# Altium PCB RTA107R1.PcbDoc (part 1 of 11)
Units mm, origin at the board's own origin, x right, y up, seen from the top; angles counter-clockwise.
Board outline 96.01 x 65.66 mm, 22 copper layers (Top Layer, GND1, INT1, PWR1-(VCCIO_MRAM), INT2, PWR2-(VCCINT), INT3, PWR3_(12V_MGTAVCC), INT4, GND2-(DGND_SGND), PWR4_(MGTAVTT_VCCBRAM,VCCAUX), PWR5-(VCC_12V), GND3-(DGND_GND), INT5, GND4, INT6, PWR6_(VCCO), INT7, GND5, INT8, GND6, Bottom Layer), stack 2.833 mm thick; 614 components, 659 nets, 4037 pads, 3511 vias.

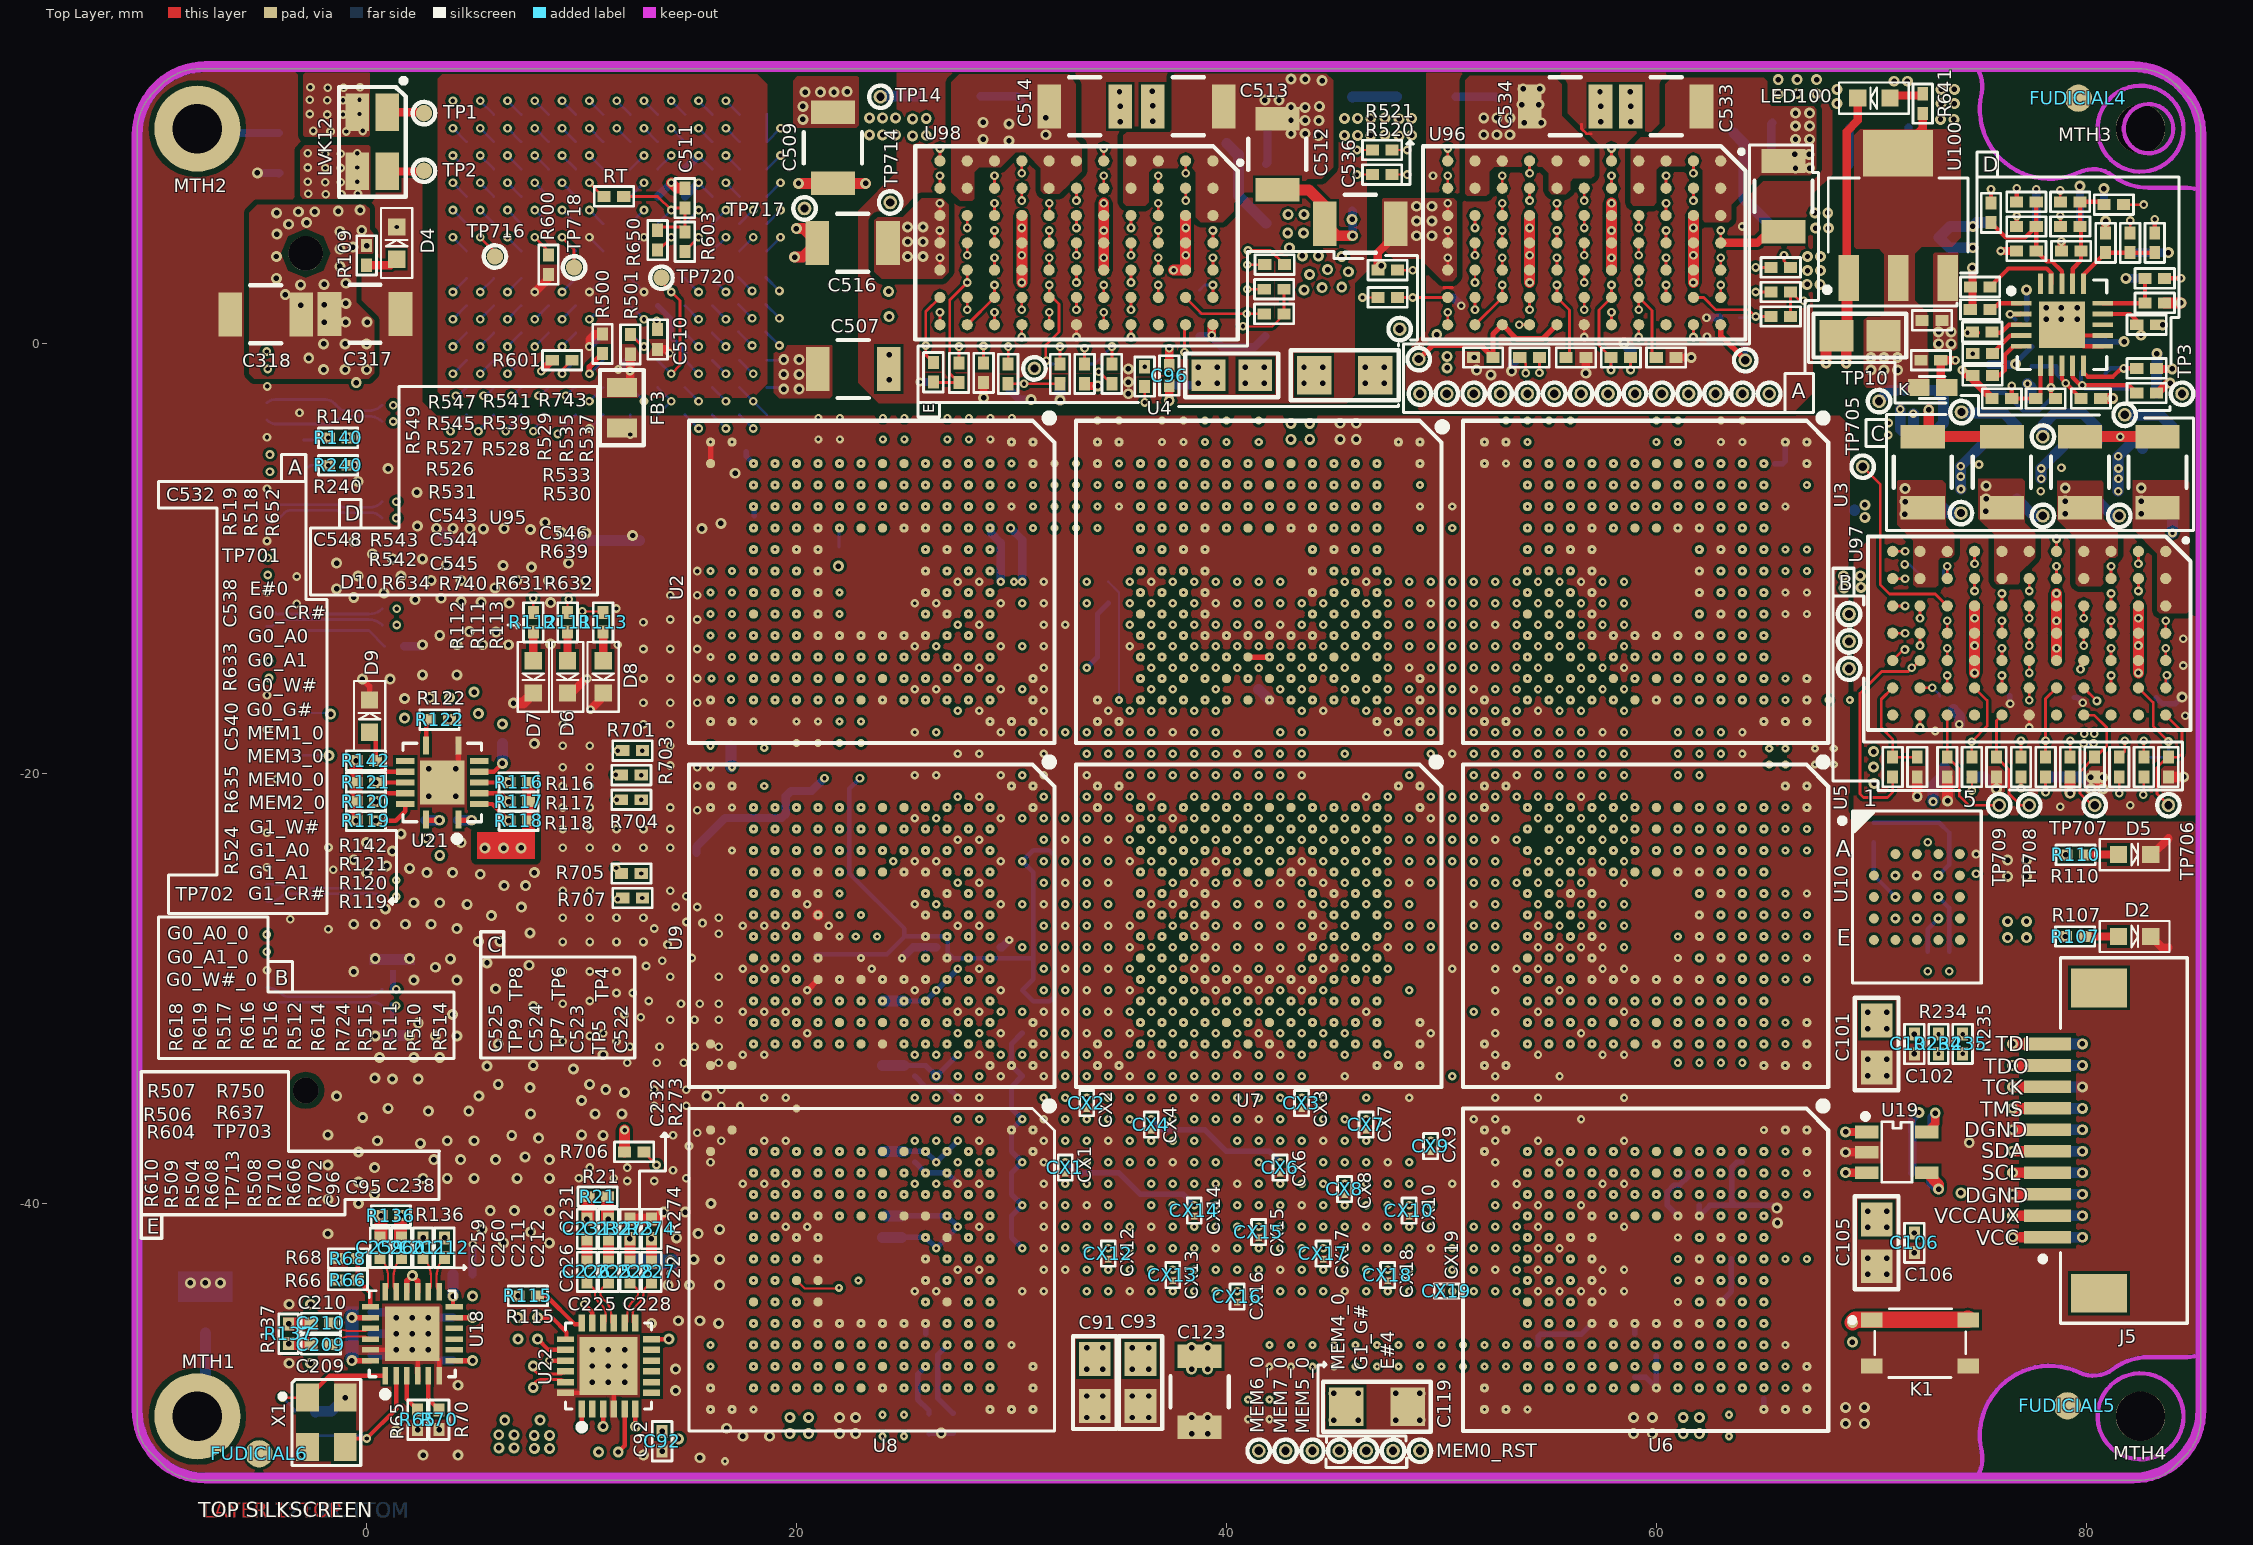
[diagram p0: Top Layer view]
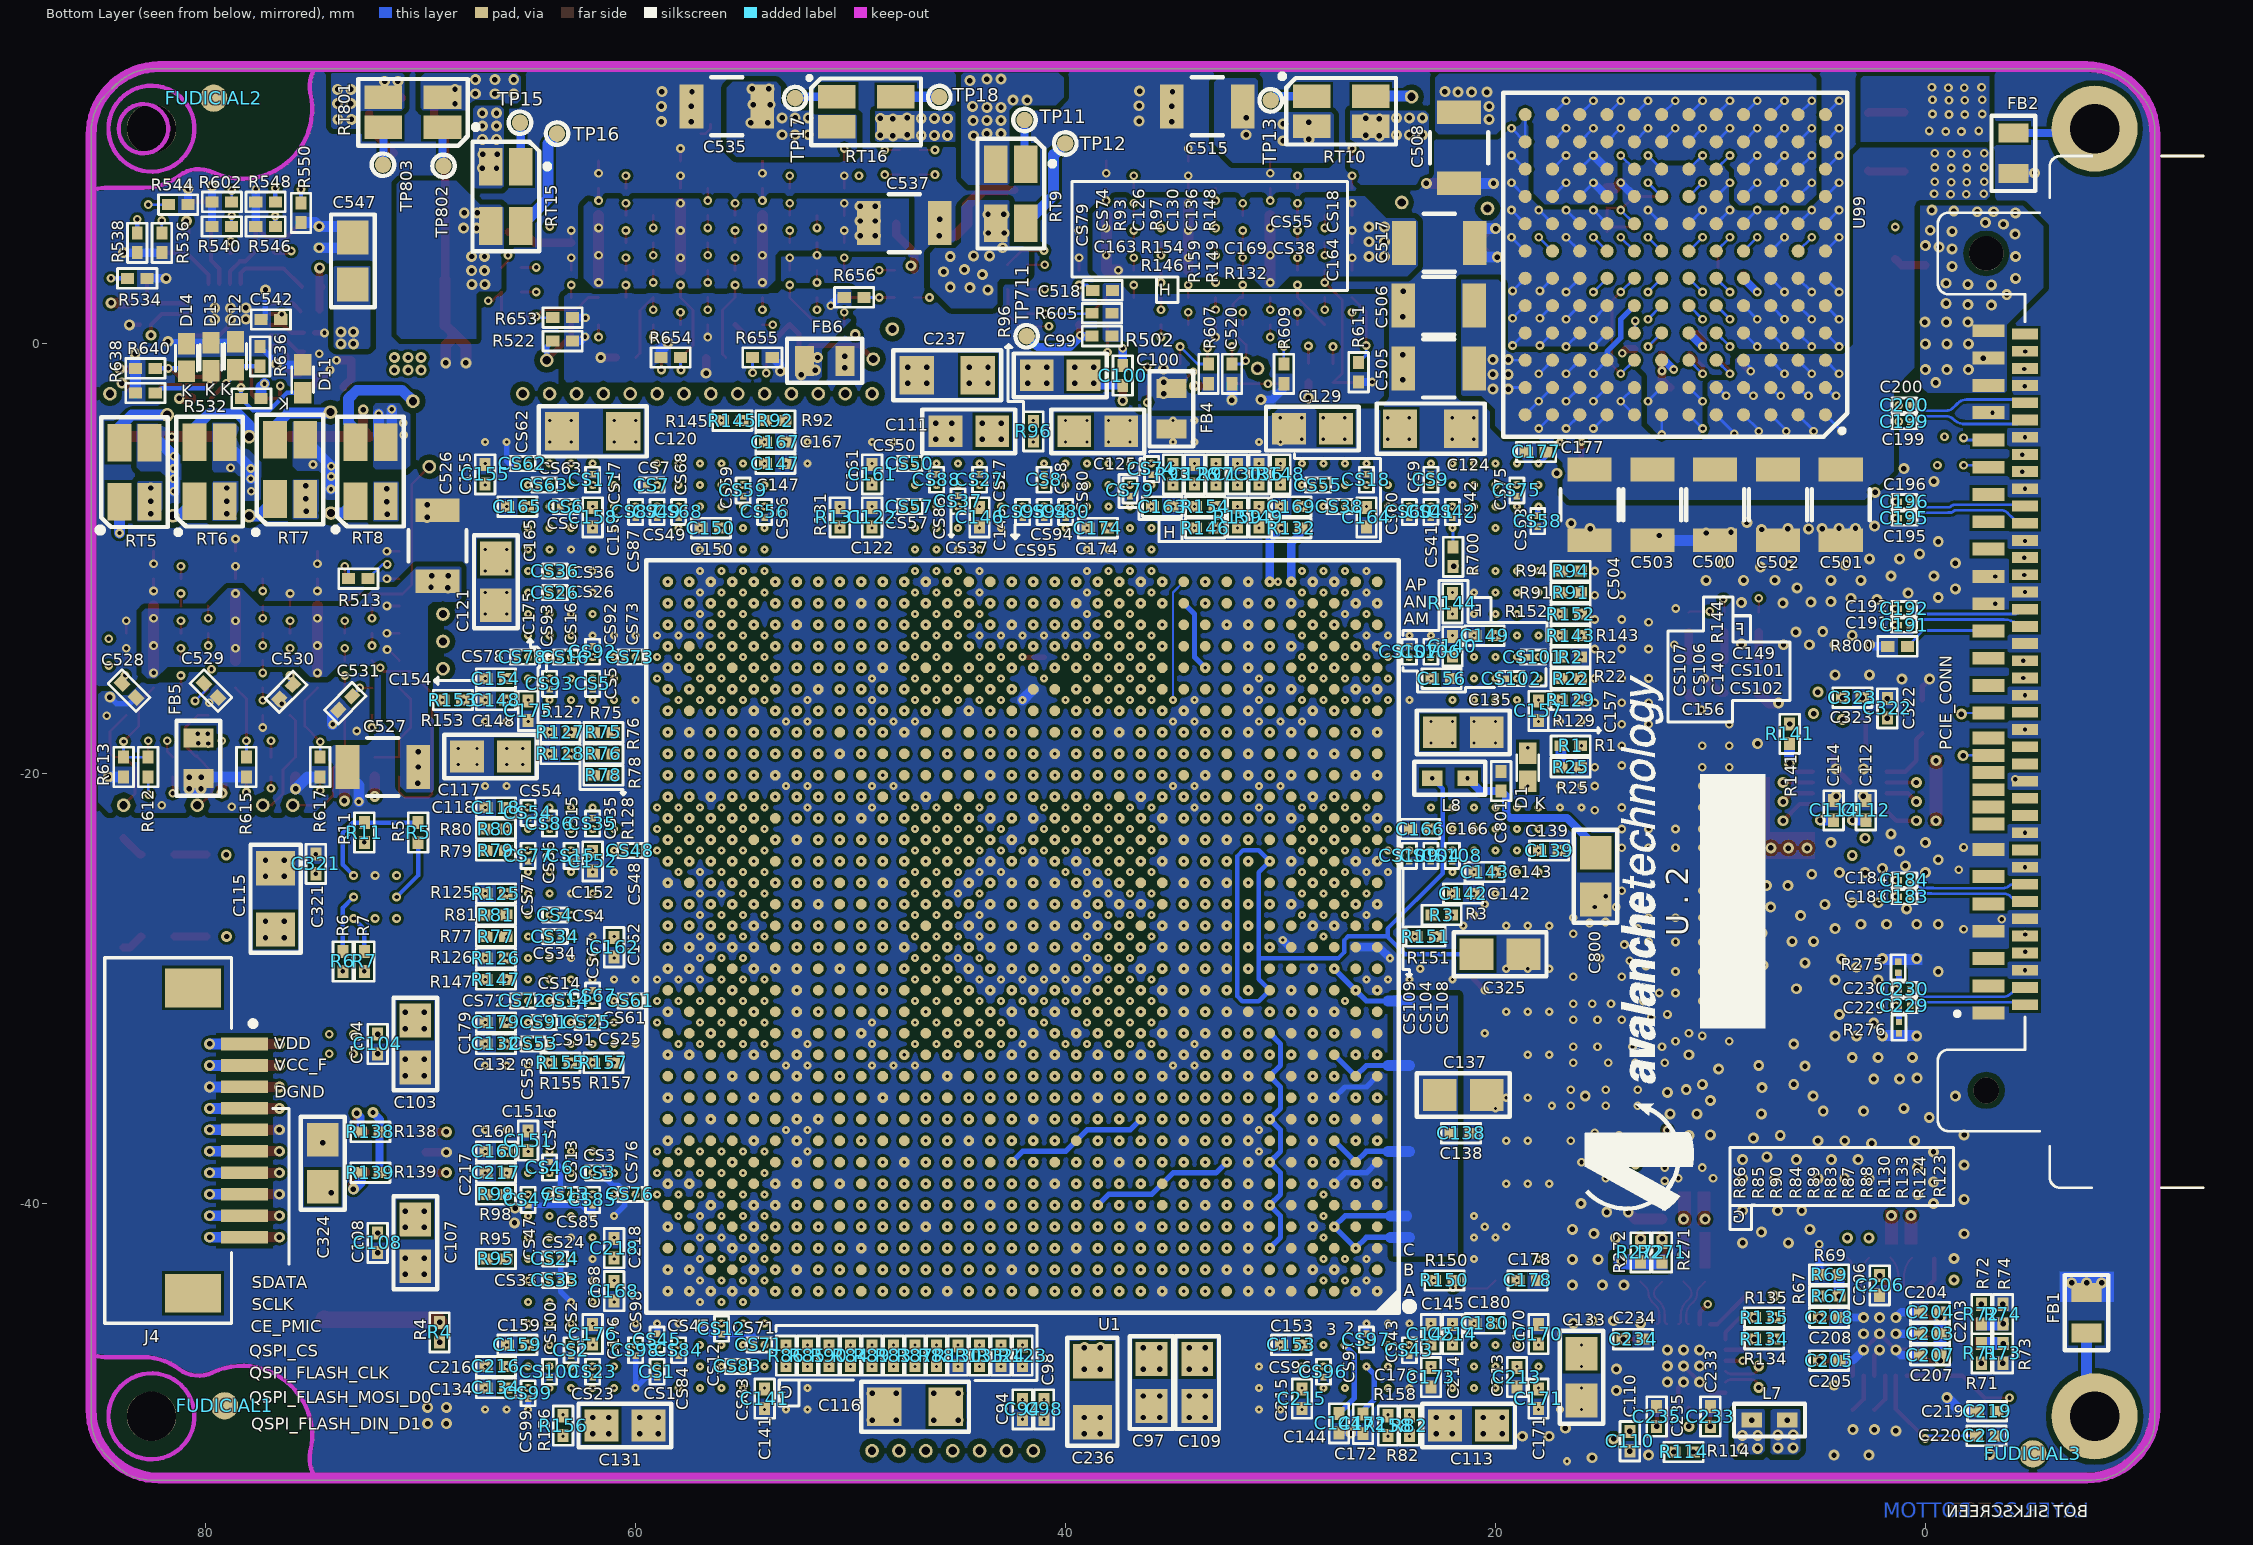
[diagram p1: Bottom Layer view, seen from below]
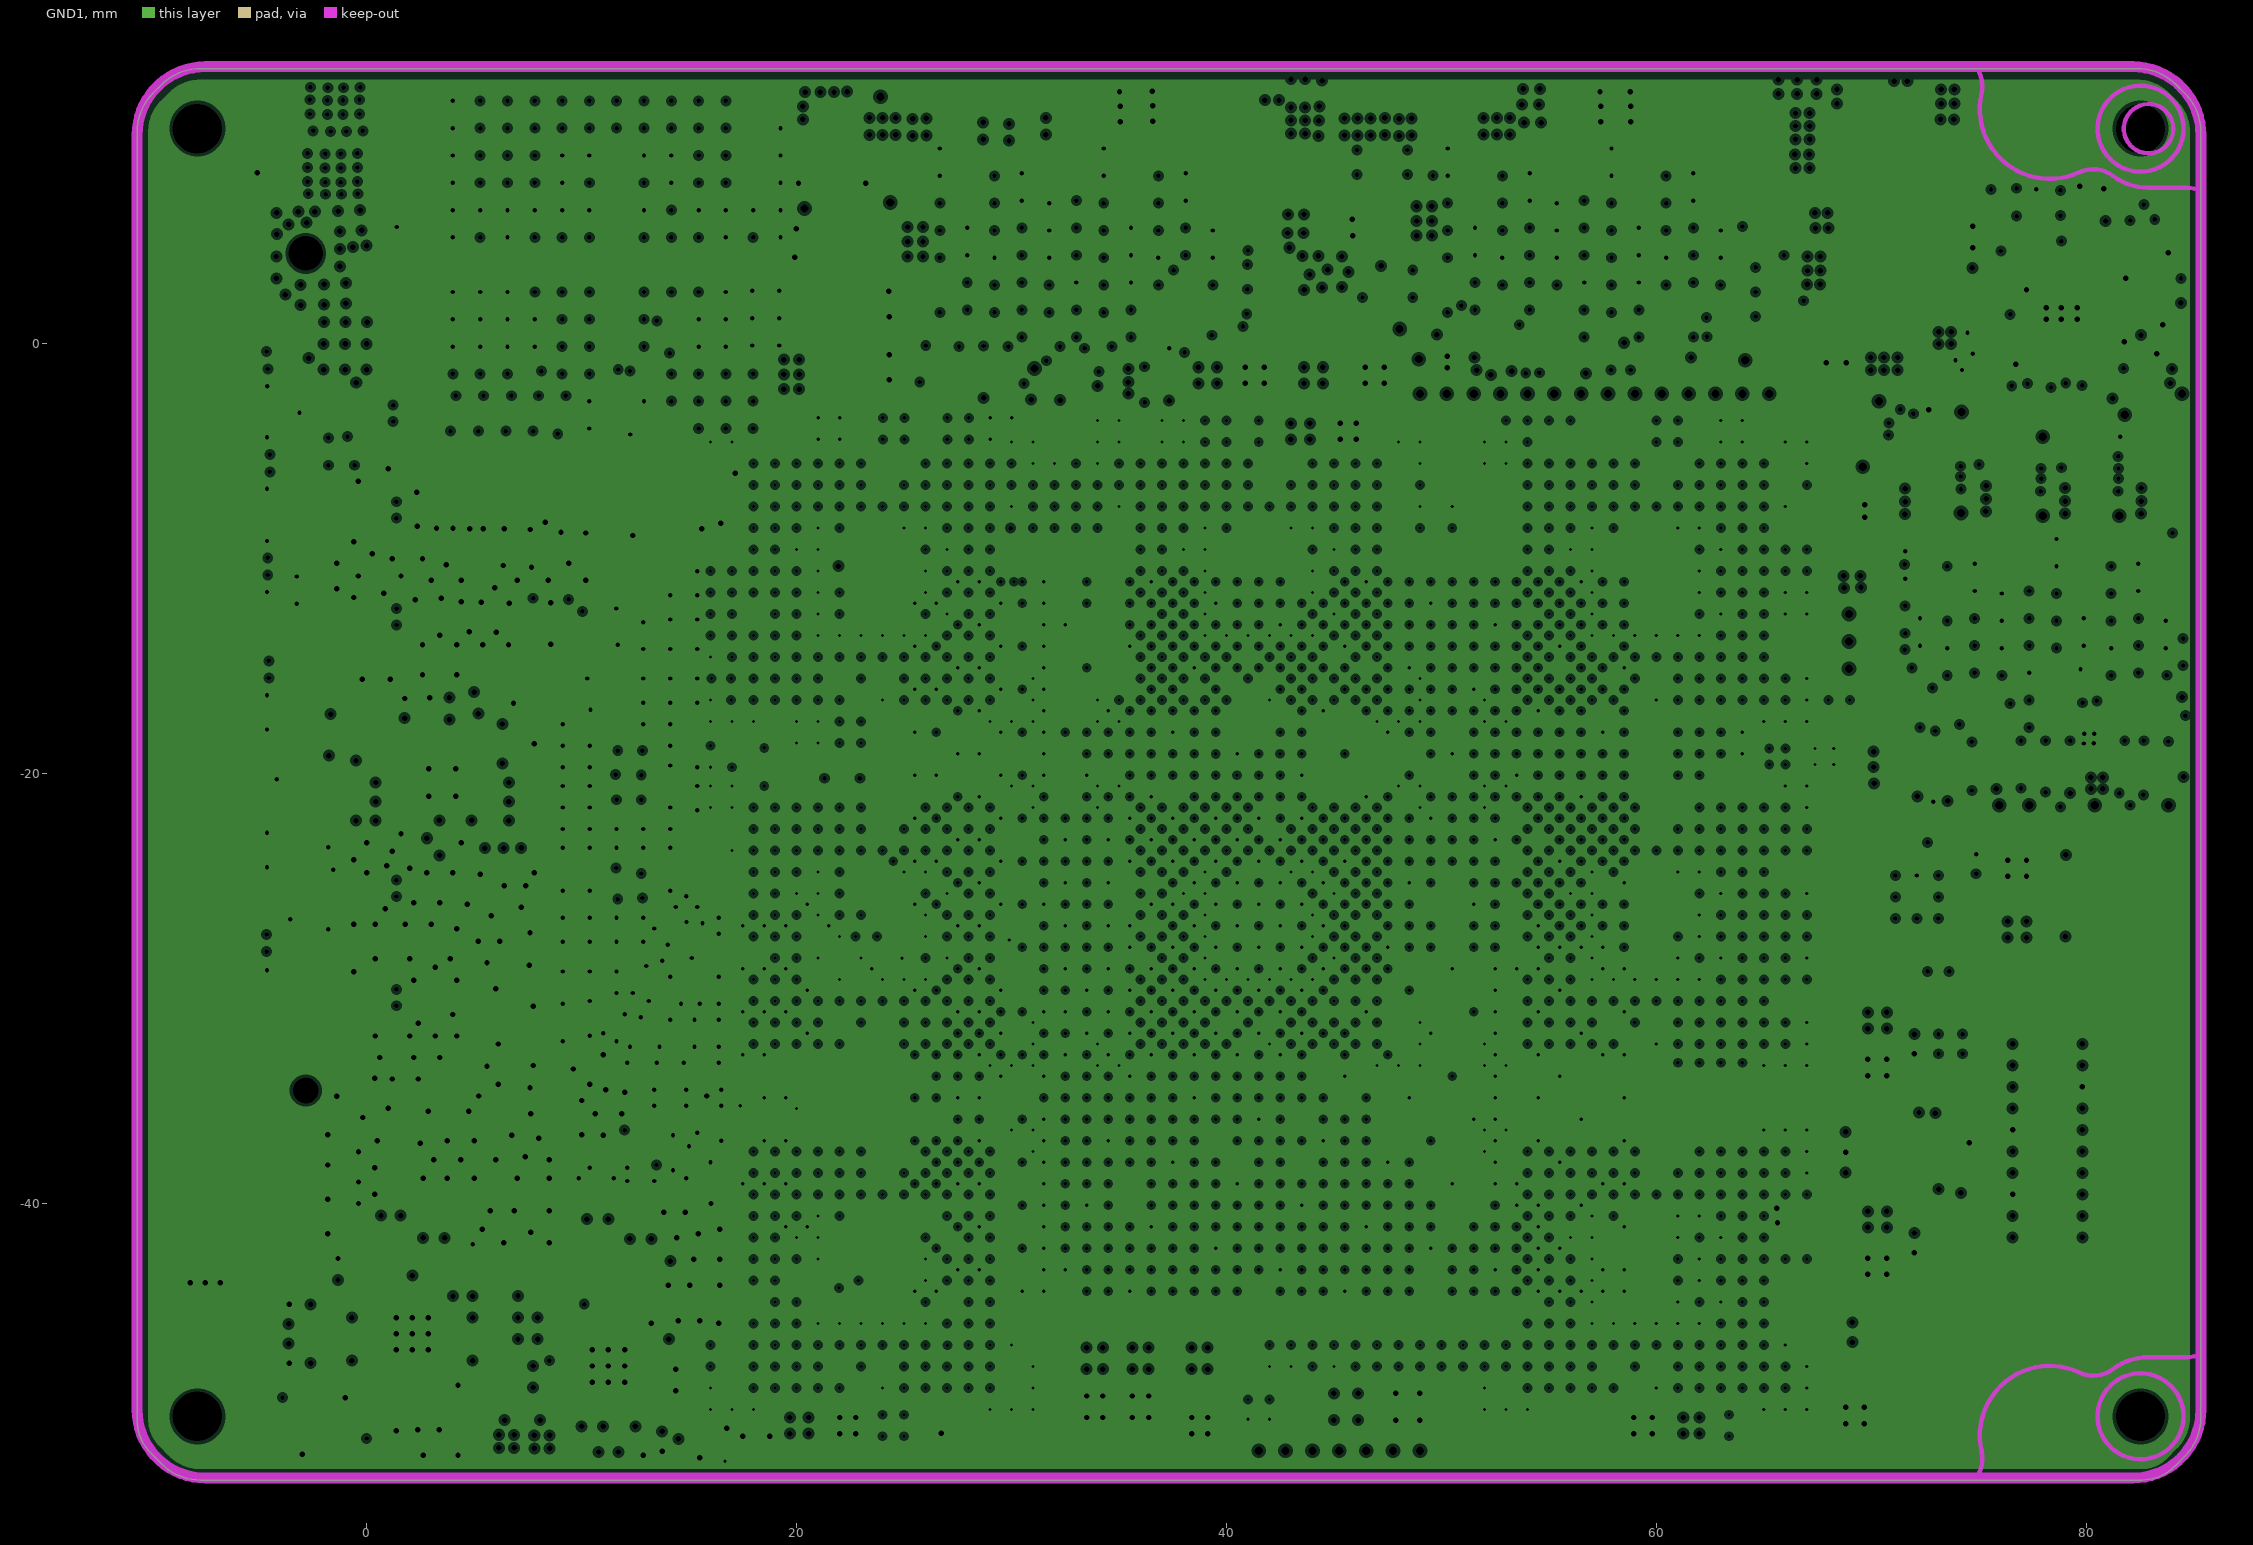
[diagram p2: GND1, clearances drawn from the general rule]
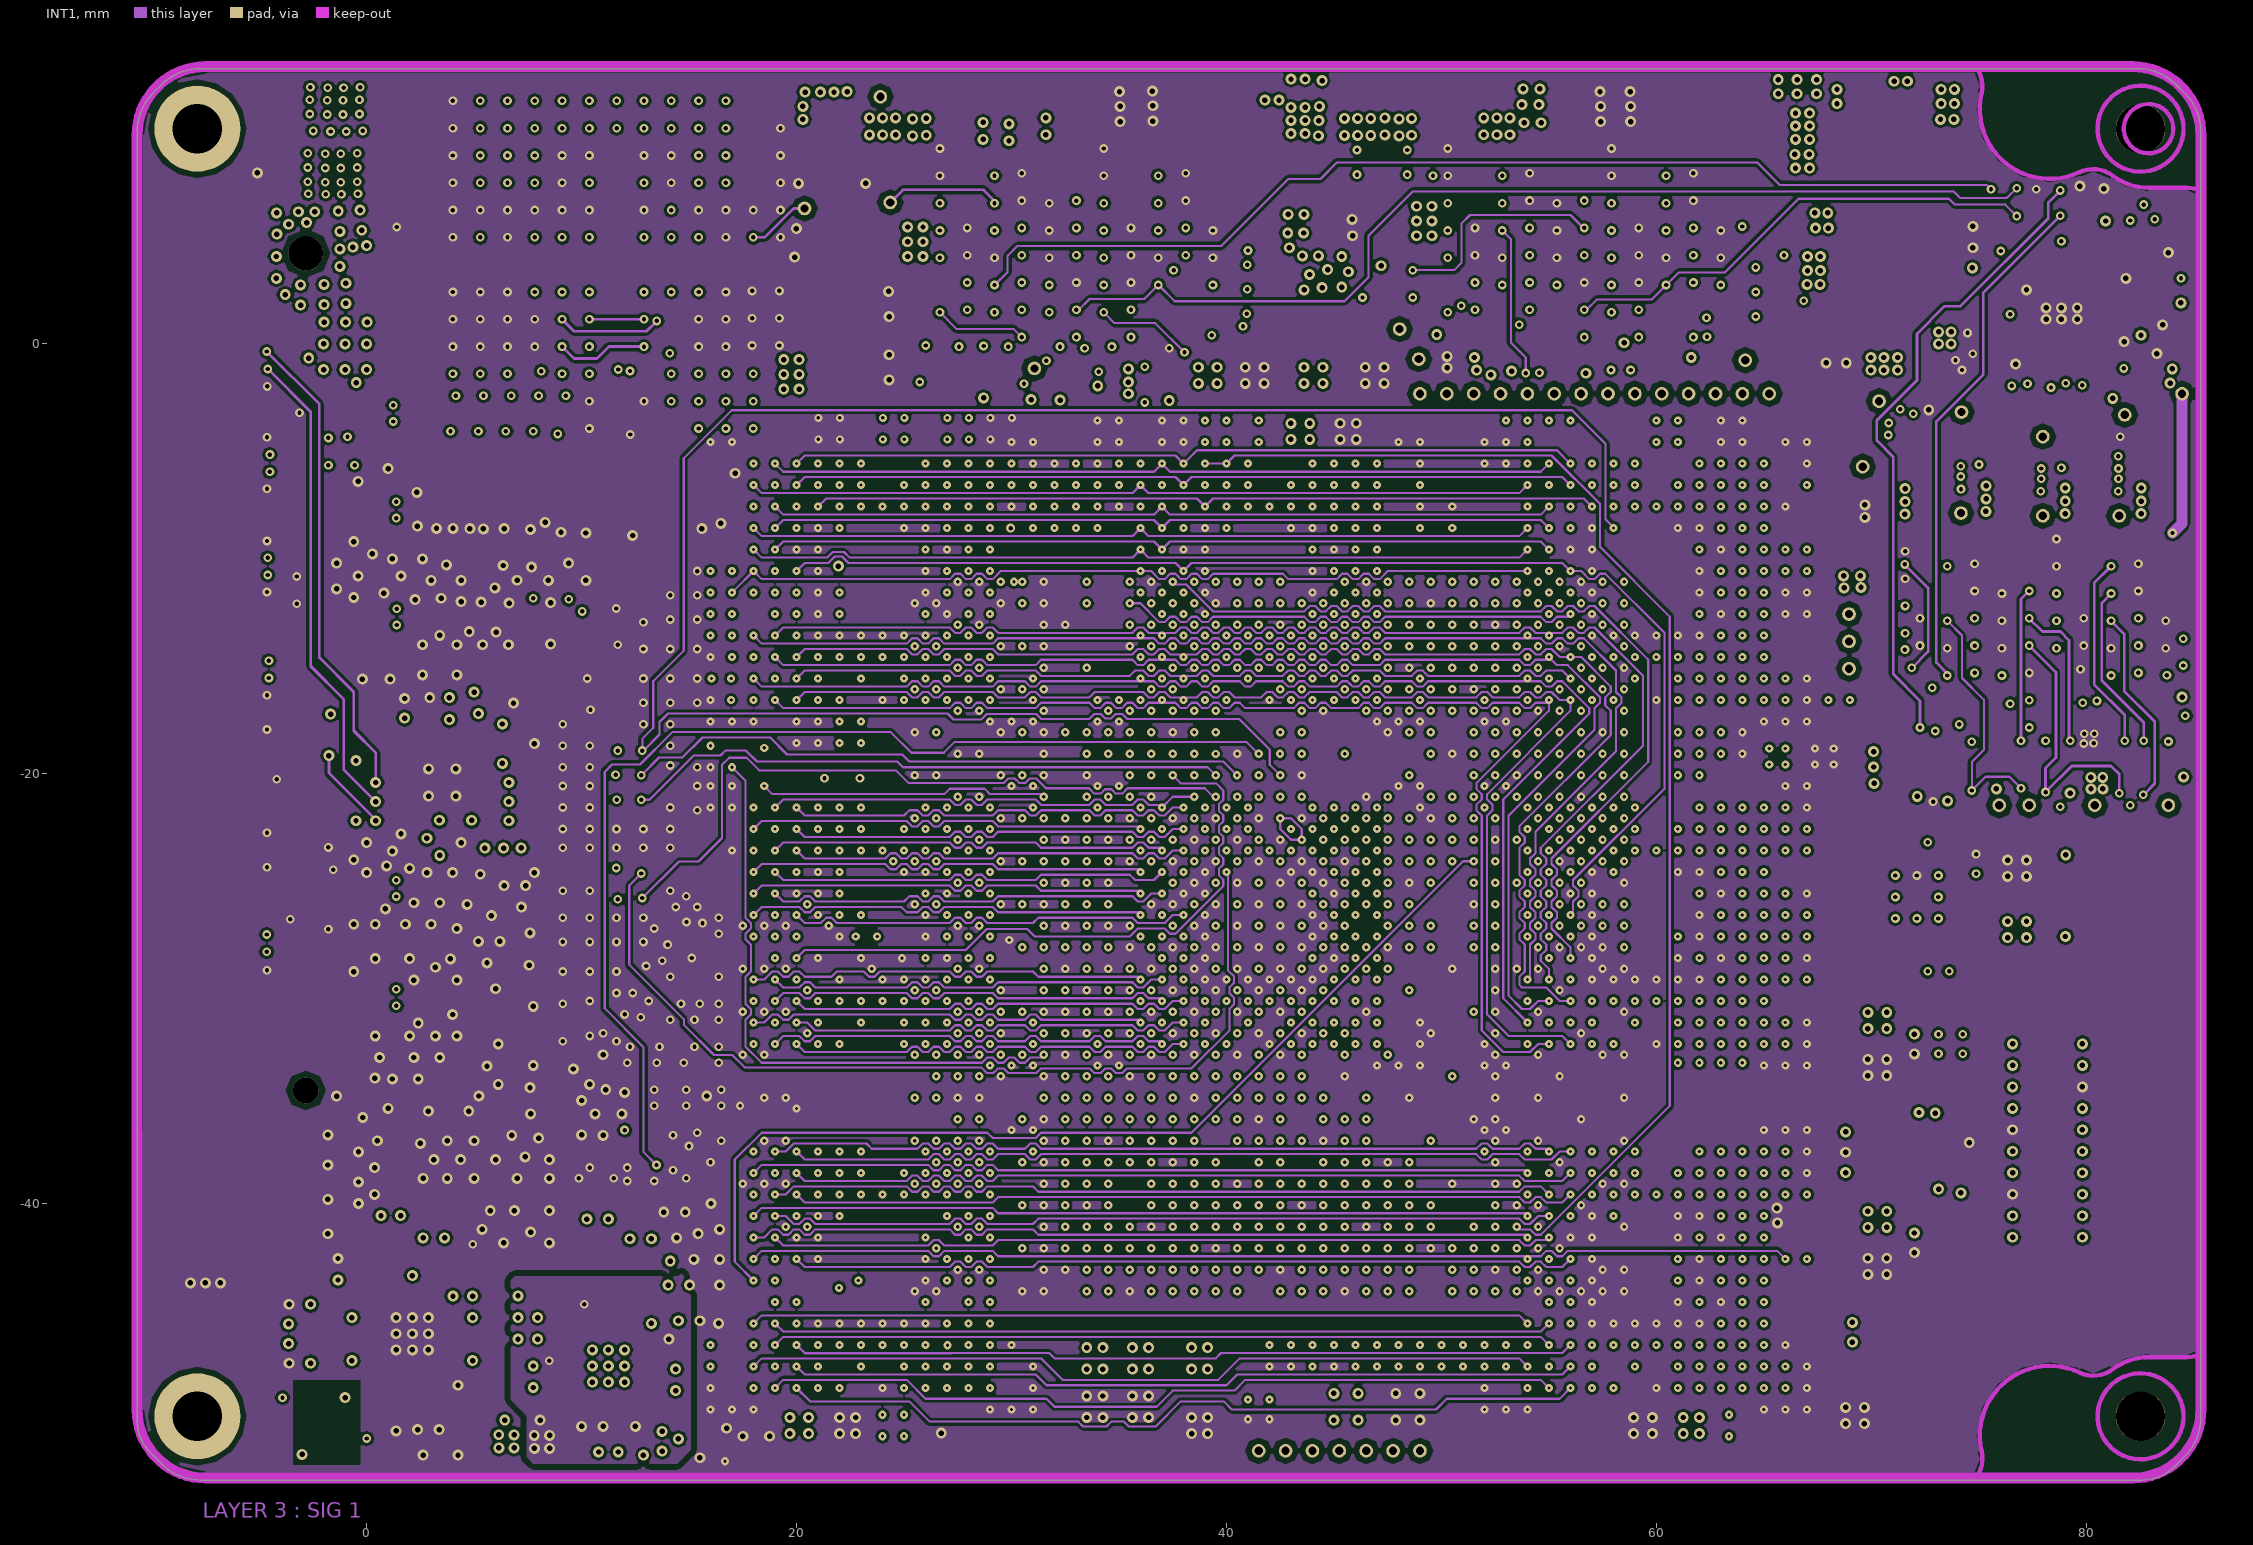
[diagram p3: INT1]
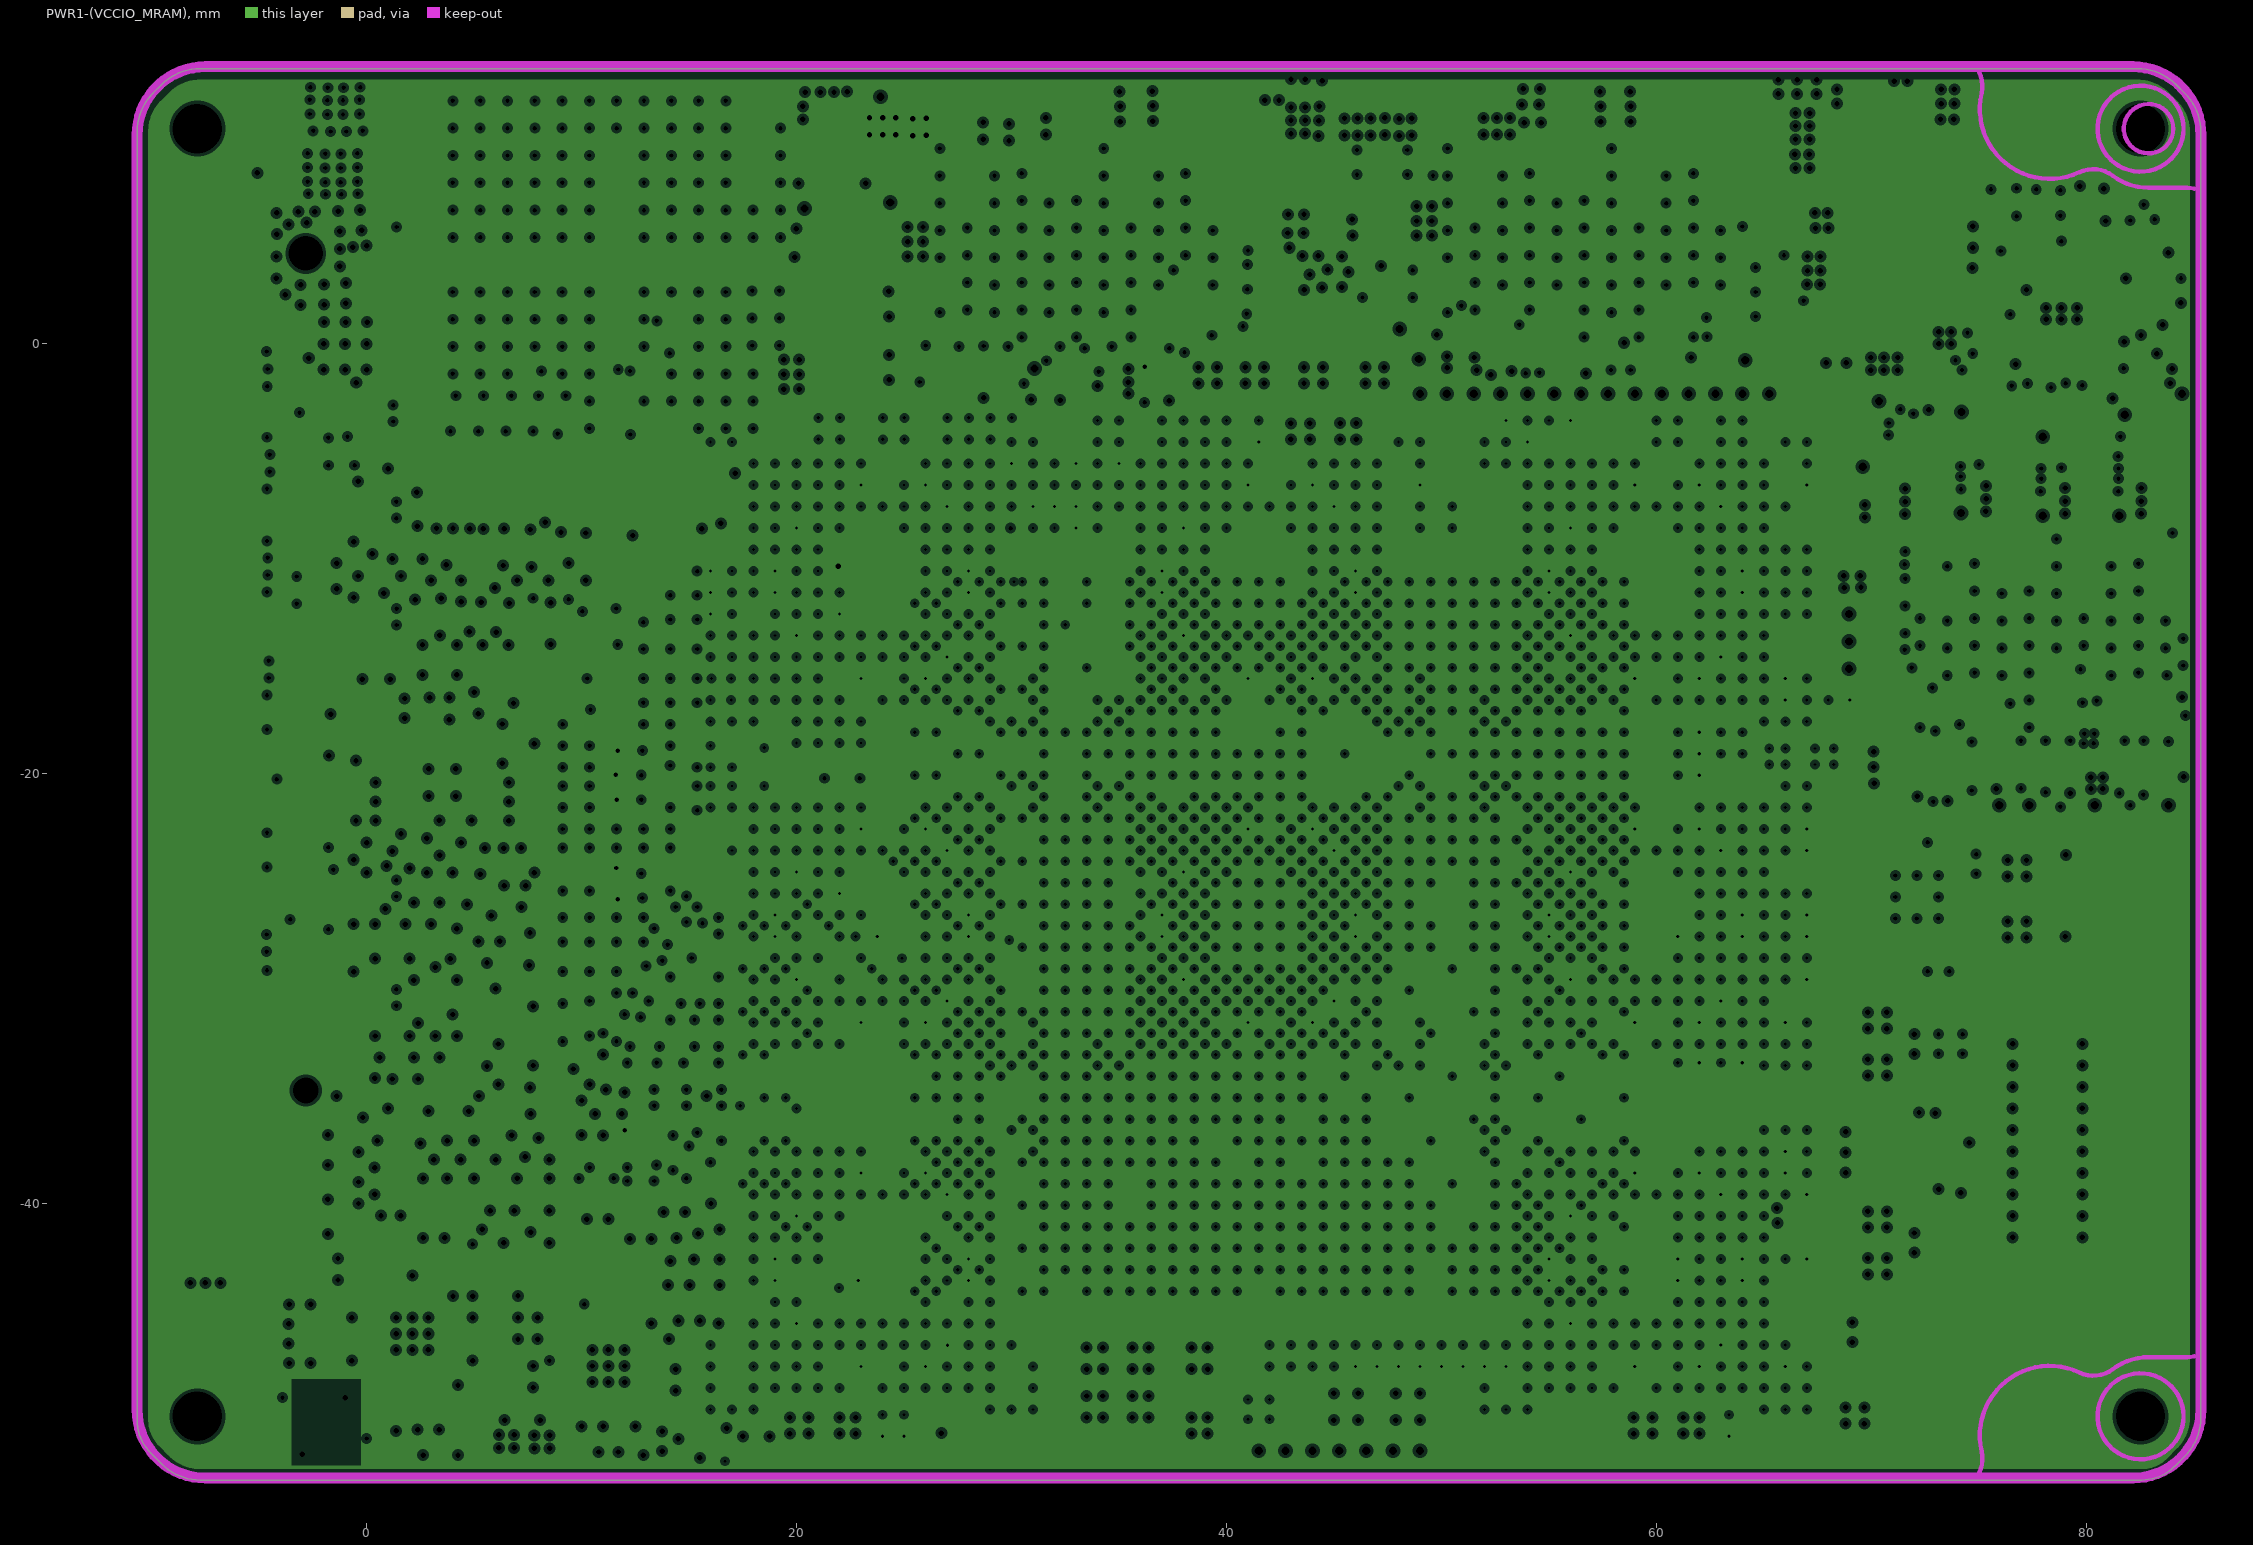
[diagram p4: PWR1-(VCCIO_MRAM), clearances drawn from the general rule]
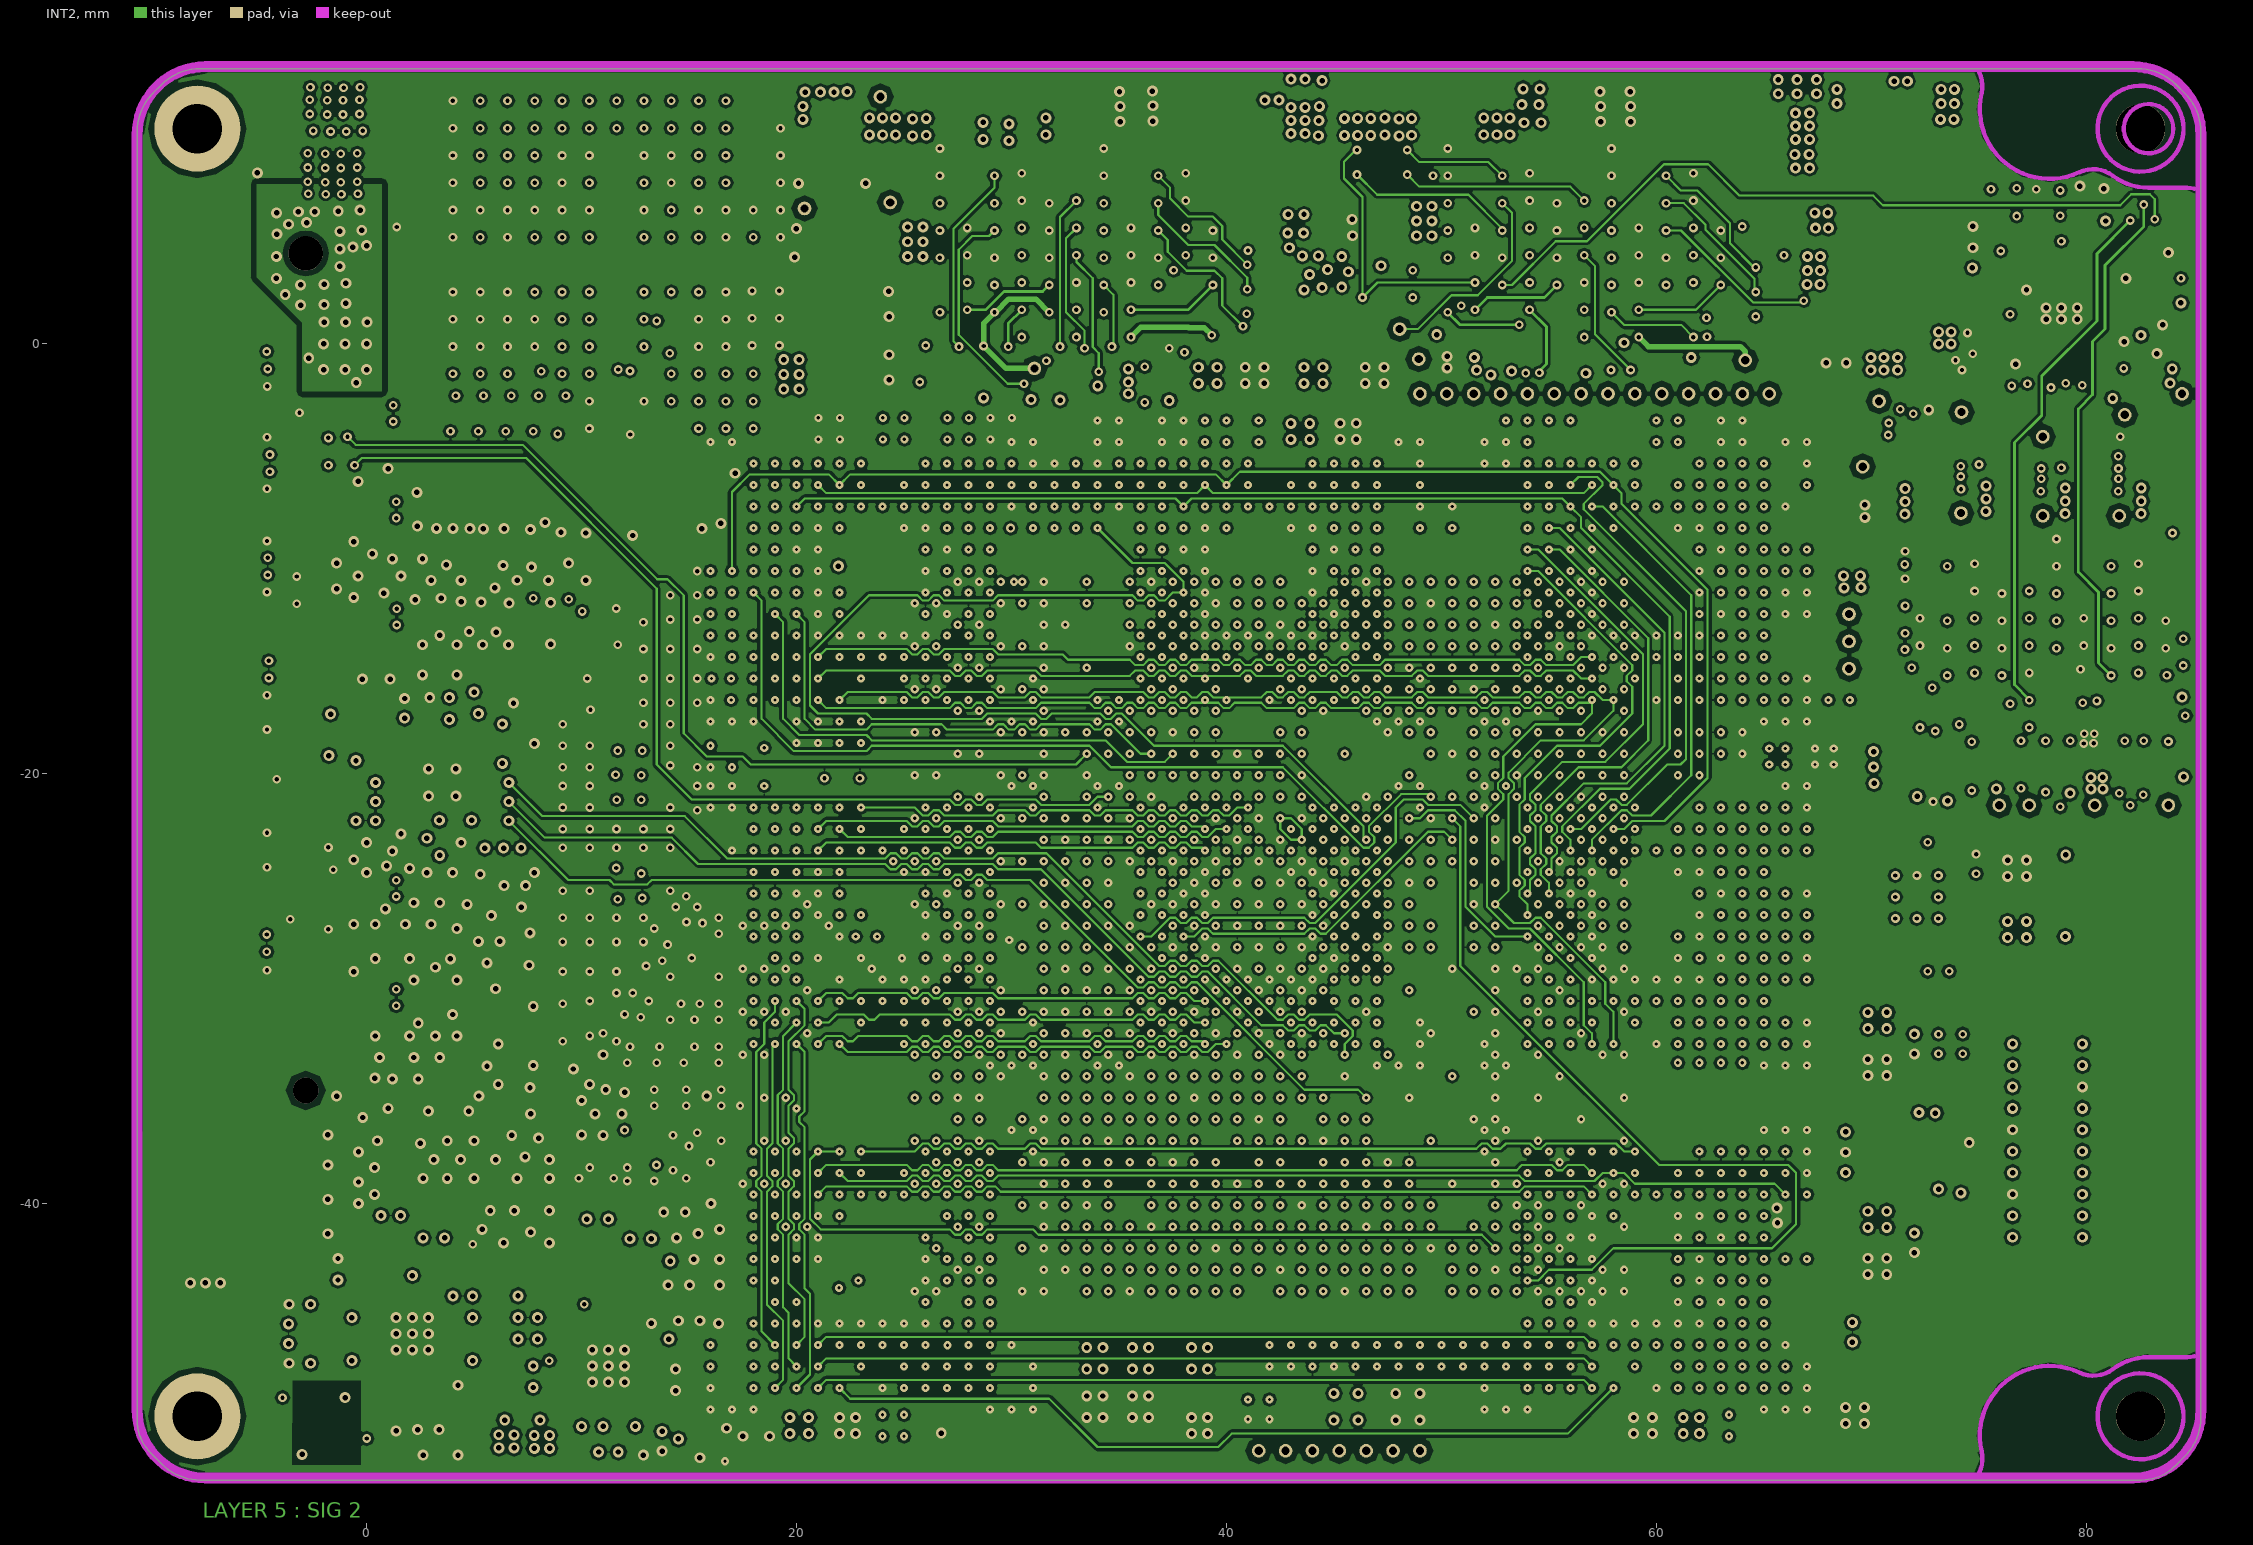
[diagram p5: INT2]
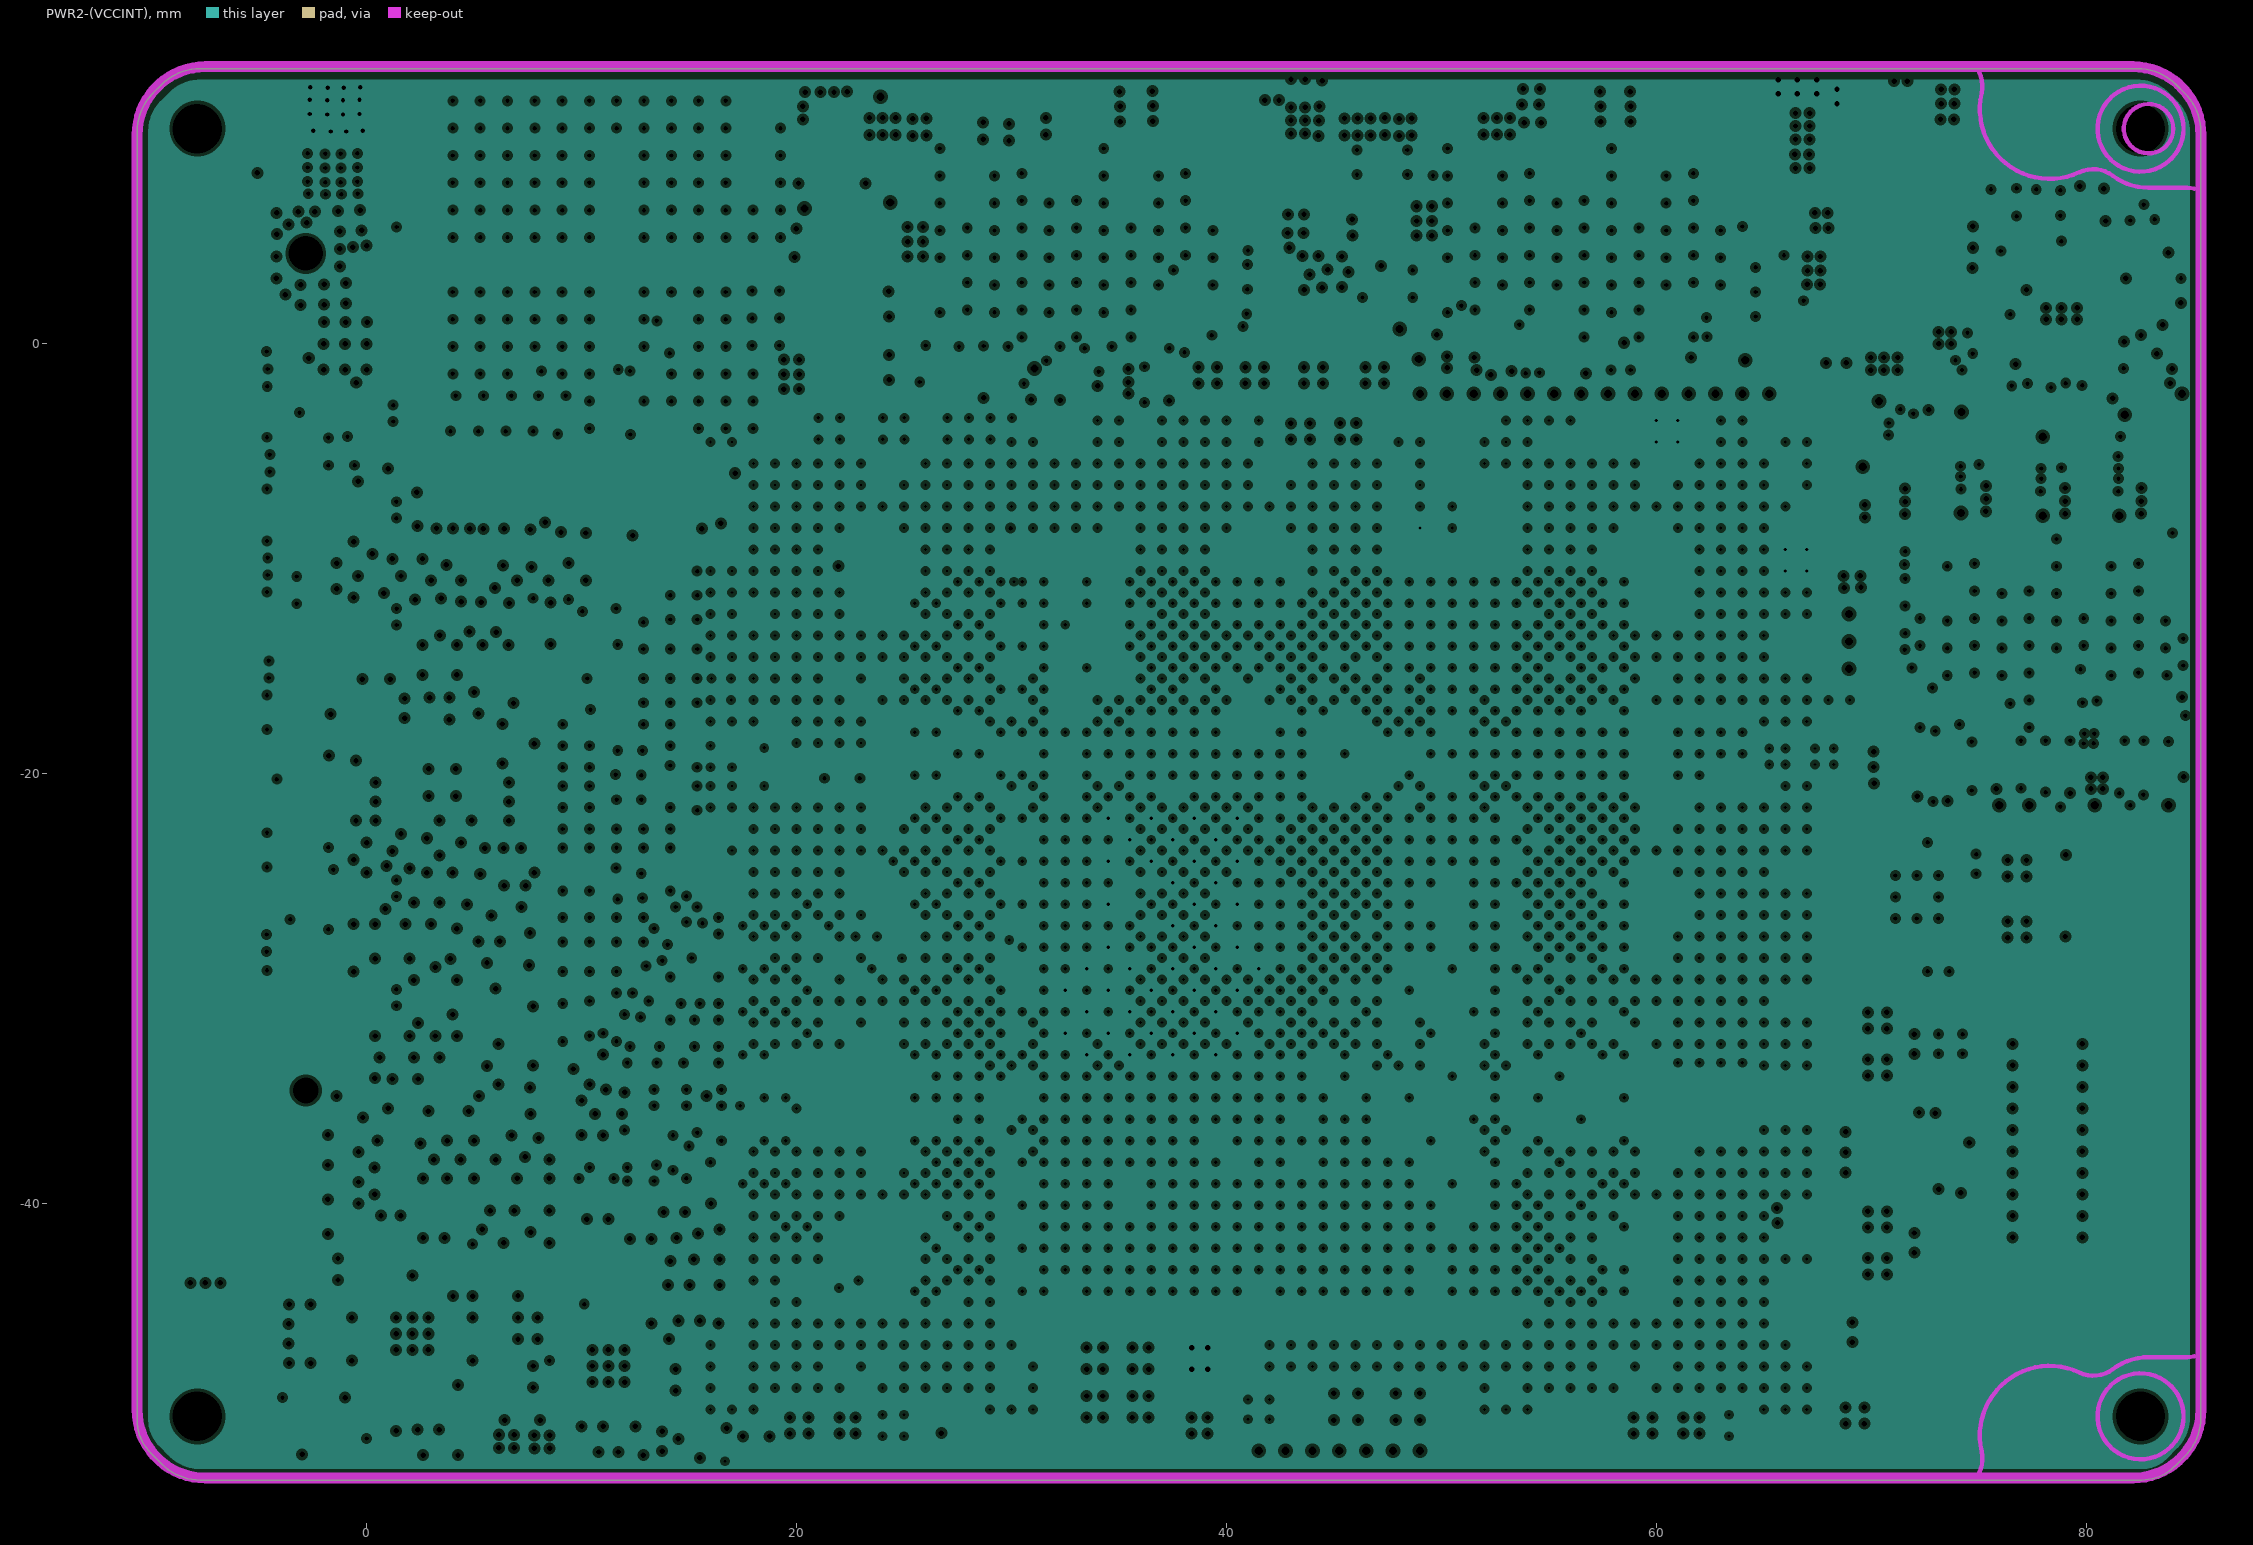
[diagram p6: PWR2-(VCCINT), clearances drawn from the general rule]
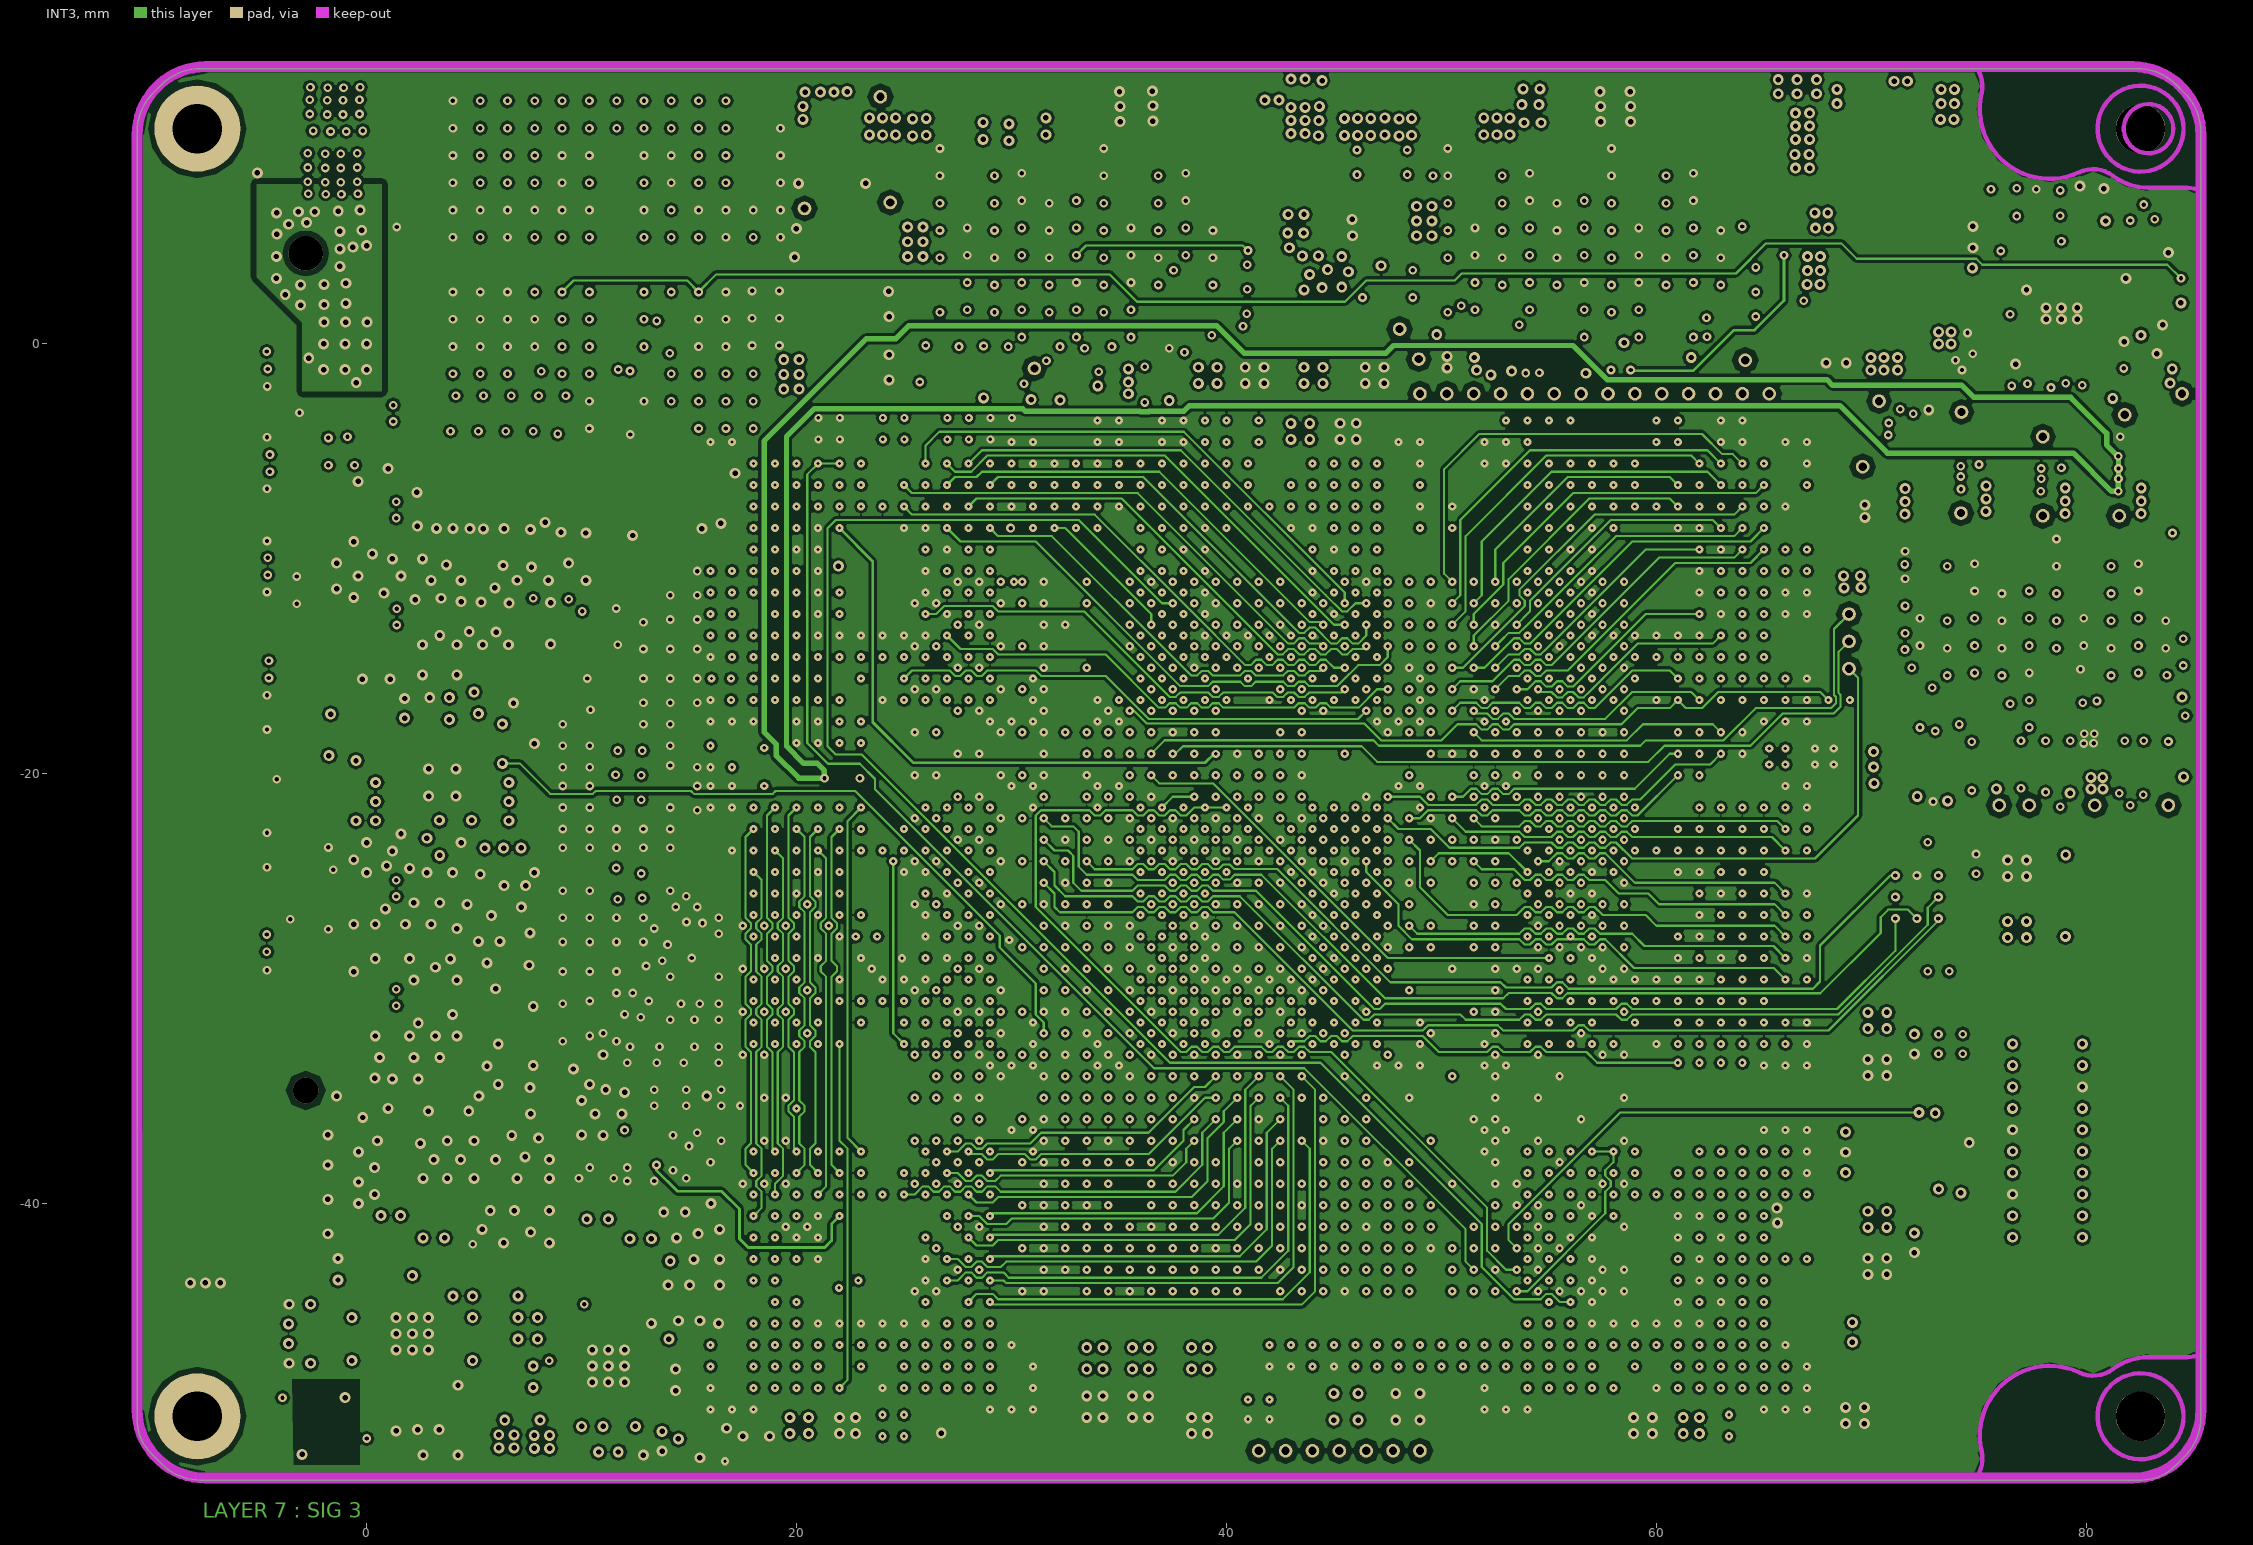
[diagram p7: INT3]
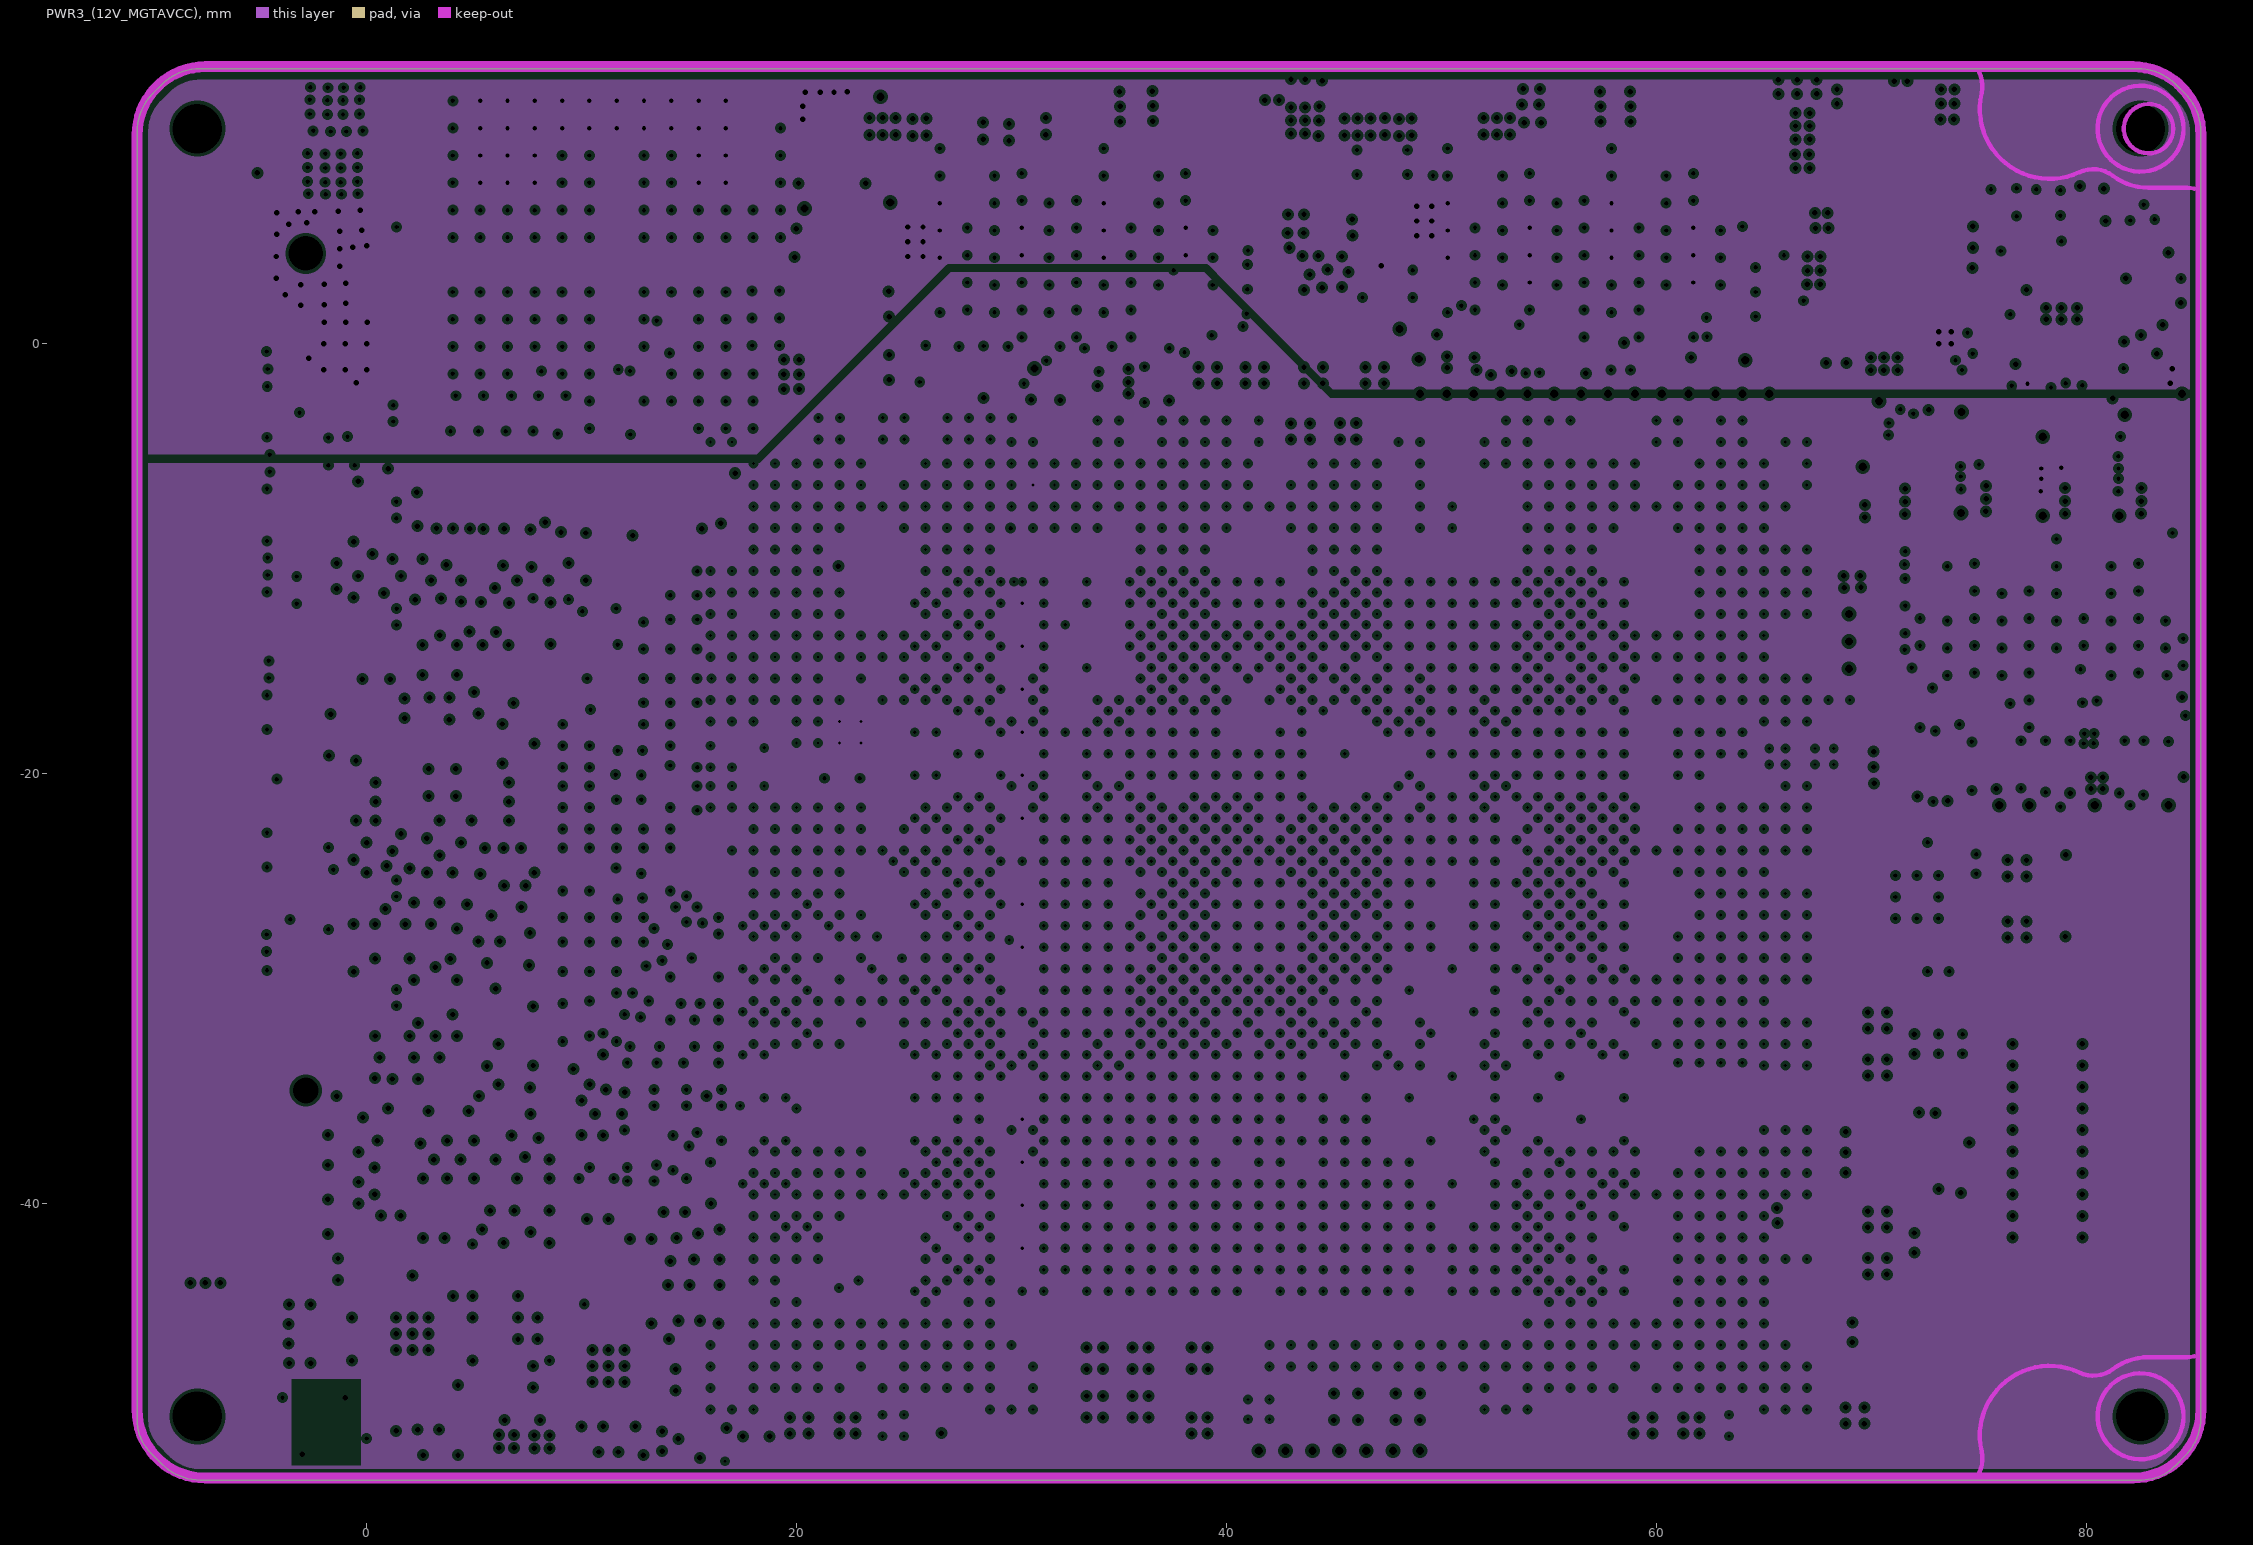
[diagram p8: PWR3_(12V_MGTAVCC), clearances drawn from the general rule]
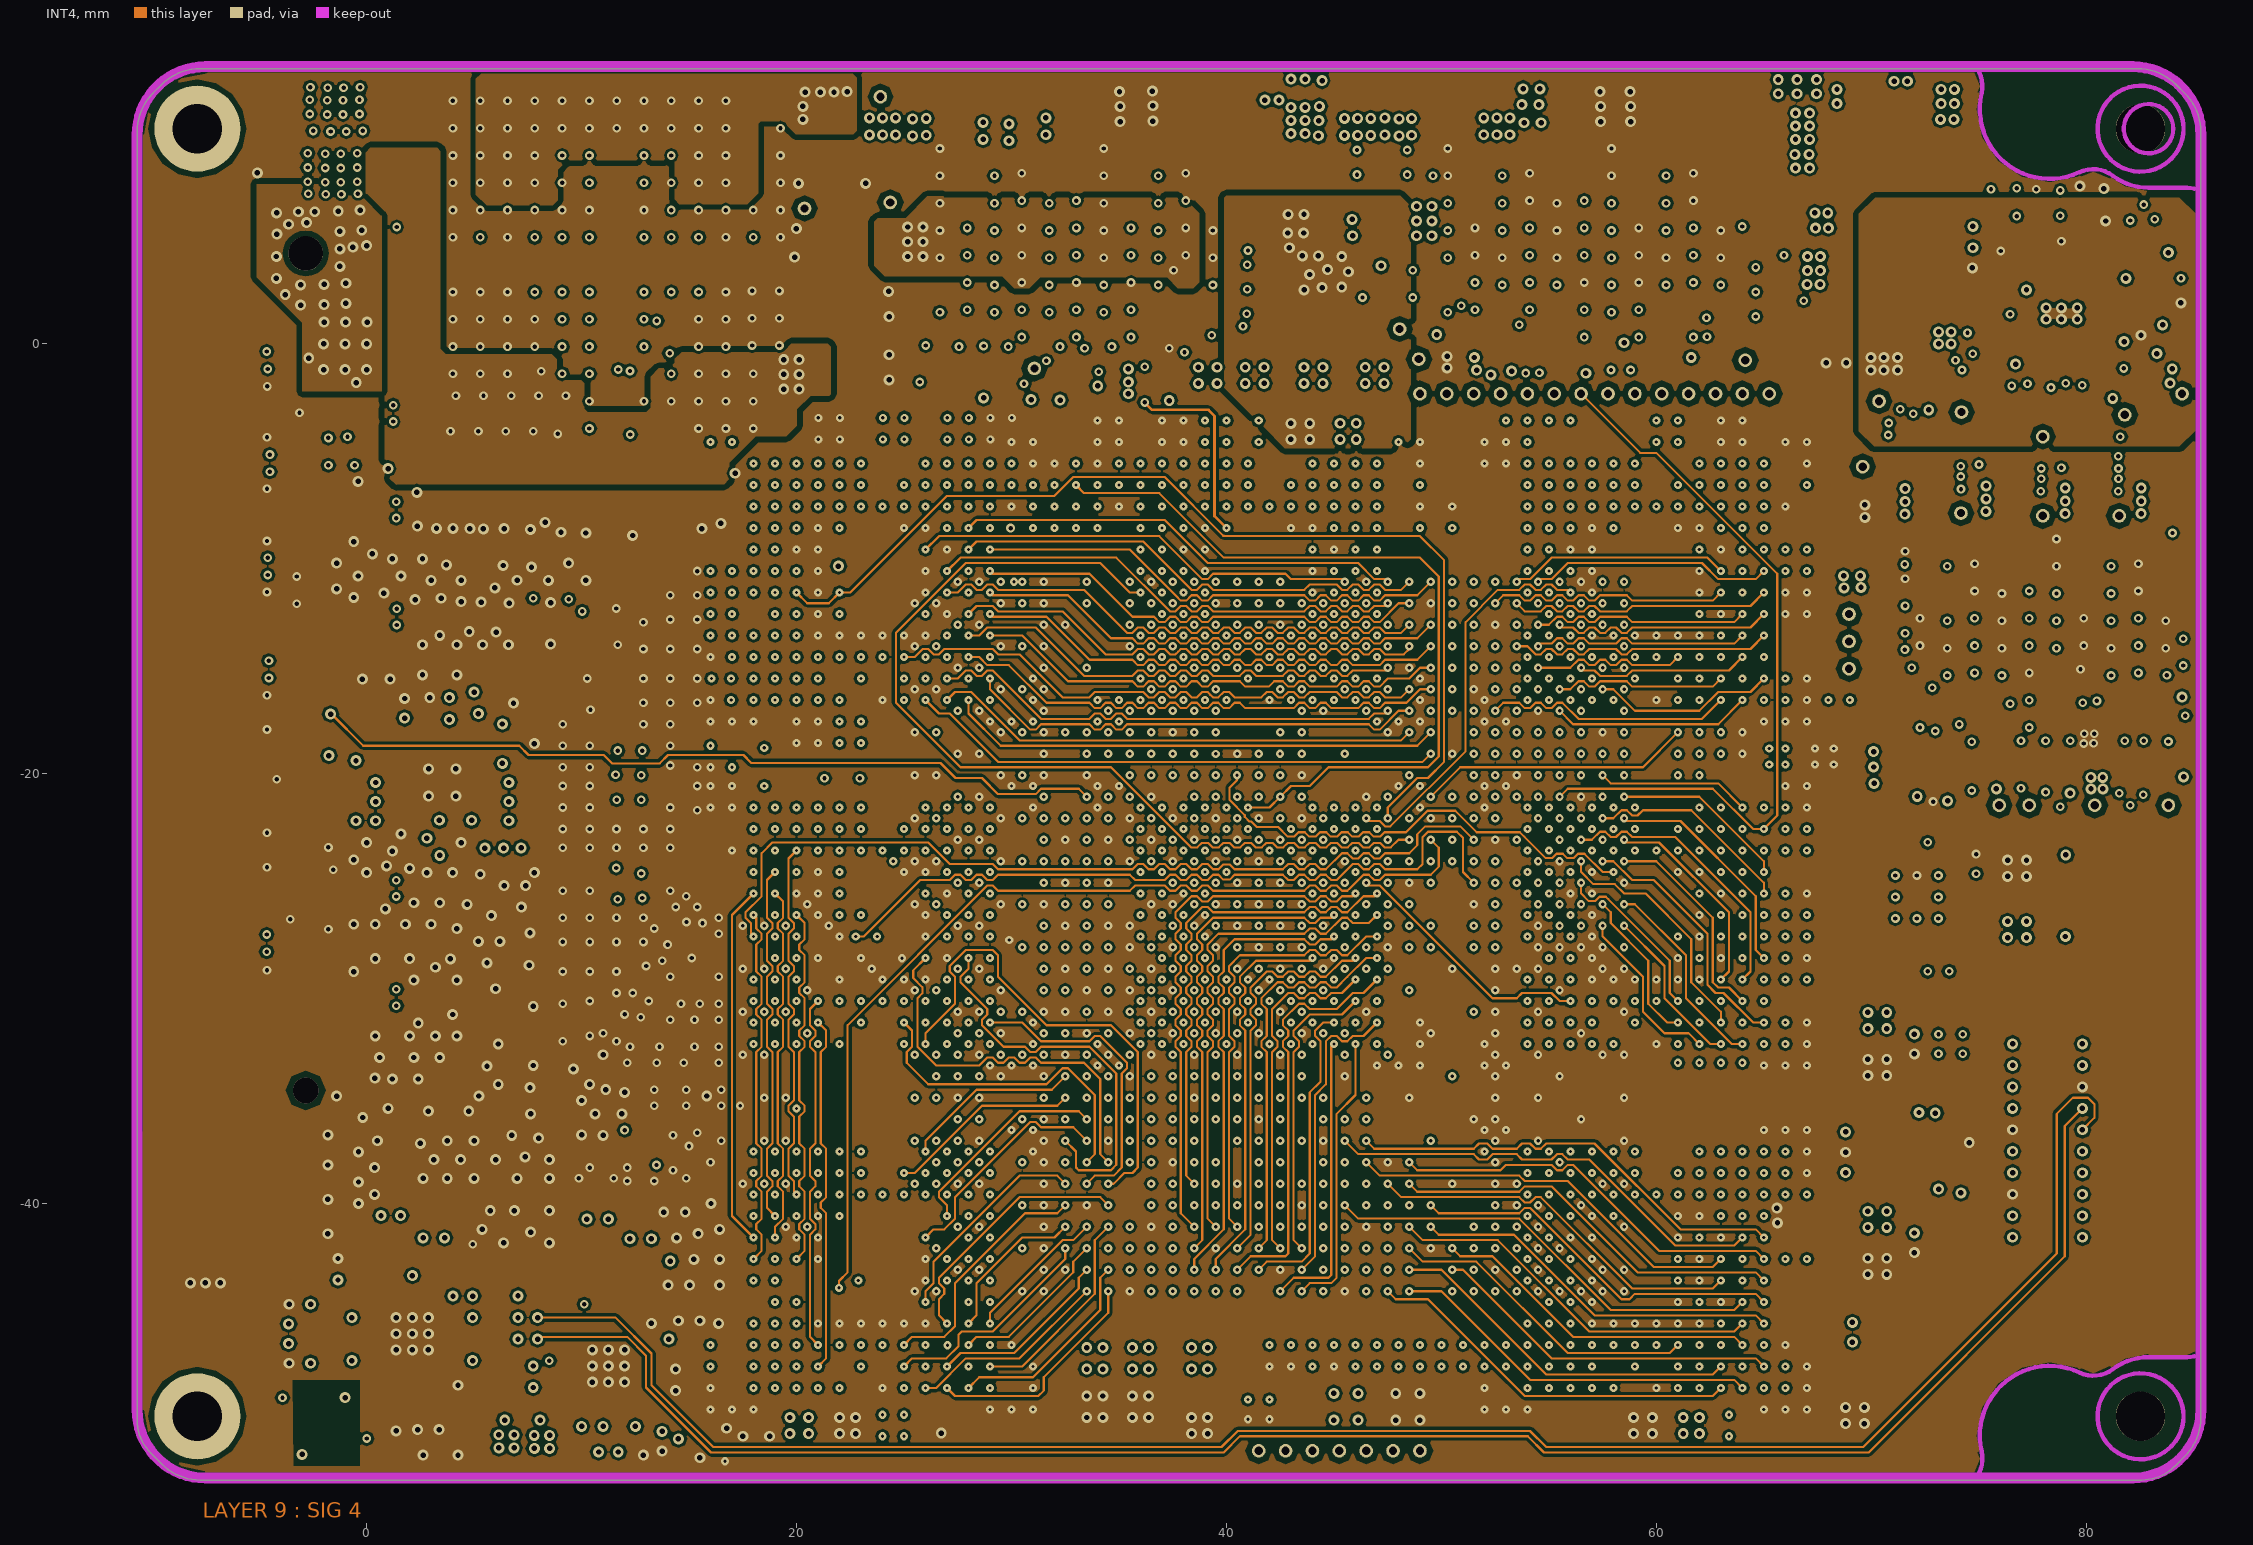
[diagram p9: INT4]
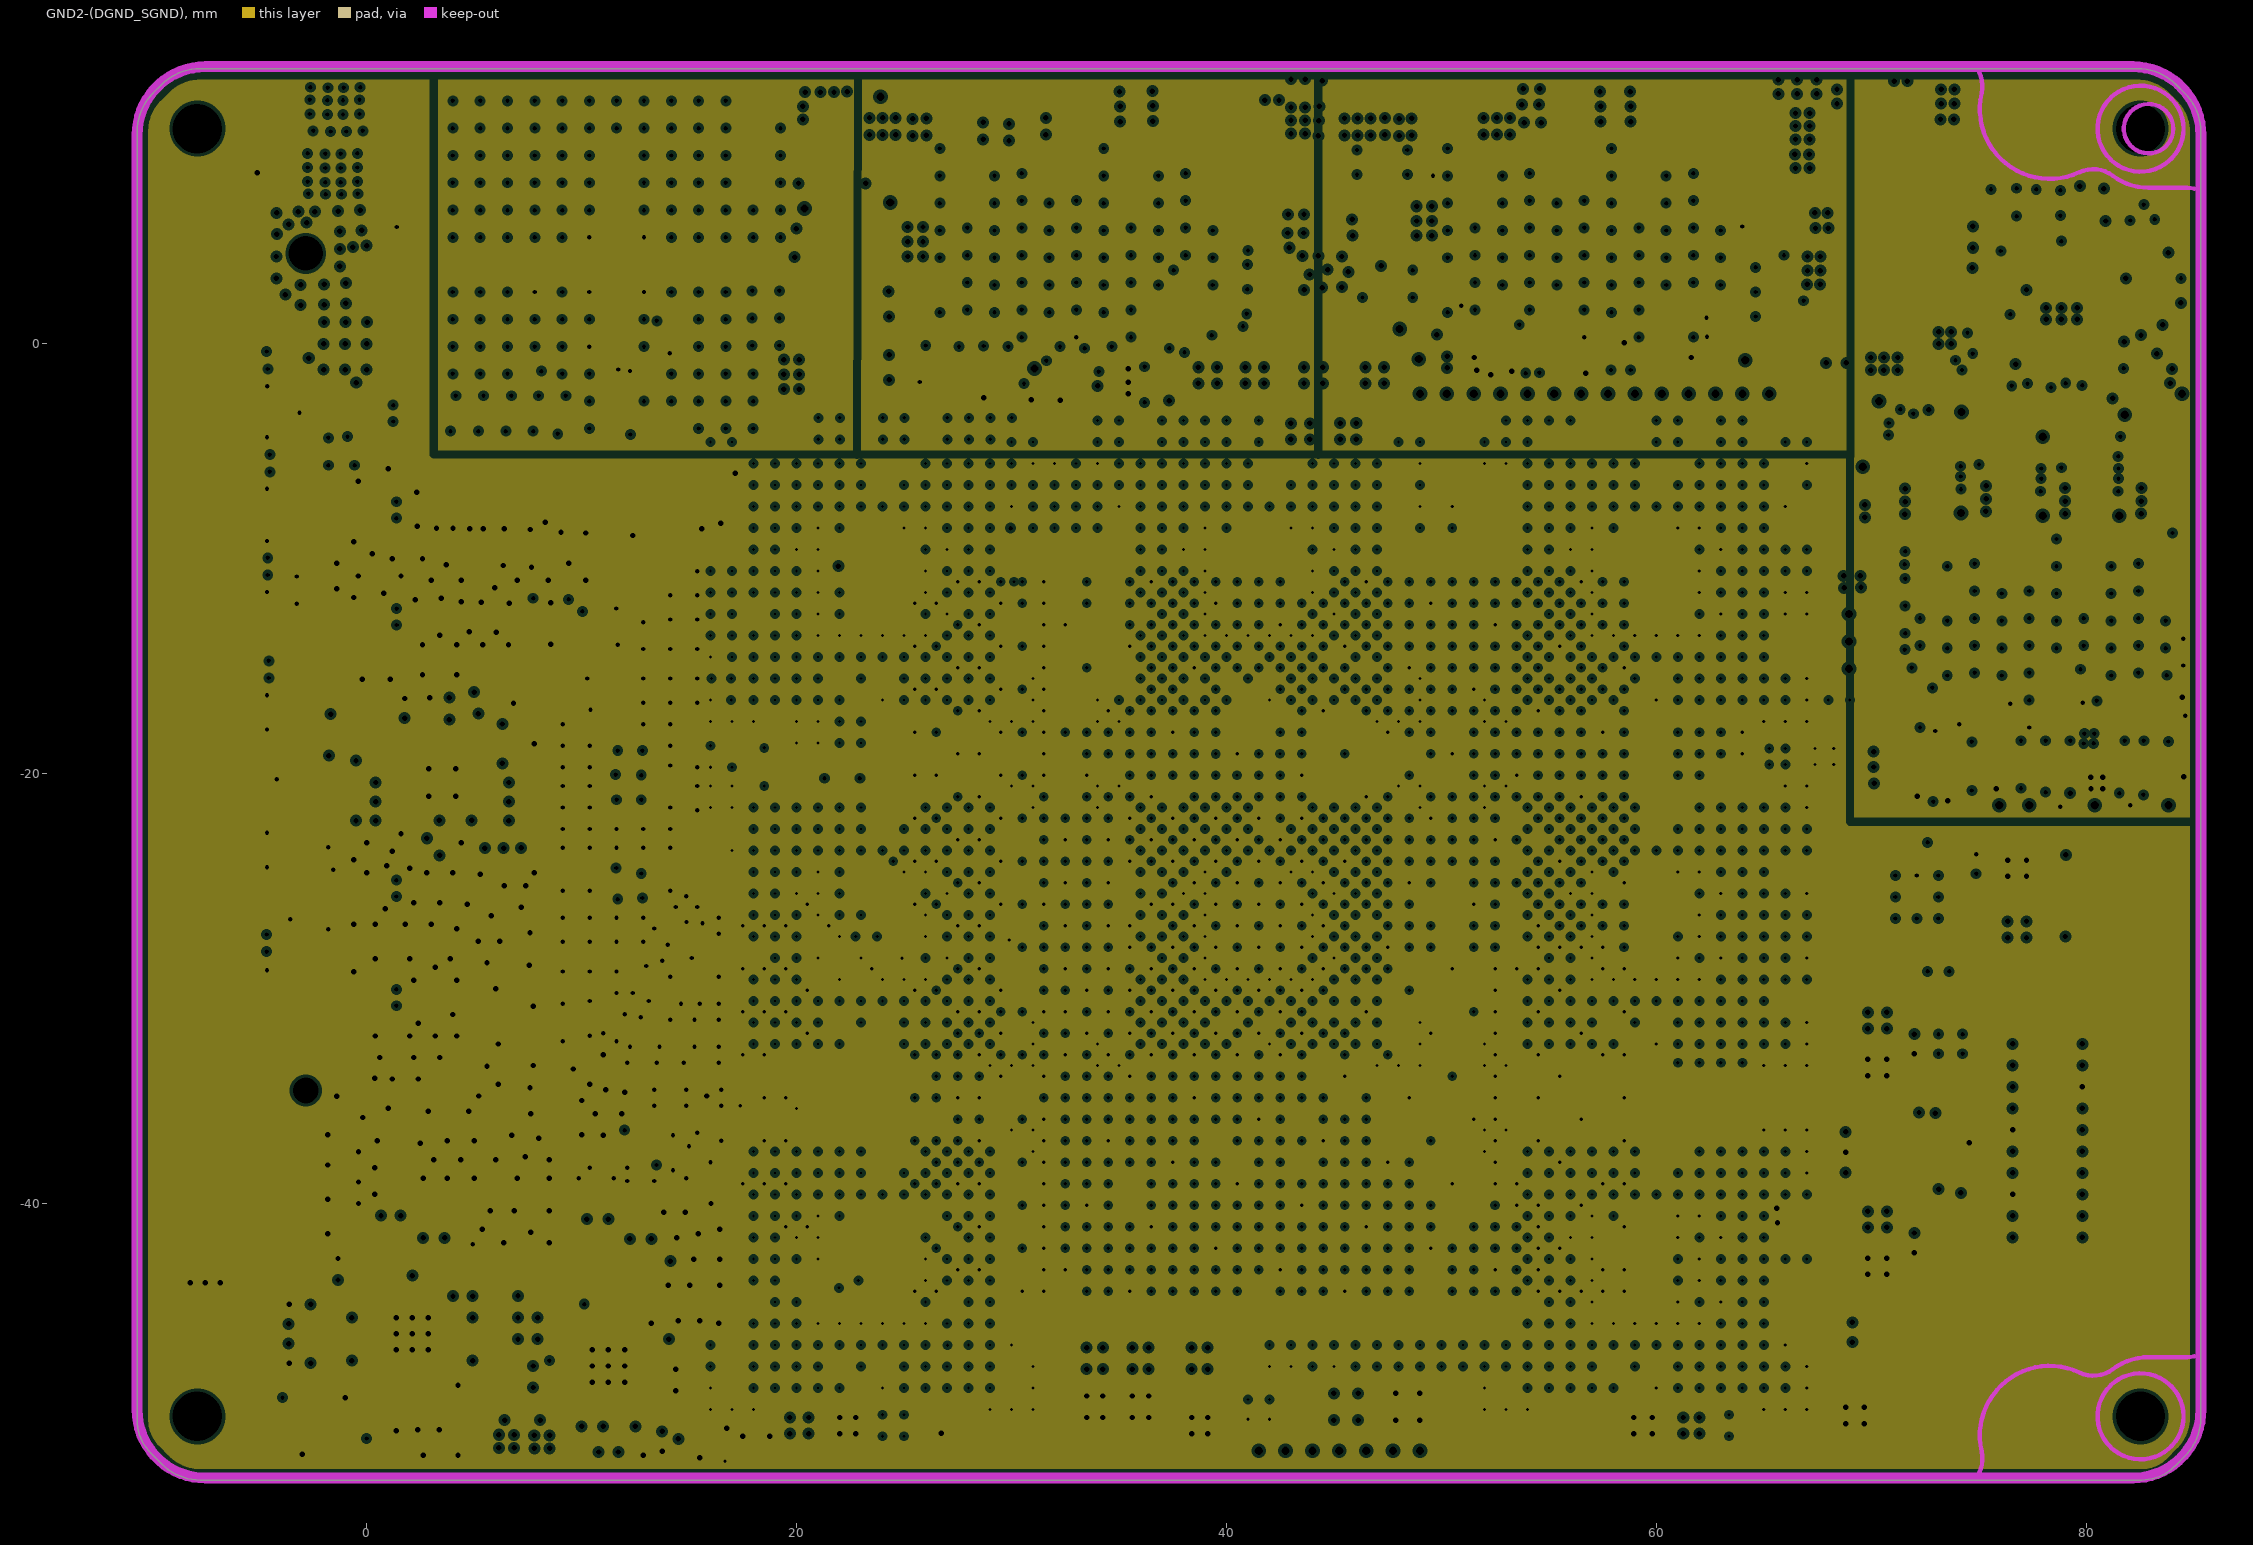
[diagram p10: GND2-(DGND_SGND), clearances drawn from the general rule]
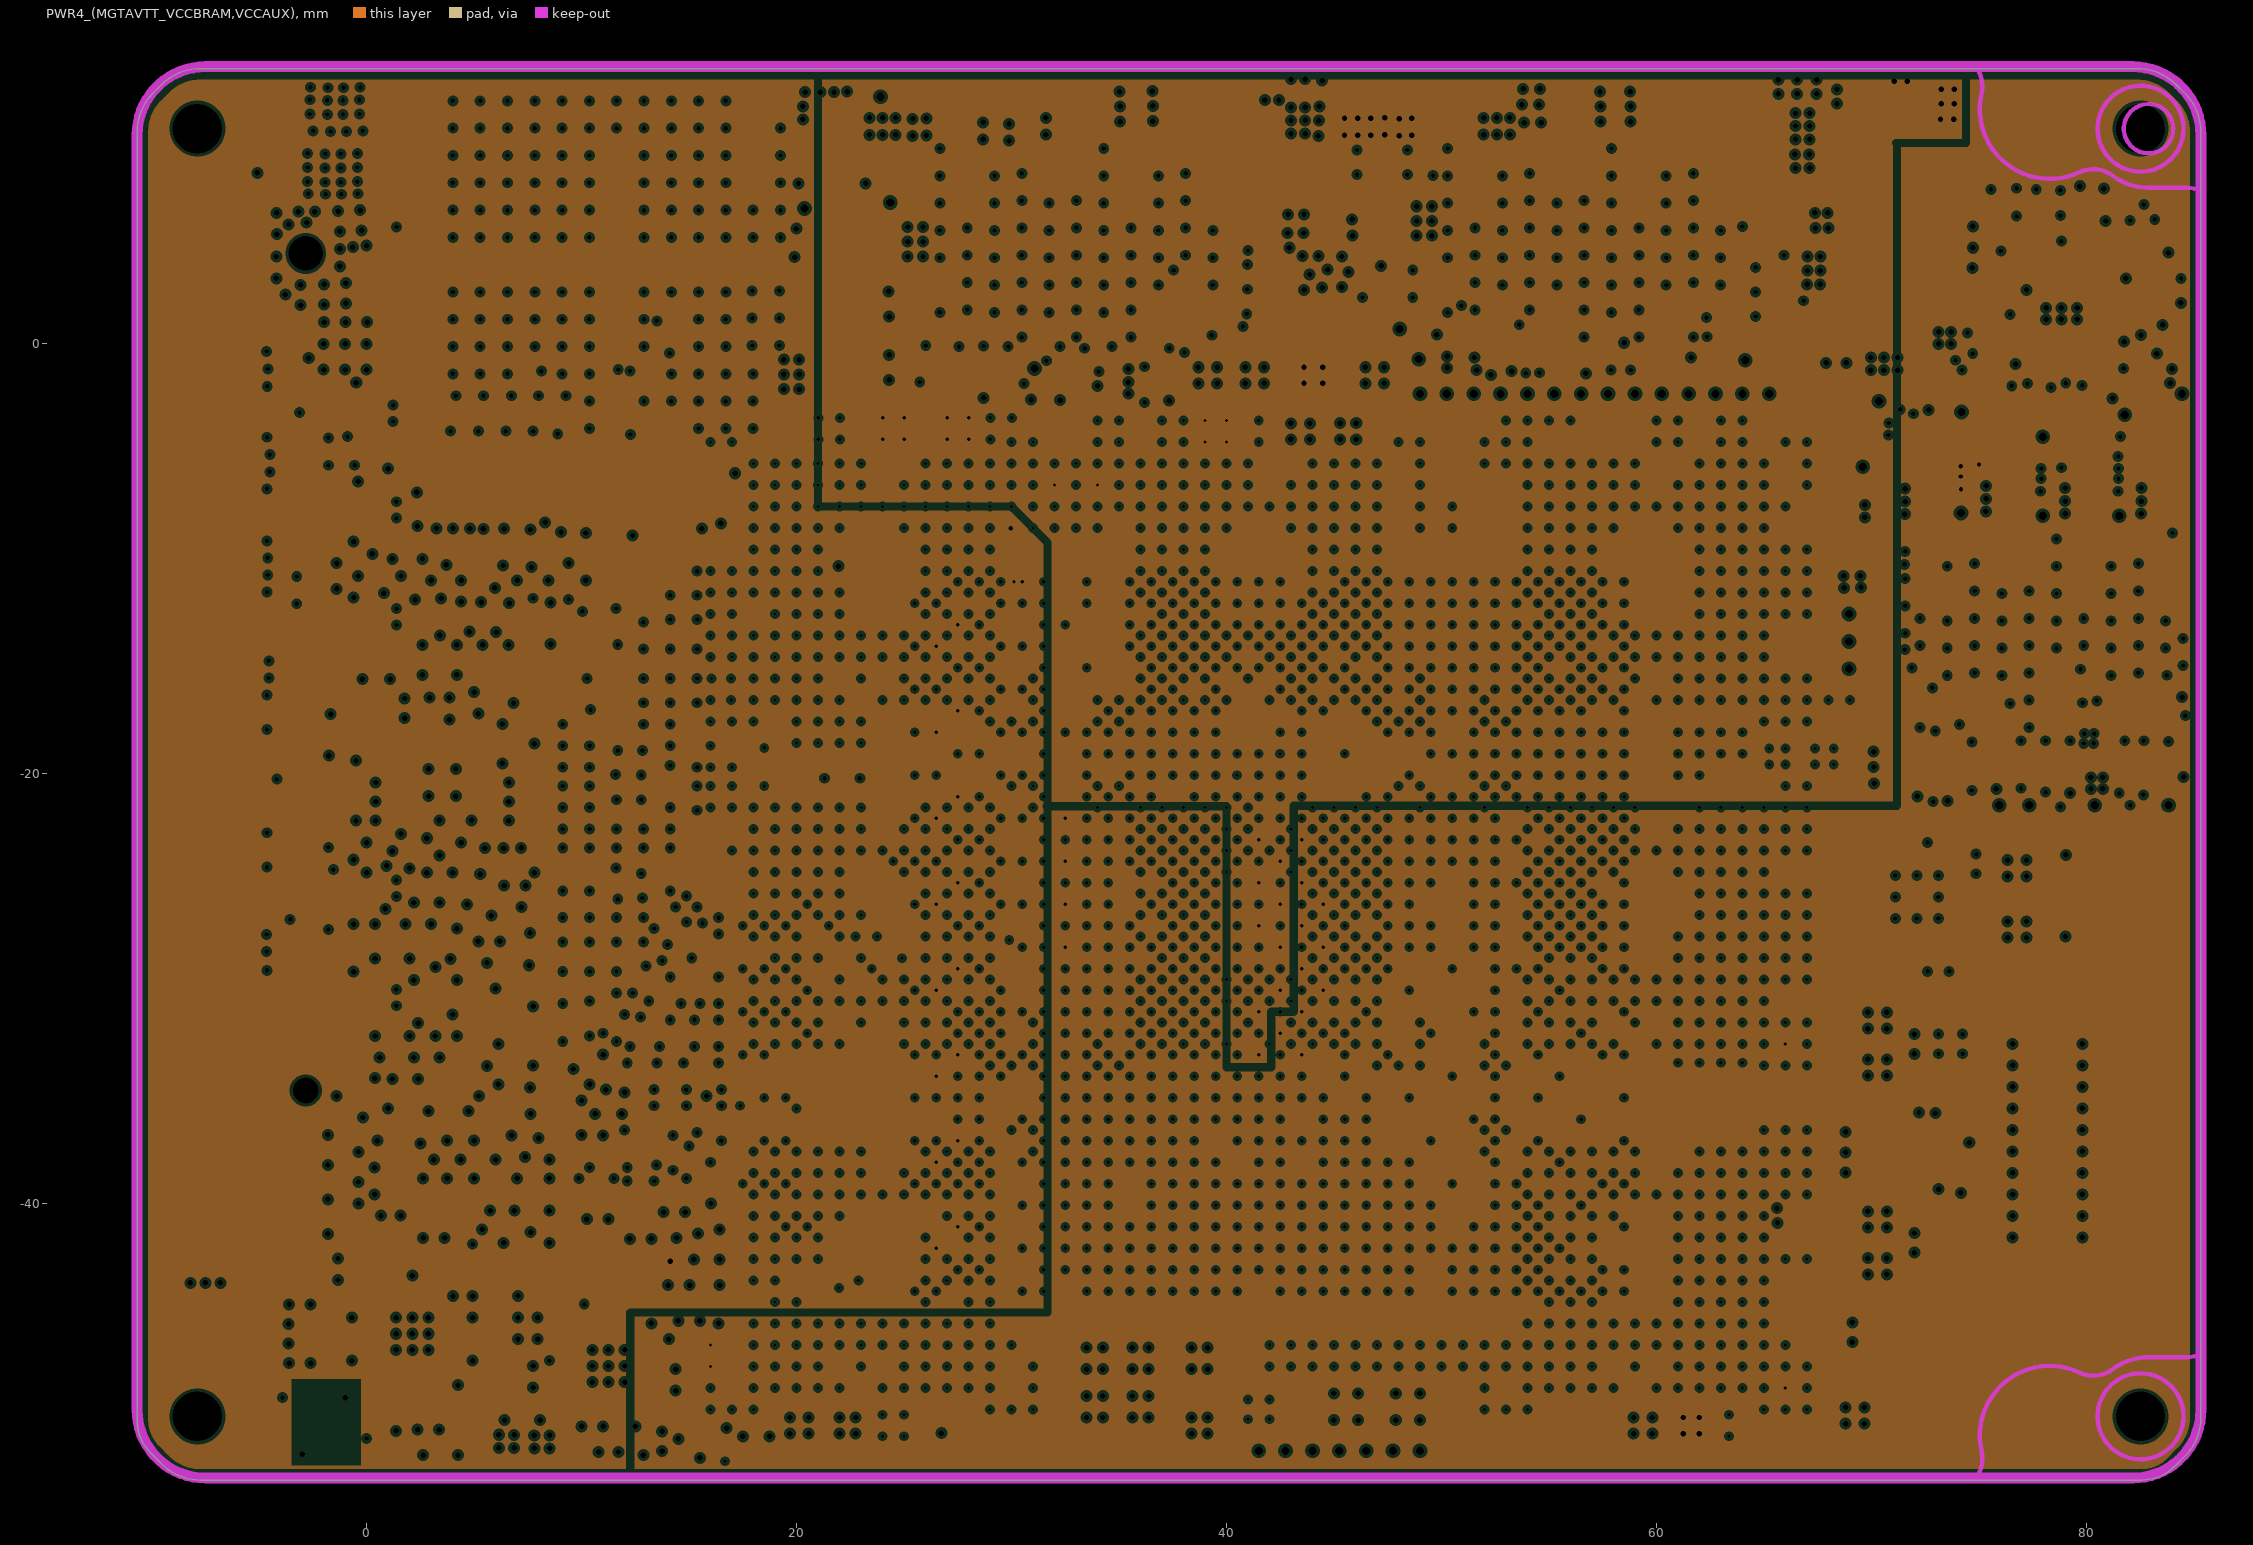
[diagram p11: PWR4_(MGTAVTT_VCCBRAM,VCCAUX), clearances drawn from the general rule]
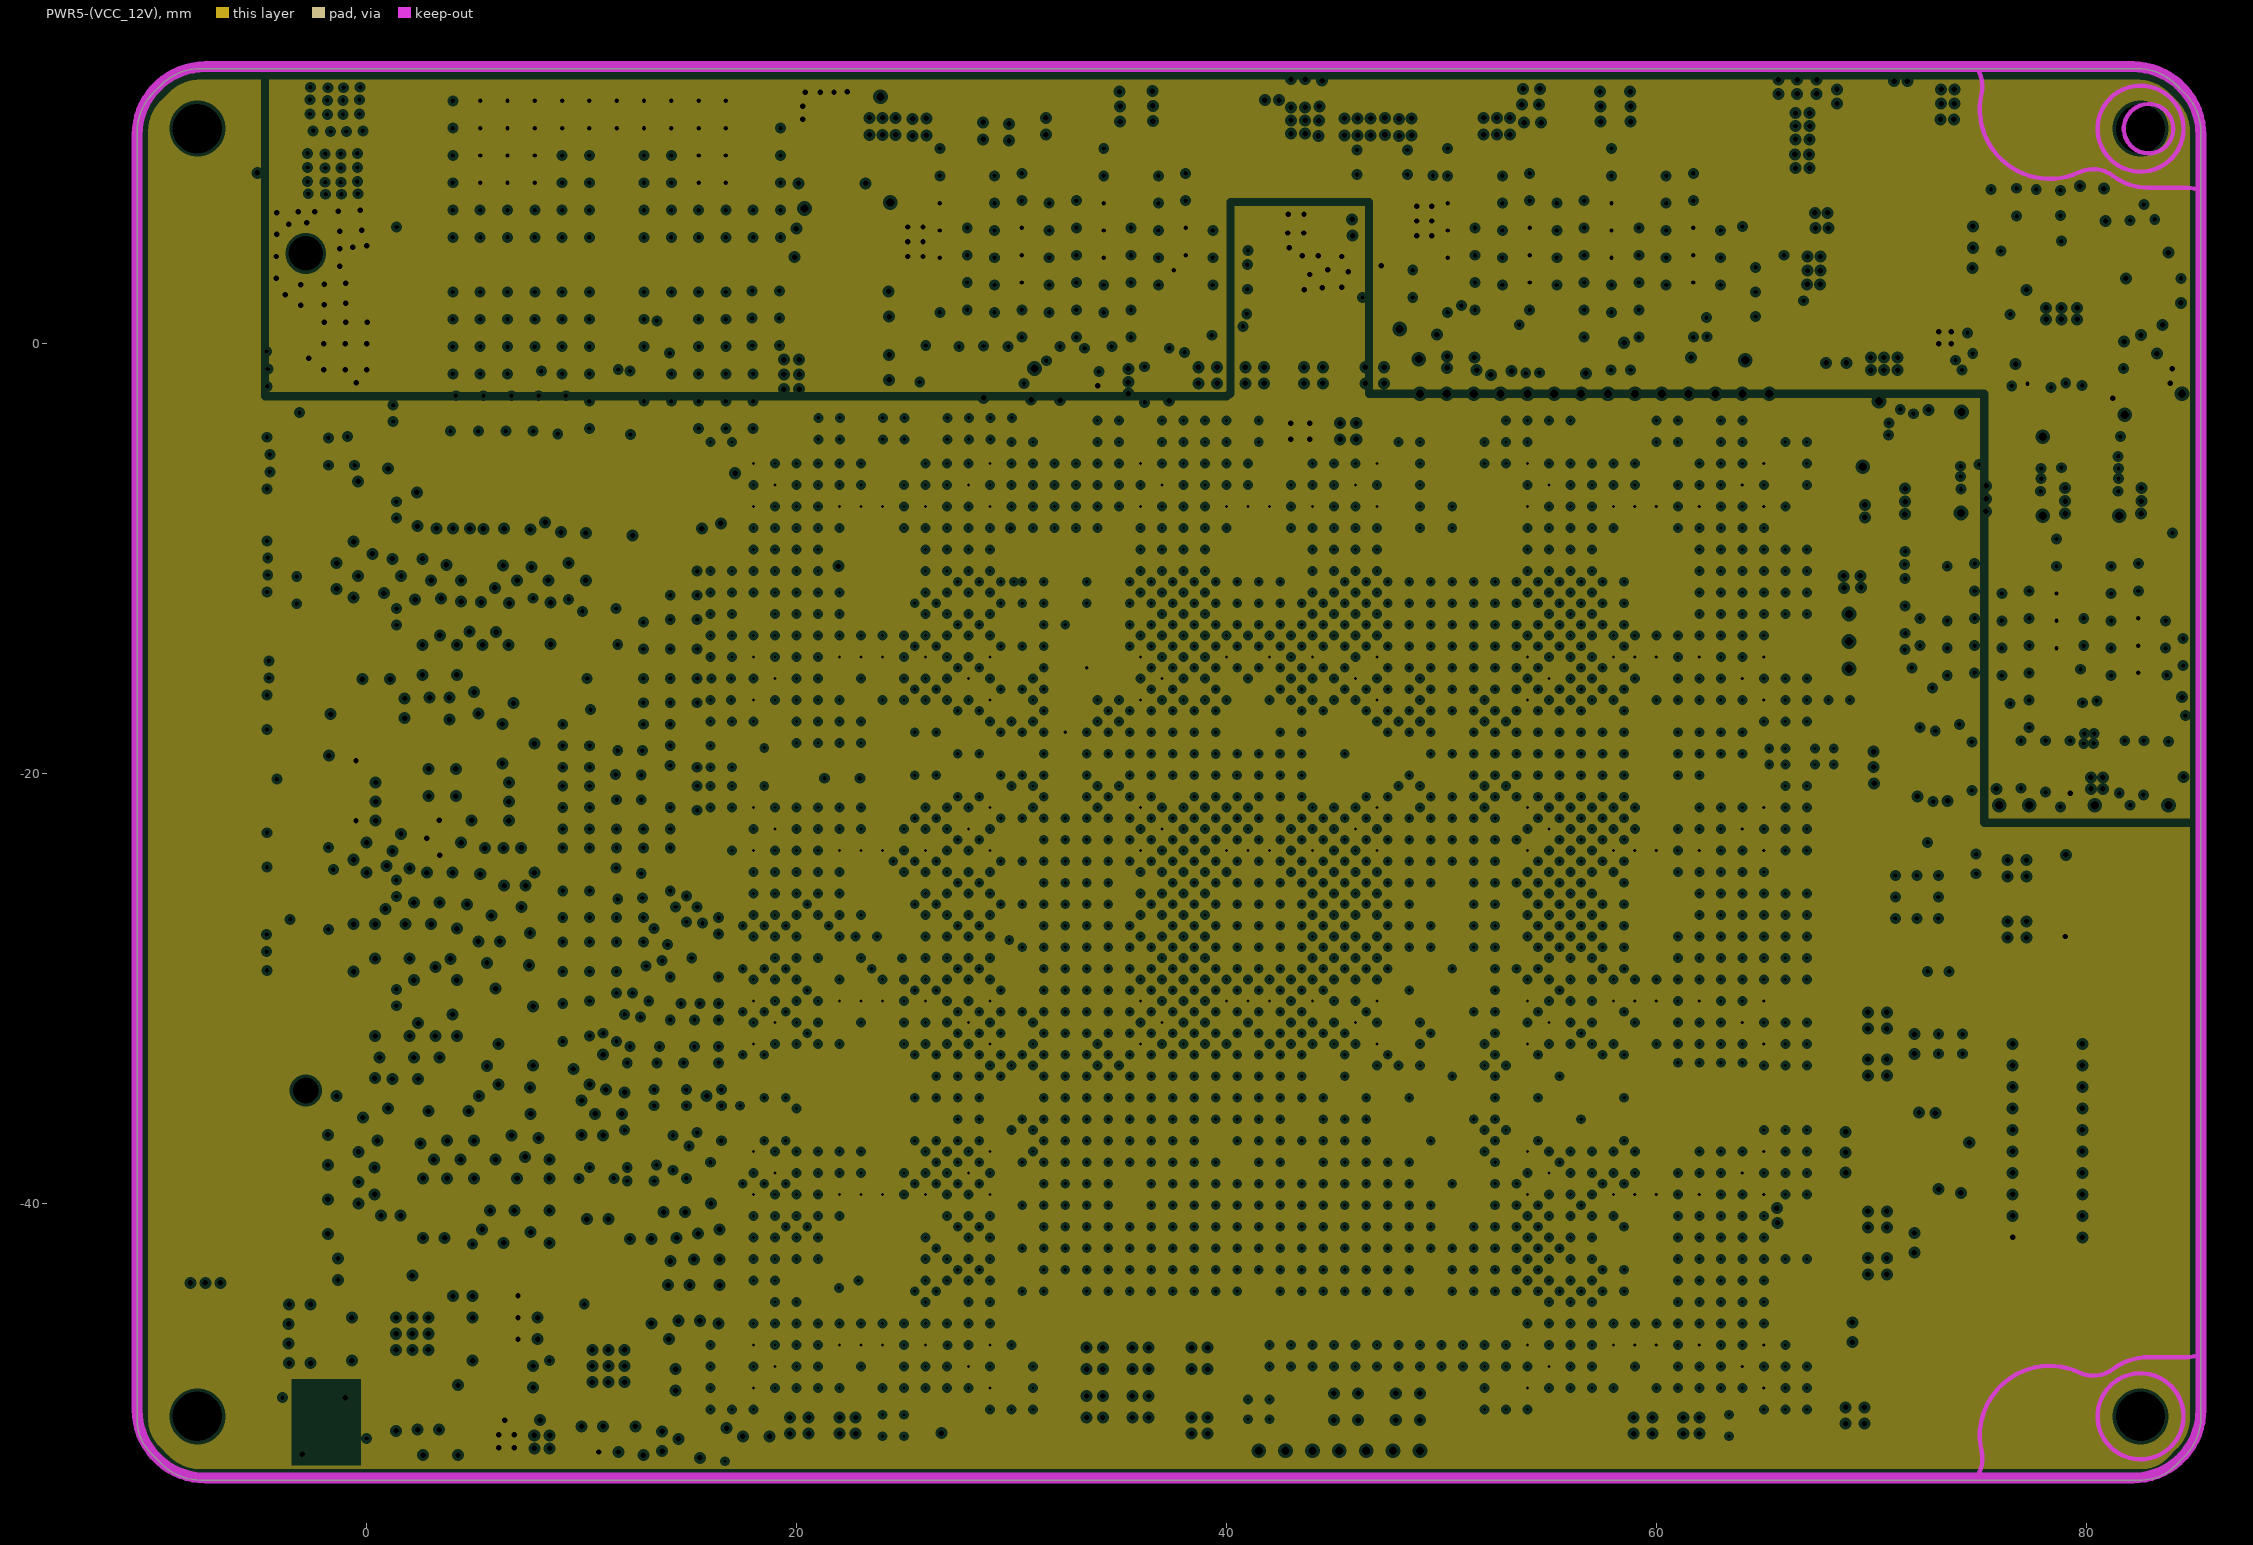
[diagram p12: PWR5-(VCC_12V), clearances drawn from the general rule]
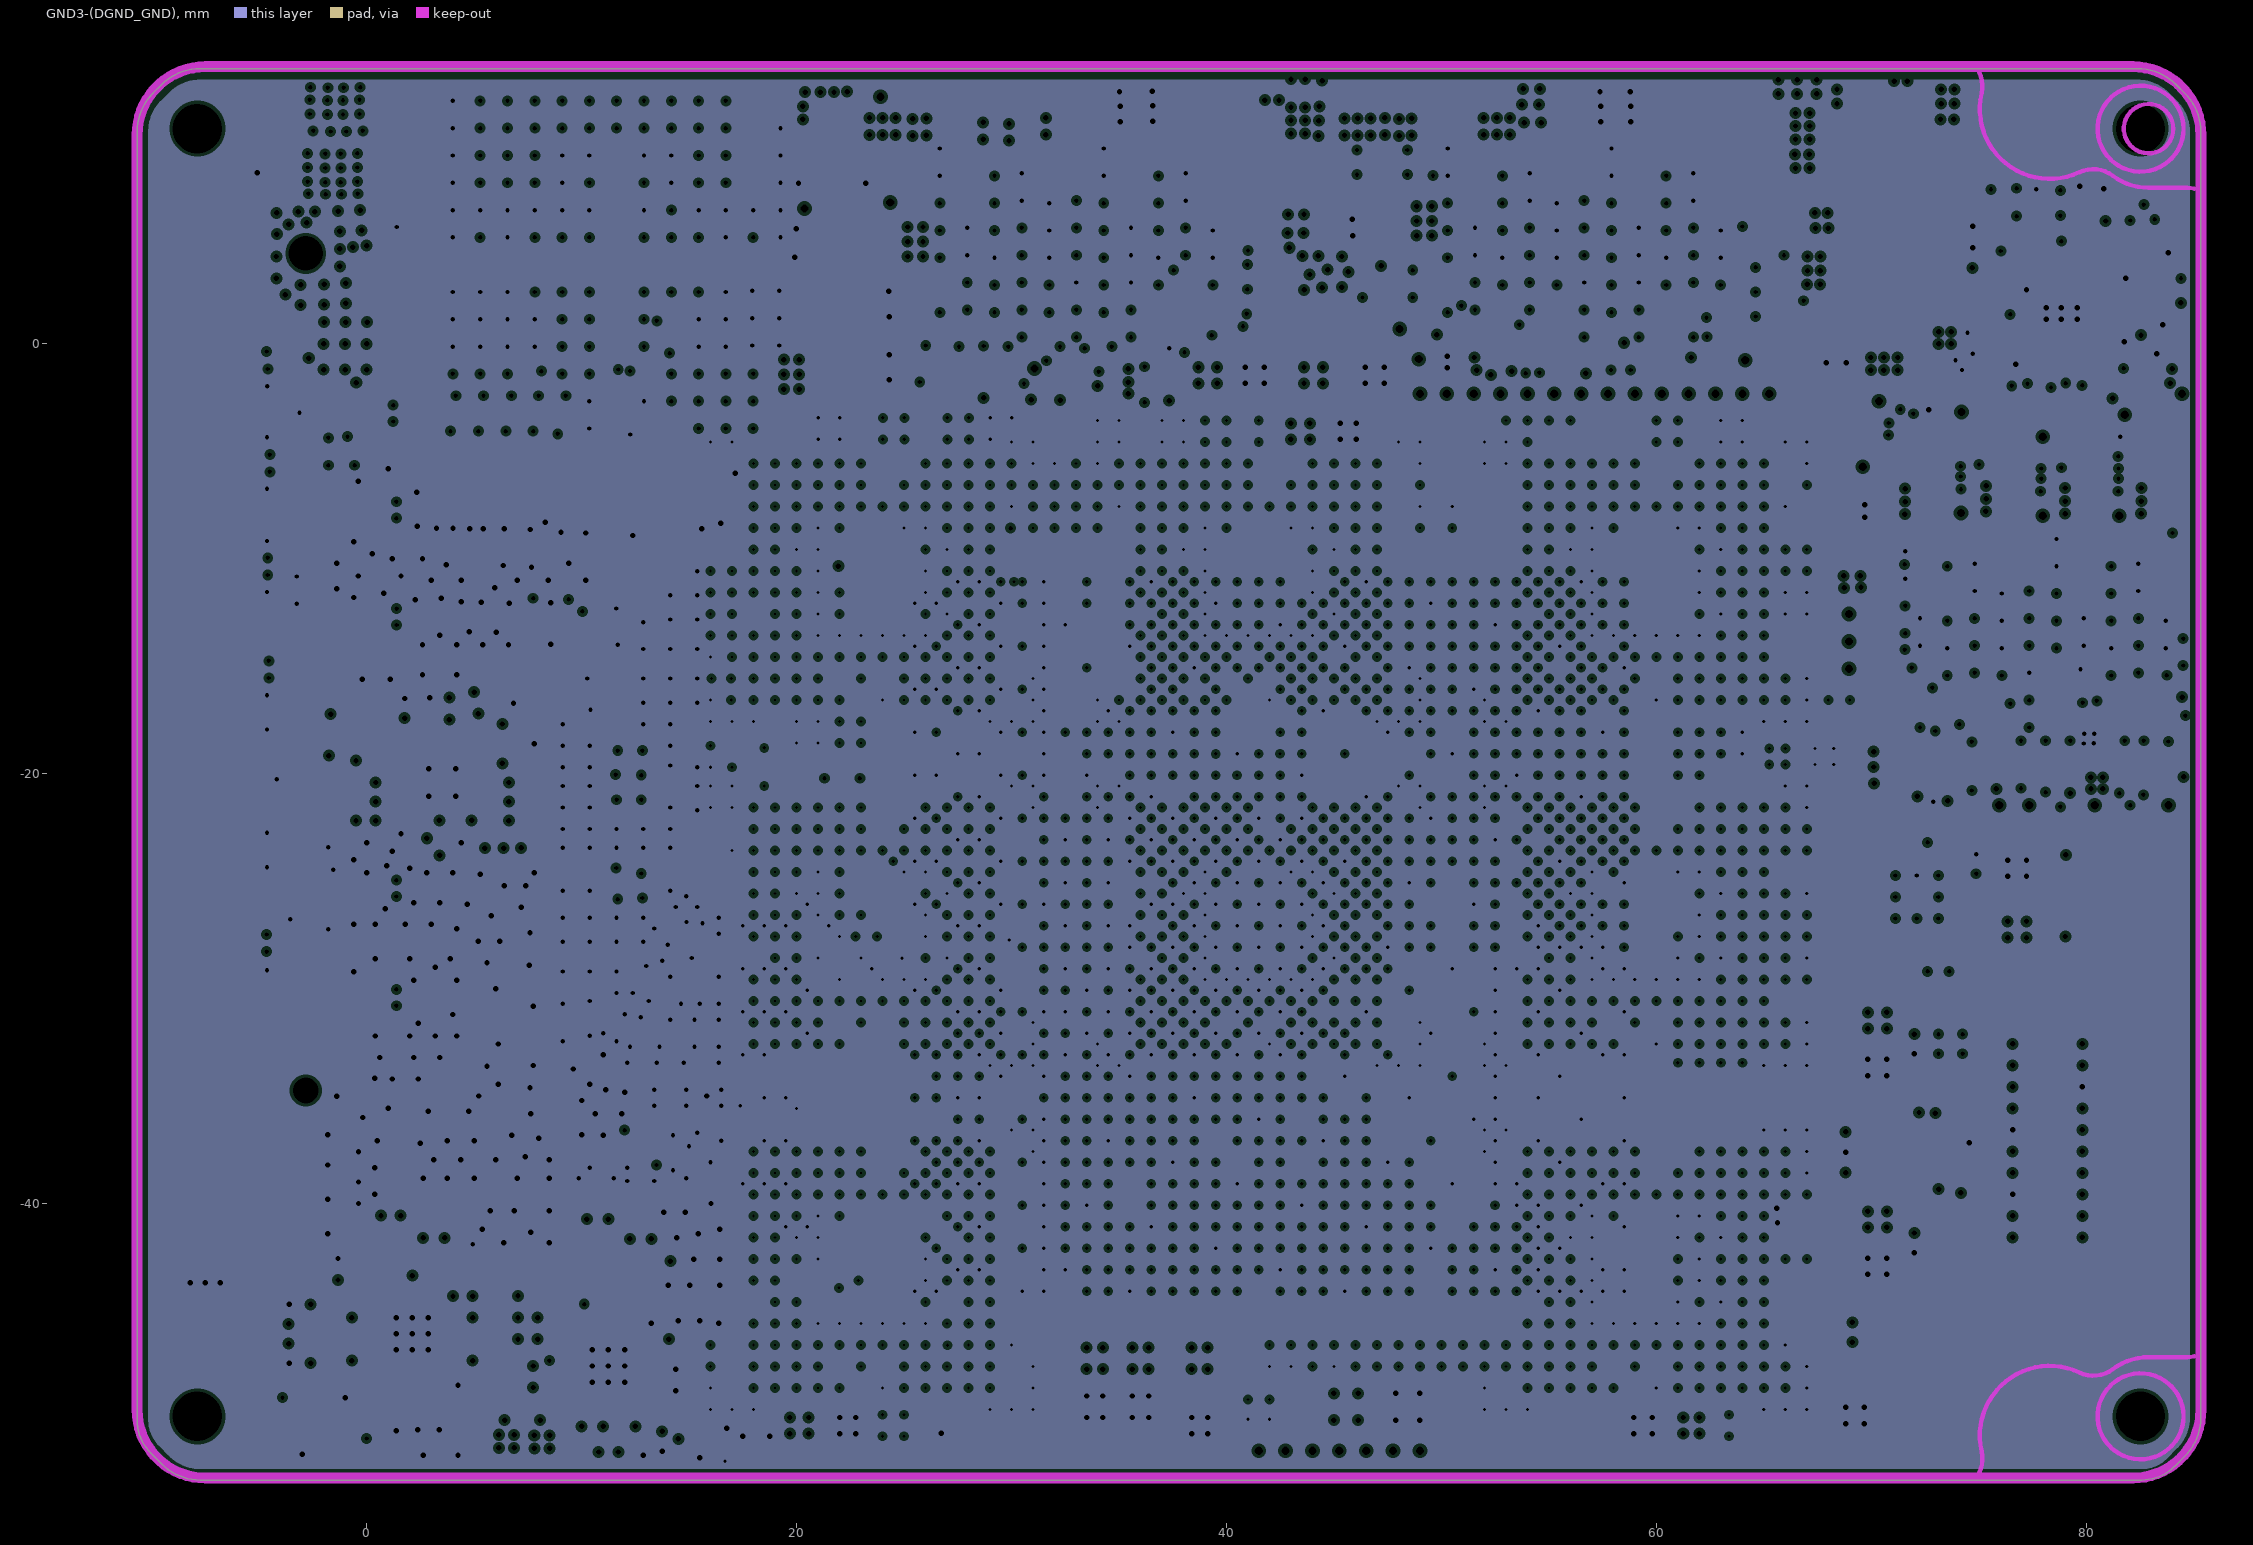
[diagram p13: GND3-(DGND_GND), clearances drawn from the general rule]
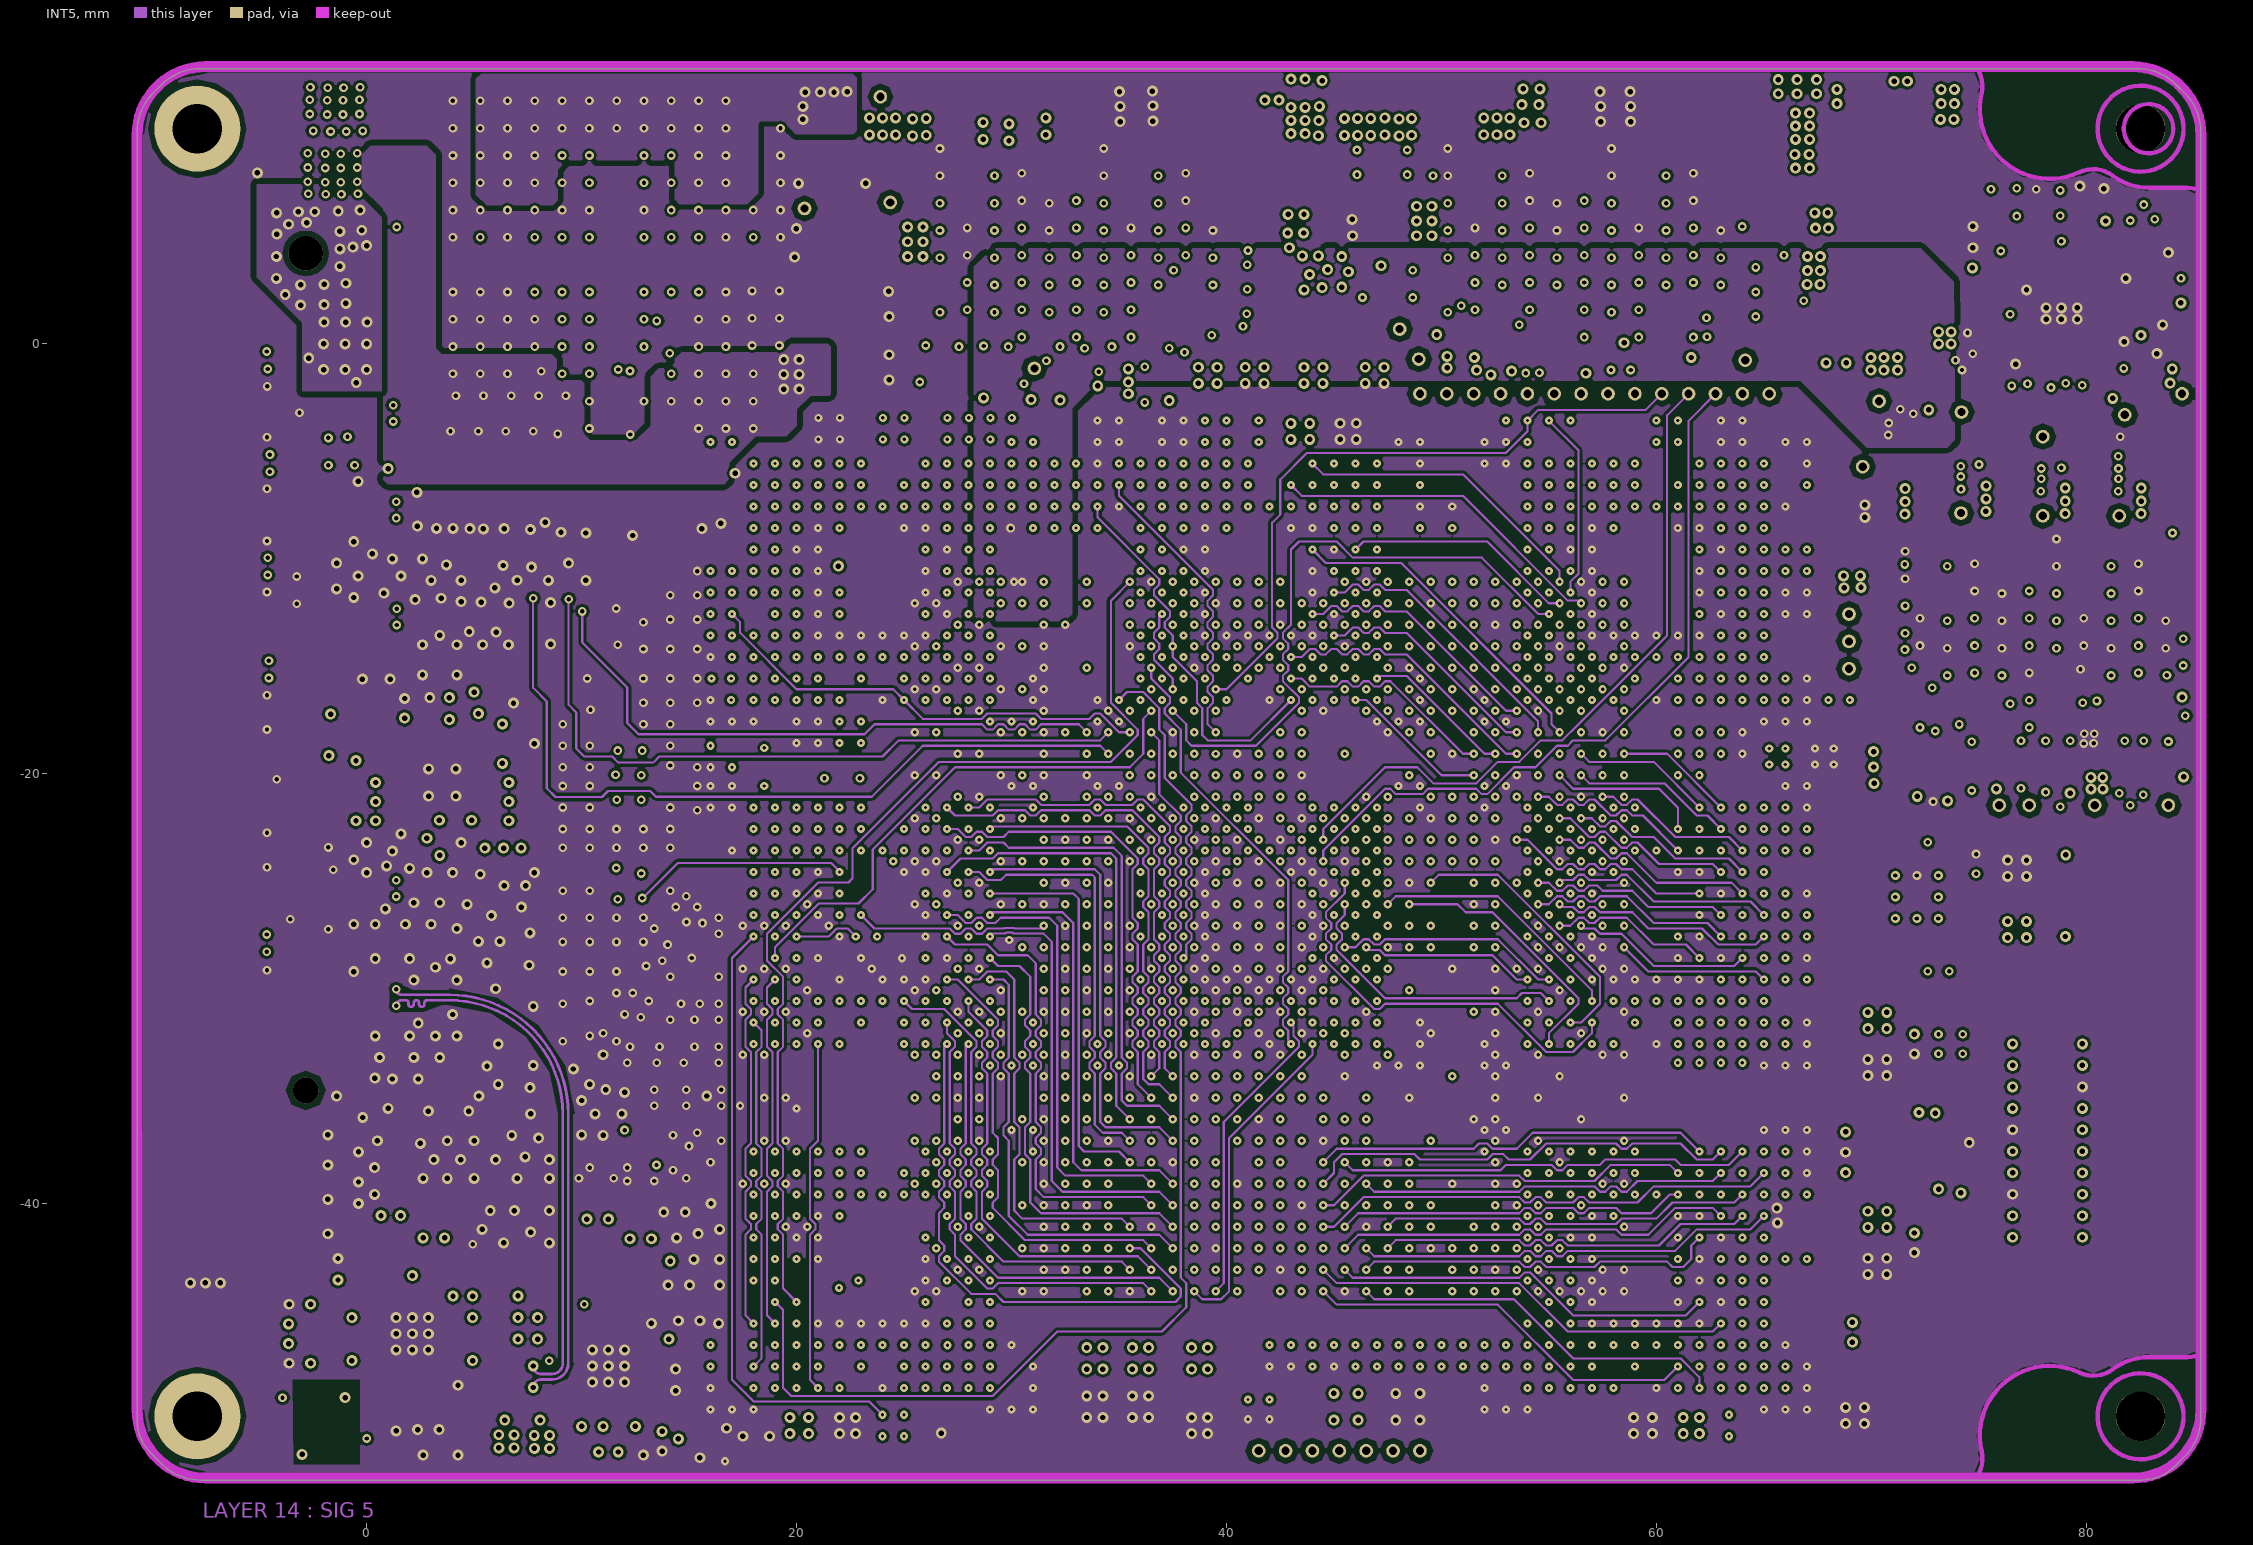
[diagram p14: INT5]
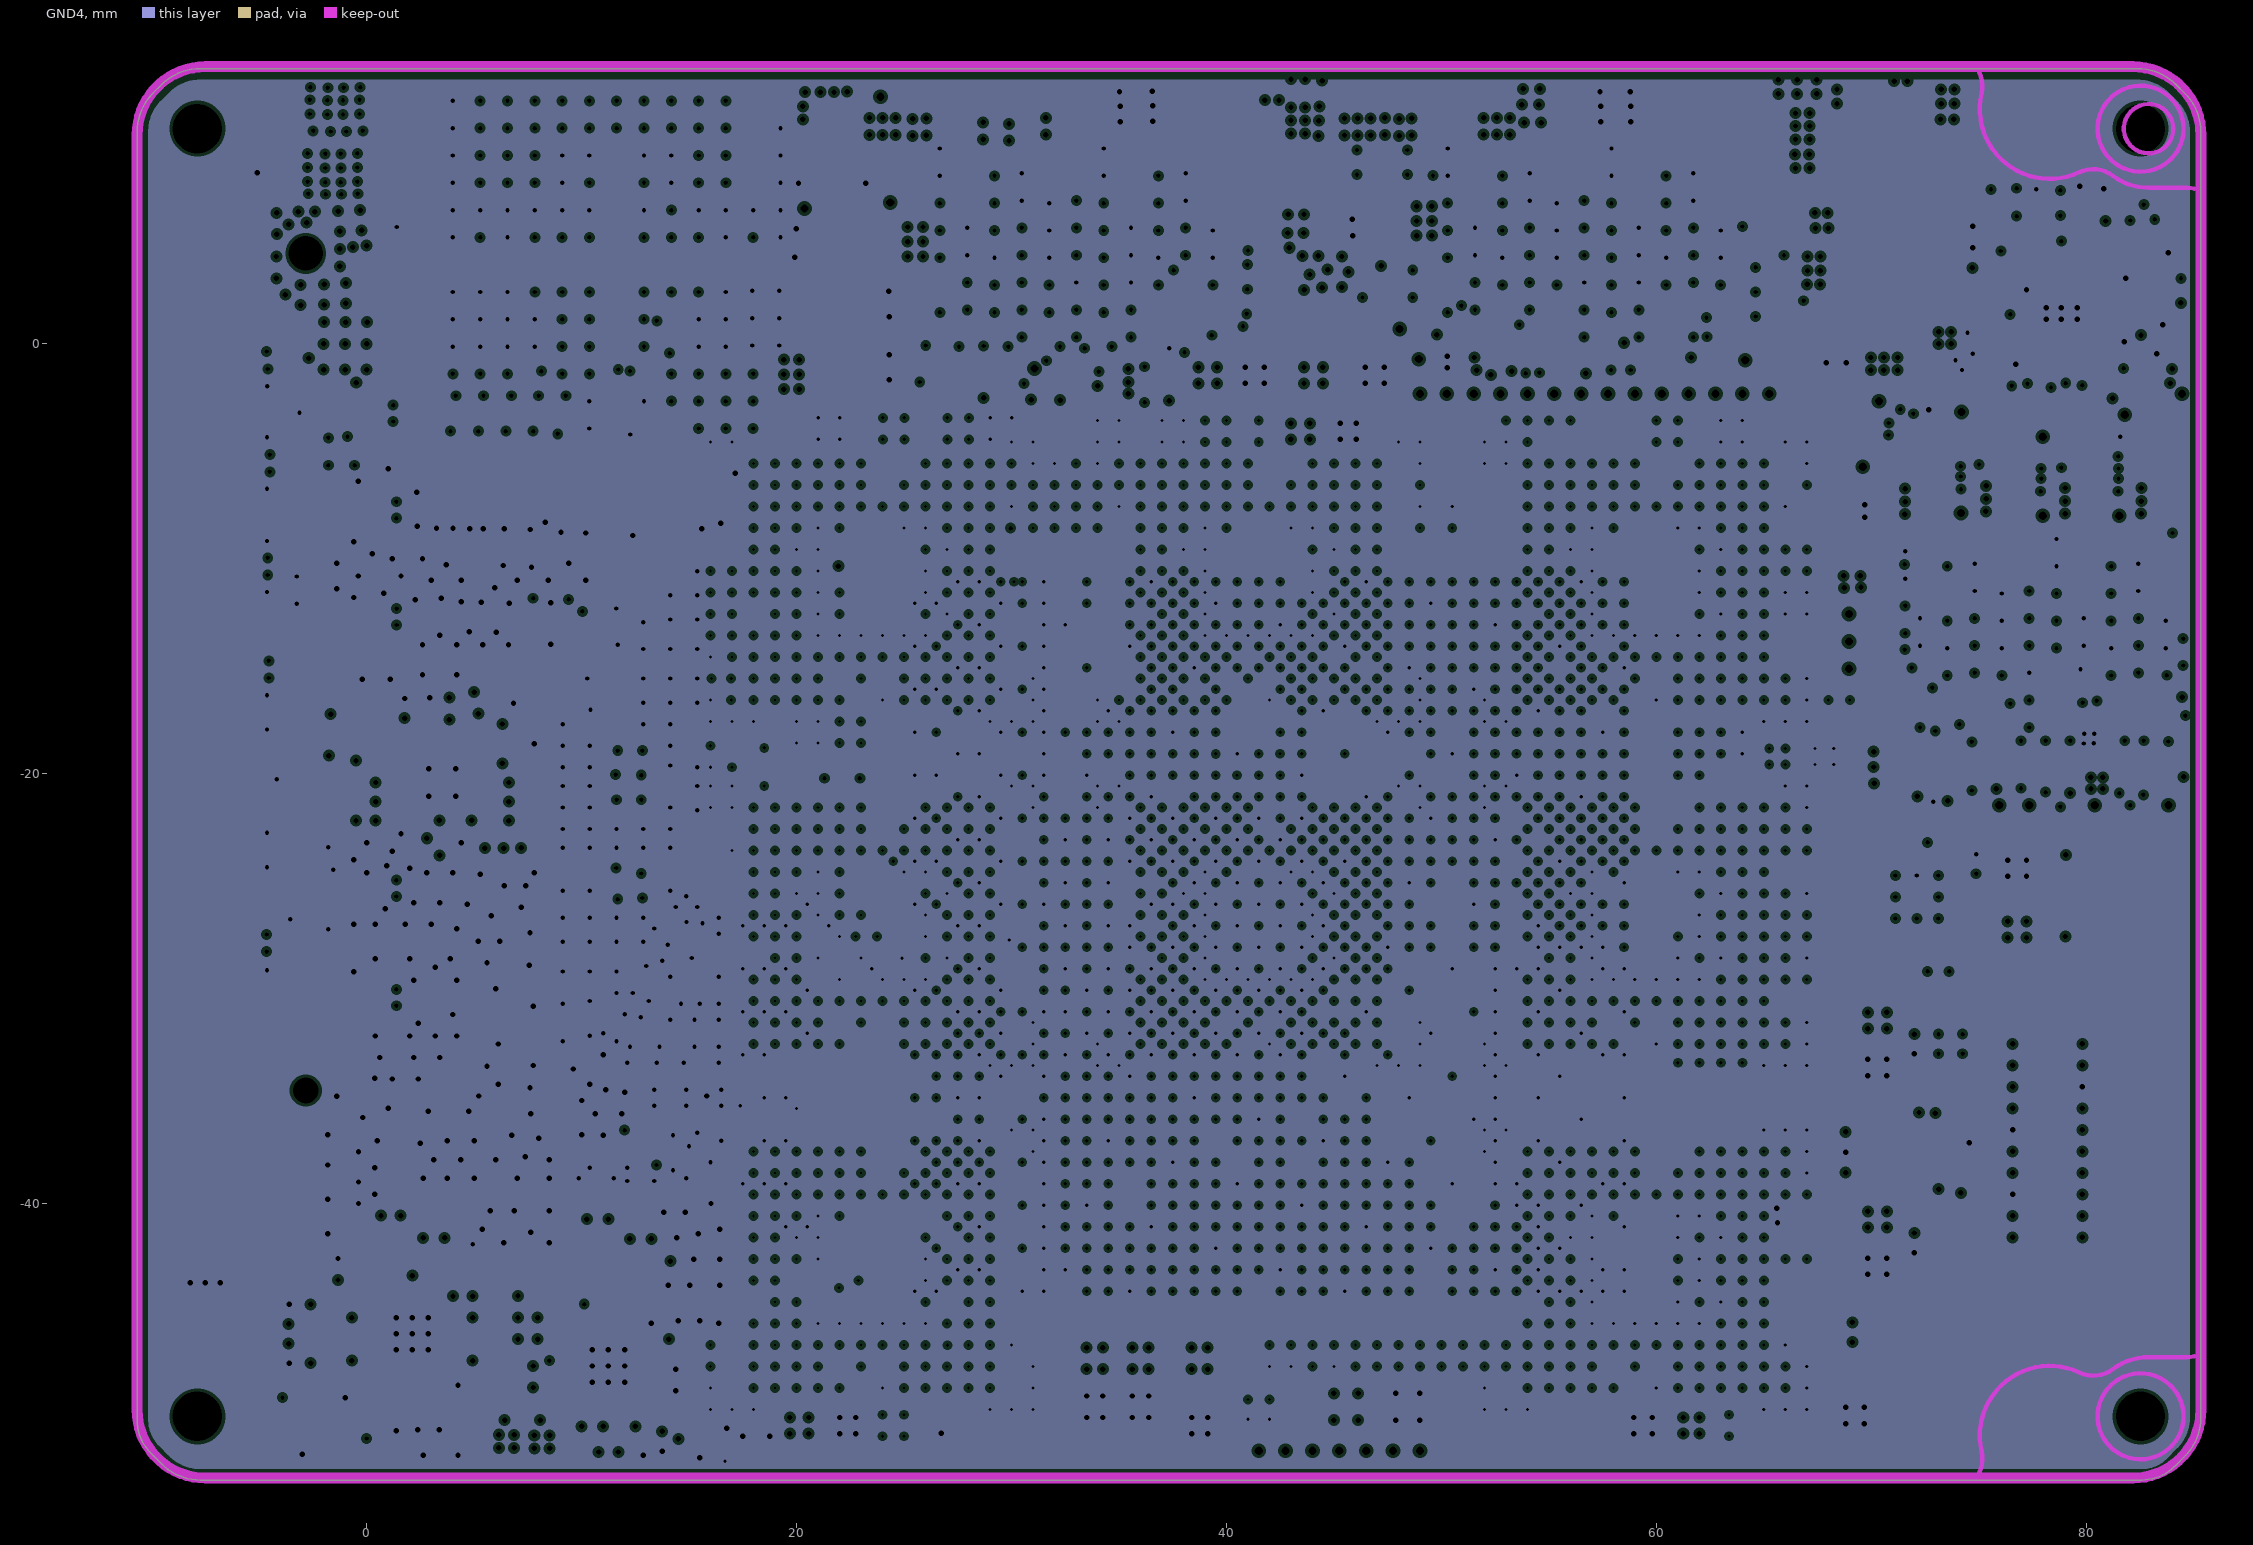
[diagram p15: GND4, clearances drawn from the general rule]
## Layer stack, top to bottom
Top Solder: solder mask 0.0254, Solder Resist, Dk 3.5
Top Layer: signal copper 0.047
Dielectric 1: dielectric 0.0892, FR-4, Dk 4.8
GND1: plane copper 0.032, net GND
Dielectric7: dielectric 0.1016, FR-4, Dk 4.8
INT1: signal copper 0.0175
Dielectric 13: prepreg 0.1234, PP-006, Dk 4.1
PWR1-(VCCIO_MRAM): plane copper 0.032, net VCCIO_MRAM
Dielectric 2: prepreg 0.1016, PP-006, Dk 4.1
INT2: signal copper 0.0175
Dielectric4: dielectric 0.1234, FR-4, Dk 4.8
PWR2-(VCCINT): plane copper 0.032, net VCCINT
Dielectric 12: prepreg 0.1016, PP-006, Dk 4.1
INT3: signal copper 0.0175
Dielectric 14: prepreg 0.1234, PP-006, Dk 4.1
PWR3_(12V_MGTAVCC): plane copper 0.032, net (Multiple Nets)
Dielectric 11: prepreg 0.1016, PP-006, Dk 4.1
INT4: signal copper 0.0175
Dielectric 10: prepreg 0.1234, PP-006, Dk 4.1
GND2-(DGND_SGND): plane copper 0.032, net (Multiple Nets)
Dielectric 9: prepreg 0.0762, PP-006, Dk 4.1
PWR4_(MGTAVTT_VCCBRAM,VCCAUX): plane copper 0.032, net (Multiple Nets)
Dielectric 8: prepreg 0.084, PP-006, Dk 4.1
PWR5-(VCC_12V): plane copper 0.032, net (Multiple Nets)
Dielectric 7: prepreg 0.0762, PP-006, Dk 4.1
GND3-(DGND_GND): plane copper 0.032, net GND
Dielectric 16: prepreg 0.1234, PP-006, Dk 4.1
INT5: signal copper 0.0175
Dielectric 6: prepreg 0.1016, PP-006, Dk 4.1
GND4: plane copper 0.032, net GND
Dielectric 5: prepreg 0.1234, PP-006, Dk 4.1
INT6: signal copper 0.0175
Dielectric 15: prepreg 0.1016, PP-006, Dk 4.1
PWR6_(VCCO): plane copper 0.032, net VCCO
Dielectric 4: prepreg 0.1234, PP-006, Dk 4.1
INT7: signal copper 0.0175
Dielectric 19: prepreg 0.1016, PP-006, Dk 4.1
GND5: plane copper 0.032, net GND
Dielectric 17: prepreg 0.1234, PP-006, Dk 4.1
INT8: signal copper 0.0175
Dielectric 18: prepreg 0.1016, PP-006, Dk 4.1
GND6: plane copper 0.032, net GND
Dielectric 3: prepreg 0.0892, PP-006, Dk 4.1
Bottom Layer: signal copper 0.047
Bottom Solder: solder mask 0.0254, Solder Resist, Dk 3.5

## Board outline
-7.736,-52.857 cw(c-7.736,-50.317) -9.532,-52.113 -10.033,-51.613 cw(c-8.474,-50.054) -10.679,-50.054 -10.679,9.869 cw(c-8.139,9.869) -9.935,11.665 -9.544,12.056 cw(c-7.748,10.26) -7.748,12.8 82.388,12.8 cw(c82.388,10.26) 84.184,12.056 84.59,11.65 cw(c82.794,9.854) 85.334,9.854 85.334,-4.616 85.33,-4.62 85.334,-4.624 85.334,-31.17 85.334,-49.656 85.334,-49.944 cw(c82.794,-49.944) 84.59,-51.74 84.11,-52.22 cw(c82.571,-50.681) 82.571,-52.857

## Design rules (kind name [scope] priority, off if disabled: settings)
Clearance Keepout [OnLayer('Keep-Out Layer')] p1: gap=0 ignorepadtopadclearanceinfootprint=FALSE
Clearance diff [InNetClass('DIFF_PCIE')  or InNetClass('DIFF_CLOCK')] p2: gap=0.099 ignorepadtopadclearanceinfootprint=FALSE except(0.086: Arc-Via; 0.127: Arc-Fill Arc-Region Track-Fill Track-Region SMDPad-Fill SMDPad-Poly SMDPad-Region THPad-Fill THPad-Poly THPad-Region Via-Fill Via-Poly Via-Region Fill-Fill; 0.203: Arc-Poly Track-Poly; 0.381: Fill-Poly Fill-Region Poly-Poly Poly-Region Region-Region)
Clearance [All] p3: gap=0.112 ignorepadtopadclearanceinfootprint=FALSE except(0.127: Arc-Poly Track-Poly SMDPad-Poly Via-Poly; 0.254: THPad-Poly Fill-Poly Poly-Poly)
DiffPairsRouting pcie [InDifferentialPairClass('All Differential Pairs')] p1: maxlimit=0.127 minlimit=0.127 mostfreqgap=0.127 toplayer_minwidth=0.127 toplayer_maxwidth=0.127 toplayer_prefwidth=0.127 midlayer1_minwidth=0.127 midlayer1_maxwidth=0.127 midlayer1_prefwidth=0.127 midlayer2_minwidth=0.127 midlayer2_maxwidth=0.127 midlayer2_prefwidth=0.127 midlayer3_minwidth=0.127 midlayer3_maxwidth=0.127 midlayer3_prefwidth=0.127 midlayer4_minwidth=0.127 midlayer4_maxwidth=0.127 midlayer4_prefwidth=0.127 midlayer5_minwidth=0.127 midlayer5_maxwidth=0.127 midlayer5_prefwidth=0.127 midlayer7_minwidth=0.127 midlayer7_maxwidth=0.127 midlayer7_prefwidth=0.127 midlayer8_minwidth=0.127 midlayer8_maxwidth=0.127 midlayer8_prefwidth=0.127 midlayer14_minwidth=0.127 midlayer14_maxwidth=0.127 midlayer14_prefwidth=0.127 bottomlayer_minwidth=0.127 bottomlayer_maxwidth=0.127 bottomlayer_prefwidth=0.127 maxuncoupledlength=12.7
DiffPairsRouting [InDifferentialPairClass('All Differential Pairs')] p2 off: maxlimit=0.152 minlimit=0.152 mostfreqgap=0.152 toplayer_minwidth=0.102 toplayer_maxwidth=0.102 toplayer_prefwidth=0.102 midlayer1_minwidth=0.102 midlayer1_maxwidth=0.102 midlayer1_prefwidth=0.102 midlayer2_minwidth=0.102 midlayer2_maxwidth=0.102 midlayer2_prefwidth=0.102 midlayer3_minwidth=0.102 midlayer3_maxwidth=0.102 midlayer3_prefwidth=0.102 midlayer4_minwidth=0.102 midlayer4_maxwidth=0.102 midlayer4_prefwidth=0.102 midlayer5_minwidth=0.102 midlayer5_maxwidth=0.102 midlayer5_prefwidth=0.102 midlayer7_minwidth=0.102 midlayer7_maxwidth=0.102 midlayer7_prefwidth=0.102 midlayer8_minwidth=0.102 midlayer8_maxwidth=0.102 midlayer8_prefwidth=0.102 midlayer14_minwidth=0.102 midlayer14_maxwidth=0.102 midlayer14_prefwidth=0.102 bottomlayer_minwidth=0.102 bottomlayer_maxwidth=0.102 bottomlayer_prefwidth=0.102 maxuncoupledlength=12.7
FanoutControl Fanout_BGA [IsBGA] p1: bgadir=Out bgaviamode=Centered fanoutstyle=Auto fanoutdirection=InThenOut viagrid=0.025 // Fanout_BGA (Default Rule)
HoleToHoleClearance [All] p1: gap=0.229 allowstackedmicrovias=TRUE
PlaneClearance PlaneClearance_2 [(ObjectKind = 'Pad') And (Name = 'Free-MTH') And (AsMils(HoleDiameter) = 90)] p1: clearance=0.635
PlaneClearance PlaneClearance_1 [ISPAD] p2: clearance=0.254
PlaneClearance [All] p3: clearance=0.152
PlaneConnect [All] p1: planeconnectstyle=Relief reliefexpansion=0.127 reliefentries=4 reliefconductorwidth=0.127 reliefairgap=0.127
PolygonConnect [All] p1: connectstyle=Direct reliefconductorwidth=0.254 reliefentries=4 polygonreliefangle="90 Angle" airgapwidth=0.254
RoomDefinition PAGE29_PWR_SUPPLY3 [InComponentClass('PAGE29_PWR_SUPPLY3')] p1: confinementstyle=ConfineIn formatcopy=TRUE lockcomponents=FALSE outline 86.48,-21.681 289.363,-21.681 289.363,-14.086 86.48,-14.086
RoomDefinition PAGE30_PWR_SUPPLY4 [InComponentClass('PAGE30_PWR_SUPPLY4')] p2: confinementstyle=ConfineIn formatcopy=TRUE lockcomponents=FALSE outline 86.48,-12.816 230.232,-12.816 230.232,-5.222 86.48,-5.222
RoomDefinition PAGE32_PWR_SUPPLY6 [InComponentClass('PAGE32_PWR_SUPPLY6')] p3: confinementstyle=ConfineIn formatcopy=TRUE lockcomponents=FALSE outline 86.48,7.593 217.513,7.593 217.513,12.343 86.48,12.343
RoomDefinition PAGE31_PWR_SUPPLY5 [InComponentClass('PAGE31_PWR_SUPPLY5')] p4: confinementstyle=ConfineIn formatcopy=TRUE lockcomponents=FALSE outline 86.48,-3.952 316.109,-3.952 316.109,6.323 86.48,6.323
RoomDefinition PAGE28_PWR_SUPPLY2 [InComponentClass('PAGE28_PWR_SUPPLY2')] p5: confinementstyle=ConfineIn formatcopy=TRUE lockcomponents=FALSE outline 86.48,-30.545 228.428,-30.545 228.428,-22.951 86.48,-22.951
RoomDefinition PAGE27_PWR_SUPPLY1 [InComponentClass('PAGE27_PWR_SUPPLY1')] p6: confinementstyle=ConfineIn formatcopy=TRUE lockcomponents=FALSE outline 86.48,-39.41 209.41,-39.41 209.41,-31.815 86.48,-31.815
RoomDefinition PAGE26_CRYTAL [InComponentClass('PAGE26_CRYTAL')] p7: confinementstyle=ConfineIn formatcopy=TRUE lockcomponents=FALSE outline -57.22,-94.712 -6.42,-94.712 -6.42,-69.312 -57.22,-69.312
RoomDefinition PAGE25_PCIE_CONN [InComponentClass('PAGE25_PCIE_CONN')] p8: confinementstyle=ConfineIn formatcopy=TRUE lockcomponents=FALSE outline -57.22,-94.712 -6.42,-94.712 -6.42,-69.312 -57.22,-69.312
RoomDefinition PAGE24_MRAM7 [InComponentClass('PAGE24_MRAM7')] p9: confinementstyle=ConfineIn formatcopy=TRUE lockcomponents=FALSE outline -57.22,-94.712 -6.42,-94.712 -6.42,-69.312 -57.22,-69.312
RoomDefinition PAGE23_MRAM6 [InComponentClass('PAGE23_MRAM6')] p10: confinementstyle=ConfineIn formatcopy=TRUE lockcomponents=FALSE outline -57.22,-94.712 -6.42,-94.712 -6.42,-69.312 -57.22,-69.312
RoomDefinition PAGE22_MRAM5 [InComponentClass('PAGE22_MRAM5')] p11: confinementstyle=ConfineIn formatcopy=TRUE lockcomponents=FALSE outline -57.22,-94.712 -6.42,-94.712 -6.42,-69.312 -57.22,-69.312
RoomDefinition PAGE21_MRAM4 [InComponentClass('PAGE21_MRAM4')] p12: confinementstyle=ConfineIn formatcopy=TRUE lockcomponents=FALSE outline -57.22,-94.712 -6.42,-94.712 -6.42,-69.312 -57.22,-69.312
RoomDefinition PAGE20_MRAM3 [InComponentClass('PAGE20_MRAM3')] p13: confinementstyle=ConfineIn formatcopy=TRUE lockcomponents=FALSE outline -57.22,-94.712 -6.42,-94.712 -6.42,-69.312 -57.22,-69.312
RoomDefinition PAGE19_MRAM2 [InComponentClass('PAGE19_MRAM2')] p14: confinementstyle=ConfineIn formatcopy=TRUE lockcomponents=FALSE outline -57.22,-94.712 -6.42,-94.712 -6.42,-69.312 -57.22,-69.312
RoomDefinition PAGE18_MRAM1 [InComponentClass('PAGE18_MRAM1')] p15: confinementstyle=ConfineIn formatcopy=TRUE lockcomponents=FALSE outline -57.22,-94.712 -6.42,-94.712 -6.42,-69.312 -57.22,-69.312
RoomDefinition PAGE17_MRAM0 [InComponentClass('PAGE17_MRAM0')] p16: confinementstyle=ConfineIn formatcopy=TRUE lockcomponents=FALSE outline -57.22,-94.712 -6.42,-94.712 -6.42,-69.312 -57.22,-69.312
RoomDefinition PAGE16_PWR_CAP [InComponentClass('PAGE16_PWR_CAP')] p17: confinementstyle=ConfineIn formatcopy=TRUE lockcomponents=FALSE outline -57.22,-94.712 -6.42,-94.712 -6.42,-69.312 -57.22,-69.312
RoomDefinition PAGE14_PWR_MGTAVCC [InComponentClass('PAGE14_PWR_MGTAVCC')] p18: confinementstyle=ConfineIn formatcopy=TRUE lockcomponents=FALSE outline -57.22,-94.712 -6.42,-94.712 -6.42,-69.312 -57.22,-69.312
RoomDefinition PAGE10_DO_NOT_CONNECT [InComponentClass('PAGE10_DO_NOT_CONNECT')] p19: confinementstyle=ConfineIn formatcopy=TRUE lockcomponents=FALSE outline -57.22,-94.712 -6.42,-94.712 -6.42,-69.312 -57.22,-69.312
RoomDefinition PAGE08_CLOCK_TX_RX [InComponentClass('PAGE08_CLOCK_TX_RX')] p20: confinementstyle=ConfineIn formatcopy=TRUE lockcomponents=FALSE outline -57.22,-94.712 -6.42,-94.712 -6.42,-69.312 -57.22,-69.312
RoomDefinition PAGE07_GPIO5 [InComponentClass('PAGE07_GPIO5')] p21: confinementstyle=ConfineIn formatcopy=TRUE lockcomponents=FALSE outline -57.22,-94.712 -6.42,-94.712 -6.42,-69.312 -57.22,-69.312
RoomDefinition PAGE06_GPIO4 [InComponentClass('PAGE06_GPIO4')] p22: confinementstyle=ConfineIn formatcopy=TRUE lockcomponents=FALSE outline 86.48,-45.43 143.872,-45.43 143.872,-40.68 86.48,-40.68
RoomDefinition PAGE05_GPIO3 [InComponentClass('PAGE05_GPIO3')] p23: confinementstyle=ConfineIn formatcopy=TRUE lockcomponents=FALSE outline -57.22,-94.712 -6.42,-94.712 -6.42,-69.312 -57.22,-69.312
RoomDefinition PAGE04_GPIO2 [InComponentClass('PAGE04_GPIO2')] p24: confinementstyle=ConfineIn formatcopy=TRUE lockcomponents=FALSE outline -57.22,-94.712 -6.42,-94.712 -6.42,-69.312 -57.22,-69.312
RoomDefinition PAGE03_GPIO1 [InComponentClass('PAGE03_GPIO1')] p25: confinementstyle=ConfineIn formatcopy=TRUE lockcomponents=FALSE outline -57.22,-94.712 -6.42,-94.712 -6.42,-69.312 -57.22,-69.312
RoomDefinition PAGE02_LED [InComponentClass('PAGE02_LED')] p26: confinementstyle=ConfineIn formatcopy=TRUE lockcomponents=FALSE outline 86.48,-51.45 97.199,-51.45 97.199,-46.7 86.48,-46.7
RoomDefinition PAGE01_JTAG_FLASH [InComponentClass('PAGE01_JTAG_FLASH')] p27: confinementstyle=ConfineIn formatcopy=TRUE lockcomponents=FALSE outline -57.22,-94.712 -6.42,-94.712 -6.42,-69.312 -57.22,-69.312
RoutingVias [All] p1: holewidth=0.203 width=0.406 viastyle="Through Hole" minholewidth=0.203 minwidth=0.406 maxholewidth=0.254 maxwidth=0.508
SolderMaskExpansion [All] p1: expansion=0.051 soldermaskfromhole=TRUE
UnRoutedNet [All] p1: checkbadconnections=TRUE
Width [All] p1: maxlimit=2.54 minlimit=0.102 preferedwidth=0.127
24 further rules are at their usual default settings.

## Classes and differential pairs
component class PAGE32_PWR_SUPPLY6: R533 R534 R535 R536 R537 R538 R539 R540 R541 R544 R545 R546 R547 R548 R549 R550 R602 R743
component class PAGE31_PWR_SUPPLY5: C542 C543 C544 C545 C546 C547 C548 D10 D11 D12 D13 D14 LED100 R526 R527 R528 R529 R530 R531 R532 R542 R543 R631 R632 R634 R636 R638 R639 R640 R641 R740 U95 U100
component class PAGE30_PWR_SUPPLY4: C532 C533 C534 C535 C536 C537 C538 C540 FB6 R518 R519 R520 R521 R522 R524 R633 R635 R637 R652 R653 R654 R655 R656 R750 RT15 RT16 RT801 TP15 TP16 TP17 TP18 TP701 TP702 TP703 TP802 TP803 U96
component class PAGE29_PWR_SUPPLY3: C522 C523 C524 C525 C526 C527 C528 C529 C530 C531 FB5 R510 R511 R512 R513 R514 R515 R516 R517 R612 R613 R614 R615 R616 R617 R618 R619 R724 RT5 RT6 RT7 RT8 TP3 TP4 TP5 TP6 TP7 TP8 TP9 TP10 TP705 TP706 TP707 TP708 TP709 U97
component class PAGE28_PWR_SUPPLY2: C512 C513 C514 C515 C516 C517 C518 C520 FB4 R502 R504 R506 R507 R508 R509 R604 R605 R606 R607 R608 R609 R610 R611 R710 RT9 RT10 TP11 TP12 TP13 TP14 TP711 TP713 TP714 U98
component class PAGE27_PWR_SUPPLY1: C500 C501 C502 C503 C504 C505 C506 C507 C508 C509 C510 C511 FB3 LVK12 R500 R501 R600 R601 R603 R650 RT TP1 TP2 TP716 TP717 TP718 TP720 U99
component class PAGE14_PWR_MGTAVCC: C325 L8
differential pair class clk: 9 10 11 13 14 15 16
differential pair class pcie: pcie pcie1 pcie2 pcie3 pcie4 pcie5 pcie6 pcie7 pcie8 pcie9 pcie10 pcie11 pcie12 pcie13 pcie14 pcie15 pcie16
component class PAGE10_DO_NOT_CONNECT: R132
component class PAGE26_CRYTAL: C203 C204 C205 C206 C207 C208 C209 C210 C211 C212 C219 C220 C259 C260 R65 R66 R67 R68 R69 R70 R71 R72 R73 R74 R136 R137 U18 X1
component class PAGE25_PCIE_CONN: C183 C184 C191 C192 C195 C196 C199 C200 C225 C226 C227 C228 C229 C230 C233 C234 C235 C317 C318 L7 PCIE_CONN R114 R115 R134 R135 R140 R240 R271 R272 R273 R274 R275 R276 R800 U22
component class PAGE24_MRAM7: C175 C176 C177 C178 C179 C180 R151 R159 U9
component class PAGE23_MRAM6: C169 C170 C171 C172 C173 C174 R150 R158 U8
component class PAGE22_MRAM5: C163 C164 C165 C166 C167 C168 R149 R157 U7
component class PAGE21_MRAM4: C157 C158 C159 C160 C161 C162 R148 R156 U6
component class PAGE20_MRAM3: C151 C152 C153 C154 C155 C156 R147 R155 U5
component class PAGE19_MRAM2: C145 C146 C147 C148 C149 C150 R146 R154 U4
component class PAGE18_MRAM1: C139 C140 C141 C142 C143 C144 R145 R153 U3
component class PAGE17_MRAM0: C213 C214 C215 C216 C217 C218 E#0 E#4 G0_A0 G0_A0_0 G0_A1 G0_A1_0 G0_CR# G0_G# G0_W# G0_W#_0 G1_A0 G1_A1 G1_CR# G1_G# G1_W# MEM0_0 MEM0_RST MEM1_0 MEM2_0 MEM3_0 MEM4_0 MEM5_0 MEM6_0 MEM7_0 R144 R152 U2
component class PAGE16_PWR_CAP: C115 C116 C117 C118 C119 C120 C121 C122 C123 C124 C125 C126 C129 C130 C131 C132 C133 C134 C135 C136 C137 C138 C236 C237 C238 C800 C801 CS1 CS2 CS3 CS4 CS5 CS6 CS7 CS8 CS9 CS12 CS13 CS14 CS15 CS16 CS17 CS18 CS23 CS24 CS25 CS26 CS27 CS33 CS34 CS35 CS36 CS37 CS38 CS41 CS42 CS43 CS45 CS46 CS47 CS48 CS49 CS50 CS53 CS54 CS55 CS56 CS57 CS58 CS59 CS60 CS61 CS62 CS63 CS67 CS68 CS71 CS72 CS73 CS74 CS75 CS76 CS77 CS78 CS79 CS80 CS83 CS84 CS85 CS86 CS87 CS88 CS91 CS92 CS93 CS94 CS95 CS96 CS97 CS98 CS99 CS100 CS101 CS102 CS104 CS106 CS107 CS108 CS109 CX1 CX2 CX3 CX4 CX6 CX7 CX8 CX9 CX10 CX12 CX13 CX14 CX15 CX16 CX17 CX18 CX19
component class PAGE08_CLOCK_TX_RX: C111 C112 C113 C114
component class PAGE07_GPIO5: C107 C108 C109 C110 R95 R96 R97 R98 R130 R131 R133
component class PAGE06_GPIO4: C103 C104 C105 C106 C324 R75 R76 R77 R78 R79 R80 R81 R82 R83 R84 R85 R86 R87 R88 R89 R90 R128 R129 R138 R139 R700 R701 R702 R703 R704 R705 R706 R707 U19
component class PAGE05_GPIO3: C99 C100 C101 C102 R126 R127
component class PAGE04_GPIO2: C95 C96 C97 C98 C231 C232 R21 R124 R125
component class PAGE03_GPIO1: C93 C94 R91 R92 R93 R94 R123
component class PAGE02_LED: D2 D4 D5 D6 D7 D8 R107 R109 R110 R111 R112 R113
component class PAGE01_JTAG_FLASH: C91 C92 C321 C322 C323 D1 D9 FB1 FB2 FUDICIAL1 FUDICIAL2 FUDICIAL3 FUDICIAL4 FUDICIAL5 FUDICIAL6 J4 J5 K1 MTH1 MTH2 MTH3 MTH4 R1 R2 R3 R4 R5 R6 R7 R11 R22 R25 R116 R117 R118 R119 R120 R121 R122 R141 R142 R143 R234 R235 U1 U10 U21
differential pair pcie16: +PCIE_TX3_P_C -PCIE_TX3_N_C
differential pair pcie15: +PCIE_TX2_P_C -PCIE_TX2_N_C
differential pair pcie14: +PCIE_TX1_P_C -PCIE_TX1_N_C
differential pair pcie13: +PCIE_TX0_P_C -PCIE_TX0_N_C
differential pair pcie12: +PCIE_RX3_P_C -PCIE_RX3_N_C
differential pair pcie11: +PCIE_RX3_P -PCIE_RX3_N
differential pair pcie10: +PCIE_RX2_P_C -PCIE_RX2_N_C
differential pair pcie9: +PCIE_RX2_P -PCIE_RX2_N
differential pair pcie8: +PCIE_RX1_P_C -PCIE_RX1_N_C
differential pair pcie7: +PCIE_CLK_P_I -PCIE_CLK_N_I
differential pair pcie6: +PCIE_CLK_P1_1 -PCIE_CLK_N1_1
differential pair pcie5: +PCIE_RX1_P -PCIE_RX1_N
differential pair pcie4: +PCIE_RX0_P -PCIE_RX0_N
differential pair pcie3: +PCIE_CLK_P1 -PCIE_CLK_N1
differential pair pcie2: +PCIE_RX0_P_C -PCIE_RX0_N_C
differential pair pcie1: +PCIE_CLK_P -PCIE_CLK_N
differential pair pcie: +PCIE_CLK_P_C -PCIE_CLK_N_C

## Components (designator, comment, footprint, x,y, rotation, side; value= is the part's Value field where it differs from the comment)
C91 "47uF/10V" CN_0805 33.875,-48.321 r90 top
C92 "10uF/10V" CN_0402 13.75,-51.051 r90 top
C93 "47uF/10V" CN_0805 36,-48.321 r90 top
C94 "10uF/10V" CN_0402 42,-49.571 r90 bottom
C95 "47uF/10V" CN_0805 40.25,-1.464 r180 top
C96 "10uF/10V" CN_0402 37.338,-1.473 r270 top
C97 "47uF/10V" CN_0805 36,-48.321 r90 bottom
C98 "10uF/10V" CN_0402 41,-49.571 r90 bottom
C99 "47uF/10V" CN_0805 40.25,-1.464 r180 bottom
C100 "10uF/10V" CN_0402 37.338,-1.473 r270 bottom
C101 "47uF/10V" CN_0805 70.25,-32.571 r90 top
C102 "10uF/10V" CN_0402 72,-32.571 r90 top
C103 "47uF/10V" CN_0805 70.25,-32.571 r90 bottom
C104 "10uF/10V" CN_0402 72,-32.571 r90 bottom
C105 "47uF/10V" CN_0805 70.25,-41.821 r90 top
C106 "10uF/10V" CN_0402 72,-41.821 r90 top
C107 "47uF/10V" CN_0805 70.25,-41.821 r90 bottom
C108 "10uF/10V" CN_0402 72,-41.821 r90 bottom
C109 "47uF/10V" CN_0805 33.875,-48.321 r90 bottom
C110 "10uF/10V" CN_0402 13.75,-51.051 r90 bottom
C111 "47uF/10V" CN_0805 44.5,-4.071 r180 bottom
C112 "10uF/10V" CN_0402 2.768,-21.706 r270 bottom
C113 "47uF/10V" CN_0805 21.25,-50.321 r180 bottom
C114 "10uF/10V" CN_0402 4.268,-21.706 r270 bottom
C115 "220uF" CN_1206 76.75,-25.821 r90 bottom
C116 "100uF" CN_1206 47,-49.446 r180 bottom
C117 "47uF/10V" CN_0805 66.75,-19.196 r180 bottom
C118 "10uF/10V" CN_0402 66.5,-21.571 r180 bottom
C119 "100uF" CN_1206 47,-49.446 r0 top
C120 "100uF" CN_1206 62,-4.071 r180 bottom
C121 "47uF/10V" CN_0805 66.5,-11.071 r90 bottom
C122 "0.01uF" CN_0402 49,-8.071 r270 bottom
C123 "330uF" CN_1210 38.75,-48.746 r270 top
C124 "100uF" CN_1206 23.016,-3.943 r0 bottom
C125 "47uF/10V" CN_0805 38.5,-4.071 r0 bottom
C126 "0.01uF" CN_0402 34,-6.071 r270 bottom
C129 "47uF/10V" CN_0805 28.516,-3.943 r180 bottom
C130 "10uF/10V" CN_0402 32,-6.071 r270 bottom
C131 "47uF/10V" CN_0805 60.5,-50.321 r0 bottom
C132 "10uF/10V" CN_0402 66.5,-32.571 r180 bottom
C133 "47uF/10V" CN_0805 16,-48.071 r90 bottom
C134 "10uF/10V" CN_0402 66.5,-48.571 r180 bottom
C135 "47uF/10V" CN_0805 21.5,-18.071 r0 bottom
C136 "10uF/10V" CN_0402 31,-6.071 r270 bottom
C137 "47uF/10V" CN_0805 21.5,-34.946 r0 bottom
C138 "10uF/10V" CN_0402 21.602,-36.723 r0 bottom
C139 "10uF/10V" CN_0402 17.5,-23.571 r0 bottom
C140 "0.1uF" CN_0402 22,-14.071 r270 bottom
C141 "0.01uF" CN_0402 54,-49.071 r90 bottom
C142 "10uF/10V" CN_0402 21.5,-25.571 r0 bottom
C143 "0.1uF" CN_0402 20.5,-24.571 r180 bottom
C144 "0.01uF" CN_0402 27.28,-50.216 r90 bottom
C145 "10uF/10V" CN_0402 23,-46.071 r270 bottom
C146 "0.1uF" CN_0402 44,-8.071 r90 bottom
C147 "0.01uF" CN_0402 53.5,-5.571 r0 bottom
C148 "10uF/10V" CN_0402 66.5,-16.571 r180 bottom
C149 "0.1uF" CN_0402 20.5,-13.571 r180 bottom
C150 "0.01uF" CN_0402 56.5,-8.571 r180 bottom
C151 "10uF/10V" CN_0402 65,-37.071 r270 bottom
C152 "0.1uF" CN_0402 62,-24.071 r90 bottom
C153 "0.01uF" CN_0402 29.5,-46.571 r180 bottom
C154 "10uF/10V" CN_0402 66.5,-15.571 r180 bottom
C155 "0.1uF" CN_0402 67,-6.071 r270 bottom
C156 "0.01uF" CN_0402 22.5,-15.571 r0 bottom
C157 "10uF/10V" CN_0402 18,-17.071 r90 bottom
C158 "0.1uF" CN_0402 62,-8.071 r90 bottom
C159 "0.01uF" CN_0402 65.5,-46.571 r180 bottom
C160 "10uF/10V" CN_0402 66.5,-37.571 r180 bottom
C161 "0.1uF" CN_0402 49,-6.071 r270 bottom
C162 "0.01uF" CN_0402 61,-28.071 r90 bottom
C163 "10uF/10V" CN_0402 35.5,-7.571 r0 bottom
C164 "0.1uF" CN_0402 26,-8.071 r90 bottom
C165 "0.01uF" CN_0402 65.5,-7.571 r180 bottom
C166 "10uF/10V" CN_0402 23.5,-22.571 r180 bottom
C167 "0.1uF" CN_0402 53.5,-4.571 r0 bottom
C168 "0.01uF" CN_0402 61,-44.071 r90 bottom
C169 "10uF/10V" CN_0402 29.5,-7.571 r180 bottom
C170 "0.1uF" CN_0402 18,-46.071 r270 bottom
C171 "0.01uF" CN_0402 18,-49.071 r90 bottom
C172 "10uF/10V" CN_0402 26.162,-50.241 r90 bottom
C173 "0.1uF" CN_0402 23,-48.071 r90 bottom
C174 "0.01uF" CN_0402 38.5,-8.571 r180 bottom
C175 "10uF/10V" CN_0402 65,-17.071 r90 bottom
C176 "0.1uF" CN_0402 62,-46.071 r270 bottom
C177 "0.01uF" CN_0402 18.11,-5.029 r180 bottom
C178 "10uF/10V" CN_0402 18.5,-43.571 r0 bottom
C179 "0.1uF" CN_0402 66.5,-31.571 r180 bottom
C180 "0.01uF" CN_0402 20.5,-45.571 r180 bottom
C183 "0.22uF" CN_0201 0.973,-25.712 r0 bottom
C184 "0.22uF" CN_0201 0.973,-24.95 r0 bottom
C191 "0.22uF" CN_0201 0.987,-13.081 r0 bottom
C192 "0.22uF" CN_0201 0.987,-12.319 r0 bottom
C195 "0.22uF" CN_0201 0.971,-8.106 r0 bottom
C196 "0.22uF" CN_0201 0.971,-7.344 r0 bottom
C199 "0.22uF" CN_0201 0.973,-3.614 r0 bottom
C200 "0.22uF" CN_0201 0.973,-2.852 r0 bottom
C203 "0.1uF" CN_0402 -0.225,-46.047 r180 bottom
C204 "0.1uF" CN_0402 -0.225,-45.047 r180 bottom
C205 "0.1uF" CN_0402 4.475,-47.301 r0 bottom
C206 "0.1uF" CN_0402 2.125,-43.801 r90 bottom
C207 "0.1uF" CN_0402 -0.225,-47.047 r180 bottom
C208 "0.1uF" CN_0402 4.475,-45.301 r0 bottom
C209 "0.1uF" CN_0402 -2.125,-46.551 r0 top
C210 "0.1uF" CN_0402 -2.125,-45.551 r0 top
C211 "0.1uF" CN_0402 2.625,-42.051 r270 top
C212 "0.1uF" CN_0402 3.625,-42.051 r270 top
C213 "10uF/10V" CN_0402 19,-48.071 r90 bottom
C214 "0.1uF" CN_0402 22,-46.071 r270 bottom
C215 "0.01uF" CN_0402 29,-49.071 r90 bottom
C216 "10uF/10V" CN_0402 66.5,-47.571 r180 bottom
C217 "0.1uF" CN_0402 66.5,-38.571 r180 bottom
C218 "0.01uF" CN_0402 61,-42.071 r270 bottom
C219 "18pF" CN_0402 -2.87,-49.657 r0 bottom
C220 "18pF" CN_0402 -2.845,-50.8 r0 bottom
C225 "0.22uF" CN_0402 11.25,-43.176 r270 top
C226 "0.22uF" CN_0402 10.25,-43.176 r270 top
C227 "0.22uF" CN_0402 13.25,-43.176 r270 top
C228 "0.22uF" CN_0402 12.25,-43.176 r270 top
C229 "0.22uF" CN_0201 0.973,-30.792 r0 bottom
C230 "0.22uF" CN_0201 0.973,-30.03 r0 bottom
C231 "0.1uF" CN_0402 10.25,-41.176 r90 top
C232 "0.1uF" CN_0402 11.25,-41.176 r90 top
C233 "1uF" CN_0402 10,-49.901 r90 bottom
C234 "0.1uF" CN_0402 13.6,-46.301 r180 bottom
C235 "0.1uF" CN_0402 12.5,-49.901 r90 bottom
C236 "100uF" CN_1206 38.75,-48.746 r270 bottom
C237 "100uF" CN_1206 45.5,-1.464 r0 bottom
C238 "100uF" CN_1206 45.5,-1.464 r0 top
C259 "0.22uF" CN_0402 0.625,-42.051 r270 top
C260 "0.22uF" CN_0402 1.625,-42.051 r270 top
C317 "47uF/10V" CN_1210 -0.076,1.397 r180 top
C318 "47uF/10V" CN_1210 -4.699,1.372 r0 top
C321 "0.1uF" CN_0402 74.873,-24.194 r270 bottom
C322 "0.1uF" CN_0402 1.768,-16.956 r270 bottom
C323 "0.1uF" CN_0402 3.393,-16.456 r0 bottom
C324 "47uF/10V" CN_0805 74.555,-38.121 r270 bottom
C325 "47uF/10V" CN_0805 19.787,-28.397 r0 bottom
C500 "100uF,16V" CN_1210 9.779,-7.493 r90 bottom
C501 "100uF,16V" CN_1210 3.937,-7.493 r90 bottom
C502 "100uF,16V" CN_1210 6.858,-7.493 r90 bottom
C503 "100uF,16V" CN_1210 12.7,-7.493 r90 bottom
C504 "100uF,16V" CN_1210 15.621,-7.493 r90 bottom
C505 "100uF,16V" CN_1210 22.631,-1.143 r180 bottom
C506 "100uF,16V" CN_1210 22.631,1.778 r180 bottom
C507 "100uF,16V" CN_1210 22.631,-1.168 r180 top
C508 "22uF,25V" CN_1210 21.692,9.119 r90 bottom
C509 "22uF,25V" CN_1210 21.692,9.119 r90 top
C510 "8nf" CN_0402 13.538,0.203 r90 top
C511 "4.7uF" CN_0402 14.808,6.782 r270 top
C512 "47uF,25V" CN_1210 42.367,8.814 r90 top
C513 "47uF,25V" CN_1210 38.227,11.049 r0 top
C514 "47uF,25V" CN_1210 33.401,11.049 r180 top
C515 "47uF,25V" CN_1210 33.401,11.049 r180 bottom
C516 "22uF,25V" CN_1210 22.607,4.699 r0 top
C517 "22uF,25V" CN_1210 22.606,4.699 r0 bottom
C518 "14nF" CN_0402 38.278,2.489 r0 bottom
C520 "14nF" CN_0402 32.258,-1.397 r90 bottom
C522 "47uF,25V" CN_1210 83.312,-5.969 r270 top
C523 "47uF,25V" CN_1210 79.71,-5.969 r270 top
C524 "47uF,25V" CN_1210 76.073,-5.969 r270 top
C525 "47uF,25V" CN_1210 72.39,-5.969 r270 top
C526 "22uF,25V" CN_1210 69.215,-9.399 r270 bottom
C527 "22uF,25V" CN_1210 71.755,-19.685 r180 bottom
C528 "14nf" CN_0402 83.566,-16.129 r45 bottom
C529 "14nf" CN_0402 79.756,-16.129 r45 bottom
C530 "14nf" CN_0402 76.257,-16.186 r135 bottom
C531 "14nf" CN_0402 73.508,-16.713 r135 bottom
C532 "47uF,25V" CN_1210 65.913,6.858 r90 top
C533 "47uF,25V" CN_1210 60.452,11.049 r0 top
C534 "47uF,25V" CN_1210 55.753,11.049 r180 top
C535 "47uF,25V" CN_1210 55.752,11.049 r180 bottom
C536 "22uF,25V" CN_1210 46.228,5.588 r0 top
C537 "22uF,25V" CN_1210 47.5,5.613 r0 bottom
C538 "14nf" CN_0402 60.452,-0.635 r180 top
C540 "14nf" CN_0402 56.261,-0.635 r180 top
C542 "8nF" CN_0402 76.967,1.135 r180 bottom
C543 "5.6nF" CN_0402 75.159,0.559 r0 top
C544 "3.9nF" CN_0402 75.173,-0.457 r0 top
C545 "1.8nF" CN_0402 75.173,-1.473 r0 top
C546 "0.1uF" CN_0402 82.804,0.889 r180 top
C547 "10uF/16V" CN_0805 73.152,3.861 r270 bottom
C548 "10uF/16V" CN_0805 69.469,0.381 r0 top
C800 "47uF/10V" CN_0805 15.342,-24.765 r90 bottom
C801 "10uF/10V" CN_0402 19.736,-20.344 r270 bottom
CS1 "0.1uF" CN_0201 59,-47.821 r90 bottom
CS2 "0.1uF" CN_0201 63,-46.821 r90 bottom
CS3 "0.1uF" CN_0201 61.75,-38.571 r0 bottom
CS4 "0.1uF" CN_0201 63.75,-26.571 r0 bottom
CS5 "0.1uF" CN_0201 62,-15.821 r90 bottom
CS6 "0.1uF" CN_0201 63.25,-7.571 r180 bottom
CS7 "0.1uF" CN_0201 59.25,-6.571 r180 bottom
CS8 "0.1uF" CN_0201 41,-6.321 r270 bottom
CS9 "0.1uF" CN_0201 23,-6.321 r270 bottom
CS12 "0.1uF" CN_0201 56,-45.821 r90 bottom
CS13 "0.1uF" CN_0201 63.25,-39.571 r180 bottom
CS14 "0.1uF" CN_0201 63.25,-30.571 r180 bottom
CS15 "0.1uF" CN_0201 63,-23.821 r90 bottom
CS16 "0.1uF" CN_0201 63.25,-14.571 r180 bottom
CS17 "0.1uF" CN_0201 62,-6.321 r270 bottom
CS18 "0.1uF" CN_0201 26,-6.321 r270 bottom
CS23 "0.1uF" CN_0201 62,-47.821 r90 bottom
CS24 "0.1uF" CN_0201 63.75,-42.571 r0 bottom
CS25 "0.1uF" CN_0201 62.25,-31.571 r180 bottom
CS26 "0.1uF" CN_0201 63.75,-11.571 r0 bottom
CS27 "0.1uF" CN_0201 44,-6.321 r270 bottom
CS33 "0.1uF" CN_0201 63.75,-43.571 r0 bottom
CS34 "0.1uF" CN_0201 63.75,-27.571 r0 bottom
CS35 "0.1uF" CN_0201 62,-22.321 r270 bottom
CS36 "0.1uF" CN_0201 63.75,-10.571 r0 bottom
CS37 "0.1uF" CN_0201 45,-7.321 r270 bottom
CS38 "0.1uF" CN_0201 27.25,-7.571 r180 bottom
CS41 "0.1uF" CN_0201 23,-7.821 r90 bottom
CS42 "0.1uF" CN_0201 22,-7.821 r90 bottom
CS43 "0.1uF" CN_0201 24,-46.821 r90 bottom
CS45 "0.1uF" CN_0201 59,-46.321 r270 bottom
CS46 "0.1uF" CN_0201 64,-38.321 r270 bottom
CS47 "0.1uF" CN_0201 65,-39.821 r90 bottom
CS48 "0.1uF" CN_0201 60.25,-23.571 r180 bottom
CS49 "0.1uF" CN_0201 59,-7.821 r90 bottom
CS50 "0.1uF" CN_0201 47.25,-5.571 r180 bottom
CS53 "0.1uF" CN_0201 64.75,-32.571 r0 bottom
CS54 "0.1uF" CN_0201 65,-21.821 r90 bottom
CS55 "0.1uF" CN_0201 28.25,-6.571 r180 bottom
CS56 "0.1uF" CN_0201 54,-7.821 r90 bottom
CS57 "0.1uF" CN_0201 47.25,-7.571 r180 bottom
CS58 "0.1uF" CN_0201 18.034,-8.249 r90 bottom
CS59 "0.1uF" CN_0201 55,-6.821 r90 bottom
CS60 "0.1uF" CN_0201 24,-7.821 r90 bottom
CS61 "0.1uF" CN_0201 60.25,-30.571 r180 bottom
CS62 "0.1uF" CN_0201 65.25,-5.571 r180 bottom
CS63 "0.1uF" CN_0201 64.25,-6.571 r180 bottom
CS67 "0.1uF" CN_0201 62,-30.321 r270 bottom
CS68 "0.1uF" CN_0201 58,-7.821 r90 bottom
CS71 "0.1uF" CN_0201 54.25,-46.571 r180 bottom
CS72 "0.1uF" CN_0201 65.25,-30.571 r180 bottom
CS73 "0.1uF" CN_0201 60.25,-14.571 r180 bottom
CS74 "0.1uF" CN_0201 36,-5.821 r90 bottom
CS75 "0.1uF" CN_0201 19,-6.821 r90 bottom
CS76 "0.1uF" CN_0201 60.25,-39.571 r180 bottom
CS77 "0.1uF" CN_0201 65,-23.821 r90 bottom
CS78 "0.1uF" CN_0201 65.25,-14.571 r180 bottom
CS79 "0.1uF" CN_0201 37,-6.821 r90 bottom
CS80 "0.1uF" CN_0201 40,-7.821 r90 bottom
CS83 "0.1uF" CN_0201 55.25,-47.571 r180 bottom
CS84 "0.1uF" CN_0201 58,-46.821 r90 bottom
CS85 "0.1uF" CN_0201 62,-39.821 r90 bottom
CS86 "0.1uF" CN_0201 64,-22.321 r270 bottom
CS87 "0.1uF" CN_0201 60,-7.821 r90 bottom
CS88 "0.1uF" CN_0201 46,-6.321 r270 bottom
CS91 "0.1uF" CN_0201 64.25,-31.571 r180 bottom
CS92 "0.1uF" CN_0201 62,-14.321 r270 bottom
CS93 "0.1uF" CN_0201 64,-15.821 r90 bottom
CS94 "0.1uF" CN_0201 41,-7.821 r90 bottom
CS95 "0.1uF" CN_0201 42,-7.821 r90 bottom
CS96 "0.1uF" CN_0201 28,-47.821 r90 bottom
CS97 "0.1uF" CN_0201 26,-46.321 r270 bottom
CS98 "0.1uF" CN_0201 60,-46.821 r90 bottom
CS99 "0.1uF" CN_0201 65,-48.821 r90 bottom
CS100 "0.1uF" CN_0201 64,-47.821 r90 bottom
CS101 "0.1uF" CN_0201 18.25,-14.571 r180 bottom
CS102 "0.1uF" CN_0201 19.25,-15.571 r180 bottom
CS104 "0.1uF" CN_0201 23,-23.821 r90 bottom
CS106 "0.1uF" CN_0201 23,-14.321 r270 bottom
CS107 "0.1uF" CN_0201 24,-14.321 r270 bottom
CS108 "0.1uF" CN_0201 22,-23.821 r90 bottom
CS109 "0.1uF" CN_0201 24,-23.821 r90 bottom
CX1 "0.1uF" CN_0201 32.5,-38.321 r90 top
CX2 "0.1uF" CN_0201 33.5,-35.321 r90 top
CX3 "0.1uF" CN_0201 43.5,-35.321 r90 top
CX4 "0.1uF" CN_0201 36.5,-36.321 r90 top
CX6 "0.1uF" CN_0201 42.5,-38.321 r90 top
CX7 "0.1uF" CN_0201 46.5,-36.321 r90 top
CX8 "0.1uF" CN_0201 45.5,-39.321 r90 top
CX9 "0.1uF" CN_0201 49.5,-37.321 r90 top
CX10 "0.1uF" CN_0201 48.5,-40.321 r90 top
CX12 "0.1uF" CN_0201 34.5,-42.321 r90 top
CX13 "0.1uF" CN_0201 37.5,-43.321 r90 top
CX14 "0.1uF" CN_0201 38.5,-40.321 r90 top
CX15 "0.1uF" CN_0201 41.5,-41.321 r90 top
CX16 "0.1uF" CN_0201 40.5,-44.321 r90 top
CX17 "0.1uF" CN_0201 44.5,-42.321 r90 top
CX18 "0.1uF" CN_0201 47.5,-43.321 r90 top
CX19 "0.1uF" CN_0201 50.25,-44.071 r0 top
D1 "BAS40LS-QYL" "BAS40 - SOD523" 18.5,-19.696 r270 bottom
D2 "LED" LED_0603 82.25,-27.571 r180 top
D4 "LED" LED_0603 1.397,4.687 r270 top
D5 "LED" LED_0603 82.25,-23.761 r180 top
D6 "LED" LED_0603 9.349,-15.493 r90 top
D7 "LED" LED_0603 7.754,-15.493 r90 top
D8 "LED" LED_0603 11.004,-15.493 r90 top
D9 "LED" LED_0603 0.138,-17.316 r270 top
D10 "BZT52C5V1" "BAS40 - SOD523" 72.861,-2.032 r180 top
D11 "BZT52C5V1" "BAS40 - SOD523" 75.489,-1.626 r270 bottom
D12 "BZT52C5V1" "BAS40 - SOD523" 78.613,-0.545 r270 bottom
D13 "BZT52C5V1" "BAS40 - SOD523" 79.756,-0.598 r270 bottom
D14 "BZT52C5V1" "BAS40 - SOD523" 80.899,-0.635 r270 bottom
E#0 "TP_DNI" MINI_TESTPOINT 65.25,-2.321 r90 top
E#4 "TP_DNI" MINI_TESTPOINT 47.75,-51.496 r90 top
FB1 "L0805" L0805 -7.5,-45.071 r270 bottom
FB2 "L0805" L0805 -4.089,8.865 r90 bottom
FB3 "L0805" L0805 11.875,-2.972 r90 top
FB4 "L0805" L0805 35.077,-3.023 r90 bottom
FB5 "L0805" L0805 80.34,-19.279 r270 bottom
FB6 "L0805" L0805 51.206,-0.787 r0 bottom
FUDICIAL1 "FUDICIAL" FUDICIAL 79.121,-49.403 r180 bottom
FUDICIAL2 "FUDICIAL" FUDICIAL 79.629,11.43 r180 bottom
FUDICIAL3 "FUDICIAL" FUDICIAL -5.004,-51.638 r180 bottom
FUDICIAL4 "FUDICIAL" FUDICIAL 79.629,11.43 r180 top
FUDICIAL5 "FUDICIAL" FUDICIAL 79.121,-49.403 r180 top
FUDICIAL6 "FUDICIAL" FUDICIAL -5.004,-51.638 r180 top
G0_A0 "TP_DNI" MINI_TESTPOINT 62.75,-2.321 r90 top
G0_A0_0 "TP_DNI" MINI_TESTPOINT 68.961,-12.573 r90 top
G0_A1 "TP_DNI" MINI_TESTPOINT 61.5,-2.321 r90 top
G0_A1_0 "TP_DNI" MINI_TESTPOINT 68.961,-13.843 r90 top
G0_CR# "TP_DNI" MINI_TESTPOINT 64,-2.321 r90 top
G0_G# "TP_DNI" MINI_TESTPOINT 59,-2.321 r90 top
G0_W# "TP_DNI" MINI_TESTPOINT 60.25,-2.321 r90 top
G0_W#_0 "TP_DNI" MINI_TESTPOINT 68.961,-15.113 r90 top
G1_A0 "TP_DNI" MINI_TESTPOINT 51.5,-2.321 r90 top
G1_A1 "TP_DNI" MINI_TESTPOINT 50.25,-2.321 r90 top
G1_CR# "TP_DNI" MINI_TESTPOINT 49,-2.321 r90 top
G1_G# "TP_DNI" MINI_TESTPOINT 46.5,-51.496 r90 top
G1_W# "TP_DNI" MINI_TESTPOINT 52.75,-2.321 r90 top
J4 "10PIN-CON" 68611014422 79.496,-37.063 r270 bottom
J5 "10PIN-CON" 68611014422 79.496,-37.063 r90 top
K1 "SW-SMD_4P_6X6" SW_PTS815_4P2X3P2X2P5 72.263,-46.482 r0 top
L7 "PN: 74269262601" 74269262601 7.25,-50.067 r0 bottom
L8 "PN: 74269262601" 74269262601 22.123,-20.208 r180 bottom
LED100 "GREEN" LED_0603 70.116,11.43 r0 top
LVK12 "0.012OHM" LVK12 0.266,9.398 r270 top
MEM0_0 "TP_DNI" MINI_TESTPOINT 55.25,-2.321 r90 top
MEM0_RST "TP_DNI" MINI_TESTPOINT 49,-51.496 r90 top
MEM1_0 "TP_DNI" MINI_TESTPOINT 57.75,-2.321 r90 top
MEM2_0 "TP_DNI" MINI_TESTPOINT 54,-2.321 r90 top
MEM3_0 "TP_DNI" MINI_TESTPOINT 56.5,-2.321 r90 top
MEM4_0 "TP_DNI" MINI_TESTPOINT 45.25,-51.496 r90 top
MEM5_0 "TP_DNI" MINI_TESTPOINT 44,-51.496 r90 top
MEM6_0 "TP_DNI" MINI_TESTPOINT 41.5,-51.496 r90 top
MEM7_0 "TP_DNI" MINI_TESTPOINT 42.75,-51.496 r90 top
MTH1 "MTH" MH_2P3_4MM -7.878,-49.891 r0 top
MTH2 "MTH" MH_2P3_4MM -7.878,10.009 r0 top
MTH3 "MTH" "MH_2p3_NPTH _keepout" 82.522,10.009 r0 top
MTH4 "MTH" "MH_2p3_NPTH _keepout" 82.522,-49.891 r0 top
PCIE_CONN "PSAS4M2130181TR" AMPHENOL_PSAS4M2130021TR -2.832,-15.264 r90 bottom
R1 "1K" RN_0402 16.5,-18.696 r180 bottom
R2 "1K" RN_0402 16.5,-14.571 r180 bottom
R3 "4.7K" RN_0402 22.5,-26.571 r180 bottom
R4 "4.7K" RN_0402 69.123,-45.983 r270 bottom
R5 "2.4K" RN_0402 70.119,-22.733 r90 bottom
R6 "4.7K" RN_0402 73.619,-28.733 r270 bottom
R7 "4.7K" RN_0402 72.619,-28.733 r270 bottom
R11 "0E" RN_0402 72.619,-22.733 r270 bottom
R21 "100E" RN_0402 10.75,-39.676 r180 top
R22 "1K" RN_0402 16.5,-15.571 r180 bottom
R25 "0E" RN_0402 16.5,-19.696 r180 bottom
R65 "4.7K" RN_0402 2.375,-50.051 r270 top
R66 "0E" RN_0402 -0.875,-43.551 r0 top
R67 "0E" RN_0402 4.475,-44.301 r180 bottom
R68 "0E" RN_0402 -0.875,-42.551 r180 top
R69 "0E" RN_0402 4.475,-43.301 r0 bottom
R70 "4.7K" RN_0402 3.375,-50.051 r270 top
R71 "1K" RN_0402 -2.609,-46.965 r90 bottom
R72 "1K" RN_0402 -2.609,-45.137 r270 bottom
R73 "1K" RN_0402 -3.609,-46.965 r270 bottom
R74 "1K" RN_0402 -3.609,-45.137 r90 bottom
R75 "4.7K" RN_0402 61.5,-18.071 r180 bottom
R76 "4.7K" RN_0402 61.5,-19.071 r180 bottom
R77 "4.7K" RN_0402 66.5,-27.571 r180 bottom
R78 "4.7K" RN_0402 61.5,-20.071 r180 bottom
R79 "4.7K" RN_0402 66.5,-23.571 r180 bottom
R80 "4.7K" RN_0402 66.5,-22.571 r180 bottom
R81 "4.7K" RN_0402 66.5,-26.571 r180 bottom
R82 "4.7K" RN_0402 24,-50.321 r90 bottom
R83 "4.7K" RN_0402 48,-47.071 r90 bottom
R84 "4.7K" RN_0402 50,-47.071 r90 bottom
R85 "4.7K" RN_0402 52,-47.071 r90 bottom
R86 "4.7K" RN_0402 53,-47.071 r90 bottom
R87 "4.7K" RN_0402 47,-47.071 r90 bottom
R88 "4.7K" RN_0402 46,-47.071 r90 bottom
R89 "4.7K" RN_0402 49,-47.071 r90 bottom
R90 "4.7K" RN_0402 51,-47.071 r90 bottom
R91 "4.7K" RN_0402 16.5,-11.571 r0 bottom
R92 "4.7K" RN_0402 53.5,-3.571 r0 bottom
R93 "4.7K" RN_0402 35,-6.071 r270 bottom
R94 "4.7K" RN_0402 16.5,-10.571 r0 bottom
R95 "4.7K" RN_0402 66.5,-42.571 r180 bottom
R96 "4.7K" RN_0402 41.5,-4.071 r90 bottom
R97 "4.7K" RN_0402 33,-6.071 r270 bottom
R98 "4.7K" RN_0402 66.5,-39.571 r180 bottom
R107 "1.5K" RN_0402 79.481,-27.571 r180 top
R109 "10.2K" RN_0402 0,4.115 r90 top
R110 "150E" RN_0402 79.502,-23.774 r180 top
R111 "1.5K" RN_0402 9.349,-12.953 r90 top
R112 "1.5K" RN_0402 7.754,-12.953 r90 top
R113 "1.5K" RN_0402 11.004,-12.953 r90 top
R114 "0E" RN_0402 11.25,-51.551 r0 bottom
R115 "0E" RN_0402 7.5,-44.285 r0 top
R116 "4.7K" RN_0402 7.074,-20.406 r0 top
R117 "4.7K" RN_0402 7.074,-21.295 r0 top
R118 "4.7K" RN_0402 7.074,-22.184 r0 top
R119 "4.7K" RN_0402 -0.038,-22.184 r180 top
R120 "4.7K" RN_0402 -0.038,-21.295 r180 top
R121 "4.7K" RN_0402 -0.038,-20.406 r180 top
R122 "0E" RN_0402 3.391,-17.485 r180 top
R123 "1K" RN_0402 42,-47.071 r270 bottom
R124 "1K" RN_0402 43,-47.071 r270 bottom
R125 "1K" RN_0402 66.5,-25.571 r0 bottom
R126 "1K" RN_0402 66.5,-28.571 r0 bottom
R127 "1K" RN_0402 63.5,-18.071 r0 bottom
R128 "1K" RN_0402 63.5,-19.071 r0 bottom
R129 "1K" RN_0402 16.5,-16.571 r180 bottom
R130 "1K" RN_0402 45,-47.071 r270 bottom
R131 "1K" RN_0402 50.5,-8.071 r90 bottom
R132 "100E" RN_0402 29.5,-8.571 r0 bottom
R133 "10K" RN_0402 44,-47.071 r270 bottom
R134 "4.7K" RN_0402 7.5,-46.301 r0 bottom
R135 "4.7K" RN_0402 7.5,-45.301 r0 bottom
R136 "100E" RN_0402 1.125,-40.551 r0 top
R137 "100E" RN_0402 -3.625,-46.051 r90 top
R138 "150E" RN_0402 72.344,-36.659 r0 bottom
R139 "4.7K" RN_0402 72.344,-38.559 r0 bottom
R140 "1K" RN_0402 -1.322,-4.376 r0 top
R141 "4.7K" RN_0402 6.312,-18.142 r90 bottom
R142 "2.4K" RN_0402 -0.038,-19.39 r0 top
R143 "1K" RN_0402 16.5,-13.571 r180 bottom
R144 "0E" RN_0402 22,-12.071 r90 bottom
R145 "0E" RN_0402 55.5,-3.571 r180 bottom
R146 "0E" RN_0402 33.5,-8.571 r0 bottom
R147 "0E" RN_0402 66.5,-29.571 r180 bottom
R148 "0E" RN_0402 30,-6.071 r270 bottom
R149 "0E" RN_0402 31,-8.071 r270 bottom
R150 "0E" RN_0402 22.375,-43.571 r180 bottom
R151 "0E" RN_0402 23.25,-27.571 r180 bottom
R152 "4.7K" RN_0402 16.5,-12.571 r0 bottom
R153 "4.7K" RN_0402 68.5,-16.571 r180 bottom
R154 "4.7K" RN_0402 33.5,-7.571 r0 bottom
R155 "4.7K" RN_0402 63.5,-33.446 r180 bottom
R156 "4.7K" RN_0402 63.375,-50.321 r90 bottom
R157 "4.7K" RN_0402 61.5,-33.446 r180 bottom
R158 "4.7K" RN_0402 25,-50.321 r90 bottom
R159 "4.7K" RN_0402 32,-8.071 r270 bottom
R234 "0E" RN_0402 73.123,-32.569 r90 top
R235 "0E" RN_0402 74.248,-32.569 r90 top
R240 "0E" RN_0402 -1.322,-5.646 r0 top
R271 "1K" RN_0402 12.25,-42.262 r90 bottom
R272 "1K" RN_0402 13.25,-42.262 r90 bottom
R273 "1K" RN_0402 12.25,-41.176 r90 top
R274 "1K" RN_0402 13.25,-41.176 r90 top
R275 "1K" RN_0201 1.27,-29.001 r90 bottom
R276 "1K" RN_0201 1.227,-31.808 r270 bottom
R500 "130K" RN_0402 10.973,0 r270 top
R501 "144.96K" RN_0402 12.268,-0.025 r90 top
R502 "8.62K" RN_0402 38.303,0.356 r0 bottom
R504 "15.1k" RN_0402 28.702,-1.346 r270 top
R506 "100k" RN_0402 42.215,2.54 r0 top
R507 "100k" RN_0402 42.24,3.683 r0 top
R508 "100k" RN_0402 32.258,-1.397 r270 top
R509 "100k" RN_0402 27.559,-1.346 r270 top
R510 "100K" RN_0402 82.677,-19.685 r270 top
R511 "100K" RN_0402 81.534,-19.685 r270 top
R512 "100K" RN_0402 76.962,-19.685 r270 top
R513 "100K" RN_0402 72.898,-10.922 r180 bottom
R514 "144.96K" RN_0402 83.82,-19.685 r270 top
R515 "120.8K" RN_0402 80.391,-19.685 r90 top
R516 "30.2k" RN_0402 75.819,-19.685 r270 top
R517 "60.4k" RN_0402 73.533,-19.685 r90 top
R518 "100K" RN_0402 65.786,2.413 r180 top
R519 "100K" RN_0402 65.786,3.556 r180 top
R520 "100K" RN_0402 47.244,7.874 r0 top
R521 "100K" RN_0402 47.244,9.017 r0 top
R522 "15.1k" RN_0402 63.398,0.127 r180 bottom
R524 "15.1K" RN_0402 51.943,-0.635 r180 top
R526 "10k" RN_0402 75.063,2.651 r180 top
R527 "10k" RN_0402 77.216,4.318 r180 top
R528 "10k" RN_0402 79.299,4.317 r180 top
R529 "10k" RN_0402 80.899,4.699 r90 top
R530 "10k" RN_0402 83.185,1.905 r0 top
R531 "10k" RN_0402 75.057,1.6 r180 top
R532 "100K" RN_0402 77.876,-2.54 r180 bottom
R533 "100E" RN_0402 83.185,3.048 r180 top
R534 "1K" RN_0402 83.185,3.048 r0 bottom
R535 "100E" RN_0402 82.042,4.699 r270 top
R536 "1K" RN_0402 82.042,4.699 r90 bottom
R537 "100E" RN_0402 83.185,4.699 r270 top
R538 "1K" RN_0402 83.185,4.699 r90 bottom
R539 "100E" RN_0402 79.253,5.461 r0 top
R540 "1K" RN_0402 79.253,5.461 r180 bottom
R541 "100E" RN_0402 79.248,6.604 r0 top
R542 "14K" RN_0402 72.771,-0.762 r180 top
R543 "10k" RN_0402 72.822,1.092 r0 top
R544 "1K" RN_0402 81.28,6.477 r0 bottom
R545 "100E" RN_0402 77.216,5.461 r0 top
R546 "1K" RN_0402 77.216,5.461 r180 bottom
R547 "100E" RN_0402 77.216,6.604 r0 top
R548 "1K" RN_0402 77.216,6.604 r180 bottom
R549 "100E" RN_0402 75.565,6.096 r270 top
R550 "1K" RN_0402 75.565,6.096 r90 bottom
R600 "0E" RN_0402 8.458,3.683 r270 top
R601 "0E" RN_0402 9.093,-0.762 r0 top
R602 "1K" RN_0402 79.248,6.604 r180 bottom
R603 "10K" RN_0402 14.808,4.75 r90 top
R604 "0E" RN_0402 42.215,1.397 r0 top
R605 "0E" RN_0402 38.303,1.422 r0 bottom
R606 "0E" RN_0402 34.671,-1.397 r270 top
R607 "0E" RN_0402 33.35,-1.397 r90 bottom
R608 "0E" RN_0402 29.845,-1.397 r270 top
R609 "0E" RN_0402 29.845,-1.397 r90 bottom
R610 "0E" RN_0402 26.365,-1.321 r270 top
R611 "0E" RN_0402 26.365,-1.321 r90 bottom
R612 "0E" RN_0402 82.677,-19.685 r270 bottom
R613 "0E" RN_0402 83.82,-19.685 r90 bottom
R614 "0E" RN_0402 78.105,-19.685 r270 top
R615 "0E" RN_0402 78.105,-19.685 r90 bottom
R616 "0E" RN_0402 74.676,-19.685 r270 top
R617 "0E" RN_0402 74.676,-19.685 r90 bottom
R618 "0E" RN_0402 70.993,-19.685 r270 top
R619 "0E" RN_0402 72.136,-19.685 r90 top
R631 "100K" RN_0402 80.213,-2.54 r180 top
R632 "100k" RN_0402 82.804,-2.286 r0 top
R633 "0E" RN_0402 58.344,-0.635 r0 top
R634 "0E" RN_0402 76.073,-2.54 r180 top
R635 "0E" RN_0402 54.102,-0.635 r180 top
R636 "4.7K" RN_0402 77.47,-0.584 r90 bottom
R637 "0E" RN_0402 47.498,2.159 r180 top
R638 "4.7K" RN_0402 82.804,-2.286 r0 bottom
R639 "100k" RN_0402 82.804,-1.143 r0 top
R640 "4.7K" RN_0402 82.804,-1.143 r0 bottom
R641 "1k" RN_0402 72.39,11.176 r90 top
R650 "10K" RN_0402 13.538,4.826 r90 top
R652 "0E" RN_0402 65.786,1.27 r0 top
R653 "0E" RN_0402 63.398,1.219 r0 bottom
R654 "0E" RN_0402 58.369,-0.635 r180 bottom
R655 "0E" RN_0402 54.102,-0.635 r0 bottom
R656 "0E" RN_0402 49.835,2.159 r180 bottom
R700 "4.7K" RN_0402 21.971,-9.906 r90 bottom
R701 "4.7K" RN_0402 12.37,-18.923 r0 top
R702 "4.7K" RN_0402 36.195,-1.524 r270 top
R703 "4.7K" RN_0402 12.319,-20.066 r0 top
R704 "4.7K" RN_0402 12.319,-21.209 r0 top
R705 "4.7K" RN_0402 12.319,-24.638 r0 top
R706 "4.7K" RN_0402 12.446,-37.592 r0 top
R707 "4.7K" RN_0402 12.37,-25.781 r0 top
R710 "10k" RN_0402 33.401,-1.397 r270 top
R724 "10k" RN_0402 79.248,-19.685 r270 top
R740 "4.7K" RN_0402 78.105,-2.54 r180 top
R743 "100E" RN_0402 81.28,6.477 r180 top
R750 "10k" RN_0402 47.498,3.429 r180 top
R800 "0E" RN_0402 1.295,-14.072 r180 bottom
RT "0E" RN_0402 11.506,6.858 r0 top
RT5 "0.012OHM" LVK12 83.312,-5.969 r90 bottom
RT6 "0.012OHM" LVK12 79.818,-5.947 r90 bottom
RT7 "0.012OHM" LVK12 76.073,-5.842 r90 bottom
RT8 "0.012OHM" LVK12 72.328,-5.946 r90 bottom
RT9 "0.012OHM" LVK12 42.545,6.985 r270 bottom
RT10 "0.012OHM" LVK12 27.178,10.82 r180 bottom
RT15 "0.012OHM" LVK12 66.04,6.858 r270 bottom
RT16 "0.012OHM" LVK12 49.276,10.795 r180 bottom
RT801 "0.012OHM" LVK12 70.358,10.769 r0 bottom
TP1 "Tap_point" MINI_TESTPOINT_SMD 2.667,10.733 r90 top
TP2 "Tap_point" MINI_TESTPOINT_SMD 2.667,8.052 r90 top
TP3 "Tap_point" MINI_TESTPOINT 84.455,-2.321 r90 top
TP4 "Tap_point" MINI_TESTPOINT 81.788,-3.302 r90 top
TP5 "Tap_point" MINI_TESTPOINT 81.534,-8.001 r90 top
TP6 "Tap_point" MINI_TESTPOINT 77.978,-4.318 r90 top
TP7 "Tap_point" MINI_TESTPOINT 77.978,-8.001 r90 top
TP8 "Tap_point" MINI_TESTPOINT 74.193,-3.175 r90 top
TP9 "Tap_point" MINI_TESTPOINT 74.168,-7.874 r90 top
TP10 "Tap_point" MINI_TESTPOINT 70.358,-2.667 r90 top
TP11 "Tap_point" MINI_TESTPOINT_SMD 41.91,10.414 r90 bottom
TP12 "Tap_point" MINI_TESTPOINT_SMD 40.014,9.322 r90 bottom
TP13 "Tap_point" MINI_TESTPOINT_SMD 30.455,11.328 r90 bottom
TP14 "Tap_point" MINI_TESTPOINT 23.901,11.495 r90 top
TP15 "Tap_point" MINI_TESTPOINT_SMD 65.38,10.287 r90 bottom
TP16 "Tap_point" MINI_TESTPOINT_SMD 63.652,9.779 r90 bottom
TP17 "Tap_point" MINI_TESTPOINT_SMD 52.578,11.43 r90 bottom
TP18 "Tap_point" MINI_TESTPOINT_SMD 45.872,11.481 r90 bottom
TP701 "Tap_point" MINI_TESTPOINT 64.135,-0.762 r90 top
TP702 "Tap_point" MINI_TESTPOINT 48.946,-0.711 r90 top
TP703 "Tap_point" MINI_TESTPOINT 48.057,0.686 r90 top
TP705 "Tap_point" MINI_TESTPOINT 69.596,-5.715 r90 top
TP706 "Tap_point" MINI_TESTPOINT 83.82,-21.463 r90 top
TP707 "Tap_point" MINI_TESTPOINT 80.391,-21.463 r90 top
TP708 "Tap_point" MINI_TESTPOINT 77.343,-21.463 r90 top
TP709 "Tap_point" MINI_TESTPOINT 75.946,-21.463 r90 top
TP711 "Tap_point" MINI_TESTPOINT_SMD 41.808,0.356 r90 bottom
TP713 "Tap_point" MINI_TESTPOINT 31.064,-1.143 r90 top
TP714 "Tap_point" MINI_TESTPOINT 24.359,6.579 r90 top
TP716 "Tap_point" MINI_TESTPOINT_SMD 5.969,4.064 r90 top
TP717 "Tap_point" MINI_TESTPOINT 20.371,6.299 r90 top
TP718 "Tap_point" MINI_TESTPOINT_SMD 9.652,3.556 r90 top
TP720 "Tap_point" MINI_TESTPOINT_SMD 13.716,3.073 r90 top
TP802 "Tap_point" MINI_TESTPOINT_SMD 68.936,8.28 r90 bottom
TP803 "Tap_point" MINI_TESTPOINT_SMD 71.755,8.331 r90 bottom
U1 "FFVA1156" FFVA1156 42,-27.571 r0 bottom
U2 "142-MRAM" 142-MRAM 23.5,-11.071 r270 top
U3 "142-MRAM" 142-MRAM 59.5,-11.071 r270 top
U4 "142-MRAM" 142-MRAM 41.5,-11.071 r270 top
U5 "142-MRAM" 142-MRAM 59.5,-27.071 r270 top
U6 "142-MRAM" 142-MRAM 59.5,-43.071 r270 top
U7 "142-MRAM" 142-MRAM 41.5,-27.071 r270 top
U8 "142-MRAM" 142-MRAM 23.5,-43.071 r270 top
U9 "142-MRAM" 142-MRAM 23.5,-27.071 r270 top
U10 "MT25QU02GABA" "MT25QU02GABA - BGA" 72.119,-25.733 r0 top
U18 "SI5335A" "SI5335A - QFN24" 2.125,-46.051 r90 top
U19 "24AA02" "24AA02 - SOT23" 71.181,-37.609 r0 top
U21 "TXS0104ERGYR" "TXS0104ERGYR - VQFN24" 3.518,-20.406 r180 top
U22 "SI53152" "SI53152 - QFN24" 11.25,-47.551 r90 top
U95 "TPS386000RGPR" QFN20_RGB_4P15X4P15X1_TEX 78.867,0.889 r0 top
U96 "LTM4644IY-1#PBF" BGA77_15X9X1P5_ANALOG 56.642,4.699 r270 top
U97 "LTM4644IY-1#PBF" BGA77_15X9X1P5_ANALOG 77.343,-13.462 r270 top
U98 "LTM4644IY-1#PBF" BGA77_15X9X1P5_ANALOG 33.02,4.699 r270 top
U99 "LTM_4631_4644" BGA144_16X16X1P91_1P91_ANA 11.633,3.683 r0 bottom
U100 "UA78M05CDCYR" VREG_SOT223-4_6P5X3P5X1P8 71.247,5.969 r90 top
X1 "ABM8-25.000MHZ-B2-T" AMB8 -1.875,-50.176 r0 top

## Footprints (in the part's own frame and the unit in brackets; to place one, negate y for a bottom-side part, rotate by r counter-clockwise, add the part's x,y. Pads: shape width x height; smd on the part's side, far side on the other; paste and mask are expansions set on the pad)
"24AA02 - SOT23" [mm]
  rect 1.1x0.6 smd: 1(-1.4,0.95) 2(-1.4,0) 3(-1.4,-0.95) 4(1.4,-0.95) 5(1.4,0.95)
  silkscreen extent -1.56,-1.4 0.71,1.77, body extent -2.03,-1.4 2.03,1.4, height 1.45
142-MRAM [mm]
  round 0.432 smd: A1(-6.5,7.5) A2(-5.5,7.5) A12(4.5,7.5) A13(5.5,7.5) A14(6.5,7.5) B1(-6.5,6.5) B14(6.5,6.5) C2(-5.5,5.5) C3(-4.5,5.5) C4(-3.5,5.5) C5(-2.5,5.5) C6(-1.5,5.5) C7(-0.5,5.5) C8(0.5,5.5) C9(1.5,5.5) C10(2.5,5.5) C11(3.5,5.5) C12(4.5,5.5) C13(5.5,5.5) C14(6.5,5.5) D2(-5.5,4.5) D3(-4.5,4.5) D4(-3.5,4.5) D5(-2.5,4.5) D6(-1.5,4.5) D7(-0.5,4.5) D8(0.5,4.5) D9(1.5,4.5) D10(2.5,4.5) D11(3.5,4.5) D12(4.5,4.5) D13(5.5,4.5) E2(-5.5,3.5) E3(-4.5,3.5) E4(-3.5,3.5) E5(-2.5,3.5) E6(-1.5,3.5) E7(-0.5,3.5) E8(0.5,3.5) E9(1.5,3.5) E10(2.5,3.5) E11(3.5,3.5) E12(4.5,3.5) E13(5.5,3.5) F2(-5.5,2.5) F3(-4.5,2.5) F4(-3.5,2.5) F5(-2.5,2.5) F6(-1.5,2.5) F7(-0.5,2.5) F8(0.5,2.5) F9(1.5,2.5) F10(2.5,2.5) F11(3.5,2.5) F12(4.5,2.5) F13(5.5,2.5) G2(-5.5,1.5) G3(-4.5,1.5) G4(-3.5,1.5) G5(-2.5,1.5) G10(2.5,1.5) G11(3.5,1.5) G12(4.5,1.5) G13(5.5,1.5) H2(-5.5,0.5) H3(-4.5,0.5) H4(-3.5,0.5) H5(-2.5,0.5) H13(5.5,0.5) J2(-5.5,-0.5) J3(-4.5,-0.5) J4(-3.5,-0.5) J5(-2.5,-0.5) J13(5.5,-0.5) K2(-5.5,-1.5) K3(-4.5,-1.5) K4(-3.5,-1.5) K5(-2.5,-1.5) K10(2.5,-1.5) K11(3.5,-1.5) K12(4.5,-1.5) K13(5.5,-1.5) L2(-5.5,-2.5) L3(-4.5,-2.5) L4(-3.5,-2.5) L5(-2.5,-2.5) L6(-1.5,-2.5) L7(-0.5,-2.5) L8(0.5,-2.5) L9(1.5,-2.5) L10(2.5,-2.5) L11(3.5,-2.5) L12(4.5,-2.5) L13(5.5,-2.5) M2(-5.5,-3.5) M3(-4.5,-3.5) M4(-3.5,-3.5) M5(-2.5,-3.5) M6(-1.5,-3.5) M7(-0.5,-3.5) M8(0.5,-3.5) M9(1.5,-3.5) M10(2.5,-3.5) M11(3.5,-3.5) M12(4.5,-3.5) M13(5.5,-3.5) N2(-5.5,-4.5) N3(-4.5,-4.5) N4(-3.5,-4.5) N5(-2.5,-4.5) N6(-1.5,-4.5) N7(-0.5,-4.5) N8(0.5,-4.5) N9(1.5,-4.5) N10(2.5,-4.5) N11(3.5,-4.5) N12(4.5,-4.5) N13(5.5,-4.5) P2(-5.5,-5.5) P3(-4.5,-5.5) P4(-3.5,-5.5) P5(-2.5,-5.5) P6(-1.5,-5.5) P7(-0.5,-5.5) P8(0.5,-5.5) P9(1.5,-5.5) P10(2.5,-5.5) P11(3.5,-5.5) P12(4.5,-5.5) P13(5.5,-5.5) R1(-6.5,-6.5) R14(6.5,-6.5) T1(-6.5,-7.5) T2(-5.5,-7.5) T13(5.5,-7.5) T14(6.5,-7.5)
  round 0.432 smd mask+0.051: H10(2.5,0.5) H11(3.5,0.5) H12(4.5,0.5) J10(2.5,-0.5) J11(3.5,-0.5) J12(4.5,-0.5)
  round 0.6 on Mech9: ""(0,0)
  silkscreen extent -7.72,-8.5 7.5,8.5, body extent -7.49,-8.51 7.49,8.51, height 1.53
68611014422 [mm]
  rect 0.6x2.2 smd: 1(-4.5,1.3) 2(-3.5,1.3) 3(-2.5,1.3) 4(-1.5,1.3) 5(-0.5,1.3) 6(0.5,1.3) 7(1.5,1.3) 8(2.5,1.3) 9(3.5,1.3) 10(4.5,1.3)
  rect 1.8x2.6 smd: ""(-7.1,-1.1) ""(7.1,-1.1)
  silkscreen extent -8.5,-5.2 8.5,1.79, body extent -8.51,-5.21 8.51,2.54, height 0.25
74269262601 [mm]
  rect 0.95x0.7 smd: 1(-0.825,0) 2(0.825,0)
  silkscreen extent -1.65,-0.76 1.65,0.76, body extent -1.65,-0.76 1.65,0.76, height 1
AMB8 [mm]
  rect 1.05x1.3 smd: 1(-0.875,1.15) 2(-0.875,-1.15) 3(0.875,-1.15) 4(0.875,1.15)
  silkscreen extent -2.14,-2 1.6,2, body extent -1.65,-2.03 1.65,2.03, height 0.8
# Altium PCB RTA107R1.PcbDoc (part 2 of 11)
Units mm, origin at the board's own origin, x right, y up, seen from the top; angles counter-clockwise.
Board outline 96.01 x 65.66 mm, 22 copper layers (Top Layer, GND1, INT1, PWR1-(VCCIO_MRAM), INT2, PWR2-(VCCINT), INT3, PWR3_(12V_MGTAVCC), INT4, GND2-(DGND_SGND), PWR4_(MGTAVTT_VCCBRAM,VCCAUX), PWR5-(VCC_12V), GND3-(DGND_GND), INT5, GND4, INT6, PWR6_(VCCO), INT7, GND5, INT8, GND6, Bottom Layer), stack 2.833 mm thick; 614 components, 659 nets, 4037 pads, 3511 vias.

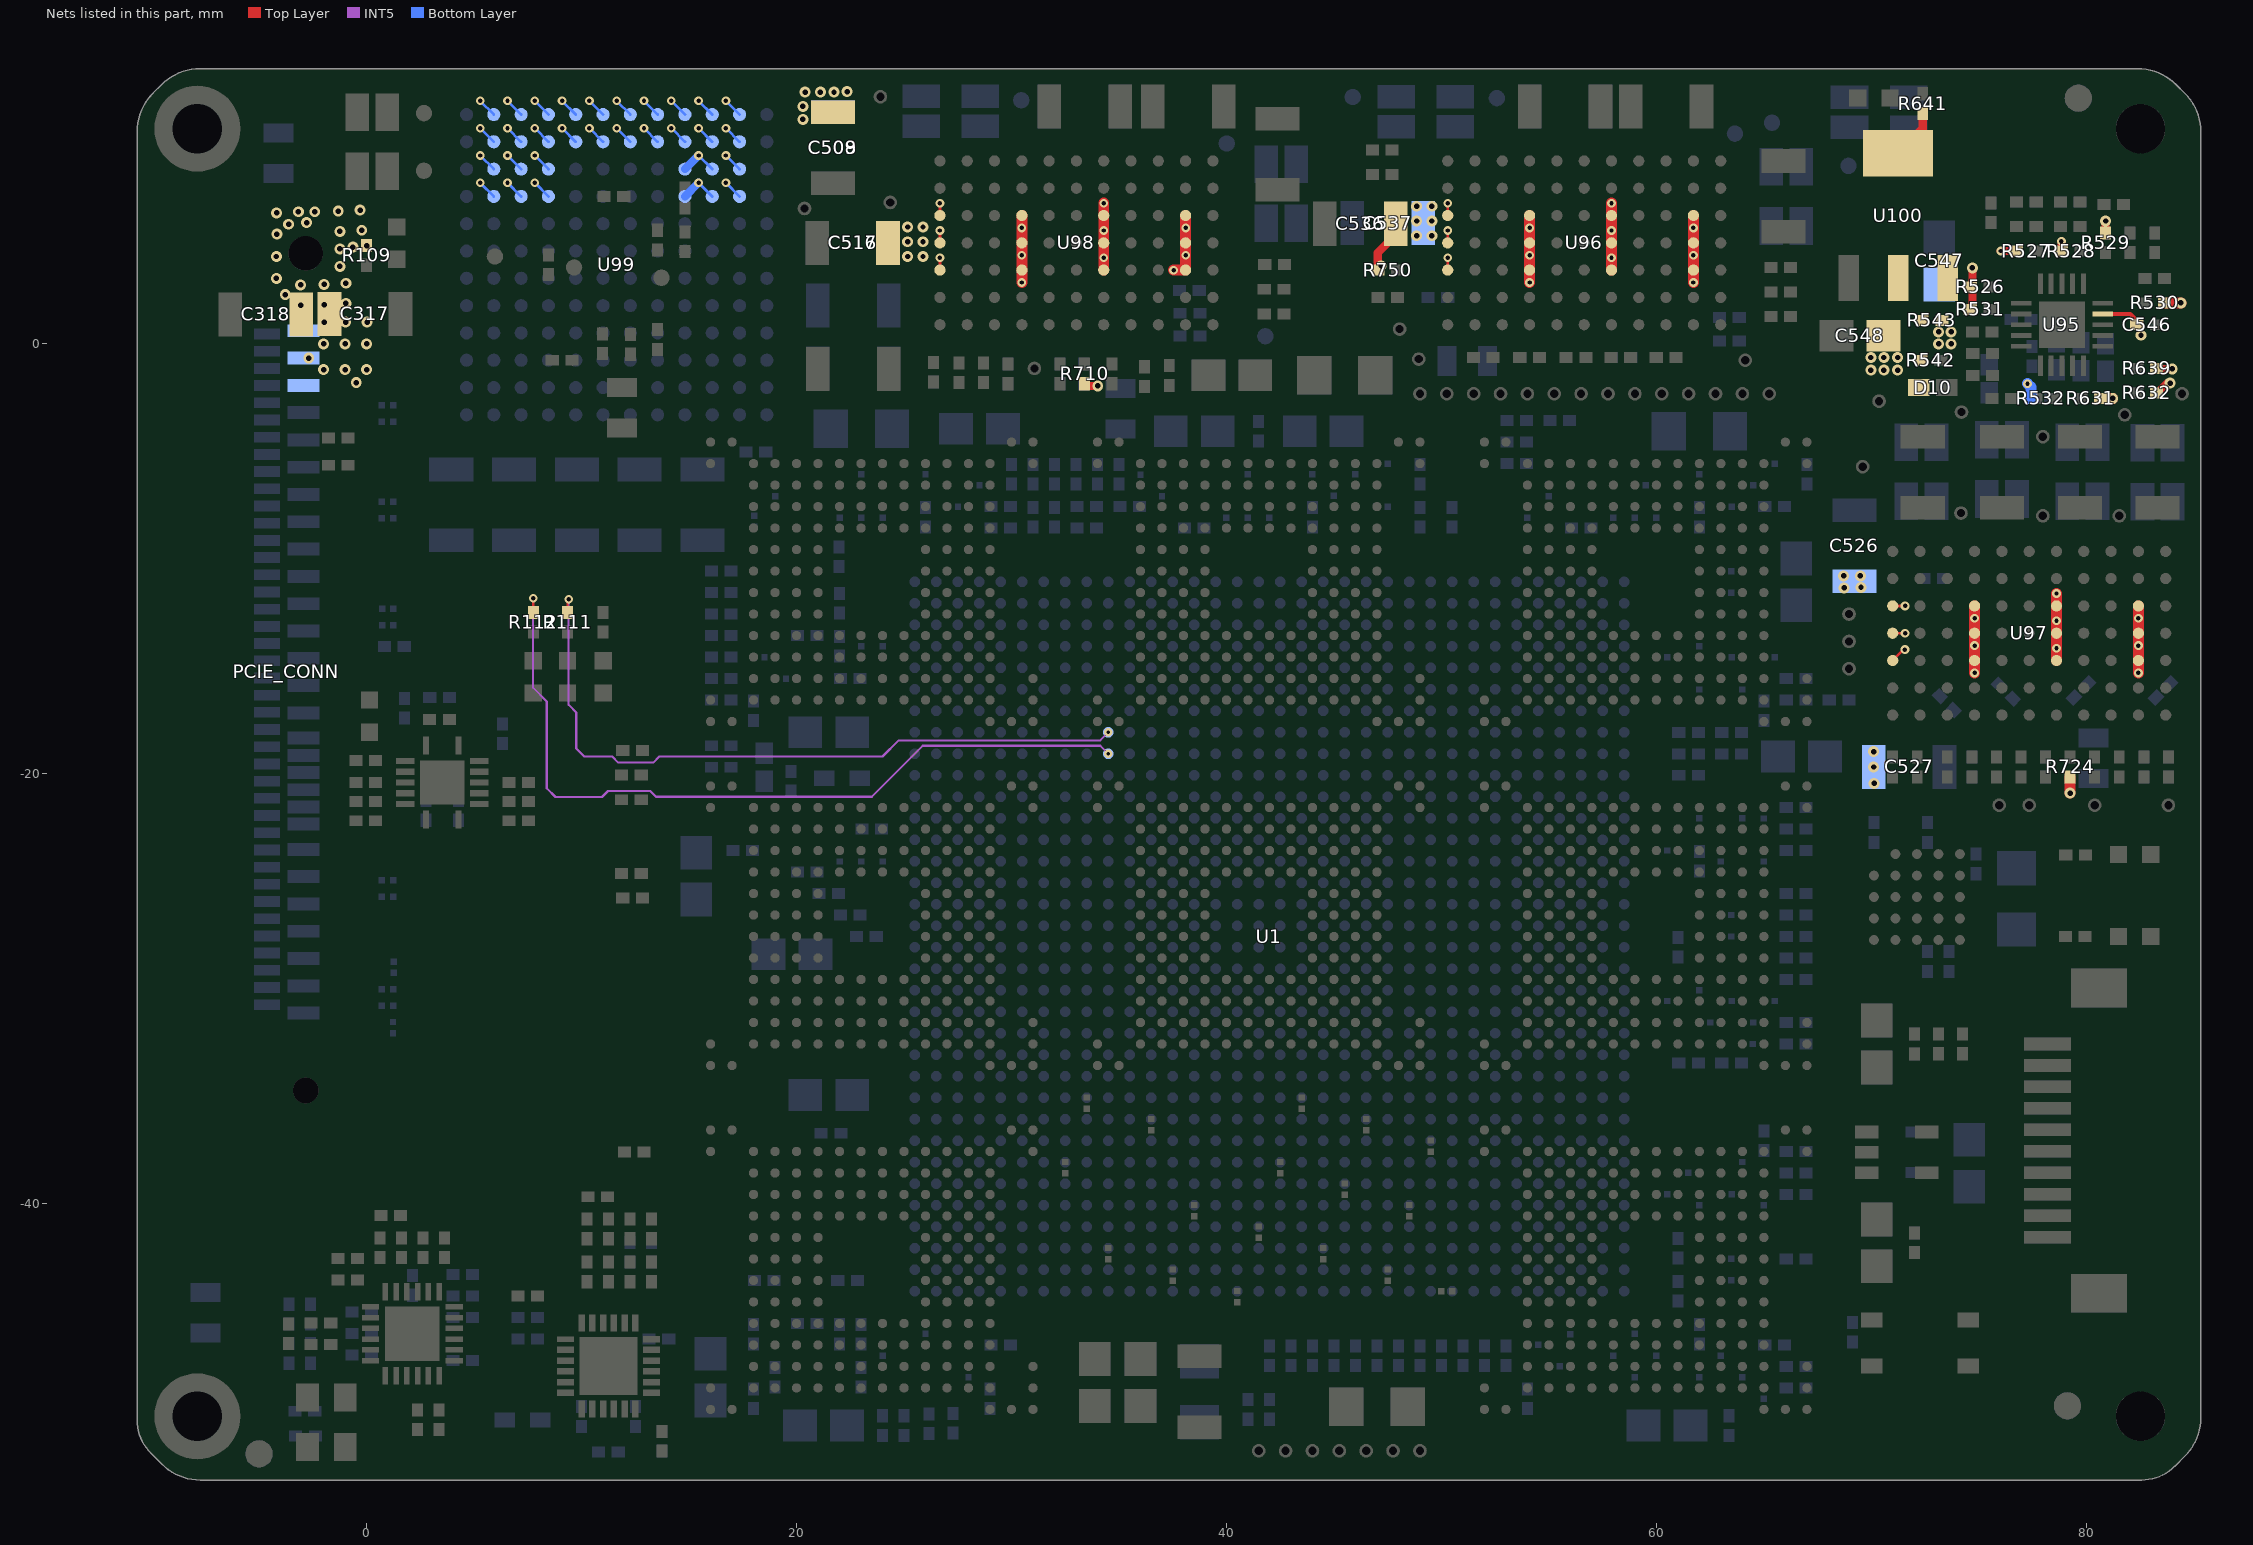
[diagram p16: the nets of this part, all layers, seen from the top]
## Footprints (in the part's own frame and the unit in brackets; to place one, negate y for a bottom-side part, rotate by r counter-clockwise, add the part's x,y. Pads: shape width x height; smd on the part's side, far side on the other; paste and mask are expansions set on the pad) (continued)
AMPHENOL_PSAS4M2130021TR [mm]
  rect 0.6x1.5 smd: E1(-7.08,-0.1) E2(-6.28,-0.1) E3(-5.48,-0.1) E4(-4.68,-0.1) E5(-3.88,-0.1) E6(-3.08,-0.1) P1(-1.905,-0.1) P2(-0.635,-0.1) P3(0.635,-0.1) P4(1.905,-0.1) P5(3.175,-0.1) P6(4.445,-0.1) P7(5.715,-0.1) P8(6.985,-0.1) P9(8.255,-0.1) P10(9.525,-0.1) P11(10.795,-0.1) P12(12.065,-0.1) P13(13.335,-0.1) P14(14.605,-0.1) P15(15.875,-0.1) S1(-15.875,-0.1) S2(-14.605,-0.1) S3(-13.335,-0.1) S4(-12.065,-0.1) S5(-10.795,-0.1) S6(-9.525,-0.1) S7(-8.255,-0.1)
  rect 0.5x1.2 smd: E7(-15.48,-1.8) E8(-14.68,-1.8) E9(-13.88,-1.8) E10(-13.08,-1.8) E11(-12.28,-1.8) E12(-11.48,-1.8) E13(-10.68,-1.8) E14(-9.88,-1.8) E15(-9.08,-1.8) E16(-8.28,-1.8) E17(9.32,-1.8) E18(10.12,-1.8) E19(10.92,-1.8) E20(11.72,-1.8) E21(12.52,-1.8) E22(13.32,-1.8) E23(14.12,-1.8) E24(14.92,-1.8) E25(15.72,-1.8) S8(-7.48,-1.8) S9(-6.68,-1.8) S10(-5.88,-1.8) S11(-5.08,-1.8) S12(-4.28,-1.8) S13(-3.48,-1.8) S14(-2.68,-1.8) S15(-1.88,-1.8) S16(-1.08,-1.8) S17(-0.28,-1.8) S18(0.52,-1.8) S19(1.32,-1.8) S20(2.12,-1.8) S21(2.92,-1.8) S22(3.72,-1.8) S23(4.52,-1.8) S24(5.32,-1.8) S25(6.12,-1.8) S26(6.92,-1.8) S27(7.72,-1.8) S28(8.52,-1.8)
  round 1.2 hole 1.2 unplated: ""(-19.47,0)
  round 1.6 hole 1.6 unplated: ""(19.47,0)
  silkscreen extent -24,-10.1 24,2.25, body extent -25.37,-10.08 25.25,3.51, height 10.51
"BAS40 - SOD523" [mm]
  rect 1x0.8 smd: 1(-0.65,0) 2(0.65,0)
  silkscreen extent -0.57,-0.51 0.64,0.51, body extent -1.14,-0.51 1.14,0.51, height 1.35
BGA77_15X9X1P5_ANALOG [mm]
  round 0.522 smd: A1(-3.81,6.35) A2(-2.54,6.35) A3(-1.27,6.35) A4(0,6.35) A5(1.27,6.35) A6(2.54,6.35) A7(3.81,6.35) B1(-3.81,5.08) B2(-2.54,5.08) B3(-1.27,5.08) B4(0,5.08) B5(1.27,5.08) B6(2.54,5.08) B7(3.81,5.08) C1(-3.81,3.81) C2(-2.54,3.81) C3(-1.27,3.81) C4(0,3.81) C5(1.27,3.81) C6(2.54,3.81) C7(3.81,3.81) D1(-3.81,2.54) D2(-2.54,2.54) D3(-1.27,2.54) D4(0,2.54) D5(1.27,2.54) D6(2.54,2.54) D7(3.81,2.54) E1(-3.81,1.27) E2(-2.54,1.27) E3(-1.27,1.27) E4(0,1.27) E5(1.27,1.27) E6(2.54,1.27) E7(3.81,1.27) F1(-3.81,0) F2(-2.54,0) F3(-1.27,0) F4(0,0) F5(1.27,0) F6(2.54,0) F7(3.81,0) G1(-3.81,-1.27) G2(-2.54,-1.27) G3(-1.27,-1.27) G4(0,-1.27) G5(1.27,-1.27) G6(2.54,-1.27) G7(3.81,-1.27) H1(-3.81,-2.54) H2(-2.54,-2.54) H3(-1.27,-2.54) H4(0,-2.54) H5(1.27,-2.54) H6(2.54,-2.54) H7(3.81,-2.54) J1(-3.81,-3.81) J2(-2.54,-3.81) J3(-1.27,-3.81) J4(0,-3.81) J5(1.27,-3.81) J6(2.54,-3.81) J7(3.81,-3.81) K1(-3.81,-5.08) K2(-2.54,-5.08) K3(-1.27,-5.08) K4(0,-5.08) K5(1.27,-5.08) K6(2.54,-5.08) K7(3.81,-5.08) L1(-3.81,-6.35) L2(-2.54,-6.35) L3(-1.27,-6.35) L4(0,-6.35) L5(1.27,-6.35) L6(2.54,-6.35) L7(3.81,-6.35)
  silkscreen extent -4.5,-7.5 4.5,7.5, body extent -4.5,-7.5 4.5,7.5, height 4.51
BGA144_16X16X1P91_1P91_ANA [mm]
  round 0.612 smd: A1(-6.985,6.985) A2(-5.715,6.985) A3(-4.445,6.985) A4(-3.175,6.985) A5(-1.905,6.985) A6(-0.635,6.985) A7(0.635,6.985) A8(1.905,6.985) A9(3.175,6.985) A10(4.445,6.985) A11(5.715,6.985) A12(6.985,6.985) B1(-6.985,5.715) B2(-5.715,5.715) B3(-4.445,5.715) B4(-3.175,5.715) B5(-1.905,5.715) B6(-0.635,5.715) B7(0.635,5.715) B8(1.905,5.715) B9(3.175,5.715) B10(4.445,5.715) B11(5.715,5.715) B12(6.985,5.715) C1(-6.985,4.445) C2(-5.715,4.445) C3(-4.445,4.445) C4(-3.175,4.445) C5(-1.905,4.445) C6(-0.635,4.445) C7(0.635,4.445) C8(1.905,4.445) C9(3.175,4.445) C10(4.445,4.445) C11(5.715,4.445) C12(6.985,4.445) D1(-6.985,3.175) D2(-5.715,3.175) D3(-4.445,3.175) D4(-3.175,3.175) D5(-1.905,3.175) D6(-0.635,3.175) D7(0.635,3.175) D8(1.905,3.175) D9(3.175,3.175) D10(4.445,3.175) D11(5.715,3.175) D12(6.985,3.175) E1(-6.985,1.905) E2(-5.715,1.905) E3(-4.445,1.905) E4(-3.175,1.905) E5(-1.905,1.905) E6(-0.635,1.905) E7(0.635,1.905) E8(1.905,1.905) E9(3.175,1.905) E10(4.445,1.905) E11(5.715,1.905) E12(6.985,1.905) F1(-6.985,0.635) F2(-5.715,0.635) F3(-4.445,0.635) F4(-3.175,0.635) F5(-1.905,0.635) F6(-0.635,0.635) F7(0.635,0.635) F8(1.905,0.635) F9(3.175,0.635) F10(4.445,0.635) F11(5.715,0.635) F12(6.985,0.635) G1(-6.985,-0.635) G2(-5.715,-0.635) G3(-4.445,-0.635) G4(-3.175,-0.635) G5(-1.905,-0.635) G6(-0.635,-0.635) G7(0.635,-0.635) G8(1.905,-0.635) G9(3.175,-0.635) G10(4.445,-0.635) G11(5.715,-0.635) G12(6.985,-0.635) H1(-6.985,-1.905) H2(-5.715,-1.905) H3(-4.445,-1.905) H4(-3.175,-1.905) H5(-1.905,-1.905) H6(-0.635,-1.905) H7(0.635,-1.905) H8(1.905,-1.905) H9(3.175,-1.905) H10(4.445,-1.905) H11(5.715,-1.905) H12(6.985,-1.905) J1(-6.985,-3.175) J2(-5.715,-3.175) J3(-4.445,-3.175) J4(-3.175,-3.175) J5(-1.905,-3.175) J6(-0.635,-3.175) J7(0.635,-3.175) J8(1.905,-3.175) J9(3.175,-3.175) J10(4.445,-3.175) J11(5.715,-3.175) J12(6.985,-3.175) K1(-6.985,-4.445) K2(-5.715,-4.445) K3(-4.445,-4.445) K4(-3.175,-4.445) K5(-1.905,-4.445) K6(-0.635,-4.445) K7(0.635,-4.445) K8(1.905,-4.445) K9(3.175,-4.445) K10(4.445,-4.445) K11(5.715,-4.445) K12(6.985,-4.445) L1(-6.985,-5.715) L2(-5.715,-5.715) L3(-4.445,-5.715) L4(-3.175,-5.715) L5(-1.905,-5.715) L6(-0.635,-5.715) L7(0.635,-5.715) L8(1.905,-5.715) L9(3.175,-5.715) L10(4.445,-5.715) L11(5.715,-5.715) L12(6.985,-5.715) M1(-6.985,-6.985) M2(-5.715,-6.985) M3(-4.445,-6.985) M4(-3.175,-6.985) M5(-1.905,-6.985) M6(-0.635,-6.985) M7(0.635,-6.985) M8(1.905,-6.985) M9(3.175,-6.985) M10(4.445,-6.985) M11(5.715,-6.985) M12(6.985,-6.985)
  silkscreen extent -8,-8 8,8, body extent -8,-7.98 8,8, height 2.51
CN_0201 [mm]
  rect 0.3x0.3 smd mask+0.051: 1(-0.26,0) 2(0.26,0)
  silkscreen extent -0.58,-0.33 0.58,0.33, body extent -0.43,-0.18 0.43,0.2, height 0.55
CN_0402 [mil] "Chip Capacitor, Body 1.0x0.5mm, IPC High Density"
  rect 24x20 smd mask+2: 1(-18,0) 2(18,0)
  silkscreen extent -36,-18 36,18, body extent -35,-20 35,20, height 39
CN_0805 [mil]
  rect 62x58 smd: 1(-43,0) 2(43,0)
  silkscreen extent -85,-40 85,40, body extent -85,-40 85,40, height 35
CN_1206 [mm]
  rect 1.6x1.8 smd: 1(-1.425,0) 2(1.425,0)
  silkscreen extent -2.51,-1.17 2.51,1.17, body extent -2.54,-1.14 2.54,1.14, height 1.6
CN_1210 [mm]
  rect 1.1x2.05 smd: 1(-1.65,0) 2(1.65,0)
  silkscreen extent -0.72,-1.35 0.72,1.35, body extent -2.29,-1.4 2.29,1.4, height 2.5
FFVA1156 [mm]
  round 0.5 smd: A1(-16.5,16.5) A2(-15.5,16.5) A3(-14.5,16.5) A4(-13.5,16.5) A5(-12.5,16.5) A6(-11.5,16.5) A7(-10.5,16.5) A8(-9.5,16.5) A9(-8.5,16.5) A10(-7.5,16.5) A11(-6.5,16.5) A12(-5.5,16.5) A13(-4.5,16.5) A14(-3.5,16.5) A15(-2.5,16.5) A16(-1.5,16.5) A17(-0.5,16.5) A18(0.5,16.5) A19(1.5,16.5) A20(2.5,16.5) A21(3.5,16.5) A22(4.5,16.5) A23(5.5,16.5) A24(6.5,16.5) A25(7.5,16.5) A26(8.5,16.5) A27(9.5,16.5) A28(10.5,16.5) A29(11.5,16.5) A30(12.5,16.5) A31(13.5,16.5) A32(14.5,16.5) A33(15.5,16.5) A34(16.5,16.5) AA1(-16.5,-3.5) AA2(-15.5,-3.5) AA3(-14.5,-3.5) AA4(-13.5,-3.5) AA5(-12.5,-3.5) AA6(-11.5,-3.5) AA7(-10.5,-3.5) AA8(-9.5,-3.5) AA9(-8.5,-3.5) AA10(-7.5,-3.5) AA11(-6.5,-3.5) AA12(-5.5,-3.5) AA13(-4.5,-3.5) AA14(-3.5,-3.5) AA15(-2.5,-3.5) AA16(-1.5,-3.5) AA17(-0.5,-3.5) AA18(0.5,-3.5) AA19(1.5,-3.5) AA20(2.5,-3.5) AA21(3.5,-3.5) AA22(4.5,-3.5) AA23(5.5,-3.5) AA24(6.5,-3.5) AA25(7.5,-3.5) AA26(8.5,-3.5) AA27(9.5,-3.5) AA28(10.5,-3.5) AA29(11.5,-3.5) AA30(12.5,-3.5) AA31(13.5,-3.5) AA32(14.5,-3.5) AA33(15.5,-3.5) AA34(16.5,-3.5) AB1(-16.5,-4.5) AB2(-15.5,-4.5) AB3(-14.5,-4.5) AB4(-13.5,-4.5) AB5(-12.5,-4.5) AB6(-11.5,-4.5) AB7(-10.5,-4.5) AB8(-9.5,-4.5) AB9(-8.5,-4.5) AB10(-7.5,-4.5) AB11(-6.5,-4.5) AB12(-5.5,-4.5) AB13(-4.5,-4.5) AB14(-3.5,-4.5) AB15(-2.5,-4.5) AB16(-1.5,-4.5) AB17(-0.5,-4.5) AB18(0.5,-4.5) AB19(1.5,-4.5) AB20(2.5,-4.5) AB21(3.5,-4.5) AB22(4.5,-4.5) AB23(5.5,-4.5) AB24(6.5,-4.5) AB25(7.5,-4.5) AB26(8.5,-4.5) AB27(9.5,-4.5) AB28(10.5,-4.5) AB29(11.5,-4.5) AB30(12.5,-4.5) AB31(13.5,-4.5) AB32(14.5,-4.5) AB33(15.5,-4.5) AB34(16.5,-4.5) AC1(-16.5,-5.5) AC2(-15.5,-5.5) AC3(-14.5,-5.5) AC4(-13.5,-5.5) AC5(-12.5,-5.5) AC6(-11.5,-5.5) AC7(-10.5,-5.5) AC8(-9.5,-5.5) AC9(-8.5,-5.5) AC10(-7.5,-5.5) AC11(-6.5,-5.5) AC12(-5.5,-5.5) AC13(-4.5,-5.5) AC14(-3.5,-5.5) AC15(-2.5,-5.5) AC16(-1.5,-5.5) AC17(-0.5,-5.5) AC18(0.5,-5.5) AC19(1.5,-5.5) AC20(2.5,-5.5) AC21(3.5,-5.5) AC22(4.5,-5.5) AC23(5.5,-5.5) AC24(6.5,-5.5) AC25(7.5,-5.5) AC26(8.5,-5.5) AC27(9.5,-5.5) AC28(10.5,-5.5) AC29(11.5,-5.5) AC30(12.5,-5.5) AC31(13.5,-5.5) AC32(14.5,-5.5) AC33(15.5,-5.5) AC34(16.5,-5.5) AD1(-16.5,-6.5) AD2(-15.5,-6.5) AD3(-14.5,-6.5) AD4(-13.5,-6.5) AD5(-12.5,-6.5) AD6(-11.5,-6.5) AD7(-10.5,-6.5) AD8(-9.5,-6.5) AD9(-8.5,-6.5) AD10(-7.5,-6.5) AD11(-6.5,-6.5) AD12(-5.5,-6.5) AD13(-4.5,-6.5) AD14(-3.5,-6.5) AD15(-2.5,-6.5) AD16(-1.5,-6.5) AD17(-0.5,-6.5) AD18(0.5,-6.5) AD19(1.5,-6.5) AD20(2.5,-6.5) AD21(3.5,-6.5) AD22(4.5,-6.5) AD23(5.5,-6.5) AD24(6.5,-6.5) AD25(7.5,-6.5) AD26(8.5,-6.5) AD27(9.5,-6.5) AD28(10.5,-6.5) AD29(11.5,-6.5) AD30(12.5,-6.5) AD31(13.5,-6.5) AD32(14.5,-6.5) AD33(15.5,-6.5) AD34(16.5,-6.5) AE1(-16.5,-7.5) AE2(-15.5,-7.5) AE3(-14.5,-7.5) AE4(-13.5,-7.5) AE5(-12.5,-7.5) AE6(-11.5,-7.5) AE7(-10.5,-7.5) AE8(-9.5,-7.5) AE9(-8.5,-7.5) AE10(-7.5,-7.5) AE11(-6.5,-7.5) AE12(-5.5,-7.5) AE13(-4.5,-7.5) AE14(-3.5,-7.5) AE15(-2.5,-7.5) AE16(-1.5,-7.5) AE17(-0.5,-7.5) AE18(0.5,-7.5) AE19(1.5,-7.5) AE20(2.5,-7.5) AE21(3.5,-7.5) AE22(4.5,-7.5) AE23(5.5,-7.5) AE24(6.5,-7.5) AE25(7.5,-7.5) AE26(8.5,-7.5) AE27(9.5,-7.5) AE28(10.5,-7.5) AE29(11.5,-7.5) AE30(12.5,-7.5) AE31(13.5,-7.5) AE32(14.5,-7.5) AE33(15.5,-7.5) AE34(16.5,-7.5) AF1(-16.5,-8.5) AF2(-15.5,-8.5) AF3(-14.5,-8.5) AF4(-13.5,-8.5) AF5(-12.5,-8.5) AF6(-11.5,-8.5) AF7(-10.5,-8.5) AF8(-9.5,-8.5) AF9(-8.5,-8.5) AF10(-7.5,-8.5) AF11(-6.5,-8.5) AF12(-5.5,-8.5) AF13(-4.5,-8.5) AF14(-3.5,-8.5) AF15(-2.5,-8.5) AF16(-1.5,-8.5) AF17(-0.5,-8.5) AF18(0.5,-8.5) AF19(1.5,-8.5) AF20(2.5,-8.5) AF21(3.5,-8.5) AF22(4.5,-8.5) AF23(5.5,-8.5) AF24(6.5,-8.5) AF25(7.5,-8.5) AF26(8.5,-8.5) AF27(9.5,-8.5) AF28(10.5,-8.5) AF29(11.5,-8.5) AF30(12.5,-8.5) AF31(13.5,-8.5) AF32(14.5,-8.5) AF33(15.5,-8.5) AF34(16.5,-8.5) AG1(-16.5,-9.5) AG2(-15.5,-9.5) AG3(-14.5,-9.5) AG4(-13.5,-9.5) AG5(-12.5,-9.5) AG6(-11.5,-9.5) AG7(-10.5,-9.5) AG8(-9.5,-9.5) AG9(-8.5,-9.5) AG10(-7.5,-9.5) AG11(-6.5,-9.5) AG12(-5.5,-9.5) AG13(-4.5,-9.5) AG14(-3.5,-9.5) AG15(-2.5,-9.5) AG16(-1.5,-9.5) AG17(-0.5,-9.5) AG18(0.5,-9.5) AG19(1.5,-9.5) AG20(2.5,-9.5) AG21(3.5,-9.5) AG22(4.5,-9.5) AG23(5.5,-9.5) AG24(6.5,-9.5) AG25(7.5,-9.5) AG26(8.5,-9.5) AG27(9.5,-9.5) AG28(10.5,-9.5) AG29(11.5,-9.5) AG30(12.5,-9.5) AG31(13.5,-9.5) AG32(14.5,-9.5) AG33(15.5,-9.5) AG34(16.5,-9.5) AH1(-16.5,-10.5) AH2(-15.5,-10.5) AH3(-14.5,-10.5) AH4(-13.5,-10.5) AH5(-12.5,-10.5) AH6(-11.5,-10.5) AH7(-10.5,-10.5) AH8(-9.5,-10.5) AH9(-8.5,-10.5) AH10(-7.5,-10.5) AH11(-6.5,-10.5) AH12(-5.5,-10.5) AH13(-4.5,-10.5) AH14(-3.5,-10.5) AH15(-2.5,-10.5) AH16(-1.5,-10.5) AH17(-0.5,-10.5) AH18(0.5,-10.5) AH19(1.5,-10.5) AH20(2.5,-10.5) AH21(3.5,-10.5) AH22(4.5,-10.5) AH23(5.5,-10.5) AH24(6.5,-10.5) AH25(7.5,-10.5) AH26(8.5,-10.5) AH27(9.5,-10.5) AH28(10.5,-10.5) AH29(11.5,-10.5) AH30(12.5,-10.5) AH31(13.5,-10.5) AH32(14.5,-10.5) AH33(15.5,-10.5) AH34(16.5,-10.5) AJ1(-16.5,-11.5) AJ2(-15.5,-11.5) AJ3(-14.5,-11.5) AJ4(-13.5,-11.5) AJ5(-12.5,-11.5) AJ6(-11.5,-11.5) AJ7(-10.5,-11.5) AJ8(-9.5,-11.5) AJ9(-8.5,-11.5) AJ10(-7.5,-11.5) AJ11(-6.5,-11.5) AJ12(-5.5,-11.5) AJ13(-4.5,-11.5) AJ14(-3.5,-11.5) AJ15(-2.5,-11.5) AJ16(-1.5,-11.5) AJ17(-0.5,-11.5) AJ18(0.5,-11.5) AJ19(1.5,-11.5) AJ20(2.5,-11.5) AJ21(3.5,-11.5) AJ22(4.5,-11.5) AJ23(5.5,-11.5) AJ24(6.5,-11.5) AJ25(7.5,-11.5) AJ26(8.5,-11.5) AJ27(9.5,-11.5) AJ28(10.5,-11.5) AJ29(11.5,-11.5) AJ30(12.5,-11.5) AJ31(13.5,-11.5) AJ32(14.5,-11.5) AJ33(15.5,-11.5) AJ34(16.5,-11.5) AK1(-16.5,-12.5) AK2(-15.5,-12.5) AK3(-14.5,-12.5) AK4(-13.5,-12.5) AK5(-12.5,-12.5) AK6(-11.5,-12.5) AK7(-10.5,-12.5) AK8(-9.5,-12.5) AK9(-8.5,-12.5) AK10(-7.5,-12.5) AK11(-6.5,-12.5) AK12(-5.5,-12.5) AK13(-4.5,-12.5) AK14(-3.5,-12.5) AK15(-2.5,-12.5) AK16(-1.5,-12.5) AK17(-0.5,-12.5) AK18(0.5,-12.5) AK19(1.5,-12.5) AK20(2.5,-12.5) AK21(3.5,-12.5) AK22(4.5,-12.5) AK23(5.5,-12.5) AK24(6.5,-12.5) AK25(7.5,-12.5) AK26(8.5,-12.5) AK27(9.5,-12.5) AK28(10.5,-12.5) AK29(11.5,-12.5) AK30(12.5,-12.5) AK31(13.5,-12.5) AK32(14.5,-12.5) AK33(15.5,-12.5) AK34(16.5,-12.5) AL1(-16.5,-13.5) AL2(-15.5,-13.5) AL3(-14.5,-13.5) AL4(-13.5,-13.5) AL5(-12.5,-13.5) AL6(-11.5,-13.5) AL7(-10.5,-13.5) AL8(-9.5,-13.5) AL9(-8.5,-13.5) AL10(-7.5,-13.5) AL11(-6.5,-13.5) AL12(-5.5,-13.5) AL13(-4.5,-13.5) AL14(-3.5,-13.5) AL15(-2.5,-13.5) AL16(-1.5,-13.5) AL17(-0.5,-13.5) AL18(0.5,-13.5) AL19(1.5,-13.5) AL20(2.5,-13.5) AL21(3.5,-13.5) AL22(4.5,-13.5) AL23(5.5,-13.5) AL24(6.5,-13.5) AL25(7.5,-13.5) AL26(8.5,-13.5) AL27(9.5,-13.5) AL28(10.5,-13.5) AL29(11.5,-13.5) AL30(12.5,-13.5) AL31(13.5,-13.5) AL32(14.5,-13.5) AL33(15.5,-13.5) AL34(16.5,-13.5) AM1(-16.5,-14.5) AM2(-15.5,-14.5) AM3(-14.5,-14.5) AM4(-13.5,-14.5) AM5(-12.5,-14.5) AM6(-11.5,-14.5) AM7(-10.5,-14.5) AM8(-9.5,-14.5) AM9(-8.5,-14.5) AM10(-7.5,-14.5) AM11(-6.5,-14.5) AM12(-5.5,-14.5) AM13(-4.5,-14.5) AM14(-3.5,-14.5) AM15(-2.5,-14.5) AM16(-1.5,-14.5) AM17(-0.5,-14.5) AM18(0.5,-14.5) AM19(1.5,-14.5) AM20(2.5,-14.5) AM21(3.5,-14.5) AM22(4.5,-14.5) AM23(5.5,-14.5) AM24(6.5,-14.5) AM25(7.5,-14.5) AM26(8.5,-14.5) AM27(9.5,-14.5) AM28(10.5,-14.5) AM29(11.5,-14.5) AM30(12.5,-14.5) AM31(13.5,-14.5) AM32(14.5,-14.5) AM33(15.5,-14.5) AM34(16.5,-14.5) AN1(-16.5,-15.5) AN2(-15.5,-15.5) AN3(-14.5,-15.5) AN4(-13.5,-15.5) AN5(-12.5,-15.5) AN6(-11.5,-15.5) AN7(-10.5,-15.5) AN8(-9.5,-15.5) AN9(-8.5,-15.5) AN10(-7.5,-15.5) AN11(-6.5,-15.5) AN12(-5.5,-15.5) AN13(-4.5,-15.5) AN14(-3.5,-15.5) AN15(-2.5,-15.5) AN16(-1.5,-15.5) AN17(-0.5,-15.5) AN18(0.5,-15.5) AN19(1.5,-15.5) AN20(2.5,-15.5) AN21(3.5,-15.5) AN22(4.5,-15.5) AN23(5.5,-15.5) AN24(6.5,-15.5) AN25(7.5,-15.5) AN26(8.5,-15.5) AN27(9.5,-15.5) AN28(10.5,-15.5) AN29(11.5,-15.5) AN30(12.5,-15.5) AN31(13.5,-15.5) AN32(14.5,-15.5) AN33(15.5,-15.5) AN34(16.5,-15.5) AP1(-16.5,-16.5) AP2(-15.5,-16.5) AP3(-14.5,-16.5) AP4(-13.5,-16.5) AP5(-12.5,-16.5) AP6(-11.5,-16.5) AP7(-10.5,-16.5) AP8(-9.5,-16.5) AP9(-8.5,-16.5) AP10(-7.5,-16.5) AP11(-6.5,-16.5) AP12(-5.5,-16.5) AP13(-4.5,-16.5) AP14(-3.5,-16.5) AP15(-2.5,-16.5) AP16(-1.5,-16.5) AP17(-0.5,-16.5) AP18(0.5,-16.5) AP19(1.5,-16.5) AP20(2.5,-16.5) AP21(3.5,-16.5) AP22(4.5,-16.5) AP23(5.5,-16.5) AP24(6.5,-16.5) AP25(7.5,-16.5) AP26(8.5,-16.5) AP27(9.5,-16.5) AP28(10.5,-16.5) AP29(11.5,-16.5) AP30(12.5,-16.5) AP31(13.5,-16.5) AP32(14.5,-16.5) AP33(15.5,-16.5) AP34(16.5,-16.5) B1(-16.5,15.5) B2(-15.5,15.5) B3(-14.5,15.5) B4(-13.5,15.5) B5(-12.5,15.5) B6(-11.5,15.5) B7(-10.5,15.5) B8(-9.5,15.5) B9(-8.5,15.5) B10(-7.5,15.5) B11(-6.5,15.5) B12(-5.5,15.5) B13(-4.5,15.5) B14(-3.5,15.5) B15(-2.5,15.5) B16(-1.5,15.5) B17(-0.5,15.5) B18(0.5,15.5) B19(1.5,15.5) B20(2.5,15.5) B21(3.5,15.5) B22(4.5,15.5) B23(5.5,15.5) B24(6.5,15.5) B25(7.5,15.5) B26(8.5,15.5) B27(9.5,15.5) B28(10.5,15.5) B29(11.5,15.5) B30(12.5,15.5) B31(13.5,15.5) B32(14.5,15.5) B33(15.5,15.5) B34(16.5,15.5) C1(-16.5,14.5) C2(-15.5,14.5) C3(-14.5,14.5) C4(-13.5,14.5) C5(-12.5,14.5) C6(-11.5,14.5) C7(-10.5,14.5) C8(-9.5,14.5) C9(-8.5,14.5) C10(-7.5,14.5) C11(-6.5,14.5) C12(-5.5,14.5) C13(-4.5,14.5) C14(-3.5,14.5) C15(-2.5,14.5) C16(-1.5,14.5) C17(-0.5,14.5) C18(0.5,14.5) C19(1.5,14.5) C20(2.5,14.5) C21(3.5,14.5) C22(4.5,14.5) C23(5.5,14.5) C24(6.5,14.5) C25(7.5,14.5) C26(8.5,14.5) C27(9.5,14.5) C28(10.5,14.5) C29(11.5,14.5) C30(12.5,14.5) C31(13.5,14.5) C32(14.5,14.5) C33(15.5,14.5) C34(16.5,14.5) D1(-16.5,13.5) D2(-15.5,13.5) D3(-14.5,13.5) D4(-13.5,13.5) D5(-12.5,13.5) D6(-11.5,13.5) D7(-10.5,13.5) D8(-9.5,13.5) D9(-8.5,13.5) D10(-7.5,13.5) D11(-6.5,13.5) D12(-5.5,13.5) D13(-4.5,13.5) D14(-3.5,13.5) D15(-2.5,13.5) D16(-1.5,13.5) D17(-0.5,13.5) D18(0.5,13.5) D19(1.5,13.5) D20(2.5,13.5) D21(3.5,13.5) D22(4.5,13.5) D23(5.5,13.5) D24(6.5,13.5) D25(7.5,13.5) D26(8.5,13.5) D27(9.5,13.5) D28(10.5,13.5) D29(11.5,13.5) D30(12.5,13.5) D31(13.5,13.5) D32(14.5,13.5) D33(15.5,13.5) D34(16.5,13.5) E1(-16.5,12.5) E2(-15.5,12.5) E3(-14.5,12.5) E4(-13.5,12.5) E5(-12.5,12.5) E6(-11.5,12.5) E7(-10.5,12.5) E8(-9.5,12.5) E9(-8.5,12.5) E10(-7.5,12.5) E11(-6.5,12.5) E12(-5.5,12.5) E13(-4.5,12.5) E14(-3.5,12.5) E15(-2.5,12.5) E16(-1.5,12.5) E17(-0.5,12.5) E18(0.5,12.5) E19(1.5,12.5) E20(2.5,12.5) E21(3.5,12.5) E22(4.5,12.5) E23(5.5,12.5) E24(6.5,12.5) E25(7.5,12.5) E26(8.5,12.5) E27(9.5,12.5) E28(10.5,12.5) E29(11.5,12.5) E30(12.5,12.5) E31(13.5,12.5) E32(14.5,12.5) E33(15.5,12.5) E34(16.5,12.5) F1(-16.5,11.5) F2(-15.5,11.5) F3(-14.5,11.5) F4(-13.5,11.5) F5(-12.5,11.5) F6(-11.5,11.5) F7(-10.5,11.5) F8(-9.5,11.5) F9(-8.5,11.5) F10(-7.5,11.5) F11(-6.5,11.5) F12(-5.5,11.5) F13(-4.5,11.5) F14(-3.5,11.5) F15(-2.5,11.5) F16(-1.5,11.5) F17(-0.5,11.5) F18(0.5,11.5) F19(1.5,11.5) F20(2.5,11.5) F21(3.5,11.5) F22(4.5,11.5) F23(5.5,11.5) F24(6.5,11.5) F25(7.5,11.5) F26(8.5,11.5) F27(9.5,11.5) F28(10.5,11.5) F29(11.5,11.5) F30(12.5,11.5) F31(13.5,11.5) F32(14.5,11.5) F33(15.5,11.5) F34(16.5,11.5) G1(-16.5,10.5) G2(-15.5,10.5) G3(-14.5,10.5) G4(-13.5,10.5) G5(-12.5,10.5) G6(-11.5,10.5) G7(-10.5,10.5) G8(-9.5,10.5) G9(-8.5,10.5) G10(-7.5,10.5) G11(-6.5,10.5) G12(-5.5,10.5) G13(-4.5,10.5) G14(-3.5,10.5) G15(-2.5,10.5) G16(-1.5,10.5) G17(-0.5,10.5) G18(0.5,10.5) G19(1.5,10.5) G20(2.5,10.5) G21(3.5,10.5) G22(4.5,10.5) G23(5.5,10.5) G24(6.5,10.5) G25(7.5,10.5) G26(8.5,10.5) G27(9.5,10.5) G28(10.5,10.5) G29(11.5,10.5) G30(12.5,10.5) G31(13.5,10.5) G32(14.5,10.5) G33(15.5,10.5) G34(16.5,10.5) H1(-16.5,9.5) H2(-15.5,9.5) H3(-14.5,9.5) H4(-13.5,9.5) H5(-12.5,9.5) H6(-11.5,9.5) H7(-10.5,9.5) H8(-9.5,9.5) H9(-8.5,9.5) H10(-7.5,9.5) H11(-6.5,9.5) H12(-5.5,9.5) H13(-4.5,9.5) H14(-3.5,9.5) H15(-2.5,9.5) H16(-1.5,9.5) H17(-0.5,9.5) H18(0.5,9.5) H19(1.5,9.5) H20(2.5,9.5) H21(3.5,9.5) H22(4.5,9.5) H23(5.5,9.5) H24(6.5,9.5) H25(7.5,9.5) H26(8.5,9.5) H27(9.5,9.5) H28(10.5,9.5) H29(11.5,9.5) H30(12.5,9.5) H31(13.5,9.5) H32(14.5,9.5) H33(15.5,9.5) H34(16.5,9.5) J1(-16.5,8.5) J2(-15.5,8.5) J3(-14.5,8.5) J4(-13.5,8.5) J5(-12.5,8.5) J6(-11.5,8.5) J7(-10.5,8.5) J8(-9.5,8.5) J9(-8.5,8.5) J10(-7.5,8.5) J11(-6.5,8.5) J12(-5.5,8.5) J13(-4.5,8.5) J14(-3.5,8.5) J15(-2.5,8.5) J16(-1.5,8.5) J17(-0.5,8.5) J18(0.5,8.5) J19(1.5,8.5) J20(2.5,8.5) J21(3.5,8.5) J22(4.5,8.5) J23(5.5,8.5) J24(6.5,8.5) J25(7.5,8.5) J26(8.5,8.5) J27(9.5,8.5) J28(10.5,8.5) J29(11.5,8.5) J30(12.5,8.5) J31(13.5,8.5) J32(14.5,8.5) J33(15.5,8.5) J34(16.5,8.5) K1(-16.5,7.5) K2(-15.5,7.5) K3(-14.5,7.5) K4(-13.5,7.5) K5(-12.5,7.5) K6(-11.5,7.5) K7(-10.5,7.5) K8(-9.5,7.5) K9(-8.5,7.5) K10(-7.5,7.5) K11(-6.5,7.5) K12(-5.5,7.5) K13(-4.5,7.5) K14(-3.5,7.5) K15(-2.5,7.5) K16(-1.5,7.5) K17(-0.5,7.5) K18(0.5,7.5) K19(1.5,7.5) K20(2.5,7.5) K21(3.5,7.5) K22(4.5,7.5) K23(5.5,7.5) K24(6.5,7.5) K25(7.5,7.5) K26(8.5,7.5) K27(9.5,7.5) K28(10.5,7.5) K29(11.5,7.5) K30(12.5,7.5) K31(13.5,7.5) K32(14.5,7.5) K33(15.5,7.5) K34(16.5,7.5) L1(-16.5,6.5) L2(-15.5,6.5) L3(-14.5,6.5) L4(-13.5,6.5) L5(-12.5,6.5) L6(-11.5,6.5) L7(-10.5,6.5) L8(-9.5,6.5) L9(-8.5,6.5) L10(-7.5,6.5) L11(-6.5,6.5) L12(-5.5,6.5) L13(-4.5,6.5) L14(-3.5,6.5) L15(-2.5,6.5) L16(-1.5,6.5) L17(-0.5,6.5) L18(0.5,6.5) L19(1.5,6.5) L20(2.5,6.5) L21(3.5,6.5) L22(4.5,6.5) L23(5.5,6.5) L24(6.5,6.5) L25(7.5,6.5) L26(8.5,6.5) L27(9.5,6.5) L28(10.5,6.5) L29(11.5,6.5) L30(12.5,6.5) L31(13.5,6.5) L32(14.5,6.5) L33(15.5,6.5) L34(16.5,6.5) M1(-16.5,5.5) M2(-15.5,5.5) M3(-14.5,5.5) M4(-13.5,5.5) M5(-12.5,5.5) M6(-11.5,5.5) M7(-10.5,5.5) M8(-9.5,5.5) M9(-8.5,5.5) M10(-7.5,5.5) M11(-6.5,5.5) M12(-5.5,5.5) M13(-4.5,5.5) M14(-3.5,5.5) M15(-2.5,5.5) M16(-1.5,5.5) M17(-0.5,5.5) M18(0.5,5.5) M19(1.5,5.5) M20(2.5,5.5) M21(3.5,5.5) M22(4.5,5.5) M23(5.5,5.5) M24(6.5,5.5) M25(7.5,5.5) M26(8.5,5.5) M27(9.5,5.5) M28(10.5,5.5) M29(11.5,5.5) M30(12.5,5.5) M31(13.5,5.5) M32(14.5,5.5) M33(15.5,5.5) M34(16.5,5.5) N1(-16.5,4.5) N2(-15.5,4.5) N3(-14.5,4.5) N4(-13.5,4.5) N5(-12.5,4.5) N6(-11.5,4.5) N7(-10.5,4.5) N8(-9.5,4.5) N9(-8.5,4.5) N10(-7.5,4.5) N11(-6.5,4.5) N12(-5.5,4.5) N13(-4.5,4.5) N14(-3.5,4.5) N15(-2.5,4.5) N16(-1.5,4.5) N17(-0.5,4.5) N18(0.5,4.5) N19(1.5,4.5) N20(2.5,4.5) N21(3.5,4.5) N22(4.5,4.5) N23(5.5,4.5) N24(6.5,4.5) N25(7.5,4.5) N26(8.5,4.5) N27(9.5,4.5) N28(10.5,4.5) N29(11.5,4.5) N30(12.5,4.5) N31(13.5,4.5) N32(14.5,4.5) N33(15.5,4.5) N34(16.5,4.5) P1(-16.5,3.5) P2(-15.5,3.5) P3(-14.5,3.5) P4(-13.5,3.5) P5(-12.5,3.5) P6(-11.5,3.5) P7(-10.5,3.5) P8(-9.5,3.5) P9(-8.5,3.5) P10(-7.5,3.5) P11(-6.5,3.5) P12(-5.5,3.5) P13(-4.5,3.5) P14(-3.5,3.5) P15(-2.5,3.5) P16(-1.5,3.5) P17(-0.5,3.5) P18(0.5,3.5) P19(1.5,3.5) P20(2.5,3.5) P21(3.5,3.5) P22(4.5,3.5) P23(5.5,3.5) P24(6.5,3.5) P25(7.5,3.5) P26(8.5,3.5) P27(9.5,3.5) P28(10.5,3.5) P29(11.5,3.5) P30(12.5,3.5) P31(13.5,3.5) P32(14.5,3.5) P33(15.5,3.5) P34(16.5,3.5) R1(-16.5,2.5) R2(-15.5,2.5) R3(-14.5,2.5) R4(-13.5,2.5) R5(-12.5,2.5) R6(-11.5,2.5) R7(-10.5,2.5) R8(-9.5,2.5) R9(-8.5,2.5) R10(-7.5,2.5) R11(-6.5,2.5) R12(-5.5,2.5) R13(-4.5,2.5) R14(-3.5,2.5) R15(-2.5,2.5) R16(-1.5,2.5) R17(-0.5,2.5) R18(0.5,2.5) R19(1.5,2.5) R20(2.5,2.5) R21(3.5,2.5) R22(4.5,2.5) R23(5.5,2.5) R24(6.5,2.5) R25(7.5,2.5) R26(8.5,2.5) R27(9.5,2.5) R28(10.5,2.5) R29(11.5,2.5) R30(12.5,2.5) R31(13.5,2.5) R32(14.5,2.5) R33(15.5,2.5) R34(16.5,2.5) T1(-16.5,1.5) T2(-15.5,1.5) T3(-14.5,1.5) T4(-13.5,1.5) T5(-12.5,1.5) T6(-11.5,1.5) T7(-10.5,1.5) T8(-9.5,1.5) T9(-8.5,1.5) T10(-7.5,1.5) T11(-6.5,1.5) T12(-5.5,1.5) T13(-4.5,1.5) T14(-3.5,1.5) T15(-2.5,1.5) T16(-1.5,1.5) T17(-0.5,1.5) T18(0.5,1.5) T19(1.5,1.5) T20(2.5,1.5) T21(3.5,1.5) T22(4.5,1.5) T23(5.5,1.5) T24(6.5,1.5) T25(7.5,1.5) T26(8.5,1.5) T27(9.5,1.5) T28(10.5,1.5) T29(11.5,1.5) T30(12.5,1.5) T31(13.5,1.5) T32(14.5,1.5) T33(15.5,1.5) T34(16.5,1.5) U1(-16.5,0.5) U2(-15.5,0.5) U3(-14.5,0.5) U4(-13.5,0.5) U5(-12.5,0.5) U6(-11.5,0.5) U7(-10.5,0.5) U8(-9.5,0.5) U9(-8.5,0.5) U10(-7.5,0.5) U11(-6.5,0.5) U12(-5.5,0.5) U13(-4.5,0.5) U14(-3.5,0.5) U15(-2.5,0.5) U16(-1.5,0.5) U17(-0.5,0.5) U18(0.5,0.5) U19(1.5,0.5) U20(2.5,0.5) U21(3.5,0.5) U22(4.5,0.5) U23(5.5,0.5) U24(6.5,0.5) U25(7.5,0.5) U26(8.5,0.5) U27(9.5,0.5) U28(10.5,0.5) U29(11.5,0.5) U30(12.5,0.5) U31(13.5,0.5) U32(14.5,0.5) U33(15.5,0.5) U34(16.5,0.5) V1(-16.5,-0.5) V2(-15.5,-0.5) V3(-14.5,-0.5) V4(-13.5,-0.5) V5(-12.5,-0.5) V6(-11.5,-0.5) V7(-10.5,-0.5) V8(-9.5,-0.5) V9(-8.5,-0.5) V10(-7.5,-0.5) V11(-6.5,-0.5) V12(-5.5,-0.5) V13(-4.5,-0.5) V14(-3.5,-0.5) V15(-2.5,-0.5) V16(-1.5,-0.5) V17(-0.5,-0.5) V18(0.5,-0.5) V19(1.5,-0.5) V20(2.5,-0.5) V21(3.5,-0.5) V22(4.5,-0.5) V23(5.5,-0.5) V24(6.5,-0.5) V25(7.5,-0.5) V26(8.5,-0.5) V27(9.5,-0.5) V28(10.5,-0.5) V29(11.5,-0.5) V30(12.5,-0.5) V31(13.5,-0.5) V32(14.5,-0.5) V33(15.5,-0.5) V34(16.5,-0.5) W1(-16.5,-1.5) W2(-15.5,-1.5) W3(-14.5,-1.5) W4(-13.5,-1.5) W5(-12.5,-1.5) W6(-11.5,-1.5) W7(-10.5,-1.5) W8(-9.5,-1.5) W9(-8.5,-1.5) W10(-7.5,-1.5) W11(-6.5,-1.5) W12(-5.5,-1.5) W13(-4.5,-1.5) W14(-3.5,-1.5) W15(-2.5,-1.5) W16(-1.5,-1.5) W17(-0.5,-1.5) W18(0.5,-1.5) W19(1.5,-1.5) W20(2.5,-1.5) W21(3.5,-1.5) W22(4.5,-1.5) W23(5.5,-1.5) W24(6.5,-1.5) W25(7.5,-1.5) W26(8.5,-1.5) W27(9.5,-1.5) W28(10.5,-1.5) W29(11.5,-1.5) W30(12.5,-1.5) W31(13.5,-1.5) W32(14.5,-1.5) W33(15.5,-1.5) W34(16.5,-1.5) Y1(-16.5,-2.5) Y2(-15.5,-2.5) Y3(-14.5,-2.5) Y4(-13.5,-2.5) Y5(-12.5,-2.5) Y6(-11.5,-2.5) Y7(-10.5,-2.5) Y8(-9.5,-2.5) Y9(-8.5,-2.5) Y10(-7.5,-2.5) Y11(-6.5,-2.5) Y12(-5.5,-2.5) Y13(-4.5,-2.5) Y14(-3.5,-2.5) Y15(-2.5,-2.5) Y16(-1.5,-2.5) Y17(-0.5,-2.5) Y18(0.5,-2.5) Y19(1.5,-2.5) Y20(2.5,-2.5) Y21(3.5,-2.5) Y22(4.5,-2.5) Y23(5.5,-2.5) Y24(6.5,-2.5) Y25(7.5,-2.5) Y26(8.5,-2.5) Y27(9.5,-2.5) Y28(10.5,-2.5) Y29(11.5,-2.5) Y30(12.5,-2.5) Y31(13.5,-2.5) Y32(14.5,-2.5) Y33(15.5,-2.5) Y34(16.5,-2.5)
  silkscreen extent -18.1,-17.5 17.5,17.5, body extent -17.5,-17.48 17.5,17.5, height 2.92
FUDICIAL [mm]
  round 1.27 smd paste-2539.97: FUDICIAL(0,0)
L0805 [mil]
  rect 35x55 smd: 1(-37,0) 2(37,0)
  silkscreen extent -69,-40 69,40, body extent -70,-40 70,40, height 18
LED_0603 [mm]
  rect 0.8x0.8 smd: 1(0.75,0) 2(-0.75,0)
  silkscreen extent -1.63,-0.72 1.62,0.73, body extent -1.65,-0.76 1.65,0.76, height 0.65
LVK12 [mm]
  rect 1.75x1.1 smd: 1(-1.375,0.7) 2(-1.375,-0.7) 3(1.375,-0.7) 4(1.375,0.7)
  silkscreen extent -2.95,-1.55 2.55,1.55, body extent -2.62,-1.55 2.49,1.52, height 0.65
MH_2P3_4MM [mm]
  round 4 hole 2.3 unplated: 1(0,0)
"MH_2p3_NPTH _keepout" [mm]
  round 2.3 hole 2.3 unplated: 1(0,0)
  Keep-Out Layer circle w0.203: c0,0 r2
MINI_TESTPOINT [mil]
  round 25 hole 15: 1(0,0)
  silkscreen extent -21,-21 21,21, body extent -20,-20 20,20, height 43
MINI_TESTPOINT_SMD [mil]
  round 30 smd: 1(0,0)
  silkscreen extent -21,-21 21,21, body extent -20,-20 20,20, height 43
"MT25QU02GABA - BGA" [mil]
  round 18 smd: A2(-39.37,78.74) A3(0,78.74) A4(39.37,78.74) A5(78.74,78.74) B1(-78.74,39.37) B2(-39.37,39.37) B3(0,39.37) B4(39.37,39.37) B5(78.74,39.37) C1(-78.74,0) C2(-39.37,0) C3(0,0) C4(39.37,0) C5(78.74,0) D1(-78.74,-39.37) D2(-39.37,-39.37) D3(0,-39.37) D4(39.37,-39.37) D5(78.74,-39.37) E1(-78.74,-78.74) E2(-39.37,-78.74) E3(0,-78.74) E4(39.37,-78.74) E5(78.74,-78.74)
  silkscreen extent -141,-157 118,157, body extent -120,-160 120,157, height 43
QFN20_RGB_4P15X4P15X1_TEX [mm]
  rect 0.95x0.23 smd mask+0.064: 1(-1.9,1) 2(-1.9,0.5) 3(-1.9,0) 4(-1.9,-0.5) 5(-1.9,-1) 11(1.9,-1) 12(1.9,-0.5) 13(1.9,0) 14(1.9,0.5) 15(1.9,1)
  rect 0.23x0.95 smd mask+0.064: 6(-1,-1.9) 7(-0.5,-1.9) 8(0,-1.9) 9(0.5,-1.9) 10(1,-1.9) 16(1,1.9) 17(0.5,1.9) 18(0,1.9) 19(-0.5,1.9) 20(-1,1.9)
  rect 2.15x2.15 smd mask+0.102: 21(0,0)
  silkscreen extent -2.46,-2.08 2.08,2.08, body extent -2.72,-2.57 2.49,2.51, height 1
RN_0201 [mm]
  rect 0.3x0.3 smd mask+0.051: 1(-0.26,0) 2(0.26,0)
  silkscreen extent -0.58,-0.33 0.58,0.33, body extent -0.64,-0.38 0.64,0.38, height 0.25
RN_0402 [mil]
  rect 24x20 smd mask+2: 1(-18,0) 2(18,0)
  silkscreen extent -36,-18 36,18, body extent -35,-20 35,20, height 14
"SI5335A - QFN24" [mm]
  rect 0.8x0.25 smd mask+0.051: 1(-1.95,1.25) 2(-1.95,0.75) 3(-1.95,0.25) 4(-1.95,-0.25) 5(-1.95,-0.75) 6(-1.95,-1.25) 13(1.95,-1.25) 14(1.95,-0.75) 15(1.95,-0.25) 16(1.95,0.25) 17(1.95,0.75) 18(1.95,1.25)
  rect 0.25x0.8 smd mask+0.051: 7(-1.25,-1.95) 8(-0.75,-1.95) 9(-0.25,-1.95) 10(0.25,-1.95) 11(0.75,-1.95) 12(1.25,-1.95) 19(1.25,1.95) 20(0.75,1.95) 21(0.25,1.95) 22(-0.25,1.95) 23(-0.75,1.95) 24(-1.25,1.95)
  rect 2.55x2.55 smd paste-2539.97: 25(0,0)
  rect 1x1 on Top Paste: ""(-0.625,-0.625) ""(-0.625,0.625) ""(0.625,-0.625) ""(0.625,0.625)
  silkscreen extent -2.92,-2 2,2, body extent -2.67,-2.67 2.54,2.54, height 0.9
"SI53152 - QFN24" [mm]
  rect 0.8x0.3 smd mask+0.051: 1(-2,1.25) 2(-2,0.75) 3(-2,0.25) 4(-2,-0.25) 5(-2,-0.75) 6(-2,-1.25) 13(2,-1.25) 14(2,-0.75) 15(2,-0.25) 16(2,0.25) 17(2,0.75) 18(2,1.25)
  rect 0.3x0.8 smd mask+0.051: 7(-1.25,-2) 8(-0.75,-2) 9(-0.25,-2) 10(0.25,-2) 11(0.75,-2) 12(1.25,-2) 20(0.75,2) 21(0.25,2) 22(-0.25,2) 23(-0.75,2) 24(-1.25,2)
  rect 0.25x0.8 smd mask+0.051: 19(1.25,2)
  rect 2.7x2.7 smd paste-2539.97: 25(0,0)
  rect 1x1 on Top Paste: ""(-0.625,-0.625) ""(-0.625,0.625) ""(0.625,-0.625) ""(0.625,0.625)
  silkscreen extent -2.94,-2 2,2, body extent -2.41,-2.41 2.41,2.41, height 0.8
SW_PTS815_4P2X3P2X2P5 [mm]
  rect 1x0.7 smd: 1(-2.25,1.075) 2(2.25,1.075) 3(-2.25,-1.075) 4(2.25,-1.075)
  silkscreen extent -3.25,-1.6 2.13,1.6, body extent -3.02,-1.83 2.9,1.98, height 2.5
"TXS0104ERGYR - VQFN24" [mm]
  rect 0.28x0.85 smd: 1(-0.75,1.725) 7(-0.75,-1.725) 8(0.75,-1.725) 14(0.75,1.725)
  rect 0.85x0.28 smd: 2(-1.725,1) 3(-1.725,0.5) 4(-1.725,0) 5(-1.725,-0.5) 6(-1.725,-1) 9(1.725,-1) 10(1.725,-0.5) 11(1.725,0) 12(1.725,0.5) 13(1.725,1)
  rect 2.05x2.05 smd paste-2539.97: 15(0,0)
  rect 0.82x0.82 on Top Paste paste+0: ""(-0.56,0.56) ""(-0.56,-0.56) ""(0.56,0.56) ""(0.56,-0.56)
  silkscreen extent -1.83,-1.83 1.83,2.72, body extent -2.16,-2.16 2.22,2.16, height 1
VREG_SOT223-4_6P5X3P5X1P8 [mm]
  rect 2.15x0.95 smd: 1(-2.9,2.3) 2(-2.9,0) 3(-2.9,-2.3)
  rect 2.15x3.25 smd: 4(2.9,0)
  silkscreen extent -3.55,-3.25 1.75,3.4, body extent -4.34,-3.61 4.27,3.86, height 1.8

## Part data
C91 C93 C95 C97 C99 C101 C103 C105 C107 C109 C111 C113 C117 C121 C125 C129 C131 C133 C135 C137 C324 C325 C800: library part CAP, "CAP CER 47UF 10V X5R 0805", Manufacturer="Murata Electronics", Manufacturer Part Number=GRM21BR61A476ME15K
C92 C94 C96 C98 C100 C102 C104 C106 C108 C110 C112 C114 C118 C130 C132 C134 C136 C138 C139 C142 C145 C148 C151 C154 C157 C160 C163 C166 C169 C172 C175 C178 C213 C216 C801: library part CAP, "CAP CER 10UF 10V X5R 0402", Manufacturer="Murata Electronics", Manufacturer Part Number=GRM155R61A106ME11D
C115: library part CAP, "CAP CER 220UF 6.3V X5R 1206", Manufacturer="Murata Electronics", Manufacturer Part Number=GRM31CR60J227ME11K
C116 C119 C120 C124 C236 C237 C238: library part CAP, "CAP CER 100UF 10V X5R 1206", Manufacturer="Murata Electronics", Manufacturer Part Number=GRM31CR61A107MEA8L
C122 C126 C141 C144 C147 C150 C153 C156 C159 C162 C165 C168 C171 C174 C177 C180 C215 C218: library part CAP, "0.01 µF, 25 V, 0402 [1005 Metric], ± 10%, X7R", Manufacturer=YAGEO, Manufacturer Part Number=CC0402JRX7R8BB103
C123: library part CAP, "CAP CER 330UF 6.3V X5R 1210 20%", Manufacturer="TAIYO YUDEN", Manufacturer Part Number=JMK325ABJ337MM-PE
C140 C143 C146 C149 C152 C155 C158 C161 C164 C167 C170 C173 C176 C179 C203 C204 C205 C206 C207 C208 C209 C210 C211 C212 C214 C217 C231 C232 C234 C235 C321 C322 C323 C546: library part CAP, "CAP CER 0.1UF 50V X7R 0402", Manufacturer="Murata Electronics", Manufacturer Part Number=GCM155R71H104KE02J
C183 C184 C191 C192 C195 C196 C199 C200 C229 C230: library part CAP, "CAP CER 0.22UF 25V X5R 0201", Manufacturer="Murata Electronics", Manufacturer Part Number=GRM033R61E224KE01D
C219 C220: library part CAP, "CAP CER 18PF 50V C0G/NP0 0402", Manufacturer="Murata Electronics", Manufacturer Part Number=GJM1555C1H180GB01D
C225 C226 C227 C228 C259 C260: library part CAP, "CAP CER 0.22UF 50V X5R 0402", Manufacturer="Murata Electronics", Manufacturer Part Number=GRM155R61H224KE01W
C233: library part CAP, "CAP CER 1UF 25V X5R 0402", Manufacturer="TDK CORPORATION", Manufacturer Part Number=C1005X5R1E105K050BC
C317 C318: library part CAP, "CAP CER 47UF 10V X6S 1210", Manufacturer="Murata Electronics", Manufacturer Part Number=GRT32EC81A476KE13L
C500 C501 C502 C503 C504 C505 C506 C507: library part CAP, "CAP CER 100UF 16V X5R 1210", Manufacturer="KYOCERA AVX", Manufacturer Part Number=1210YD107MAT2A
C508 C509 C516 C517 C526 C527 C536 C537: library part CAP, "CAP CER 22UF 25V X5R 1210", Manufacturer="Samsung Electro-Mechanics", Manufacturer Part Number=CL32A226KAJNNNE
C510 C542: library part CAP, "CAP CER 8200PF 25V X7R 0402", Manufacturer=KEMET, Manufacturer Part Number=C0402C822J3RACTU
C511: library part CAP, "CAP CER 4.7UF 25V X5S 0402", Manufacturer="Murata Electronics", Manufacturer Part Number=GRM155C61E475ME15J
C512 C513 C514 C515 C522 C523 C524 C525 C532 C533 C534 C535: library part CAP, "CAP CER 47UF 25V X5R 1210", Manufacturer="KYOCERA AVX", Manufacturer Part Number=KGM32LR51E476MU
C518 C520 C528 C529 C530 C531 C538 C540: library part CAP, "CAP CER 0402 15NF 50V X7R 5%", Manufacturer=KEMET, Manufacturer Part Number=C0402C153J5RECTU
C543: library part CAP, "CAP CER 5600PF 50V X7R 0402", Manufacturer=KEMET, Manufacturer Part Number=C0402C562K5RACTU
C544: library part CAP, "CAP CER 3900PF 50V X7R 0402", Manufacturer="KYOCERA AVX", Manufacturer Part Number=KGM05AR71H392JH
C545: library part CAP, "CAP CER 1800PF 50V U2J 0402", Manufacturer=KEMET, Manufacturer Part Number=C0402C182J5JACTU
C547 C548: library part CAP_POLAR, "10 µF ±10% 16V Ceramic Capacitor X5R 0805 (2012 Metric)", Manufacturer="Samsung Electro-Mechanics", Manufacturer Part Number=CL21A106KOQNNNE
CS1 CS2 CS3 CS4 CS5 CS6 CS7 CS8 CS9 CS12 CS13 CS14 CS15 CS16 CS17 CS18 CS23 CS24 CS25 CS26 CS27 CS33 CS34 CS35 CS36 CS37 CS38 CS41 CS42 CS43 CS45 CS46 CS47 CS48 CS49 CS50 CS53 CS54 CS55 CS56 CS57 CS58 CS59 CS60 CS61 CS62 CS63 CS67 CS68 CS71 CS72 CS73 CS74 CS75 CS76 CS77 CS78 CS79 CS80 CS83 CS84 CS85 CS86 CS87 CS88 CS91 CS92 CS93 CS94 CS95 CS96 CS97 CS98 CS99 CS100 CS101 CS102 CS104 CS106 CS107 CS108 CS109 CX1 CX2 CX3 CX4 CX6 CX7 CX8 CX9 CX10 CX12 CX13 CX14 CX15 CX16 CX17 CX18 CX19: library part CAP, "CAP CER 0.1UF 35V X5R 0201", Manufacturer="Murata Electronics", Manufacturer Part Number=GRM033R6YA104KE14D
D1: library part BAS40, "DIODE SCHOTTKY 40V 200MA SOD523", Manufacturer="Micro Commercial Co", Manufacturer Part Number=BAS40X-TP, Power Dissipation=500mW
D2 D4 D5 D6 D7 D8 D9: "LED GREEN CLEAR SMD", Manufacturer="Lite-On Inc.", Manufacturer Part Number=LTST-C191KGKT
D10 D11 D12 D13 D14: "DIODE ZENER 5.1V 200MW SOD523", Manufacturer="Micro Commercial Co", Manufacturer Part Number=BZT52C5V1T-TP, Power Dissipation=500mW
E#0 E#4 G0_A0 G0_A0_0 G0_A1 G0_A1_0 G0_CR# G0_G# G0_W# G0_W#_0 G1_A0 G1_A1 G1_CR# G1_G# G1_W# MEM0_0 MEM0_RST MEM1_0 MEM2_0 MEM3_0 MEM4_0 MEM5_0 MEM6_0 MEM7_0: library part TEST_POINT, "Tap_point 15X25"
FB1 FB2 FB3 FB4 FB5 FB6: library part INDUCTOR, "FERRITE BEAD 110 OHM 0805 1LN", Manufacturer="Murata Electronics", Manufacturer Part Number=BLM21SP111SZ1D
J4 J5: "CONN FPC BOTTOM 10POS 1MM R/A", Manufacturer="Würth Elektronik", Manufacturer Part Number=68611014422
K1: library part "SW PUSH-S_2", "SWITCH TACTILE SPST-NO 0.05A 12V", Manufacturer=C&K, Manufacturer Part Number="PTS815 SJK 250 SMTR LFS"
L7 L8: library part INDUCTOR, "WE-TMSB SMT EMI SUPPRESSION FERR", Manufacturer="Würth Elektronik", Manufacturer Part Number=74269262601
LED100: library part LED, "LED GREEN CLEAR SMD", Manufacturer="Lite-On Inc.", Manufacturer Part Number=LTST-C191KGKT
LVK12 RT5 RT6 RT7 RT8 RT9 RT10 RT15 RT16 RT801: library part LVK24, "RES 0.012OHM 1% 1/2W 1206", Manufacturer=OHMITE, Manufacturer Part Number=LVK12
MTH1 MTH2 MTH3 MTH4: library part FUDICIAL
PCIE_CONN: library part PCIE_CON, "SAS/PCIE 4.0 (U.2 & U.3) CONNECT", Manufacturer="Amphenol ICC (FCI)"
R1 R2 R22 R71 R72 R73 R74 R123 R124 R125 R126 R127 R128 R129 R130 R131 R140 R143 R271 R272 R273 R274 R534 R536 R538 R540 R544 R546 R548 R550 R602 R641: library part RES, "RES 1K OHM 1% 1/16W 0402", Manufacturer=YAGEO, Manufacturer Part Number=RC0402FR-131KL
R3 R4 R6 R7 R65 R70 R75 R76 R77 R78 R79 R80 R81 R82 R83 R84 R85 R86 R87 R88 R89 R90 R91 R92 R93 R94 R95 R96 R97 R98 R116 R117 R118 R119 R120 R121 R134 R135 R139 R141 R152 R153 R154 R155 R156 R157 R158 R159 R636 R638 R640 R700 R701 R702 R703 R704 R705 R706 R707 R740: library part RES, "RES 4.7K OHM 1% 1/16W 0402", Manufacturer=YAGEO, Manufacturer Part Number=RC0402FR-134K7L
R5 R142: library part RES, "RES 2.4K OHM 1% 1/16W 0402", Manufacturer=YAGEO, Manufacturer Part Number=RC0402FR-072K4L
R11 R25 R66 R67 R68 R69 R114 R115 R122 R144 R145 R146 R147 R148 R149 R634 R800: library part RES, "RES 0 OHM JUMPER 1/16W 0402", Manufacturer=YAGEO, Manufacturer Part Number=RC0402FR-070RL
R21 R132 R136 R137 R533 R535 R537 R539 R541 R545 R547 R549 R743: library part RES, "RES 100 OHM 1% 1/16W 0402", Manufacturer=YAGEO, Manufacturer Part Number=RC0402FR-07100RL
R107 R111 R112 R113: library part RES, "RES 1.5K OHM 1% 1/16W 0402", Manufacturer=YAGEO, Manufacturer Part Number=RC0402FR-131K5L
R109: library part RES, "RES 10.2K OHM 1% 1/16W 0402", Manufacturer=YAGEO, Manufacturer Part Number=RC0402FR-0710K2L
R110 R138: library part RES, "RES 150 OHM 1% 1/16W 0402", Manufacturer=YAGEO, Manufacturer Part Number=RC0402FR-07150RL
R133 R526 R527 R528 R529 R530 R531 R543 R603 R650 R710 R724 R750: library part RES, "RES 10K OHM 1% 1/16W 0402", Manufacturer=YAGEO, Manufacturer Part Number=RC0402FR-0710KL
R150 R151 R234 R235 R240 R601 R605 R607 R609 R611 R613 R615 R617 R619 R653 R654 R655 R656 RT: library part RES, "RES 0 OHM JUMPER 1/16W 0402", Manufacturer=YAGEO, Manufacturer Part Number=RC0402FR-070RL_DNI
R275 R276: library part RES, "RES 1K OHM 1% 1/20W 0201", Manufacturer=YAGEO, Manufacturer Part Number=RC0201FR-131KL
R500: library part RES, "RES 130K OHM 1% 1/16W 0402", Manufacturer=YAGEO, Manufacturer Part Number=RC0402FR-07130KL
R501 R514: library part RES, "RES 143K OHM 1% 1/16W 0402", Manufacturer=YAGEO, Manufacturer Part Number=RC0402FR-07143KL
R502: library part RES, "RES 8.66K OHM 1% 1/16W 0402", Manufacturer=YAGEO, Manufacturer Part Number=RC0402FR-078K66L
R504 R522 R524: library part RES, "RES SMD 15K OHM 0.1% 1/16W 0402", Manufacturer=YAGEO, Manufacturer Part Number=RT0402BRD0715KL
R506 R507 R508 R509 R510 R511 R512 R513 R518 R519 R520 R521 R532 R631 R632 R639: library part RES, "RES 100K OHM 1% 1/16W 0402", Manufacturer=YAGEO, Manufacturer Part Number=RC0402FR-07100KL
R515: library part RES, "RES 120K OHM 1% 1/16W 0402", Manufacturer=YAGEO, Manufacturer Part Number=RC0402FR-07120KL
R516: library part RES, "RES 30.1K OHM 1% 1/16W 0402", Manufacturer=YAGEO, Manufacturer Part Number=RC0402FR-0730K1L
R517: library part RES, "RES 60.4K OHM 1% 1/16W 0402", Manufacturer=YAGEO, Manufacturer Part Number=RC0402FR-0760K4L
R542: library part RES, "RES 14K OHM 1% 1/16W 0402", Manufacturer=YAGEO, Manufacturer Part Number=RC0402FR-0714KL
R600 R604 R606 R608 R610 R612 R614 R616 R618 R633 R635 R637 R652: library part RES, "RES 0 OHM JUMPER 1/16W 0402", Manufacturer=YAGEO, Manufacturer Part Number=RC0402JR-070RL
TP1 TP2 TP3 TP4 TP5 TP6 TP7 TP8 TP9 TP10 TP11 TP12 TP13 TP14 TP15 TP16 TP17 TP18 TP701 TP702 TP703 TP705 TP706 TP707 TP708 TP709 TP711 TP713 TP714 TP716 TP717 TP718 TP720 TP802 TP803: "Tap_point 15X25"
U1: "IC FPGA 516 I/O 1156FCBGA", Manufacturer=AMD, Manufacturer Part Number=XCKU15P-1FFVA1156E
U2 U3 U4 U5 U6 U7 U8 U9: "IC 142-MRAM MEMORY", Manufacturer="Avalanche Technology"
U10: "IC FLASH 256MBIT SPI 24TPBGA", Manufacturer="Micron Technology Inc.", Manufacturer Part Number=MT25QU256ABA8E12-0AAT
U18: "IC CLOCK GENERATOR 24QFN", Manufacturer="Skyworks Solutions Inc.", Manufacturer Part Number=SI5335A-B02436-GM
U19: "IC EEPROM 2KBIT I2C SOT23-6", Manufacturer="Microchip Technology", Manufacturer Part Number=24AA025UIDT-I/OT
U21: "IC TRANSLTR BIDIRECTIONAL 14VQFN", Manufacturer="Texas Instruments"
U22: "IC PCIE BUFFER 100MHZ 1IN 2OUT", Manufacturer="Skyworks Solutions Inc.", Manufacturer Part Number=SI53152-A01AGM
U95: "IC SUPERVISOR 4 CHANNEL 20QF", Manufacturer="Texas Instruments"
U96 U97 U98: library part LTM4644IY-1#PBF_2908, "DC DC CONVERTER 4X0.6-5.5V", Manufacturer="Analog Devices Inc."
U99: "DC DC CONVERTER 0.6V TO 1.8V", Manufacturer="ANALOG DEVICES INC", Manufacturer Part Number=LTM4631EV#PBF
U100: library part REG, "IC REG LINEAR 5V 500MA SOT223-4", Manufacturer="Texas Instruments"
X1: library part CRYSTAL, "CRYSTAL 25.0000MHZ 18PF SMD", Manufacturer="Abracon LLC"

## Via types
v1: diameter 0.381, hole 0.152, Top Layer to Bottom Layer, tented both sides, 2009 vias
v2: diameter 0.508, hole 0.254, Top Layer to Bottom Layer, tented both sides, 467 vias
v3: diameter 0.406, hole 0.203, Top Layer to Bottom Layer, 458 vias
v4: diameter 0.508, hole 0.254, Top Layer to Bottom Layer, 239 vias
v5: diameter 0.406, hole 0.203, Top Layer to Bottom Layer, tented both sides, 181 vias
v6: diameter 0.381, hole 0.152, Top Layer to GND4, tented both sides, 147 vias
v7: diameter 0.406, hole 0.203, Top Layer to GND4, tented both sides, 10 vias

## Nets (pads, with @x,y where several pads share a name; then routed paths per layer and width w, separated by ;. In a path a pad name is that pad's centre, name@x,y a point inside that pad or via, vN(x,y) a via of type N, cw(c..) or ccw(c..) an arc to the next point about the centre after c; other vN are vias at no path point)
5V: C546.2 C548.2 D10.2 R526.2 R527.2 R528.2 R529.2 R530.2 R531.2 R542.2 R543.1 R641.1 U95.14 U100.2 U100.4 | length 9.3
  Top Layer w0.203: U95.14@80.767,1.389 82.044,1.389 82.544,0.889 v4(82.544,0.4)
  Top Layer w0.381: U100.4@71.247,8.869 72.39,10.012 R641.1@72.39,10.719 ; R526.2@74.606,2.651 74.701,2.746 v4(74.701,3.531) ; R531.2@74.701,1.603 R526.2@74.701,2.651 ; v3(76.022,4.318) R527.2@76.759,4.318 ; R528.2@78.842,4.317 v3(78.842,4.775) ; R529.2@80.899,5.156 v4(80.899,5.715)
  Top Layer w0.508: R530.2@83.642,1.905 v4(84.404,1.905)
  other v4: 69.977,-1.219 70.587,-1.219 71.222,-1.219 69.977,-0.635 70.587,-0.635 71.222,-0.635
12V: C317.2 C318.2 C508.2 C509.2 C516.2 C517.2 C526.2 C527.2 C536.2 C537.2 C547.2 PCIE_CONN.P13 PCIE_CONN.P14 PCIE_CONN.P15 R109.2 R532.2 R543.2 R631.1 R632.2 R639.2 R710.2 R724.2 R750.2 U96.B3 U96.B4 U96.B5 U96.E3 U96.E4 U96.E5 U96.H3 U96.H4 U96.H5 U96.L3 U96.L4 U96.L5 U97.B3 U97.B4 U97.B5 U97.E3 U97.E4 U97.E5 U97.H3 U97.H4 U97.H5 U97.L3 U97.L4 U97.L5 U98.B3 U98.B4 U98.B5 U98.E3 U98.E4 U98.E5 U98.H3 U98.H4 U98.H5 U98.L3 U98.L4 U98.L5 U99.J2 U99.J3 U99.J4 U99.J9 U99.J10 U99.J11 U99.K2 U99.K3 U99.K4 U99.K9 U99.K10 U99.K11 U99.L2 U99.L3 U99.L4 U99.L5 U99.L6 U99.L7 U99.L8 U99.L9 U99.L10 U99.L11 U99.M2 U99.M3 U99.M4 U99.M5 U99.M6 U99.M7 U99.M8 U99.M9 U99.M10 U99.M11 U100.3 | length 68.9
  Top Layer w0.127: U98.L5@26.67,3.429 v3(26.67,4.005) ; U98.L4@26.67,4.699 v3(26.67,5.275) ; U98.L3@26.67,5.969 v3(26.67,6.545) ; U96.L5@50.292,3.429 v3(50.292,4.005) ; U96.L4@50.292,4.699 v3(50.292,5.275) ; U96.L3@50.292,5.969 v3(50.292,6.545) ; U97.L5@70.993,-14.732 71.501,-14.224 v3(71.561,-14.224) ; U97.L4@70.993,-13.462 71.389,-13.462 v3(71.569,-13.462) ; U97.L3@70.993,-12.192 v3(71.569,-12.192)
  Top Layer w0.203: R639.2@83.261,-1.143 R639.2@83.287,-1.168
  Top Layer w0.381: R710.2@33.401,-1.854 33.503,-1.956 v4(34.011,-1.956) ; R750.2@47.041,3.429 47.041,4.242 47.878,5.079 C536.2@47.878,5.588 ; R632.2@83.287,-2.311 83.769,-1.829 v4(83.896,-1.829) ; R639.2@83.287,-1.168 v4(83.998,-1.168)
  Top Layer w0.508: v3(30.48,2.853) U98.H5@30.48,3.429 v3(30.48,4.123) U98.H4@30.48,4.699 v3(30.48,5.393) U98.H3@30.48,5.969 ; U98.E5@34.29,3.429 v3(34.29,4.005) U98.E4@34.29,4.699 v3(34.29,5.275) U98.E3@34.29,5.969 v3(34.29,6.545) ; v3(37.541,3.429) U98.B5@38.1,3.429 v3(38.1,4.123) U98.B4@38.1,4.699 v3(38.1,5.393) U98.B3@38.1,5.969 ; v3(54.102,2.853) U96.H5@54.102,3.429 v3(54.102,4.123) U96.H4@54.102,4.699 v3(54.102,5.393) U96.H3@54.102,5.969 ; U96.E5@57.912,3.429 v3(57.912,4.005) U96.E4@57.912,4.699 v3(57.912,5.275) U96.E3@57.912,5.969 v3(57.912,6.545) ; v3(61.722,2.853) U96.B5@61.722,3.429 v3(61.722,4.123) U96.B4@61.722,4.699 v3(61.722,5.393) U96.B3@61.722,5.969 ; v3(74.803,-15.308) U97.H5@74.803,-14.732 v3(74.803,-14.038) U97.H4@74.803,-13.462 v3(74.803,-12.768) U97.H3@74.803,-12.192 ; U97.E5@78.613,-14.732 v3(78.613,-14.156) U97.E4@78.613,-13.462 v3(78.613,-12.886) U97.E3@78.613,-12.192 v3(78.613,-11.616) ; v4(79.248,-20.904) R724.2@79.248,-20.142 ; R631.1@80.67,-2.54 v4(81.229,-2.54) ; v3(82.423,-15.308) U97.B5@82.423,-14.732 v3(82.423,-14.038) U97.B4@82.423,-13.462 v3(82.423,-12.768) U97.B3@82.423,-12.192
  Bottom Layer w0.127: v3(5.283,7.493) U99.J2@5.918,6.858 ; v3(5.283,8.763) U99.K2@5.918,8.128 ; v3(5.283,10.033) U99.L2@5.918,9.398 ; v3(5.283,11.303) U99.M2@5.918,10.668 ; v3(6.553,7.493) U99.J3@7.188,6.858 ; v3(6.553,8.763) U99.K3@7.188,8.128 ; v3(6.553,10.033) U99.L3@7.188,9.398 ; v3(6.553,11.303) U99.M3@7.188,10.668 ; v3(7.823,7.493) U99.J4@8.458,6.858 ; v3(7.823,8.763) U99.K4@8.458,8.128 ; v3(7.823,10.033) U99.L4@8.458,9.398 ; v3(7.823,11.303) U99.M4@8.458,10.668 ; v3(9.093,10.033) U99.L5@9.728,9.398 ; v3(9.093,11.303) U99.M5@9.728,10.668 ; v3(10.363,10.033) U99.L6@10.998,9.398 ; v3(10.363,11.303) U99.M6@10.998,10.668 ; v3(11.633,10.033) U99.L7@12.268,9.398 ; v3(11.633,11.303) U99.M7@12.268,10.668 ; v3(12.903,10.033) U99.L8@13.538,9.398 ; v3(12.903,11.303) U99.M8@13.538,10.668 ; v3(14.173,10.033) U99.L9@14.808,9.398 ; v3(14.173,11.303) U99.M9@14.808,10.668 ; v3(15.443,7.493) U99.J10@16.078,6.858 ; v3(15.443,8.763) U99.K10@16.078,8.128 ; v3(15.443,10.033) U99.L10@16.078,9.398 ; v3(15.443,11.303) U99.M10@16.078,10.668 ; v3(16.713,7.493) U99.J11@17.348,6.858 ; v3(16.713,8.763) U99.K11@17.348,8.128 ; v3(16.713,10.033) U99.L11@17.348,9.398 ; v3(16.713,11.303) U99.M11@17.348,10.668
  Bottom Layer w0.381: U99.J9@14.808,6.858 v3(15.443,7.493) ; U99.K9@14.808,8.128 v3(15.443,8.763)
  Bottom Layer w0.508: v3(77.267,-1.854) 77.419,-2.007 R532.2@77.419,-2.54
  other v2: -0.483,-1.803 -2,-1.2 -1,-1.2 0,-1.2 -2.692,-0.66 -2,0 -1,0 0,0 -1.979,1.009 -0.979,1.009 0.021,1.009 -3.073,1.803 -1.981,1.829 -0.965,1.88 -3.785,2.286 -3.073,2.743 -1.981,2.769 -0.965,2.819 -4.202,3.048 -1.245,3.607 -4.202,4.064 -1.245,4.42 -0.635,4.496 0,4.572 -4.179,5.105 -1.245,5.232 -0.229,5.283 -3.625,5.563 -2.794,5.639 -4.191,6.096 -3.175,6.147 -2.413,6.147 -1.321,6.172 -0.305,6.223
  other v4: 70.129,-20.447 70.105,-19.685 70.104,-18.974 68.732,-11.354 69.52,-11.328 68.707,-10.795 69.494,-10.795 73.131,0 73.711,0 73.131,0.559 73.711,0.559 47.193,3.632 25.171,4.064 25.883,4.064 25.171,4.75 25.883,4.75 48.844,5.029 49.555,5.029 25.171,5.436 25.883,5.436 48.844,5.715 49.555,5.715 48.844,6.401 49.555,6.401 20.295,10.439 20.295,11.049 20.396,11.709 21.107,11.709 21.742,11.709 22.352,11.735
ACT_0: R111.2 U1.AG10 | length 33.3
  Top Layer w0.102: R111.2@9.349,-12.496 9.349,-11.936 v3(9.398,-11.887)
  INT5 w0.102: v3(9.398,-11.887) 9.398,-16.795 9.754,-17.15 9.754,-18.821 10.128,-19.196 11.424,-19.196 11.709,-19.482 13.329,-19.482 13.614,-19.196 24,-19.196 24.75,-18.446 34.125,-18.446 v1(34.5,-18.071)
ACT_1: R112.2 U1.AF10 | length 37.4
  Top Layer w0.102: v3(7.747,-11.836) 7.754,-11.843 R112.2@7.754,-12.496
  INT5 w0.102: v3(7.747,-11.836) 7.747,-16 8.382,-16.635 8.382,-20.676 8.788,-21.082 10.947,-21.082 11.227,-20.803 13.194,-20.803 13.462,-21.071 23.5,-21.071 25.875,-18.696 34.125,-18.696 v1(34.5,-19.071)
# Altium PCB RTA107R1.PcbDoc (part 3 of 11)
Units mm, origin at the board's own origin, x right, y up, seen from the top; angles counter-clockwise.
Board outline 96.01 x 65.66 mm, 22 copper layers (Top Layer, GND1, INT1, PWR1-(VCCIO_MRAM), INT2, PWR2-(VCCINT), INT3, PWR3_(12V_MGTAVCC), INT4, GND2-(DGND_SGND), PWR4_(MGTAVTT_VCCBRAM,VCCAUX), PWR5-(VCC_12V), GND3-(DGND_GND), INT5, GND4, INT6, PWR6_(VCCO), INT7, GND5, INT8, GND6, Bottom Layer), stack 2.833 mm thick; 614 components, 659 nets, 4037 pads, 3511 vias.

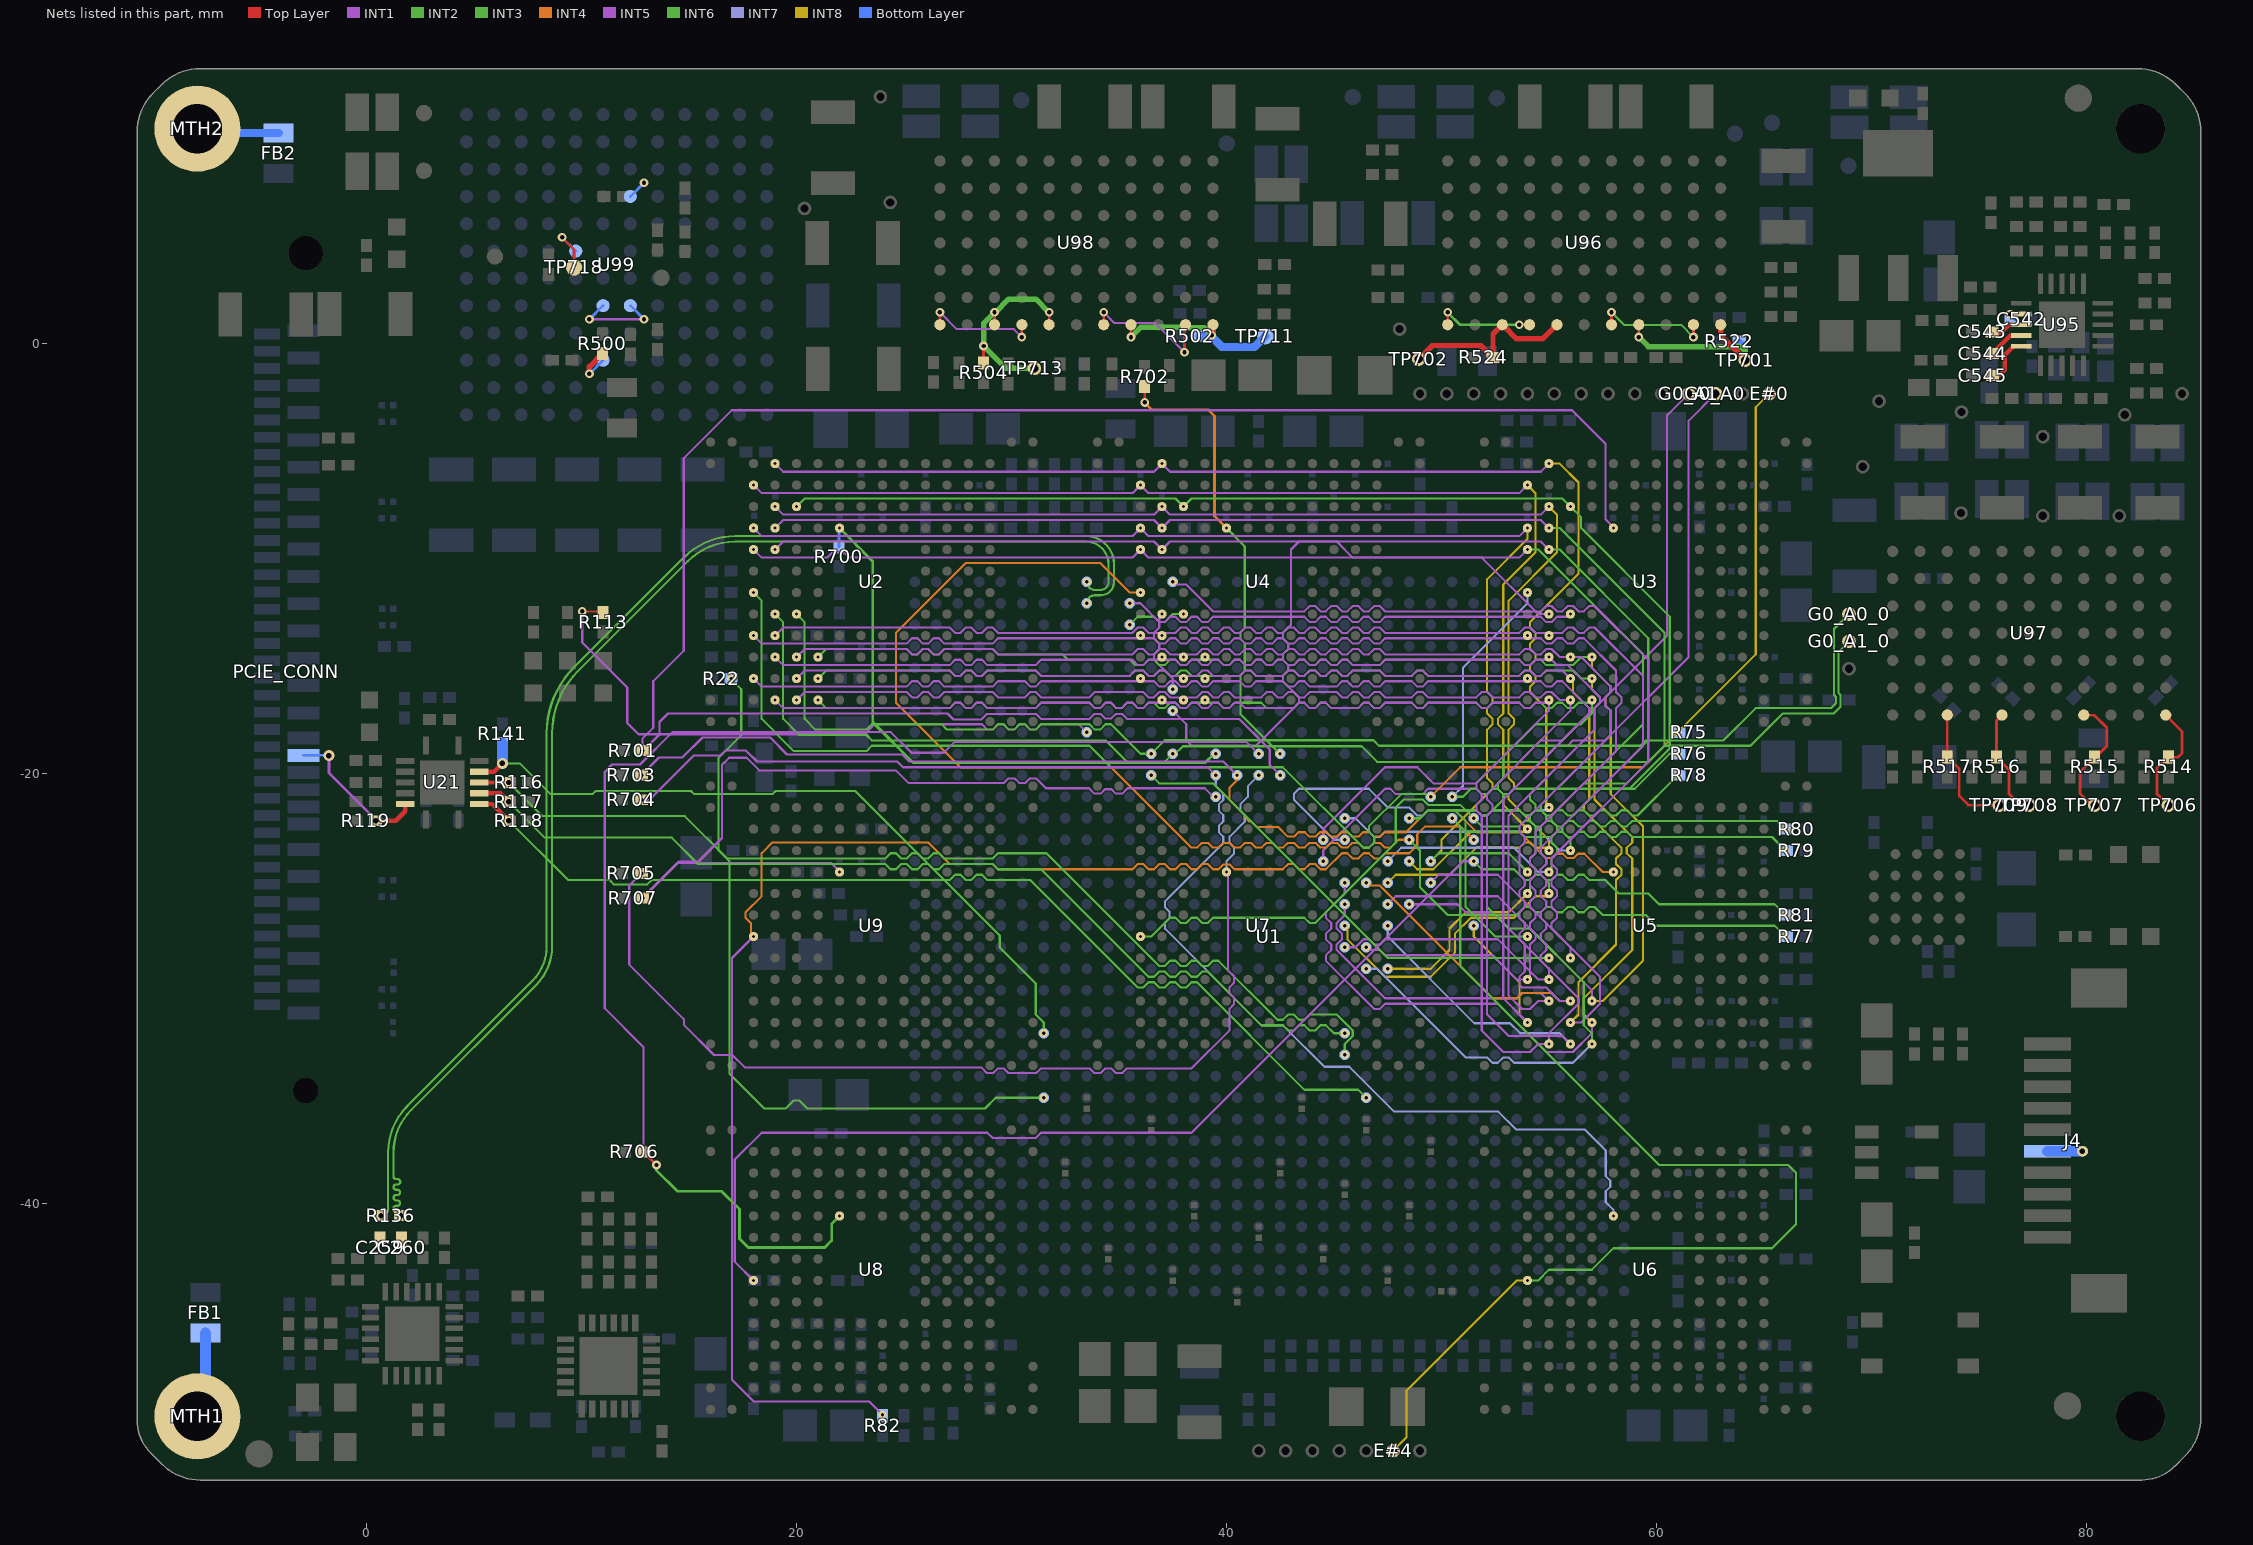
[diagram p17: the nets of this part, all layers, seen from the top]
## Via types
v1: diameter 0.381, hole 0.152, Top Layer to Bottom Layer, tented both sides, 2009 vias
v2: diameter 0.508, hole 0.254, Top Layer to Bottom Layer, tented both sides, 467 vias
v3: diameter 0.406, hole 0.203, Top Layer to Bottom Layer, 458 vias
v4: diameter 0.508, hole 0.254, Top Layer to Bottom Layer, 239 vias
v5: diameter 0.406, hole 0.203, Top Layer to Bottom Layer, tented both sides, 181 vias
v6: diameter 0.381, hole 0.152, Top Layer to GND4, tented both sides, 147 vias
v7: diameter 0.406, hole 0.203, Top Layer to GND4, tented both sides, 10 vias

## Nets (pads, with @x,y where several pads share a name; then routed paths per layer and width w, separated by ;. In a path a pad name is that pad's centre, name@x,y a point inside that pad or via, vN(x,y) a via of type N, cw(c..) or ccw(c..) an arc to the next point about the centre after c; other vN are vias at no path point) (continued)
ACT_2: R113.2 U1.AG9 | length 29.6
  Top Layer w0.102: v3(10.033,-12.446) 10.954,-12.446 R113.2@11.004,-12.496
  INT5 w0.102: v3(10.033,-12.446) 10.033,-13.894 12.125,-15.986 12.125,-17.637 12.649,-18.161 23.16,-18.161 23.625,-17.696 28.625,-17.696 28.875,-17.946 29.125,-17.946 29.375,-17.696 29.625,-17.696 29.875,-17.946 30.125,-17.946 30.375,-17.696 30.625,-17.696 30.875,-17.946 31.125,-17.946 31.375,-17.696 33.125,-17.696 v1(33.5,-18.071)
CE_PMIC: J4.6 | length 1.6
  Bottom Layer w0.508: J4.6@78.196,-37.563 v2(79.821,-37.562)
CHASSIS_GND1: FB1.2 MTH1.1 | length 4
  Bottom Layer w0.508: MTH1.1@-7.878,-49.891 -7.5,-49.513 FB1.2@-7.5,-46.011
CHASSIS_GND2: FB2.2 MTH2.1 | length 4
  Bottom Layer w0.381: MTH2.1@-7.83,10.057 -7.742,9.969 cw(c-7.533,10.057) -7.76,10.057 -7.507,9.804 FB2.2@-4.089,9.804
CLK_125_N: C260.1 R136.2 U1.AP9 | length 59.8
  INT6 w0.102: v2(1.582,-40.551) cw(c1.582,-40.221) 1.252,-40.221 cw(c1.373,-40.221) 1.373,-40.1 1.427,-40.1 ccw(c1.427,-39.973) 1.554,-39.973 ccw(c1.431,-39.973) 1.431,-39.85 1.381,-39.85 cw(c1.381,-39.721) 1.252,-39.721 cw(c1.373,-39.721) 1.373,-39.6 1.427,-39.6 ccw(c1.427,-39.473) 1.554,-39.473 ccw(c1.431,-39.473) 1.431,-39.35 1.373,-39.35 cw(c1.373,-39.229) 1.252,-39.229 cw(c1.373,-39.229) 1.373,-39.108 1.442,-39.108 ccw(c1.442,-38.987) 1.562,-38.987 ccw(c1.433,-38.987) 1.433,-38.858 1.373,-38.858 cw(c1.373,-38.737) 1.252,-38.737 1.252,-37.625 cw(c4.064,-37.625) 2.076,-35.637 7.875,-29.837 ccw(c6.056,-28.018) 8.629,-28.018 8.629,-18.119 cw(c12.716,-18.119) 9.826,-15.229 14.941,-10.114 cw(c17.148,-12.32) 17.148,-9.2 33.469,-9.2 cw(c33.469,-10.243) 34.512,-10.243 34.512,-11.084 cw(c34.152,-11.084) 34.152,-11.444 33.873,-11.444 cw(c33.873,-11.071) v1(33.5,-11.071)
CLK_125_P: C259.1 R136.1 U1.AN9 | length 59.8
  INT6 w0.102: v2(0.668,-40.551) ccw(c0.668,-40.221) 0.998,-40.221 0.998,-37.625 cw(c4.064,-37.625) 1.896,-35.457 7.696,-29.657 ccw(c6.056,-28.018) 8.375,-28.018 8.375,-21.446 8.375,-18.119 cw(c12.716,-18.119) 9.646,-15.05 14.762,-9.934 cw(c17.148,-12.32) 17.148,-8.946 33.469,-8.946 cw(c33.469,-10.243) 34.766,-10.243 34.766,-11.084 cw(c34.152,-11.084) 34.152,-11.698 33.873,-11.698 ccw(c33.873,-12.071) v1(33.5,-12.071)
CLK_OUT: TP718.1 U99.G5 | length 2.5
  Top Layer w0.127: v3(9.093,4.953) 9.652,4.394 TP718.1@9.652,3.556
  Bottom Layer w0.127: v3(9.093,4.953) U99.G5@9.728,4.318
COMP_U96_1_2: U96.B7 U96.E7 | length 5.4
  Top Layer w0.127: U96.E7@57.912,0.889 v3(57.912,1.465) ; v3(61.722,0.313) U96.B7@61.722,0.889
  INT2 w0.102: v3(57.912,1.465) 58.494,0.883 61.152,0.883 v3(61.722,0.313)
COMP_U96_3_4: U96.H7 U96.L7 | length 4.6
  Top Layer w0.127: U96.L7@50.292,0.889 v3(50.292,1.465) ; v3(53.619,0.889) U96.H7@54.102,0.889
  INT2 w0.127: v3(50.292,1.465) 50.868,0.889 v3(53.619,0.889)
COMP_U98_1_2: U98.B7 U98.E7 | length 6.4
  Top Layer w0.127: U98.E7@34.29,0.889 v3(34.29,1.465) ; v3(38.049,-0.397) 38.049,0.838 U98.B7@38.1,0.889
  INT1 w0.102: v3(34.29,1.465) 34.79,0.965 36.687,0.965 v3(38.049,-0.397)
COMP_U98_3_4: U98.H7 U98.L7 | length 5.4
  Top Layer w0.127: U98.L7@26.67,0.889 v3(26.67,1.465) ; v3(30.48,0.313) U98.H7@30.48,0.889
  INT1 w0.102: v3(26.67,1.465) 27.449,0.686 30.107,0.686 v3(30.48,0.313)
COMP_U99_1_2: U99.E6 U99.E7 | length 4.3
  INT1 w0.127: v3(10.363,1.143) v3(12.903,1.143)
  Bottom Layer w0.127: v3(10.363,1.143) U99.E6@10.998,1.778 ; U99.E7@12.268,1.778 v3(12.903,1.143)
CONFIG_SWITCH_0: R22.1 U1.K7 | length 35
  INT6 w0.102: v1(16.957,-15.571) 16.957,-15.604 17.424,-16.071 17.424,-18.204 16.375,-19.253 16.375,-23.571 16.875,-24.071 16.875,-33.946 18.5,-35.571 19.5,-35.571 19.875,-35.196 20.125,-35.196 20.5,-35.571 28.767,-35.571 29.267,-35.071 v1(31.5,-35.071)
CT1: C545.2 U95.5 | length 2.3
  Top Layer w0.203: C545.2@75.63,-1.473 75.952,-1.473 76.2,-1.225 76.2,-0.533 U95.5@76.606,-0.127 ; U95.5@76.632,-0.127 76.648,-0.111 U95.5@76.967,-0.111
CT2: C544.2 U95.4 | length 1.8
  Top Layer w0.203: C544.2@75.444,-0.365 75.708,-0.365 76.462,0.389 U95.4@76.967,0.389
CT3: C543.2 U95.3 | length 1.7
  Top Layer w0.203: C543.2@75.438,0.508 76.022,0.508 76.403,0.889 U95.3@76.967,0.889
CT4: C542.2 U95.2 | length 0.9
  Top Layer w0.203: v3(76.454,1.372) 76.934,1.372 76.959,1.397 U95.2@76.967,1.389
  Bottom Layer w0.203: v3(76.454,1.372) 76.454,1.388 C542.2@76.707,1.135
DONE_LED: R141.1 U1.N7 U21.5 | length 34.2
  Top Layer w0.203: U21.5@5.243,-19.906 5.923,-19.906 v2(6.312,-19.517)
  INT3 w0.102: v2(6.312,-19.517) 7.116,-19.517 8.536,-20.937 10.527,-20.937 10.661,-20.803 15.089,-20.803 15.224,-20.937 18.89,-20.937 19.025,-20.803 22.732,-20.803 29.451,-27.522 29.451,-28.079 31.125,-29.753 31.125,-31.196 31.5,-31.571 v1(31.5,-32.071)
  Bottom Layer w0.508: v2(6.312,-19.517) R141.1@6.312,-18.6
E#0: E#0.1 R75.2 U1.AD25 U2.P8 | length 72
  INT4 w0.102: v1(49.5,-21.071) 50.875,-19.696 59.375,-19.696 v1(61,-18.071)
  INT8 w0.102: v1(61,-18.071) 64.625,-14.446 64.625,-2.946 E#0.1@65.25,-2.321
  INT2 w0.102: v1(18,-11.571) 18.375,-11.946 18.375,-17.446 19.875,-18.946 23.25,-18.946 23.5,-18.696 33.625,-18.696 34.625,-19.696 42.625,-19.696 46.375,-23.446 46.625,-23.446 46.875,-23.196 46.875,-22.946 46.625,-22.696 46.625,-22.446 48.125,-20.946 49.375,-20.946 v1(49.5,-21.071)
E#0_1: R700.2 U1.AF15 U2.K5 | length 27.5
  INT3 w0.127: v1(22,-8.571) 23.546,-10.117 23.546,-17.602 25.425,-19.482 39.014,-19.482 39.421,-19.075 v1(39.5,-19.075)
  Bottom Layer w0.127: R700.2@21.971,-9.449 21.971,-8.6 v1(22,-8.571)
E#1: R76.2 U1.AD26 U3.P8 | length 22.7
  INT7 w0.102: v1(50.5,-21.071) 51,-20.571 51,-15.071 54,-12.071 v1(54,-11.571)
  INT3 w0.102: v1(50.5,-21.071) 51,-21.071 51.375,-20.696 51.625,-20.696 51.875,-20.946 52.125,-20.946 52.375,-20.696 52.625,-20.696 52.875,-20.946 53.125,-20.946 53.375,-20.696 59,-20.696 60.625,-19.071 v1(61,-19.071)
E#1_1: R701.2 U1.AE18 U3.K5 | length 95.8
  INT1 w0.102: v1(42.5,-20.071) 42.012,-19.583 42.012,-18.872 40.589,-17.45 35.378,-17.45 35.146,-17.218 34.852,-17.218 34.646,-17.424 34.352,-17.424 34.146,-17.218 33.854,-17.218 33.622,-17.45 31.378,-17.45 31.146,-17.218 28.854,-17.218 28.593,-17.479 27.305,-17.479 27.026,-17.2 14.017,-17.2 13.625,-17.592 13.625,-18.176 12.878,-18.923 v7(12.827,-18.923) 12.827,-18.364 13.335,-17.856 13.335,-15.69 14.75,-14.275 14.75,-5.322 16.982,-3.09 36.042,-3.09 36.043,-3.091 36.347,-3.091 36.348,-3.09 56.074,-3.09 57.633,-4.648 57.633,-8.153 58,-8.521 v1(58,-8.571)
E#2: R77.2 U1.AB24 U4.P8 | length 66.2
  INT4 w0.102: v1(36,-11.571) 35.5,-11.571 34.125,-10.196 27.875,-10.196 24.625,-13.446 24.625,-16.696 27.625,-19.696 34.626,-19.696 38.354,-23.424 38.648,-23.424 38.854,-23.218 39.148,-23.218 39.354,-23.424 39.648,-23.424 39.854,-23.218 40.148,-23.218 40.354,-23.424 40.648,-23.424 40.854,-23.218 41.148,-23.218 41.354,-23.424 41.648,-23.424 41.854,-23.218 42.148,-23.218 42.354,-23.424 42.648,-23.424 42.854,-23.218 43.148,-23.218 43.354,-23.424 43.648,-23.424 43.854,-23.218 44.148,-23.218 44.354,-23.424 44.648,-23.424 44.854,-23.218 45.148,-23.218 45.354,-23.424 45.648,-23.424 45.854,-23.218 46.148,-23.218 46.354,-23.424 46.648,-23.424 46.854,-23.218 47.148,-23.218 47.354,-23.424 47.646,-23.424 47.999,-23.071 v1(48.5,-23.071)
  INT3 w0.102: v1(48.5,-23.071) 49,-23.571 49,-25.276 50.295,-26.571 53.5,-26.571 53.875,-26.196 54.125,-26.196 54.375,-26.446 54.625,-26.446 54.875,-26.196 55.125,-26.196 55.375,-26.446 55.625,-26.446 55.875,-26.196 56.125,-26.196 56.375,-26.446 56.625,-26.446 56.875,-26.196 57.125,-26.196 57.5,-26.571 59.5,-26.571 60,-27.071 65.5,-27.071 v1(66,-27.571)
E#2_1: R702.2 U1.AF18 U4.K5 | length 21.6
  Top Layer w0.127: v3(36.195,-2.725) R702.2@36.195,-1.981
  INT6 w0.102: v1(40,-8.571) 40.853,-9.424 40.853,-13.219 40.647,-13.425 40.647,-13.719 40.853,-13.925 40.853,-15.219 40.647,-15.425 40.647,-17.224 v1(42.494,-19.071)
  INT4 w0.127: v3(36.195,-2.725) 36.54,-3.071 39.164,-3.071 39.446,-3.353 39.446,-8.017 v1(40,-8.571)
E#3: R78.2 U1.AC24 U5.P8 | length 25.2
  INT2 w0.102: v1(48.5,-22.071) 49,-22.071 49.375,-21.696 50.625,-21.696 51.125,-22.196 51.125,-26.196 52.5,-27.571 v1(54,-27.571)
  INT3 w0.102: v1(48.5,-22.071) 49,-22.071 49.375,-21.696 51.625,-21.696 51.875,-21.946 52.125,-21.946 52.375,-21.696 53.625,-21.696 53.875,-21.946 54.125,-21.946 54.375,-21.696 54.625,-21.696 54.875,-21.946 55.125,-21.946 55.25,-21.821 55.375,-21.696 55.625,-21.696 55.875,-21.946 56.125,-21.946 56.375,-21.696 56.625,-21.696 56.875,-21.946 57.125,-21.946 57.375,-21.696 57.625,-21.696 57.875,-21.946 58.125,-21.946 58.375,-21.696 58.625,-21.696 58.875,-21.946 59.125,-21.946 v1(61,-20.071)
E#3_1: R703.2 U1.AE16 U5.K5 | length 51.8
  INT4 w0.102: v1(40.488,-20.071) 40.488,-20.295 40.147,-20.635 40.147,-21.219 40.853,-21.925 40.853,-22.005 41.066,-22.218 41.146,-22.218 41.407,-22.479 42.409,-22.479 42.854,-22.924 43.146,-22.924 43.352,-22.718 43.646,-22.718 43.852,-22.924 44.146,-22.924 44.352,-22.718 44.646,-22.718 44.852,-22.924 45.146,-22.924 45.352,-22.718 45.646,-22.718 45.852,-22.924 46.146,-22.924 46.352,-22.718 46.646,-22.718 46.852,-22.924 47.146,-22.924 47.352,-22.718 48.352,-22.718 49.352,-21.718 50.646,-21.718 51.646,-22.718 53.646,-22.718 53.852,-22.924 53.854,-22.924 54.854,-23.924 55.146,-23.924 55.352,-23.718 55.646,-23.718 55.852,-23.924 56.146,-23.924 56.352,-23.718 56.648,-23.718 56.667,-23.737 57.501,-24.571 v1(58,-24.571)
  INT1 w0.102: v7(12.776,-20.066) 12.787,-20.066 13.605,-19.248 14.687,-19.248 15.621,-18.313 18.771,-18.313 19.558,-19.101 24.917,-19.101 25.248,-19.431 39.848,-19.431 v1(40.488,-20.071)
E#4: E#4.1 R79.2 U1.AC26 U6.P8 | length 70.4
  INT8 w0.102: E#4.1@47.75,-51.496 48.375,-50.871 48.375,-48.696 53.5,-43.571 v1(54,-43.571)
  INT2 w0.102: v1(50.5,-22.071) 50.875,-22.446 50.875,-28.946 60.125,-38.196 66.125,-38.196 66.5,-38.571 66.5,-40.946 65.375,-42.071 58,-42.071 57,-43.071 55,-43.071 54.5,-43.571 v1(54,-43.571)
  INT3 w0.102: v1(50.5,-22.071) 51.125,-22.696 53.625,-22.696 53.875,-22.946 55.125,-22.946 55.375,-22.696 55.625,-22.696 55.875,-22.946 56.125,-22.946 56.375,-22.696 56.625,-22.696 56.875,-22.946 57.125,-22.946 57.375,-22.696 57.625,-22.696 57.875,-22.946 58.125,-22.946 58.375,-22.696 58.625,-22.696 58.875,-22.946 65.375,-22.946 v1(66,-23.571)
E#4_1: R704.2 U1.AE15 U6.K5 | length 65.2
  INT7 w0.102: v1(39.5,-20.071) 39.5,-20.572 39.853,-20.925 39.853,-21.219 39.647,-21.425 39.647,-21.719 39.853,-21.925 39.853,-22.219 39.647,-22.425 39.647,-22.719 39.853,-22.925 39.853,-23.217 37.353,-25.717 37.353,-25.719 37.147,-25.925 37.147,-26.219 37.353,-26.425 37.353,-26.717 37.147,-26.923 37.147,-27.217 41.648,-31.718 42.646,-31.718 44.558,-33.63 45.71,-33.63 47.799,-35.718 52.646,-35.718 53.479,-36.551 56.667,-36.551 57.647,-37.53 57.647,-38.719 57.853,-38.925 57.853,-39.219 57.647,-39.425 57.647,-39.924 58,-40.277 v1(58,-40.571)
  INT1 w0.102: v7(12.776,-21.209) 13.157,-21.209 15.215,-19.152 16.459,-19.152 16.688,-18.923 17.65,-18.923 18.158,-19.431 24.689,-19.431 24.954,-19.696 39.125,-19.696 v1(39.5,-20.071)
E#5: R80.2 U1.AC27 U7.P8 | length 36
  INT2 w0.102: v1(36,-27.571) 36.5,-27.571 37.125,-26.946 37.375,-26.696 37.625,-26.696 37.875,-26.946 38.125,-26.946 38.375,-26.696 38.625,-26.696 38.875,-26.946 39.125,-26.946 39.375,-26.696 43.625,-26.696 43.875,-26.946 44.125,-26.946 47.875,-23.196 47.875,-21.571 48.25,-21.196 49.125,-21.196 49.375,-21.446 50.875,-21.446 v1(51.5,-22.071)
  INT3 w0.102: v1(51.5,-22.071) 51.875,-22.446 53.625,-22.446 53.875,-22.196 54.125,-22.196 54.375,-22.446 54.625,-22.446 54.875,-22.196 55.125,-22.196 55.375,-22.446 55.625,-22.446 55.875,-22.196 56.125,-22.196 56.25,-22.321 56.375,-22.446 56.625,-22.446 56.875,-22.196 57.125,-22.196 57.375,-22.446 57.625,-22.446 57.875,-22.196 58.125,-22.196 58.25,-22.321 58.375,-22.446 58.625,-22.446 58.875,-22.196 65.625,-22.196 v1(66,-22.571)
E#5_1: R705.2 U1.AE17 U7.K5 | length 49.2
  INT7 w0.102: v1(40,-24.571) 40,-24.07 40.353,-23.717 40.353,-23.423 40.147,-23.217 40.147,-22.923 40.853,-22.217 40.853,-21.923 40.647,-21.717 40.647,-21.423 40.996,-21.075 40.996,-20.575 v1(41.5,-20.071)
  INT1 w0.102: v7(12.776,-24.638) 12.217,-25.197 12.217,-28.88 14.757,-31.42 14.757,-31.674 16.164,-33.08 17.01,-33.08 17.589,-33.659 28.589,-33.659 28.854,-33.924 29.147,-33.924 29.353,-33.718 29.648,-33.718 29.854,-33.924 31.148,-33.924 31.354,-33.718 33.648,-33.718 33.854,-33.924 34.148,-33.924 34.354,-33.718 34.648,-33.718 34.854,-33.924 35.148,-33.924 35.354,-33.718 38.354,-33.718 40.147,-31.925 40.147,-30.925 40.353,-30.719 40.353,-30.425 40.147,-30.219 40.147,-29.925 40.353,-29.719 40.353,-29.425 40.066,-29.138 40.066,-24.637 v1(40,-24.571)
E#6: R81.2 U1.AA27 U8.P8 | length 62.5
  INT1 w0.102: v6(18,-43.571) 17.125,-42.696 17.125,-37.946 18.375,-36.696 28.875,-36.696 29.125,-36.946 31.125,-36.946 31.375,-36.696 38.375,-36.696 51,-24.071 v1(51.5,-24.071)
  INT3 w0.102: v1(51.5,-24.071) 51.875,-24.446 53.375,-24.446 53.875,-24.946 54.125,-24.946 54.375,-24.696 54.625,-24.696 54.875,-24.946 55.125,-24.946 55.375,-24.696 55.625,-24.696 55.875,-24.946 56.125,-24.946 56.375,-24.696 56.625,-24.696 56.875,-24.946 57.625,-24.946 58.25,-25.571 59.625,-25.571 60.125,-26.071 65.5,-26.071 v1(66,-26.571)
E#6_1: R706.2 U1.AF17 U8.K5 | length 64.3
  Top Layer w0.127: R706.2@12.903,-37.592 12.903,-37.617 v3(13.487,-38.202)
  INT1 w0.102: v3(13.487,-38.202) 12.875,-37.589 12.875,-32.712 11.074,-30.912 11.074,-19.914 11.417,-19.571 12.715,-19.571 14.224,-18.062 24.386,-18.062 25.349,-19.025 26.848,-19.025 27.356,-18.517 40.919,-18.517 41.474,-19.071 v1(41.5,-19.071)
  INT3 w0.127: v3(13.487,-38.202) 13.487,-38.456 14.453,-39.421 16.517,-39.421 17.348,-40.252 17.348,-41.631 17.755,-42.037 21.311,-42.037 21.634,-41.713 21.634,-40.937 v6(22,-40.571)
E#7: R82.2 U1.AB27 U9.P8 | length 70.1
  INT5 w0.102: v6(18,-27.571) 17,-28.571 17,-48.196 18,-49.196 23.375,-49.196 v1(24,-49.821)
  INT4 w0.102: v6(18,-27.571) 17.875,-27.446 17.875,-26.946 17.625,-26.696 17.625,-26.446 18.375,-25.696 18.375,-23.696 18.875,-23.196 26.125,-23.196 27.125,-24.196 29.125,-24.196 29.375,-24.446 35.625,-24.446 35.875,-24.196 36.125,-24.196 36.375,-24.446 36.625,-24.446 36.875,-24.196 37.125,-24.196 37.375,-24.446 37.625,-24.446 37.875,-24.196 38.125,-24.196 38.375,-24.446 38.625,-24.446 38.875,-24.196 39.125,-24.196 39.375,-24.446 39.626,-24.446 39.854,-24.218 40.146,-24.218 40.374,-24.446 42.625,-24.446 42.875,-24.196 43.125,-24.196 43.375,-24.446 43.625,-24.446 43.875,-24.196 44.125,-24.196 44.375,-24.446 44.625,-24.446 45.375,-23.696 45.625,-23.696 45.875,-23.946 46.125,-23.946 46.375,-23.696 46.625,-23.696 46.875,-23.946 47.125,-23.946 47.375,-23.696 48.5,-23.696 48.875,-23.321 48.875,-22.821 49.25,-22.446 50.875,-22.446 v1(51.5,-23.071)
E#7_1: R707.2 U1.AD15 U9.K5 | length 42.9
  INT5 w0.102: v7(12.827,-25.781) 12.852,-25.781 14.478,-24.155 21.615,-24.155 22,-24.54 v1(22,-24.571)
  INT1 w0.102: v7(12.827,-25.781) 14.529,-24.079 15.443,-24.079 16.535,-22.987 16.535,-19.583 16.866,-19.253 17.678,-19.253 18.268,-19.843 24.621,-19.843 25.202,-20.424 29.648,-20.424 29.854,-20.218 30.148,-20.218 30.354,-20.424 30.648,-20.424 30.854,-20.218 31.146,-20.218 31.604,-20.676 33.605,-20.676 33.854,-20.924 34.148,-20.924 34.354,-20.718 34.648,-20.718 34.854,-20.924 35.146,-20.924 35.395,-20.676 38.989,-20.676 39.384,-21.071 v1(39.5,-21.071)
ePERst0#: PCIE_CONN.E5 R119.1 U21.13 | length 7
  Top Layer w0.203: v2(0.419,-22.184) 1.356,-22.184 1.793,-21.747 U21.13@1.793,-21.406
  INT1 w0.127: v2(-1.753,-19.152) -1.753,-19.96 0.419,-22.132 v2(0.419,-22.184)
  Bottom Layer w0.127: PCIE_CONN.E5@-2.932,-19.144 -1.761,-19.144 v2(-1.753,-19.152)
EXT_VCC: U99.J7 | length 0.9
  Bottom Layer w0.127: U99.J7@12.268,6.858 v3(12.903,7.493)
FB1_1: R502.2 TP711.1 U98.A7 U98.D7 | length 8.6
  Top Layer w0.127: v3(35.56,0.313) U98.D7@35.56,0.889
  Top Layer w0.381: v3(39.319,0.4) 39.319,0.838 U98.A7@39.37,0.889
  INT2 w0.254: v3(35.56,0.313) 36.009,0.762 38.234,0.762 38.241,0.755 38.965,0.755 v3(39.319,0.4)
  Bottom Layer w0.381: R502.2@38.76,0.356 39.274,0.356 39.782,-0.152 41.3,-0.152 TP711.1@41.808,0.356
FB1_3: R504.1 TP713.1 U98.G7 U98.J7 | length 9.6
  Top Layer w0.127: R504.1@28.702,-0.914 R504.1@28.702,-0.889 v3(28.702,-0.102) ; U98.J7@29.21,0.889 v3(29.21,1.465) ; U98.G7@31.75,0.889 v3(31.75,1.465)
  INT2 w0.254: TP713.1@31.064,-1.143 29.743,-1.143 v3(28.702,-0.102) 28.702,0.957 v3(29.21,1.465) 29.253,1.465 29.87,2.083 31.132,2.083 v3(31.75,1.465)
FB2_1: R514.1 TP706.1 U97.A7 | length 5.5
  Top Layer w0.127: U97.A7@83.693,-17.272 84.455,-18.034 84.455,-19.051 84.279,-19.228 R514.1@83.82,-19.228 83.769,-19.228 83.287,-19.71 83.287,-20.93 TP706.1@83.82,-21.463
FB2_2: R515.2 TP707.1 U97.D7 | length 5.8
  Top Layer w0.127: U97.D7@79.883,-17.272 80.366,-17.272 80.95,-17.856 80.95,-18.715 80.488,-19.177 80.391,-19.177 R515.2@80.391,-19.228 79.71,-19.909 79.71,-20.909 80.264,-21.463 TP707.1@80.391,-21.463
FB2_3: R516.1 TP708.1 U97.G7 | length 5.2
  Top Layer w0.127: U97.G7@76.073,-17.272 75.819,-17.526 R516.1@75.819,-19.228 76.403,-19.812 76.403,-20.93 76.937,-21.463 TP708.1@77.343,-21.463
FB2_4: R517.2 TP709.1 U97.J7 | length 6
  Top Layer w0.127: U97.J7@73.533,-17.272 R517.2@73.533,-19.228 74.092,-19.787 74.092,-21.041 74.513,-21.463 TP709.1@75.946,-21.463
FB3_1: R522.1 TP701.1 U96.A7 U96.D7 | length 9.3
  Top Layer w0.127: v3(59.182,0.313) U96.D7@59.182,0.889
  Top Layer w0.254: U96.A7@62.992,0.889 62.992,0.381 TP701.1@64.135,-0.762
  INT2 w0.254: v3(59.182,0.313) 59.624,-0.129 61.905,-0.129 61.907,-0.127 63.906,-0.127 64.135,-0.356 TP701.1@64.135,-0.762
  Bottom Layer w0.254: R522.1@63.856,0.127 64.135,-0.152 TP701.1@64.135,-0.762
FB3_3: R524.1 TP702.1 U96.G7 U96.J7 | length 8.7
  Top Layer w0.254: TP702.1@48.946,-0.711 49.581,-0.076 51.841,-0.076 R524.1@52.4,-0.635 52.4,0.457 U96.J7@52.832,0.889 53.492,0.229 54.712,0.229 U96.G7@55.372,0.889
FPGA_EPERST0#: R118.1 U1.K22 U21.2 | length 48.1
  Top Layer w0.203: U21.2@5.243,-21.406 5.839,-21.406 v2(6.617,-22.184)
  INT2 w0.102: v2(6.617,-22.184) 9.379,-24.946 11.3,-24.946 11.5,-25.146 13.059,-25.146 13.259,-24.946 27.125,-24.946 27.375,-24.696 27.625,-24.696 27.875,-24.946 28.125,-24.946 28.375,-24.696 28.625,-24.696 28.875,-24.946 30.875,-24.946 35.875,-29.946 36.125,-29.946 36.375,-29.696 36.625,-29.696 36.875,-29.946 37.125,-29.946 37.375,-29.696 37.625,-29.696 37.875,-29.946 38.125,-29.946 38.375,-29.696 38.625,-29.696 43.625,-34.696 46.125,-34.696 v1(46.5,-35.071)
FPGA_I2C_SCLK: R117.1 U1.N21 U21.3 | length 46.5
  Top Layer w0.203: U21.3@5.243,-20.906 6.228,-20.906 v2(6.617,-21.295)
  INT2 w0.102: v2(6.617,-21.295) 8.293,-22.971 14.194,-22.971 15.419,-24.196 24.125,-24.196 24.375,-24.446 24.625,-24.446 24.875,-24.196 25.125,-24.196 25.375,-24.446 25.625,-24.446 25.875,-24.196 26.125,-24.196 26.375,-24.446 26.625,-24.446 26.875,-24.196 29.125,-24.196 29.375,-24.446 31.375,-24.446 36.375,-29.446 36.625,-29.446 36.875,-29.196 37.125,-29.196 37.375,-29.446 37.625,-29.446 37.875,-29.196 38.125,-29.196 38.375,-29.446 38.625,-29.446 38.875,-29.196 39.125,-29.196 41.625,-31.696 42.5,-31.696 42.625,-31.696 42.875,-31.946 43.125,-31.946 43.375,-31.696 43.625,-31.696 43.875,-31.946 44.125,-31.946 44.375,-31.696 44.625,-31.696 45,-32.071 v1(45.5,-32.071)
FPGA_I2C_SDA: R116.1 U1.M21 U21.4 | length 48.6
  Top Layer w0.203: U21.4@5.243,-20.406 v2(6.617,-20.406)
  INT2 w0.102: v2(6.617,-20.406) 8.182,-21.971 14.8,-21.971 16.775,-23.946 24.125,-23.946 24.375,-23.696 24.625,-23.696 24.875,-23.946 25.125,-23.946 25.375,-23.696 25.625,-23.696 25.875,-23.946 26.125,-23.946 26.375,-23.696 26.625,-23.696 26.875,-23.946 29.125,-23.946 29.375,-23.696 31.625,-23.696 36.875,-28.946 37.125,-28.946 37.375,-28.696 37.625,-28.696 37.875,-28.946 38.125,-28.946 38.375,-28.696 38.625,-28.696 38.875,-28.946 39.125,-28.946 39.375,-28.696 39.625,-28.696 42.375,-31.446 42.625,-31.446 42.875,-31.196 43.125,-31.196 43.375,-31.446 43.625,-31.446 43.875,-31.196 45.125,-31.196 45.875,-31.946 45.875,-32.196 45.5,-32.571 v1(45.5,-33.071)
FSET: R500.2 U99.C6 | length 2.1
  Top Layer w0.254: v3(10.363,-1.397) 10.363,-1.067 R500.2@10.973,-0.457
  Bottom Layer w0.127: v3(10.363,-1.397) U99.C6@10.998,-0.762
G0_A0: G0_A0.1 U1.AA20 | length 34.4
  INT5 w0.102: v1(44.5,-24.071) 44.5,-23.571 47.375,-20.696 47.625,-20.696 47.875,-20.946 49.125,-20.946 49.375,-20.696 51.625,-20.696 51.875,-20.946 52.125,-20.946 53.375,-19.696 54.375,-19.696 55.375,-18.696 55.875,-18.696 56.125,-18.446 57.625,-18.446 61.5,-14.571 61.5,-3.571 G0_A0.1@62.75,-2.321
G0_A0_0: G0_A0_0.1 U1.AF12 U2.M9 | length 60.4
  INT2 w0.102: v1(20,-12.571) 20.375,-12.946 20.375,-17.446 20.875,-17.946 23.25,-17.946 23.5,-17.696 26.75,-17.696 27,-17.946 29.125,-17.946 29.375,-17.696 29.625,-17.696 29.875,-17.946 30.125,-17.946 30.375,-17.696 30.625,-17.696 30.875,-17.946 31.125,-17.946 31.375,-17.696 33.625,-17.696 33.875,-17.946 34.125,-17.946 34.375,-17.696 34.625,-17.696 36,-19.071 v1(36.5,-19.071)
  INT3 w0.102: v1(36.5,-19.071) 37.131,-18.44 46.836,-18.44 47.092,-18.696 59.25,-18.696 59.5,-18.446 63.125,-18.446 64.625,-16.946 68.125,-16.946 68.353,-16.718 68.353,-16.425 68.265,-16.337 68.265,-13.269 G0_A0_0.1@68.961,-12.573
G0_A0_1: U1.AN11 U3.M9 | length 22.5
  INT1 w0.102: v1(35.5,-12.071) 36,-12.071 36.875,-12.946 37.125,-12.946 37.375,-12.696 37.625,-12.696 37.875,-12.946 38.125,-12.946 38.375,-12.696 38.625,-12.696 38.875,-12.946 39.125,-12.946 39.375,-12.696 43.625,-12.696 43.875,-12.946 44.125,-12.946 44.375,-12.696 44.625,-12.696 44.875,-12.946 45.125,-12.946 45.375,-12.696 45.625,-12.696 45.875,-12.946 46.125,-12.946 46.375,-12.696 46.625,-12.696 46.875,-12.946 47.125,-12.946 47.375,-12.696 54.625,-12.696 54.875,-12.946 55.125,-12.946 55.375,-12.696 55.875,-12.696 v1(56,-12.571)
G0_A0_2: U1.AM11 U4.M9 | length 2.9
  INT6 w0.102: v1(35.5,-13.071) 35.875,-12.696 36.625,-12.696 36.875,-12.946 37.125,-12.946 37.5,-12.571 v1(38,-12.571)
G0_A0_3: U1.AP13 U5.M9 | length 41.8
  INT1 w0.102: v1(37.5,-11.071) 37.625,-11.196 38.125,-11.196 39.375,-12.446 43.625,-12.446 43.875,-12.196 44.125,-12.196 44.375,-12.446 44.625,-12.446 44.875,-12.196 45.125,-12.196 45.375,-12.446 45.625,-12.446 45.875,-12.196 46.125,-12.196 46.375,-12.446 46.625,-12.446 46.875,-12.196 47.125,-12.196 47.375,-12.446 54.625,-12.446 54.875,-12.196 55.125,-12.196 55.375,-12.446 55.625,-12.446 55.875,-12.196 56.125,-12.196 56.375,-12.446 56.625,-12.446 56.875,-12.196 57.125,-12.196 59.625,-14.696 59.625,-19.446 55.125,-23.946 55.125,-24.196 55.375,-24.446 55.375,-24.696 55.125,-24.946 55.125,-25.196 55.375,-25.446 55.375,-25.696 55.125,-25.946 55.125,-26.196 55.375,-26.446 55.375,-26.696 55.125,-26.946 55.125,-27.196 56,-28.071 v1(56,-28.571)
G0_A1: G0_A1.1 U1.AB20 | length 32.5
  INT5 w0.102: v1(44.5,-23.071) 44.5,-22.571 47.375,-19.696 48.875,-19.696 49.625,-20.446 51.625,-20.446 52.625,-19.446 53.625,-19.446 54.625,-18.446 55.625,-18.446 56.375,-17.696 60.5,-13.571 60.5,-3.321 G0_A1.1@61.5,-2.321
G0_A1_0: G0_A1_0.1 U1.AF13 U2.N9 | length 60
  INT2 w0.102: v1(19,-12.571) 19.375,-12.946 19.375,-17.446 20.125,-18.196 23.25,-18.196 23.5,-18.446 34.375,-18.446 35.375,-19.446 37.125,-19.446 v1(37.5,-19.071)
  INT3 w0.102: v1(37.5,-19.071) 37.622,-19.071 37.975,-18.718 38.646,-18.718 38.648,-18.72 40.352,-18.72 40.354,-18.718 46.287,-18.718 47.015,-19.446 59.625,-19.446 60.375,-18.696 64.375,-18.696 65.875,-17.196 68.25,-17.196 68.566,-16.88 68.566,-16.336 68.478,-16.248 68.478,-14.326 G0_A1_0.1@68.961,-13.843
G0_A1_1: U1.AH13 U3.N9 | length 29.4
  INT5 w0.102: v1(37.5,-17.071) 38.125,-17.696 38.125,-18.446 38.375,-18.696 41.375,-18.696 43.375,-16.696 43.375,-16.446 42.625,-15.696 42.625,-15.446 42.875,-15.196 42.875,-14.946 42.625,-14.696 42.625,-14.446 42.875,-14.196 42.875,-13.946 42.625,-13.696 42.625,-13.446 43,-13.071 43,-9.571 43.375,-9.196 45.125,-9.196 45.875,-9.946 51.875,-9.946 54.5,-12.571 v1(55,-12.571)
G0_A1_2: U1.AJ13 U4.N9 | length 4.2
  INT5 w0.102: v1(37,-12.571) 36.875,-12.696 36.875,-13.196 36.625,-13.446 36.625,-13.696 36.875,-13.946 36.875,-14.196 36.625,-14.446 36.625,-14.696 37.5,-15.571 v1(37.5,-16.071)
G0_A1_3: U1.AE12 U5.N9 | length 22
  INT3 w0.102: v1(36.5,-20.071) 36.875,-20.446 39.375,-20.446 47.5,-28.571 v1(55,-28.571)
G0_A2: U1.AB21 U2.N2 U3.N2 U4.N2 U5.N2 | length 71.9
  INT7 w0.102: v1(45.5,-23.071) 45,-23.071 43.139,-21.21 43.139,-20.932 43.375,-20.696 46.625,-20.696 47.5,-21.571 48.5,-21.571 48.875,-21.946 49.125,-21.946 49.375,-21.696 51.625,-21.696 51.875,-21.946 52.125,-21.946 52.375,-21.696 53.625,-21.696 53.875,-21.946 54.125,-21.946 54.375,-21.696 54.875,-21.696 v1(55,-21.571)
  INT8 w0.102: v1(55,-21.571) 54.875,-21.446 54.875,-16.946 54.125,-16.196 54.125,-15.946 54.375,-15.696 54.375,-15.446 54.125,-15.196 54.125,-14.946 54.375,-14.696 54.375,-14.446 54.125,-14.196 54.125,-13.946 54.375,-13.696 54.375,-13.446 54.125,-13.196 54.125,-12.946 56.375,-10.696 56.375,-6.446 55.5,-5.571 v1(55,-5.571)
  INT1 w0.102: v1(19,-5.571) 19.375,-5.946 36.625,-5.946 v1(37,-5.571) 37.375,-5.946 54.625,-5.946 v1(55,-5.571)
G0_A3: U1.AC21 U2.M4 U3.M4 U4.M4 U5.M4 | length 68.9
  INT7 w0.102: v1(45.5,-22.071) 46,-22.071 46.875,-22.946 47.125,-22.946 47.375,-22.696 53.625,-22.696 53.875,-22.946 54.875,-22.946 55.5,-23.571 v1(56,-23.571)
  INT2 w0.102: v1(20,-7.571) 20.375,-7.196 37.625,-7.196 v1(38,-7.571) 38.375,-7.196 55.625,-7.196 v1(56,-7.571) 56.5,-8.071 56.5,-8.571 60.625,-12.696 60.625,-18.821 58.75,-20.696 57.375,-20.696 55.625,-22.446 55.625,-22.696 56,-23.071 v1(56,-23.571)
G0_A4: U1.Y23 U2.N4 U3.N4 U4.N4 U5.N4 | length 63.3
  INT8 w0.102: v1(47.5,-25.071) 47.875,-24.696 50.375,-24.696 51.625,-23.446 53.625,-23.446 53.875,-23.196 54.125,-23.196 54.375,-23.446 54.875,-23.446 v1(55,-23.571) 55,-23.071 53.125,-21.196 53.125,-20.946 53.375,-20.696 53.375,-20.446 53.125,-20.196 53.125,-17.946 53.375,-17.696 53.375,-17.446 53.125,-17.196 53.125,-11.946 55.375,-9.696 55.375,-7.946 v1(55,-7.571)
  INT1 w0.102: v1(19,-7.571) 19.375,-7.946 36.625,-7.946 v1(37,-7.571) 37.375,-7.946 54.625,-7.946 v1(55,-7.571)
G0_A5: U1.AA23 U2.N5 U3.N5 U4.N5 U5.N5 | length 67.2
  INT7 w0.102: v1(47.5,-24.071) 48.125,-23.446 53.375,-23.446 54.5,-24.571 v1(55,-24.571)
  INT1 w0.102: v6(19,-8.571) 19.375,-8.196 36.625,-8.196 v1(37,-8.571) 37.375,-8.196 54.625,-8.196 v1(55,-8.571)
  INT2 w0.102: v1(55,-24.571) 55.125,-24.446 55.125,-23.946 55.375,-23.696 55.375,-23.446 55.125,-23.196 55.125,-22.946 55.375,-22.696 55.375,-22.446 55.125,-22.196 55.125,-21.946 56.625,-20.446 58.625,-20.446 60.375,-18.696 60.375,-13.446 55.5,-8.571 v1(55,-8.571)
G0_A6: U1.AA24 U2.P3 U3.P3 U4.P3 U5.P3 | length 60.7
  INT8 w0.102: v1(48.5,-24.071) 48.875,-24.446 49.625,-24.446 51.375,-22.696 53.875,-22.696 v1(54,-22.571) 52.875,-21.446 52.875,-20.946 52.625,-20.696 52.625,-20.446 52.875,-20.196 52.875,-17.946 52.625,-17.696 52.625,-17.446 52.875,-17.196 52.875,-11.196 54.375,-9.696 54.375,-6.946 v1(54,-6.571)
  INT1 w0.102: v1(18,-6.571) 18.375,-6.946 35.625,-6.946 v1(36,-6.571) 36.375,-6.946 53.625,-6.946 v1(54,-6.571)
G0_A7: U1.AA25 U2.P5 U3.P5 U4.P5 U5.P5 | length 59.6
  INT8 w0.102: v1(49.5,-24.071) 50,-23.571 50,-23.071 52.375,-20.696 52.375,-20.446 52.125,-20.196 52.125,-17.946 52.375,-17.696 52.375,-17.446 52.125,-17.196 52.125,-16.946 52.375,-16.696 52.375,-16.446 52.125,-16.196 52.125,-10.946 54,-9.071 v1(54,-8.571)
  INT1 w0.102: v6(18,-8.571) 18.375,-8.946 35.625,-8.946 v1(36,-8.571) 36.375,-8.946 53.625,-8.946 v1(54,-8.571)
  INT3 w0.102: v1(49.5,-24.071) 49.875,-23.696 53.125,-23.696 v1(54,-24.571)
G0_A8: U1.Y22 U2.M11 U3.M11 U4.M11 U5.M11 | length 73.5
  INT4 w0.102: v1(46.5,-25.071) 46.625,-25.196 47.125,-25.196 52.375,-30.446 53.5,-30.446 53.75,-30.196 55.125,-30.196 55.5,-30.571 v1(56,-30.571)
  INT1 w0.102: v1(20,-14.571) 20.375,-14.196 25.125,-14.196 25.375,-14.446 25.625,-14.446 25.875,-14.196 26.125,-14.196 26.375,-14.446 26.625,-14.446 26.875,-14.196 29.125,-14.196 29.375,-14.446 35.625,-14.446 35.875,-14.196 36.125,-14.196 36.375,-14.446 36.625,-14.446 36.875,-14.196 37.125,-14.196 37.375,-14.446 37.875,-14.446 v1(38,-14.571) 38.125,-14.446 38.625,-14.446 38.875,-14.196 39.125,-14.196 39.375,-14.446 39.625,-14.446 39.875,-14.196 40.125,-14.196 40.375,-14.446 40.625,-14.446 40.875,-14.196 41.125,-14.196 41.375,-14.446 41.625,-14.446 41.875,-14.196 42.125,-14.196 42.375,-14.446 42.625,-14.446 42.875,-14.196 43.125,-14.196 43.375,-14.446 43.625,-14.446 43.875,-14.196 44.125,-14.196 44.375,-14.446 44.625,-14.446 44.875,-14.196 45.125,-14.196 45.375,-14.446 45.625,-14.446 45.875,-14.196 46.125,-14.196 46.375,-14.446 46.625,-14.446 46.875,-14.196 47.125,-14.196 47.375,-14.446 53.625,-14.446 53.875,-14.196 54.125,-14.196 54.375,-14.446 54.625,-14.446 54.875,-14.196 55.125,-14.196 55.5,-14.571 v1(56,-14.571) 56.5,-14.571 57.875,-15.946 57.875,-16.196 57.625,-16.446 57.625,-16.821 57.875,-17.071 57.875,-18.196 53.625,-22.446 53.625,-22.696 53.875,-22.946 53.875,-23.196 53.625,-23.446 53.625,-24.696 53.875,-24.946 53.875,-25.196 53.625,-25.446 53.625,-25.696 53.875,-25.946 53.875,-26.196 53.625,-26.446 53.625,-26.696 53.875,-26.946 53.875,-27.196 53.625,-27.446 53.625,-27.696 53.875,-27.946 53.875,-29.196 53.625,-29.446 53.625,-29.821 53.75,-29.946 54.875,-29.946 55.5,-30.571 v1(56,-30.571)
G0_A9: U1.W23 U2.L11 U3.L11 U4.L11 U5.L11 | length 69.9
  INT5 w0.102: v1(47.5,-26.071) 47.875,-25.696 52.625,-25.696 57,-30.071 v1(57,-30.571)
  INT8 w0.102: v1(57,-30.571) 57.5,-30.571 59.375,-28.696 59.375,-22.446 57.875,-20.946 57.875,-17.071 57.625,-16.821 57.625,-16.446 57.875,-16.196 57.875,-15.946 57,-15.071 v1(57,-14.571)
  INT2 w0.102: v1(21,-14.571) 21.375,-14.196 25.125,-14.196 25.375,-14.446 25.625,-14.446 25.875,-14.196 26.125,-14.196 26.375,-14.446 26.625,-14.446 26.875,-14.196 29.125,-14.196 29.375,-14.446 32.375,-14.446 32.625,-14.696 35.5,-14.696 35.75,-14.946 36.125,-14.946 36.375,-14.696 36.625,-14.696 36.875,-14.946 37.125,-14.946 37.375,-14.696 37.625,-14.696 37.875,-14.946 38.125,-14.946 38.375,-14.696 38.875,-14.696 v1(39,-14.571) 39.125,-14.696 39.625,-14.696 39.875,-14.946 40.125,-14.946 40.375,-14.696 40.625,-14.696 40.875,-14.946 41.125,-14.946 41.375,-14.696 41.625,-14.696 41.875,-14.946 42.125,-14.946 42.375,-14.696 42.625,-14.696 42.875,-14.946 43.125,-14.946 43.375,-14.696 43.625,-14.696 43.875,-14.946 44.125,-14.946 44.375,-14.696 44.625,-14.696 44.875,-14.946 45.125,-14.946 45.375,-14.696 45.625,-14.696 45.875,-14.946 47.125,-14.946 47.375,-14.696 53.625,-14.696 53.875,-14.946 54.125,-14.946 54.375,-14.696 54.625,-14.696 54.875,-14.946 56.125,-14.946 56.5,-14.571 v1(57,-14.571)
G0_A10: U1.W24 U2.N13 U3.N13 U4.N13 U5.N13 | length 72.7
  INT5 w0.102: v1(48.5,-26.071) 50.75,-26.071 51.125,-26.446 52.375,-26.446 56.375,-30.446 56.375,-30.696 55,-32.071 v1(55,-32.571)
  INT1 w0.102: v1(19,-16.571) 19.375,-16.946 27.125,-16.946 27.375,-16.696 27.625,-16.696 27.875,-16.946 28.125,-16.946 28.375,-16.696 28.625,-16.696 28.875,-16.946 31.125,-16.946 31.375,-16.696 33.625,-16.696 33.875,-16.946 34.125,-16.946 34.375,-16.696 34.625,-16.696 34.875,-16.946 35.125,-16.946 35.375,-16.696 35.625,-16.696 35.75,-16.821 35.875,-16.946 36.125,-16.946 36.375,-16.696 36.875,-16.696 v1(37,-16.571) 37.125,-16.696 37.625,-16.696 37.875,-16.946 38.125,-16.946 38.375,-16.696 38.625,-16.696 38.875,-16.946 39.125,-16.946 39.375,-16.696 39.625,-16.696 39.875,-16.946 40.125,-16.946 40.375,-16.696 40.625,-16.696 40.875,-16.946 43.125,-16.946 43.375,-16.696 43.625,-16.696 43.875,-16.946 44.125,-16.946 44.375,-16.696 44.625,-16.696 44.875,-16.946 46.125,-16.946 46.375,-16.696 46.625,-16.696 46.875,-16.946 47.125,-16.946 47.375,-16.696 48.625,-16.696 48.875,-16.946 49.125,-16.946 49.375,-16.696 51.625,-16.696 51.875,-16.946 52.125,-16.946 52.375,-16.696 53.625,-16.696 53.875,-16.946 54.125,-16.946 54.375,-16.696 54.875,-16.696 v1(55,-16.571) 55,-17.071 51.625,-20.446 51.625,-20.696 51.875,-20.946 51.875,-21.196 51.625,-21.446 51.625,-21.696 51.75,-21.821 51.875,-21.946 51.875,-31.946 52.875,-32.946 54.125,-32.946 54.5,-32.571 v1(55,-32.571)
G0_A11: U1.Y25 U2.M12 U3.M12 U4.M12 U5.M12 | length 70.5
  INT5 w0.102: v1(49.5,-25.071) 49.875,-24.696 52.625,-24.696 57.375,-29.446 57.375,-30.696 56.5,-31.571 v1(56,-31.571)
  INT8 w0.102: v1(56,-31.571) 56.375,-31.196 56.375,-29.696 58.125,-27.946 58.125,-24.946 58.375,-24.696 58.375,-24.446 58.125,-24.196 58.125,-23.946 58.375,-23.696 58.375,-23.446 58.25,-23.321 56.625,-21.696 56.625,-21.446 56.875,-21.196 56.875,-16.946 56.125,-16.196 56.125,-15.696 v1(56,-15.571)
  INT1 w0.102: v1(20,-15.571) 20.375,-15.196 27.125,-15.196 27.375,-15.446 27.625,-15.446 27.875,-15.196 28.125,-15.196 28.375,-15.446 28.625,-15.446 28.875,-15.196 31.125,-15.196 31.375,-15.446 35.5,-15.446 35.75,-15.196 36.125,-15.196 36.375,-15.446 36.625,-15.446 36.875,-15.196 37.125,-15.196 37.375,-15.446 37.875,-15.446 v1(38,-15.571) 38.125,-15.446 38.625,-15.446 38.875,-15.196 39.125,-15.196 39.375,-15.446 40.625,-15.446 40.875,-15.196 41.125,-15.196 41.375,-15.446 42.625,-15.446 42.875,-15.196 43.125,-15.196 43.375,-15.446 43.625,-15.446 43.875,-15.196 44.125,-15.196 44.375,-15.446 44.625,-15.446 44.875,-15.196 45.125,-15.196 45.375,-15.446 45.625,-15.446 45.875,-15.196 47.125,-15.196 47.375,-15.446 48.625,-15.446 48.875,-15.196 49.125,-15.196 49.25,-15.321 49.375,-15.446 53.625,-15.446 53.875,-15.196 54.125,-15.196 54.375,-15.446 54.625,-15.446 54.875,-15.196 55.625,-15.196 v1(56,-15.571)
G0_A12: U1.U21 U2.N10 U3.N10 U4.N10 U5.N10 | length 72.9
  INT5 w0.102: v1(45.5,-28.071) 46,-28.071 46.375,-27.696 46.625,-27.696 46.875,-27.946 47.125,-27.946 47.375,-27.696 52.625,-27.696 54.5,-29.571 v1(55,-29.571)
  INT1 w0.102: v1(19,-13.571) 19.375,-13.196 27.125,-13.196 27.375,-13.446 27.625,-13.446 27.875,-13.196 28.125,-13.196 28.375,-13.446 28.625,-13.446 28.875,-13.196 29.125,-13.196 29.375,-13.446 29.5,-13.446 35.625,-13.446 35.875,-13.196 36.125,-13.196 36.375,-13.446 36.875,-13.446 v1(37,-13.571) 37.125,-13.446 37.625,-13.446 37.875,-13.196 38.125,-13.196 38.375,-13.446 38.625,-13.446 38.875,-13.196 39.125,-13.196 39.375,-13.446 39.625,-13.446 39.875,-13.196 40.125,-13.196 40.375,-13.446 40.625,-13.446 40.875,-13.196 41.125,-13.196 41.375,-13.446 41.625,-13.446 41.875,-13.196 42.125,-13.196 42.375,-13.446 42.625,-13.446 42.875,-13.196 43.125,-13.196 43.375,-13.446 43.625,-13.446 43.875,-13.196 44.125,-13.196 44.375,-13.446 44.625,-13.446 44.875,-13.196 45.125,-13.196 45.375,-13.446 45.625,-13.446 45.875,-13.196 46.125,-13.196 46.375,-13.446 46.625,-13.446 46.875,-13.196 47.125,-13.196 47.375,-13.446 53.625,-13.446 53.875,-13.196 54.125,-13.196 54.375,-13.446 54.875,-13.446 v1(55,-13.571) 55.125,-13.446 55.625,-13.446 55.875,-13.196 56.125,-13.196 56.375,-13.446 56.625,-13.446 56.875,-13.196 57.125,-13.196 59.375,-15.446 59.375,-18.696 54.625,-23.446 54.625,-23.696 54.875,-23.946 54.875,-24.196 54.625,-24.446 54.625,-24.696 54.875,-24.946 54.875,-25.196 54.625,-25.446 54.625,-25.696 54.875,-25.946 54.875,-26.196 54.625,-26.446 54.625,-26.696 54.875,-26.946 54.875,-27.196 54.625,-27.446 54.625,-27.696 54.875,-27.946 54.875,-28.196 54.625,-28.446 54.625,-28.696 55,-29.071 v1(55,-29.571)
G0_A13: U1.U22 U2.P10 U3.P10 U4.P10 U5.P10 | length 69.6
  INT5 w0.102: v1(46.5,-28.071) 46.625,-28.196 47.125,-28.196 47.375,-28.446 52.375,-28.446 53.5,-29.571 v1(54,-29.571)
  INT1 w0.102: v1(18,-13.571) 18.375,-13.946 25.125,-13.946 25.375,-13.696 25.625,-13.696 25.875,-13.946 26.125,-13.946 26.375,-13.696 26.625,-13.696 26.875,-13.946 29.125,-13.946 29.375,-13.696 35.875,-13.696 v1(36,-13.571) 36.125,-13.696 36.625,-13.696 36.875,-13.946 37.125,-13.946 37.375,-13.696 37.625,-13.696 37.875,-13.946 38.125,-13.946 38.375,-13.696 38.625,-13.696 38.875,-13.946 39.125,-13.946 39.375,-13.696 39.625,-13.696 39.875,-13.946 40.125,-13.946 40.375,-13.696 40.625,-13.696 40.875,-13.946 41.125,-13.946 41.375,-13.696 41.625,-13.696 41.875,-13.946 42.125,-13.946 42.375,-13.696 42.625,-13.696 42.875,-13.946 43.125,-13.946 43.375,-13.696 43.625,-13.696 43.875,-13.946 44.125,-13.946 44.375,-13.696 44.625,-13.696 44.875,-13.946 45.125,-13.946 45.375,-13.696 45.625,-13.696 45.875,-13.946 46.125,-13.946 46.375,-13.696 46.625,-13.696 46.875,-13.946 47.125,-13.946 47.375,-13.696 53.875,-13.696 v1(54,-13.571) 54.125,-13.696 54.625,-13.696 54.875,-13.946 55.125,-13.946 55.375,-13.696 55.625,-13.696 55.875,-13.946 56.125,-13.946 56.375,-13.696 56.625,-13.696 58.125,-15.196 58.125,-16.196 58.375,-16.446 58.375,-16.696 58.125,-16.946 58.125,-18.946 54.375,-22.696 54.375,-23.696 54.125,-23.946 54.125,-24.196 54.375,-24.446 54.375,-24.696 54.125,-24.946 54.125,-25.196 54.375,-25.446 54.375,-25.696 54.125,-25.946 54.125,-26.196 54.375,-26.446 54.375,-26.696 54.125,-26.946 54.125,-27.196 54.375,-27.446 54.375,-27.696 54.125,-27.946 54.125,-29.446 v1(54,-29.571)
G0_A14: U1.V23 U2.M13 U3.M13 U4.M13 U5.M13 | length 71.7
  INT7 w0.102: v1(47.5,-27.071) 47.5,-27.571 51.532,-31.603 53.193,-31.603 53.661,-32.071 55.5,-32.071 v1(56,-32.571)
  INT1 w0.102: v1(20,-16.571) 20.375,-16.196 25.125,-16.196 25.375,-16.446 25.625,-16.446 25.875,-16.196 26.125,-16.196 26.375,-16.446 26.625,-16.446 26.875,-16.196 29.125,-16.196 29.375,-16.446 30.625,-16.446 30.875,-16.196 31.125,-16.196 31.375,-16.446 33.625,-16.446 33.875,-16.196 36.125,-16.196 36.375,-16.446 36.625,-16.446 36.875,-16.196 37.125,-16.196 37.375,-16.446 37.875,-16.446 v1(38,-16.571) 38.125,-16.446 38.625,-16.446 38.875,-16.196 39.125,-16.196 39.375,-16.446 39.625,-16.446 39.875,-16.196 40.125,-16.196 40.375,-16.446 41.625,-16.446 41.875,-16.196 42.125,-16.196 42.375,-16.446 42.625,-16.446 42.875,-16.196 43.125,-16.196 43.375,-16.446 43.625,-16.446 43.875,-16.196 45.125,-16.196 45.375,-16.446 45.625,-16.446 45.875,-16.196 46.125,-16.196 46.375,-16.446 46.625,-16.446 46.875,-16.196 47.125,-16.196 47.375,-16.446 48.625,-16.446 48.875,-16.196 49.125,-16.196 49.375,-16.446 51.625,-16.446 51.875,-16.196 52.125,-16.196 52.375,-16.446 53.625,-16.446 53.875,-16.196 54.125,-16.196 54.375,-16.446 54.625,-16.446 54.875,-16.196 55.125,-16.196 55.5,-16.571 v1(56,-16.571) 56,-17.071 52.125,-20.946 52.125,-21.196 52.375,-21.446 52.375,-21.696 52.125,-21.946 52.125,-31.196 53.125,-32.196 55.625,-32.196 v1(56,-32.571)
G0_A15: U1.T22 U2.L13 U3.L13 U4.L13 U5.L13 | length 74.9
  INT7 w0.102: v1(46.5,-29.071) 47,-29.071 51.125,-33.196 52.125,-33.196 52.375,-33.446 52.625,-33.446 52.875,-33.196 53.125,-33.196 53.375,-33.446 56.125,-33.446 v1(57,-32.571)
  INT2 w0.102: v1(21,-16.571) 21.375,-16.946 27.125,-16.946 27.375,-16.696 27.625,-16.696 27.875,-16.946 28.125,-16.946 28.375,-16.696 28.625,-16.696 28.875,-16.946 31.125,-16.946 31.375,-16.696 33.625,-16.696 33.875,-16.946 34.125,-16.946 34.375,-16.696 34.625,-16.696 34.875,-16.946 35.125,-16.946 35.375,-16.696 35.625,-16.696 35.875,-16.946 36.125,-16.946 36.375,-16.696 36.625,-16.696 36.875,-16.946 37.125,-16.946 37.375,-16.696 37.625,-16.696 37.875,-16.946 38.125,-16.946 38.375,-16.696 38.875,-16.696 v1(39,-16.571) 39.125,-16.696 39.625,-16.696 39.875,-16.946 40.125,-16.946 40.375,-16.696 41.625,-16.696 41.875,-16.946 43.125,-16.946 43.375,-16.696 43.625,-16.696 43.875,-16.946 44.125,-16.946 44.375,-16.696 44.625,-16.696 44.875,-16.946 46.125,-16.946 46.375,-16.696 46.625,-16.696 46.875,-16.946 47.125,-16.946 47.375,-16.696 48.625,-16.696 48.875,-16.946 49.125,-16.946 49.375,-16.696 51.625,-16.696 51.875,-16.946 52.125,-16.946 52.375,-16.696 53.625,-16.696 53.875,-16.946 54.125,-16.946 54.375,-16.696 54.625,-16.696 54.875,-16.946 55.125,-16.946 55.375,-16.696 55.625,-16.696 55.875,-16.946 56.125,-16.946 56.375,-16.696 56.875,-16.696 v1(57,-16.571) 57,-17.196 56.5,-17.696 54.375,-17.696 52.875,-19.196 52.875,-20.196 52.625,-20.446 52.625,-20.696 52.875,-20.946 52.875,-21.196 52.125,-21.946 52.125,-26.196 53.125,-27.196 54.125,-27.196 56.625,-29.696 56.625,-31.696 57,-32.071 v1(57,-32.571)
G0_A16: U1.T23 U2.P6 U3.P6 U4.P6 U5.P6 | length 67.9
  INT8 w0.102: v1(47.5,-29.071) 49.5,-29.071 50.375,-28.196 50.375,-27.196 51.125,-26.446 53.125,-26.446 v1(54,-25.571)
  INT1 w0.102: v6(18,-9.571) 18.375,-9.946 21.421,-9.946 21.685,-9.682 22.207,-9.682 22.47,-9.946 35.625,-9.946 v1(36,-9.571) 36.375,-9.946 53.625,-9.946 v1(54,-9.571)
  INT2 w0.102: v1(54,-25.571) 54.125,-25.446 54.125,-24.946 54.375,-24.696 54.375,-24.446 54.125,-24.196 54.125,-23.946 54.375,-23.696 54.375,-22.446 54.125,-22.196 54.125,-21.946 54.375,-21.696 54.375,-21.446 54.125,-21.196 54.125,-20.946 55.625,-19.446 57.625,-19.446 59.375,-17.696 59.375,-14.446 54.5,-9.571 v1(54,-9.571)
G0_A17: U1.V21 U2.N6 U3.N6 U4.N6 U5.N6 | length 71.5
  INT8 w0.102: v1(45.5,-27.071) 45.625,-27.196 45.625,-27.696 47.375,-29.446 49.5,-29.446 50.625,-28.321 50.625,-27.446 51.375,-26.696 53.375,-26.696 54.375,-25.696 54.875,-25.696 v1(55,-25.571)
  INT1 w0.102: v6(19,-9.571) 19.375,-9.196 36.625,-9.196 v1(37,-9.571) 37.375,-9.196 54.625,-9.196 v1(55,-9.571)
  INT2 w0.102: v1(55,-25.571) 55,-25.071 54.625,-24.696 54.625,-24.446 54.875,-24.196 54.875,-23.946 54.625,-23.696 54.625,-22.446 54.875,-22.196 54.875,-21.946 54.625,-21.696 54.625,-21.446 56.375,-19.696 58.375,-19.696 59.625,-18.446 59.625,-13.696 55.5,-9.571 v1(55,-9.571)
G0_A18: U1.W21 U2.N11 U3.N11 U4.N11 U5.N11 | length 73.7
  INT5 w0.102: v1(45.5,-26.071) 45.5,-26.571 45.125,-26.946 45.125,-27.196 45.375,-27.446 45.375,-27.696 45.125,-27.946 45.125,-28.196 47.375,-30.446 53.5,-30.446 53.75,-30.196 54.625,-30.196 v1(55,-30.571)
  INT1 w0.102: v1(19,-14.571) 19.375,-14.946 27.125,-14.946 27.375,-14.696 27.625,-14.696 27.875,-14.946 28.125,-14.946 28.375,-14.696 28.625,-14.696 28.875,-14.946 31.125,-14.946 31.375,-14.696 35.625,-14.696 35.875,-14.946 36.125,-14.946 36.375,-14.696 36.875,-14.696 v1(37,-14.571) 37.125,-14.696 37.625,-14.696 37.875,-14.946 38.125,-14.946 38.375,-14.696 38.625,-14.696 38.875,-14.946 39.125,-14.946 39.375,-14.696 39.625,-14.696 39.875,-14.946 40.125,-14.946 40.375,-14.696 40.625,-14.696 40.875,-14.946 41.125,-14.946 41.375,-14.696 41.625,-14.696 41.875,-14.946 42.125,-14.946 42.375,-14.696 42.625,-14.696 42.875,-14.946 43.125,-14.946 43.375,-14.696 43.625,-14.696 43.875,-14.946 44.125,-14.946 44.375,-14.696 44.625,-14.696 44.875,-14.946 45.125,-14.946 45.375,-14.696 45.625,-14.696 45.875,-14.946 47.125,-14.946 47.375,-14.696 53.625,-14.696 53.875,-14.946 54.125,-14.946 54.375,-14.696 54.875,-14.696 v1(55,-14.571) 55.375,-14.946 55.875,-14.946 57.375,-16.446 57.375,-16.696 57.125,-16.946 57.125,-17.946 53.125,-21.946 53.125,-30.321 53.75,-30.946 54.125,-30.946 54.5,-30.571 v1(55,-30.571)
G0_A19: U1.Y21 U2.L12 U3.L12 U4.L12 U5.L12 | length 77
  INT5 w0.102: v1(45.5,-25.071) 45.5,-25.571 44.625,-26.446 44.625,-26.696 44.875,-26.946 44.875,-27.196 44.625,-27.446 44.625,-27.696 44.875,-27.946 44.875,-28.196 44.625,-28.446 44.625,-28.696 46.875,-30.946 47.125,-30.946 47.375,-30.696 52.625,-30.696 54.875,-32.946 56.125,-32.946 57,-32.071 v1(57,-31.571)
  INT8 w0.102: v1(57,-31.571) 56.625,-31.196 56.625,-30.446 58.875,-28.196 58.875,-23.946 58.625,-23.696 58.625,-23.446 58.875,-23.196 58.875,-22.946 57.125,-21.196 57.125,-16.946 57.375,-16.696 57.375,-16.446 57,-16.071 v1(57,-15.571)
  INT2 w0.102: v1(21,-15.571) 21.375,-15.196 27.125,-15.196 27.375,-15.446 27.625,-15.446 27.875,-15.196 28.125,-15.196 28.375,-15.446 28.625,-15.446 28.875,-15.196 31.125,-15.196 31.375,-15.446 35.5,-15.446 35.75,-15.196 36.125,-15.196 36.375,-15.446 36.625,-15.446 36.875,-15.196 37.125,-15.196 37.375,-15.446 37.625,-15.446 37.875,-15.196 38.125,-15.196 38.375,-15.446 38.875,-15.446 v1(39,-15.571) 39.125,-15.446 40.625,-15.446 40.875,-15.196 41.125,-15.196 41.375,-15.446 42.625,-15.446 42.875,-15.196 43.125,-15.196 43.375,-15.446 43.625,-15.446 43.875,-15.196 44.125,-15.196 44.375,-15.446 44.625,-15.446 44.875,-15.196 45.125,-15.196 45.375,-15.446 45.625,-15.446 45.875,-15.196 47.125,-15.196 47.375,-15.446 48.625,-15.446 48.875,-15.196 49.125,-15.196 49.375,-15.446 53.625,-15.446 53.875,-15.196 54.125,-15.196 54.375,-15.446 54.625,-15.446 54.875,-15.196 56.125,-15.196 56.5,-15.571 v1(57,-15.571)
G0_A20: U1.V27 U2.P12 U3.P12 U4.P12 U5.P12 | length 64.8
  INT8 w0.102: v1(51.5,-27.071) 51.5,-27.571 53.625,-29.696 53.625,-31.196 v1(54,-31.571)
  INT1 w0.102: v1(18,-15.571) 18.375,-15.946 25.125,-15.946 25.375,-15.696 25.625,-15.696 25.875,-15.946 26.125,-15.946 26.375,-15.696 26.625,-15.696 26.875,-15.946 29.125,-15.946 29.375,-15.696 30.625,-15.696 30.875,-15.946 31.125,-15.946 31.375,-15.696 35.875,-15.696 v1(36,-15.571) 36.125,-15.696 36.625,-15.696 36.875,-15.946 37.125,-15.946 37.375,-15.696 37.625,-15.696 37.875,-15.946 38.125,-15.946 38.375,-15.696 38.625,-15.696 38.875,-15.946 39.125,-15.946 39.375,-15.696 40.625,-15.696 40.875,-15.946 41.125,-15.946 41.375,-15.696 42.625,-15.696 42.875,-15.946 43.125,-15.946 43.375,-15.696 43.625,-15.696 43.875,-15.946 45.125,-15.946 45.375,-15.696 45.625,-15.696 45.75,-15.821 45.875,-15.946 46.125,-15.946 46.375,-15.696 46.625,-15.696 46.875,-15.946 47.125,-15.946 47.375,-15.696 48.625,-15.696 48.875,-15.946 49.125,-15.946 49.375,-15.696 53.875,-15.696 v1(54,-15.571) 54.125,-15.696 54.625,-15.696 54.875,-15.946 55.125,-15.946 55.375,-15.696 55.625,-15.696 56.875,-16.946 56.875,-17.196 52.875,-21.196 52.875,-30.446 v1(54,-31.571)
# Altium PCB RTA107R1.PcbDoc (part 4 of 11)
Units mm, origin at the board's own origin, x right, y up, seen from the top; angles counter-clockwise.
Board outline 96.01 x 65.66 mm, 22 copper layers (Top Layer, GND1, INT1, PWR1-(VCCIO_MRAM), INT2, PWR2-(VCCINT), INT3, PWR3_(12V_MGTAVCC), INT4, GND2-(DGND_SGND), PWR4_(MGTAVTT_VCCBRAM,VCCAUX), PWR5-(VCC_12V), GND3-(DGND_GND), INT5, GND4, INT6, PWR6_(VCCO), INT7, GND5, INT8, GND6, Bottom Layer), stack 2.833 mm thick; 614 components, 659 nets, 4037 pads, 3511 vias.

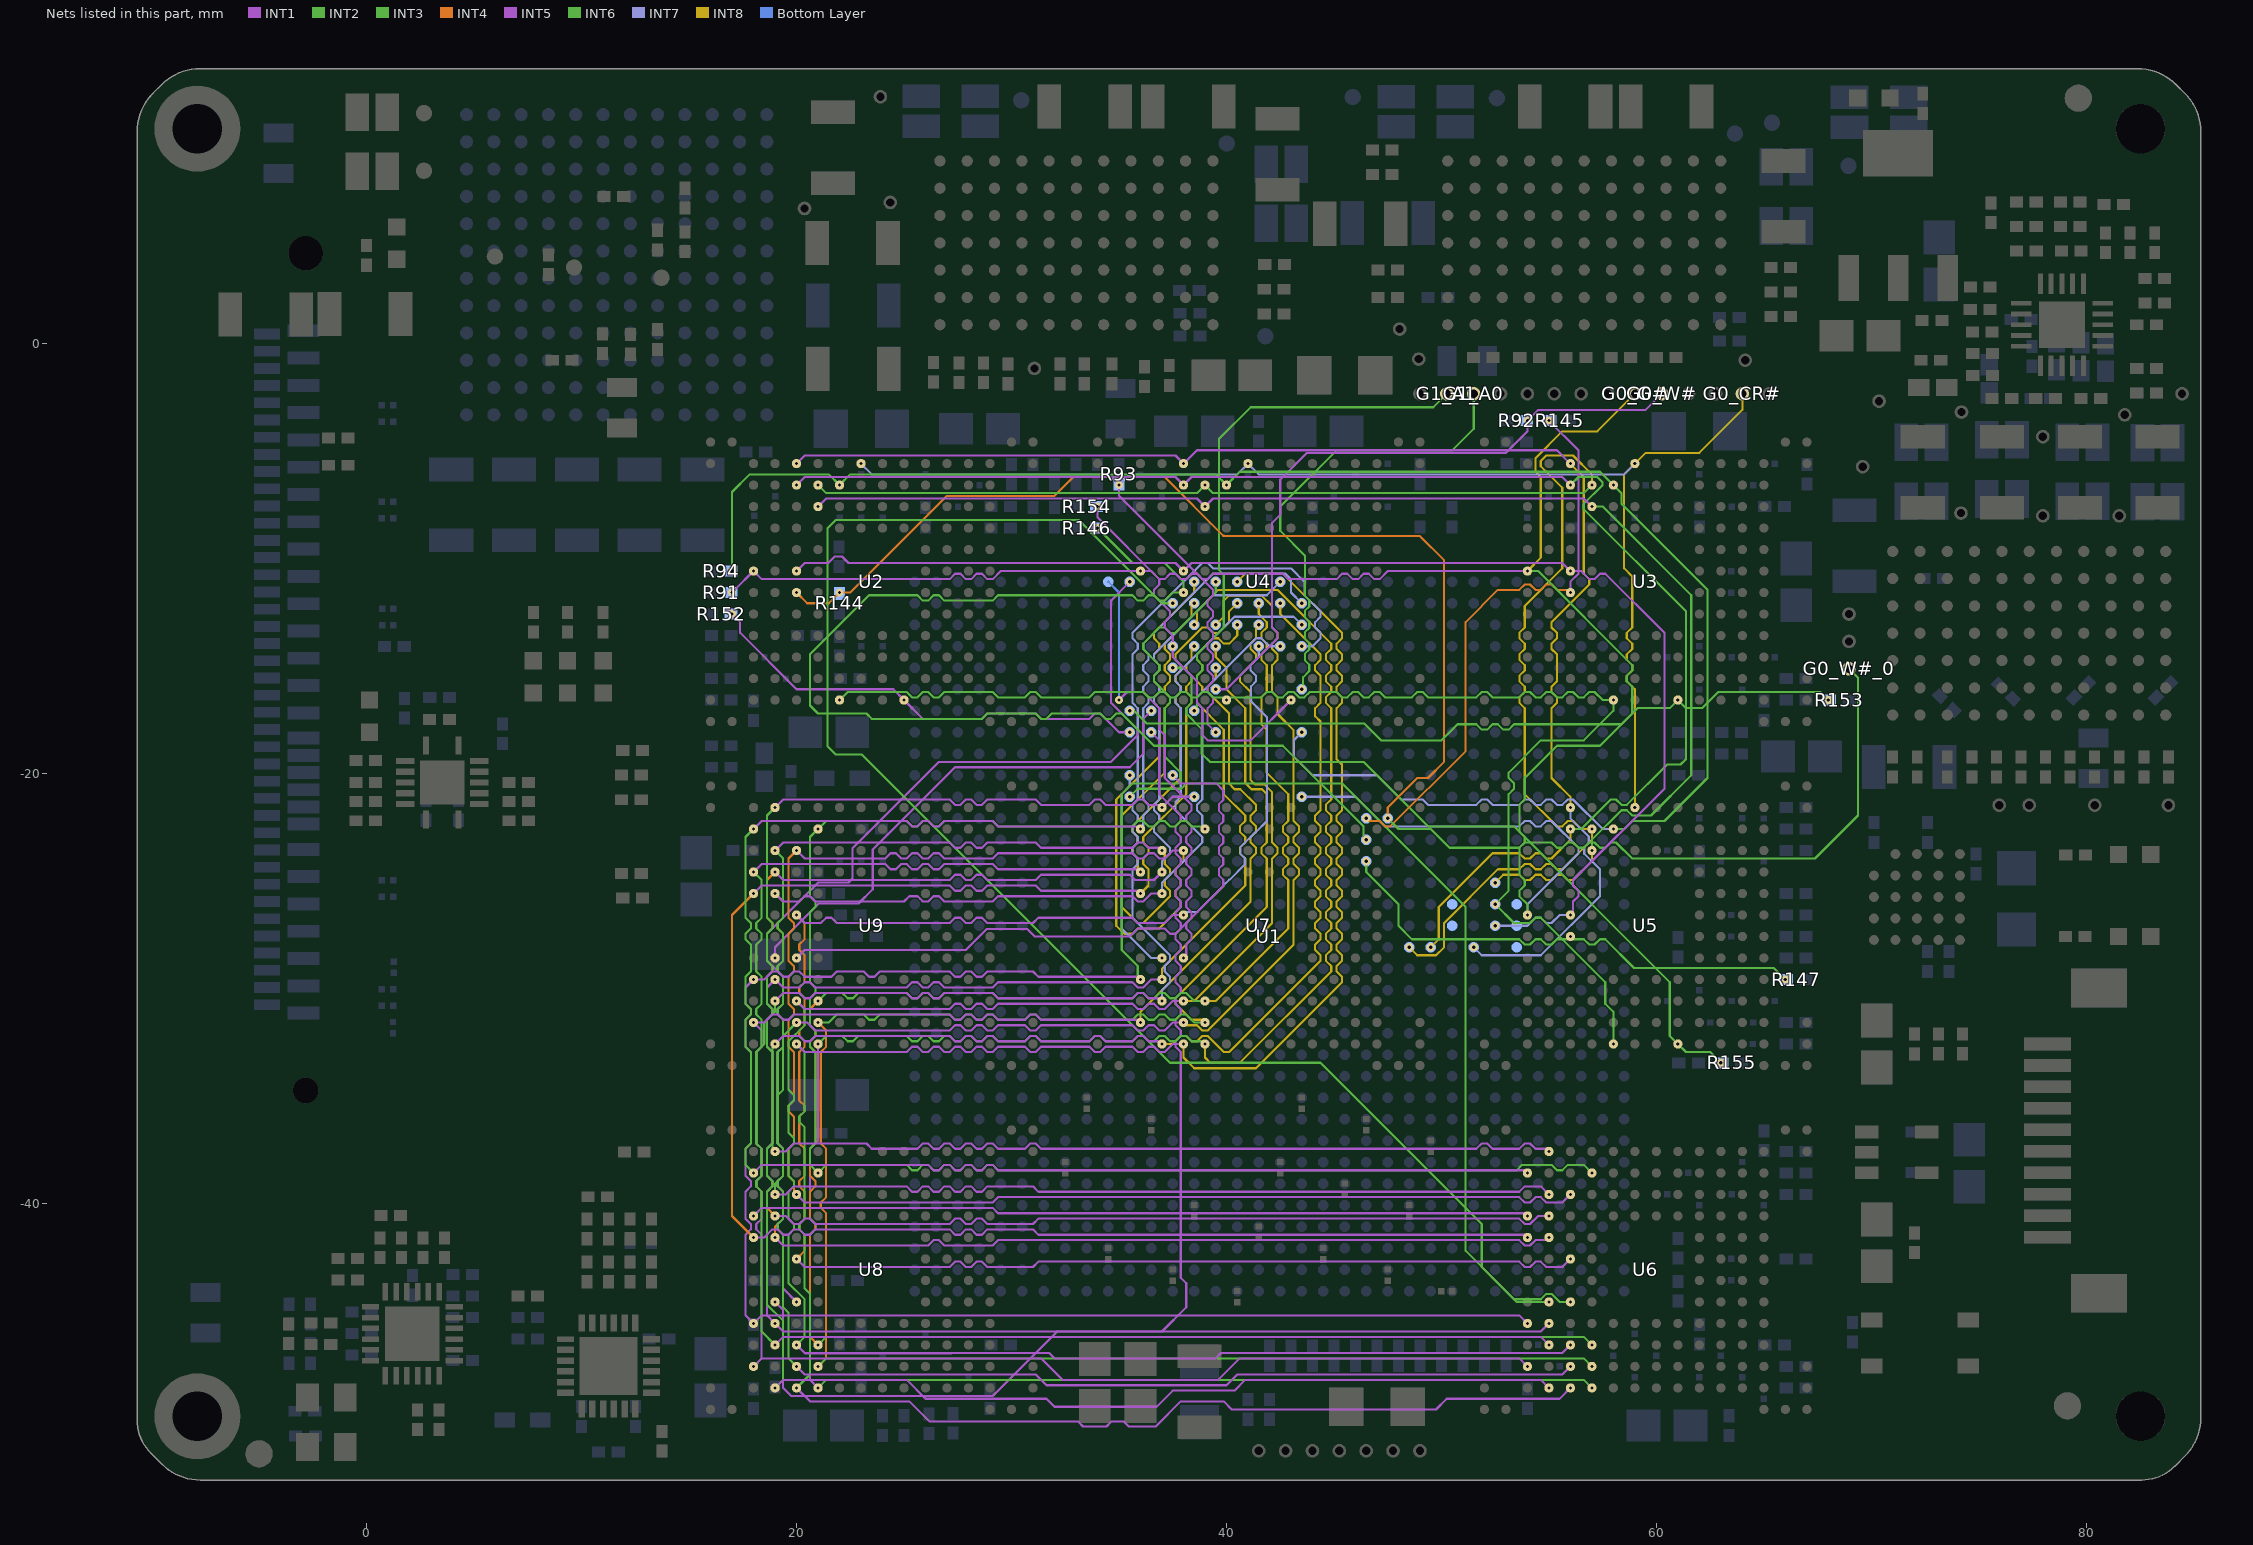
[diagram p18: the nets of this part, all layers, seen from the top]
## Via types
v1: diameter 0.381, hole 0.152, Top Layer to Bottom Layer, tented both sides, 2009 vias
v2: diameter 0.508, hole 0.254, Top Layer to Bottom Layer, tented both sides, 467 vias
v3: diameter 0.406, hole 0.203, Top Layer to Bottom Layer, 458 vias
v4: diameter 0.508, hole 0.254, Top Layer to Bottom Layer, 239 vias
v5: diameter 0.406, hole 0.203, Top Layer to Bottom Layer, tented both sides, 181 vias
v6: diameter 0.381, hole 0.152, Top Layer to GND4, tented both sides, 147 vias
v7: diameter 0.406, hole 0.203, Top Layer to GND4, tented both sides, 10 vias

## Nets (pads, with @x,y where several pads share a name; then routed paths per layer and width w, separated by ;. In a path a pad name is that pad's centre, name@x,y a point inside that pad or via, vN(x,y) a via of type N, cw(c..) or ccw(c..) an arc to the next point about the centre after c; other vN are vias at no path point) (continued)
G0_A21: U1.V28 U2.M7 U3.M7 U4.M7 U5.M7 | length 61.7
  INT7 w0.102: v1(52.5,-27.071) 54,-27.071 54.375,-26.696 54.625,-26.696 54.875,-26.946 55.125,-26.946 55.5,-26.571 v1(56,-26.571)
  INT1 w0.102: v1(20,-10.571) 20.375,-10.196 21.473,-10.196 21.773,-9.896 22.118,-9.896 22.418,-10.196 37.625,-10.196 v1(38,-10.571) 38.375,-10.196 55.625,-10.196 v1(56,-10.571) 56.5,-10.571 56.875,-10.946 57.125,-10.946 57.375,-10.696 57.625,-10.696 60.375,-13.446 60.375,-20.696 56.125,-24.946 56.125,-25.196 56.375,-25.446 56.375,-25.696 56.125,-25.946 56.125,-26.446 v1(56,-26.571)
G0_A22: U1.U24 U2.L3 U3.L3 U4.L3 U5.L3 | length 73.9
  INT8 w0.102: v1(48.5,-28.071) 48.875,-28.446 49.75,-28.446 50.125,-28.071 50.125,-26.946 52.625,-24.446 53.625,-24.446 53.875,-24.196 54.125,-24.196 54.375,-24.446 54.625,-24.446 54.875,-24.196 55.125,-24.196 55.375,-24.446 55.625,-24.446 57,-23.071 v1(57,-22.571) 56.5,-22.571 56.125,-22.196 55.875,-22.196 55.625,-22.446 55.375,-22.446 53.875,-20.946 53.875,-16.946 53.625,-16.696 53.625,-16.446 53.875,-16.196 53.875,-15.946 53.625,-15.696 53.625,-15.446 53.875,-15.196 53.875,-14.946 53.625,-14.696 53.625,-14.446 53.875,-14.196 53.875,-13.946 53.625,-13.696 53.625,-13.446 53.875,-13.196 53.875,-12.196 55.625,-10.446 55.625,-6.696 54.625,-5.696 54.625,-5.446 54.875,-5.196 56.125,-5.196 57,-6.071 v1(57,-6.571)
  INT2 w0.102: v1(21,-6.571) 21.375,-6.946 38.625,-6.946 v1(39,-6.571) 39.375,-6.946 56.625,-6.946 v1(57,-6.571)
G0_A23: U1.U25 U2.M3 U3.M3 U4.M3 U5.M3 | length 70.9
  INT8 w0.102: v1(49.5,-28.071) 49.875,-27.696 49.875,-26.196 52.375,-23.696 53.625,-23.696 53.875,-23.946 54.125,-23.946 54.375,-23.696 54.625,-23.696 54.875,-23.946 55.125,-23.946 56,-23.071 v1(56,-22.571)
  INT1 w0.102: v1(20,-6.571) 20.375,-6.196 37.625,-6.196 v1(38,-6.571) 38.375,-6.196 55.625,-6.196 v1(56,-6.571)
  INT2 w0.102: v1(56,-22.571) 56.5,-22.571 57.75,-21.321 57.875,-21.196 58.125,-21.196 58.375,-21.446 58.625,-21.446 60.5,-19.571 61.125,-19.571 61.375,-19.321 61.375,-12.446 56.625,-7.696 56.625,-7.446 57.5,-6.571 57.5,-6.446 57.25,-6.196 56.375,-6.196 v1(56,-6.571)
G0_A24: U1.W28 U2.K13 U3.K13 U4.K13 U5.K13 | length 63.2
  INT2 w0.102: v1(22,-16.571) 22.375,-16.196 25.125,-16.196 25.375,-16.446 25.625,-16.446 25.875,-16.196 26.125,-16.196 26.375,-16.446 26.625,-16.446 26.875,-16.196 29.125,-16.196 29.375,-16.446 30.625,-16.446 30.875,-16.196 31.125,-16.196 31.375,-16.446 33.625,-16.446 33.875,-16.196 36.125,-16.196 36.375,-16.446 36.625,-16.446 36.875,-16.196 37.125,-16.196 37.375,-16.446 37.625,-16.446 37.875,-16.196 38.125,-16.196 38.375,-16.446 38.625,-16.446 38.875,-16.196 39.125,-16.196 39.375,-16.446 39.875,-16.446 v1(40,-16.571) 40.125,-16.446 41.625,-16.446 41.875,-16.196 42.125,-16.196 42.375,-16.446 42.625,-16.446 42.875,-16.196 43.125,-16.196 43.375,-16.446 43.625,-16.446 43.875,-16.196 45.125,-16.196 45.375,-16.446 45.625,-16.446 45.875,-16.196 46.125,-16.196 46.375,-16.446 46.625,-16.446 46.875,-16.196 47.125,-16.196 47.375,-16.446 48.625,-16.446 48.875,-16.196 49.125,-16.196 49.375,-16.446 51.625,-16.446 51.875,-16.196 52.125,-16.196 52.375,-16.446 53.625,-16.446 53.875,-16.196 54.125,-16.196 54.375,-16.446 54.625,-16.446 54.875,-16.196 55.125,-16.196 55.375,-16.446 55.625,-16.446 55.875,-16.196 56.125,-16.196 56.375,-16.446 56.625,-16.446 56.875,-16.196 57.125,-16.196 57.5,-16.571 v1(58,-16.571) 58,-17.071 56.625,-18.446 54.625,-18.446 53.125,-19.946 53.125,-20.196 53.375,-20.446 53.375,-20.696 53.125,-20.946 53.125,-25.446 v1(52.5,-26.071) 53.375,-26.946 54.125,-26.946 54.375,-26.696 54.625,-26.696 57.625,-29.696 57.625,-30.696 58,-31.071 v1(58,-32.571)
G0_A25: U1.Y28 U2.L4 U3.L4 U4.L4 U5.L4 | length 63.9
  INT8 w0.102: v1(52.5,-25.071) 52.875,-24.696 53.625,-24.696 53.875,-24.946 54.125,-24.946 54.375,-24.696 54.625,-24.696 54.875,-24.946 55.125,-24.946 55.375,-24.696 55.625,-24.696 55.875,-24.946 56.125,-24.946 57,-24.071 v1(57,-23.571)
  INT1 w0.102: v1(21,-7.571) 21.375,-7.196 38.625,-7.196 v1(39,-7.571) 39.375,-7.196 56.625,-7.196 v1(57,-7.571)
  INT2 w0.102: v1(57,-23.571) 57,-23.071 58.375,-21.696 58.625,-21.696 58.875,-21.946 59.75,-21.946 61.625,-20.071 61.625,-11.696 57.5,-7.571 v1(57,-7.571)
G0_A26: U1.U27 U2.M2 U3.M2 U4.M2 U5.M2 | length 66.9
  INT7 w0.102: v1(51.5,-28.071) 51.875,-28.446 54.625,-28.446 57.379,-25.692 57.379,-24.449 56.647,-23.717 56.647,-23.423 56.853,-23.217 56.853,-22.925 56.842,-22.914 56,-22.071 v1(56,-21.571)
  INT8 w0.102: v1(56,-21.571) 56,-21.071 55.125,-20.196 55.125,-16.946 55.375,-16.696 55.375,-16.446 55.125,-16.196 55.125,-15.946 55.375,-15.696 55.375,-14.446 55.125,-14.196 55.125,-13.946 55.375,-13.696 55.375,-13.446 55.125,-13.196 55.125,-12.946 56.875,-11.196 56.875,-10.946 56.625,-10.696 56.625,-6.196 v1(56,-5.571)
  INT1 w0.102: v1(20,-5.571) 20.375,-5.196 37.625,-5.196 v1(38,-5.571) 38.625,-4.946 55.375,-4.946 v1(56,-5.571)
G0_A27: U1.V29
G0_A28: U1.W29
G0_A29: U1.V26
G0_A30: U1.W26
G0_A31: U1.U29
G0_CR#: G0_CR#.1 R93.2 U1.AG15 U2.J2 U3.J2 U4.J2 U5.J2 | length 75.7
  INT5 w0.102: v1(35,-6.571) 35,-7.071 39.375,-11.446 39.375,-11.696 39.125,-11.946 39.125,-12.196 39.375,-12.446 39.375,-12.696 39.125,-12.946 39.125,-13.196 39.375,-13.446 39.375,-13.696 39.125,-13.946 39.125,-14.196 39.375,-14.446 39.375,-14.696 39.125,-14.946 39.125,-15.196 39.375,-15.446 39.375,-15.696 39.125,-15.946 39.125,-16.196 39.375,-16.446 39.375,-16.696 39.125,-16.946 39.125,-17.696 v1(39.5,-18.071)
  INT7 w0.102: v1(23,-5.571) 23.5,-6.071 34.5,-6.071 v1(35,-6.571) 35.5,-6.071 40.5,-6.071 v1(41,-5.571) 41.5,-6.071 58.5,-6.071 v1(59,-5.571)
  INT8 w0.102: v1(59,-21.571) 59,-16.071 58.625,-15.696 58.625,-15.446 58.875,-15.196 58.875,-14.946 58.625,-14.696 58.625,-14.446 58.875,-14.196 58.875,-13.946 58.625,-13.696 58.625,-13.446 58.875,-13.196 58.875,-10.821 58.5,-10.446 58.5,-6.071 v1(59,-5.571) 59.5,-5.071 62,-5.071 64,-3.071 G0_CR#.1@64,-2.321
G0_G#: G0_G#.1 R91.2 U1.AD19 U2.P7 U3.P7 U4.P7 U5.P7 | length 91.7
  INT7 w0.102: v1(43.5,-21.071) 46,-21.071 47.375,-22.446 53.625,-22.446 53.875,-22.196 54.125,-22.196 54.375,-22.446 54.625,-22.446 54.875,-22.196 55.125,-22.196 56.375,-23.446 56.375,-23.696 54,-26.071 v1(54,-26.571)
  INT8 w0.102: v1(54,-10.571) 54.625,-9.946 54.625,-6.196 54.375,-5.946 54.375,-5.321 55.625,-4.071 57.25,-4.071 G0_G#.1@59,-2.321
  INT1 w0.102: v1@17.125,-11.571 17.125,-11.446 v1(18,-10.571) 18.375,-10.946 27.125,-10.946 27.375,-10.696 27.625,-10.696 27.875,-10.946 28.125,-10.946 28.375,-10.696 28.625,-10.696 28.875,-10.946 29.125,-10.946 29.5,-10.571 v1(36,-10.571) 36.5,-10.571 36.875,-10.946 37.125,-10.946 37.375,-10.696 37.625,-10.696 37.75,-10.821 37.875,-10.946 38.125,-10.946 38.375,-10.696 38.625,-10.696 38.875,-10.946 39.125,-10.946 39.375,-10.696 42.625,-10.696 42.875,-10.946 45.125,-10.946 45.375,-10.696 45.625,-10.696 45.875,-10.946 46.125,-10.946 46.375,-10.696 46.625,-10.696 46.875,-10.946 47.125,-10.946 47.5,-10.571 v1(54,-10.571)
  INT2 w0.102: v1(54,-26.571) 54,-26.071 53.625,-25.696 53.625,-25.446 53.75,-25.321 53.875,-25.196 53.875,-24.946 53.625,-24.696 53.625,-23.446 53.875,-23.196 53.875,-22.946 53.625,-22.696 53.625,-21.446 53.875,-21.196 53.875,-20.196 55.375,-18.696 57.375,-18.696 58.875,-17.196 58.875,-15.946 58.625,-15.696 58.625,-15.446 58.875,-15.196 58.875,-14.946 54.5,-10.571 v1(54,-10.571)
  other v1: 17,-11.571
G0_INT#_0: R152.2 U1.AG11 U2.G13 | length 21.5
  INT5 w0.102: v1(17,-12.571) 17.375,-12.946 17.375,-13.446 20,-16.071 24.5,-16.071 v1(25,-16.571) 25.875,-17.446 28.625,-17.446 28.875,-17.196 31.125,-17.196 31.375,-17.446 33.625,-17.446 33.875,-17.196 34.125,-17.196 35,-18.071 v1(35.5,-18.071)
G0_INT#_1: R153.2 U1.AH11 U3.G13 | length 34.9
  INT3 w0.102: v1(35.5,-17.071) 35.698,-17.071 36.29,-17.663 46.41,-17.663 47.193,-18.446 50,-18.446 50.75,-17.696 51.625,-17.696 51.875,-17.946 52.125,-17.946 52.375,-17.696 52.625,-17.696 52.875,-17.946 53.125,-17.946 53.375,-17.696 58.375,-17.696 59.125,-16.946 60.625,-16.946 v1(61,-16.571) 61.375,-16.946 62.125,-16.946 62.875,-16.196 67.625,-16.196 v1(68,-16.571)
G0_INT#_2: R154.2 U1.AL13 U4.G13 | length 18.1
  INT5 w0.102: v1(34,-7.571) 34,-8.071 36.875,-10.946 36.875,-11.196 36.625,-11.446 36.625,-11.696 37.375,-12.446 37.375,-12.696 37.125,-12.946 37.125,-13.196 37.5,-13.571 v1(37.5,-14.071) 37.5,-14.571 38.625,-15.696 38.625,-16.696 38.875,-16.946 38.875,-18.196 39.125,-18.446 41.125,-18.446 v1(43,-16.571)
G0_INT#_3: R155.2 U1.AK13 U5.G13 | length 36.6
  INT6 w0.102: v1(37.5,-15.071) 38,-15.071 38.375,-15.446 38.375,-16.696 38.125,-16.946 38.125,-17.196 38.853,-17.924 38.853,-19.066 39.233,-19.446 46.375,-19.446 49.375,-22.446 53.375,-22.446 60.625,-29.696 60.625,-32.196 v1(61,-32.571) 61.375,-32.946 62.5,-32.946 v1(63,-33.446)
G0_PG#: R94.2 U1.AG19 U2.K3 U3.K3 U4.K3 U5.K3 | length 85.3
  INT7 w0.102: v1(43.5,-18.071) 43.139,-18.432 43.139,-19.21 44,-20.071 47,-20.071 48.125,-21.196 49.125,-21.196 49.375,-21.446 51.625,-21.446 51.875,-21.196 52.125,-21.196 52.375,-21.446 53.625,-21.446 53.875,-21.196 54.125,-21.196 54.375,-21.446 54.625,-21.446 54.875,-21.196 55.125,-21.196 55.375,-21.446 55.625,-21.446 55.875,-21.196 56.125,-21.196 57.5,-22.571 v1(58,-22.571)
  INT2 w0.102: v1(17,-10.571) 17,-6.895 17.824,-6.071 21.5,-6.071 v1(22,-6.571) 22.5,-6.071 39.5,-6.071 v1(40,-6.571) 40.625,-5.946 57.375,-5.946 v1(58,-6.571) 58.375,-6.946 58.375,-7.446 62.375,-11.446 62.375,-20.196 60.375,-22.196 58.875,-22.196 58.5,-22.571 v1(58,-22.571)
G0_W#: G0_W#.1 R92.2 U1.AJ15 | length 31.2
  INT5 w0.102: v1(39.5,-16.071) 40,-16.071 42.375,-13.696 42.375,-13.446 42.125,-13.196 42.125,-8.321 42.5,-7.946 42.5,-6.321 43.75,-5.071 53,-5.071 54,-4.071 v1(54,-3.571) 54.5,-3.071 58.25,-3.071 59.5,-3.071 G0_W#.1@60.25,-2.321
G0_W#_0: G0_W#_0.1 R144.2 U1.AC23 U2.M8 | length 79.1
  INT4 w0.102: v1(20,-11.571) 20.5,-12.071 21.5,-12.071 v1(22,-11.571) 22.5,-11.571 27,-7.071 32,-7.071 32.875,-6.196 37.124,-6.196 39.852,-8.924 39.887,-8.924 39.909,-8.946 49,-8.946 50.125,-10.071 50.125,-19.446 49.375,-20.196 48.875,-20.196 47.5,-21.571 v1(47.5,-22.071)
  INT3 w0.102: v1(47.5,-22.071) 48,-22.571 49.5,-22.571 50.375,-23.446 53.625,-23.446 53.875,-23.196 55.125,-23.196 55.375,-23.446 55.625,-23.446 55.875,-23.196 56.125,-23.196 56.375,-23.446 56.625,-23.446 56.875,-23.196 57.125,-23.196 57.375,-23.446 57.625,-23.446 57.875,-23.196 58.125,-23.196 58.875,-23.946 67.375,-23.946 69.375,-21.946 69.375,-15.527 G0_W#_0.1@68.961,-15.113
G0_W#_1: R145.2 U1.AC22 U3.M8 | length 26.9
  INT5 w0.102: v1(55,-3.571) 56.375,-4.946 56.375,-10.696 56,-11.071 v1(56,-11.571)
  INT4 w0.102: v1(46.5,-22.071) 46.625,-22.196 47.125,-22.196 47.375,-22.446 47.625,-22.446 51.125,-18.946 51.125,-12.946 52.625,-11.446 53.625,-11.446 53.875,-11.196 54.125,-11.196 54.375,-11.446 54.625,-11.446 54.875,-11.196 55.125,-11.196 55.375,-11.446 55.875,-11.446 v1(56,-11.571)
G0_W#_2: R146.2 U1.AB22 U4.M8 | length 56.7
  INT2 w0.102: v1(34,-8.571) 35.625,-10.196 37.125,-10.196 38,-11.071 v1(38,-11.571) 37.5,-11.571 37.125,-11.946 36.875,-11.946 36.625,-11.696 36.375,-11.696 36.125,-11.946 35.875,-11.946 35.625,-11.696 29.375,-11.696 29.125,-11.946 26.875,-11.946 26.625,-11.696 26.375,-11.696 26.125,-11.946 25.875,-11.946 25.625,-11.696 23.375,-11.696 20.625,-14.446 20.625,-16.821 21,-17.196 23.25,-17.196 23.5,-17.446 28.625,-17.446 28.875,-17.196 31.125,-17.196 31.375,-17.446 31.625,-17.446 31.875,-17.196 34.125,-17.196 34.375,-17.446 34.625,-17.446 34.875,-17.196 35.125,-17.196 36.625,-18.696 42.625,-18.696 46.375,-22.446 46.375,-22.946 v1(46.5,-23.071)
G0_W#_3: R147.2 U1.AA22 U5.M8 | length 23.4
  INT3 w0.102: v1(46.5,-24.071) 46.5,-24.571 48,-26.071 48,-27.071 48.625,-27.696 53.625,-27.696 53.875,-27.946 54.125,-27.946 54.375,-27.696 54.625,-27.696 54.875,-27.946 55.125,-27.946 55.375,-27.696 55.875,-27.696 v1(56,-27.571) 56.125,-27.696 56.625,-27.696 56.875,-27.946 57.125,-27.946 57.375,-27.696 57.625,-27.696 58.961,-29.032 65.461,-29.032 v1(66,-29.571)
G1_A0: G1_A0.1 U1.AJ19 | length 21.8
  INT6 w0.102: v1(43.5,-16.071) 43.566,-16.005 43.566,-15.504 43.853,-15.217 43.853,-14.923 43.647,-14.717 43.647,-14.423 43.853,-14.217 43.853,-13.923 43.647,-13.717 43.647,-13.423 43.853,-13.217 43.853,-12.923 43.647,-12.717 43.647,-12.423 43.853,-12.217 43.853,-11.923 43.647,-11.717 43.647,-9.843 42.5,-8.696 42.5,-7.571 45.125,-4.946 50.5,-4.946 51.5,-3.946 G1_A0.1@51.5,-2.321
G1_A0_0: U1.AN13 U6.M9 | length 74.6
  INT3 w0.102: v1(37.5,-12.071) 37,-12.071 33.125,-8.196 21.827,-8.196 21.438,-8.585 21.438,-18.72 21.819,-19.101 23.03,-19.101 37.375,-33.446 44.375,-33.446 51.875,-40.946 51.875,-42.946 53.375,-44.446 54.625,-44.446 54.875,-44.196 55.125,-44.196 55.5,-44.571 v1(56,-44.571)
G1_A0_1: U1.AP10 U7.M9 | length 21.7
  INT5 w0.102: v1(35,-16.571) 35.375,-16.196 36.125,-16.196 36.875,-16.946 36.875,-17.946 37.125,-18.196 37.125,-20.196 38.375,-21.446 38.375,-21.696 38.125,-21.946 38.125,-22.196 38.375,-22.446 38.375,-22.696 38.125,-22.946 38.125,-23.196 38.375,-23.446 38.375,-23.696 38.125,-23.946 38.125,-24.196 38.375,-24.446 38.375,-24.696 38.125,-24.946 38.125,-25.196 38.375,-25.446 38.375,-25.696 38.125,-25.946 38.125,-26.196 38.375,-26.446 38.375,-26.696 38.125,-26.946 38.125,-27.196 38.375,-27.446 38.375,-27.696 38.125,-27.946 38.125,-28.446 v1(38,-28.571)
  Bottom Layer w0.102: U1.AP10@34.5,-11.071 35,-11.571 v1(35,-16.571)
G1_A0_2: U1.AP11 U8.M9 | length 48.4
  INT5 w0.102: v6(20,-44.571) 19.375,-43.946 19.375,-41.446 19.125,-41.196 19.125,-40.946 19.375,-40.696 19.375,-39.446 19.125,-39.196 19.125,-38.946 19.375,-38.696 19.375,-37.446 19.125,-37.196 19.125,-32.946 19.375,-32.696 19.375,-31.446 19.125,-31.196 19.125,-30.946 19.375,-30.696 19.375,-29.446 18.625,-28.696 18.625,-27.446 21.016,-25.055 22.418,-25.055 22.606,-24.867 22.606,-23.465 ; 22.606,-23.46 22.606,-23.465 ; v1(35.5,-11.071) 34.625,-11.946 34.625,-16.696 35.875,-17.946 35.875,-18.196 34.625,-19.446 26.625,-19.446 22.606,-23.465
G1_A0_3: U1.AE13 U9.M9 | length 29.5
  INT1 w0.102: v6(20,-28.571) 20.375,-28.196 27.874,-28.196 28.852,-27.218 30.735,-27.218 31.088,-27.571 35.5,-27.571 35.875,-27.196 37.125,-27.196 37.375,-27.446 37.625,-27.446 39.853,-25.218 39.853,-24.925 39.647,-24.719 39.647,-24.425 39.853,-24.219 39.853,-23.925 39.647,-23.719 39.647,-23.425 39.853,-23.219 39.853,-22.925 39.647,-22.719 39.647,-22.425 39.853,-22.219 39.853,-21.925 39.647,-21.719 39.647,-21.425 39.854,-21.218 39.854,-20.777 39.522,-20.446 37.875,-20.446 v1(37.5,-20.071)
G1_A1: G1_A1.1 U1.AH14 | length 25
  INT6 w0.102: v1(38.5,-17.071) 38.625,-16.946 38.625,-15.571 38.625,-15.446 38.875,-15.196 38.875,-14.946 38.625,-14.696 38.625,-14.446 39.875,-13.196 39.875,-10.744 39.647,-10.516 39.647,-4.424 41.125,-2.946 49.625,-2.946 G1_A1.1@50.25,-2.321
G1_A1_0: U1.AD11 U6.N9 | length 39.1
  INT6 w0.102: v1(35.5,-21.071) 35.875,-20.696 37.891,-20.696 38.141,-20.446 45.375,-20.446 51.125,-26.196 51.125,-42.196 53.5,-44.571 v1(55,-44.571)
G1_A1_1: U1.AE11 U7.N9 | length 9.7
  INT7 w0.102: v1(35.5,-20.071) 35.5,-20.571 35.125,-20.946 35.125,-27.196 36.5,-28.571 v1(37,-28.571)
G1_A1_2: U1.AG12 U8.N9 | length 54.5
  INT5 w0.102: v6(19,-44.571) 19.375,-44.946 19.375,-48.571 19.75,-48.946 29.125,-48.946 32.125,-45.946 37,-45.946 38.125,-44.821 38.125,-43.696 37.875,-43.446 37.875,-32.946 37.625,-32.696 37.625,-32.446 37.875,-32.196 37.875,-31.946 37.625,-31.696 37.625,-31.446 37.875,-31.196 37.875,-30.946 37.625,-30.696 37.625,-30.446 37.875,-30.196 37.875,-29.946 37.625,-29.696 37.625,-29.446 37.875,-29.196 37.875,-28.946 37.625,-28.696 37.625,-28.446 37.875,-28.196 37.875,-27.946 37.625,-27.696 37.625,-27.446 37.875,-27.196 37.875,-26.946 37.625,-26.696 37.625,-26.446 37.875,-26.196 37.875,-25.946 37.625,-25.696 37.625,-25.446 37.875,-25.196 37.875,-24.946 37.625,-24.696 37.625,-24.446 37.875,-24.196 37.875,-23.946 37.625,-23.696 37.625,-23.446 37.875,-23.196 37.875,-22.946 37.625,-22.696 37.625,-22.446 37.875,-22.196 37.875,-21.946 36.875,-20.946 36.875,-18.446 v1(36.5,-18.071)
G1_A1_3: U1.AH12 U9.N9 | length 24.6
  INT5 w0.102: v6(19,-28.571) 19,-28.071 21.034,-26.037 22.883,-26.037 23.546,-25.375 23.546,-23.525 ; 23.546,-23.52 23.546,-23.525 ; v1(36.5,-17.071) 36.125,-17.446 36.125,-19.071 35.5,-19.696 27.375,-19.696 23.546,-23.525
G1_A2: U1.AD14 U6.N2 U7.N2 U8.N2 U9.N2 | length 77.2
  INT1 w0.102: v6(19,-37.571) 19.5,-37.571 19.875,-37.196 23.25,-37.196 23.5,-37.446 25.625,-37.446 25.875,-37.196 26.125,-37.196 26.375,-37.446 26.625,-37.446 26.875,-37.196 27.125,-37.196 27.375,-37.446 27.625,-37.446 27.875,-37.196 28.125,-37.196 28.375,-37.446 28.625,-37.446 28.875,-37.196 29.125,-37.196 29.375,-37.446 30.625,-37.446 30.875,-37.196 31.125,-37.196 31.375,-37.446 51.625,-37.446 51.875,-37.196 52.125,-37.196 52.375,-37.446 53.625,-37.446 53.875,-37.196 54.125,-37.196 54.375,-37.446 54.875,-37.446 v1(55,-37.571) ; v1(19,-21.571) 19.375,-21.196 27.125,-21.196 27.375,-21.446 27.625,-21.446 27.875,-21.196 28.125,-21.196 28.375,-21.446 28.625,-21.446 28.875,-21.196 31.125,-21.196 31.375,-21.446 33.625,-21.446 33.875,-21.196 34.125,-21.196 34.375,-21.446 35.625,-21.446 35.875,-21.196 36.125,-21.196 36.375,-21.446 36.875,-21.446 v1(37,-21.571) 37.5,-21.071 v1(38.5,-21.071)
  INT3 w0.102: v6(19,-37.571) 18.875,-37.446 18.875,-32.946 18.625,-32.696 18.625,-31.446 18.875,-31.196 18.875,-30.946 18.625,-30.696 18.625,-29.446 18.875,-29.196 18.875,-28.946 18.625,-28.696 18.625,-27.446 18.875,-27.196 18.875,-26.946 18.625,-26.696 18.625,-21.946 v1(19,-21.571) ; v1(37,-21.571) 37.5,-21.071 v1(38.5,-21.071)
G1_A3: U1.AP14 U6.M4 U7.M4 U8.M4 U9.M4 | length 98.5
  INT4 w0.102: v6(20,-39.571) 19.875,-39.446 19.875,-38.946 19.625,-38.696 19.625,-37.446 19.875,-37.196 19.875,-35.946 19.625,-35.696 19.625,-35.446 19.875,-35.196 19.875,-32.946 19.625,-32.696 19.625,-31.446 19.875,-31.196 19.875,-30.946 19.625,-30.696 19.625,-29.446 19.875,-29.196 19.875,-28.946 19.625,-28.696 19.625,-27.446 19.875,-27.196 19.875,-26.946 19.625,-26.696 19.625,-23.946 v1(20,-23.571)
  INT8 w0.102: v1(38,-23.571) 38,-24.071 37.625,-24.446 37.625,-24.696 37.875,-24.946 37.875,-25.196 37.625,-25.446 37.625,-25.696 37.875,-25.946 37.875,-26.196 36.875,-27.196 35.875,-27.196 35.625,-27.446 35.25,-27.446 34.875,-27.071 34.875,-21.196 36.875,-19.196 36.875,-16.946 36.625,-16.696 36.625,-16.446 36.875,-16.196 36.875,-15.946 36.625,-15.696 36.625,-15.446 36.875,-15.196 36.875,-14.946 36.625,-14.696 36.625,-14.446 36.875,-14.196 36.875,-13.946 36.625,-13.696 36.625,-13.446 38.5,-11.571 v1(38.5,-11.071)
  INT1 w0.102: v6(20,-39.571) 20.375,-39.946 29.125,-39.946 29.375,-39.696 53.625,-39.696 53.875,-39.946 54.125,-39.946 54.375,-39.696 54.625,-39.696 54.875,-39.946 55.625,-39.946 v1(56,-39.571) ; v1(20,-23.571) 20.375,-23.946 24.125,-23.946 24.375,-23.696 24.625,-23.696 24.875,-23.946 25.125,-23.946 25.375,-23.696 25.625,-23.696 25.875,-23.946 26.125,-23.946 26.375,-23.696 26.625,-23.696 26.875,-23.946 29.125,-23.946 29.375,-23.696 35.625,-23.696 35.875,-23.946 36.125,-23.946 36.375,-23.696 36.625,-23.696 36.875,-23.946 37.125,-23.946 37.5,-23.571 v1(38,-23.571)
G1_A4: U1.AN14 U6.N4 U7.N4 U8.N4 U9.N4 | length 95.1
  INT8 w0.102: v1(37,-23.571) 37.125,-23.696 37.125,-24.196 37.375,-24.446 37.375,-24.696 37.125,-24.946 37.125,-25.196 37.375,-25.446 37.375,-25.696 36.125,-26.946 35.875,-26.946 35.125,-26.196 35.125,-21.946 37.125,-19.946 37.125,-16.946 37.375,-16.696 37.375,-16.446 37.125,-16.196 37.125,-15.946 37.375,-15.696 37.375,-15.446 37.125,-15.196 37.125,-14.946 37.375,-14.696 37.375,-14.446 37.125,-14.196 37.125,-13.946 38.375,-12.696 38.375,-12.196 v1(38.5,-12.071)
  INT1 w0.102: v6(19,-39.571) 19.5,-39.571 19.875,-39.196 25.125,-39.196 25.375,-39.446 25.625,-39.446 25.875,-39.196 26.125,-39.196 26.375,-39.446 26.625,-39.446 26.875,-39.196 27.125,-39.196 27.375,-39.446 27.625,-39.446 27.875,-39.196 28.125,-39.196 28.375,-39.446 28.625,-39.446 28.875,-39.196 31,-39.196 31.25,-39.446 53.625,-39.446 53.875,-39.196 54.625,-39.196 v1(55,-39.571) ; v1(19,-23.571) 19.375,-23.196 27.125,-23.196 27.375,-23.446 27.625,-23.446 27.875,-23.196 28.125,-23.196 28.375,-23.446 28.625,-23.446 28.875,-23.196 31.125,-23.196 31.375,-23.446 35.625,-23.446 35.875,-23.196 36.125,-23.196 36.375,-23.446 36.875,-23.446 v1(37,-23.571)
  INT3 w0.102: v6(19,-39.571) 19,-39.071 19.375,-38.696 19.375,-37.446 19.125,-37.196 19.125,-32.946 19.375,-32.696 19.375,-31.446 19.125,-31.196 19.125,-30.946 19.375,-30.696 19.375,-29.446 19.125,-29.196 19.125,-28.946 19.375,-28.696 19.375,-27.446 19.125,-27.196 19.125,-26.946 19.375,-26.696 19.375,-23.946 v1(19,-23.571)
G1_A5: U1.AP18 U6.N5 U7.N5 U8.N5 U9.N5 | length 92.1
  INT4 w0.102: v6(19,-40.571) 18.625,-40.196 18.625,-39.446 18.875,-39.196 18.875,-38.946 18.625,-38.696 18.625,-37.446 18.875,-37.196 18.875,-32.946 18.625,-32.696 18.625,-31.446 18.875,-31.196 18.875,-30.946 18.625,-30.696 18.625,-29.446 18.875,-29.196 18.875,-28.946 18.625,-28.696 18.625,-27.446 18.875,-27.196 18.875,-26.946 18.625,-26.696 18.625,-24.946 v1(19,-24.571)
  INT7 w0.102: v1(37,-24.571) 37,-24.071 37.375,-23.696 37.375,-23.446 36.625,-22.696 36.625,-22.446 36.875,-22.196 36.875,-21.946 36.625,-21.696 36.625,-21.446 36.875,-21.196 36.875,-16.946 36.625,-16.696 36.625,-16.446 36.875,-16.196 36.875,-15.946 36.625,-15.696 36.625,-15.446 36.875,-15.196 36.875,-14.946 36.625,-14.696 36.625,-14.446 39.375,-11.696 41.875,-11.696 v1(42.5,-11.071)
  INT1 w0.102: v6(19,-40.571) 19.5,-40.571 19.875,-40.946 20.125,-40.946 20.375,-40.696 20.625,-40.696 20.875,-40.946 25,-40.946 27.125,-40.946 27.375,-40.696 27.625,-40.696 27.875,-40.946 28.125,-40.946 28.375,-40.696 28.625,-40.696 28.875,-40.946 31,-40.946 31.25,-40.696 53.625,-40.696 53.875,-40.946 54.125,-40.946 54.5,-40.571 v1(55,-40.571) ; v1(19,-24.571) 19.375,-24.946 27.125,-24.946 27.375,-24.696 27.625,-24.696 27.875,-24.946 28.125,-24.946 28.375,-24.696 28.625,-24.696 28.875,-24.946 31.125,-24.946 31.375,-24.696 35.5,-24.696 35.75,-24.946 36.625,-24.946 v1(37,-24.571)
G1_A6: U1.AN19 U6.P3 U7.P3 U8.P3 U9.P3 | length 92
  INT7 w0.102: v1(36,-22.571) 36.125,-22.446 36.125,-21.946 36.375,-21.696 36.375,-21.446 36.125,-21.196 36.125,-16.946 36.375,-16.696 36.375,-16.446 36.125,-16.196 36.125,-15.946 36.375,-15.696 36.375,-15.446 36.125,-15.196 36.125,-14.946 36.375,-14.696 36.375,-14.446 36.125,-14.196 36.125,-13.946 39.375,-10.696 42.75,-10.696 43,-10.946 43,-11.571 v1(43.5,-12.071)
  INT1 w0.102: v6(18,-38.571) 18.375,-38.196 24.807,-38.196 26.125,-38.196 26.375,-38.446 26.625,-38.446 26.875,-38.196 27.125,-38.196 27.375,-38.446 27.625,-38.446 27.875,-38.196 28.125,-38.196 28.375,-38.446 28.625,-38.446 28.875,-38.196 29.125,-38.196 29.375,-38.446 53.875,-38.446 v1(54,-38.571) ; v1(18,-22.571) 18.375,-22.196 25.125,-22.196 25.375,-22.446 25.625,-22.446 25.875,-22.196 26.125,-22.196 26.375,-22.446 26.625,-22.446 26.875,-22.196 29.125,-22.196 29.375,-22.446 35.875,-22.446 v1(36,-22.571)
  INT3 w0.102: v6(18,-38.571) 17.625,-38.196 17.625,-37.446 17.875,-37.196 17.875,-32.946 17.625,-32.696 17.625,-31.446 17.875,-31.196 17.875,-30.946 17.625,-30.696 17.625,-29.446 17.875,-29.196 17.875,-27.946 17.625,-27.696 17.625,-27.446 17.875,-27.196 17.875,-26.946 17.625,-26.696 17.625,-22.946 v1(18,-22.571)
G1_A7: U1.AN16 U6.P5 U7.P5 U8.P5 U9.P5 | length 88.9
  INT8 w0.102: v1(36,-24.571) 35.875,-24.446 35.875,-23.946 35.625,-23.696 35.625,-23.446 35.875,-23.196 35.875,-22.946 35.625,-22.696 35.625,-22.446 37.875,-20.196 37.875,-16.946 37.625,-16.696 37.625,-16.446 37.875,-16.196 37.875,-15.946 37.625,-15.696 37.625,-15.446 37.875,-15.196 37.875,-14.946 37.625,-14.696 37.625,-14.446 38.875,-13.196 39.125,-13.196 39.375,-13.446 39.625,-13.446 40.125,-12.946 40.125,-12.446 v1(40.5,-12.071)
  INT1 w0.102: v6(18,-40.571) 18.375,-40.196 29.125,-40.196 29.375,-40.446 53.875,-40.446 v1(54,-40.571) ; v1(18,-24.571) 18.375,-24.196 24.125,-24.196 24.375,-24.446 24.625,-24.446 24.875,-24.196 25.125,-24.196 25.25,-24.321 25.375,-24.446 25.625,-24.446 25.875,-24.196 26.125,-24.196 26.375,-24.446 26.625,-24.446 26.875,-24.196 29.125,-24.196 29.375,-24.446 35.875,-24.446 v1(36,-24.571)
  INT3 w0.102: v6(18,-40.571) 18.375,-40.196 18.375,-39.446 18.125,-39.196 18.125,-38.946 18.375,-38.696 18.375,-37.446 18.125,-37.196 18.125,-32.946 18.375,-32.696 18.375,-31.446 18.125,-31.196 18.125,-30.946 18.375,-30.696 18.375,-29.446 18.125,-29.196 18.125,-27.946 18.375,-27.696 18.375,-27.446 18.125,-27.196 18.125,-26.946 18.375,-26.696 18.375,-24.946 v1(18,-24.571)
G1_A8: U1.AM17 U6.M11 U7.M11 U8.M11 U9.M11 | length 94.6
  INT8 w0.102: v1(38,-30.571) 38.5,-30.571 42.125,-26.946 42.125,-23.946 42.375,-23.696 42.375,-23.446 42.125,-23.196 42.125,-20.853 41.776,-20.505 41.333,-20.505 41.125,-20.297 41.125,-16.196 40.625,-15.696 40.625,-15.446 41.375,-14.696 41.375,-14.446 41.125,-14.196 41.125,-13.946 41.375,-13.696 41.375,-13.196 v1(41.5,-13.071)
  INT1 w0.102: v1(20,-46.571) 20.391,-46.962 27.197,-46.962 27.213,-46.946 31.75,-46.946 32,-47.196 39.5,-47.196 39.75,-46.946 55.625,-46.946 v1(56,-46.571) ; v6(20,-30.571) 20.375,-30.946 27.125,-30.946 27.375,-30.696 27.625,-30.696 27.875,-30.946 28.125,-30.946 28.375,-30.696 28.625,-30.696 28.875,-30.946 29.125,-30.946 29.375,-30.696 35.625,-30.696 35.875,-30.946 36.125,-30.946 36.375,-30.696 36.625,-30.696 36.875,-30.946 37.125,-30.946 37.5,-30.571 v1(38,-30.571)
  INT2 w0.102: v1(20,-46.571) 20.375,-46.196 20.375,-44.446 19.625,-43.696 19.625,-41.446 19.875,-41.196 19.875,-40.946 19.625,-40.696 19.625,-39.446 19.875,-39.196 19.875,-38.946 19.625,-38.696 19.625,-37.446 19.875,-37.196 19.875,-36.946 19.625,-36.696 19.625,-35.446 19.875,-35.196 19.875,-34.946 19.625,-34.696 19.625,-32.446 20.375,-31.696 20.375,-30.946 v6(20,-30.571)
G1_A9: U1.AN17 U6.L11 U7.L11 U8.L11 U9.L11 | length 95.2
  INT4 w0.102: v1(21,-46.571) 20.625,-46.196 20.625,-41.446 20.875,-41.196 20.875,-40.946 20.625,-40.696 20.625,-39.446 20.875,-39.196 20.875,-38.946 20.625,-38.696 20.625,-37.446 20.875,-37.196 20.875,-35.071 20.875,-34.196 20.875,-32.946 20.625,-32.696 20.625,-32.446 20.875,-32.196 20.875,-31.946 20.625,-31.696 20.625,-30.946 v6(21,-30.571)
  INT8 w0.102: v1(39,-30.571) 39.5,-30.571 42.875,-27.196 42.875,-24.946 42.625,-24.696 42.625,-24.446 42.875,-24.196 42.875,-23.946 42.625,-23.696 42.625,-23.446 42.875,-23.196 42.875,-22.946 42.625,-22.696 42.625,-22.446 42.875,-22.196 42.875,-20.946 41.875,-19.946 41.875,-17.946 41.625,-17.696 41.625,-16.446 41.875,-16.196 41.875,-14.946 41.625,-14.696 41.625,-14.446 41.875,-14.196 41.875,-13.946 41.625,-13.696 41.625,-13.446 41.875,-13.196 41.875,-12.946 41.5,-12.571 v1(41.5,-12.071)
  INT2 w0.102: v1(21,-46.571) 21.375,-46.196 56.625,-46.196 v1(57,-46.571) ; v6(21,-30.571) 21.375,-30.196 22.125,-30.196 22.375,-30.446 22.625,-30.446 22.875,-30.196 25.125,-30.196 25.375,-30.446 25.625,-30.446 25.875,-30.196 26.125,-30.196 26.375,-30.446 26.625,-30.446 26.875,-30.196 29.125,-30.196 29.375,-30.446 35.625,-30.446 35.875,-30.196 36.125,-30.196 36.375,-30.446 36.625,-30.446 36.875,-30.196 37.125,-30.196 37.375,-30.446 37.625,-30.446 37.875,-30.196 38.125,-30.196 38.5,-30.571 v1(39,-30.571)
G1_A10: U1.AN18 U6.N13 U7.N13 U8.N13 U9.N13 | length 102.8
  INT8 w0.102: v1(37,-32.571) 37.5,-32.571 37.875,-32.196 38.125,-32.196 38.375,-32.446 38.625,-32.446 38.875,-32.196 39.125,-32.196 39.875,-32.946 40.125,-32.946 44.375,-28.696 44.375,-28.446 44.125,-28.196 44.125,-27.946 44.375,-27.696 44.375,-27.446 44.125,-27.196 44.125,-26.946 44.375,-26.696 44.375,-26.446 44.125,-26.196 44.125,-25.946 44.375,-25.696 44.375,-25.446 44.125,-25.196 44.125,-24.946 44.375,-24.696 44.375,-24.446 44.125,-24.196 44.125,-23.946 44.375,-23.696 44.375,-23.446 44.125,-23.196 44.125,-22.946 44.375,-22.696 44.375,-22.446 44.125,-22.196 44.125,-21.946 44.375,-21.696 44.375,-17.571 44.125,-17.321 44.125,-16.946 44.375,-16.696 44.375,-15.446 44.125,-15.196 44.125,-14.946 44.375,-14.696 44.375,-14.446 42.5,-12.571 v1(42.5,-12.071)
  INT1 w0.102: v6(19,-48.571) 19.375,-48.196 25.125,-48.196 26,-49.071 31.625,-49.071 32,-49.446 36.75,-49.446 37.5,-48.696 40.375,-48.696 40.875,-48.196 54.625,-48.196 v1(55,-48.571) ; v6(19,-32.571) 19.375,-32.196 20.125,-32.196 20.375,-32.446 20.625,-32.446 20.875,-32.196 27.125,-32.196 27.375,-32.446 27.625,-32.446 27.875,-32.196 28.125,-32.196 28.375,-32.446 28.625,-32.446 28.875,-32.196 29.125,-32.196 29.375,-32.446 30.625,-32.446 30.875,-32.196 31.125,-32.196 31.375,-32.446 33.625,-32.446 33.875,-32.196 34.125,-32.196 34.375,-32.446 35.625,-32.446 35.875,-32.196 36.125,-32.196 36.375,-32.446 36.875,-32.446 v1(37,-32.571)
  INT2 w0.102: v6(19,-48.571) 19.375,-48.196 19.375,-45.446 18.625,-44.696 18.625,-39.446 18.875,-39.196 18.875,-38.946 18.625,-38.696 18.625,-37.446 18.875,-37.196 18.875,-32.696 v6(19,-32.571)
G1_A11: U1.AM15 U6.M12 U7.M12 U8.M12 U9.M12 | length 101.2
  INT8 w0.102: v1(38,-31.571) 38.125,-31.696 38.625,-31.696 38.875,-31.946 39.125,-31.946 43.125,-27.946 43.125,-24.946 43.375,-24.696 43.375,-24.446 43.125,-24.196 43.125,-23.946 43.375,-23.696 43.375,-23.446 43.125,-23.196 43.125,-22.946 43.375,-22.696 43.375,-22.446 43.125,-22.196 43.125,-17.971 42.375,-17.221 42.375,-16.446 42.125,-16.196 42.125,-14.946 42.375,-14.696 42.375,-14.446 42.125,-14.196 42.125,-13.946 42.375,-13.696 42.375,-13.446 42.125,-13.196 42.125,-12.196 41.625,-11.696 40.125,-11.696 39.875,-11.946 39.875,-12.696 v1(39.5,-13.071)
  INT1 w0.102: v1(20,-47.571) 20.375,-47.946 31.125,-47.946 31.625,-48.446 40,-48.446 40.5,-47.946 55.625,-47.946 v1(56,-47.571) ; v6(20,-31.571) 20.5,-31.571 20.875,-31.946 27.125,-31.946 27.375,-31.696 27.625,-31.696 27.875,-31.946 28.125,-31.946 28.375,-31.696 28.625,-31.696 28.875,-31.946 29.125,-31.946 29.375,-31.696 30.625,-31.696 30.875,-31.946 31.125,-31.946 31.375,-31.696 35.625,-31.696 35.875,-31.946 36.125,-31.946 36.375,-31.696 36.625,-31.696 36.875,-31.946 37.125,-31.946 37.5,-31.571 v1(38,-31.571)
  INT2 w0.102: v1(20,-47.571) 19.625,-47.196 19.625,-45.071 19.375,-44.821 19.375,-41.446 19.125,-41.196 19.125,-40.946 19.375,-40.696 19.375,-39.446 19.125,-39.196 19.125,-38.946 19.375,-38.696 19.375,-37.446 19.125,-37.196 19.125,-34.946 19.375,-34.696 19.375,-32.196 v6(20,-31.571)
G1_A12: U1.AM16 U6.N10 U7.N10 U8.N10 U9.N10 | length 93.8
  INT5 w0.102: v6(19,-45.571) 18.625,-45.196 18.625,-39.446 18.875,-39.196 18.875,-38.946 18.625,-38.696 18.625,-37.446 18.875,-37.196 18.875,-32.946 18.625,-32.696 18.625,-31.446 18.875,-31.196 18.875,-30.946 18.625,-30.696 18.625,-29.946 v6(19,-29.571)
  INT8 w0.102: v1(37,-29.571) 37,-29.071 40.875,-25.196 40.875,-23.946 40.625,-23.696 40.625,-23.446 40.875,-23.196 40.875,-22.946 40.625,-22.696 40.625,-22.446 40.875,-22.196 40.875,-21.946 39.875,-20.946 39.875,-17.946 38.625,-16.696 38.625,-16.446 38.875,-16.196 38.875,-15.946 38.625,-15.696 38.625,-15.446 38.875,-15.196 38.875,-14.946 38.625,-14.696 38.625,-14.446 39.375,-13.696 39.625,-13.696 39.875,-13.946 40.125,-13.946 40.5,-13.571 v1(40.5,-13.071)
  INT1 w0.102: v6(19,-45.571) 19.375,-45.946 54.625,-45.946 v1(55,-45.571) ; v6(19,-29.571) 19.375,-29.946 20.125,-29.946 20.375,-29.696 20.625,-29.696 20.875,-29.946 25.125,-29.946 25.375,-29.696 25.625,-29.696 25.875,-29.946 26.125,-29.946 26.375,-29.696 26.625,-29.696 26.875,-29.946 29.125,-29.946 29.375,-29.696 35.625,-29.696 35.875,-29.946 36.125,-29.946 36.5,-29.571 v1(37,-29.571)
G1_A13: U1.AP15 U6.P10 U7.P10 U8.P10 U9.P10 | length 97.4
  INT5 w0.102: v6(18,-45.571) 17.625,-45.196 17.625,-41.446 17.875,-41.196 17.875,-40.946 17.625,-40.696 17.625,-39.446 17.875,-39.196 17.875,-38.946 17.625,-38.696 17.625,-37.446 17.875,-37.196 17.875,-32.946 17.625,-32.696 17.625,-31.446 17.875,-31.196 17.875,-30.946 17.625,-30.696 17.625,-29.946 v6(18,-29.571)
  INT6 w0.102: v1(36,-29.571) 35.875,-29.446 35.875,-28.946 35.125,-28.196 35.125,-20.946 35.625,-20.446 37.75,-20.446 37.875,-20.321 37.875,-19.946 37.125,-19.196 37.125,-16.946 37.375,-16.696 37.375,-16.446 36.625,-15.696 36.625,-15.446 36.875,-15.196 36.875,-14.946 36.125,-14.196 36.125,-13.946 36.875,-13.196 37.125,-13.196 37.375,-13.446 37.625,-13.446 39.5,-11.571 v1(39.5,-11.071)
  INT1 w0.102: v6(18,-45.571) 18.375,-45.196 53.625,-45.196 v1(54,-45.571) ; v6(18,-29.571) 18.5,-29.571 18.875,-29.196 19.125,-29.196 19.375,-29.446 19.625,-29.446 19.875,-29.196 20.125,-29.196 20.375,-29.446 21.625,-29.446 21.875,-29.196 23.125,-29.196 23.375,-29.446 23.625,-29.446 23.875,-29.196 27.125,-29.196 27.375,-29.446 27.625,-29.446 27.875,-29.196 28.125,-29.196 28.375,-29.446 28.625,-29.446 28.875,-29.196 31,-29.196 31.25,-29.446 35.875,-29.446 v1(36,-29.571)
G1_A14: U1.AP16 U6.M13 U7.M13 U8.M13 U9.M13 | length 109.6
  INT8 w0.102: v1(38,-32.571) 38,-33.196 38.5,-33.696 41.375,-33.696 45.375,-29.696 45.375,-29.446 45.125,-29.196 45.125,-28.946 45.375,-28.696 45.375,-28.446 45.125,-28.196 45.125,-27.946 45.375,-27.696 45.375,-27.446 45.125,-27.196 45.125,-26.946 45.375,-26.696 45.375,-26.446 45.125,-26.196 45.125,-25.946 45.375,-25.696 45.375,-25.446 45.125,-25.196 45.125,-24.946 45.375,-24.696 45.375,-24.446 45.125,-24.196 45.125,-23.946 45.375,-23.696 45.375,-23.446 45.125,-23.196 45.125,-22.946 45.375,-22.696 45.375,-22.446 45.125,-22.196 45.125,-21.946 45.375,-21.696 45.375,-19.571 45.125,-19.321 45.125,-16.946 45.375,-16.696 45.375,-16.446 45.125,-16.196 45.125,-15.946 45.375,-15.696 45.375,-15.446 45.125,-15.196 45.125,-14.946 45.375,-14.696 45.375,-14.446 45.125,-14.196 45.125,-13.946 45.375,-13.696 45.375,-13.446 42.625,-10.696 40.875,-10.696 v1(40.5,-11.071)
  INT1 w0.102: v1(20,-48.571) 20.625,-49.196 25.25,-49.196 26.194,-50.14 33.104,-50.14 33.327,-50.363 34.423,-50.363 34.646,-50.14 35.229,-50.14 35.452,-50.363 36.708,-50.363 37.875,-49.196 39.875,-49.196 40.25,-49.571 49.75,-49.571 50.25,-49.071 55.5,-49.071 v1(56,-48.571) ; v6(20,-32.571) 20.375,-32.946 25.125,-32.946 25.375,-32.696 25.625,-32.696 25.875,-32.946 26.125,-32.946 26.375,-32.696 26.625,-32.696 26.875,-32.946 27.125,-32.946 27.375,-32.696 27.625,-32.696 27.875,-32.946 28.125,-32.946 28.375,-32.696 28.625,-32.696 28.875,-32.946 29.125,-32.946 29.375,-32.696 30.625,-32.696 30.875,-32.946 31.125,-32.946 31.375,-32.696 33.625,-32.696 33.875,-32.946 34.125,-32.946 34.375,-32.696 35.625,-32.696 35.875,-32.946 36.125,-32.946 36.375,-32.696 36.625,-32.696 36.875,-32.946 37.125,-32.946 37.5,-32.571 v1(38,-32.571)
  INT2 w0.102: v1(20,-48.571) 20.625,-47.946 20.625,-44.196 20.375,-43.946 20.375,-41.446 20.125,-41.196 20.125,-40.946 20.375,-40.696 20.375,-36.446 20.125,-36.196 20.125,-35.946 20.375,-35.696 20.375,-32.946 v6(20,-32.571)
G1_A15: U1.AM14 U6.L13 U7.L13 U8.L13 U9.L13 | length 107.5
  INT5 w0.102: v1(21,-48.571) 20.625,-48.196 20.625,-41.446 20.875,-41.196 20.875,-40.946 20.625,-40.696 20.625,-37.446 21,-37.071 v6(21,-32.571)
  INT8 w0.102: v1(38.5,-13.071) 38.625,-12.946 38.625,-12.446 39.625,-11.446 42.375,-11.446 44.875,-13.946 44.875,-14.196 44.625,-14.446 44.625,-14.696 44.875,-14.946 44.875,-15.196 44.625,-15.446 44.625,-15.696 44.875,-15.946 44.875,-16.196 44.625,-16.446 44.625,-16.696 44.875,-16.946 44.875,-21.196 44.625,-21.446 44.625,-21.696 44.875,-21.946 44.875,-22.196 44.625,-22.446 44.625,-22.696 44.875,-22.946 44.875,-23.196 44.625,-23.446 44.625,-23.696 44.875,-23.946 44.875,-24.196 44.625,-24.446 44.625,-24.696 44.875,-24.946 44.875,-25.196 44.625,-25.446 44.625,-25.696 44.875,-25.946 44.875,-26.196 44.625,-26.446 44.625,-26.696 44.875,-26.946 44.875,-27.196 44.625,-27.446 44.625,-27.696 44.875,-27.946 44.875,-28.196 44.625,-28.446 44.625,-28.696 44.875,-28.946 44.875,-29.196 40.625,-33.446 39.25,-33.446 39,-33.196 v1(39,-32.571)
  INT2 w0.102: v1(21,-48.571) 21.375,-48.196 56.625,-48.196 v1(57,-48.571) ; v6(21,-32.571) 21.375,-32.196 22.125,-32.196 22.375,-32.446 22.625,-32.446 22.875,-32.196 25.125,-32.196 25.375,-32.446 25.625,-32.446 25.875,-32.196 26.125,-32.196 26.375,-32.446 26.625,-32.446 26.875,-32.196 27.125,-32.196 27.375,-32.446 27.625,-32.446 27.875,-32.196 28.125,-32.196 28.375,-32.446 28.625,-32.446 28.875,-32.196 29.125,-32.196 29.375,-32.446 30.625,-32.446 30.875,-32.196 31.125,-32.196 31.375,-32.446 33.625,-32.446 33.875,-32.196 34.125,-32.196 34.375,-32.446 35.625,-32.446 35.875,-32.196 36.125,-32.196 36.375,-32.446 36.625,-32.446 36.875,-32.196 37.125,-32.196 37.375,-32.446 37.625,-32.446 37.875,-32.196 38.125,-32.196 38.375,-32.446 38.875,-32.446 v1(39,-32.571)
G1_A16: U1.AL14 U6.P6 U7.P6 U8.P6 U9.P6 | length 86.1
  INT4 w0.102: v6(18,-41.571) 17,-40.571 17,-26.571 v6(18,-25.571)
  INT8 w0.102: v1(36,-25.571) 36.375,-25.196 36.375,-24.446 36.125,-24.196 36.125,-23.946 36.375,-23.696 36.375,-23.446 36.125,-23.196 36.125,-22.946 38.125,-20.946 38.125,-16.946 38.375,-16.696 38.375,-16.446 38.125,-16.196 38.125,-15.946 38.375,-15.696 38.375,-15.446 38.125,-15.196 38.125,-14.946 38.375,-14.696 38.375,-14.196 v1(38.5,-14.071)
  INT1 w0.102: v6(18,-41.571) 18.5,-41.571 18.875,-41.196 19.125,-41.196 19.375,-41.446 19.625,-41.446 19.875,-41.196 20.125,-41.196 20.375,-41.446 20.625,-41.446 20.875,-41.196 21.75,-41.196 27.125,-41.196 27.375,-41.446 27.625,-41.446 27.875,-41.196 28.125,-41.196 28.375,-41.446 28.625,-41.446 28.875,-41.196 31,-41.196 31.25,-41.446 53.875,-41.446 v1(54,-41.571) ; v6(18,-25.571) 18.375,-25.196 27.125,-25.196 27.375,-25.446 27.625,-25.446 27.875,-25.196 28.125,-25.196 28.375,-25.446 28.625,-25.446 28.875,-25.196 31.125,-25.196 31.375,-25.446 35.875,-25.446 v1(36,-25.571)
G1_A17: U1.AM19 U6.N6 U7.N6 U8.N6 U9.N6 | length 92.2
  INT4 w0.102: v6(19,-41.571) 19,-41.071 19.375,-40.696 19.375,-39.446 19.125,-39.196 19.125,-38.946 19.375,-38.696 19.375,-37.446 19.125,-37.196 19.125,-32.946 19.375,-32.696 19.375,-31.446 19.125,-31.196 19.125,-30.946 19.375,-30.696 19.375,-29.446 19.125,-29.196 19.125,-28.946 19.375,-28.696 19.375,-27.446 19.125,-27.196 19.125,-26.946 19.375,-26.696 19.375,-25.946 v6(19,-25.571)
  INT7 w0.102: v1(37,-25.571) 37,-25.071 38.875,-23.196 38.875,-22.946 37.625,-21.696 37.625,-21.321 37.875,-21.071 37.875,-16.946 37.625,-16.696 37.625,-16.446 37.875,-16.196 37.875,-15.946 37.625,-15.696 37.625,-15.446 40.375,-12.696 43.125,-12.696 v1(43.5,-13.071)
  INT1 w0.102: v6(19,-41.571) 19.375,-41.946 24.576,-41.946 26.125,-41.946 26.375,-41.696 26.625,-41.696 26.875,-41.946 29.125,-41.946 29.375,-41.696 53.625,-41.696 53.875,-41.946 54.125,-41.946 54.375,-41.696 54.875,-41.696 v1(55,-41.571) ; v6(19,-25.571) 19.375,-25.946 20.125,-25.946 20.375,-25.696 20.625,-25.696 20.875,-25.946 25,-25.946 25.25,-25.696 25.625,-25.696 25.75,-25.821 25.875,-25.946 26.125,-25.946 26.375,-25.696 26.625,-25.696 26.875,-25.946 29.125,-25.946 29.375,-25.696 35.625,-25.696 35.875,-25.946 36.125,-25.946 36.5,-25.571 v1(37,-25.571)
G1_A18: U1.AL19 U6.N11 U7.N11 U8.N11 U9.N11 | length 105.5
  INT7 w0.102: v1(37,-30.571) 37,-30.071 37.375,-29.696 37.375,-29.446 37.125,-29.196 37.125,-28.946 37.375,-28.696 37.375,-28.446 35.625,-26.696 35.625,-24.446 35.875,-24.196 35.875,-23.946 35.625,-23.696 35.625,-23.446 35.875,-23.196 35.875,-22.946 35.625,-22.696 35.625,-22.446 35.875,-22.196 35.875,-21.946 35.625,-21.696 35.625,-21.446 35.875,-21.196 35.875,-16.946 35.625,-16.696 35.625,-14.446 35.875,-14.196 35.875,-13.946 35.625,-13.696 35.625,-13.446 38.875,-10.196 39.125,-10.196 39.375,-10.446 43,-10.446 43.625,-11.071 43.625,-11.696 44.375,-12.446 44.375,-12.696 44.125,-12.946 44.125,-13.196 44.375,-13.446 44.375,-13.696 44,-14.071 v1(43.5,-14.071)
  INT1 w0.102: v1(19,-46.571) 19.375,-46.196 54.625,-46.196 v1(55,-46.571) ; v6(19,-30.571) 19.375,-30.196 20.125,-30.196 20.375,-30.446 20.625,-30.446 20.875,-30.196 25.125,-30.196 25.375,-30.446 25.625,-30.446 25.875,-30.196 26.125,-30.196 26.375,-30.446 26.625,-30.446 26.875,-30.196 29.125,-30.196 29.375,-30.446 35.625,-30.446 35.875,-30.196 36.125,-30.196 36.375,-30.446 36.875,-30.446 v1(37,-30.571)
  INT2 w0.102: v1(19,-46.571) 18.375,-45.946 18.375,-39.446 18.125,-39.196 18.125,-38.946 18.375,-38.696 18.375,-37.446 18.125,-37.196 18.125,-32.946 18.5,-32.571 18.5,-31.571 19,-31.071 v6(19,-30.571)
G1_A19: U1.AL15 U6.L12 U7.L12 U8.L12 U9.L12 | length 94.4
  INT4 w0.102: v1(21,-47.571) 21.375,-47.196 21.375,-40.446 21.125,-40.196 21.125,-39.946 21.375,-39.696 21.375,-37.446 21.125,-37.196 21.125,-32.946 21.375,-32.696 21.375,-31.946 v6(21,-31.571)
  INT8 w0.102: v1(39,-31.571) 38.875,-31.446 38.375,-31.446 37.625,-30.696 37.625,-30.446 41.875,-26.196 41.875,-23.946 41.625,-23.696 41.625,-23.446 41.875,-23.196 41.875,-20.945 41.656,-20.726 41.655,-20.726 41.646,-20.718 41.165,-20.718 40.875,-20.428 40.875,-16.946 40,-16.071 40,-15.071 39.5,-14.571 v1(39.5,-14.071)
  INT2 w0.102: v1(21,-47.571) 21.375,-47.196 56.625,-47.196 v1(57,-47.571) ; v6(21,-31.571) 21.5,-31.571 21.875,-31.196 23.125,-31.196 23.375,-31.446 23.625,-31.446 23.875,-31.196 27.125,-31.196 27.375,-31.446 27.625,-31.446 27.875,-31.196 28.125,-31.196 28.375,-31.446 28.625,-31.446 28.875,-31.196 29.125,-31.196 29.375,-31.446 30.625,-31.446 30.875,-31.196 31.125,-31.196 31.375,-31.446 35.625,-31.446 35.875,-31.196 36.125,-31.196 36.375,-31.446 36.625,-31.446 36.875,-31.196 37.125,-31.196 37.375,-31.446 37.625,-31.446 37.875,-31.196 38.125,-31.196 38.5,-31.571 v1(39,-31.571)
G1_A20: U1.AK15 U6.P12 U7.P12 U8.P12 U9.P12 | length 93.6
  INT5 w0.102: v1(18,-47.571) 18.375,-47.196 18.375,-41.446 18.125,-41.196 18.125,-40.946 18.375,-40.696 18.375,-39.446 18.125,-39.196 18.125,-38.946 18.375,-38.696 18.375,-37.446 18.125,-37.196 18.125,-32.946 18.375,-32.696 18.375,-31.946 v6(18,-31.571)
  INT8 w0.102: v1(36,-31.571) 36,-31.071 41.125,-25.946 41.125,-23.946 41.375,-23.696 41.375,-23.446 41.125,-23.196 41.125,-22.946 41.375,-22.696 41.375,-22.446 41.125,-22.196 41.125,-21.946 41.375,-21.696 41.375,-21.447 40.646,-20.718 40.378,-20.718 40.125,-20.465 40.125,-17.196 39.125,-16.196 39.125,-15.946 39.5,-15.571 v1(39.5,-15.071)
  INT1 w0.102: v1(18,-47.571) 18.375,-47.196 31.375,-47.196 32.375,-48.196 39.625,-48.196 40.625,-47.196 53.625,-47.196 v1(54,-47.571) ; v6(18,-31.571) 18.5,-31.571 18.875,-31.196 19.125,-31.196 19.375,-31.446 19.625,-31.446 19.875,-31.196 27.125,-31.196 27.375,-31.446 27.625,-31.446 27.875,-31.196 28.125,-31.196 28.375,-31.446 28.625,-31.446 28.875,-31.196 29.125,-31.196 29.375,-31.446 30.625,-31.446 30.875,-31.196 31.125,-31.196 31.375,-31.446 35.875,-31.446 v1(36,-31.571)
G1_A21: U1.AL17 U6.M7 U7.M7 U8.M7 U9.M7 | length 89.3
  INT4 w0.102: v6(20,-42.571) 20.375,-42.196 20.375,-41.446 20.125,-41.196 20.125,-40.946 20.375,-40.696 20.375,-39.446 20.125,-39.196 20.125,-38.946 20.375,-38.696 20.375,-37.446 20.125,-37.196 20.125,-35.946 20.375,-35.696 20.375,-35.446 20.125,-35.196 20.125,-32.946 20.375,-32.696 20.375,-32.446 20.125,-32.196 20.125,-31.946 20.375,-31.696 20.375,-30.446 20.125,-30.196 20.125,-29.946 20.375,-29.696 20.375,-28.446 20.125,-28.196 20.125,-27.946 20.375,-27.696 20.375,-26.946 v6(20,-26.571)
  INT7 w0.102: v1(38,-26.571) 38.147,-26.424 38.646,-26.424 39.853,-25.217 39.853,-25.196 40.125,-24.924 40.146,-24.924 40.853,-24.217 40.853,-23.923 40.647,-23.717 40.647,-23.423 41.353,-22.717 41.367,-22.717 41.885,-22.2 41.885,-17.374 41.147,-16.636 41.147,-15.924 41.375,-15.696 41.375,-15.446 41.125,-15.196 41.125,-14.946 41.5,-14.571 v1(41.5,-14.071)
  INT1 w0.102: v6(20,-42.571) 20.375,-42.946 27.125,-42.946 27.375,-42.696 27.625,-42.696 27.875,-42.946 28.125,-42.946 28.375,-42.696 28.625,-42.696 28.875,-42.946 31,-42.946 31.25,-42.696 53.625,-42.696 53.875,-42.946 54.125,-42.946 54.375,-42.696 54.625,-42.696 54.875,-42.946 55.625,-42.946 v1(56,-42.571) ; v6(20,-26.571) 20.375,-26.946 21.125,-26.946 21.375,-26.696 21.625,-26.696 21.875,-26.946 27.125,-26.946 27.375,-26.696 27.625,-26.696 27.875,-26.946 28.125,-26.946 28.375,-26.696 28.625,-26.696 28.875,-26.946 31,-26.946 31.25,-26.696 35.625,-26.696 35.875,-26.946 37.125,-26.946 37.5,-26.571 v1(38,-26.571)
G1_A22: U1.AL18 U6.L3 U7.L3 U8.L3 U9.L3 | length 85.7
  INT7 w0.102: v1(39,-22.571) 38.875,-22.446 38.875,-21.946 38.625,-21.696 38.625,-21.446 38.875,-21.196 38.875,-16.946 38.625,-16.696 38.625,-16.446 41.375,-13.696 41.625,-13.696 42,-14.071 v1(42.5,-14.071)
  INT2 w0.102: v6(21,-38.571) 21.375,-38.196 25.125,-38.196 25.375,-38.446 25.625,-38.446 25.875,-38.196 26.125,-38.196 26.375,-38.446 26.625,-38.446 26.875,-38.196 27.125,-38.196 27.375,-38.446 27.625,-38.446 27.875,-38.196 28.125,-38.196 28.375,-38.446 28.625,-38.446 28.875,-38.196 29.125,-38.196 29.375,-38.446 53.5,-38.446 53.75,-38.196 55.125,-38.196 55.375,-38.446 55.625,-38.446 55.875,-38.196 56.625,-38.196 v1(57,-38.571) ; v1(21,-22.571) 21.375,-22.196 25.125,-22.196 25.375,-22.446 25.625,-22.446 25.875,-22.196 26.125,-22.196 26.375,-22.446 26.625,-22.446 26.875,-22.196 29.125,-22.196 29.375,-22.446 35.625,-22.446 35.875,-22.196 36.125,-22.196 36.375,-22.446 36.625,-22.446 36.875,-22.196 37.125,-22.196 37.375,-22.446 37.625,-22.446 37.875,-22.196 38.125,-22.196 38.375,-22.446 38.875,-22.446 v1(39,-22.571)
  INT3 w0.102: v6(21,-38.571) 20.625,-38.196 20.625,-37.446 20.875,-37.196 20.875,-32.946 20.625,-32.696 20.625,-32.446 20.875,-32.196 20.875,-31.946 20.625,-31.696 20.625,-30.446 20.875,-30.196 20.875,-29.946 20.625,-29.696 20.625,-26.446 20.875,-26.196 20.875,-25.946 20.625,-25.696 20.625,-22.946 v1(21,-22.571)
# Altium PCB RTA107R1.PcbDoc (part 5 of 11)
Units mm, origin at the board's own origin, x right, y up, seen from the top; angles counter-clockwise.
Board outline 96.01 x 65.66 mm, 22 copper layers (Top Layer, GND1, INT1, PWR1-(VCCIO_MRAM), INT2, PWR2-(VCCINT), INT3, PWR3_(12V_MGTAVCC), INT4, GND2-(DGND_SGND), PWR4_(MGTAVTT_VCCBRAM,VCCAUX), PWR5-(VCC_12V), GND3-(DGND_GND), INT5, GND4, INT6, PWR6_(VCCO), INT7, GND5, INT8, GND6, Bottom Layer), stack 2.833 mm thick; 614 components, 659 nets, 4037 pads, 3511 vias.

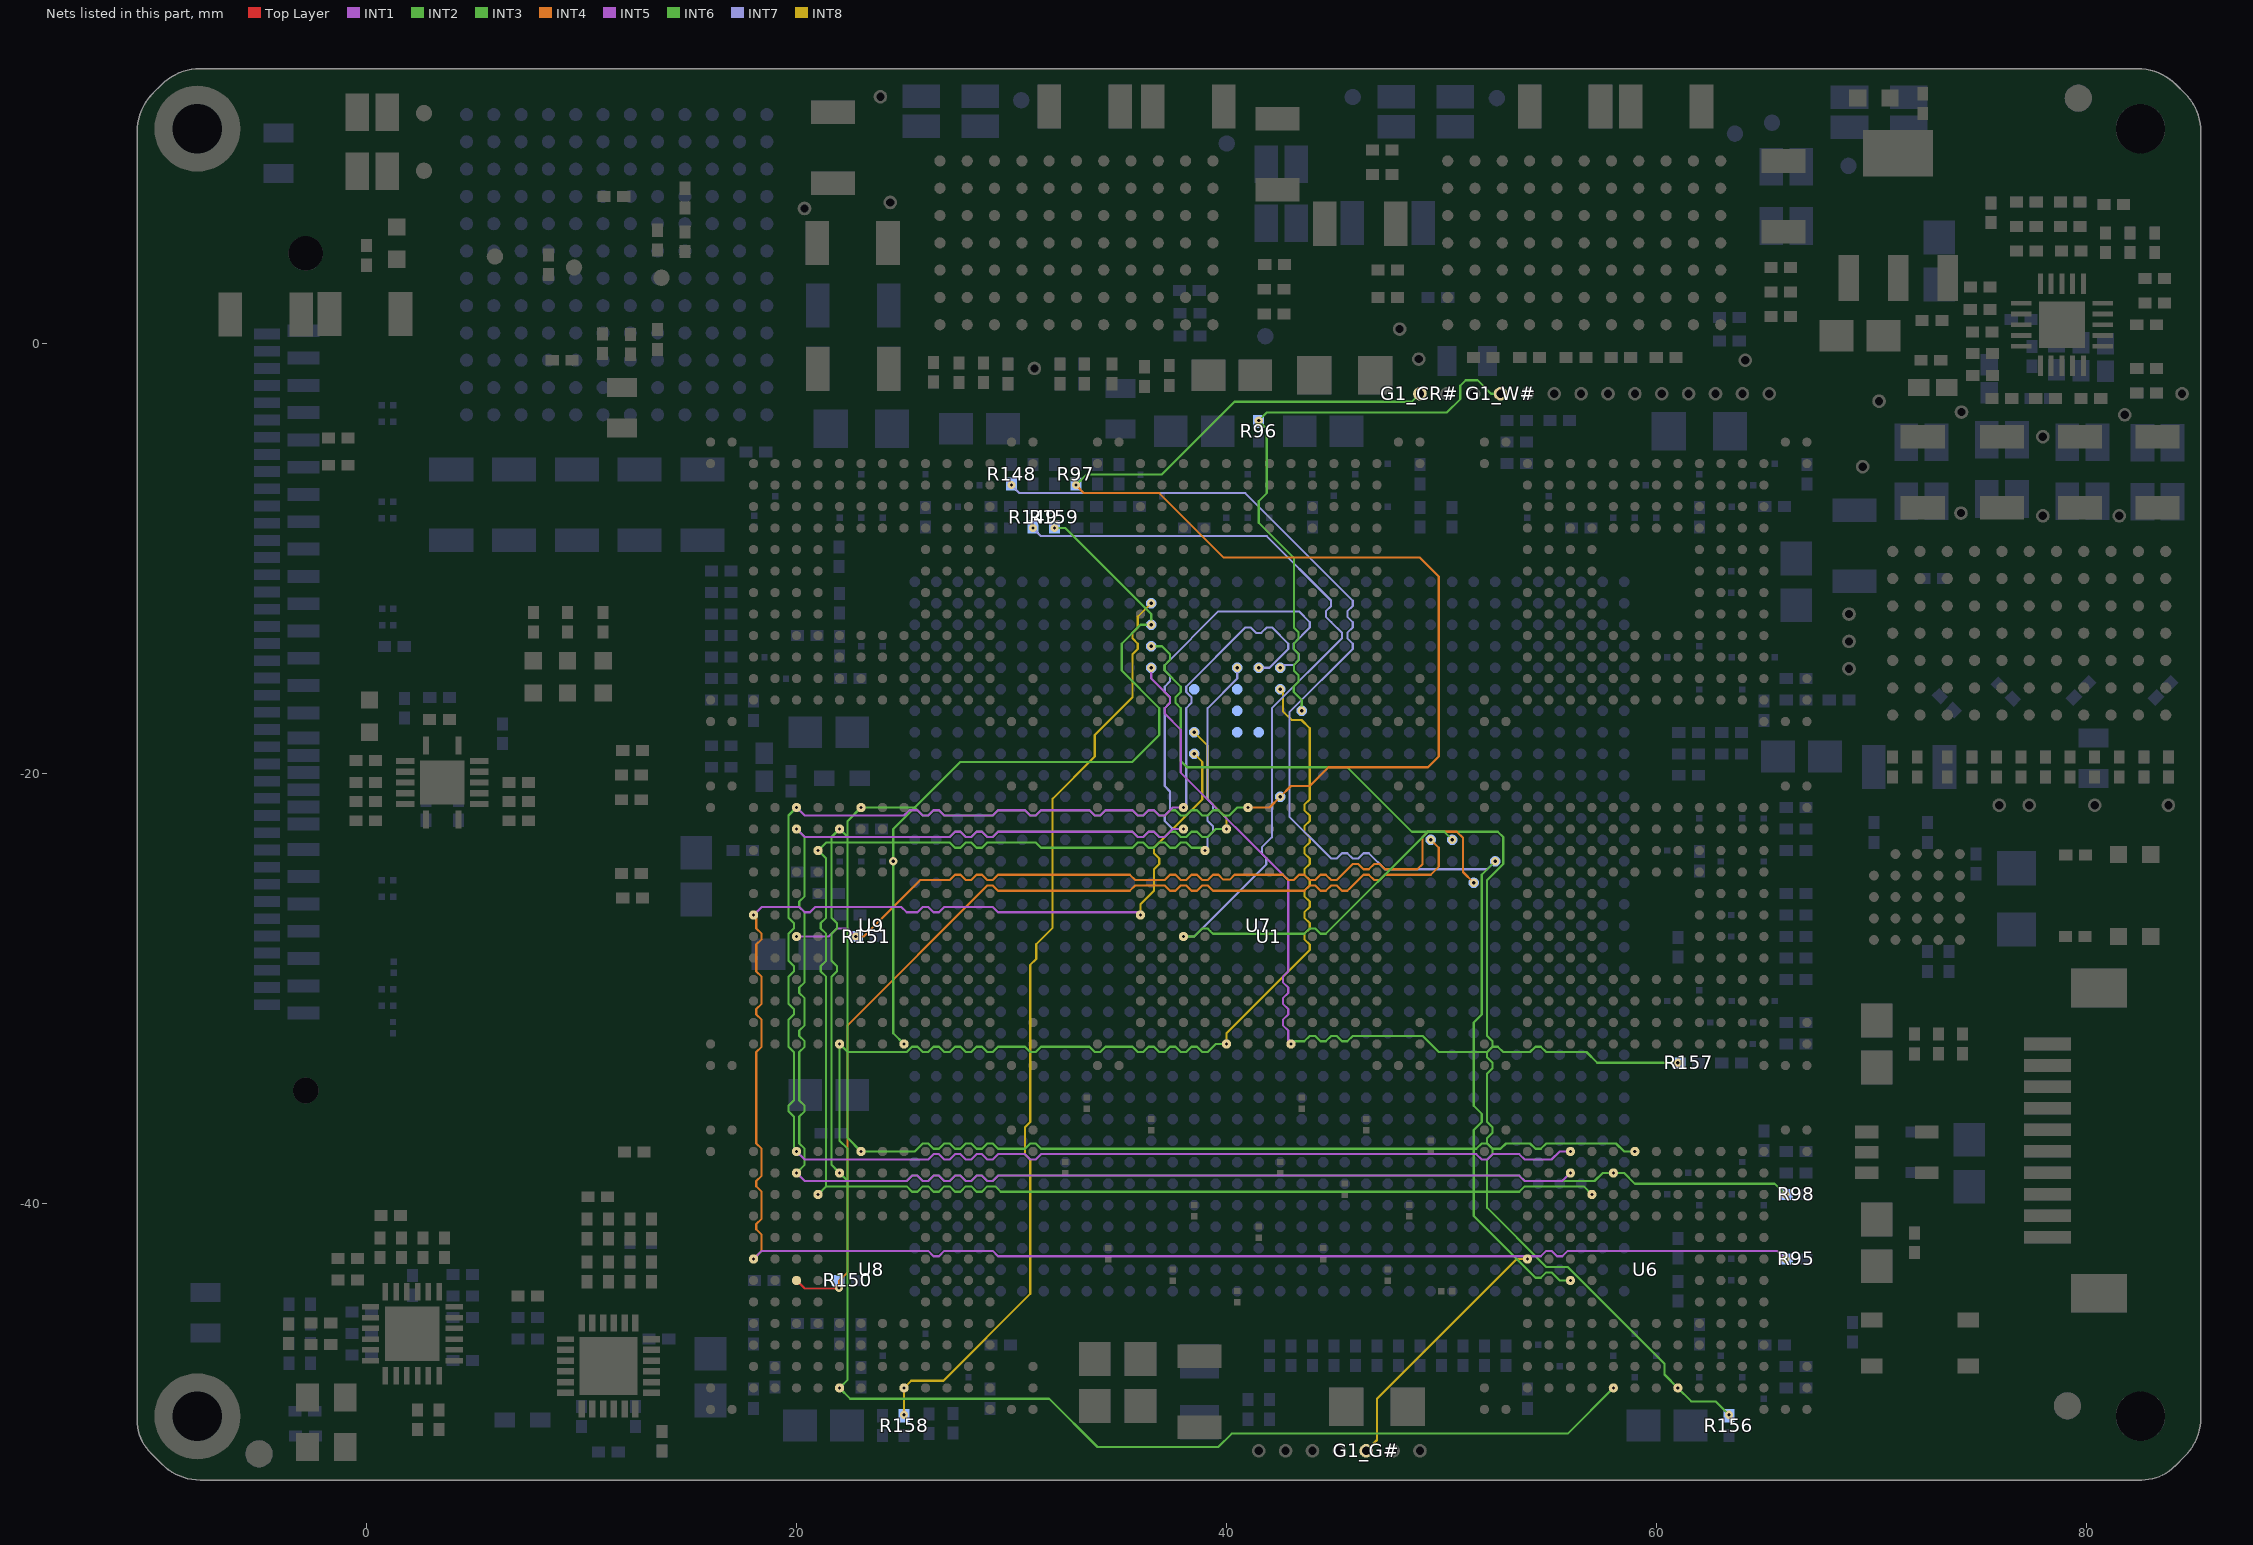
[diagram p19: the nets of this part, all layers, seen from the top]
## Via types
v1: diameter 0.381, hole 0.152, Top Layer to Bottom Layer, tented both sides, 2009 vias
v2: diameter 0.508, hole 0.254, Top Layer to Bottom Layer, tented both sides, 467 vias
v3: diameter 0.406, hole 0.203, Top Layer to Bottom Layer, 458 vias
v4: diameter 0.508, hole 0.254, Top Layer to Bottom Layer, 239 vias
v5: diameter 0.406, hole 0.203, Top Layer to Bottom Layer, tented both sides, 181 vias
v6: diameter 0.381, hole 0.152, Top Layer to GND4, tented both sides, 147 vias
v7: diameter 0.406, hole 0.203, Top Layer to GND4, tented both sides, 10 vias

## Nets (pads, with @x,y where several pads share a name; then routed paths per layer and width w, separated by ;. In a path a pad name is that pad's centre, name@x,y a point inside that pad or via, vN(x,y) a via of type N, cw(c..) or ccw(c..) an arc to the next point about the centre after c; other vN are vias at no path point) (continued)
G1_A23: U1.AK18 U6.M3 U7.M3 U8.M3 U9.M3 | length 93.9
  INT7 w0.102: v1(38,-22.571) 37.5,-22.571 37.125,-22.196 37.125,-21.946 37.375,-21.696 37.375,-20.821 37.125,-20.571 37.125,-19.321 37.125,-16.946 37.375,-16.696 37.375,-16.446 37.125,-16.196 37.125,-15.946 37.375,-15.696 37.375,-15.446 37.125,-15.196 37.125,-14.946 39.625,-12.446 43.375,-12.446 43.875,-12.946 43.875,-13.196 43.125,-13.946 43.125,-14.196 43.375,-14.446 43.375,-14.696 43.125,-14.946 42.625,-14.946 v1(42.5,-15.071)
  INT1 w0.102: v6(20,-38.571) 20.375,-38.946 25.125,-38.946 25.375,-38.696 25.625,-38.696 25.875,-38.946 26.125,-38.946 26.375,-38.696 26.625,-38.696 26.875,-38.946 27.125,-38.946 27.375,-38.696 27.625,-38.696 27.875,-38.946 28.125,-38.946 28.375,-38.696 28.625,-38.696 28.875,-38.946 29.125,-38.946 29.375,-38.696 53.625,-38.696 53.875,-38.946 55.625,-38.946 v1(56,-38.571) ; v1(20,-22.571) 20.375,-22.946 27.125,-22.946 27.375,-22.696 27.625,-22.696 27.875,-22.946 28.125,-22.946 28.375,-22.696 28.625,-22.696 28.875,-22.946 29.125,-22.946 29.375,-22.696 35.625,-22.696 35.875,-22.946 36.125,-22.946 36.375,-22.696 36.625,-22.696 36.875,-22.946 37.125,-22.946 37.5,-22.571 v1(38,-22.571)
  INT3 w0.102: v6(20,-38.571) 20.375,-38.196 20.375,-37.446 20.125,-37.196 20.125,-35.946 20.375,-35.696 20.375,-35.446 20.125,-35.196 20.125,-32.946 20.375,-32.696 20.375,-32.446 20.125,-32.196 20.125,-31.946 20.375,-31.696 20.375,-30.446 20.125,-30.196 20.125,-29.946 20.375,-29.696 20.375,-26.446 20.125,-26.196 20.125,-25.946 20.375,-25.696 20.375,-22.946 v1(20,-22.571)
G1_A24: U1.AJ18 U6.K13 U7.K13 U8.K13 U9.K13 | length 95.4
  INT8 w0.102: v1(40,-32.571) 40,-32.071 43.875,-28.196 43.875,-27.946 43.625,-27.696 43.625,-27.446 43.875,-27.196 43.875,-26.946 43.625,-26.696 43.625,-26.446 43.875,-26.196 43.875,-25.946 43.625,-25.696 43.625,-25.446 43.875,-25.196 43.875,-24.946 43.625,-24.696 43.625,-24.446 43.875,-24.196 43.875,-23.946 43.625,-23.696 43.625,-23.446 43.875,-23.196 43.875,-22.946 43.625,-22.696 43.625,-22.446 43.875,-22.196 43.875,-21.946 43.625,-21.696 43.625,-21.446 43.875,-21.196 43.875,-17.885 43.491,-17.501 43.031,-17.501 42.625,-17.094 42.625,-16.196 v1(42.5,-16.071)
  INT2 w0.102: v1(22,-48.571) 22.5,-49.071 31.75,-49.071 34,-51.321 39.625,-51.321 40.25,-50.696 55.875,-50.696 v1(58,-48.571) ; v6(22,-32.571) 22.375,-32.946 25.125,-32.946 25.375,-32.696 25.625,-32.696 25.875,-32.946 26.125,-32.946 26.375,-32.696 26.625,-32.696 26.875,-32.946 27.125,-32.946 27.375,-32.696 27.625,-32.696 27.875,-32.946 28.125,-32.946 28.375,-32.696 28.625,-32.696 28.875,-32.946 29.125,-32.946 29.375,-32.696 30.625,-32.696 30.875,-32.946 31.125,-32.946 31.375,-32.696 33.625,-32.696 33.875,-32.946 34.125,-32.946 34.375,-32.696 35.625,-32.696 35.875,-32.946 36.125,-32.946 36.375,-32.696 36.625,-32.696 36.875,-32.946 37.125,-32.946 37.375,-32.696 37.625,-32.696 37.875,-32.946 38.125,-32.946 38.375,-32.696 38.625,-32.696 38.875,-32.946 39.125,-32.946 39.5,-32.571 v1(40,-32.571)
  INT3 w0.102: v1(22,-48.571) 22.375,-48.196 22.375,-37.446 22,-37.071 v6(22,-32.571)
G1_A25: U1.AK16 U6.L4 U7.L4 U8.L4 U9.L4 | length 83
  INT7 w0.102: v1(39,-23.571) 39.125,-23.446 39.125,-22.946 39.375,-22.696 39.375,-22.446 39.125,-22.196 39.125,-21.946 39.375,-21.696 39.375,-21.446 39.125,-21.196 39.125,-16.946 40.5,-15.571 v1(40.5,-15.071)
  INT2 w0.102: v6(21,-39.571) 21.375,-39.196 25.125,-39.196 25.375,-39.446 25.625,-39.446 25.875,-39.196 26.125,-39.196 26.375,-39.446 26.625,-39.446 26.875,-39.196 27.125,-39.196 27.375,-39.446 27.625,-39.446 27.875,-39.196 28.125,-39.196 28.375,-39.446 28.625,-39.446 28.875,-39.196 29.25,-39.196 29.5,-39.446 53.625,-39.446 53.875,-39.196 56.625,-39.196 v1(57,-39.571) ; v1(21,-23.571) 21.375,-23.196 27.125,-23.196 27.375,-23.446 27.625,-23.446 27.875,-23.196 28.125,-23.196 28.375,-23.446 28.625,-23.446 28.875,-23.196 31.125,-23.196 31.375,-23.446 35.625,-23.446 35.875,-23.196 36.125,-23.196 36.375,-23.446 36.625,-23.446 36.875,-23.196 37.125,-23.196 37.375,-23.446 37.625,-23.446 37.875,-23.196 38.125,-23.196 38.375,-23.446 38.875,-23.446 v1(39,-23.571)
  INT3 w0.102: v6(21,-39.571) 21.375,-39.196 21.375,-29.446 21.125,-29.196 21.125,-28.946 21.375,-28.696 21.375,-27.446 21.125,-27.196 21.125,-26.946 21.375,-26.696 21.375,-23.946 v1(21,-23.571)
G1_A26: U1.AK17 U6.M2 U7.M2 U8.M2 U9.M2 | length 88.5
  INT7 w0.102: v1(38,-21.571) 38.125,-21.446 38.125,-16.946 38.375,-16.696 38.375,-16.446 38.125,-16.196 38.125,-15.946 40.875,-13.196 41.125,-13.196 41.375,-13.446 41.625,-13.446 41.875,-13.196 42.125,-13.196 42.875,-13.946 42.875,-14.196 42,-15.071 v1(41.5,-15.071)
  INT1 w0.102: v6(20,-37.571) 20.375,-37.946 26.125,-37.946 26.375,-37.696 26.625,-37.696 26.875,-37.946 27.125,-37.946 27.375,-37.696 27.625,-37.696 27.875,-37.946 28.125,-37.946 28.375,-37.696 28.625,-37.696 28.875,-37.946 29.125,-37.946 29.375,-37.696 30.625,-37.696 30.875,-37.946 31.125,-37.946 31.375,-37.696 51.625,-37.696 51.875,-37.946 52.125,-37.946 52.375,-37.696 53.625,-37.696 53.875,-37.946 55.125,-37.946 55.5,-37.571 v1(56,-37.571) ; v1(20,-21.571) 20.375,-21.946 25,-21.946 25.25,-21.696 25.625,-21.696 25.875,-21.946 26.125,-21.946 26.375,-21.696 26.625,-21.696 26.875,-21.946 29.125,-21.946 29.375,-21.696 30.625,-21.696 30.875,-21.946 31.125,-21.946 31.375,-21.696 33.625,-21.696 33.875,-21.946 34.126,-21.946 34.376,-21.696 35.625,-21.696 35.875,-21.946 36.125,-21.946 36.375,-21.696 36.625,-21.696 36.875,-21.946 37.125,-21.946 37.5,-21.571 v1(38,-21.571)
  INT3 w0.102: v6(20,-37.571) 19.875,-37.446 19.875,-35.946 19.625,-35.696 19.625,-35.446 19.875,-35.196 19.875,-32.946 19.625,-32.696 19.625,-31.446 19.875,-31.196 19.875,-30.946 19.625,-30.696 19.625,-29.446 19.875,-29.196 19.875,-28.946 19.625,-28.696 19.625,-27.446 19.875,-27.196 19.875,-26.946 19.625,-26.696 19.625,-21.946 v1(20,-21.571)
G1_A27: U1.AJ16
G1_A28: U1.AH16
G1_A29: U1.AG16
G1_A30: U1.AG17
G1_A31: U1.AJ14
G1_CR#: G1_CR#.1 R97.2 U1.AD18 U6.J2 U7.J2 U8.J2 U9.J2 | length 128.9
  INT6 w0.102: v1(33,-6.571) 33.5,-6.071 37,-6.071 40.375,-2.696 48.625,-2.696 G1_CR#.1@49,-2.321
  INT4 w0.102: v1(33,-6.571) 33.375,-6.946 36.875,-6.946 39.875,-9.946 49,-9.946 49.875,-10.821 49.875,-19.196 49.375,-19.696 44.75,-19.696 43.875,-20.571 43,-20.571 v1(42.5,-21.071) 42,-21.571 v1(41,-21.571)
  INT2 w0.102: v6(23,-37.571) 25.5,-37.571 25.875,-37.196 26.125,-37.196 26.375,-37.446 26.625,-37.446 26.875,-37.196 27.125,-37.196 27.375,-37.446 27.625,-37.446 27.875,-37.196 28.125,-37.196 28.375,-37.446 28.625,-37.446 28.875,-37.196 29.125,-37.196 29.375,-37.446 30.625,-37.446 30.875,-37.196 31.125,-37.196 31.375,-37.446 51.625,-37.446 51.875,-37.196 52.125,-37.196 52.375,-37.446 52.75,-37.446 53,-37.196 54.125,-37.196 54.375,-37.446 54.625,-37.446 54.875,-37.196 58.125,-37.196 58.5,-37.571 v1(59,-37.571) ; v1(23,-21.571) 25.5,-21.571 25.875,-21.946 26.125,-21.946 26.375,-21.696 26.625,-21.696 26.875,-21.946 29.125,-21.946 29.375,-21.696 30.625,-21.696 30.875,-21.946 31.125,-21.946 31.375,-21.696 33.625,-21.696 33.875,-21.946 34.125,-21.946 34.375,-21.696 35.625,-21.696 35.875,-21.946 36.125,-21.946 36.375,-21.696 36.625,-21.696 36.875,-21.946 37.125,-21.946 37.375,-21.696 37.625,-21.696 37.875,-21.946 38.125,-21.946 38.375,-21.696 38.625,-21.696 38.875,-21.946 39.125,-21.946 39.375,-21.696 39.625,-21.696 39.875,-21.946 40.125,-21.946 40.5,-21.571 v1(41,-21.571)
  INT3 w0.102: v6(23,-37.571) 22.375,-36.946 22.375,-22.196 v1(23,-21.571)
G1_G#: G1_G#.1 R95.2 U1.AF14 U6.P7 U7.P7 U8.P7 U9.P7 | length 106.7
  INT4 w0.102: v1(18,-42.571) 18.375,-42.196 18.375,-41.446 18.125,-41.196 18.125,-40.946 18.375,-40.696 18.375,-39.446 18.125,-39.196 18.125,-38.946 18.375,-38.696 18.375,-37.446 18.125,-37.196 18.125,-32.946 18.375,-32.696 18.375,-31.446 18.125,-31.196 18.125,-30.946 18.375,-30.696 18.375,-29.446 18.125,-29.196 18.125,-27.946 18.375,-27.696 18.375,-27.446 18.125,-27.196 18.125,-26.696 v6(18,-26.571)
  INT8 w0.102: v1(36,-26.571) 36,-26.071 36.625,-25.446 36.625,-24.446 36.875,-24.196 36.875,-23.946 36.625,-23.696 36.625,-23.446 38.75,-21.321 38.875,-21.196 38.875,-19.446 v1(38.5,-19.071) ; G1_G#.1@46.5,-51.496 47,-50.996 47,-49.071 53.5,-42.571 v1(54,-42.571)
  INT1 w0.102: v1(18,-42.571) 18.375,-42.196 24.737,-42.196 26.125,-42.196 26.375,-42.446 26.625,-42.446 26.875,-42.196 29.125,-42.196 29.375,-42.446 53.875,-42.446 v1(54,-42.571) 54.125,-42.446 54.625,-42.446 54.875,-42.196 55.125,-42.196 55.375,-42.446 55.625,-42.446 55.875,-42.196 65.625,-42.196 v1(66,-42.571) ; v6(18,-26.571) 18.375,-26.196 20.125,-26.196 20.375,-26.446 20.625,-26.446 20.875,-26.196 24.875,-26.196 25.125,-26.446 25.625,-26.446 25.875,-26.196 26.125,-26.196 26.375,-26.446 26.625,-26.446 26.875,-26.196 29.125,-26.196 29.375,-26.446 35.875,-26.446 v1(36,-26.571)
G1_INT#_0: R156.2 U1.AL12 U6.G13 | length 57
  INT6 w0.102: v1(36.5,-14.071) 37,-14.071 37.375,-14.446 37.375,-14.696 37.125,-14.946 37.125,-15.196 37.875,-15.946 37.875,-16.196 37.625,-16.446 37.625,-16.696 37.875,-16.946 37.875,-19.409 38.162,-19.696 45.625,-19.696 48.625,-22.696 52.625,-22.696 52.875,-22.946 52.875,-24.196 52.125,-24.946 52.125,-32.196 52.375,-32.446 52.375,-32.696 52.125,-32.946 52.125,-33.196 52.375,-33.446 52.375,-33.696 52.125,-33.946 52.125,-36.196 52.375,-36.446 52.375,-36.696 52.125,-36.946 52.125,-37.196 52.375,-37.446 52.375,-37.696 52.125,-37.946 52.125,-40.196 54.875,-42.946 55.875,-42.946 60.375,-47.446 60.375,-47.946 v1(61,-48.571) 61.625,-49.196 62.75,-49.196 v1(63.375,-49.821)
G1_INT#_1: R157.2 U1.AK12 U7.G13 | length 40.5
  INT5 w0.102: v1(36.5,-15.071) 36.5,-15.571 37.375,-16.446 37.375,-16.696 37.125,-16.946 37.125,-17.196 37.875,-17.946 37.875,-19.946 42.875,-24.946 42.875,-29.196 42.625,-29.446 42.625,-29.696 42.875,-29.946 42.875,-30.196 42.625,-30.446 42.625,-30.696 42.875,-30.946 42.875,-31.196 42.625,-31.446 42.625,-31.696 42.875,-31.946 42.875,-32.446 v1(43,-32.571)
  INT3 w0.102: v1(43,-32.571) 43.125,-32.446 43.625,-32.446 43.875,-32.196 44.125,-32.196 44.375,-32.446 44.625,-32.446 44.875,-32.196 45.125,-32.196 45.375,-32.446 45.625,-32.446 45.875,-32.196 49.125,-32.196 49.875,-32.946 52.125,-32.946 52.375,-32.696 52.625,-32.696 52.875,-32.946 54.125,-32.946 54.375,-32.696 54.625,-32.696 54.875,-32.946 56.75,-32.946 57.25,-33.446 v1(61,-33.446)
G1_INT#_2: R158.2 U1.AN12 U8.G13 | length 43.8
  INT8 w0.102: v1(25,-49.821) v1(25,-48.571) 25.336,-48.235 26.836,-48.235 30.875,-44.196 30.875,-37.946 30.625,-37.696 30.625,-36.446 30.875,-36.196 30.875,-28.891 31.147,-28.619 31.147,-27.925 31.913,-27.159 31.913,-21.158 33.875,-19.196 33.875,-18.196 35.625,-16.446 35.625,-14.446 35.875,-14.196 35.875,-13.946 35.625,-13.696 35.625,-13.446 35.875,-13.196 35.875,-12.696 v1(36.5,-12.071)
G1_INT#_3: R159.2 U1.AM12 U9.G13 | length 37.8
  INT6 w0.102: v1(24.5,-24.071) 24.5,-22.571 27.625,-19.446 35.625,-19.446 36.875,-18.196 36.875,-16.946 35.125,-15.196 35.125,-13.946 36,-13.071 v1(36.5,-13.071)
  INT3 w0.102: v1(24.5,-24.071) 24.5,-32.071 v6(25,-32.571) ; v1(32,-8.571) 32.5,-8.571 36.5,-12.571 v1(36.5,-13.071)
G1_PG#: R98.2 U1.AG14 U6.K3 U7.K3 U8.K3 U9.K3 | length 87.2
  INT8 w0.102: v1(38.5,-18.071) 39.125,-18.696 39.125,-21.196 40,-22.071 v1(40,-22.571)
  INT2 w0.102: v6(22,-38.571) 22.375,-38.946 25.125,-38.946 25.375,-38.696 25.625,-38.696 25.875,-38.946 26.125,-38.946 26.375,-38.696 26.625,-38.696 26.875,-38.946 27.125,-38.946 27.375,-38.696 27.625,-38.696 27.875,-38.946 28.125,-38.946 28.375,-38.696 28.625,-38.696 28.875,-38.946 29.125,-38.946 29.375,-38.696 53.625,-38.696 53.875,-38.946 57.125,-38.946 57.5,-38.571 v1(58,-38.571) 58.5,-38.571 59,-39.071 65.5,-39.071 v1(66,-39.571) ; v1(22,-22.571) 22.375,-22.946 27.125,-22.946 27.375,-22.696 27.625,-22.696 27.875,-22.946 28.125,-22.946 28.375,-22.696 28.625,-22.696 28.875,-22.946 29.125,-22.946 29.375,-22.696 35.625,-22.696 35.875,-22.946 36.125,-22.946 36.375,-22.696 36.625,-22.696 36.875,-22.946 37.125,-22.946 37.375,-22.696 37.625,-22.696 37.875,-22.946 38.125,-22.946 38.375,-22.696 38.625,-22.696 38.875,-22.946 39.125,-22.946 39.5,-22.571 v1(40,-22.571)
  INT3 w0.102: v6(22,-38.571) 21.625,-38.196 21.625,-29.446 21.875,-29.196 21.875,-28.946 21.625,-28.696 21.625,-27.446 21.875,-27.196 21.875,-26.946 21.625,-26.696 21.625,-22.946 v1(22,-22.571)
G1_W#: G1_W#.1 R96.2 U1.AH19 | length 27.8
  INT6 w0.102: v1(43.5,-17.071) 43.5,-16.571 43.129,-16.2 43.129,-15.941 43.353,-15.717 43.353,-15.423 43.147,-15.217 43.147,-14.923 43.353,-14.717 43.353,-14.423 43.147,-14.217 43.147,-13.923 43.353,-13.717 43.353,-13.423 43.147,-13.217 43.147,-9.968 41.5,-8.321 41.5,-7.321 41.875,-6.946 41.875,-3.946 v1(41.5,-3.571) 41.875,-3.196 50.25,-3.196 50.875,-2.571 50.875,-1.946 51.125,-1.696 51.683,-1.696 52.308,-2.321 G1_W#.1@52.75,-2.321
G1_W#_0: R148.2 U1.AA28 U6.M8 | length 64.1
  INT6 w0.102: v1(52.5,-24.071) 51.875,-24.696 51.875,-31.196 51.5,-31.571 51.5,-35.446 51.875,-35.821 51.875,-36.196 51.5,-36.571 51.5,-40.571 54.375,-43.446 54.625,-43.446 54.875,-43.196 55.125,-43.196 55.5,-43.571 v1(56,-43.571)
  INT7 w0.102: v1(30,-6.571) 30.375,-6.946 40.875,-6.946 45.875,-11.946 45.875,-12.196 45.625,-12.446 45.625,-12.696 45.875,-12.946 45.875,-13.196 45.625,-13.446 45.625,-13.696 45.875,-13.946 45.875,-14.196 42.926,-17.145 42.926,-21.997 44.875,-23.946 45.125,-23.946 45.375,-23.696 45.625,-23.696 45.875,-23.946 46.125,-23.946 46.375,-23.696 46.625,-23.696 47.375,-24.446 52.125,-24.446 v1(52.5,-24.071)
G1_W#_1: R149.2 U1.AB26 U7.M8 | length 49.9
  INT7 w0.102: v1(31,-8.571) 31.375,-8.946 41.875,-8.946 44.866,-11.937 44.866,-12.205 44.625,-12.446 44.625,-12.696 44.875,-12.946 45.375,-13.446 45.375,-13.696 42.113,-16.958 42.113,-22.957 41.647,-23.423 41.647,-23.717 41.853,-23.923 41.853,-24.217 40.354,-25.717 40.354,-25.718 39.876,-26.196 38.5,-27.571 v1(38,-27.571)
  INT2 w0.102: v1(38,-27.571) 38.5,-27.571 38.875,-27.196 39.125,-27.196 39.25,-27.321 39.375,-27.446 43.625,-27.446 43.875,-27.196 44.125,-27.196 44.375,-27.446 44.625,-27.446 49.375,-22.696 50.125,-22.696 v1(50.5,-23.071)
G1_W#_2: R150.2 U1.AB25 U8.M8 | length 47.9
  Top Layer w0.102: U8.M8@20,-43.571 20.378,-43.949 21.938,-43.949 v1(21.971,-43.917)
  INT4 w0.102: v1(21.971,-43.917) 21.971,-43.6 22.375,-43.196 22.375,-31.696 28.875,-25.196 29.125,-25.196 29.375,-25.446 35.5,-25.446 35.75,-25.196 37.125,-25.196 37.375,-25.446 37.625,-25.446 37.875,-25.196 38.125,-25.196 38.375,-25.446 38.625,-25.446 38.875,-25.196 39.125,-25.196 39.375,-25.446 43.625,-25.446 43.875,-25.196 44.125,-25.196 44.375,-25.446 44.625,-25.446 44.875,-25.196 45.125,-25.196 45.375,-25.446 45.625,-25.446 45.75,-25.321 46.375,-24.696 46.625,-24.696 46.875,-24.946 47.125,-24.946 47.375,-24.696 49.5,-24.696 49.875,-24.321 49.875,-23.446 v1(49.5,-23.071)
G1_W#_3: R151.2 U1.Y27 U9.M8 | length 38.7
  INT5 w0.102: v6(20,-27.571) 21.5,-27.571 21.875,-27.196 22.375,-27.196 v1(22.75,-27.571)
  INT4 w0.102: v1(22.75,-27.571) 23.125,-27.571 25.75,-24.946 27.125,-24.946 27.375,-24.696 27.625,-24.696 27.875,-24.946 28.125,-24.946 28.375,-24.696 28.625,-24.696 28.875,-24.946 29.125,-24.946 29.375,-24.696 35.5,-24.696 35.75,-24.946 37.125,-24.946 37.375,-24.696 37.625,-24.696 37.875,-24.946 38.125,-24.946 38.375,-24.696 38.625,-24.696 38.875,-24.946 39.125,-24.946 39.375,-24.696 39.626,-24.696 39.854,-24.924 40.146,-24.924 40.374,-24.696 42.625,-24.696 42.875,-24.946 43.125,-24.946 43.375,-24.696 43.625,-24.696 43.875,-24.946 44.125,-24.946 44.375,-24.696 44.625,-24.696 44.875,-24.946 45.125,-24.946 45.875,-24.196 46.125,-24.196 46.375,-24.446 46.625,-24.446 46.875,-24.196 47.125,-24.196 47.375,-24.446 48.875,-24.446 49.125,-24.196 49.125,-22.946 49.375,-22.696 50.716,-22.696 51,-22.98 51,-24.571 v1(51.5,-25.071)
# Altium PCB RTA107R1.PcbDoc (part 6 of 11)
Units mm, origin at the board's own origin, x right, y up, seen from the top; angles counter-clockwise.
Board outline 96.01 x 65.66 mm, 22 copper layers (Top Layer, GND1, INT1, PWR1-(VCCIO_MRAM), INT2, PWR2-(VCCINT), INT3, PWR3_(12V_MGTAVCC), INT4, GND2-(DGND_SGND), PWR4_(MGTAVTT_VCCBRAM,VCCAUX), PWR5-(VCC_12V), GND3-(DGND_GND), INT5, GND4, INT6, PWR6_(VCCO), INT7, GND5, INT8, GND6, Bottom Layer), stack 2.833 mm thick; 614 components, 659 nets, 4037 pads, 3511 vias.

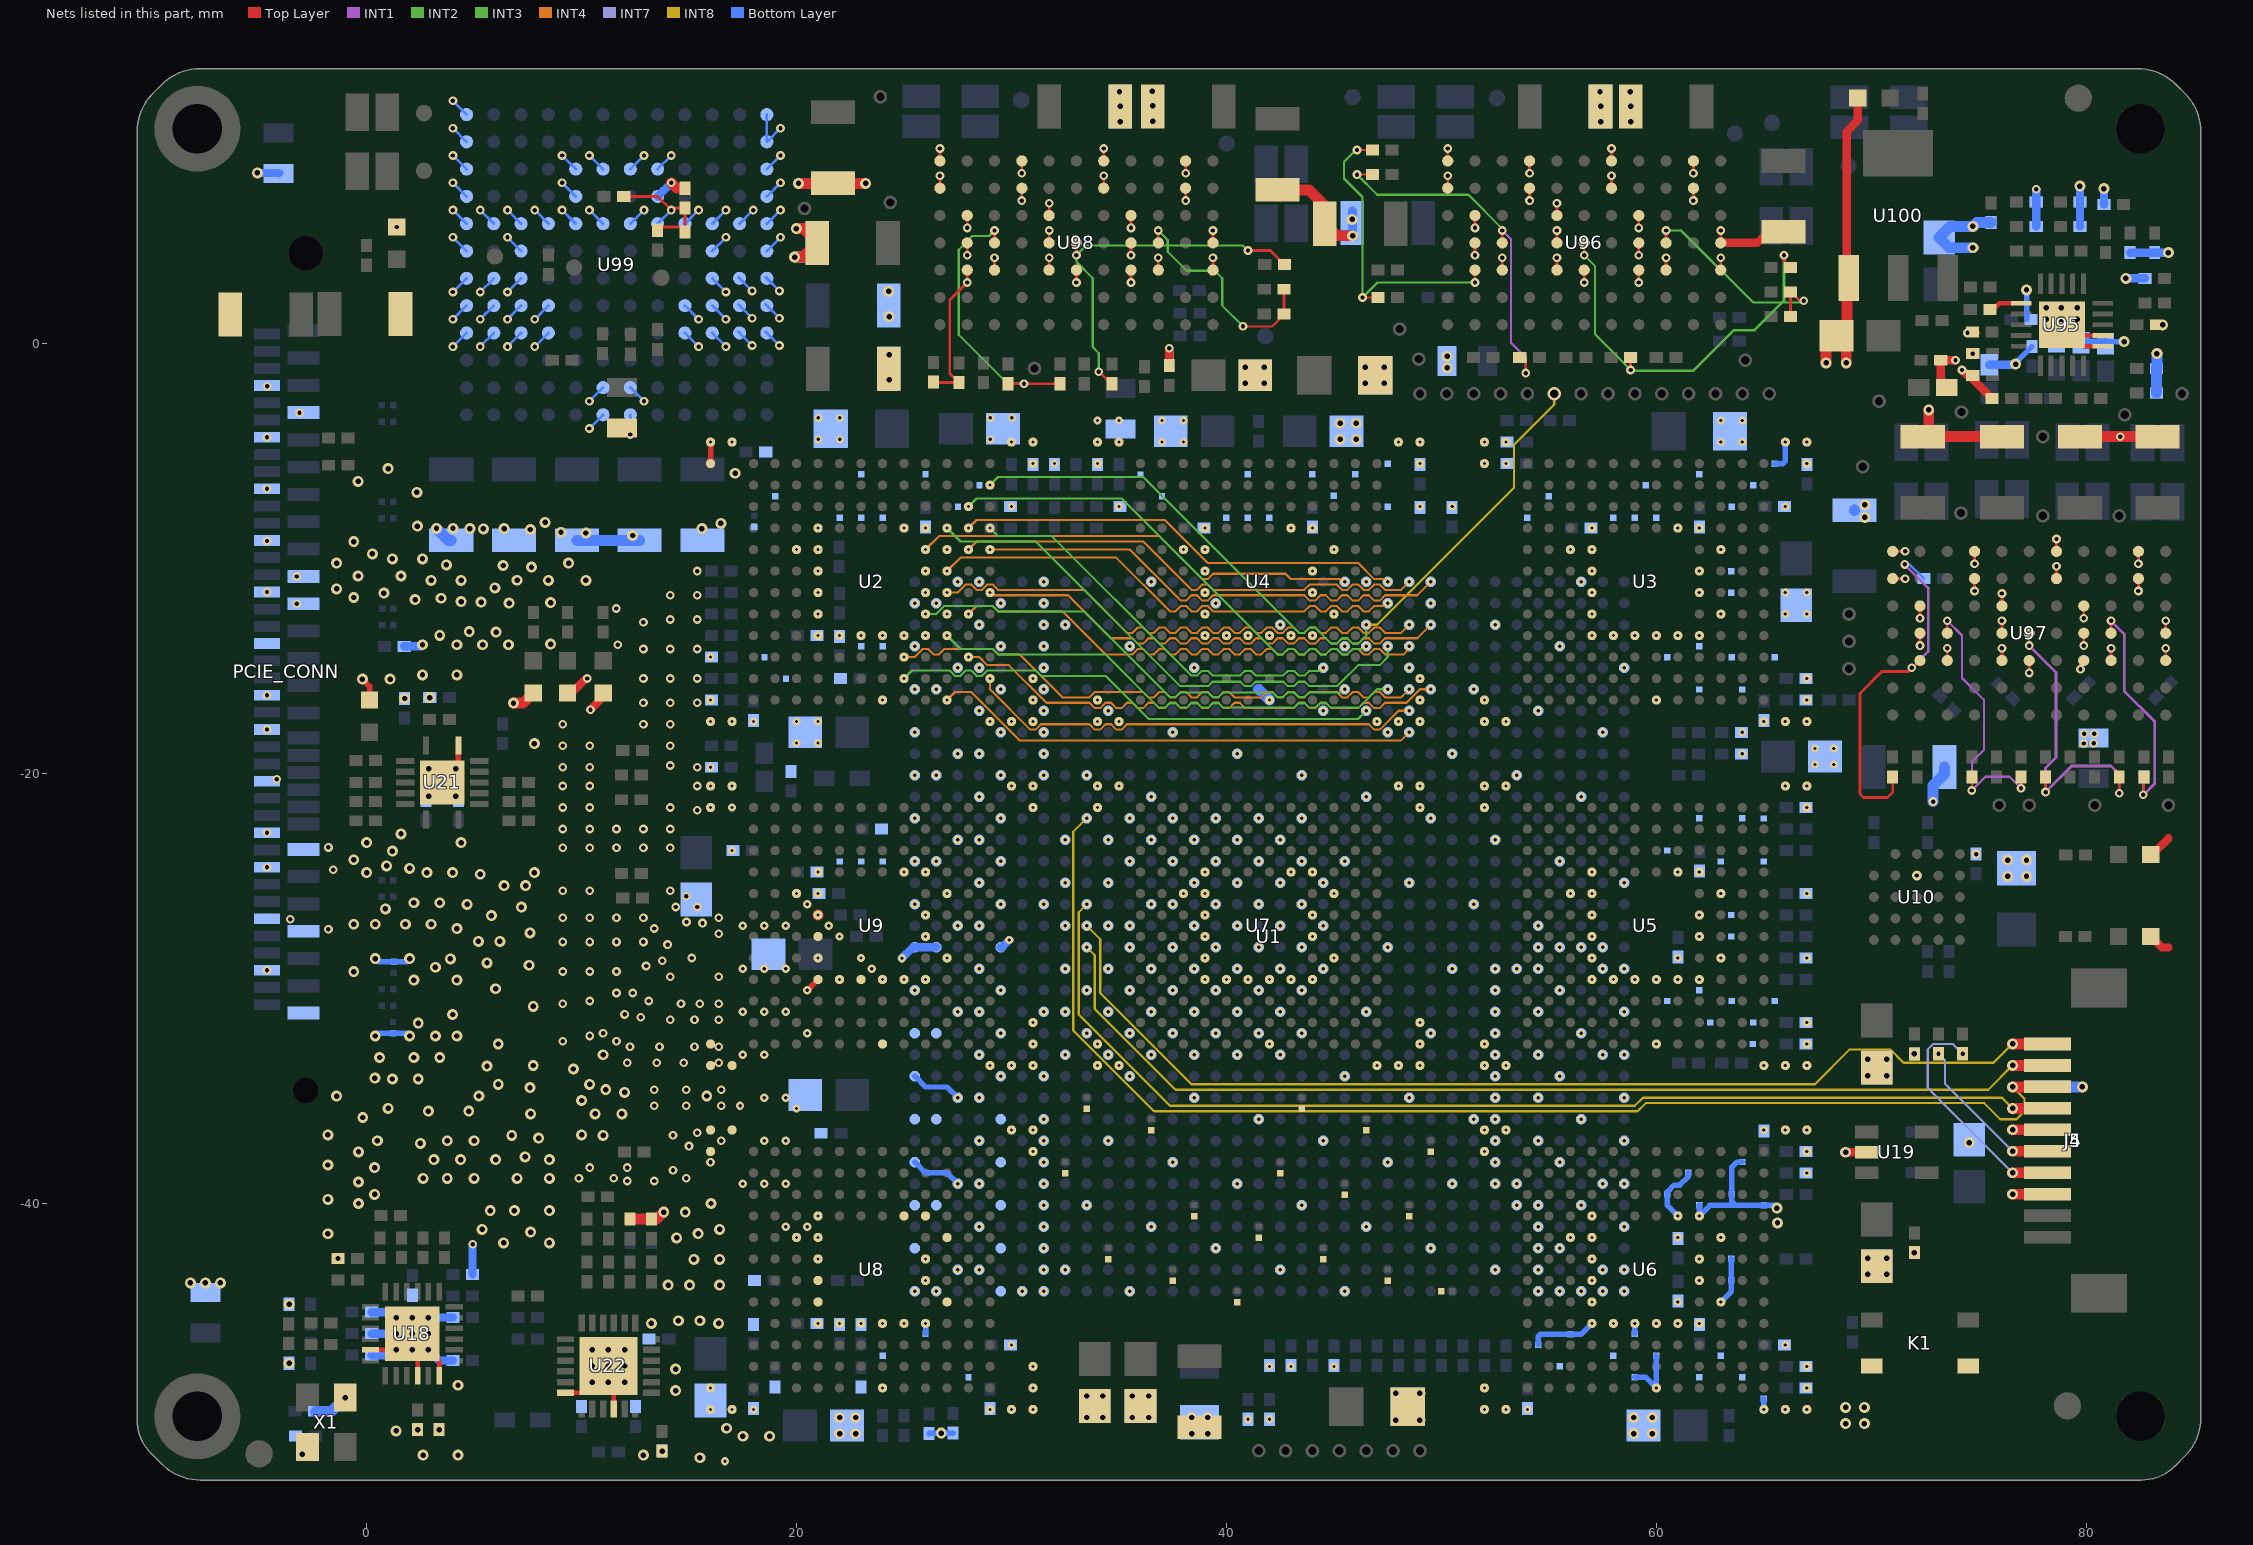
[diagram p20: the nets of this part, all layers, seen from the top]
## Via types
v1: diameter 0.381, hole 0.152, Top Layer to Bottom Layer, tented both sides, 2009 vias
v2: diameter 0.508, hole 0.254, Top Layer to Bottom Layer, tented both sides, 467 vias
v3: diameter 0.406, hole 0.203, Top Layer to Bottom Layer, 458 vias
v4: diameter 0.508, hole 0.254, Top Layer to Bottom Layer, 239 vias
v5: diameter 0.406, hole 0.203, Top Layer to Bottom Layer, tented both sides, 181 vias
v6: diameter 0.381, hole 0.152, Top Layer to GND4, tented both sides, 147 vias
v7: diameter 0.406, hole 0.203, Top Layer to GND4, tented both sides, 10 vias

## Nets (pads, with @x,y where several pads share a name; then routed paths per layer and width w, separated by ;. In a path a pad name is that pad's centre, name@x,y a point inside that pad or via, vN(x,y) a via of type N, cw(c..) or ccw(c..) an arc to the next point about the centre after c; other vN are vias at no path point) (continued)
GND: C91.1 C92.1 C93.1 C94.1 C95.1 C96.1 C97.1 C98.1 C99.1 C100.1 C101.1 C102.1 C103.1 C104.1 C105.1 C106.1 C107.1 C108.1 C109.1 C110.1 C111.1 C112.1 C113.1 C114.1 C115.2 C116.1 C117.1 C118.1 C119.2 C120.1 C121.1 C122.1 C123.2 C124.1 C125.1 C126.1 C129.1 C130.1 C131.1 C132.1 C133.1 C134.1 C135.1 C136.1 C137.1 C138.1 C139.1 C140.1 C141.1 C142.1 C143.1 C144.1 C145.1 C146.1 C147.1 C148.1 C149.1 C150.1 C151.1 C152.1 C153.1 C154.1 C155.1 C156.1 C157.1 C158.1 C159.1 C160.1 C161.1 C162.1 C163.1 C164.1 C165.1 C166.1 C167.1 C168.1 C169.1 C170.1 C171.1 C172.1 C173.1 C174.1 C175.1 C176.1 C177.1 C178.1 C179.1 C180.1 C203.1 C204.1 C205.1 C206.1 C207.1 C208.1 C213.1 C214.1 C215.1 C216.1 C217.1 C218.1 C219.2 C220.1 C233.2 C234.2 C235.2 C236.2 C237.2 C238.2 C317.1 C318.1 C321.1 C322.1 C323.1 C324.1 C325.1 C500.1 C501.1 C502.1 C503.1 C504.1 C505.1 C506.1 C507.1 C508.1 C509.1 C511.1 C512.1 C513.1 C514.1 C515.1 C516.1 C517.1 C522.1 C523.1 C524.1 C525.1 C526.1 C527.1 C532.1 C533.1 C534.1 C535.1 C536.1 C537.1 C542.1 C543.1 C544.1 C545.1 C546.1 C547.1 C548.1 C800.1 C801.1 CS1.1 CS2.1 CS3.1 CS4.1 CS5.1 CS6.1 CS7.1 CS8.1 CS9.1 CS12.1 CS13.1 CS14.1 CS15.1 CS16.1 CS17.1 CS18.1 CS23.1 CS24.1 CS25.1 CS26.1 CS27.1 CS33.1 CS34.1 CS35.1 CS36.1 CS37.1 CS38.1 CS41.1 CS42.1 CS43.1 CS45.1 CS46.1 CS47.1 CS48.1 CS49.1 CS50.1 CS53.1 CS54.1 CS55.1 CS56.1 CS57.1 CS58.1 CS59.1 CS60.1 CS61.1 CS62.1 CS63.1 CS67.1 CS68.1 CS71.1 CS72.1 CS73.1 CS74.1 CS75.1 CS76.1 CS77.1 CS78.1 CS79.1 CS80.1 CS83.1 CS84.1 CS85.1 CS86.1 CS87.1 CS88.1 CS91.1 CS92.1 CS93.1 CS94.1 CS95.1 CS96.1 CS97.1 CS98.1 CS99.1 CS100.1 CS101.1 CS102.1 CS104.1 CS106.1 CS107.1 CS108.1 CS109.1 CX1.1 CX2.1 CX3.1 CX4.1 CX6.1 CX7.1 CX8.1 CX9.1 CX10.1 CX12.1 CX13.1 CX14.1 CX15.1 CX16.1 CX17.1 CX18.1 CX19.1 D2.2 D4.2 D5.2 D6.2 D7.2 D8.2 D9.2 D10.1 D11.1 D12.1 D13.1 D14.1 FB1.1 FB2.1 FB3.1 FB4.1 FB5.1 FB6.1 J4.3 J5.3 J5.6 K1.3 K1.4 LED100.2 PCIE_CONN.E9 PCIE_CONN.E12 PCIE_CONN.E15 PCIE_CONN.E19 PCIE_CONN.E22 PCIE_CONN.P5 PCIE_CONN.P6 PCIE_CONN.P12 PCIE_CONN.S1 PCIE_CONN.S4 PCIE_CONN.S7 PCIE_CONN.S8 PCIE_CONN.S11 PCIE_CONN.S14 PCIE_CONN.S16 PCIE_CONN.S19 PCIE_CONN.S22 PCIE_CONN.S25 PCIE_CONN.S28 R2.2 R25.2 R65.2 R68.2 R69.2 R70.2 R73.2 R74.2 R123.2 R124.2 R125.2 R126.2 R127.2 R128.2 R129.2 R130.2 R131.2 R273.2 R274.2 R275.2 R276.2 R534.1 R536.1 R538.1 R540.1 R542.1 R544.1 R546.1 R548.1 R550.1 R602.1 R634.2 R636.2 R638.2 R640.2 R800.1 U1.A1 U1.A2 U1.A5 U1.A6 U1.A7 U1.A11 U1.A21 U1.A30 U1.A31 U1.A32 U1.A33 U1.A34 U1.AA1 U1.AA2 U1.AA5 U1.AA11 U1.AA13 U1.AA15 U1.AA17 U1.AA19 U1.AA21 U1.AA31 U1.AB3 U1.AB4 U1.AB8 U1.AB10 U1.AB12 U1.AB14 U1.AB16 U1.AB18 U1.AB28 U1.AC1 U1.AC5 U1.AC11 U1.AC13 U1.AC15 U1.AC17 U1.AC19 U1.AC25 U1.AD4 U1.AD12 U1.AD22 U1.AD32 U1.AE1 U1.AE2 U1.AE5 U1.AE7 U1.AE9 U1.AE19 U1.AE29 U1.AF3 U1.AF4 U1.AF7 U1.AF16 U1.AF26 U1.AG1 U1.AG5 U1.AG7 U1.AG13 U1.AG23 U1.AG33 U1.AH4 U1.AH7 U1.AH10 U1.AH20 U1.AH30 U1.AJ1 U1.AJ2 U1.AJ5 U1.AJ7 U1.AJ17 U1.AJ27 U1.AK3 U1.AK4 U1.AK7 U1.AK14 U1.AK24 U1.AK34 U1.AL1 U1.AL5 U1.AL7 U1.AL11 U1.AL21 U1.AL31 U1.AM4 U1.AM7 U1.AM8 U1.AM18 U1.AM28 U1.AN1 U1.AN2 U1.AN5 U1.AN7 U1.AN15 U1.AN25 U1.AP3 U1.AP4 U1.AP7 U1.AP12 U1.AP22 U1.AP32 U1.B3 U1.B4 U1.B7 U1.B8 U1.B18 U1.B28 U1.B30 U1.B33 U1.B34 U1.C1 U1.C5 U1.C7 U1.C15 U1.C25 U1.C30 U1.C31 U1.D4 U1.D7 U1.D12 U1.D22 U1.D30 U1.D34 U1.E1 U1.E2 U1.E5 U1.E7 U1.E9 U1.E19 U1.E29 U1.E30 U1.E32 U1.F3 U1.F4 U1.F7 U1.F16 U1.F26 U1.F28 U1.F29 U1.F33 U1.F34 U1.G1 U1.G5 U1.G7 U1.G13 U1.G23 U1.G28 U1.G31 U1.H4 U1.H7 U1.H10 U1.H20 U1.H28 U1.H30 U1.H34 U1.J1 U1.J2 U1.J5 U1.J7 U1.J17 U1.J27 U1.J28 U1.J32 U1.K3 U1.K4 U1.K14 U1.K24 U1.K28 U1.K30 U1.K34 U1.L1 U1.L5 U1.L7 U1.L11 U1.L21 U1.L28 U1.L31 U1.M4 U1.M8 U1.M10 U1.M12 U1.M14 U1.M16 U1.M18 U1.M28 U1.M30 U1.M33 U1.M34 U1.N1 U1.N2 U1.N5 U1.N9 U1.N11 U1.N13 U1.N15 U1.N17 U1.N19 U1.N25 U1.N28 U1.N32 U1.P3 U1.P4 U1.P7 U1.P8 U1.P10 U1.P12 U1.P14 U1.P16 U1.P18 U1.P22 U1.P28 U1.P30 U1.P34 U1.R1 U1.R5 U1.R9 U1.R11 U1.R13 U1.R15 U1.R17 U1.R19 U1.R28 U1.R31 U1.T4 U1.T8 U1.T10 U1.T12 U1.T14 U1.T16 U1.T18 U1.T20 U1.T26 U1.T28 U1.T29 U1.T30 U1.T33 U1.T34 U1.U1 U1.U2 U1.U5 U1.U11 U1.U13 U1.U15 U1.U17 U1.U19 U1.U23 U1.U30 U1.U31 U1.U32 U1.U33 U1.V3 U1.V4 U1.V8 U1.V10 U1.V11 U1.V14 U1.V16 U1.V18 U1.V20 U1.V30 U1.W1 U1.W5 U1.W7 U1.W12 U1.W13 U1.W15 U1.W17 U1.W19 U1.W27 U1.Y4 U1.Y8 U1.Y10 U1.Y14 U1.Y16 U1.Y18 U1.Y20 U1.Y24 U1.Y34 U2.A1 U2.A2 U2.A12 U2.A13 U2.A14 U2.B1 U2.B14 U2.C14 U2.E6 U2.E9 U2.F5 U2.F7 U2.F8 U2.F10 U2.G5 U2.G10 U2.H10 U2.H13 U2.J10 U2.K10 U2.L5 U2.L6 U2.L7 U2.L8 U2.L9 U2.L10 U2.M6 U2.R1 U2.R14 U2.T1 U2.T2 U2.T13 U2.T14 U3.A1 U3.A2 U3.A12 U3.A13 U3.A14 U3.B1 U3.B14 U3.C14 U3.E6 U3.E9 U3.F5 U3.F7 U3.F8 U3.F10 U3.G5 U3.G10 U3.H10 U3.H13 U3.J10 U3.K10 U3.L5 U3.L6 U3.L7 U3.L8 U3.L9 U3.L10 U3.M6 U3.R1 U3.R14 U3.T1 U3.T2 U3.T13 U3.T14 U4.A1 U4.A2 U4.A12 U4.A13 U4.A14 U4.B1 U4.B14 U4.C14 U4.E6 U4.E9 U4.F5 U4.F7 U4.F8 U4.F10 U4.G5 U4.G10 U4.H10 U4.H13 U4.J10 U4.K10 U4.L5 U4.L6 U4.L7 U4.L8 U4.L9 U4.L10 U4.M6 U4.R1 U4.R14 U4.T1 U4.T2 U4.T13 U4.T14 U5.A1 U5.A2 U5.A12 U5.A13 U5.A14 U5.B1 U5.B14 U5.C14 U5.E6 U5.E9 U5.F5 U5.F7 U5.F8 U5.F10 U5.G5 U5.G10 U5.H10 U5.H13 U5.J10 U5.K10 U5.L5 U5.L6 U5.L7 U5.L8 U5.L9 U5.L10 U5.M6 U5.R1 U5.R14 U5.T1 U5.T2 U5.T13 U5.T14 U6.A1 U6.A2 U6.A12 U6.A13 U6.A14 U6.B1 U6.B14 U6.C14 U6.E6 U6.E9 U6.F5 U6.F7 U6.F8 U6.F10 U6.G5 U6.G10 U6.H10 U6.H13 U6.J10 U6.K10 U6.L5 U6.L6 U6.L7 U6.L8 U6.L9 U6.L10 U6.M6 U6.R1 U6.R14 U6.T1 U6.T2 U6.T13 U6.T14 U7.A1 U7.A2 U7.A12 U7.A13 U7.A14 U7.B1 U7.B14 U7.C14 U7.E6 U7.E9 U7.F5 U7.F7 U7.F8 U7.F10 U7.G5 U7.G10 U7.H10 U7.H13 U7.J10 U7.K10 U7.L5 U7.L6 U7.L7 U7.L8 U7.L9 U7.L10 U7.M6 U7.R1 U7.R14 U7.T1 U7.T2 U7.T13 U7.T14 U8.A1 U8.A2 U8.A12 U8.A13 U8.A14 U8.B1 U8.B14 U8.C14 U8.E6 U8.E9 U8.F5 U8.F7 U8.F8 U8.F10 U8.G5 U8.G10 U8.H10 U8.H13 U8.J10 U8.K10 U8.L5 U8.L6 U8.L7 U8.L8 U8.L9 U8.L10 U8.M6 U8.R1 U8.R14 U8.T1 U8.T2 U8.T13 U8.T14 U9.A1 U9.A2 U9.A12 U9.A13 U9.A14 U9.B1 U9.B14 U9.C14 U9.E6 U9.E9 U9.F5 U9.F7 U9.F8 U9.F10 U9.G5 U9.G10 U9.H10 U9.H13 U9.J10 U9.K10 U9.L5 U9.L6 U9.L7 U9.L8 U9.L9 U9.L10 U9.M6 U9.R1 U9.R14 U9.T1 U9.T2 U9.T13 U9.T14 U10.B3 U18.4 U18.6 U18.23 U18.25 U19.2 U21.7 U21.15 U22.4 U22.24 U22.25 U95.11 U95.12 U95.21 U96.A4 U96.A5 U96.B1 U96.B2 U96.C5 U96.D3 U96.D4 U96.D5 U96.E1 U96.E2 U96.F5 U96.G3 U96.G4 U96.G5 U96.H1 U96.H2 U96.J5 U96.K3 U96.K4 U96.L1 U96.L2 U97.A4 U97.A5 U97.B1 U97.B2 U97.C5 U97.D3 U97.D4 U97.D5 U97.E1 U97.E2 U97.F5 U97.G3 U97.G4 U97.G5 U97.H1 U97.H2 U97.J5 U97.K3 U97.K4 U97.L1 U97.L2 U98.A4 U98.A5 U98.B1 U98.B2 U98.C5 U98.D3 U98.D4 U98.D5 U98.E1 U98.E2 U98.F5 U98.G3 U98.G4 U98.G5 U98.H1 U98.H2 U98.J5 U98.K3 U98.K4 U98.L1 U98.L2 U99.A6 U99.A7 U99.B6 U99.B7 U99.D1 U99.D2 U99.D3 U99.D4 U99.D9 U99.D10 U99.D11 U99.D12 U99.E1 U99.E2 U99.E3 U99.E4 U99.E9 U99.E10 U99.E11 U99.E12 U99.F1 U99.F2 U99.F3 U99.F10 U99.F11 U99.F12 U99.G1 U99.G3 U99.G10 U99.G12 U99.H1 U99.H2 U99.H3 U99.H4 U99.H5 U99.H6 U99.H7 U99.H9 U99.H10 U99.H11 U99.H12 U99.J1 U99.J5 U99.J8 U99.J12 U99.K1 U99.K5 U99.K6 U99.K7 U99.K8 U99.K12 U99.L1 U99.L12 U99.M1 U99.M12 U100.1 X1.2 X1.4 | length 239.2
  Top Layer w0.127: U98.L2@26.67,7.239 v3(26.67,7.815) ; U98.L1@26.67,8.509 v3(26.67,9.085) ; v3(27.94,4.123) U98.K4@27.94,4.699 ; v3(27.94,5.393) U98.K3@27.94,5.969 ; U98.J5@29.21,3.429 v3(29.21,4.005) ; v3(30.48,6.663) U98.H2@30.48,7.239 ; v3(30.48,7.933) U98.H1@30.48,8.509 ; U98.G5@31.75,3.429 v3(31.75,4.005) ; U98.G4@31.75,4.699 v3(31.75,5.275) ; U98.G3@31.75,5.969 v3(31.75,6.545) ; v3(33.02,2.853) U98.F5@33.02,3.429 ; U98.E2@34.29,7.239 v3(34.29,7.815) ; U98.E1@34.29,8.509 v3(34.29,9.085) ; v3(35.56,2.853) U98.D5@35.56,3.429 ; v3(35.56,4.123) U98.D4@35.56,4.699 ; v3(35.56,5.393) U98.D3@35.56,5.969 ; U98.C5@36.83,3.429 v3(36.83,4.005) ; v3(38.1,6.663) U98.B2@38.1,7.239 ; v3(38.1,7.933) U98.B1@38.1,8.509 ; U98.A5@39.37,3.429 v3(39.37,4.005) ; U98.A4@39.37,4.699 v3(39.37,5.275) ; U96.L2@50.292,7.239 v3(50.292,7.815) ; U96.L1@50.292,8.509 v3(50.292,9.085) ; v3(51.562,4.123) U96.K4@51.562,4.699 ; v3(51.562,5.393) U96.K3@51.562,5.969 ; U96.J5@52.832,3.429 v3(52.832,4.005) ; v3(54.102,6.663) U96.H2@54.102,7.239 ; v3(54.102,7.933) U96.H1@54.102,8.509 ; U96.G5@55.372,3.429 v3(55.372,4.005) ; U96.G4@55.372,4.699 v3(55.372,5.275) ; U96.G3@55.372,5.969 v3(55.372,6.545) ; v3(56.642,2.853) U96.F5@56.642,3.429 ; U96.E2@57.912,7.239 v3(57.912,7.815) ; U96.E1@57.912,8.509 v3(57.912,9.085) ; v3(59.182,2.853) U96.D5@59.182,3.429 ; v3(59.182,4.123) U96.D4@59.182,4.699 ; v3(59.182,5.393) U96.D3@59.182,5.969 ; U96.C5@60.452,3.429 v3(60.452,4.005) ; v3(61.722,6.663) U96.B2@61.722,7.239 ; v3(61.722,7.933) U96.B1@61.722,8.509 ; U96.A5@62.992,3.429 v3(62.992,4.005) ; U96.A4@62.992,4.699 v3(62.992,5.275) ; U97.L2@70.993,-10.922 71.389,-10.922 v3(71.569,-10.922) ; U97.L1@70.993,-9.652 v3(71.569,-9.652) ; v3(72.263,-14.038) U97.K4@72.263,-13.462 ; v3(72.263,-12.768) U97.K3@72.263,-12.192 ; U97.J5@73.533,-14.732 v3(73.533,-14.156) ; v3(74.803,-11.498) U97.H2@74.803,-10.922 ; v3(74.803,-10.228) U97.H1@74.803,-9.652 ; U97.G5@76.073,-14.732 v3(76.073,-14.156) ; U97.G4@76.073,-13.462 v3(76.073,-12.886) ; U97.G3@76.073,-12.192 v3(76.073,-11.616) ; v3(77.343,-15.308) U97.F5@77.343,-14.732 ; U97.E2@78.613,-10.922 v3(78.613,-10.346) ; U97.E1@78.613,-9.652 v3(78.613,-9.076) ; v3(79.731,-15.138) 79.731,-14.884 U97.D5@79.883,-14.732 ; v3(79.883,-14.038) U97.D4@79.883,-13.462 ; v3(79.883,-12.768) U97.D3@79.883,-12.192 ; U97.C5@81.153,-14.732 v3(81.153,-14.156) ; v3(82.423,-11.498) U97.B2@82.423,-10.922 ; v3(82.423,-10.228) U97.B1@82.423,-9.652 ; U97.A5@83.693,-14.732 v3(83.693,-14.156) ; U97.A4@83.693,-13.462 v3(83.693,-12.886)
  Top Layer w0.203: U18.23@0.175,-46.801 v2(1.375,-46.801) v2(2.125,-46.051) v2(2.875,-46.801) 3.375,-47.301 U18.6@3.375,-48.001 ; v2(2.125,-46.801) 2.375,-47.051 U18.4@2.375,-48.001 ; U22.24@9.3,-48.801 10,-48.801 v2(10.5,-48.301) v2(11.25,-47.551) ; v2(11.25,-48.301) 11.5,-48.551 U22.4@11.5,-49.501 ; U95.21@78.867,0.889 U95.21@79.367,0.389 ; U95.11@80.767,-0.111 79.867,-0.111 U95.21@79.367,0.389 ; U95.12@80.767,0.389 U95.21@79.367,0.389 ; C546.1@83.058,0.883 v4(83.547,0.883)
  Top Layer w0.254: v2(-0.2,-15.6) 0.138,-15.938 D9.2@0.138,-16.566 ; U21.15@3.518,-20.406 4.268,-19.656 U21.7@4.268,-18.681 ; U2.T2@16,-5.571 v1(16,-4.571) ; v1@20.5,-30.074 v1(20.5,-30.071) U9.L10@21,-29.571 ; v4(65.608,-40.208) v4@65.659,-40.208 ; v3(74.473,0.508) C543.1@74.918,0.508
  Top Layer w0.381: v3(1.397,5.436) D4.2@1.397,5.437 ; D6.2@9.349,-16.243 9.538,-16.243 10.21,-15.571 v5(10.262,-15.571) ; v5(10.414,-17.018) 11.004,-16.428 D8.2@11.004,-16.243 ; C96.1@37.338,-1.016 v3(37.338,-0.203) ; C512.1@42.367,7.164 C512.1@42.774,7.164 ; U96.A4@62.992,4.699 64.694,4.699 65.203,5.208 C532.1@65.913,5.208 ; v2(68.806,-37.609) U19.2@69.781,-37.609 ; U100.1@68.859,2.981 68.859,9.88 69.366,10.387 LED100.2@69.366,11.43 ; D10.1@73.586,-2.032 73.586,-1.983 73.228,-1.626 R542.1@73.228,-0.762 v3(73.914,-0.762) ; v3(74.219,-1.219) 74.473,-1.473 C545.1@74.716,-1.473 ; C545.1@74.701,-1.575 74.701,-1.626 R634.2@75.616,-2.54 ; D2.2@83,-27.571 83.512,-28.083 83.828,-28.083 ; D5.2@83,-23.761 83.069,-23.761 83.828,-23.003
  Top Layer w0.508: v2(6.833,-16.713) 7.284,-16.713 D7.2@7.754,-16.243 ; R273.2@12.25,-40.719 R274.2@13.25,-40.719 13.494,-40.719 v2(13.821,-40.391) ; v3(14.173,7.493) 14.427,7.239 C511.1@14.808,7.239 ; v4(19.914,4.039) 20.297,4.039 C516.1@20.957,4.699 20.957,4.722 20.32,5.359 v4(19.99,5.359) ; v4(20.091,7.468) 20.092,7.469 C509.1@21.692,7.469 23.215,7.469 v4(23.216,7.468) ; C512.1@42.774,7.164 43.839,7.164 44.578,6.425 C536.1@44.578,5.588 45.137,5.029 v4(45.872,5.029) ; v4(67.894,-0.889) 67.894,-0.102 C548.1@68.377,0.381 ; v4(68.834,-0.889) 68.834,-0.076 C548.1@68.377,0.381 ; U100.1@68.859,2.981 68.859,0.863 C548.1@68.377,0.381 ; v4(72.669,-3.073) 72.669,-4.04 C525.1@72.39,-4.319 C524.1@76.073,-4.319 ; v2(76.571,-39.563) J5.3@78.196,-39.563 ; v2(76.571,-36.562) J5.6@78.196,-36.562 ; C523.1@79.452,-4.319 C523.1@79.71,-4.319 v3(81.585,-4.319) C522.1@83.312,-4.319 C522.1@83.819,-4.319
  INT3 w0.254: v1(22,-29.571) 22.016,-29.571 v1@22.022,-29.566
  Bottom Layer w0.127: v3(4.013,-0.127) U99.D1@4.648,0.508 ; v3(4.013,1.143) U99.E1@4.648,1.778 ; v3(4.013,2.413) U99.F1@4.648,3.048 ; v3(4.013,4.953) U99.G1@4.648,4.318 ; v3(4.013,6.223) U99.H1@4.648,5.588 ; v3(4.013,7.493) U99.J1@4.648,6.858 ; v3(4.013,8.763) U99.K1@4.648,8.128 ; v3(4.013,10.033) U99.L1@4.648,9.398 ; v3(4.013,11.303) U99.M1@4.648,10.668 ; v3(5.283,-0.127) U99.D2@5.918,0.508 ; v3(5.283,1.143) U99.E2@5.918,1.778 ; v3(5.283,2.413) U99.F2@5.918,3.048 ; v3(5.283,6.223) U99.H2@5.918,5.588 ; v3(6.553,-0.127) U99.D3@7.188,0.508 ; v3(6.553,1.143) U99.E3@7.188,1.778 ; v3(6.553,2.413) U99.F3@7.188,3.048 ; v3(6.553,4.953) U99.G3@7.188,4.318 ; v3(6.553,6.223) U99.H3@7.188,5.588 ; v3(7.823,-0.127) U99.D4@8.458,0.508 ; v3(7.823,1.143) U99.E4@8.458,1.778 ; v3(7.823,6.223) U99.H4@8.458,5.588 ; v3(9.093,6.223) U99.H5@9.728,5.588 ; v3(9.093,7.493) U99.J5@9.728,6.858 ; v3(9.093,8.763) U99.K5@9.728,8.128 ; v3(10.363,-3.937) U99.A6@10.998,-3.302 ; v3(10.363,-2.667) U99.B6@10.998,-2.032 ; v3(10.363,6.223) U99.H6@10.998,5.588 ; v3(10.363,8.763) U99.K6@10.998,8.128 ; v3(12.268,-4.216) U99.A7@12.268,-3.302 ; U99.B7@12.268,-2.032 v3(12.903,-2.667) ; U99.H7@12.268,5.588 v3(12.903,6.223) ; U99.K7@12.268,8.128 v3(12.903,8.763) ; U99.K8@13.538,8.128 v3(14.173,8.763) ; U99.D9@14.808,0.508 v3(15.443,-0.127) ; U99.E9@14.808,1.778 v3(15.443,1.143) ; U99.H9@14.808,5.588 v3(15.443,6.223) ; U99.D10@16.078,0.508 v3(16.713,-0.127) ; U99.E10@16.078,1.778 v3(16.713,1.143) ; U99.F10@16.078,3.048 v3(16.713,2.413) ; U99.G10@16.078,4.318 v3(16.713,4.953) ; U99.H10@16.078,5.588 v3(16.713,6.223) ; U99.D11@17.297,0.559 v3(17.932,-0.076) ; U99.E11@17.297,1.829 v3(17.932,1.194) ; U99.F11@17.297,3.099 v3(17.932,2.464) ; U99.H11@17.348,5.588 v3(17.983,6.223) ; U99.D12@18.567,0.559 v3(19.202,-0.076) ; U99.E12@18.567,1.829 v3(19.202,1.194) ; U99.F12@18.567,3.099 v3(19.202,2.464) ; U99.G12@18.618,4.318 v3(19.253,4.953) ; U99.H12@18.618,5.588 v3(19.253,6.223) ; U99.J12@18.618,6.858 v3(19.253,7.493) ; U99.K12@18.618,8.128 v3(19.253,8.763) ; U99.M12@18.618,10.668 U99.L12@18.618,9.398 v3(19.253,10.033)
  Bottom Layer w0.254: v2(0.4,-32.2) 0.532,-32.068 R276.2@1.227,-32.068 1.868,-32.068 v2(2,-32.2) ; v2(0.4,-28.6) 0.541,-28.741 R275.2@1.27,-28.741 1.859,-28.741 v2(2,-28.6) ; U1.G1@25.5,-38.071 26,-38.571 27,-38.571 v1(27.5,-39.071) ; U1.L1@25.5,-34.071 26,-34.571 27,-34.571 v1(27.5,-35.071) ; CS97.1@26,-46.061 v1(26,-45.571) ; C172.1@26.162,-50.698 26.187,-50.673 v4(26.733,-50.673) C144.1@27.28,-50.673 ; CS71.1@54.51,-46.571 54.51,-46.176 54.605,-46.081 CS12.1@56,-46.081 56.49,-46.081 v1(57,-45.571) ; CS1.1@59,-48.081 59.51,-48.081 v1(60,-48.571) CS98.1@60,-47.081 ; CS45.1@59,-46.061 v1(59,-45.571) ; v1(61,-40.571) 60.51,-40.081 CS76.1@60.51,-39.571 60.51,-39.454 60.822,-39.142 61.087,-39.142 61.49,-38.738 CS3.1@61.49,-38.571 ; CS85.1@62,-40.081 v1(62,-40.571) 62.49,-40.081 63.688,-40.081 ; v1(63,-44.571) 63.49,-44.081 CS33.1@63.49,-43.571 CS24.1@63.49,-42.571 ; CS46.1@64,-38.061 63.742,-38.061 63.51,-38.293 CS13.1@63.51,-39.571 63.51,-39.903 63.688,-40.081 ; v1(65,-49.571) CS99.1@65,-49.081 ; CS62.1@65.51,-5.571 65.886,-5.571 66,-5.457 v1(66,-4.571) ; v4(65.608,-40.208) 65.481,-40.081 CS47.1@65,-40.081 63.688,-40.081 ; v4(76.708,-0.94) 76.708,-0.889 R636.2@77.47,-0.127 ; v4(77.217,2.515) 77.227,2.505 C542.1@77.227,1.135 ; D12.1@78.613,0.18 78.666,0.127 80.862,0.127 80.899,0.09 81.751,0.09 v4(81.763,0.102) ; v3(79.883,-18.593) FB5.1@80.34,-18.593
  Bottom Layer w0.381: v2(-5.08,7.95) -4.064,7.95 FB2.1@-4.089,7.925 ; C207.1@0.232,-47.047 1.129,-47.047 v2(1.375,-46.801) ; C203.1@0.232,-46.047 1.371,-46.047 v2(1.375,-46.051) ; C204.1@0.232,-45.047 1.121,-45.047 v2(1.375,-45.301) ; R800.1@1.753,-14.072 2.528,-14.072 v2(2.6,-14) ; v2(2.875,-46.801) 3.375,-47.301 C205.1@4.018,-47.301 ; v2(2.875,-45.301) C208.1@4.018,-45.301 ; R69.2@4.932,-43.301 v3(4.932,-41.885) ; U99.J8@13.538,6.858 v3(14.173,7.493) ; v1@24.892,-28.6 25.421,-28.071 U1.U1@25.5,-28.071 U1.U2@26.5,-28.071 ; U1.U5@29.5,-28.071 29.562,-28.071 v1(29.896,-27.737) ; C100.1@37.338,-1.016 v3(37.338,-0.203) ; C537.1@45.85,5.613 45.85,6.195 45.872,6.172 v4(45.872,5.029) ; D11.1@75.489,-0.976 76.672,-0.976 v4(76.708,-0.94) ; R546.1@77.673,5.461 R548.1@77.673,6.604 v3(77.673,7.188) ; v4(79.705,7.341) R602.1@79.705,6.604 79.71,6.599 R540.1@79.71,5.461 ; R544.1@80.818,6.482 v4(80.818,7.218) ; D14.1@80.899,0.015 D14.1@80.899,0.09 ; v4(81.839,3.048) R534.1@82.728,3.048 ; R536.1@82.042,4.242 R538.1@83.185,4.242 v4(83.82,4.242)
  Bottom Layer w0.508: C219.2@-2.388,-49.682 -2.362,-49.657 -1.631,-49.657 v2(-1,-49.026) ; v2(3.251,-8.585) 3.809,-9.143 C501.1@3.937,-9.143 ; C500.1@9.779,-9.143 C503.1@12.7,-9.143 ; v4(19.914,4.039) 20.701,4.039 20.956,4.294 C517.1@20.956,4.699 20.956,4.952 20.549,5.359 v4(19.99,5.359) ; v4(20.091,7.468) 20.092,7.469 C508.1@21.692,7.469 ; U1.AJ17@41.5,-16.071 v1(42,-16.571) ; C526.1@69.215,-7.749 C526.1@69.215,-7.722 ; v3(72.873,-21.295) 72.873,-20.549 73.405,-20.016 C527.1@73.405,-19.685 ; v4(74.727,4.47) 73.635,4.47 C547.1@73.152,4.953 73.66,5.461 v4(74.727,5.461) 74.905,5.639 R550.1@75.565,5.639 ; J4.3@78.196,-34.563 v2(79.821,-34.562) ; R638.2@83.261,-2.286 R640.2@83.261,-1.143 83.287,-1.118 v4(83.287,-0.457)
  other v1: 16.675,-51.983 41,-50.028 42,-50.028 16,-49.571 17,-49.571 18,-49.571 29,-49.571 30,-49.571 31,-49.571 52,-49.571 53,-49.571 54,-49.571 66,-49.571 67,-49.571 16,-48.571 24,-48.571 31,-48.571 52,-48.571 67,-48.571 31,-47.571 42,-47.571 43,-47.571 45,-47.571 67,-47.571 30,-46.571 66,-46.571 21,-45.571 22,-45.571 23,-45.571 24,-45.571 25,-45.571 58,-45.571 60,-45.571 61,-45.571 62,-45.571 57,-44.571 61,-44.571 25.5,-44.071 26.5,-44.071 30.5,-44.071 31.5,-44.071 35.5,-44.071 45.5,-44.071 54.5,-44.071 55.5,-44.071 56.5,-44.071 57.5,-44.071 58.5,-44.071 26,-43.571 57,-43.571 62,-43.571 27.5,-43.071 28.5,-43.071 31.5,-43.071 32.5,-43.071 42.5,-43.071 52.5,-43.071 54.5,-43.071 57.5,-43.071 58.5,-43.071 21,-42.571 26,-42.571 57,-42.571 62,-42.571 31.5,-42.071 39.5,-42.071 49.5,-42.071 54.5,-42.071 55.5,-42.071 20,-41.571 21,-41.571 56,-41.571 57,-41.571 61,-41.571 63,-41.571 19.5,-41.071 20.5,-41.071 28.5,-41.071 31.5,-41.071 36.5,-41.071 46.5,-41.071 54.5,-41.071 58.5,-41.071 21,-40.571 57,-40.571 31.5,-40.071 33.5,-40.071 43.5,-40.071 53.5,-40.071 54.5,-40.071 56.5,-40.071 17.5,-39.071 18.5,-39.071 19.5,-39.071 28.5,-39.071 31.5,-39.071 40.5,-39.071 50.5,-39.071 52.5,-39.071 53.5,-39.071 57.5,-39.071 58.5,-39.071 67,-38.571 31.5,-38.071 37.5,-38.071 47.5,-38.071 52.5,-38.071 55.5,-38.071 31,-37.571 52,-37.571 67,-37.571 18.5,-37.071 19.5,-37.071 28.5,-37.071 31.5,-37.071 34.5,-37.071 44.5,-37.071 52.5,-37.071 54.5,-37.071 58.5,-37.071 31,-36.571 52,-36.571 53,-36.571 65,-36.571 66,-36.571 67,-36.571 31.5,-36.071 41.5,-36.071 51.5,-36.071 52.5,-36.071 56.5,-36.071 20,-35.571 17.375,-35.446 18.5,-35.071 19.5,-35.071 28.5,-35.071 38.5,-35.071 48.5,-35.071 52.5,-35.071 54.5,-35.071 58.5,-35.071 31.5,-34.071 35.5,-34.071 45.5,-34.071 52.5,-34.071 55.5,-34.071 34,-33.571 35,-33.571 47,-33.571 48,-33.571 49,-33.571 52,-33.571 53,-33.571 65,-33.571 66,-33.571 67,-33.571 17.5,-33.071 18.5,-33.071 32.5,-33.071 34.5,-33.071 36.5,-33.071 38.5,-33.071 40.5,-33.071 42.5,-33.071 52.5,-33.071 54.5,-33.071 57.5,-33.071 58.5,-33.071 34,-32.571 42,-32.571 49,-32.571 52,-32.571 60,-32.571 67,-32.571 20.5,-32.071 33.5,-32.071 35.5,-32.071 37.5,-32.071 39.5,-32.071 41.5,-32.071 43.5,-32.071 49.5,-32.071 52.5,-32.071 56.5,-32.071 49,-31.571 67,-31.571 17.5,-31.071 18.5,-31.071 19.5,-31.071 27.5,-31.071 28.5,-31.071 32.5,-31.071 34.5,-31.071 36.5,-31.071 38.5,-31.071 40.5,-31.071 42.5,-31.071 46.5,-31.071 52.5,-31.071 54.5,-31.071 58.5,-31.071 25.5,-30.071 29.5,-30.071 33.5,-30.071 35.5,-30.071 37.5,-30.071 39.5,-30.071 41.5,-30.071 43.5,-30.071 52.5,-30.071 55.5,-30.071 24,-29.571 25,-29.571 26,-29.571 39,-29.571 40,-29.571 41,-29.571 42,-29.571 43,-29.571 44,-29.571 57,-29.571 58,-29.571 59,-29.571 60,-29.571 61,-29.571 62,-29.571 17.5,-29.071 18.5,-29.071 19.5,-29.071 23.5,-29.071 28.5,-29.071 32.5,-29.071 34.5,-29.071 36.5,-29.071 38.5,-29.071 40.5,-29.071 42.5,-29.071 44.5,-29.071 50.5,-29.071 52.5,-29.071 53.5,-29.071 54.5,-29.071 57.5,-29.071 58.5,-29.071 24.908,-28.58 39,-28.571 45,-28.571 57,-28.571 61,-28.571 63,-28.571 67,-28.571 35.5,-28.071 37.5,-28.071 39.5,-28.071 41.5,-28.071 43.5,-28.071 47.5,-28.071 54.5,-28.071 55.5,-28.071 56.5,-28.071 57.5,-28.071 39,-27.571 44,-27.571 57,-27.571 62,-27.571 17.5,-27.071 18.5,-27.071 19.5,-27.071 21.5,-27.071 27.5,-27.071 28.5,-27.071 32.5,-27.071 34.5,-27.071 35.5,-27.071 38.5,-27.071 40.5,-27.071 42.5,-27.071 44.5,-27.071 54.5,-27.071 21,-26.571 26,-26.571 39,-26.571 44,-26.571 57,-26.571 62,-26.571 20.5,-26.071 25.5,-26.071 29.5,-26.071 31.5,-26.071 36.5,-26.071 37.5,-26.071 39.5,-26.071 41.5,-26.071 43.5,-26.071 51.5,-26.071 20,-25.571 21,-25.571 27,-25.571 38,-25.571 39,-25.571 45,-25.571 56,-25.571 57,-25.571 63,-25.571 67,-25.571 28.5,-25.071 32.5,-25.071 34.5,-25.071 38.5,-25.071 40.5,-25.071 42.5,-25.071 44.5,-25.071 48.5,-25.071 58.5,-25.071 21,-24.571 25,-24.571 26,-24.571 39,-24.571 43,-24.571 44,-24.571 57,-24.571 61,-24.571 62,-24.571 25.5,-24.071 26.5,-24.071 29.5,-24.071 35.5,-24.071 37.5,-24.071 39.5,-24.071 41.5,-24.071 43.5,-24.071 45.5,-24.071 55.5,-24.071 17,-23.571 27.5,-23.071 28.5,-23.071 32.5,-23.071 34.5,-23.071 36.5,-23.071 38.5,-23.071 40.5,-23.071 42.5,-23.071 52.5,-23.071 25.5,-22.071 29.5,-22.071 35.5,-22.071 37.5,-22.071 39.5,-22.071 41.5,-22.071 43.5,-22.071 49.5,-22.071 16,-21.571 17,-21.571 31,-21.571 34,-21.571 49,-21.571 52,-21.571 67,-21.571 28.5,-21.071 36.5,-21.071 46.5,-21.071 56.5,-21.071 16,-20.571 17,-20.571 30,-20.571 31,-20.571 34,-20.571 35,-20.571 48,-20.571 49,-20.571 52,-20.571 53,-20.571 66,-20.571 67,-20.571 25.5,-20.071 26.5,-20.071 29.5,-20.071 31.5,-20.071 33.5,-20.071 43.5,-20.071 53.5,-20.071 16,-19.696 67.375,-19.571 68.25,-19.571 27.5,-19.071 28.5,-19.071 31.5,-19.071 40.5,-19.071 50.5,-19.071 64,-19.071 67.375,-18.821 68.25,-18.821 20,-18.571 21,-18.571 25.5,-18.071 29.5,-18.071 31.5,-18.071 37.5,-18.071 47.5,-18.071 57.5,-18.071 64,-18.071 16,-17.571 17,-17.571 18,-17.571 20,-17.571 21,-17.571 29,-17.571 30,-17.571 31,-17.571 34,-17.571 35,-17.571 47,-17.571 48,-17.571 49,-17.571 52,-17.571 53,-17.571 65,-17.571 66,-17.571 67,-17.571 28.5,-17.071 31.5,-17.071 34.5,-17.071 44.5,-17.071 54.5,-17.071 16,-16.571 24,-16.571 31,-16.571 34,-16.571 49,-16.571 52,-16.571 60,-16.571 67,-16.571 25.5,-16.071 26.5,-16.071 29.5,-16.071 31.5,-16.071 51.5,-16.071 31,-15.571 49,-15.571 67,-15.571 27.5,-15.071 28.5,-15.071 31.5,-15.071 38.5,-15.071 48.5,-15.071 58.5,-15.071 16,-14.571 25.5,-14.071 29.5,-14.071 31.5,-14.071 35.5,-14.071 45.5,-14.071 55.5,-14.071 21,-13.571 22,-13.571 23,-13.571 24,-13.571 25,-13.571 26,-13.571 39,-13.571 40,-13.571 41,-13.571 42,-13.571 43,-13.571 44,-13.571 57,-13.571 58,-13.571 59,-13.571 60,-13.571 61,-13.571 62,-13.571 28.5,-13.071 31.5,-13.071 32.5,-13.071 42.5,-13.071 52.5,-13.071 21,-12.571 27,-12.571 39,-12.571 45,-12.571 57,-12.571 63,-12.571 66,-12.571 67,-12.571 25.5,-12.071 26.5,-12.071 29.5,-12.071 31.5,-12.071 39.5,-12.071 49.5,-12.071 21,-11.571 26,-11.571 39,-11.571 44,-11.571 57,-11.571 62,-11.571 66,-11.571 67,-11.571 27.5,-11.071 28.5,-11.071 31.5,-11.071 36.5,-11.071 46.5,-11.071 56.5,-11.071 21,-10.571 26,-10.571 39,-10.571 44,-10.571 57,-10.571 62,-10.571 38,-9.571 39,-9.571 45,-9.571 56,-9.571 57,-9.571 63,-9.571 39,-8.571 43,-8.571 44,-8.571 57,-8.571 61,-8.571 62,-8.571 30,-7.571 35,-7.571 49,-7.571 50.5,-7.571 66,-7.571 31,-5.571 32,-5.571 34,-5.571 49,-5.571 52,-5.571 53,-5.571 67,-5.571 17,-4.571 30,-4.571 31,-4.571 34,-4.571 35,-4.571 37,-4.571 38,-4.571 48,-4.571 49,-4.571 52,-4.571 53,-4.571 63,-4.571 64,-4.571 67,-4.571 21.016,-4.443 22.016,-4.443 29.016,-4.443 34,-3.571 35,-3.571 37,-3.571 38,-3.571 63,-3.571 64,-3.571 21.016,-3.443 22.016,-3.443 29.016,-3.443 30.016,-3.443
  other v2: 15.5,-51.821 2.625,-51.696 4.25,-51.696 12.875,-51.696 -2.997,-51.664 13.75,-51.508 17.5,-50.821 18.75,-50.821 22,-50.696 22.75,-50.696 38.375,-50.696 39.125,-50.696 58.941,-50.696 59.816,-50.696 1.375,-50.571 2.375,-50.508 3.375,-50.508 16.75,-50.446 68.804,-50.23 69.679,-50.23 47.875,-50.071 49,-50.071 22,-49.946 22.75,-49.946 33.5,-49.946 34.25,-49.946 35.625,-49.946 36.375,-49.946 38.375,-49.946 39.125,-49.946 58.941,-49.946 59.816,-49.946 68.804,-49.48 69.679,-49.48 33.5,-48.946 34.25,-48.946 35.625,-48.946 36.375,-48.946 47.875,-48.821 49,-48.821 14.375,-48.696 4.25,-48.446 12,-48.301 14.375,-47.696 10.5,-47.551 12,-47.551 -3.609,-47.423 10.5,-46.801 11.25,-46.801 12,-46.801 2.875,-46.051 13.25,-45.571 16.375,-45.571 14.5,-45.446 15.5,-45.446 2.125,-45.301 -3.609,-44.679 14.021,-43.791 15.021,-43.791 16.421,-43.791 -8.199,-43.687 -7.5,-43.687 -6.802,-43.687 69.842,-43.288 70.717,-43.288 15.221,-42.591 16.421,-42.591 -1.332,-42.551 69.842,-42.538 70.717,-42.538 72,-42.278 6.375,-41.821 8.5,-41.821 14.421,-41.591 -1.8,-41.4 15.421,-41.391 7.625,-41.321 5.375,-41.196 16.421,-41.191 14.821,-40.391 5.75,-40.321 6.875,-40.321 8.5,-40.321 -0.379,-39.991 16.021,-39.991 -1.8,-39.8 0.375,-39.571 -0.379,-38.991 2.625,-38.821 3.75,-38.821 5,-38.821 7,-38.821 8.5,-38.821 0.375,-38.321 -1.8,-38.2 3.125,-37.946 4.375,-37.946 6,-37.946 8.5,-37.946 7.375,-37.821 -0.379,-37.591 2.5,-37.196 74.555,-37.16 0.5,-37.071 3.75,-37.071 5,-37.071 8,-36.946 6.75,-36.821 11,-36.821 -1.8,-36.8 10,-36.8 -0.179,-35.991 7.625,-35.821 10.625,-35.821 11.875,-35.821 2.875,-35.696 4.75,-35.696 1,-35.571 10,-35.2 -1.4,-35 5.221,-34.991 15.821,-34.991 12,-34.821 11.125,-34.696 7.6,-34.6 6.125,-34.446 10.375,-34.446 1.2,-34.2 2.4,-34.2 0.381,-34.163 69.842,-34.038 70.717,-34.038 9.621,-33.735 5.6,-33.6 7.75,-33.571 69.842,-33.288 70.717,-33.288 0.6,-33.2 2.2,-33.2 3.4,-33.2 11,-33.071 72,-33.028 6.125,-32.571 3.2,-32.2 4.2,-32.2 2.4,-31.6 4,-31.2 7.75,-30.821 6,-30 2.2,-29.6 4.2,-29.6 -0.6,-29.2 3.2,-29 7.562,-28.908 5.6,-28.8 3.901,-28.616 5.2,-27.8 6.2,-27.8 7.6,-27.4 4.2,-27.2 -0.6,-27 0.4,-27 1.8,-27 3,-27 5.8,-26.6 0.873,-26.286 7.2,-26.2 4.677,-26.075 2.2,-26 3.4,-26 6.4,-25.2 7.4,-25.2 76.342,-24.771 77.217,-24.771 5.286,-24.674 0,-24.6 2.8,-24.6 4,-24.6 7.8,-24.6 2,-24.4 0.928,-24.287 76.342,-24.021 77.217,-24.021 -0.6,-24 1.2,-23.6 0,-23.2 4.4,-23.2 1.6,-22.8 2.883,-21.041 4.153,-21.041 2.883,-19.771 4.153,-19.771 7.8,-18.6 1.768,-16.499 2.936,-16.456 1.092,-15.596 2.6,-15.4 4.2,-15.4 4.2,-14 5.4,-14 6.6,-14 8.56,-13.97 3.404,-13.564 6.02,-13.411 4.775,-13.386 6.629,-12.065 8.56,-12.04 5.323,-12.014 4.394,-11.989 2.259,-11.895 3.464,-11.836 -0.6,-11.8 0.8,-11.6 -1.4,-11.4 5.969,-11.354 3,-11 4.4,-11 7,-10.998 8.458,-11 10.2,-11 -0.4,-10.8 1.6,-10.8 7.671,-10.389 6.35,-10.312 3.708,-10.287 -1.4,-10.2 9.4,-10.2 1.2,-10 2.6,-10 0.266,-9.772 -0.6,-9.2 12.37,-8.915 10.2,-8.8 9.042,-8.763 7.62,-8.636 4.8,-8.6 5.436,-8.611 6.4,-8.6 15.6,-8.6 4.018,-8.585 2.362,-8.484 16.485,-8.357 8.306,-8.306 2.337,-6.909 -0.4,-6.4 17.145,-6.02 1,-5.8 45.288,-4.444 46.038,-4.444 45.288,-3.694 46.038,-3.694 40.875,-1.839 41.75,-1.839 46.458,-1.839 47.333,-1.839 50.267,-1.118 40.875,-1.089 41.75,-1.089 46.458,-1.089 47.333,-1.089 50.267,-0.584
  other v3: 80.34,-18.586 79.908,-18.136 80.366,-18.136 74.716,-0.457
  other v4: 65.634,-40.894 69.698,-8.077 69.698,-7.493 24.308,-1.676 24.308,-0.508 78.13,1.143 78.842,1.143 79.578,1.143 24.308,1.27 78.13,1.676 78.842,1.676 79.578,1.676 24.282,2.438 45.847,5.79 35.05,10.338 57.402,10.338 58.801,10.338 36.575,10.363 35.051,11.049 57.403,11.049 58.802,11.049 36.576,11.074 35.025,11.735 57.377,11.735 58.776,11.735 36.55,11.76
  other v5: 12.125,-38.946 13.375,-38.946 9.875,-38.821 11.5,-38.821 14.875,-38.821 14.25,-38.446 10.375,-38.321 12.125,-38.321 16,-38.071 15,-37.321 16.5,-37.071 14.25,-36.821 15.375,-36.696 13.375,-35.446 14.875,-35.446 16.5,-35.446 13.375,-34.696 14.875,-34.696 16.5,-34.696 12.125,-33.446 13.5,-33.446 14.75,-33.446 16.375,-33.446 12.25,-32.696 13.625,-32.696 15.25,-32.696 16.375,-32.696 9.125,-32.446 11.625,-32.446 10.375,-32.196 11,-32.071 14.125,-31.446 15.25,-31.446 16.375,-31.446 12.75,-31.321 12,-31.196 9.125,-30.696 14.625,-30.696 15.5,-30.696 16.375,-30.696 10.375,-30.571 13.125,-30.571 11.625,-30.196 12.375,-30.196 14.125,-29.446 16.375,-29.446 9.125,-29.196 10.375,-29.196 11.625,-29.196 -4.632,-29.144 13,-28.946 13.75,-28.696 15.125,-28.571 14,-27.946 9.125,-27.821 10.375,-27.821 11.625,-27.821 12.875,-27.821 16.375,-27.446 -1.779,-27.236 13.375,-27.196 15.625,-26.946 14.878,-26.895 -3.556,-26.772 9.125,-26.696 10.375,-26.696 11.625,-26.696 12.875,-26.696 16.375,-26.696 14.375,-26.196 15.375,-26.196 14.875,-25.696 9.125,-25.446 10.375,-25.446 14.125,-25.446 72.119,-24.733 -1.549,-24.46 -4.632,-24.344 74.873,-23.737 9.125,-23.446 10.375,-23.446 11.625,-23.446 12.875,-23.446 14.125,-23.446 -1.779,-23.426 -4.632,-22.744 9.125,-22.571 10.375,-22.571 11.625,-22.571 12.875,-22.571 14.125,-22.571 15.375,-21.696 9.125,-21.571 10.375,-21.571 14.125,-21.571 9.125,-20.571 10.375,-20.571 15.375,-20.571 -4.179,-20.251 9.125,-19.696 10.375,-19.696 15.375,-19.696 14.121,-19.614 9.125,-18.696 10.375,-18.696 14.125,-18.696 -4.632,-17.944 9.125,-17.696 12.875,-17.696 14.125,-17.696 12.875,-16.696 14.125,-16.696 15.375,-16.696 -4.632,-16.344 12.875,-15.571 14.125,-15.571 15.375,-15.571 12.875,-14.196 14.125,-14.196 15.375,-14.196 11.684,-13.995 12.875,-12.946 14.125,-12.821 15.375,-12.821 11.608,-12.313 -3.251,-12.09 14.125,-11.696 15.375,-11.696 -4.632,-11.544 -3.251,-10.82 15.375,-10.571 -4.632,-9.169 -4.632,-6.744 -4.632,-4.344 -3.124,-3.2 -4.623,-1.981
  other v6: 30,-36.571 29.5,-34.071 29,-33.571 30,-33.571 31,-33.571 28.5,-33.071 31,-32.571 29.5,-32.071 31,-31.571 31.5,-31.071 21,-28.571 23,-28.571 27,-28.571 22,-27.571 26,-27.571 20,-9.571 21,-9.571 27,-9.571 21,-8.571 25,-8.571 26,-8.571
I2C_SCL: J5.4 R235.1 | length 10.9
  Top Layer w0.508: v2(76.571,-38.563) J5.4@78.196,-38.563
  INT7 w0.102: v5(74.248,-33.026) 73.793,-32.571 72.875,-32.571 72.625,-32.821 72.625,-34.617 v2(76.571,-38.563)
I2C_SDA: J5.5 R234.1 | length 7.6
  Top Layer w0.508: v2(76.571,-37.563) J5.5@78.196,-37.563
  INT7 w0.102: v5(73.123,-33.026) 73.425,-33.328 73.425,-34.417 v2(76.571,-37.563)
INT_VCC: C511.2 R603.2 R650.2 RT.2 U99.H8 | length 6.6
  Top Layer w0.127: RT.2@11.963,6.858 13.538,6.858 v3(14.173,6.223) 14.275,6.325 C511.2@14.808,6.325 R603.2@14.808,5.207 14.578,5.437 13.692,5.437 R650.2@13.538,5.283
  Bottom Layer w0.127: U99.H8@13.538,5.588 v3(14.173,6.223)
INT_VCC1_1: R506.2 R604.2 U98.C4 | length 10.7
  Top Layer w0.102: v3(40.767,0.813) 42.139,0.813 R604.2@42.672,1.346
  Top Layer w0.127: U98.C4@36.83,4.699 v3(36.83,5.275) ; R604.2@42.672,1.397 42.672,2.515 R506.2@42.697,2.54
  INT2 w0.102: v3(36.83,5.275) 37.27,4.835 37.27,4.284 38.151,3.404 39.446,3.404 39.802,3.048 39.802,1.778 v3(40.767,0.813)
INT_VCC1_2: R507.2 R606.2 U98.F4 | length 17.5
  Top Layer w0.127: v3(33.02,4.123) U98.F4@33.02,4.699 ; v3(34.061,-1.295) 34.62,-1.854 R606.2@34.671,-1.854 ; v3(41,4.343) 42.037,4.343 R507.2@42.697,3.683
  INT2 w0.102: v3(33.02,4.123) 33.02,3.81 33.779,3.051 33.779,-0.15 34.061,-0.432 v3(34.061,-1.295)
  INT3 w0.102: v3(33.02,4.123) 33.469,4.572 40.759,4.572 41,4.331 v3(41,4.343)
INT_VCC1_3: R508.2 R608.2 U98.J4 | length 13.1
  Top Layer w0.127: U98.J4@29.21,4.699 v3(29.21,5.275) ; R608.2@29.845,-1.854 v3(30.582,-1.854) R508.2@32.258,-1.854
  INT2 w0.102: v3(29.21,5.275) 28.95,5.015 28.179,5.015 27.544,4.379 27.544,0.423 29.821,-1.854 v3(30.582,-1.854)
  Bottom Layer w0.127: v3@30.455,-1.851 30.457,-1.854 v3(30.582,-1.854)
INT_VCC1_4: R509.2 R610.2 U98.K5 | length 7
  Top Layer w0.127: R610.2@26.365,-1.778 26.391,-1.803 R509.2@27.559,-1.803 27.127,-1.372 27.127,2.04 v3(27.94,2.853) U98.K5@27.94,3.429
INT_VCC2_1: R510.2 R612.2 U97.C4 | length 11.4
  Top Layer w0.127: U97.C4@81.153,-13.462 v3(81.153,-12.886) ; v3(82.652,-20.98) 82.677,-20.955 R510.2@82.677,-20.142
  INT1 w0.127: v3(81.153,-12.886) 81.763,-13.496 81.763,-16.154 83.185,-17.577 83.185,-20.447 v3(82.652,-20.98)
  Bottom Layer w0.127: v3(82.652,-20.98) 82.677,-20.955 R612.2@82.677,-20.142
INT_VCC2_2: R511.2 R614.2 U97.F4 | length 14.6
  Top Layer w0.127: v3(77.343,-14.038) U97.F4@77.343,-13.462 ; v3(78.105,-20.853) R614.2@78.105,-20.142 ; v3(81.534,-20.904) R511.2@81.534,-20.142
  INT1 w0.127: v3(77.343,-14.038) 78.588,-15.283 78.588,-19.253 78.105,-19.736 v3(78.105,-20.853) 79.324,-19.634 81.153,-19.634 81.534,-20.015 v3(81.534,-20.904)
INT_VCC2_3: R512.2 R616.2 U97.J4 | length 13.4
  Top Layer w0.102: v3(74.676,-20.777) R616.2@74.676,-20.142
  Top Layer w0.127: U97.J4@73.533,-13.462 v3(73.533,-12.886) ; v3(76.962,-20.676) R512.2@76.962,-20.142
  INT1 w0.102: v3(73.533,-12.886) 74.219,-13.572 74.219,-15.545 75.235,-16.561 75.235,-18.898 74.676,-19.456 v3(74.676,-20.777) ; v3@74.676,-20.803 v3(74.676,-20.777) ; v3(76.962,-20.676) 76.429,-20.142 75.311,-20.142 v3(74.676,-20.777)
INT_VCC2_4: R513.2 R618.2 U97.K5 | length 17.2
  Top Layer w0.127: R618.2@70.993,-20.142 70.993,-20.864 70.749,-21.107 69.637,-21.107 69.469,-20.94 69.469,-16.257 70.486,-15.24 71.713,-15.24 v3(71.882,-15.071) ; v3@71.933,-15.062 U97.K5@72.263,-14.732
  INT1 w0.127: v3(71.552,-10.262) 72.641,-11.351 72.641,-14.312 v3(71.882,-15.071)
  Bottom Layer w0.127: v3(71.552,-10.262) 71.78,-10.262 R513.2@72.441,-10.922
INT_VCC3_1: R518.1 R652.2 U96.C4 | length 10.6
  Top Layer w0.127: U96.C4@60.452,4.699 v3(60.452,5.275) ; R652.2@66.421,1.092 R652.2@66.243,1.27 R518.1@66.243,2.413 66.65,2.007 v3(66.853,2.007)
  INT2 w0.102: v3(60.452,5.275) 61.146,5.275 64.491,1.93 66.777,1.93 v3(66.853,2.007)
INT_VCC3_2: R519.1 R633.2 U96.F4 | length 18.8
  Top Layer w0.127: v3(56.642,4.123) U96.F4@56.642,4.699 ; v3(58.801,-1.219) R633.2@58.801,-0.635 ; v3(65.938,4.123) 65.938,3.861 R519.1@66.243,3.556
  INT2 w0.102: v3(56.642,4.123) 57.15,3.615 57.15,0.432 v3(58.801,-1.219) v3@58.837,-1.255
  INT3 w0.127: v3@58.837,-1.255 61.712,-1.255 63.602,0.635 64.567,0.635 65.938,2.007 v3(65.938,4.123)
  Bottom Layer w0.127: v3(58.801,-1.219) v3@58.801,-1.09
INT_VCC3_3: R520.1 R635.2 U96.J4 | length 17.1
  Top Layer w0.102: v3(46.076,7.874) R520.1@46.787,7.874 ; U96.J4@52.832,4.699 v3(52.832,5.275) ; R635.2@53.645,-0.635 53.924,-0.914 v3(53.924,-1.36)
  INT1 w0.102: v3(52.832,5.275) 53.238,4.869 53.238,0.051 53.924,-0.635 v3(53.924,-1.36)
  INT2 w0.102: v3(46.076,7.874) 47.015,6.934 51.257,6.934 52.832,5.359 v3(52.832,5.275)
INT_VCC3_4: R521.1 R637.2 U96.K5 | length 15
  Top Layer w0.102: v3(46.076,9.017) R521.1@46.787,9.017 ; v3(46.33,2.159) R637.2@47.041,2.159 ; v3(51.562,2.853) U96.K5@51.562,3.429
  INT2 w0.102: v3(46.076,9.017) 46.008,9.017 45.466,8.475 45.466,7.696 46.33,6.833 v3(46.33,2.159) 47.024,2.853 v3(51.562,2.853)
JTAG_TCK: J5.8 U1.AC9 | length 59.5
  Top Layer w0.508: v2(76.571,-34.563) J5.8@78.196,-34.563
  INT8 w0.102: v1(33.5,-22.071) 32.875,-22.696 32.875,-31.946 36.625,-35.696 59.125,-35.696 59.5,-35.321 75.25,-35.321 76,-36.071 76.75,-36.071 77.125,-35.696 77.125,-35.117 v2(76.571,-34.563)
JTAG_TDI: J5.10 U1.V9 | length 50.5
  Top Layer w0.508: v2(76.571,-32.563) J5.10@78.196,-32.563
  INT8 w0.102: v1(33.5,-27.071) 34.125,-27.696 34.125,-30.196 38.375,-34.446 67.375,-34.446 69,-32.821 70.875,-32.821 71.5,-33.446 75.687,-33.446 v2(76.571,-32.563)
JTAG_TDO: J5.9 U1.U9 | length 49.4
  Top Layer w0.508: v2(76.571,-33.563) J5.9@78.196,-33.563
  INT8 w0.102: v1(33.5,-28.071) 33.875,-28.446 33.875,-30.946 37.625,-34.696 75.437,-34.696 v2(76.571,-33.563)
JTAG_TMS: J5.7 U1.W9 | length 52.5
  Top Layer w0.508: v2(76.571,-35.562) J5.7@78.196,-35.563
  INT8 w0.102: v1(33.5,-26.071) 33.125,-26.446 33.125,-31.196 37.375,-35.446 59,-35.446 59.375,-35.071 76.079,-35.071 v2(76.571,-35.562)
M\R\: R531.1 U95.1 | length 1.5
  Top Layer w0.203: R531.1@75.59,1.524 75.955,1.889 U95.1@76.967,1.889
MEM0_0: MEM0_0.1 U1.AM22 U2.C3 | length 36.6
  INT8 w0.102: v1(46.5,-13.071) 47,-13.071 53.375,-6.696 53.375,-4.696 55.25,-2.821 MEM0_0.1@55.25,-2.321
  INT3 w0.102: v1(29,-6.571) 29.375,-6.196 36.125,-6.196 43.375,-13.446 43.625,-13.446 43.875,-13.196 44.125,-13.196 44.875,-13.946 45.125,-13.946 45.375,-13.696 45.625,-13.696 45.875,-13.946 46.125,-13.946 46.5,-13.571 v1(46.5,-13.071)
MEM0_1: U1.AP23 U2.D5 | length 20.8
  INT4 w0.102: v6(28,-8.571) 28.375,-8.196 37.125,-8.196 39.125,-10.196 46.125,-10.196 46.875,-10.946 47.375,-10.946 v1(47.5,-11.071)
MEM0_2: U1.AK20 U2.C5 | length 19
  INT3 w0.102: v6(29,-8.571) 29.375,-8.946 31.875,-8.946 37.661,-14.732 ; 37.662,-14.732 38.354,-15.424 38.648,-15.424 38.854,-15.218 39.148,-15.218 39.354,-15.424 40.648,-15.424 40.854,-15.218 41.148,-15.218 41.354,-15.424 42.648,-15.424 42.854,-15.218 43.148,-15.218 43.354,-15.424 43.648,-15.424 43.854,-15.218 44.353,-15.218 v1(44.5,-15.071)
MEM0_3: U1.AN23 U2.E7 | length 23
  INT4 w0.102: v1(27,-10.571) 27.625,-9.946 34.875,-9.946 37.375,-12.446 37.625,-12.446 37.875,-12.196 38.125,-12.196 38.375,-12.446 38.625,-12.446 38.875,-12.196 39.125,-12.196 39.375,-12.446 43.625,-12.446 43.875,-12.196 44.125,-12.196 44.375,-12.446 44.625,-12.446 44.875,-12.196 45.125,-12.196 45.375,-12.446 45.625,-12.446 45.875,-12.196 46.125,-12.196 46.375,-12.446 46.625,-12.446 46.875,-12.196 47.375,-12.196 v1(47.5,-12.071)
MEM0_4: U1.AL24 U2.D9 | length 24.2
  INT4 w0.102: v1(28,-12.571) 28.375,-12.196 29.125,-12.196 29.375,-12.446 32.375,-12.446 34.375,-14.446 35.625,-14.446 35.875,-14.196 36.125,-14.196 36.375,-14.446 36.625,-14.446 36.875,-14.196 37.125,-14.196 37.375,-14.446 37.625,-14.446 37.75,-14.321 37.875,-14.196 38.125,-14.196 38.375,-14.446 38.625,-14.446 38.875,-14.196 39.125,-14.196 39.375,-14.446 39.625,-14.446 39.875,-14.196 40.125,-14.196 40.375,-14.446 40.625,-14.446 40.875,-14.196 41.125,-14.196 41.375,-14.446 41.625,-14.446 41.875,-14.196 42.125,-14.196 42.375,-14.446 42.625,-14.446 42.875,-14.196 43.125,-14.196 43.375,-14.446 43.625,-14.446 43.875,-14.196 44.125,-14.196 44.375,-14.446 44.625,-14.446 44.875,-14.196 45.125,-14.196 45.375,-14.446 45.625,-14.446 45.875,-14.196 46.125,-14.196 46.375,-14.446 46.625,-14.446 46.875,-14.196 47.125,-14.196 47.375,-14.446 48.25,-14.446 v1@48.5,-14.196
  other v1: 48.5,-14.071
MEM0_5: U1.AJ25 U2.D11 | length 24.9
  INT4 w0.102: v1(28,-14.571) 28.5,-14.571 28.875,-14.946 29.875,-14.946 31.625,-16.696 33.625,-16.696 33.875,-16.946 34.125,-16.946 34.375,-16.696 34.625,-16.696 34.875,-16.946 35.125,-16.946 35.375,-16.696 35.625,-16.696 35.875,-16.946 36.125,-16.946 36.375,-16.696 36.625,-16.696 36.875,-16.946 37.125,-16.946 37.375,-16.696 37.625,-16.696 37.875,-16.946 38.125,-16.946 38.375,-16.696 38.625,-16.696 38.875,-16.946 39.125,-16.946 39.375,-16.696 39.625,-16.696 39.875,-16.946 40.125,-16.946 40.375,-16.696 40.625,-16.696 40.875,-16.946 43.125,-16.946 43.375,-16.696 43.625,-16.696 43.875,-16.946 44.125,-16.946 44.375,-16.696 44.625,-16.696 44.875,-16.946 46.125,-16.946 46.375,-16.696 46.625,-16.696 46.875,-16.946 47.125,-16.946 47.375,-16.696 48.375,-16.696 49,-16.071 v1(49.5,-16.071)
MEM0_6: U1.AH24 U2.C12 | length 21.8
  INT4 w0.102: v1(29,-15.571) 29,-16.071 30.875,-17.946 31.125,-17.946 31.375,-17.696 33.625,-17.696 33.875,-17.946 34.125,-17.946 34.375,-17.696 34.625,-17.696 34.875,-17.946 35.125,-17.946 35.375,-17.696 46.625,-17.696 46.875,-17.946 47.125,-17.946 48,-17.071 v1(48.5,-17.071)
MEM0_7: U1.AH22 U2.G12 | length 23.2
  INT3 w0.102: v1(25,-15.571) 25.375,-15.196 27.125,-15.196 27.375,-15.446 27.625,-15.446 27.875,-15.196 28.125,-15.196 28.375,-15.446 28.625,-15.446 28.875,-15.196 31.125,-15.196 31.375,-15.446 34.375,-15.446 36.379,-17.45 46.121,-17.45 v1(46.5,-17.071)
MEM0_8: U1.AL22 U2.D4 | length 22.4
  INT3 w0.102: v1(28,-7.571) 28.375,-7.196 35.125,-7.196 42.375,-14.446 42.625,-14.446 42.875,-14.196 43.125,-14.196 43.375,-14.446 43.625,-14.446 43.875,-14.196 44.125,-14.196 44.375,-14.446 44.625,-14.446 44.875,-14.196 45.125,-14.196 45.375,-14.446 45.625,-14.446 45.875,-14.196 46.375,-14.196 v1(46.5,-14.071)
MEM0_9: U1.AP24 U2.D6 | length 22.6
  INT4 w0.102: v6(28,-9.571) 28.375,-9.196 36.125,-9.196 38.125,-11.196 38.375,-11.446 38.625,-11.446 38.875,-11.196 39.125,-11.196 39.375,-11.446 43.625,-11.446 43.875,-11.196 45.125,-11.196 45.375,-11.446 45.625,-11.446 45.875,-11.196 46.125,-11.196 46.375,-11.446 46.625,-11.446 46.875,-11.196 47.125,-11.196 47.375,-11.446 48.125,-11.446 v1(48.5,-11.071)
MEM0_10: U1.AP25 U2.C6 | length 22.9
  INT4 w0.102: v6(29,-9.571) 35.5,-9.571 37.625,-11.696 37.875,-11.946 38.125,-11.946 38.375,-11.696 38.625,-11.696 38.875,-11.946 39.125,-11.946 39.375,-11.696 43.625,-11.696 43.875,-11.946 44.125,-11.946 44.375,-11.696 44.625,-11.696 44.875,-11.946 45.125,-11.946 45.375,-11.696 45.625,-11.696 45.875,-11.946 46.125,-11.946 46.375,-11.696 46.625,-11.696 46.875,-11.946 47.125,-11.946 47.375,-11.696 48.875,-11.696 v1(49.5,-11.071)
MEM0_11: U1.AM25 U2.C8 | length 24.1
  INT4 w0.102: v1(29,-11.571) 29.125,-11.696 32.625,-11.696 34.625,-13.696 35.625,-13.696 35.875,-13.946 36.125,-13.946 36.375,-13.696 36.625,-13.696 36.875,-13.946 37.125,-13.946 37.375,-13.696 37.625,-13.696 37.875,-13.946 38.125,-13.946 38.375,-13.696 38.625,-13.696 38.875,-13.946 39.125,-13.946 39.375,-13.696 39.625,-13.696 39.875,-13.946 40.125,-13.946 40.375,-13.696 40.625,-13.696 40.875,-13.946 41.125,-13.946 41.375,-13.696 41.625,-13.696 41.875,-13.946 42.125,-13.946 42.375,-13.696 42.625,-13.696 42.875,-13.946 43.125,-13.946 43.375,-13.696 43.625,-13.696 43.875,-13.946 44.125,-13.946 44.375,-13.696 44.625,-13.696 44.875,-13.946 45.125,-13.946 45.375,-13.696 45.625,-13.696 45.875,-13.946 46.125,-13.946 46.375,-13.696 46.625,-13.696 46.875,-13.946 47.125,-13.946 47.375,-13.696 48.875,-13.696 v1(49.5,-13.071)
MEM0_12: U1.AJ21 U2.F9 | length 22.1
  INT3 w0.102: v1(26,-12.571) 26.5,-12.571 26.875,-12.196 29.125,-12.196 29.375,-12.446 33.375,-12.446 37.353,-16.424 37.646,-16.424 37.852,-16.218 39.146,-16.218 39.352,-16.424 39.646,-16.424 39.852,-16.218 42.146,-16.218 42.352,-16.424 42.646,-16.424 42.852,-16.218 43.146,-16.218 43.352,-16.424 43.646,-16.424 43.852,-16.218 45.353,-16.218 v1(45.5,-16.071)
MEM0_13: U1.AJ23 U2.E10 | length 23.1
  INT3 w0.102: v1(27,-13.571) 27.625,-14.196 29.125,-14.196 29.375,-14.446 34.375,-14.446 36.853,-16.924 37.146,-16.924 37.352,-16.718 37.646,-16.718 37.852,-16.924 38.146,-16.924 38.352,-16.718 38.646,-16.718 38.852,-16.924 39.146,-16.924 39.352,-16.718 39.646,-16.718 39.852,-16.924 43.146,-16.924 43.352,-16.718 43.646,-16.718 43.852,-16.924 44.146,-16.924 44.352,-16.718 44.646,-16.718 44.852,-16.924 46.147,-16.924 47,-16.071 v1(47.5,-16.071)
MEM0_14: U1.AJ24 U2.G11 | length 27
  INT4 w0.102: v1(25,-14.571) 25.5,-14.571 25.875,-14.196 26.125,-14.196 26.375,-14.446 26.625,-14.446 26.875,-14.196 29.125,-14.196 29.375,-14.446 30.375,-14.446 32.375,-16.446 33.625,-16.446 33.875,-16.196 36.125,-16.196 36.375,-16.446 36.625,-16.446 36.875,-16.196 37.125,-16.196 37.375,-16.446 37.625,-16.446 37.875,-16.196 38.125,-16.196 38.375,-16.446 38.625,-16.446 38.875,-16.196 39.125,-16.196 39.25,-16.321 39.375,-16.446 39.625,-16.446 39.875,-16.196 40.125,-16.196 40.375,-16.446 41.625,-16.446 41.875,-16.196 42.125,-16.196 42.375,-16.446 42.625,-16.446 42.875,-16.196 43.125,-16.196 43.375,-16.446 43.625,-16.446 43.875,-16.196 45.125,-16.196 45.375,-16.446 45.625,-16.446 45.875,-16.196 46.125,-16.196 46.375,-16.446 46.625,-16.446 46.875,-16.196 47.125,-16.196 47.375,-16.446 48.125,-16.446 v1(48.5,-16.071)
MEM0_15: U1.AG24 U2.E13 | length 22.7
  INT4 w0.102: v1(27,-16.571) 27.375,-16.196 28.125,-16.196 30.375,-18.446 48.125,-18.446 v1(48.5,-18.071)
MEM0_16: U1.AL23 U2.E5 | length 25.1
  INT3 w0.102: v6(27,-8.571) 27.625,-9.196 31.125,-9.196 37.853,-15.924 39.148,-15.924 39.354,-15.718 40.648,-15.718 40.854,-15.924 41.146,-15.924 41.352,-15.718 42.646,-15.718 42.852,-15.924 43.146,-15.924 43.352,-15.718 43.646,-15.718 43.852,-15.924 45.146,-15.924 45.353,-15.717 ; 45.354,-15.717 46.125,-14.946 47.125,-14.946 47.5,-14.571 v1(47.5,-14.071)
MEM0_17: U1.AP21 U2.F6 | length 20.8
  INT4 w0.102: v6(26,-9.571) 26.625,-8.946 36.875,-8.946 38.875,-10.946 39.125,-10.946 39.375,-10.696 42.75,-10.696 43,-10.946 45.375,-10.946 v1(45.5,-11.071)
MEM0_18: U1.AM24 U2.E8 | length 25.4
  INT4 w0.102: v1(27,-11.571) 27.5,-11.571 27.875,-11.196 28.125,-11.196 28.375,-11.446 28.625,-11.446 28.875,-11.196 29.125,-11.196 29.375,-11.446 33.375,-11.446 35.125,-13.196 35.375,-13.446 35.625,-13.446 35.875,-13.196 36.125,-13.196 36.375,-13.446 36.625,-13.446 36.875,-13.196 37.125,-13.196 37.375,-13.446 37.625,-13.446 37.875,-13.196 38.125,-13.196 38.375,-13.446 38.625,-13.446 38.875,-13.196 39.125,-13.196 39.375,-13.446 39.625,-13.446 39.875,-13.196 40.125,-13.196 40.375,-13.446 40.625,-13.446 40.875,-13.196 41.125,-13.196 41.375,-13.446 41.625,-13.446 41.875,-13.196 42.125,-13.196 42.375,-13.446 42.625,-13.446 42.875,-13.196 43.125,-13.196 43.375,-13.446 43.625,-13.446 43.875,-13.196 44.125,-13.196 44.375,-13.446 44.625,-13.446 44.875,-13.196 45.125,-13.196 45.375,-13.446 45.625,-13.446 45.875,-13.196 46.125,-13.196 46.375,-13.446 46.625,-13.446 46.875,-13.196 47.125,-13.196 47.375,-13.446 48.125,-13.446 v1(48.5,-13.071)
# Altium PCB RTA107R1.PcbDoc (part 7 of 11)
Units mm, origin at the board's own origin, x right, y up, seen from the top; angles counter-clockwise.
Board outline 96.01 x 65.66 mm, 22 copper layers (Top Layer, GND1, INT1, PWR1-(VCCIO_MRAM), INT2, PWR2-(VCCINT), INT3, PWR3_(12V_MGTAVCC), INT4, GND2-(DGND_SGND), PWR4_(MGTAVTT_VCCBRAM,VCCAUX), PWR5-(VCC_12V), GND3-(DGND_GND), INT5, GND4, INT6, PWR6_(VCCO), INT7, GND5, INT8, GND6, Bottom Layer), stack 2.833 mm thick; 614 components, 659 nets, 4037 pads, 3511 vias.

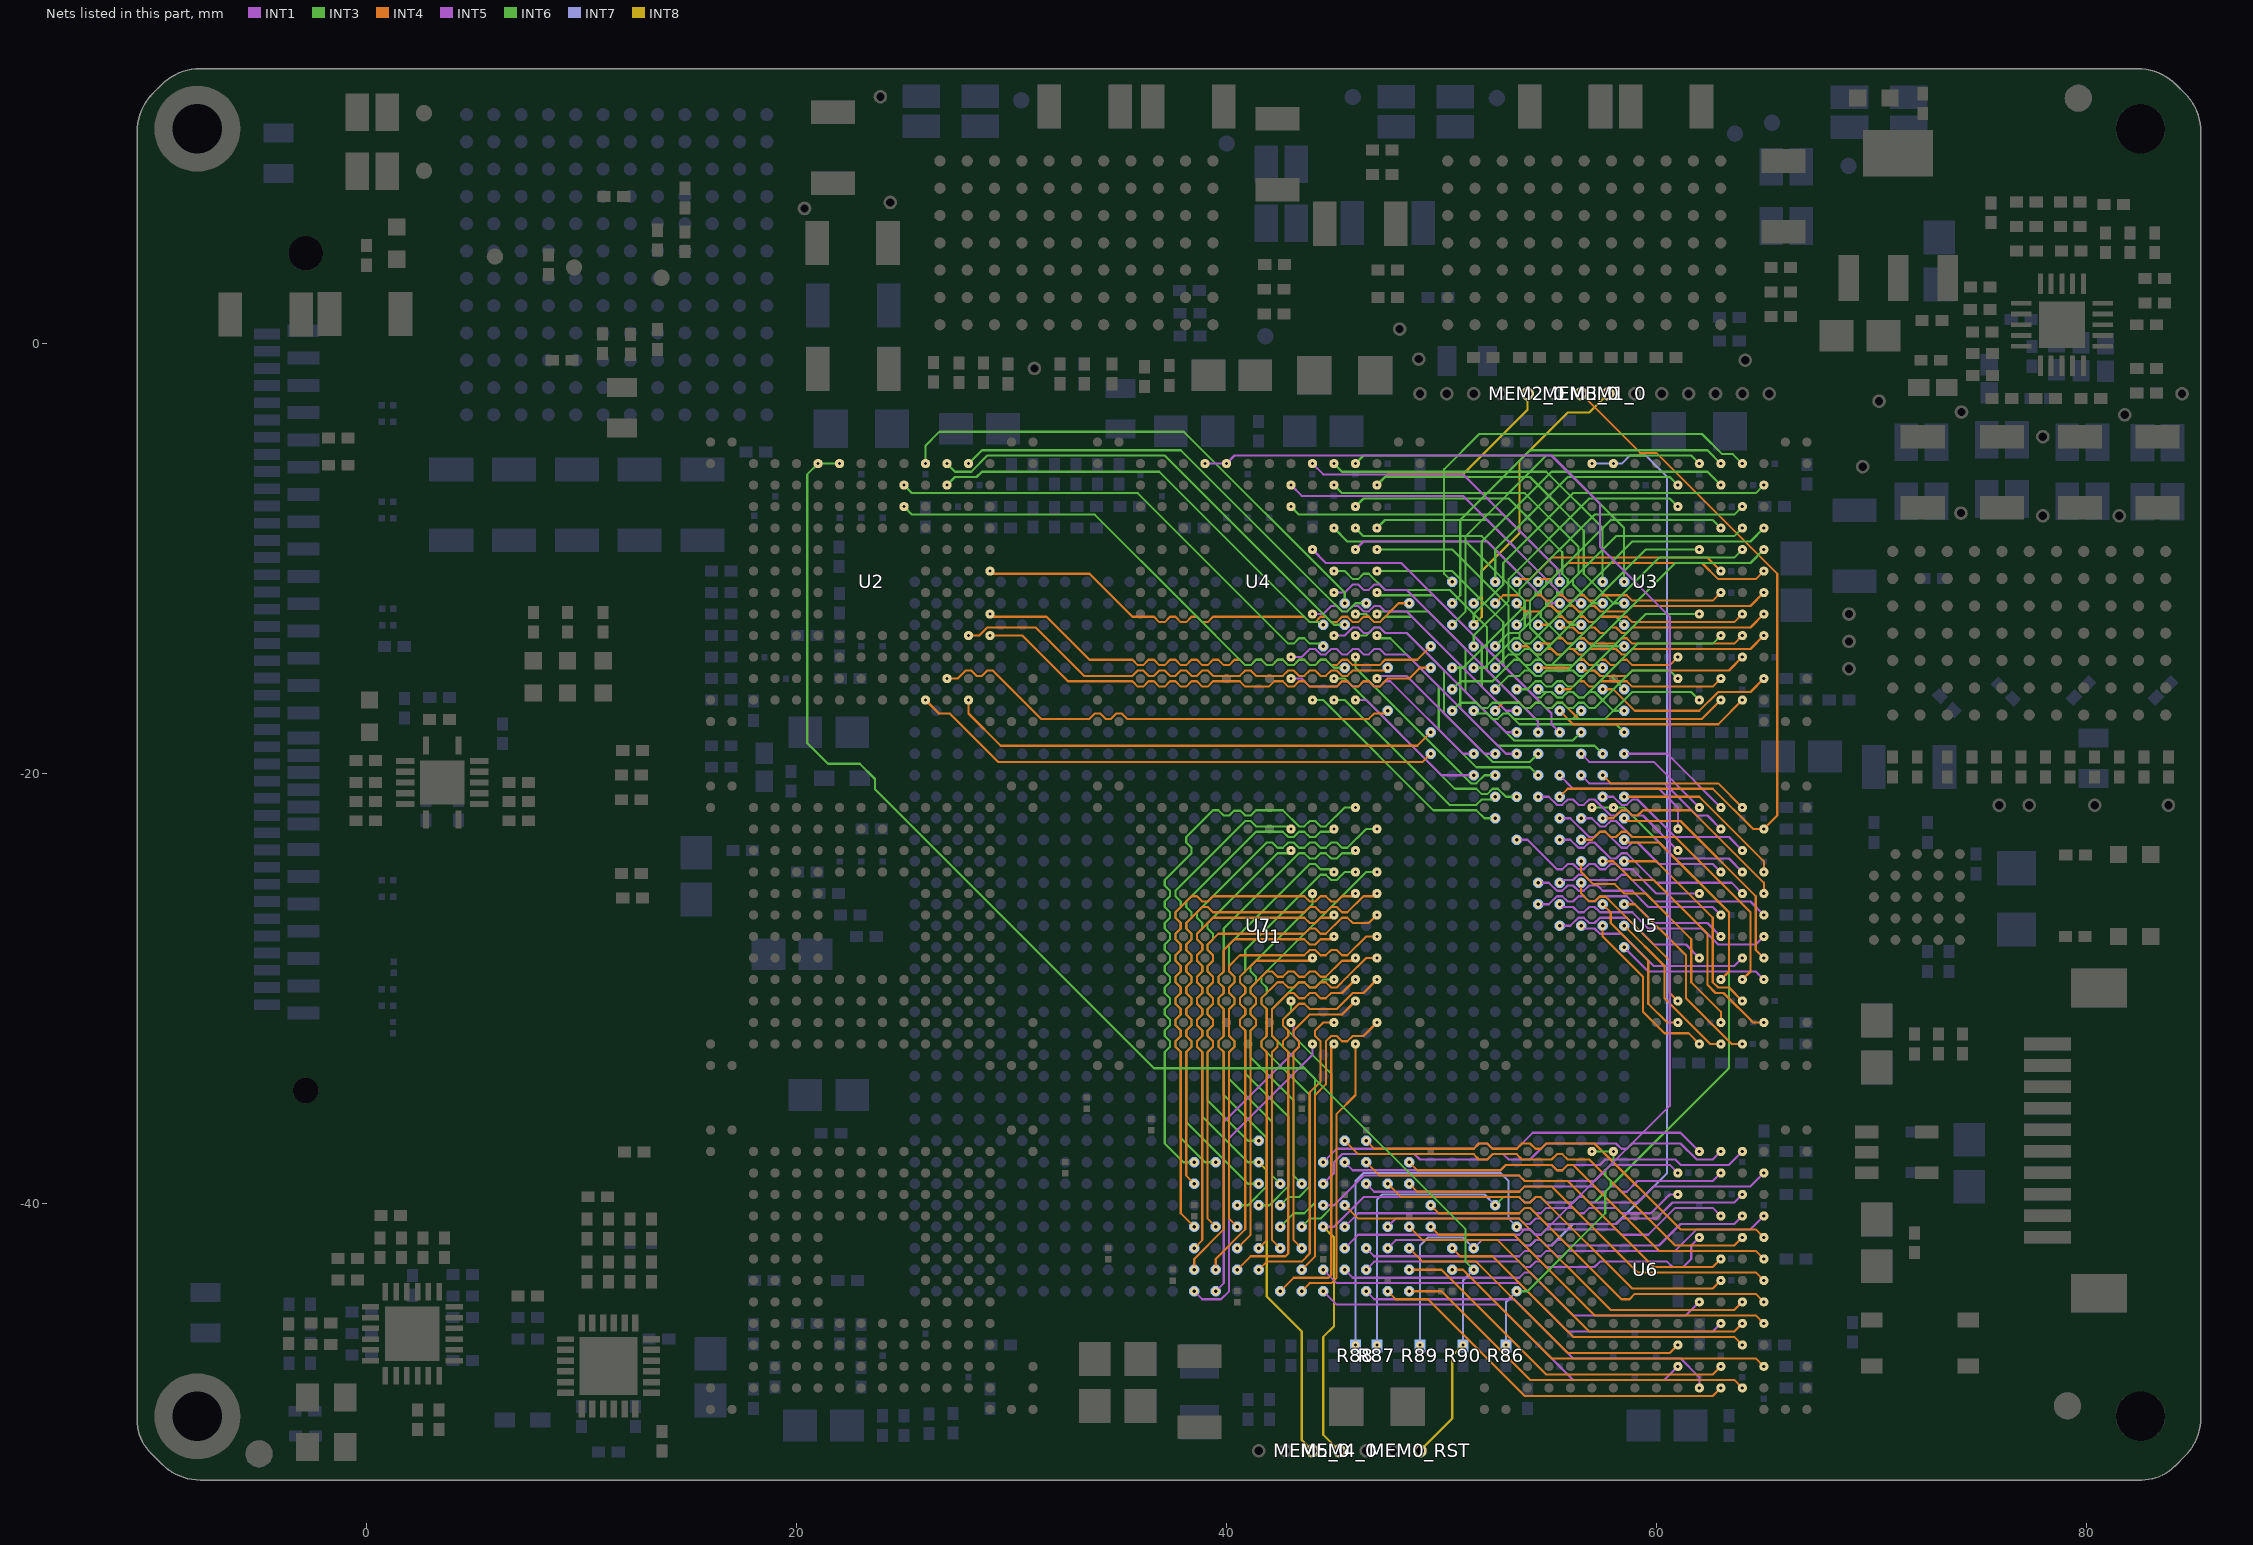
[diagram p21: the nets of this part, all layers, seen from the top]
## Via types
v1: diameter 0.381, hole 0.152, Top Layer to Bottom Layer, tented both sides, 2009 vias
v2: diameter 0.508, hole 0.254, Top Layer to Bottom Layer, tented both sides, 467 vias
v3: diameter 0.406, hole 0.203, Top Layer to Bottom Layer, 458 vias
v4: diameter 0.508, hole 0.254, Top Layer to Bottom Layer, 239 vias
v5: diameter 0.406, hole 0.203, Top Layer to Bottom Layer, tented both sides, 181 vias
v6: diameter 0.381, hole 0.152, Top Layer to GND4, tented both sides, 147 vias
v7: diameter 0.406, hole 0.203, Top Layer to GND4, tented both sides, 10 vias

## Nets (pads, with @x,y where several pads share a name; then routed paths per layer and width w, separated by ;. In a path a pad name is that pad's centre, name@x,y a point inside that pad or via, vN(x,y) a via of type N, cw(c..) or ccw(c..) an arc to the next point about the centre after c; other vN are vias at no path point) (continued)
MEM0_19: U1.AK25 U2.C10 | length 23.5
  INT4 w0.102: v1(29,-13.571) 30.5,-13.571 32.625,-15.696 35.625,-15.696 35.875,-15.946 36.125,-15.946 36.375,-15.696 36.625,-15.696 36.875,-15.946 37.125,-15.946 37.375,-15.696 37.625,-15.696 37.875,-15.946 38.125,-15.946 38.375,-15.696 38.625,-15.696 38.875,-15.946 39.125,-15.946 39.375,-15.696 40.625,-15.696 40.875,-15.946 41.966,-15.946 42.216,-15.696 42.625,-15.696 42.875,-15.946 43.125,-15.946 43.375,-15.696 43.625,-15.696 43.875,-15.946 45.125,-15.946 45.375,-15.696 45.625,-15.696 45.875,-15.946 46.125,-15.946 46.375,-15.696 46.625,-15.696 46.875,-15.946 47.125,-15.946 47.5,-15.571 48.5,-15.571 49,-15.071 v1(49.5,-15.071)
MEM0_20: U1.AG25 U2.D13 | length 23
  INT4 w0.102: v1(28,-16.571) 28,-17.196 29.5,-18.696 48.875,-18.696 v1(49.5,-18.071)
MEM0_21: U1.AF25 U2.F13 | length 24.8
  INT4 w0.102: v1(26,-16.571) 26.625,-17.196 27.125,-17.196 29.375,-19.446 49.125,-19.446 v1(49.5,-19.071)
MEM0_22: U1.AL20 U2.G3 | length 22.8
  INT3 w0.102: v1(25,-6.571) 25.375,-6.946 35.875,-6.946 42.875,-13.946 43.125,-13.946 43.375,-13.696 43.625,-13.696 43.875,-13.946 44.375,-13.946 v1(44.5,-14.071)
MEM0_23: U1.AK21 U2.G4 | length 24.4
  INT3 w0.102: v1(25,-7.571) 25.375,-7.946 33.875,-7.946 38.125,-12.196 40.875,-14.946 41.125,-14.946 41.375,-14.696 41.625,-14.696 41.875,-14.946 42.125,-14.946 42.375,-14.696 42.625,-14.696 42.875,-14.946 43.125,-14.946 43.375,-14.696 43.625,-14.696 43.875,-14.946 44.125,-14.946 44.375,-14.696 44.625,-14.696 45,-15.071 v1(45.5,-15.071)
MEM0_24: U1.AN24 U2.C7 | length 22.1
  INT4 w0.102: v1(29,-10.571) 29.125,-10.696 33.625,-10.696 35.625,-12.696 36.625,-12.696 36.875,-12.946 37.125,-12.946 37.375,-12.696 37.625,-12.696 37.875,-12.946 38.125,-12.946 38.375,-12.696 38.625,-12.696 38.875,-12.946 39.125,-12.946 39.375,-12.696 43.625,-12.696 43.875,-12.946 44.125,-12.946 44.375,-12.696 44.625,-12.696 44.875,-12.946 45.125,-12.946 45.375,-12.696 45.625,-12.696 45.875,-12.946 46.125,-12.946 46.375,-12.696 46.625,-12.696 46.875,-12.946 47.125,-12.946 48,-12.071 v1(48.5,-12.071)
MEM0_25: U1.AL25 U2.C9 | length 23.9
  INT4 w0.102: v1(29,-12.571) 29.125,-12.696 31.625,-12.696 33.625,-14.696 35.625,-14.696 35.875,-14.946 36.125,-14.946 36.375,-14.696 36.625,-14.696 36.875,-14.946 37.125,-14.946 37.375,-14.696 37.625,-14.696 37.875,-14.946 38.125,-14.946 38.375,-14.696 38.625,-14.696 38.875,-14.946 39.125,-14.946 39.375,-14.696 39.625,-14.696 39.875,-14.946 40.125,-14.946 40.375,-14.696 40.625,-14.696 40.875,-14.946 41.125,-14.946 41.375,-14.696 41.625,-14.696 41.875,-14.946 42.125,-14.946 42.375,-14.696 42.625,-14.696 42.875,-14.946 43.125,-14.946 43.375,-14.696 43.625,-14.696 43.875,-14.946 44.125,-14.946 44.375,-14.696 44.625,-14.696 44.875,-14.946 45.125,-14.946 45.375,-14.696 45.625,-14.696 45.875,-14.946 47.125,-14.946 47.375,-14.696 48.875,-14.696 v1(49.5,-14.071)
MEM0_26: U1.AK23 U2.D10 | length 22.4
  INT4 w0.102: v1(28,-13.571) 28.5,-13.571 28.875,-13.196 31.125,-13.196 33.375,-15.446 35.625,-15.446 35.875,-15.196 36.125,-15.196 36.375,-15.446 36.625,-15.446 36.875,-15.196 37.125,-15.196 37.375,-15.446 37.625,-15.446 37.875,-15.196 38.125,-15.196 38.375,-15.446 38.625,-15.446 38.875,-15.196 39.125,-15.196 39.375,-15.446 40.625,-15.446 40.875,-15.196 41.125,-15.196 41.375,-15.446 42.625,-15.446 42.875,-15.196 43.125,-15.196 43.375,-15.446 43.625,-15.446 43.875,-15.196 44.125,-15.196 44.375,-15.446 44.625,-15.446 44.875,-15.196 45.125,-15.196 45.375,-15.446 45.625,-15.446 45.875,-15.196 47.375,-15.196 v1(47.5,-15.071)
MEM0_27: U1.AH23 U2.E12 | length 22.4
  INT4 w0.102: v1(27,-15.571) 27.5,-15.571 27.875,-15.196 28.125,-15.196 28.375,-15.446 28.625,-15.446 28.875,-15.196 29.125,-15.196 31.375,-17.446 33.625,-17.446 33.875,-17.196 34.125,-17.196 34.375,-17.446 34.625,-17.446 34.875,-17.196 35.125,-17.196 35.375,-17.446 46.625,-17.446 46.875,-17.196 47.375,-17.196 v1(47.5,-17.071)
MEM0_28: U1.AM20 U2.E3 | length 20.7
  INT3 w0.102: v1(27,-6.571) 27.375,-6.196 28.375,-6.196 28.625,-5.946 36.875,-5.946 43.875,-12.946 44.375,-12.946 v1(44.5,-13.071)
MEM0_29: U1.AN22 U2.D2 | length 22
  INT3 w0.102: v1(28,-5.571) 28.625,-4.946 37.875,-4.946 44.625,-11.696 45.375,-12.446 45.625,-12.446 46,-12.071 v1(46.5,-12.071)
MEM0_30: U1.AN21 U2.F2 | length 24.2
  INT3 w0.102: v1(26,-5.571) 26,-4.734 26.644,-4.09 38.019,-4.09 45.5,-11.571 v1(45.5,-12.071)
MEM0_31: U1.AM21 U2.E2 | length 22.2
  INT3 w0.102: v1(27,-5.571) 27.375,-5.946 28.125,-5.946 28.875,-5.196 37.125,-5.196 45,-13.071 v1(45.5,-13.071)
MEM0_RST: MEM0_RST.1 R90.2 U1.B27 U2.K2 U2.L2 | length 66
  INT7 w0.102: v1(51,-46.571) 51,-43.571 v1(51.5,-43.071)
  INT8 w0.102: MEM0_RST.1@49,-51.496 50.5,-49.996 50.5,-47.071 v1(51,-46.571)
  INT3 w0.102: v1(22,-5.571) v1(21,-5.571) 20.498,-6.073 20.498,-18.568 21.462,-19.533 22.936,-19.533 23.647,-20.243 23.647,-20.718 36.625,-33.696 43.625,-33.696 51.125,-41.196 51.125,-42.696 v1(51.5,-43.071)
MEM1_0: MEM1_0.1 U1.AM27 U3.C3 | length 31
  INT8 w0.102: v1(51.5,-13.071) 51.875,-12.696 51.875,-10.571 53.625,-8.821 53.625,-5.446 55.875,-3.196 56.875,-3.196 MEM1_0.1@57.75,-2.321
  INT3 w0.102: v1(51.5,-13.071) 51.5,-12.571 52.875,-11.196 52.875,-10.196 56.125,-6.946 64.625,-6.946 v1(65,-6.571)
MEM1_1: U1.AL28 U3.D5 | length 13.8
  INT3 w0.102: v1(52.5,-14.071) 52.75,-13.821 53.125,-13.446 53.625,-13.446 53.875,-13.196 58.125,-8.946 63.625,-8.946 v1(64,-8.571)
MEM1_2: U1.AK27 U3.C5 | length 16.4
  INT3 w0.102: v1(51.5,-15.071) 52,-15.071 53.375,-13.696 53.625,-13.696 53.875,-13.946 54.125,-13.946 54.375,-13.696 58.875,-9.196 64.375,-9.196 v1(65,-8.571)
MEM1_3: U1.AP29 U3.E7 | length 10.2
  INT4 w0.102: v1(53.5,-11.071) 53.625,-10.946 54.125,-10.946 55.125,-9.946 62.375,-9.946 v1(63,-10.571)
MEM1_4: U1.AM30 U3.D9 | length 10.3
  INT4 w0.102: v1(54.5,-13.071) 55,-13.071 55.375,-12.696 55.625,-12.696 55.875,-12.946 56.125,-12.946 56.375,-12.696 56.625,-12.696 56.875,-12.946 57.125,-12.946 57.375,-12.696 58.625,-12.696 58.875,-12.946 63.625,-12.946 v1(64,-12.571)
MEM1_5: U1.AK32 U3.D11 | length 8
  INT4 w0.102: v1(56.5,-15.071) 56.625,-15.196 57.125,-15.196 57.375,-15.446 58.625,-15.446 58.875,-15.196 63.375,-15.196 v1(64,-14.571)
MEM1_6: U1.AJ33 U3.C12 | length 8.5
  INT4 w0.102: v1(57.5,-16.071) 58,-16.071 59,-17.071 62,-17.071 62.875,-16.196 64.375,-16.196 v1(65,-15.571)
MEM1_7: U1.AH26 U3.G12 | length 12.5
  INT3 w0.102: v1(50.5,-17.071) 50.875,-16.696 51.625,-16.696 51.875,-16.946 52.125,-16.946 52.375,-16.696 53.625,-16.696 53.875,-16.946 54.125,-16.946 54.375,-16.696 54.625,-16.696 54.875,-16.946 55.125,-16.946 55.375,-16.696 55.625,-16.696 55.875,-16.946 56.125,-16.946 56.375,-16.696 56.625,-16.696 56.875,-16.946 57.125,-16.946 58.875,-15.196 60.625,-15.196 v1(61,-15.571)
MEM1_8: U1.AK26 U3.D4 | length 17.4
  INT3 w0.102: v1(50.5,-15.071) 51,-15.071 53.875,-12.196 53.875,-11.946 53.625,-11.696 53.625,-11.446 57.125,-7.946 63.625,-7.946 v1(64,-7.571)
MEM1_9: U1.AJ26 U3.D6 | length 16.6
  INT3 w0.102: v1(50.5,-16.071) 50.875,-15.696 52.375,-15.696 53.375,-14.696 53.625,-14.696 53.875,-14.946 54.125,-14.946 54.375,-14.696 54.625,-14.696 54.875,-14.946 55.125,-14.946 60.125,-9.946 63.625,-9.946 v1(64,-9.571)
MEM1_10: U1.AJ28 U3.C6 | length 15.4
  INT3 w0.102: v1(52.5,-16.071) 53.125,-15.446 53.625,-15.446 53.875,-15.196 54.125,-15.196 54.375,-15.446 54.625,-15.446 54.875,-15.196 55.875,-15.196 60.875,-10.196 64.375,-10.196 v1(65,-9.571)
MEM1_11: U1.AN29 U3.C8 | length 12.6
  INT4 w0.102: v1(53.5,-12.071) 53.875,-12.446 54.625,-12.446 54.875,-12.196 55.125,-12.196 55.375,-12.446 55.625,-12.446 55.875,-12.196 56.125,-12.196 56.375,-12.446 56.625,-12.446 56.875,-12.196 57.125,-12.196 57.375,-12.446 58.625,-12.446 58.875,-12.196 64.375,-12.196 v1(65,-11.571)
MEM1_12: U1.AJ29 U3.F9 | length 10.4
  INT3 w0.102: v1(53.5,-16.071) 54,-16.071 54.375,-15.696 54.625,-15.696 54.875,-15.946 55.125,-15.946 55.375,-15.696 55.625,-15.696 55.875,-15.946 56.125,-15.946 56.375,-15.696 59.5,-12.571 v1(62,-12.571)
MEM1_13: U1.AJ30 U3.E10 | length 10.1
  INT3 w0.102: v1(54.5,-16.071) 54.625,-16.196 55.125,-16.196 55.375,-16.446 55.625,-16.446 55.875,-16.196 56.125,-16.196 56.375,-16.446 56.625,-16.446 56.875,-16.196 59.125,-13.946 62.625,-13.946 v1(63,-13.571)
MEM1_14: U1.AK30 U3.G11 | length 7.3
  INT4 w0.102: v1(54.5,-15.071) 56,-15.071 56.375,-14.696 56.625,-14.696 56.875,-14.946 57.125,-14.946 57.375,-14.696 57.625,-14.696 57.875,-14.946 58.125,-14.946 58.375,-14.696 58.625,-14.696 58.875,-14.946 60.625,-14.946 v1(61,-14.571)
MEM1_15: U1.AH28 U3.E13 | length 11.7
  INT4 w0.102: v1(52.5,-17.071) 52.875,-16.696 53.625,-16.696 53.875,-16.946 54.125,-16.946 54.375,-16.696 54.625,-16.696 54.875,-16.946 55.125,-16.946 55.375,-16.696 55.625,-16.696 56.375,-17.446 62.125,-17.446 v1(63,-16.571)
MEM1_16: U1.AM29 U3.E5 | length 12
  INT3 w0.102: v1(53.5,-13.071) 54.125,-12.446 54.125,-11.946 57.875,-8.196 62.625,-8.196 v1(63,-8.571)
MEM1_17: U1.AK28 U3.F6 | length 12
  INT3 w0.102: v1(52.5,-15.071) 53.125,-14.446 53.625,-14.446 53.875,-14.196 54.125,-14.196 54.375,-14.446 54.625,-14.446 54.875,-14.196 59.5,-9.571 v1(62,-9.571)
MEM1_18: U1.AN28 U3.E8 | length 11.7
  INT4 w0.102: v1(52.5,-12.071) 52.875,-11.696 53.625,-11.696 53.875,-11.946 54.125,-11.946 54.375,-11.696 54.625,-11.696 54.875,-11.946 55.125,-11.946 55.375,-11.696 55.625,-11.696 55.875,-11.946 56.125,-11.946 56.375,-11.696 56.625,-11.696 56.875,-11.946 57.125,-11.946 57.375,-11.696 58.625,-11.696 58.875,-11.946 62.625,-11.946 v1(63,-11.571)
MEM1_19: U1.AL29 U3.C10 | length 12.6
  INT4 w0.102: v1(53.5,-14.071) 54,-14.071 54.375,-14.446 54.625,-14.446 54.875,-14.196 55.125,-14.196 55.375,-14.446 55.625,-14.446 55.875,-14.196 56.125,-14.196 56.375,-14.446 56.625,-14.446 56.875,-14.196 58,-14.196 58.125,-14.196 58.375,-14.446 58.625,-14.446 58.875,-14.196 64.375,-14.196 v1(65,-13.571)
MEM1_20: U1.AH31 U3.D13 | length 9.2
  INT4 w0.102: v1(55.5,-17.071) 56.125,-17.696 62.875,-17.696 v1(64,-16.571)
MEM1_21: U1.AH27 U3.F13 | length 11.5
  INT3 w0.102: v1(51.5,-17.071) 51.625,-17.196 52.125,-17.196 52.375,-17.446 52.625,-17.446 52.875,-17.196 53.125,-17.196 53.375,-17.446 57.625,-17.446 58.875,-16.196 61.625,-16.196 v1(62,-16.571)
MEM1_22: U1.AP28 U3.G3 | length 11.6
  INT3 w0.102: v1(52.5,-11.071) 52.5,-9.571 55.875,-6.196 60.625,-6.196 v1(61,-6.571)
MEM1_23: U1.AL27 U3.G4 | length 13.4
  INT3 w0.102: v1(51.5,-14.071) 51.5,-13.571 53.125,-11.946 53.125,-10.946 56.875,-7.196 60.625,-7.196 v1(61,-7.571)
MEM1_24: U1.AP30 U3.C7 | length 11.3
  INT4 w0.102: v1(54.5,-11.071) 54.625,-10.946 55.125,-10.946 55.875,-10.196 62.125,-10.196 62.875,-10.946 64.625,-10.946 v1(65,-10.571)
MEM1_25: U1.AM31 U3.C9 | length 10.4
  INT4 w0.102: v1(55.5,-13.071) 55.625,-13.196 56.125,-13.196 56.375,-13.446 56.625,-13.446 56.875,-13.196 57.125,-13.196 57.375,-13.446 57.625,-13.446 57.875,-13.196 58.125,-13.196 58.375,-13.446 58.625,-13.446 58.875,-13.196 64.375,-13.196 v1(65,-12.571)
MEM1_26: U1.AL30 U3.D10 | length 10.3
  INT4 w0.102: v1(54.5,-14.071) 54.625,-13.946 55.125,-13.946 55.375,-13.696 55.625,-13.696 55.875,-13.946 56.125,-13.946 56.375,-13.696 56.625,-13.696 56.875,-13.946 58.125,-13.946 58.375,-13.696 58.625,-13.696 58.875,-13.946 63.625,-13.946 v1(64,-13.571)
MEM1_27: U1.AJ31 U3.E12 | length 8.1
  INT4 w0.102: v1(55.5,-16.071) 56,-16.071 56.375,-15.696 56.625,-15.696 56.875,-15.946 57.125,-15.946 57.375,-15.696 58.625,-15.696 58.875,-15.946 62.625,-15.946 v1(63,-15.571)
MEM1_28: U1.AN27 U3.E3 | length 15.8
  INT3 w0.102: v1(51.5,-12.071) 51.875,-11.696 51.875,-9.196 55.125,-5.946 62.375,-5.946 v1(63,-6.571)
MEM1_29: U1.AP26 U3.D2 | length 20.5
  INT3 w0.102: v1(50.5,-11.071) 50.125,-10.696 50.125,-5.831 51.76,-4.196 62.125,-4.196 63.06,-5.131 63.56,-5.131 v1(64,-5.571)
MEM1_30: U1.AM26 U3.F2 | length 17
  INT3 w0.102: v1(50.5,-13.071) 51.125,-12.446 51.125,-8.946 54.875,-5.196 61.625,-5.196 v1(62,-5.571)
MEM1_31: U1.AN26 U3.E2 | length 17.8
  INT3 w0.102: v1(50.5,-12.071) 50.875,-11.696 50.875,-8.196 54.125,-4.946 62.375,-4.946 v1(63,-5.571)
MEM1_RST: R89.2 U1.C27 U3.K2 U3.L2 | length 54.8
  INT7 w0.102: v1(49,-46.571) 49,-41.946 49.375,-41.571 51,-41.571 v1(51.5,-42.071) 51.875,-41.696 53.625,-41.696 53.875,-41.946 54.125,-41.946 54.375,-41.696 54.625,-41.696 54.875,-41.946 55.125,-41.946 56.125,-40.946 58.125,-40.946 60.5,-38.571 60.5,-6.196 59.5,-5.196 58.761,-5.196 58.386,-5.571 v1(58,-5.571) v1(57,-5.571)
MEM2_0: MEM2_0.1 U1.AN34 U4.C3 | length 24.5
  INT6 w0.102: v1(47,-6.571) 47.375,-6.196 54.125,-6.196 56.625,-8.696 56.625,-10.696 58,-12.071 v1(58.5,-12.071)
  INT8 w0.102: v1(47,-6.571) 47.5,-6.071 51,-6.071 54,-3.071 MEM2_0.1@54,-2.321
MEM2_1: U1.AL32 U4.D5 | length 14.5
  INT6 w0.102: v1(46,-8.571) 46.375,-8.946 51.875,-8.946 54.375,-11.446 54.375,-11.696 54.125,-11.946 54.125,-13.196 55.375,-14.446 55.625,-14.446 55.875,-14.196 56.375,-14.196 v1(56.5,-14.071)
MEM2_2: U1.AL34 U4.C5 | length 15.9
  INT6 w0.102: v1(47,-8.571) 47.375,-8.196 52.125,-8.196 54.875,-10.946 54.875,-11.196 54.625,-11.446 54.625,-11.696 54.875,-11.946 54.875,-12.196 54.625,-12.446 54.625,-12.696 55.875,-13.946 56.125,-13.946 56.375,-13.696 56.625,-13.696 57,-14.071 v1(58.5,-14.071)
MEM2_3: U1.AH32 U4.E7 | length 15.9
  INT6 w0.102: v1(45,-10.571) 45.5,-10.571 45.875,-10.946 46.125,-10.946 46.375,-10.696 46.625,-10.696 47.375,-11.446 50.375,-11.446 52.125,-13.196 52.125,-15.196 54.375,-17.446 56.125,-17.446 v1(56.5,-17.071)
MEM2_4: U1.AF33 U4.D9 | length 15.6
  INT6 w0.102: v1(46,-12.571) 46.5,-12.571 46.875,-12.946 47.125,-12.946 47.375,-12.696 48.625,-12.696 50.875,-14.946 50.875,-16.946 52.625,-18.696 57.125,-18.696 v1(57.5,-19.071)
MEM2_5: U1.AE28 U4.D11 | length 9.4
  INT6 w0.102: v1(46,-14.571) 46,-15.071 51.375,-20.446 51.625,-20.446 52,-20.071 v1(52.5,-20.071)
MEM2_6: U1.AF28 U4.C12 | length 7.1
  INT5 w0.102: v1(47,-15.571) 47.125,-15.446 48.375,-15.446 52,-19.071 v1(52.5,-19.071)
MEM2_7: U1.AF27 U4.G12 | length 10.6
  INT5 w0.102: v1(43,-15.571) 43.5,-15.571 43.875,-15.946 45.125,-15.946 45.375,-15.696 45.625,-15.696 45.875,-15.946 46.125,-15.946 46.375,-15.696 46.625,-15.696 46.875,-15.946 47.125,-15.946 47.375,-15.696 47.625,-15.696 51,-19.071 v1(51.5,-19.071)
MEM2_8: U1.AM34 U4.D4 | length 16.7
  INT6 w0.102: v1(46,-7.571) 46.375,-7.196 53.125,-7.196 55.625,-9.696 55.625,-10.696 55.875,-10.946 55.875,-11.196 55.625,-11.446 55.625,-11.696 56.875,-12.946 57.125,-12.946 57.375,-12.696 58.125,-12.696 v1(58.5,-13.071)
MEM2_9: U1.AN31 U4.D6 | length 10.8
  INT5 w0.102: v1(46,-9.571) 46.375,-9.196 52.125,-9.196 55,-12.071 v1(55.5,-12.071)
MEM2_10: U1.AJ34 U4.C6 | length 15.8
  INT6 w0.102: v1(47,-9.571) 50.5,-9.571 53.125,-12.196 53.125,-14.196 54.375,-15.446 54.625,-15.446 54.875,-15.196 56.125,-15.196 56.375,-15.446 56.625,-15.446 56.875,-15.196 57.125,-15.196 57.375,-15.446 57.875,-15.446 v1(58.5,-16.071)
MEM2_11: U1.AG34 U4.C8 | length 15.4
  INT6 w0.102: v1(47,-11.571) 47.125,-11.696 49.625,-11.696 51.875,-13.946 51.875,-15.946 53.625,-17.696 58.125,-17.696 v1(58.5,-18.071)
MEM2_12: U1.AH29 U4.F9 | length 12.1
  INT5 w0.102: v1(44,-12.571) 44.5,-12.571 44.875,-12.196 45.125,-12.196 45.375,-12.446 45.625,-12.446 45.875,-12.196 46.125,-12.196 46.375,-12.446 46.625,-12.446 46.875,-12.196 47.125,-12.196 47.375,-12.446 48.375,-12.446 53,-17.071 v1(53.5,-17.071)
MEM2_13: U1.AG29 U4.E10 | length 10.9
  INT5 w0.102: v1(45,-13.571) 45.5,-13.571 45.875,-13.196 46.125,-13.196 46.375,-13.446 46.625,-13.446 46.875,-13.196 47.125,-13.196 47.375,-13.446 48.375,-13.446 53,-18.071 v1(53.5,-18.071)
MEM2_14: U1.AF29 U4.G11 | length 13.3
  INT5 w0.102: v1(43,-14.571) 43.5,-14.571 43.875,-14.196 44.125,-14.196 44.375,-14.446 44.625,-14.446 44.875,-14.196 45.125,-14.196 45.375,-14.446 45.625,-14.446 45.875,-14.196 46.125,-14.196 46.375,-14.446 46.625,-14.446 46.875,-14.196 47.125,-14.196 47.375,-14.446 48.375,-14.446 53,-19.071 v1(53.5,-19.071)
MEM2_15: U1.AD28 U4.E13 | length 9.7
  INT6 w0.102: v1(45,-16.571) 45.5,-16.571 50.375,-21.446 51.625,-21.446 51.875,-21.196 52.375,-21.196 v1(52.5,-21.071)
MEM2_16: U1.AK33 U4.E5 | length 16.8
  INT6 w0.102: v1(45,-8.571) 45.625,-9.196 51.125,-9.196 53.875,-11.946 53.875,-13.196 53.625,-13.446 53.625,-13.696 54.625,-14.696 54.875,-14.946 56.125,-14.946 56.375,-14.696 56.625,-14.696 56.875,-14.946 57.375,-14.946 v1(57.5,-15.071)
MEM2_17: U1.AG31 U4.F6 | length 15.3
  INT5 w0.102: v1(44,-9.571) 44.625,-10.196 48.125,-10.196 55.125,-17.196 55.125,-17.696 v1(55.5,-18.071)
MEM2_18: U1.AG30 U4.E8 | length 13
  INT5 w0.102: v1(45,-11.571) 45.5,-11.571 45.875,-11.196 46.125,-11.196 46.375,-11.446 46.625,-11.446 46.875,-11.196 47.125,-11.196 47.375,-11.446 48.375,-11.446 54.5,-17.571 v1(54.5,-18.071)
MEM2_19: U1.AE30 U4.C10 | length 11.4
  INT6 w0.102: v1(47,-13.571) 47.125,-13.696 47.625,-13.696 49.875,-15.946 49.875,-17.946 51.625,-19.696 54.125,-19.696 v1(54.5,-20.071)
MEM2_20: U1.AE27 U4.D13 | length 6.9
  INT5 w0.102: v1(46,-16.571) 46.5,-16.571 50,-20.071 v1(51.5,-20.071)
MEM2_21: U1.AC28 U4.F13 | length 10.8
  INT6 w0.102: v1(44,-16.571) 44.5,-16.571 49.625,-21.696 51.625,-21.696 52,-22.071 v1(52.5,-22.071)
MEM2_22: U1.AN32 U4.G3 | length 15.8
  INT5 w0.102: v1(43,-6.571) 43.5,-7.071 51,-7.071 55.875,-11.946 56.375,-11.946 v1(56.5,-12.071)
MEM2_23: U1.AM32 U4.G4 | length 17.4
  INT6 w0.102: v1(43,-7.571) 43.375,-7.946 52.875,-7.946 55.375,-10.446 55.375,-10.696 55.125,-10.946 55.125,-11.196 55.375,-11.446 55.375,-11.696 55.125,-11.946 55.125,-12.196 56,-13.071 v1(56.5,-13.071)
MEM2_24: U1.AH34 U4.C7 | length 16
  INT6 w0.102: v1(47,-10.571) 50.5,-10.571 52.875,-12.946 52.875,-14.946 54.375,-16.446 54.625,-16.446 54.875,-16.196 55.125,-16.196 55.375,-16.446 55.625,-16.446 55.875,-16.196 56.125,-16.196 56.25,-16.321 56.375,-16.446 56.625,-16.446 56.875,-16.196 57.125,-16.196 58,-17.071 v1(58.5,-17.071)
MEM2_25: U1.AG32 U4.C9 | length 13.4
  INT6 w0.102: v1(47,-12.571) 47.125,-12.446 49.375,-12.446 51.125,-14.196 51.125,-16.196 53.375,-18.446 56.125,-18.446 v1(56.5,-18.071)
MEM2_26: U1.AF30 U4.D10 | length 12.6
  INT6 w0.102: v1(46,-13.571) 46.5,-13.571 46.875,-13.196 47.125,-13.196 47.375,-13.446 48.375,-13.446 50.125,-15.196 50.125,-17.196 52.375,-19.446 54.125,-19.446 v1(54.5,-19.071)
MEM2_27: U1.AD29 U4.E12 | length 11
  INT6 w0.102: v1(45,-15.571) 45.5,-15.571 50.625,-20.696 51.625,-20.696 51.875,-20.946 52.125,-20.946 52.375,-20.696 52.625,-20.696 53,-21.071 v1(53.5,-21.071)
MEM2_28: U1.AN33 U4.E3 | length 16.2
  INT6 w0.102: v1(45,-6.571) 45.375,-6.946 53.875,-6.946 56.375,-9.446 56.375,-10.696 56.125,-10.946 56.125,-11.196 57,-12.071 v1(57.5,-12.071)
MEM2_29: U1.AP34 U4.D2 | length 16.6
  INT6 w0.102: v1(46,-5.571) 46.375,-5.196 55.125,-5.196 58.5,-8.571 v1(58.5,-11.071)
MEM2_30: U1.AP31 U4.F2 | length 14.1
  INT5 w0.102: v1(44,-5.571) 44.5,-6.071 51,-6.071 55.5,-10.571 v1(55.5,-11.071)
MEM2_31: U1.AP33 U4.E2 | length 16.2
  INT6 w0.102: v1(45,-5.571) 45.375,-5.946 54.875,-5.946 57.5,-8.571 v1(57.5,-11.071)
MEM2_RST: R88.2 U1.D29 U4.K2 U4.L2 | length 75.9
  INT7 w0.102: v1(46,-46.571) 46,-38.946 46.375,-38.571 52.75,-38.571 53.125,-38.946 53.125,-40.696 v1(53.5,-41.071)
  INT1 w0.102: v1(39,-5.571) v1(40,-5.571) 40.375,-5.196 55.125,-5.196 57.375,-7.446 57.375,-9.446 60.625,-12.696 60.625,-35.446 55,-41.071 54.625,-41.446 54.375,-41.446 54.125,-41.196 53.625,-41.196 v1(53.5,-41.071)
MEM3_0: MEM3_0.1 U1.AD31 U5.C3 | length 35.2
  INT4 w0.102: v1(55.5,-21.071) 55.875,-20.696 62.625,-20.696 64.5,-22.571 v1(65,-22.571) 65.625,-21.946 65.625,-10.696 60,-5.071 59.25,-5.071 MEM3_0.1@56.5,-2.321
MEM3_1: U1.AC32 U5.D5 | length 8.7
  INT5 w0.102: v1(56.5,-22.071) 57,-22.071 57.375,-22.446 57.625,-22.446 57.875,-22.196 58.125,-22.196 58.875,-22.946 59.875,-22.946 60.875,-23.946 63.375,-23.946 v1(64,-24.571)
MEM3_2: U1.AD34 U5.C5 | length 8.2
  INT4 w0.102: v1(58.5,-21.071) 62,-21.071 65,-24.071 v1(65,-24.571)
MEM3_3: U1.Y30 U5.E7 | length 9.5
  INT5 w0.102: v1(54.5,-25.071) 55,-25.071 55.375,-25.446 55.625,-25.446 55.875,-25.196 56.125,-25.196 56.375,-25.446 56.625,-25.446 56.875,-25.196 57.25,-25.196 57.5,-25.446 58.875,-25.446 59.625,-26.196 62.625,-26.196 v1(63,-26.571)
MEM3_4: U1.V32 U5.D9 | length 8.4
  INT5 w0.102: v1(56.5,-27.071) 56.625,-27.196 57.125,-27.196 57.375,-27.446 58.375,-27.446 59.875,-28.946 63.625,-28.946 v1(64,-28.571)
MEM3_5: U1.AA34 U5.D11 | length 9.9
  INT4 w0.102: v1(58.5,-24.071) 60,-24.071 62.625,-26.696 62.625,-29.696 62.875,-29.946 63.375,-29.946 v1(64,-30.571)
MEM3_6: U1.AA33 U5.C12 | length 12
  INT4 w0.102: v1(57.5,-24.071) 58,-24.071 58.875,-24.946 59.875,-24.946 62.375,-27.446 62.375,-29.821 62.75,-30.196 63.125,-30.196 64.5,-31.571 v1(65,-31.571)
MEM3_7: U1.W33 U5.G12 | length 7.2
  INT4 w0.102: v1(57.5,-26.071) 57.875,-26.446 57.875,-26.946 59.625,-28.696 59.625,-30.696 60.5,-31.571 v1(61,-31.571)
MEM3_8: U1.AD33 U5.D4 | length 7.7
  INT5 w0.102: v1(57.5,-21.071) 58,-21.071 58.375,-21.446 58.625,-21.446 58.875,-21.196 59.125,-21.196 60.875,-22.946 63.375,-22.946 v1(64,-23.571)
MEM3_9: U1.AB31 U5.D6 | length 9.9
  INT5 w0.102: v1(55.5,-23.071) 56,-23.071 56.375,-23.446 56.625,-23.446 56.875,-23.196 57.125,-23.196 57.875,-23.946 58.125,-23.946 58.375,-23.696 58.625,-23.696 60,-25.071 63.5,-25.071 v1(64,-25.571)
MEM3_10: U1.AC33 U5.C6 | length 9.8
  INT4 w0.102: v1(57.5,-22.071) 58,-22.071 58.375,-21.696 58.625,-21.696 58.875,-21.946 59.125,-21.946 59.375,-21.696 61.625,-21.696 65,-25.071 v1(65,-25.571)
MEM3_11: U1.W31 U5.C8 | length 10.6
  INT5 w0.102: v1(55.5,-26.071) 55.625,-26.196 56.125,-26.196 56.375,-26.446 56.625,-26.446 56.875,-26.196 57.125,-26.196 57.375,-26.446 58.875,-26.446 59.625,-27.196 62.125,-27.196 62.875,-27.946 64.625,-27.946 v1(65,-27.571)
MEM3_12: U1.V31 U5.F9 | length 7.6
  INT5 w0.102: v1(55.5,-27.071) 56,-27.071 56.375,-26.696 56.625,-26.696 56.875,-26.946 57.125,-26.946 57.375,-26.696 58.625,-26.696 59.875,-27.946 61.375,-27.946 v1(62,-28.571)
MEM3_13: U1.AB34 U5.E10 | length 9.6
  INT4 w0.102: v1(58.5,-23.071) 58.625,-23.196 60.125,-23.196 63.375,-26.446 63.375,-29.196 v1(63,-29.571)
MEM3_14: U1.Y32 U5.G11 | length 8.1
  INT4 w0.102: v1(56.5,-25.071) 56.5,-25.57 56.854,-25.924 57.146,-25.924 57.352,-25.718 57.646,-25.718 57.759,-25.831 60.625,-28.696 60.625,-30.196 v1(61,-30.571)
MEM3_15: U1.V34 U5.E13 | length 7.7
  INT4 w0.102: v1(58.5,-27.071) 60.375,-28.946 60.375,-30.446 62.5,-32.571 v1(63,-32.571)
MEM3_16: U1.AC31 U5.E5 | length 8.9
  INT5 w0.102: v1(55.5,-22.071) 56,-22.071 56.875,-22.946 57.125,-22.946 57.375,-22.696 57.625,-22.696 58.375,-23.446 58.625,-23.446 58.875,-23.196 59.125,-23.196 60.125,-24.196 62.625,-24.196 v1(63,-24.571)
MEM3_17: U1.AB29 U5.F6 | length 10.2
  INT5 w0.102: v1(53.5,-23.071) 54,-23.071 54.75,-23.821 55.375,-24.446 55.625,-24.446 55.875,-24.196 56.125,-24.196 56.375,-24.446 56.625,-24.446 56.875,-24.196 ; 56.875,-24.196 57.125,-24.196 57.375,-24.446 57.625,-24.446 57.875,-24.196 58.125,-24.196 58.375,-24.446 58.875,-24.446 60,-25.571 v1(62,-25.571)
MEM3_18: U1.W30 U5.E8 | length 9.8
  INT5 w0.102: v1(54.5,-26.071) 55,-26.071 55.375,-25.696 55.625,-25.696 55.875,-25.946 56.125,-25.946 56.375,-25.696 56.625,-25.696 56.875,-25.946 57.125,-25.946 57.375,-25.696 58.625,-25.696 59.875,-26.946 62.375,-26.946 v1(63,-27.571)
MEM3_19: U1.U34 U5.C10 | length 7.1
  INT5 w0.102: v1(58.5,-28.071) 58.75,-28.321 59.625,-29.196 64.625,-29.196 v1(65,-29.571)
MEM3_20: U1.W34 U5.D13 | length 9.4
  INT4 w0.102: v1(58.5,-26.071) 59,-26.071 61.375,-28.446 61.375,-30.446 63.5,-32.571 v1(64,-32.571)
MEM3_21: U1.V33 U5.F13 | length 8
  INT4 w0.102: v1(57.5,-27.071) 57.5,-27.571 59.375,-29.446 59.375,-31.071 60.375,-32.071 61.5,-32.071 v1(62,-32.571)
MEM3_22: U1.AE31 U5.G3 | length 7.1
  INT5 w0.102: v1(55.5,-20.071) 56.125,-20.696 60.125,-20.696 61,-21.571 v1(61,-22.571)
MEM3_23: U1.AD30 U5.G4 | length 8.2
  INT5 w0.102: v1(54.5,-21.071) 55,-21.071 55.375,-21.446 55.625,-21.446 55.875,-21.196 56.125,-21.196 56.375,-21.446 56.625,-21.446 56.875,-21.196 57.125,-21.196 57.875,-21.946 58.125,-21.946 58.375,-21.696 58.625,-21.696 58.875,-21.946 59.375,-21.946 v1(61,-23.571)
MEM3_24: U1.Y31 U5.C7 | length 10.6
  INT5 w0.102: v1(55.5,-25.071) 55.625,-24.946 56.125,-24.946 56.375,-24.696 56.625,-24.696 56.875,-24.946 58.125,-24.946 58.375,-24.696 58.625,-24.696 59.875,-25.946 64.375,-25.946 v1(65,-26.571)
MEM3_25: U1.AC34 U5.C9 | length 10.7
  INT4 w0.102: v1(58.5,-22.071) 58.625,-22.196 61.125,-22.196 64.625,-25.696 64.625,-28.196 v1(65,-28.571)
MEM3_26: U1.AB32 U5.D10 | length 13.1
  INT4 w0.102: v1(56.5,-23.071) 57,-23.071 57.375,-22.696 57.625,-22.696 57.875,-22.946 58.125,-22.946 58.375,-22.696 58.625,-22.696 58.875,-22.946 60.875,-22.946 64.375,-26.446 64.375,-29.196 v1(64,-29.571)
MEM3_27: U1.AA32 U5.E12 | length 11.4
  INT4 w0.102: v1(56.5,-24.071) 56.5,-24.57 57.065,-25.135 58.064,-25.135 58.5,-25.571 59.5,-25.571 61.625,-27.696 61.625,-29.696 63,-31.071 v1(63,-31.571)
MEM3_28: U1.AE32 U5.E3 | length 7.5
  INT5 w0.102: v1(56.5,-20.071) 56.875,-20.446 60.375,-20.446 61.875,-21.946 62.375,-21.946 v1(63,-22.571)
MEM3_29: U1.AE33 U5.D2 | length 7.1
  INT4 w0.102: v1(57.5,-20.071) 57.875,-20.446 62.875,-20.446 v1(64,-21.571)
MEM3_30: U1.AF32 U5.F2 | length 6.5
  INT5 w0.102: v1(56.5,-19.071) 56.875,-19.446 59.875,-19.446 v1(62,-21.571)
MEM3_31: U1.AF34 U5.E2 | length 5.5
  INT5 w0.102: v1(58.5,-19.071) 60.5,-19.071 v1(63,-21.571)
MEM3_RST: R87.2 U1.E28 U5.K2 U5.L2 | length 42.3
  INT6 w0.102: v1(52.5,-40.071) 52.875,-39.696 53.625,-39.696 53.875,-39.946 54.125,-39.946 54.375,-39.696 54.625,-39.696 54.875,-39.946 56.125,-39.946 56.375,-39.696 56.625,-39.696 56.875,-39.946 57.125,-39.946 63.375,-33.696 63.375,-26.446 58.5,-21.571 v1(58,-21.571) v1(57,-21.571)
  INT7 w0.102: v1(47,-46.571) 47,-39.821 47.25,-39.571 52,-39.571 v1(52.5,-40.071)
MEM4_0: MEM4_0.1 U1.D20 U6.C3 | length 33.3
  INT5 w0.102: v1(44.5,-41.071) 45,-41.071 46.375,-39.696 53.625,-39.696 53.875,-39.946 54.125,-39.946 54.375,-39.696 54.625,-39.696 54.875,-39.946 56.125,-39.946 56.375,-39.696 56.625,-39.696 56.875,-39.946 59.125,-39.946 59.875,-39.196 64.375,-39.196 v1(65,-38.571)
  INT8 w0.102: v1(44.5,-41.071) 45,-41.571 45,-45.696 44.5,-46.196 44.5,-50.746 MEM4_0.1@45.25,-51.496
MEM4_1: U1.C23 U6.D5 | length 17.7
  INT5 w0.102: v1(47.5,-42.071) 47.875,-41.696 53.625,-41.696 53.875,-41.946 54.125,-41.946 54.375,-41.696 54.625,-41.696 54.875,-41.946 55.125,-41.946 55.375,-41.696 55.625,-41.696 55.875,-41.946 60.125,-41.946 61.125,-40.946 63.625,-40.946 v1(64,-40.571)
MEM4_2: U1.C22 U6.C5 | length 19.8
  INT5 w0.102: v1(46.5,-42.071) 46.875,-42.446 53.625,-42.446 53.875,-42.196 54.125,-42.196 54.375,-42.446 54.625,-42.446 54.875,-42.196 55.125,-42.196 55.375,-42.446 55.625,-42.446 55.875,-42.196 60.875,-42.196 61.875,-41.196 64.375,-41.196 v1(65,-40.571)
MEM4_3: U1.G22 U6.E7 | length 18.7
  INT4 w0.102: v1(46.5,-38.071) 47.125,-38.696 53.625,-38.696 53.875,-38.946 55.875,-38.946 59.875,-42.946 62.625,-42.946 v1(63,-42.571)
MEM4_4: U1.E21 U6.D9 | length 20.7
  INT4 w0.102: v1(45.5,-40.071) 46.125,-40.696 53.625,-40.696 57.875,-44.946 63.625,-44.946 v1(64,-44.571)
MEM4_5: U1.C26 U6.D11 | length 15.4
  INT4 w0.102: v1(50.5,-42.071) 50.875,-42.446 52.375,-42.446 56.125,-46.196 63.625,-46.196 v1(64,-46.571)
MEM4_6: U1.B26 U6.C12 | length 16.4
  INT4 w0.102: v1(50.5,-43.071) 51,-43.071 55.125,-47.196 64.625,-47.196 v1(65,-47.571)
MEM4_7: U1.A20 U6.G12 | length 18.5
  INT5 w0.102: v1(44.5,-44.071) 45.125,-44.696 52.625,-44.696 56.125,-48.196 60.375,-48.196 v1(61,-47.571)
MEM4_8: U1.D23 U6.D4 | length 17.5
  INT5 w0.102: v1(47.5,-41.071) 47.75,-40.821 47.875,-40.696 53.625,-40.696 53.875,-40.946 54.125,-40.946 54.375,-40.696 54.625,-40.696 54.875,-40.946 58.125,-40.946 58.375,-40.696 60,-40.696 60.75,-39.946 63.625,-39.946 v1(64,-39.571)
MEM4_9: U1.H21 U6.D6 | length 21.1
  INT4 w0.102: v1(45.5,-37.071) 46.125,-37.696 51.5,-37.696 51.75,-37.946 52.125,-37.946 52.375,-37.696 53.5,-37.696 53.75,-37.946 55.125,-37.946 55.375,-37.696 55.625,-37.696 55.875,-37.946 56.875,-37.946 60.875,-41.946 63.625,-41.946 v1(64,-41.571)
MEM4_10: U1.H22 U6.C6 | length 21
  INT4 w0.102: v1(46.5,-37.071) 46.875,-37.446 51.5,-37.446 51.75,-37.196 52.125,-37.196 52.375,-37.446 53.5,-37.446 53.75,-37.196 54.125,-37.196 54.375,-37.446 54.625,-37.446 54.875,-37.196 57.125,-37.196 61.125,-41.196 64.625,-41.196 v1(65,-41.571)
MEM4_11: U1.F24 U6.C8 | length 18.6
  INT4 w0.102: v1(48.5,-39.071) 48.875,-39.446 53.625,-39.446 53.875,-39.196 55.125,-39.196 59.125,-43.196 64.625,-43.196 v1(65,-43.571)
MEM4_12: U1.B21 U6.F9 | length 17.8
  INT5 w0.102: v1(45.5,-43.071) 45.875,-43.446 53.625,-43.446 53.875,-43.196 54.125,-43.196 56.125,-45.196 61.375,-45.196 v1(62,-44.571)
MEM4_13: U1.B20 U6.E10 | length 19.8
  INT5 w0.102: v1(44.5,-43.071) 45.125,-43.696 53.625,-43.696 55.875,-45.946 62.625,-45.946 v1(63,-45.571)
MEM4_14: U1.C24 U6.G11 | length 14.7
  INT4 w0.102: v1(48.5,-42.071) 49.125,-42.696 51.625,-42.696 55.875,-46.946 60.625,-46.946 v1(61,-46.571)
MEM4_15: U1.A23 U6.E13 | length 17.7
  INT4 w0.102: v1(47.5,-44.071) 47.875,-44.446 49.375,-44.446 53.875,-48.946 62.625,-48.946 v1(63,-48.571)
MEM4_16: U1.C21 U6.E5 | length 18.8
  INT5 w0.102: v1(45.5,-42.071) 46.125,-41.446 53.625,-41.446 53.875,-41.196 54.125,-41.196 54.375,-41.446 54.625,-41.446 54.875,-41.196 56.125,-41.196 58.125,-41.196 58.375,-41.446 59.625,-41.446 60.875,-40.196 62.625,-40.196 v1(63,-40.571)
MEM4_17: U1.B22 U6.F6 | length 17.1
  INT5 w0.102: v1(46.5,-43.071) 46.875,-42.696 53.625,-42.696 53.875,-42.946 54.125,-42.946 54.375,-42.696 54.625,-42.696 54.875,-42.946 57.125,-42.946 57.375,-42.696 60.5,-42.696 60.75,-42.946 61.25,-42.946 61.625,-42.571 61.625,-41.946 v1(62,-41.571)
MEM4_18: U1.F23 U6.E8 | length 17.9
  INT4 w0.102: v1(47.5,-39.071) 48.125,-39.696 53.625,-39.696 53.875,-39.946 54.125,-39.946 54.375,-39.696 54.625,-39.696 58.875,-43.946 62.625,-43.946 v1(63,-43.571)
MEM4_19: U1.D25 U6.C10 | length 17.4
  INT4 w0.102: v1(49.5,-41.071) 49.875,-41.446 53.375,-41.446 57.125,-45.196 64.625,-45.196 v1(65,-45.571)
MEM4_20: U1.A24 U6.D13 | length 17.4
  INT4 w0.102: v1(48.5,-44.071) 50,-44.071 54.125,-48.196 63.625,-48.196 v1(64,-48.571)
MEM4_21: U1.A22 U6.F13 | length 17.7
  INT5 w0.102: v1(46.5,-44.071) 46.875,-44.446 53.375,-44.446 56.125,-47.196 61.125,-47.196 62,-48.071 v1(62,-48.571)
MEM4_22: U1.E20 U6.G3 | length 17.6
  INT5 w0.102: v1(44.5,-40.071) 45,-40.071 46.375,-38.696 53.625,-38.696 53.875,-38.946 57.125,-38.946 57.875,-38.196 60.625,-38.196 v1(61,-38.571)
MEM4_23: U1.D21 U6.G4 | length 16.7
  INT5 w0.102: v1(45.5,-41.071) 46.125,-40.446 53.625,-40.446 53.875,-40.196 54.125,-40.196 54.375,-40.446 54.625,-40.446 54.875,-40.196 56.125,-40.196 56.375,-40.446 56.625,-40.446 56.875,-40.196 58.125,-40.196 58.375,-40.446 59.75,-40.446 60.625,-39.571 v1(61,-39.571)
MEM4_24: U1.G24 U6.C7 | length 18.8
  INT4 w0.102: v1(48.5,-38.071) 48.875,-38.446 52.75,-38.446 53,-38.196 55.125,-38.196 55.375,-38.446 55.625,-38.446 55.875,-38.196 56.125,-38.196 60.125,-42.196 64.625,-42.196 v1(65,-42.571)
MEM4_25: U1.E25 U6.C9 | length 17.8
  INT4 w0.102: v1(49.5,-40.071) 49.875,-40.446 53.625,-40.446 53.875,-40.196 54.125,-40.196 58.375,-44.446 58.75,-44.446 59,-44.196 64.625,-44.196 v1(65,-44.571)
MEM4_26: U1.D24 U6.D10 | length 17.7
  INT4 w0.102: v1(48.5,-41.071) 49.125,-41.696 52.625,-41.696 56.875,-45.946 63.625,-45.946 v1(64,-45.571)
MEM4_27: U1.B24 U6.E12 | length 16.7
  INT4 w0.102: v1(48.5,-43.071) 50,-43.071 54.875,-47.946 62.625,-47.946 v1(63,-47.571)
MEM4_28: U1.F22 U6.E3 | length 17.4
  INT5 w0.102: v1(46.5,-39.071) 46.875,-39.446 53.625,-39.446 53.875,-39.196 57.125,-39.196 57.375,-39.446 57.625,-39.446 57.875,-39.196 58.125,-39.196 58.375,-39.446 58.625,-39.446 59.125,-38.946 62.625,-38.946 v1(63,-38.571)
MEM4_29: U1.G21 U6.D2 | length 19.4
  INT5 w0.102: v1(45.5,-38.071) 45.875,-38.446 52.75,-38.446 53,-38.196 55.125,-38.196 55.375,-38.446 55.625,-38.446 55.875,-38.196 57.375,-38.196 57.625,-37.946 60.875,-37.946 61.125,-38.196 63.375,-38.196 v1(64,-37.571)
MEM4_30: U1.G20 U6.F2 | length 18.6
  INT5 w0.102: v1(44.5,-38.071) 45.125,-37.446 51.5,-37.446 51.75,-37.196 52.125,-37.196 52.375,-37.446 53.5,-37.446 54.25,-36.696 61.125,-36.696 v1(62,-37.571)
MEM4_31: U1.F20 U6.E2 | length 20.7
  INT5 w0.102: v1(44.5,-39.071) 45,-38.571 45,-38.071 45.375,-37.696 48.75,-37.696 49,-37.946 52.125,-37.946 52.375,-37.696 52.875,-37.696 53.125,-37.946 54.125,-37.946 54.875,-37.196 58.125,-37.196 58.375,-37.446 58.625,-37.446 58.875,-37.196 61.125,-37.196 61.875,-37.946 62.625,-37.946 v1(63,-37.571)
MEM4_RST: R86.2 U1.A29 U6.K2 U6.L2 | length 12.6
  INT7 w0.102: v1(53,-46.571) 53,-44.571 v1(53.5,-44.071)
  INT3 w0.102: v1(53.5,-44.071) 54,-44.071 57.625,-40.446 57.625,-39.446 57.875,-39.196 57.875,-38.946 57.625,-38.696 57.625,-38.446 58,-38.071 v1(58,-37.571) v1(57,-37.571)
MEM5_0: MEM5_0.1 U1.G17 U7.C3 | length 39.6
  INT6 w0.102: v1(41.5,-38.071) 41,-38.071 38.875,-35.946 38.875,-32.946 38.625,-32.696 38.625,-32.446 38.875,-32.196 38.875,-31.946 38.625,-31.696 38.625,-31.446 38.875,-31.196 38.875,-30.946 38.625,-30.696 38.625,-30.446 38.875,-30.196 38.875,-29.946 38.625,-29.696 38.625,-29.446 38.875,-29.196 38.875,-28.946 38.625,-28.696 38.625,-28.446 38.875,-28.196 38.875,-27.946 38.625,-27.696 38.625,-27.446 38.875,-27.196 38.875,-26.946 38.625,-26.696 38.625,-26.446 41.875,-23.196 42.125,-23.196 42.375,-23.446 42.625,-23.446 42.875,-23.196 43.125,-23.196 43.375,-23.446 43.625,-23.446 43.875,-23.196 44.125,-23.196 44.375,-23.446 44.625,-23.446 44.875,-23.196 45.125,-23.196 45.375,-23.446 45.625,-23.446 46.5,-22.571 v1(47,-22.571)
  INT8 w0.102: v1(41.5,-38.071) 41.875,-38.446 41.875,-44.321 43.5,-45.946 43.5,-50.996 MEM5_0.1@44,-51.496
MEM5_1: U1.E17 U7.D5 | length 21
  INT6 w0.102: v1(41.5,-40.071) 42,-40.071 42.875,-39.196 42.875,-35.946 40.875,-33.946 40.875,-31.946 40.625,-31.696 40.625,-31.446 40.875,-31.196 40.875,-30.946 40.625,-30.696 40.625,-30.446 40.875,-30.196 40.875,-29.946 40.625,-29.696 40.625,-29.446 40.875,-29.196 40.875,-28.196 44.375,-24.696 44.625,-24.696 44.875,-24.946 45.125,-24.946 45.5,-24.571 v1(46,-24.571)
MEM5_2: U1.E18 U7.C5 | length 20.2
  INT6 w0.102: v1(42.5,-40.071) 42.875,-39.696 43.375,-39.696 43.875,-39.196 43.875,-34.946 41.625,-32.696 41.625,-32.446 41.875,-32.196 41.875,-30.946 41.625,-30.696 41.625,-30.446 41.875,-30.196 41.875,-29.946 41.625,-29.696 41.625,-29.446 46.5,-24.571 v1(47,-24.571)
MEM5_3: U1.C14 U7.E7 | length 22.9
  INT4 w0.102: v1(38.5,-42.071) 38.875,-41.696 38.875,-32.946 38.625,-32.696 38.625,-32.446 38.875,-32.196 38.875,-31.946 38.625,-31.696 38.625,-31.446 38.875,-31.196 38.875,-30.946 38.625,-30.696 38.625,-30.446 38.875,-30.196 38.875,-29.946 38.625,-29.696 38.625,-29.446 38.875,-29.196 38.875,-28.946 38.625,-28.696 38.625,-28.446 38.875,-28.196 38.875,-27.946 38.625,-27.696 38.625,-27.446 39.375,-26.696 43.625,-26.696 43.875,-26.946 44.125,-26.946 44.375,-26.696 44.875,-26.696 v1(45,-26.571)
MEM5_4: U1.C16 U7.D9 | length 18.9
  INT4 w0.102: v1(40.5,-42.071) 41.125,-41.446 41.125,-31.946 41.375,-31.696 41.375,-31.446 41.125,-31.196 41.125,-30.946 41.375,-30.696 41.375,-30.446 41.125,-30.196 41.125,-29.946 41.875,-29.196 42.125,-29.196 42.375,-29.446 42.625,-29.446 42.875,-29.196 43.125,-29.196 43.375,-29.446 43.625,-29.446 43.875,-29.196 44.125,-29.196 44.375,-29.446 44.625,-29.446 45.375,-28.696 45.875,-28.696 v1(46,-28.571)
MEM5_5: U1.C19 U7.D11 | length 13.9
  INT4 w0.102: v1(43.5,-42.071) 43.125,-41.696 43.125,-32.946 43.375,-32.696 43.375,-32.446 43.125,-32.196 43.125,-31.946 43.875,-31.196 45.375,-31.196 v1(46,-30.571)
MEM5_6: U1.B19 U7.C12 | length 14
  INT4 w0.102: v1(43.5,-43.071) 44.125,-42.446 44.125,-34.946 44.625,-34.446 44.625,-32.446 44.875,-32.196 45.125,-32.196 45.375,-32.446 45.625,-32.446 45.875,-32.196 46.375,-32.196 v1(47,-31.571)
MEM5_7: U1.A15 U7.G12 | length 14.3
  INT5 w0.102: v1(39.5,-44.071) 39.875,-43.696 39.875,-36.196 43.375,-32.696 43.375,-32.446 43.125,-32.196 43.125,-31.696 v1(43,-31.571)
MEM5_8: U1.E16 U7.D4 | length 23.2
  INT6 w0.102: v1(40.5,-40.071) 41,-40.071 41.875,-39.196 41.875,-36.946 39.875,-34.946 39.875,-32.946 39.625,-32.696 39.625,-32.446 39.875,-32.196 39.875,-30.946 39.625,-30.696 39.625,-30.446 39.875,-30.196 39.875,-29.946 39.625,-29.696 39.625,-29.446 39.875,-29.196 39.875,-27.196 43.375,-23.696 43.625,-23.696 43.875,-23.946 44.125,-23.946 44.375,-23.696 44.625,-23.696 44.875,-23.946 45.125,-23.946 45.375,-23.696 45.875,-23.696 v1(46,-23.571)
MEM5_9: U1.D14 U7.D6 | length 25.6
  INT4 w0.102: v1(38.5,-41.071) 37.875,-40.446 37.875,-32.946 37.625,-32.696 37.625,-32.446 37.875,-32.196 37.875,-31.946 37.625,-31.696 37.625,-31.446 37.875,-31.196 37.875,-30.946 37.625,-30.696 37.625,-30.446 37.875,-30.196 37.875,-29.946 37.625,-29.696 37.625,-29.446 37.875,-29.196 37.875,-28.946 37.625,-28.696 37.625,-28.446 37.875,-28.196 37.875,-27.946 37.625,-27.696 37.625,-27.446 37.875,-27.196 37.875,-26.946 37.625,-26.696 37.625,-26.446 38.375,-25.696 38.625,-25.696 38.875,-25.946 39.125,-25.946 39.375,-25.696 43.625,-25.696 43.875,-25.946 44.125,-25.946 44.375,-25.696 44.625,-25.696 44.875,-25.946 45.125,-25.946 45.375,-25.696 45.875,-25.696 v1(46,-25.571)
MEM5_10: U1.F14 U7.C6 | length 23.6
  INT4 w0.102: v1(38.5,-39.071) 38.125,-38.696 38.125,-32.946 38.375,-32.696 38.375,-32.446 38.125,-32.196 38.125,-31.946 38.375,-31.696 38.375,-31.446 38.125,-31.196 38.125,-30.946 38.375,-30.696 38.375,-30.446 38.125,-30.196 38.125,-29.946 38.375,-29.696 38.375,-29.446 38.125,-29.196 38.125,-28.946 38.375,-28.696 38.375,-28.446 38.125,-28.196 38.125,-27.946 38.375,-27.696 38.375,-27.446 38.125,-27.196 38.125,-26.946 38.875,-26.196 39.125,-26.196 39.375,-26.446 43.625,-26.446 43.875,-26.196 44.125,-26.196 44.375,-26.446 44.625,-26.446 44.875,-26.196 45.125,-26.196 45.375,-26.446 45.625,-26.446 46.375,-25.696 46.875,-25.696 v1(47,-25.571)
MEM5_11: U1.D16 U7.C8 | length 20.8
  INT4 w0.102: v1(40.5,-41.071) 40.125,-40.696 40.125,-32.946 40.375,-32.696 40.375,-32.446 40.125,-32.196 40.125,-30.946 40.375,-30.696 40.375,-30.446 40.125,-30.196 40.125,-29.946 40.375,-29.696 40.375,-29.446 40.125,-29.196 40.125,-28.946 40.625,-28.446 43.625,-28.446 43.875,-28.196 44.125,-28.196 44.375,-28.446 44.625,-28.446 44.875,-28.196 45.125,-28.196 45.375,-28.446 45.625,-28.446 46.5,-27.571 v1(47,-27.571)
MEM5_12: U1.B15 U7.F9 | length 18.4
  INT4 w0.102: v1(39.5,-43.071) 39.5,-42.571 40.875,-41.196 40.875,-31.946 40.625,-31.696 40.625,-31.446 40.875,-31.196 40.875,-30.946 40.625,-30.696 40.625,-30.446 40.875,-30.196 40.875,-29.946 40.625,-29.696 40.625,-29.446 41.375,-28.696 43.875,-28.696 v1(44,-28.571)
MEM5_13: U1.D18 U7.E10 | length 15.6
  INT6 w0.102: v1(42.5,-41.071) 43.125,-40.446 43.625,-40.446 44.125,-39.946 44.125,-34.196 42.125,-32.196 42.125,-30.946 43.375,-29.696 43.625,-29.696 43.875,-29.946 44.125,-29.946 44.5,-29.571 v1(45,-29.571)
MEM5_14: U1.D19 U7.G11 | length 12.4
  INT6 w0.102: v1(43,-30.571) 43,-31.071 42.625,-31.446 42.625,-31.696 44.625,-33.696 44.875,-33.946 44.875,-40.196 44.375,-40.696 43.875,-40.696 v1(43.5,-41.071)
MEM5_15: U1.A18 U7.E13 | length 13.5
  INT4 w0.102: v1(42.5,-44.071) 43.125,-43.446 44.75,-43.446 44.875,-43.321 44.875,-32.696 v1(45,-32.571)
MEM5_16: U1.F18 U7.E5 | length 19.3
  INT6 w0.102: v1(42.5,-39.071) 42.125,-38.696 42.125,-36.196 40.125,-34.196 40.125,-32.946 40.375,-32.696 40.375,-32.446 40.125,-32.196 40.125,-30.946 40.375,-30.696 40.375,-30.446 40.125,-30.196 40.125,-29.946 40.375,-29.696 40.375,-29.446 40.125,-29.196 40.125,-27.946 43.875,-24.196 44.125,-24.196 44.375,-24.446 44.875,-24.446 v1(45,-24.571)
MEM5_17: U1.F19 U7.F6 | length 16.3
  INT6 w0.102: v1(43.5,-39.071) 43.125,-38.696 43.125,-35.196 41.125,-33.196 41.125,-31.946 41.375,-31.696 41.375,-31.446 41.125,-31.196 41.125,-30.946 41.375,-30.696 41.375,-30.446 41.125,-30.196 41.125,-29.946 41.375,-29.696 41.375,-29.446 41.125,-29.196 41.125,-28.946 44,-26.071 v1(44,-25.571)
MEM5_18: U1.B14 U7.E8 | length 21.7
  INT4 w0.102: v1(38.5,-43.071) 38.5,-42.571 39.875,-41.196 39.875,-32.946 39.625,-32.696 39.625,-32.446 39.875,-32.196 39.875,-30.946 39.625,-30.696 39.625,-30.446 39.875,-30.196 39.875,-29.946 39.625,-29.696 39.625,-29.446 39.875,-29.196 39.875,-28.196 40.375,-27.696 43.625,-27.696 43.875,-27.946 44.125,-27.946 44.375,-27.696 44.875,-27.696 v1(45,-27.571)
MEM5_19: U1.B16 U7.C10 | length 19.2
  INT4 w0.102: v1(40.5,-43.071) 41.125,-42.446 42.75,-42.446 42.875,-42.321 42.875,-32.946 42.625,-32.696 42.625,-32.446 42.875,-32.196 42.875,-31.946 42.625,-31.696 42.625,-31.446 43.375,-30.696 43.625,-30.696 43.875,-30.946 45.125,-30.946 45.875,-30.196 46.375,-30.196 v1(47,-29.571)
MEM5_20: U1.A19 U7.D13 | length 13.1
  INT4 w0.102: v1(43.5,-44.071) 43.875,-43.696 44.875,-43.696 45.125,-43.446 45.125,-35.821 46,-34.946 v1(46,-32.571)
MEM5_21: U1.A14 U7.F13 | length 15
  INT5 w0.102: v1(38.5,-44.071) 38.875,-44.446 39.75,-44.446 40.125,-44.071 40.125,-36.946 44,-33.071 v1(44,-32.571)
MEM5_22: U1.G15 U7.G3 | length 22
  INT6 w0.102: v1(39.5,-38.071) 39,-38.071 37.875,-36.946 37.875,-32.946 37.625,-32.696 37.625,-32.446 37.875,-32.196 37.875,-31.946 37.625,-31.696 37.625,-31.446 37.875,-31.196 37.875,-30.946 37.625,-30.696 37.625,-30.446 37.875,-30.196 37.875,-29.946 37.625,-29.696 37.625,-29.446 37.875,-29.196 37.875,-28.946 37.625,-28.696 37.625,-28.446 37.875,-28.196 37.875,-27.946 37.625,-27.696 37.625,-27.446 37.875,-27.196 37.875,-26.946 37.625,-26.696 37.625,-26.446 37.875,-26.196 37.875,-25.946 37.625,-25.696 37.625,-25.446 40.875,-22.196 41.125,-22.196 41.375,-22.446 42.875,-22.446 v1(43,-22.571)
MEM5_23: U1.H17 U7.G4 | length 17.9
  INT6 w0.102: v1(41.5,-37.071) 41,-37.071 39.125,-35.196 39.125,-32.946 39.375,-32.696 39.375,-32.446 39.125,-32.196 39.125,-31.946 39.375,-31.696 39.375,-31.446 39.125,-31.196 39.125,-30.946 39.375,-30.696 39.375,-30.446 39.125,-30.196 39.125,-29.946 39.375,-29.696 39.375,-29.446 39.125,-29.196 39.125,-28.946 39.375,-28.696 39.375,-28.446 39.125,-28.196 39.125,-27.946 39.375,-27.696 39.375,-27.446 39.125,-27.196 39.125,-26.946 42.375,-23.696 42.875,-23.696 v1(43,-23.571)
MEM5_24: U1.D15 U7.C7 | length 23.2
  INT4 w0.102: v1(39.5,-41.071) 39.125,-40.696 39.125,-32.946 39.375,-32.696 39.375,-32.446 39.125,-32.196 39.125,-31.946 39.375,-31.696 39.375,-31.446 39.125,-31.196 39.125,-30.946 39.375,-30.696 39.375,-30.446 39.125,-30.196 39.125,-29.946 39.375,-29.696 39.375,-29.446 39.125,-29.196 39.125,-28.946 39.375,-28.696 39.375,-28.446 39.125,-28.196 39.125,-27.946 39.625,-27.446 43.625,-27.446 43.875,-27.196 44.125,-27.196 44.375,-27.446 44.625,-27.446 45.375,-26.696 45.625,-26.696 45.875,-26.946 46.625,-26.946 v1(47,-26.571)
MEM5_25: U1.C17 U7.C9 | length 18.9
  INT4 w0.102: v1(41.5,-42.071) 41.875,-41.696 41.875,-32.946 41.625,-32.696 41.625,-32.446 41.875,-32.196 41.875,-30.946 41.625,-30.696 41.625,-30.446 42.375,-29.696 42.625,-29.696 42.875,-29.946 43.125,-29.946 43.375,-29.696 43.625,-29.696 43.875,-29.946 44.125,-29.946 44.375,-29.696 44.625,-29.696 44.875,-29.946 45.125,-29.946 45.625,-29.446 46.5,-28.571 v1(47,-28.571)
MEM5_26: U1.C18 U7.D10 | length 16.3
  INT4 w0.102: v1(42.5,-42.071) 42.125,-41.696 42.125,-32.946 42.375,-32.696 42.375,-32.446 42.125,-32.196 42.125,-30.946 42.875,-30.196 43.125,-30.196 43.375,-30.446 43.625,-30.446 43.875,-30.196 44.125,-30.196 44.375,-30.446 44.625,-30.446 44.875,-30.196 45.375,-30.196 v1(46,-29.571)
MEM5_27: U1.B17 U7.E12 | length 14.4
  INT4 w0.102: v1(41.5,-43.071) 41.875,-42.696 43.5,-42.696 43.875,-42.321 43.875,-34.821 44.375,-34.321 44.375,-32.446 44.125,-32.196 44.125,-31.946 44.5,-31.571 v1(45,-31.571)
MEM5_28: U1.F17 U7.E3 | length 25
  INT6 w0.102: v1(41.5,-39.071) 41,-39.071 38.125,-36.196 38.125,-32.946 38.375,-32.696 38.375,-32.446 38.125,-32.196 38.125,-31.946 38.375,-31.696 38.375,-31.446 38.125,-31.196 38.125,-30.946 38.375,-30.696 38.375,-30.446 38.125,-30.196 38.125,-29.946 38.375,-29.696 38.375,-29.446 38.125,-29.196 38.125,-28.946 38.375,-28.696 38.375,-28.446 38.125,-28.196 38.125,-27.946 38.375,-27.696 38.375,-27.446 38.125,-27.196 38.125,-26.946 38.375,-26.696 38.375,-26.446 38.125,-26.196 38.125,-25.946 41.375,-22.696 42.625,-22.696 42.875,-22.946 43.125,-22.946 43.375,-22.696 43.625,-22.696 43.875,-22.946 44.125,-22.946 44.375,-22.696 44.875,-22.696 v1(45,-22.571)
MEM5_29: U1.G14 U7.D2 | length 27.9
  INT6 w0.102: v1(38.5,-38.071) 38,-38.071 37.125,-37.196 37.125,-32.946 37.375,-32.696 37.375,-32.446 37.125,-32.196 37.125,-31.946 37.375,-31.696 37.375,-31.446 37.125,-31.196 37.125,-30.946 37.375,-30.696 37.375,-30.446 37.125,-30.196 37.125,-29.946 37.375,-29.696 37.375,-29.446 37.125,-29.196 37.125,-28.946 37.375,-28.696 37.375,-28.446 37.125,-28.196 37.125,-27.946 37.375,-27.696 37.375,-27.446 37.125,-27.196 37.125,-26.946 37.375,-26.696 37.375,-26.446 37.125,-26.196 37.125,-25.946 37.375,-25.696 37.375,-25.446 37.125,-25.196 37.125,-24.946 38.375,-23.696 38.375,-23.446 38.125,-23.196 38.125,-22.946 39.375,-21.696 39.625,-21.696 39.875,-21.946 40.125,-21.946 40.349,-21.722 40.354,-21.718 40.646,-21.718 40.776,-21.848 40.875,-21.946 41.125,-21.946 41.375,-21.696 42.625,-21.696 43.375,-22.446 43.625,-22.446 43.875,-22.196 44.125,-22.196 44.375,-22.446 44.625,-22.446 45.5,-21.571 v1(46,-21.571)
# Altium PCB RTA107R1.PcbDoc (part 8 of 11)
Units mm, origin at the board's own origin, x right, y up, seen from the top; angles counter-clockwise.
Board outline 96.01 x 65.66 mm, 22 copper layers (Top Layer, GND1, INT1, PWR1-(VCCIO_MRAM), INT2, PWR2-(VCCINT), INT3, PWR3_(12V_MGTAVCC), INT4, GND2-(DGND_SGND), PWR4_(MGTAVTT_VCCBRAM,VCCAUX), PWR5-(VCC_12V), GND3-(DGND_GND), INT5, GND4, INT6, PWR6_(VCCO), INT7, GND5, INT8, GND6, Bottom Layer), stack 2.833 mm thick; 614 components, 659 nets, 4037 pads, 3511 vias.

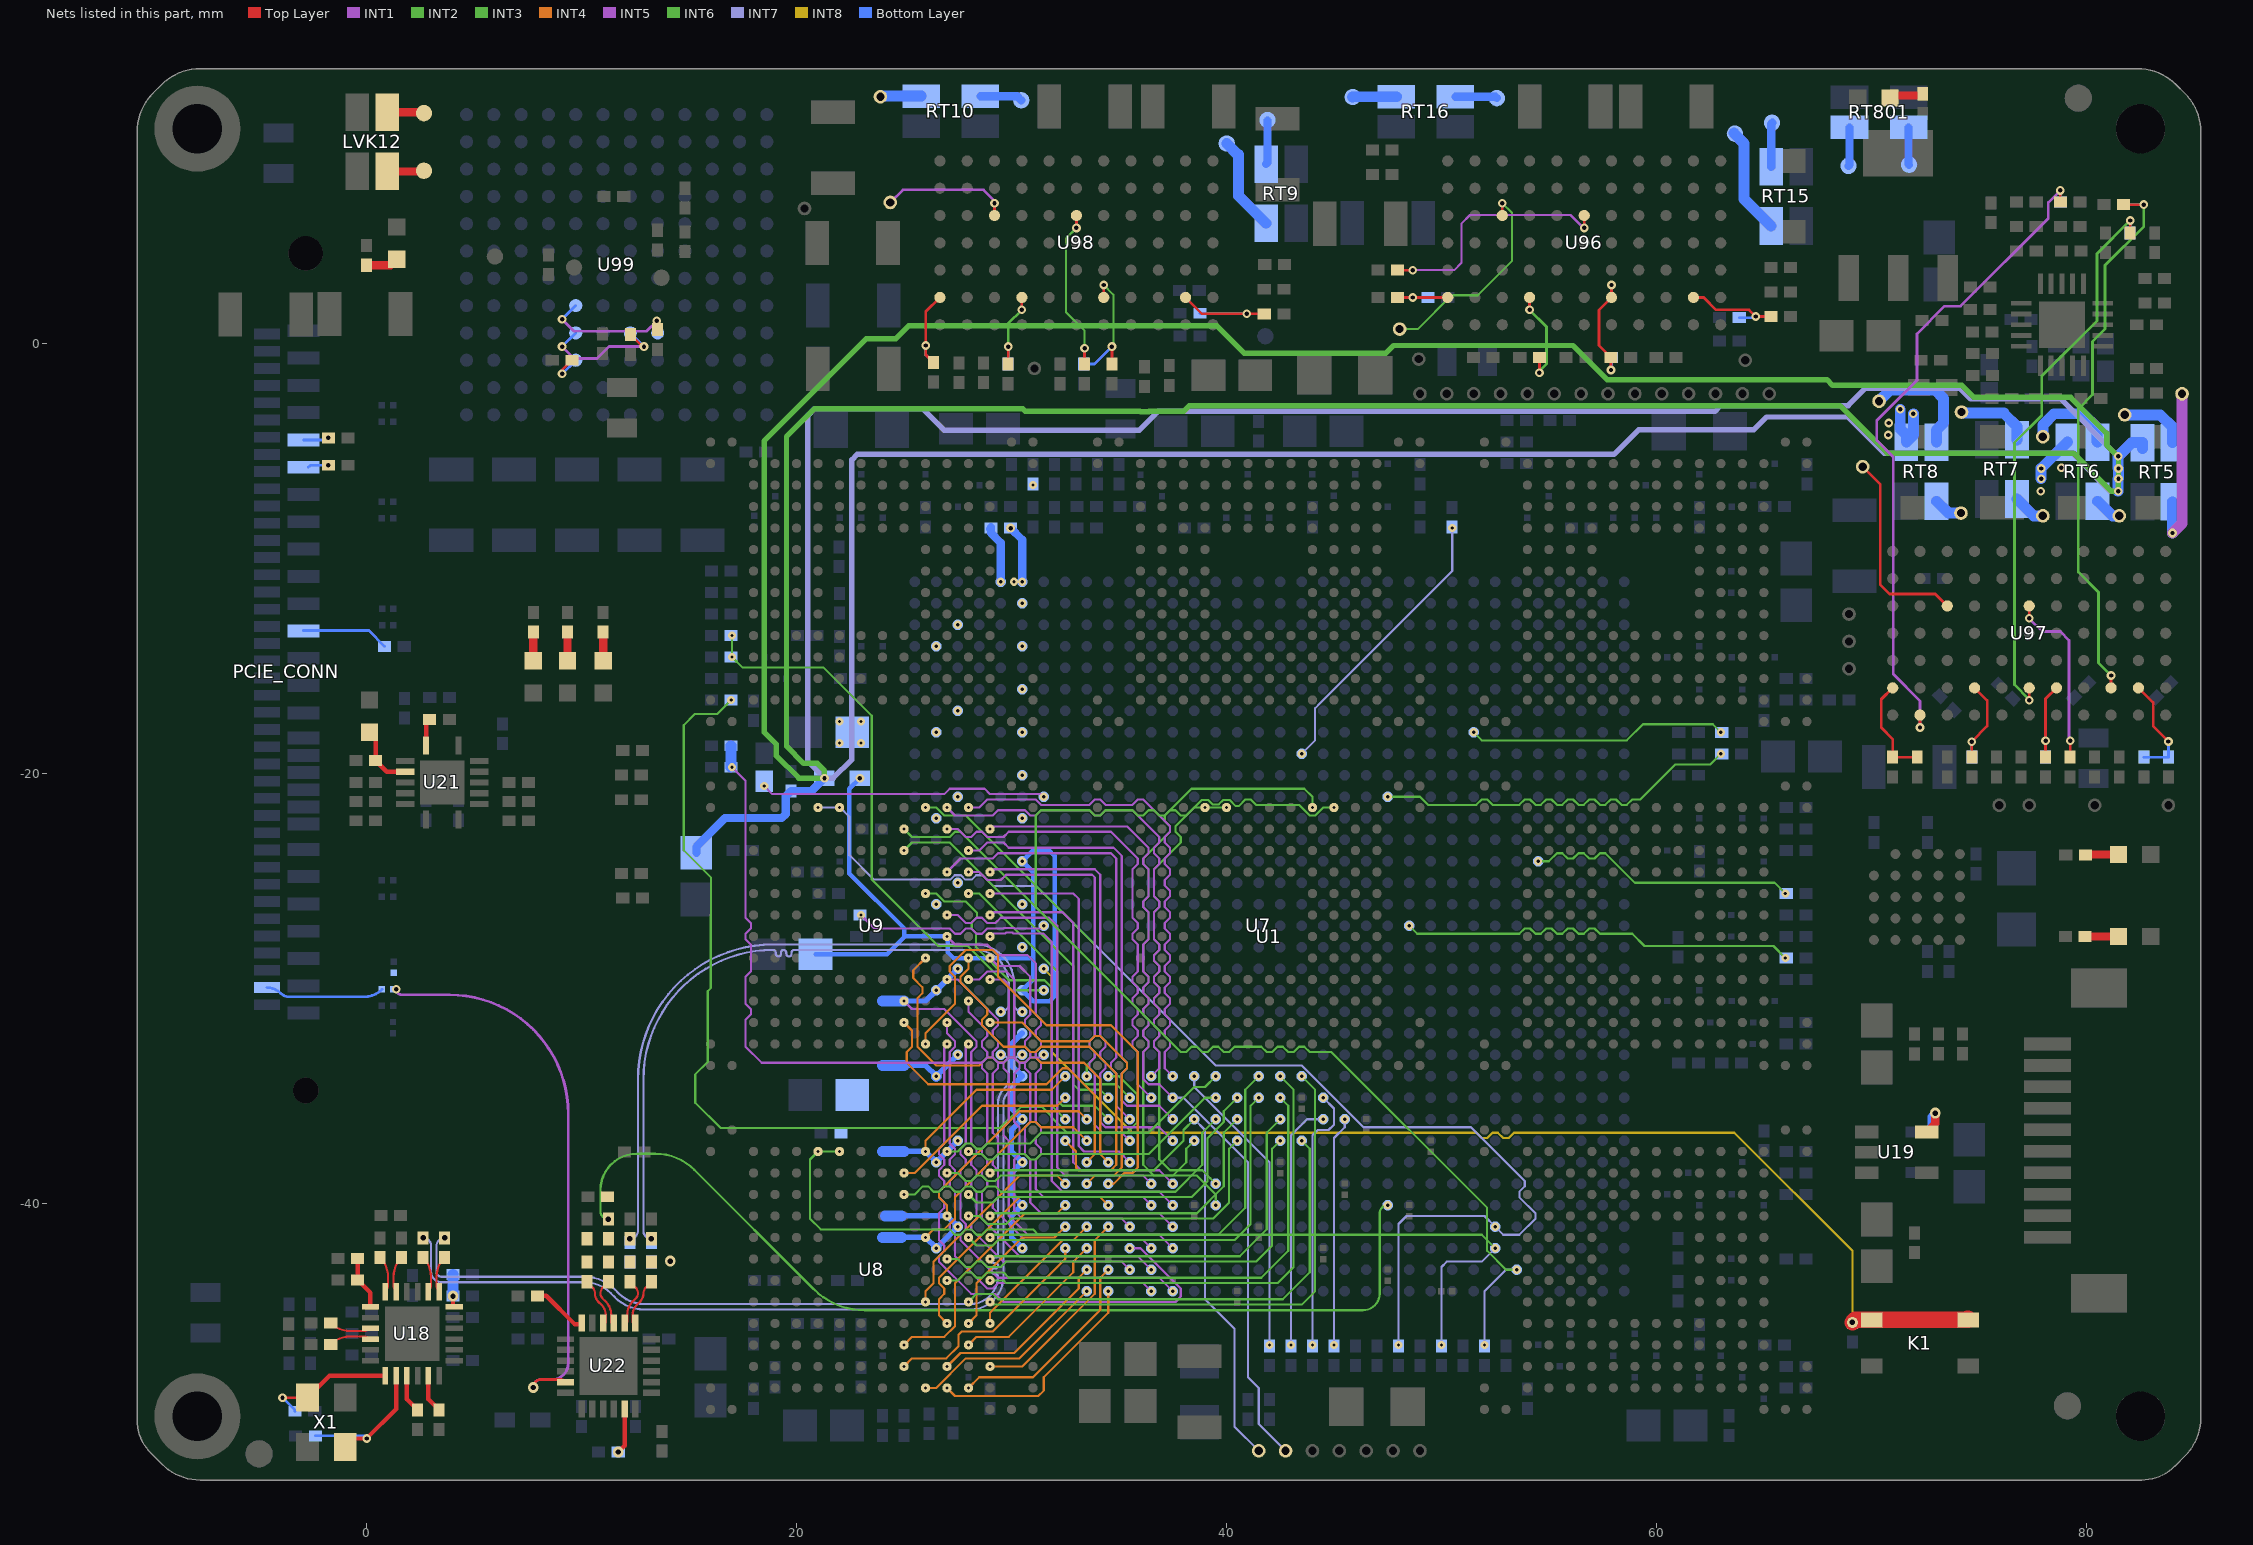
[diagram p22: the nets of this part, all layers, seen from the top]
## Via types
v1: diameter 0.381, hole 0.152, Top Layer to Bottom Layer, tented both sides, 2009 vias
v2: diameter 0.508, hole 0.254, Top Layer to Bottom Layer, tented both sides, 467 vias
v3: diameter 0.406, hole 0.203, Top Layer to Bottom Layer, 458 vias
v4: diameter 0.508, hole 0.254, Top Layer to Bottom Layer, 239 vias
v5: diameter 0.406, hole 0.203, Top Layer to Bottom Layer, tented both sides, 181 vias
v6: diameter 0.381, hole 0.152, Top Layer to GND4, tented both sides, 147 vias
v7: diameter 0.406, hole 0.203, Top Layer to GND4, tented both sides, 10 vias

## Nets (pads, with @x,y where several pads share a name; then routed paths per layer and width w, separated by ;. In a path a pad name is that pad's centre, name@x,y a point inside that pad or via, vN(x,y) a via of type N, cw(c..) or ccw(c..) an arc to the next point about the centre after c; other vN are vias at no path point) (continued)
MEM5_30: U1.E15 U7.F2 | length 30.6
  INT6 w0.102: v1(39.5,-40.071) 39.5,-39.571 38.625,-38.696 36.625,-38.696 36.125,-38.196 36.125,-32.946 36.375,-32.696 36.375,-32.446 36.125,-32.196 36.125,-31.946 36.375,-31.696 36.375,-31.446 36.125,-31.196 36.125,-30.946 36.375,-30.696 36.375,-30.446 36.125,-30.196 36.125,-29.946 36.375,-29.696 36.375,-29.446 36.125,-29.196 36.125,-27.946 36.375,-27.696 36.375,-26.446 36.125,-26.196 36.125,-25.946 36.375,-25.696 36.375,-24.446 36.125,-24.196 36.125,-23.946 37.375,-22.696 37.375,-22.446 37.125,-22.196 37.125,-21.946 38.375,-20.696 43.625,-20.696 44,-21.071 v1(44,-21.571)
MEM5_31: U1.F15 U7.E2 | length 29.3
  INT6 w0.102: 38.625,-21.447 38.854,-21.218 39.146,-21.218 39.353,-21.425 39.647,-21.425 39.854,-21.218 40.146,-21.218 40.433,-21.505 40.566,-21.505 40.875,-21.196 41.125,-21.196 41.375,-21.446 43.375,-21.446 43.875,-21.946 44.125,-21.946 44.5,-21.571 v1(45,-21.571) ; 38.625,-21.446 37.625,-22.446 37.625,-22.696 37.875,-22.946 37.875,-23.196 36.625,-24.446 36.625,-25.696 36.875,-25.946 36.875,-26.196 36.625,-26.446 36.625,-27.696 36.875,-27.946 36.875,-28.196 36.625,-28.446 36.625,-28.696 36.875,-28.946 36.875,-29.196 36.625,-29.446 36.625,-29.696 36.875,-29.946 36.875,-30.196 36.625,-30.446 36.625,-30.696 36.875,-30.946 36.875,-31.196 36.625,-31.446 36.625,-31.696 36.875,-31.946 36.875,-32.196 36.625,-32.446 36.625,-32.696 36.875,-32.946 36.875,-37.946 37.375,-38.446 38.875,-38.446 39.25,-38.821 v1(39.5,-39.071)
MEM5_RST: R85.2 U1.B29 U7.K2 U7.L2 | length 50.1
  INT7 w0.102: v1(52,-46.571) 52,-44.071 53,-43.071 v1(53.5,-43.071)
  INT3 w0.102: v1(40,-21.571) v1(39,-21.571) 38.5,-21.571 38.125,-21.946 37.875,-21.946 37.625,-21.696 37.375,-21.696 37.125,-21.946 36.875,-21.946 36.625,-21.696 36.375,-21.696 36.125,-21.946 35.875,-21.946 35.625,-21.696 34.375,-21.696 34.125,-21.946 33.875,-21.946 33.625,-21.696 31.375,-21.696 31.125,-21.946 31.125,-26.196 37.875,-32.946 38.125,-32.946 38.375,-32.696 38.625,-32.696 38.875,-32.946 39.125,-32.946 39.375,-32.696 39.625,-32.696 39.875,-32.946 40.125,-32.946 40.375,-32.696 41.625,-32.696 41.875,-32.946 42.125,-32.946 42.375,-32.696 42.625,-32.696 42.875,-32.946 43.125,-32.946 43.375,-32.696 43.625,-32.696 43.875,-32.946 44.875,-32.946 52.125,-40.196 52.125,-42.196 53,-43.071 v1(53.5,-43.071)
MEM6_0: MEM6_0.1 U1.J14 U8.C3 | length 27.5
  INT7 w0.102: v1(38.5,-36.071) 39,-36.571 39,-44.446 40.375,-45.821 40.375,-50.371 MEM6_0.1@41.5,-51.496
  INT3 w0.102: v6(29,-38.571) 29.125,-38.446 36.625,-38.446 38,-37.071 38,-36.571 v1(38.5,-36.071)
MEM6_1: U1.H16 U8.D5 | length 15.7
  INT3 w0.102: v1(28,-40.571) 28.5,-40.571 28.875,-40.946 29.75,-40.946 30,-40.696 39.375,-40.696 40.125,-39.946 40.125,-37.446 v1(40.5,-37.071)
MEM6_2: U1.J16 U8.C5 | length 14.8
  INT3 w0.102: v6(29,-40.571) 29.125,-40.446 38.625,-40.446 39.875,-39.196 39.875,-36.696 v1(40.5,-36.071)
MEM6_3: U1.H18 U8.E7 | length 20.9
  INT3 w0.102: v1(27,-42.571) 27.5,-42.571 27.875,-42.946 28.125,-42.946 28.375,-42.696 28.625,-42.696 28.875,-42.946 29.5,-42.946 29.75,-42.696 41.375,-42.696 42.125,-41.946 42.125,-37.446 v1(42.5,-37.071)
MEM6_4: U1.H19 U8.D9 | length 22.9
  INT3 w0.102: v6(28,-44.571) 28.375,-44.196 29.125,-44.196 29.375,-44.446 42.625,-44.446 43.875,-43.196 43.875,-37.446 v1(43.5,-37.071)
MEM6_5: U1.C9 U8.D11 | length 7.7
  INT4 w0.102: v1(28,-46.571) 28.375,-46.196 29.875,-46.196 32.875,-43.196 32.875,-42.696 v1(33.5,-42.071)
MEM6_6: U1.D10 U8.C12 | length 9.7
  INT4 w0.102: v1(29,-47.571) 30.5,-47.571 33.875,-44.196 33.875,-41.696 v1(34.5,-41.071)
MEM6_7: U1.C8 U8.G12 | length 10.4
  INT4 w0.102: v1(25,-47.571) 25.375,-47.196 26.963,-47.196 27.534,-46.626 27.534,-46.101 27.689,-45.946 29.125,-45.946 32.5,-42.571 v1(32.5,-42.071)
MEM6_8: U1.K16 U8.D4 | length 16.1
  INT3 w0.102: v1(28,-39.571) 28.375,-39.946 29.125,-39.946 29.375,-39.696 38.375,-39.696 39.125,-38.946 39.125,-36.946 39.875,-36.196 39.875,-35.696 v1(40.5,-35.071)
MEM6_9: U1.K17 U8.D6 | length 19.7
  INT3 w0.102: v1(28,-41.571) 28.375,-41.946 29.125,-41.946 29.375,-41.696 40.375,-41.696 41.125,-40.946 41.125,-35.446 v1(41.5,-35.071)
MEM6_10: U1.L17 U8.C6 | length 18.8
  INT3 w0.102: v6(29,-41.571) 29.125,-41.446 39.625,-41.446 40.875,-40.196 40.875,-34.696 v1(41.5,-34.071)
MEM6_11: U1.L18 U8.C8 | length 23.6
  INT3 w0.102: v6(29,-43.571) 29.625,-43.571 29.75,-43.696 42.375,-43.696 43.125,-42.946 43.125,-34.696 v1(42.5,-34.071)
MEM6_12: U1.F8 U8.F9 | length 10
  INT4 w0.102: v6(26,-44.571) 26,-44.071 26.375,-43.696 26.375,-42.696 30.375,-38.696 32.125,-38.696 v1(32.5,-39.071)
MEM6_13: U1.E10 U8.E10 | length 12.1
  INT4 w0.102: v6(27,-45.571) 26.625,-45.196 26.625,-44.446 26.875,-44.196 26.875,-43.946 26.625,-43.696 26.625,-43.446 30.375,-39.696 34.125,-39.696 v1(34.5,-40.071)
MEM6_14: U1.E8 U8.G11 | length 11.4
  INT4 w0.102: v1(25,-46.571) 25.375,-46.196 26.875,-46.196 27.375,-45.696 27.375,-43.696 30.625,-40.446 32.125,-40.446 v1(32.5,-40.071)
MEM6_15: U1.A10 U8.E13 | length 10.6
  INT4 w0.102: v1(27,-48.571) 27.375,-48.946 31.25,-48.946 31.5,-48.696 31.5,-48.071 34.5,-45.071 v1(34.5,-44.071)
MEM6_16: U1.J9 U8.E5 | length 9.9
  INT4 w0.102: v6(27,-40.571) 27,-40.071 26.625,-39.696 26.625,-39.446 30.375,-35.696 33.125,-35.696 v1(33.5,-36.071)
MEM6_17: U1.H9 U8.F6 | length 10.7
  INT4 w0.102: v6(26,-41.571) 26.375,-41.196 26.875,-41.196 27.375,-40.696 27.375,-39.696 30.875,-36.196 31.125,-36.196 31.375,-36.446 32.875,-36.446 v1(33.5,-37.071)
MEM6_18: U1.K18 U8.E8 | length 24.1
  INT3 w0.102: v1(27,-43.571) 27.5,-43.571 27.875,-43.196 28.125,-43.196 28.375,-43.446 28.625,-43.446 28.875,-43.196 29.625,-43.196 29.875,-43.446 41.625,-43.446 42.875,-42.196 42.875,-35.446 v1(42.5,-35.071)
MEM6_19: U1.D9 U8.C10 | length 6.7
  INT4 w0.102: v6(29,-45.571) 29,-45.071 32.375,-41.696 32.875,-41.696 v1(33.5,-41.071)
MEM6_20: U1.B10 U8.D13 | length 9.7
  INT4 w0.102: v1(28,-48.571) 28.5,-48.071 31,-48.071 34.125,-44.946 34.125,-43.446 v1(34.5,-43.071)
MEM6_21: U1.A9 U8.F13 | length 9.4
  INT4 w0.102: v6(26,-48.571) 26.5,-48.571 27.875,-47.196 30.375,-47.196 v1(33.5,-44.071)
MEM6_22: U1.K8 U8.G3 | length 8.9
  INT4 w0.102: v6(25,-38.571) 25.5,-38.571 28.625,-35.446 32.125,-35.446 v1(32.5,-35.071)
MEM6_23: U1.J15 U8.G4 | length 17.7
  INT3 w0.102: v6(25,-39.571) 25.5,-39.571 25.875,-39.196 26.125,-39.196 26.375,-39.446 26.625,-39.446 26.875,-39.196 27.125,-39.196 27.375,-39.446 27.625,-39.446 27.875,-39.196 28.125,-39.196 28.375,-39.446 28.625,-39.446 28.875,-39.196 29.25,-39.196 29.5,-39.446 37.625,-39.446 38.875,-38.196 38.875,-36.696 v1(39.5,-36.071)
MEM6_24: U1.J18 U8.C7 | length 18.8
  INT3 w0.102: v6(29,-42.571) 29.125,-42.446 40.625,-42.446 41.875,-41.196 41.875,-36.696 v1(42.5,-36.071)
MEM6_25: U1.L19 U8.C9 | length 25.7
  INT3 w0.102: v6(29,-44.571) 29.125,-44.696 43.5,-44.696 44.125,-44.071 44.125,-34.696 v1(43.5,-34.071)
MEM6_26: U1.D8 U8.D10 | length 7.2
  INT4 w0.102: v6(28,-45.571) 28.375,-45.196 28.375,-43.696 30.5,-41.571 32,-41.571 v1(32.5,-41.071)
MEM6_27: U1.B9 U8.E12 | length 8.7
  INT4 w0.102: v6(27,-47.571) 27.625,-46.946 30.125,-46.946 33.125,-43.946 33.125,-43.446 v1(33.5,-43.071)
MEM6_28: U1.H14 U8.E3 | length 13
  INT3 w0.102: v6(27,-38.571) 27.5,-38.571 27.875,-38.946 28.125,-38.946 28.375,-38.696 28.625,-38.696 28.875,-38.946 29.25,-38.946 29.5,-38.696 37.5,-38.696 38.125,-38.071 38.125,-37.446 v1(38.5,-37.071)
MEM6_29: U1.K15 U8.D2 | length 13.1
  INT3 w0.102: v6(28,-37.571) 28.125,-37.696 28.625,-37.696 28.875,-37.946 29.125,-37.946 29.375,-37.696 30.625,-37.696 30.875,-37.946 31.125,-37.946 31.375,-37.696 36.375,-37.696 39,-35.071 v1(39.5,-35.071)
MEM6_30: U1.L8 U8.F2 | length 8.2
  INT4 w0.102: v6(26,-37.571) 26,-37.071 28.375,-34.696 31.875,-34.696 v1(32.5,-34.071)
MEM6_31: U1.L15 U8.E2 | length 14.2
  INT3 w0.102: v6(27,-37.571) 27.5,-37.571 27.875,-37.196 28.125,-37.196 28.375,-37.446 28.625,-37.446 28.875,-37.196 30.875,-37.196 31.375,-36.696 36.375,-36.696 38.5,-34.571 39,-34.571 v1(39.5,-34.071)
MEM6_RST: R84.2 U1.C28 U8.K2 U8.L2 | length 43.6
  INT7 w0.102: v1(50,-46.571) 50,-42.946 50.25,-42.696 51.875,-42.696 v1(52.5,-42.071)
  INT2 w0.102: v6(22,-37.571) v6(21,-37.571) 20.625,-37.946 20.625,-40.696 21.125,-41.196 27.125,-41.196 27.375,-41.446 27.625,-41.446 27.875,-41.196 28.125,-41.196 28.375,-41.446 28.625,-41.446 28.875,-41.196 31,-41.196 31.25,-41.446 51.875,-41.446 v1(52.5,-42.071)
MEM7_0: MEM7_0.1 U1.K13 U9.C3 | length 40.6
  INT5 w0.102: v1(29,-22.571) 29.125,-22.446 35.375,-22.446 36.375,-23.446 36.375,-23.696 36.125,-23.946 36.125,-24.196 36.375,-24.446 36.375,-25.696 36.125,-25.946 36.125,-26.196 36.375,-26.446 36.375,-27.696 36.125,-27.946 36.125,-29.196 36.375,-29.446 36.375,-29.696 36.125,-29.946 36.125,-30.196 36.375,-30.446 36.375,-30.696 36.125,-30.946 36.125,-31.196 36.375,-31.446 36.375,-31.696 36.125,-31.946 36.125,-32.196 36.375,-32.446 36.375,-32.696 36.125,-32.946 36.125,-34.196 36.375,-34.446 36.875,-34.446 v1(37.5,-35.071)
  INT7 w0.102: v1(37.5,-35.071) 38,-35.071 41,-38.071 41,-48.071 41.5,-48.571 41.5,-50.246 MEM7_0.1@42.75,-51.496
MEM7_1: U1.H11 U9.D5 | length 20
  INT5 w0.102: v1(28,-24.571) 28.5,-24.571 28.875,-24.946 29.5,-24.946 29.75,-24.696 33.75,-24.696 33.875,-24.821 33.875,-32.196 33.625,-32.446 33.625,-32.696 33.875,-32.946 33.875,-33.196 33.625,-33.446 33.625,-33.696 33.875,-33.946 33.875,-36.321 34.25,-36.696 35.125,-36.696 v1(35.5,-37.071)
MEM7_2: U1.H13 U9.C5 | length 20.9
  INT5 w0.102: v1(29,-24.571) 29.125,-24.446 33.875,-24.446 34.125,-24.696 34.125,-32.196 34.375,-32.446 34.375,-32.696 34.125,-32.946 34.125,-33.196 34.375,-33.446 34.375,-33.696 34.125,-33.946 34.125,-36.196 34.375,-36.446 36.875,-36.446 v1(37.5,-37.071)
MEM7_3: U1.F12 U9.E7 | length 21.7
  INT5 w0.102: v1(27,-26.571) 27.5,-26.571 27.875,-26.946 28.125,-26.946 28.375,-26.696 28.625,-26.696 28.875,-26.946 29.25,-26.946 29.5,-26.696 31.75,-26.696 32.125,-27.071 32.125,-38.321 32.5,-38.696 36.125,-38.696 v1(36.5,-39.071)
MEM7_4: U1.H8 U9.D9 | length 19
  INT4 w0.102: v6(28,-28.571) 28,-29.071 27.625,-29.446 27.625,-29.696 28.875,-30.946 28.875,-31.196 28.625,-31.446 28.625,-31.696 29.625,-32.696 30.625,-32.696 30.875,-32.946 31.125,-32.946 31.375,-32.696 33.625,-32.696 33.875,-32.946 34.625,-33.696 34.875,-33.946 34.875,-38.196 34.625,-38.446 33.125,-38.446 33,-38.321 33,-37.571 v1(32.5,-37.071)
MEM7_5: U1.B12 U9.D11 | length 20.3
  INT5 w0.102: v6(28,-30.571) 28,-31.071 28.875,-31.946 28.875,-32.196 28.625,-32.446 28.625,-32.696 28.875,-32.946 28.875,-33.196 28.625,-33.446 28.625,-33.696 28.875,-33.946 28.875,-37.196 28.625,-37.446 28.625,-37.696 28.875,-37.946 28.875,-38.196 28.625,-38.446 28.625,-38.696 28.875,-38.946 28.875,-39.196 28.625,-39.446 28.625,-40.696 30.375,-42.446 35.875,-42.446 v1(36.5,-43.071)
MEM7_6: U1.F9 U9.C12 | length 14.3
  INT4 w0.102: v6(29,-31.571) 30.5,-31.571 31.375,-32.446 33.625,-32.446 33.875,-32.196 34.125,-32.196 35.125,-33.196 35.375,-33.446 35.375,-33.696 35.125,-33.946 35.125,-38.321 34.75,-38.696 33.875,-38.696 v1(33.5,-39.071)
MEM7_7: U1.G9 U9.G12 | length 15.4
  INT4 w0.102: v6(25,-31.571) 25.375,-31.946 25.375,-32.696 25.125,-32.946 25.125,-33.446 26.125,-34.446 31.625,-34.446 32.375,-33.696 32.625,-33.696 33.875,-34.946 33.875,-37.696 v1(33.5,-38.071)
MEM7_8: U1.J13 U9.D4 | length 21.9
  INT5 w0.102: v1(28,-23.571) 28.5,-23.571 28.875,-23.196 29.625,-23.196 29.875,-23.446 34.75,-23.446 35.125,-23.821 35.125,-33.196 35.375,-33.446 35.375,-33.696 35.125,-33.946 35.125,-35.196 35.375,-35.446 36.875,-35.446 v1(37.5,-36.071)
MEM7_9: U1.J10 U9.D6 | length 14.4
  INT6 w0.102: v1(28,-25.571) 28.5,-25.571 32.125,-29.196 32.125,-35.196 32.375,-35.446 33.875,-35.446 v1(34.5,-36.071)
MEM7_10: U1.G11 U9.C6 | length 18.4
  INT5 w0.102: v1(29,-25.571) 32.875,-25.571 33.125,-25.821 33.125,-37.321 33.375,-37.571 35,-37.571 v1(35.5,-38.071)
MEM7_11: U1.E13 U9.C8 | length 20.3
  INT5 w0.102: v6(29,-27.571) 29.147,-27.424 29.709,-27.424 29.75,-27.384 30.042,-27.384 30.082,-27.424 31.478,-27.424 31.875,-27.821 31.875,-38.946 32.375,-39.446 36.875,-39.446 v1(37.5,-40.071)
MEM7_12: U1.G10 U9.F9 | length 18.5
  INT4 w0.102: v6(26,-28.571) 25.425,-29.146 25.425,-29.497 25.853,-29.925 25.853,-30.217 25.625,-30.445 25.625,-32.696 26.5,-33.571 28.5,-33.571 28.875,-33.196 29.125,-33.196 29.375,-33.446 29.625,-33.446 29.875,-33.196 30.125,-33.196 30.375,-33.446 30.625,-33.446 30.875,-33.196 31.125,-33.196 31.375,-33.446 33.375,-33.446 34.125,-34.196 34.125,-37.696 v1(34.5,-38.071)
MEM7_13: U1.C12 U9.E10 | length 21
  INT5 w0.102: v6(27,-29.571) 27.5,-29.571 29.375,-31.446 29.375,-31.696 29.125,-31.946 29.125,-32.196 29.375,-32.446 29.375,-32.696 29.125,-32.946 29.125,-33.196 29.375,-33.446 29.375,-33.696 29.125,-33.946 29.125,-36.696 29.375,-36.946 29.375,-37.696 29.125,-37.946 29.125,-38.196 29.375,-38.446 29.375,-39.696 29.125,-39.946 29.125,-40.196 30.625,-41.696 36.125,-41.696 v1(36.5,-42.071)
MEM7_14: U1.B11 U9.G11 | length 21.8
  INT5 w0.102: v6(25,-30.571) 25.375,-30.946 26.875,-30.946 28.375,-32.446 28.375,-32.696 28.125,-32.946 28.125,-37.196 28.375,-37.446 28.375,-37.696 28.125,-37.946 28.125,-38.196 28.375,-38.446 28.375,-38.696 28.125,-38.946 28.125,-39.196 28.375,-39.446 28.375,-40.696 28.125,-40.946 28.125,-41.196 29.625,-42.696 35.125,-42.696 v1(35.5,-43.071)
MEM7_15: U1.C11 U9.E13 | length 26.8
  INT5 w0.102: v6(27,-32.571) 26.875,-32.696 26.875,-37.196 26.625,-37.446 26.625,-37.696 26.875,-37.946 26.875,-38.196 26.625,-38.446 26.625,-38.696 26.875,-38.946 26.875,-39.196 26.625,-39.446 26.625,-39.696 26.875,-39.946 26.875,-40.196 26.625,-40.446 26.625,-41.696 26.875,-41.946 26.875,-42.196 26.625,-42.446 26.625,-42.696 28.125,-44.196 29.25,-44.196 29.625,-44.571 37.625,-44.571 37.875,-44.321 37.875,-43.946 36,-42.071 v1(35.5,-42.071)
MEM7_16: U1.J11 U9.E5 | length 20.9
  INT5 w0.102: v1(27,-24.571) 27.625,-23.946 29.125,-23.946 29.375,-23.696 34.625,-23.696 34.875,-23.946 34.875,-33.196 34.625,-33.446 34.625,-33.696 34.875,-33.946 34.875,-35.446 v1(35.5,-36.071)
MEM7_17: U1.J8 U9.F6 | length 15.2
  INT6 w0.102: v1(26,-25.571) 26.5,-25.571 26.875,-25.946 27.875,-25.946 28.396,-26.467 28.396,-26.675 28.147,-26.925 28.147,-27.217 28.353,-27.423 28.353,-28.074 29.884,-29.604 31.533,-29.604 31.875,-29.946 31.875,-35.446 v1(32.5,-36.071)
MEM7_18: U1.E12 U9.E8 | length 21.9
  INT5 w0.102: v6(27,-27.571) 27.375,-27.946 28.875,-27.946 29.375,-28.446 30.75,-28.446 31.125,-28.821 31.125,-31.196 31.375,-31.446 31.375,-31.696 31.125,-31.946 31.125,-32.196 31.375,-32.446 31.375,-32.696 31.125,-32.946 31.125,-33.196 31.375,-33.446 31.375,-33.696 31.125,-33.946 31.125,-36.196 31.375,-36.446 31.375,-36.696 31.125,-36.946 31.125,-37.196 31.375,-37.446 31.375,-37.696 31.125,-37.946 31.125,-39.321 31.5,-39.696 36.125,-39.696 v1(36.5,-40.071)
MEM7_19: U1.C13 U9.C10 | length 20.4
  INT5 w0.102: v6(29,-29.571) 29.625,-29.571 29.875,-29.821 29.875,-33.196 29.625,-33.446 29.625,-33.696 29.875,-33.946 29.875,-36.196 29.625,-36.446 29.625,-36.821 29.875,-37.071 29.875,-40.571 30.75,-41.446 36.875,-41.446 v1(37.5,-42.071)
MEM7_20: U1.A13 U9.D13 | length 20.8
  INT5 w0.102: v6(28,-32.571) 27.875,-32.696 27.875,-37.196 27.625,-37.446 27.625,-37.696 27.875,-37.946 27.875,-38.196 27.625,-38.446 27.625,-38.696 27.875,-38.946 27.875,-39.196 27.625,-39.446 27.625,-40.696 27.875,-40.946 27.875,-41.196 27.625,-41.446 27.625,-41.696 29.375,-43.446 36.875,-43.446 v1(37.5,-44.071)
MEM7_21: U1.F10 U9.F13 | length 23
  INT4 w0.102: v6(26,-32.571) 26,-32.071 27.375,-30.696 27.375,-29.446 27.125,-29.196 27.125,-28.946 27.875,-28.196 29.125,-28.196 29.375,-28.446 29.375,-29.446 31.625,-31.696 34.625,-31.696 35.875,-32.946 35.875,-38.321 35.625,-38.571 35.25,-38.571 34.75,-39.071 v1(34.5,-39.071)
MEM7_22: U1.K11 U9.G3 | length 19.4
  INT6 w0.102: v1(25,-22.571) 25.375,-22.946 27.125,-22.946 27.375,-22.696 27.625,-22.696 27.875,-22.946 33.125,-28.196 33.125,-34.196 33.375,-34.446 34.875,-34.446 v1(35.5,-35.071)
MEM7_23: U1.K10 U9.G4 | length 17.8
  INT6 w0.102: v1(25,-23.571) 25.375,-23.196 27.125,-23.196 27.375,-23.446 32.875,-28.946 32.875,-34.446 33.125,-34.696 34.125,-34.696 v1(34.5,-35.071)
MEM7_24: U1.F13 U9.C7 | length 20.3
  INT5 w0.102: v1(29,-26.571) 29.125,-26.446 32.375,-26.446 32.875,-26.946 32.875,-38.071 33.25,-38.446 36.875,-38.446 v1(37.5,-39.071)
MEM7_25: U1.D13 U9.C9 | length 20.7
  INT5 w0.102: v6(29,-28.571) 29.375,-28.946 30.375,-28.946 30.875,-29.446 30.875,-31.196 30.625,-31.446 30.625,-31.696 30.875,-31.946 30.875,-32.196 30.625,-32.446 30.625,-32.696 30.875,-32.946 30.875,-33.196 30.625,-33.446 30.625,-33.696 30.875,-33.946 30.875,-36.196 30.625,-36.446 30.625,-37.696 30.875,-37.946 30.875,-39.946 31.375,-40.446 36.875,-40.446 v1(37.5,-41.071)
MEM7_26: U1.D11 U9.D10 | length 19.3
  INT5 w0.102: v6(28,-29.571) 28.5,-29.571 28.875,-29.196 29.75,-29.196 30.125,-29.571 30.125,-33.196 30.375,-33.446 30.375,-33.696 30.125,-33.946 30.125,-36.196 30.375,-36.446 30.375,-37.696 30.125,-37.946 30.125,-40.321 30.5,-40.696 35.125,-40.696 v1(35.5,-41.071)
MEM7_27: U1.A12 U9.E12 | length 21.9
  INT5 w0.102: v6(27,-31.571) 27,-32.071 27.375,-32.446 27.375,-32.696 27.125,-32.946 27.125,-37.196 27.375,-37.446 27.375,-37.696 27.125,-37.946 27.125,-38.196 27.375,-38.446 27.375,-38.696 27.125,-38.946 27.125,-39.196 27.375,-39.446 27.375,-40.696 27.125,-40.946 27.125,-41.196 27.375,-41.446 27.375,-42.446 28.875,-43.946 29.125,-43.946 29.375,-43.696 36.125,-43.696 v1(36.5,-44.071)
MEM7_28: U1.K12 U9.E3 | length 22.5
  INT5 w0.102: v1(27,-22.571) 27.5,-22.571 27.875,-22.946 28.125,-22.946 28.375,-22.696 28.625,-22.696 28.875,-22.946 29.625,-22.946 29.875,-22.696 34.625,-22.696 35.875,-23.946 35.875,-24.196 35.625,-24.446 35.625,-26.696 35.875,-26.946 35.875,-27.196 35.625,-27.446 35.625,-27.696 35.875,-27.946 35.875,-29.196 35.625,-29.446 35.625,-29.696 35.875,-29.946 35.875,-30.196 35.625,-30.446 35.625,-30.696 35.875,-30.946 35.875,-31.196 35.625,-31.446 35.625,-31.696 35.875,-31.946 35.875,-32.196 35.625,-32.446 35.625,-32.696 35.875,-32.946 35.875,-34.446 v1(36.5,-35.071)
MEM7_29: U1.L13 U9.D2 | length 24.4
  INT5 w0.102: v1(28,-21.571) 28.5,-21.571 28.875,-21.196 31.125,-21.196 31.375,-21.446 33.625,-21.446 33.875,-21.196 34.125,-21.196 34.375,-21.446 35.625,-21.446 35.875,-21.196 36.125,-21.196 37.375,-22.446 37.375,-22.696 37.125,-22.946 37.125,-23.196 37.375,-23.446 37.375,-23.696 37.125,-23.946 37.125,-24.196 37.375,-24.446 37.375,-24.696 37.125,-24.946 37.125,-25.196 37.375,-25.446 37.375,-25.696 37.125,-25.946 37.125,-26.196 37.375,-26.446 37.375,-26.696 37.125,-26.946 37.125,-27.196 37.375,-27.446 37.375,-27.696 37.125,-27.946 37.125,-28.196 37.375,-28.446 37.375,-28.696 37.125,-28.946 37.125,-29.196 37.375,-29.446 37.375,-29.696 37.125,-29.946 37.125,-30.196 37.375,-30.446 37.375,-30.696 37.125,-30.946 37.125,-31.196 37.375,-31.446 37.375,-31.696 37.125,-31.946 37.125,-32.196 37.375,-32.446 37.375,-32.696 37.125,-32.946 37.125,-33.696 v1(37.5,-34.071)
MEM7_30: U1.L9 U9.F2 | length 17
  INT6 w0.102: v1(26,-21.571) 26.5,-21.571 26.875,-21.946 27.875,-21.946 33.875,-27.946 33.875,-32.196 33.625,-32.446 33.625,-32.696 33.875,-32.946 33.875,-33.196 33.5,-33.571 v1(33.5,-34.071)
MEM7_31: U1.L12 U9.E2 | length 24
  INT5 w0.102: v1(27,-21.571) 27.375,-21.946 29.125,-21.946 29.375,-21.696 30.625,-21.696 30.875,-21.946 31.125,-21.946 31.375,-21.696 33.625,-21.696 33.875,-21.946 34.125,-21.946 34.375,-21.696 35.625,-21.696 36.875,-22.946 36.875,-23.196 36.625,-23.446 36.625,-23.696 36.875,-23.946 36.875,-24.196 36.625,-24.446 36.625,-25.696 36.875,-25.946 36.875,-26.196 36.625,-26.446 36.625,-27.696 36.875,-27.946 36.875,-28.196 36.625,-28.446 36.625,-28.696 36.875,-28.946 36.875,-29.196 36.625,-29.446 36.625,-29.696 36.875,-29.946 36.875,-30.196 36.625,-30.446 36.625,-30.696 36.875,-30.946 36.875,-31.196 36.625,-31.446 36.625,-31.696 36.875,-31.946 36.875,-32.196 36.625,-32.446 36.625,-32.696 36.875,-32.946 36.875,-33.696 v1(36.5,-34.071)
MEM7_RST: R83.2 U1.D28 U9.K2 U9.L2 | length 56.5
  INT7 w0.102: v1(21,-21.571) v1(22,-21.571) 22.028,-21.571 22.454,-21.996 22.454,-23.774 23.603,-24.924 27.148,-24.924 27.354,-24.718 27.648,-24.718 27.854,-24.924 28.148,-24.924 28.354,-24.718 28.648,-24.718 28.854,-24.924 29.152,-25.222 31.151,-25.222 ; 31.197,-25.268 31.151,-25.222 ; v1(48,-46.571) 48,-40.946 48.375,-40.571 52,-40.571 v1(52.5,-41.071) 52.875,-41.446 53.625,-41.446 54.375,-40.696 54.375,-40.446 53.625,-39.696 53.625,-39.446 53.875,-39.196 53.875,-38.946 51.375,-36.446 46.375,-36.446 43.5,-33.571 39.5,-33.571 31.151,-25.222
MGTAVCC: C135.2 C136.2 RT6.3 U1.AC6 U1.AE6 U1.AG6 U1.AJ6 U1.AL6 U1.AN6 U1.C6 U1.E6 U1.G6 U1.J6 U1.L6 U1.N6 U1.U6 U1.W6 | length 14.3
  Bottom Layer w0.254: v1(30.5,-42.071) 30,-41.571 30,-40.571 v1(30.5,-40.071) 30,-39.571 30,-38.571 v1(30.5,-38.071) 30,-37.571 30,-36.571 v1(30.5,-36.071) 30,-35.571 30,-34.571 U1.L6@30.5,-34.071 30,-33.571 30,-32.571 U1.N6@30.5,-32.071
  Bottom Layer w0.508: v3(77.902,-6.274) v3(77.902,-5.8) 77.902,-5.788 RT6.3@79.118,-4.572
  other v1: 30.5,-28.071 30.5,-26.071 30.5,-22.071 30.5,-20.071 22,-18.571 23,-18.571 30.5,-18.071 22,-17.571 23,-17.571 30.5,-16.071 30.5,-14.071 30.5,-12.071 31,-6.571
  other v3: 77.876,-6.858 78.842,-5.766
MGTAVCC_EN: R535.1 R536.2 U97.F6 | length 26.6
  Top Layer w0.127: v3(77.343,-16.578) U97.F6@77.343,-16.002 ; R535.1@82.042,5.156 v3(82.042,5.74)
  INT2 w0.127: v3(77.343,-16.578) 77.343,-16.542 76.657,-15.856 76.657,-4.597 77.927,-3.327 77.927,-1.499 80.493,1.067 80.493,4.191 v3(82.042,5.74)
  Bottom Layer w0.127: R536.2@82.042,5.156 v3(82.042,5.74)
MGTAVTT: C137.2 C138.2 R132.2 R271.1 R272.1 RT8.3 U1.AC2 U1.AD3 U1.AG2 U1.AH3 U1.AL2 U1.AM3 U1.AP6 U1.C2 U1.D3 U1.G2 U1.H3 U1.L2 U1.M3 U1.R2 U1.T3 U1.W2 U1.Y3 | length 26.8
  Bottom Layer w0.254: 24.5,-33.571 26,-33.571 v6(26.5,-34.071) v6(27.5,-33.071) ; 24.625,-37.571 26,-37.571 v6(26.5,-38.071) v6(27.5,-37.071) ; 24.875,-41.571 26,-41.571 v1(26.5,-42.071) v1(27.5,-41.071) 27,-40.571 24.875,-40.571 ; 25,-30.571 26,-30.571 v1(26.5,-30.071) v1(27.5,-29.071)
  Bottom Layer w0.381: v3(29.957,-8.571) 30.5,-9.114 v1(30.5,-11.071)
  Bottom Layer w0.508: 24,-41.571 24.875,-41.571 ; 24,-37.571 25,-37.571 ; 24,-33.571 25,-33.571 ; 24,-30.571 25,-30.571 ; 24.125,-40.571 24.875,-40.571 ; v3(71.346,-3.048) 71.346,-3.962 71.628,-4.245 RT8.3@71.628,-4.571 71.955,-4.244 v3(71.955,-3.251)
  other v1: 26.5,-26.071 27.5,-25.071 26.5,-22.071 27.5,-21.071 26.5,-18.071 27.5,-17.071 26.5,-14.071 27.5,-13.071 30.116,-11.071
  other v2: 14.125,-42.676
  other v3: 70.79,-4.242 70.815,-3.683
MGTAVTT_EN: R541.1 R602.2 U97.K7 | length 31.4
  Top Layer w0.127: v3(72.263,-17.848) U97.K7@72.263,-17.272 ; R541.1@78.791,6.604 v3(78.791,7.137)
  INT1 w0.127: 70.25,-4.496 70.25,-3.562 72.119,-1.694 72.119,0.465 73.406,1.753 74.143,1.753 78.232,5.842 78.232,6.579 v3(78.791,7.137) ; 70.256,-4.496 71.018,-5.258 71.018,-15.367 72.263,-16.612 v3(72.263,-17.848)
  Bottom Layer w0.127: R602.2@78.791,6.604 v3(78.791,7.137)
MGTREFCLK1N: C212.1 U1.M5 | length 40.6
  INT7 w0.102: v2(3.625,-41.594) ccw(c3.625,-41.967) 3.252,-41.967 3.252,-43.161 ccw(c3.49,-43.161) 3.49,-43.399 10.127,-43.399 cw(c10.127,-45.391) 11.536,-43.982 11.73,-44.176 ccw(c12.919,-42.987) 12.919,-44.669 28.083,-44.669 ccw(c28.083,-43.381) 29.371,-43.381 ccw(c29.25,-43.381) 29.25,-43.26 29.192,-43.26 cw(c29.192,-43.137) 29.069,-43.137 cw(c29.196,-43.137) 29.196,-43.01 29.25,-43.01 ccw(c29.25,-42.889) 29.371,-42.889 ccw(c29.242,-42.889) 29.242,-42.76 29.192,-42.76 cw(c29.192,-42.637) 29.069,-42.637 cw(c29.196,-42.637) 29.196,-42.51 29.25,-42.51 ccw(c29.25,-42.389) 29.371,-42.389 29.371,-35.309 cw(c30.238,-35.309) 29.625,-34.696 ccw(c29.026,-34.097) 29.873,-34.097 29.873,-33.444 ccw(c29.5,-33.444) v1(29.5,-33.071)
MGTREFCLK1P: C211.1 U1.M6 | length 40.6
  INT7 w0.102: v2(2.625,-41.594) cw(c2.625,-41.967) 2.998,-41.967 2.998,-43.161 ccw(c3.49,-43.161) 3.49,-43.653 10.127,-43.653 cw(c10.127,-45.391) 11.357,-44.162 11.55,-44.356 ccw(c12.919,-42.987) 12.919,-44.923 28.083,-44.923 ccw(c28.083,-43.381) 29.625,-43.381 29.625,-35.309 cw(c30.238,-35.309) 29.805,-34.876 ccw(c29.026,-34.097) 30.127,-34.097 30.127,-33.444 cw(c30.5,-33.444) v1(30.5,-33.071)
MGTRREF: R132.1 U1.AP5 | length 2.8
  Bottom Layer w0.381: R132.1@29,-8.614 R132.1@29.043,-8.571 ; R132.1@29.043,-8.528 R132.1@29.043,-8.571 ; v1(29.5,-11.071) 29.5,-9.256 29.043,-8.799 R132.1@29.043,-8.571
MGTVCCAUX: C800.2 C801.2 L8.2 RT5.3 | length 339.4
  INT7 w0.254: 20.523,-19.434 v5(21.298,-20.208) 21.702,-20.208 22.571,-19.339 22.571,-5.393 22.822,-5.142 58.028,-5.142 59.17,-4 64.529,-4 65.126,-3.404 68.91,-3.404 70.59,-5.084 79.328,-5.084 81.102,-6.858 v3(81.483,-6.858) 81.483,-6.285 v3(81.497,-6.27) v3(81.497,-5.797) 81.497,-5.247 v3(81.483,-5.232) 78.816,-2.565 74.615,-2.565 74.107,-2.057 69.735,-2.057 68.915,-2.877 62.98,-2.877 62.716,-3.142 37.178,-3.142 36.822,-3.142 35.95,-4.014 26.865,-4.014 25.865,-3.014 20.838,-3.014 20.523,-3.329 20.523,-19.434
  INT3 w0.254: v3@81.483,-6.285 v3(81.483,-6.858) 81.173,-6.858 79.399,-5.084 70.743,-5.084 68.536,-2.877 38.271,-2.877 38.013,-3.134 36.411,-3.134 36.378,-3.167 36.012,-3.167 35.972,-3.128 30.628,-3.128 30.514,-3.014 20.838,-3.014 19.533,-4.319 19.533,-18.72 20.33,-19.517 20.965,-19.517 21.298,-19.85 v5(21.298,-20.208) 20.107,-20.208 19.05,-19.152 19.05,-18.618 18.491,-18.059 18.491,-4.521 23.241,0.229 24.613,0.229 25.226,0.842 39.544,0.842 40.818,-0.432 47.422,-0.432 47.777,-0.076 56.121,-0.076 57.211,-1.166 57.211,-1.169 57.704,-1.661 67.93,-1.661 68.197,-1.929 74.207,-1.929 74.768,-2.489 79.273,-2.489 80.95,-4.166 80.95,-4.699 v3(81.483,-5.232) 81.497,-5.247 v3(81.497,-5.797) v3(81.497,-6.27)
  INT3 w0.381: v3@81.483,-6.285 v3(81.497,-6.27)
  Bottom Layer w0.381: C800.2@15.342,-23.673 15.342,-23.393 16.671,-22.064 19.313,-22.064 19.5,-21.877 19.5,-21.037 C801.2@19.736,-20.801 20.705,-20.801 v5(21.298,-20.208)
  Bottom Layer w0.508: v3(81.483,-6.858) 81.483,-6.285 v3(81.497,-6.27) v3(81.497,-5.797) 81.483,-5.782 v3(81.483,-5.232) 82.122,-4.594 RT5.3@82.612,-4.594 RT5.3@82.612,-4.876
MGTVCCAUX_EN: R544.2 R743.1 U97.C6 | length 26.3
  Top Layer w0.127: U97.C6@81.153,-16.002 v3(81.153,-15.426) ; R743.1@81.737,6.477 v3(82.677,6.477)
  INT2 w0.127: v3(81.153,-15.426) 80.569,-14.842 80.569,-11.557 79.629,-10.617 79.629,-3.023 80.289,-2.362 80.289,0.102 80.874,0.686 80.874,3.658 82.677,5.461 v3(82.677,6.477)
  Bottom Layer w0.127: R544.2@81.737,6.477 v3(82.677,6.477)
MGTVCCAUX_R: C325.2 L8.1 U1.AA6 U1.R6 | length 36.4
  Bottom Layer w0.203: C325.2@20.879,-28.397 24.206,-28.397 25.019,-27.584 ; v5(22.947,-20.209) 22.454,-20.702 22.454,-24.638 25.019,-27.203 25.019,-27.559 26.862,-27.559 26.924,-27.621 26.924,-27.635 27.026,-27.737 27.026,-28.296 27.305,-28.575 31.013,-28.575 ; 31.013,-28.575 31.013,-24.584 v1(30.5,-24.071) 31.01,-23.561 31.74,-23.561 32.004,-23.825 32.004,-30.353 31.775,-30.582 31.011,-30.582 U1.R6@30.5,-30.071 31.013,-29.558 31.013,-28.575
NetC209_2: C209.2 U18.22 | length 2
  Top Layer w0.102: C209.2@-1.668,-46.551 cw(c-0.767,-47.451) -0.767,-46.178 -0.122,-46.178 cw(c-0.122,-46.598) U18.22@0.175,-46.301
NetC210_2: C210.2 U18.21 | length 2
  Top Layer w0.102: C210.2@-1.668,-45.551 ccw(c-0.767,-44.65) -0.767,-45.924 -0.122,-45.924 ccw(c-0.122,-45.504) U18.21@0.175,-45.801
NetC211_2: C211.2 U18.14 | length 1.7
  Top Layer w0.102: C211.2@2.625,-42.508 cw(c1.724,-43.409) 2.998,-43.409 2.998,-43.804 cw(c2.578,-43.804) U18.14@2.875,-44.101
NetC212_2: C212.2 U18.13 | length 1.7
  Top Layer w0.102: U18.13@3.375,-44.101 cw(c3.672,-43.804) 3.252,-43.804 3.252,-43.409 cw(c4.525,-43.409) C212.2@3.625,-42.508
NetC219_1: C219.1 U18.1 X1.1 | length 6.1
  Top Layer w0.127: v3(-3.912,-49.022) -3.908,-49.026 X1.1@-2.75,-49.026
  Top Layer w0.203: X1.1@-2.75,-49.026 -1.725,-48.001 U18.1@0.875,-48.001
  Bottom Layer w0.127: v3(-3.912,-49.022) -3.327,-49.606 C219.1@-3.327,-49.657
NetC220_2: C220.2 U18.2 X1.3 | length 7.1
  Top Layer w0.203: X1.3@-1.168,-50.926 v3(0,-50.926) 1.375,-49.551 U18.2@1.375,-48.001
  Bottom Layer w0.127: C220.2@-2.388,-50.8 -0.126,-50.8 v3(0,-50.926)
NetC225_2: C225.2 U22.15 | length 2.3
  Top Layer w0.102: C225.2@11.25,-43.633 10.997,-43.886 ccw(c11.287,-44.176) 10.877,-44.176 ccw(c11.184,-44.176) 10.967,-44.393 11.125,-44.551 cw(c10.517,-45.159) 11.377,-45.159 11.377,-45.478 ccw(c11.5,-45.478) U22.15@11.5,-45.601
NetC226_2: C226.2 U22.16 | length 2.3
  Top Layer w0.102: C226.2@10.25,-43.633 10.503,-43.886 cw(c10.213,-44.176) 10.623,-44.176 ccw(c11.184,-44.176) 10.787,-44.572 10.945,-44.731 cw(c10.517,-45.159) 11.123,-45.159 11.123,-45.478 cw(c11,-45.478) U22.16@11,-45.601
NetC227_2: C227.2 U22.13 | length 2.3
  Top Layer w0.102: U22.13@12.5,-45.601 cw(c12.5,-45.478) 12.377,-45.478 12.377,-45.159 cw(c12.983,-45.159) 12.554,-44.731 12.713,-44.572 ccw(c12.316,-44.176) 12.877,-44.176 cw(c13.287,-44.176) 12.997,-43.886 C227.2@13.25,-43.633
NetC228_2: C228.2 U22.14 | length 2.3
  Top Layer w0.102: U22.14@12,-45.601 ccw(c12,-45.478) 12.123,-45.478 12.123,-45.159 cw(c12.983,-45.159) 12.375,-44.551 12.533,-44.393 ccw(c12.316,-44.176) 12.623,-44.176 ccw(c12.213,-44.176) 12.503,-43.886 C228.2@12.25,-43.633
NetC259_2: C259.2 U18.18 | length 1.7
  Top Layer w0.102: C259.2@0.625,-42.508 cw(c-0.276,-43.409) 0.998,-43.409 0.998,-43.804 cw(c0.578,-43.804) U18.18@0.875,-44.101
NetC260_2: C260.2 U18.17 | length 1.7
  Top Layer w0.102: U18.17@1.375,-44.101 cw(c1.672,-43.804) 1.252,-43.804 1.252,-43.409 cw(c2.525,-43.409) C260.2@1.625,-42.508
NetC510_2: C510.2 U99.D8 U99.E5 | length 6.9
  Top Layer w0.127: v3(13.5,1.067) 13.538,1.029 C510.2@13.538,0.463
  INT1 w0.127: v3(9.093,1.143) 9.652,0.584 13.017,0.584 v3(13.5,1.067)
  Bottom Layer w0.127: v3(9.093,1.143) U99.E5@9.728,1.778 ; v3(13.5,1.067) 13.5,0.546 U99.D8@13.538,0.508
NetD1_2: D1.2 U1.AD7 | length 13.4
  INT1 w0.102: v1(18.5,-20.571) 18.875,-20.946 26.875,-20.946 27.125,-20.696 28.75,-20.696 29,-20.946 31.375,-20.946 v1(31.5,-21.071)
NetD2_1: D2.1 R107.1 | length 1.5
  Top Layer w0.381: R107.1@79.959,-27.571 D2.1@81.45,-27.571
NetD4_1: D4.1 R109.1 | length 1.5
  Top Layer w0.381: R109.1@0,3.658 1.118,3.658 D4.1@1.397,3.937
NetD5_1: D5.1 R110.1 | length 1.5
  Top Layer w0.381: R110.1@79.959,-23.761 D5.1@81.45,-23.761
NetD6_1: D6.1 R111.1 | length 1.3
  Top Layer w0.381: D6.1@9.349,-14.743 R111.1@9.349,-13.41
NetD7_1: D7.1 R112.1 | length 1.3
  Top Layer w0.381: D7.1@7.754,-14.743 R112.1@7.754,-13.41
NetD8_1: D8.1 R113.1 | length 1.3
  Top Layer w0.381: D8.1@11.004,-14.743 R113.1@11.004,-13.41
NetD9_1: D9.1 R142.2 U21.10 | length 3
  Top Layer w0.203: D9.1@0.138,-18.116 0.419,-18.398 R142.2@0.419,-19.39 0.935,-19.906 U21.10@1.793,-19.906
NetK1_1: K1.1 K1.2 R4.1 U1.T7 | length 54.3
  Top Layer w0.762: v2(69.123,-45.526) 69.242,-45.407 K1.2@74.513,-45.407 ; K1.2@74.461,-45.355 K1.2@74.513,-45.355
  INT8 w0.102: v1(31.5,-29.071) 31.875,-29.446 31.875,-32.946 35.625,-36.696 51.625,-36.696 51.875,-36.946 52.125,-36.946 52.375,-36.696 52.625,-36.696 52.875,-36.946 53.125,-36.946 53.375,-36.696 63.625,-36.696 69.123,-42.193 v2(69.123,-45.526)
NetLED100_1: LED100.1 R641.2 | length 1.6
  Top Layer w0.381: LED100.1@70.866,11.43 70.993,11.557 72.314,11.557 R641.2@72.39,11.633
NetLVK12_1: LVK12.1 TP1.1 | length 1.7
  Top Layer w0.381: LVK12.1@0.966,10.773 2.627,10.773 TP1.1@2.667,10.733
NetLVK12_4: LVK12.4 TP2.1 | length 1.7
  Top Layer w0.381: LVK12.4@0.966,8.023 2.638,8.023 TP2.1@2.667,8.052
NetPCIE_CONN_P4: PCIE_CONN.P4 R800.2 | length 4.1
  Bottom Layer w0.127: PCIE_CONN.P4@-2.946,-13.335 0.102,-13.335 R800.2@0.838,-14.072
NetPCIE_CONN_P10: PCIE_CONN.P10 R240.1 | length 1
  Bottom Layer w0.127: PCIE_CONN.P10@-2.72,-5.739 cw(c-2.498,-5.961) -2.498,-5.646 v5(-1.779,-5.646)
NetPCIE_CONN_P11: PCIE_CONN.P11 R140.1 | length 1.2
  Bottom Layer w0.127: PCIE_CONN.P11@-2.932,-4.469 -1.871,-4.469 v5(-1.779,-4.376)
NetR1_1: R1.1 R25.1 U1.M7 | length 29.6
  INT1 w0.102: v1(17,-19.696) 17.625,-20.321 17.625,-26.696 17.875,-26.946 17.875,-27.196 17.625,-27.446 17.625,-27.696 17.875,-27.946 17.875,-29.196 17.625,-29.446 17.625,-30.696 17.875,-30.946 17.875,-31.196 17.625,-31.446 17.625,-32.696 18.375,-33.446 21.375,-33.446 28.625,-33.446 28.875,-33.196 29.125,-33.196 29.375,-33.446 29.625,-33.446 29.875,-33.196 30.125,-33.196 30.375,-33.446 30.625,-33.446 30.875,-33.196 31.375,-33.196 v1(31.5,-33.071)
  Bottom Layer w0.508: R25.1@16.957,-19.696 R1.1@16.957,-18.696
NetR2_1: R2.1 R143.1 U1.R7 | length 26.4
  INT6 w0.102: v1(17,-13.571) v1(17,-14.571) 17.491,-15.062 21.26,-15.062 23.5,-17.302 23.5,-24.922 26.594,-28.016 27.965,-28.016 30.02,-30.071 v1(31.5,-30.071)
NetR3_1: R3.1 U1.V7 | length 9.2
  INT5 w0.102: v1(23,-26.571) 23.625,-27.196 27.125,-27.196 27.375,-27.446 27.625,-27.446 27.875,-27.196 28.125,-27.196 28.375,-27.446 28.625,-27.446 28.875,-27.196 29.636,-27.196 29.661,-27.17 30.13,-27.17 30.156,-27.196 31.375,-27.196 v1(31.5,-27.071)
NetR65_1: R65.1 U18.3 | length 1.8
  Top Layer w0.203: U18.3@1.875,-48.001 1.875,-49.094 R65.1@2.375,-49.594
NetR66_2: R66.2 R68.1 U18.19 | length 2.8
  Top Layer w0.203: R68.1@-0.418,-42.551 R66.2@-0.418,-43.551 0.175,-44.144 U18.19@0.175,-44.801 U18.19@-0.1,-44.801
NetR67_2: R67.2 R69.1 U18.12 | length 1.5
  Top Layer w0.203: v2(4.018,-44.301) 4.018,-44.744 U18.12@4.075,-44.801
  Bottom Layer w0.508: v2(4.018,-44.301) R69.1@4.018,-43.301
NetR70_1: R70.1 U18.5 | length 1.8
  Top Layer w0.203: U18.5@2.875,-48.001 2.875,-49.094 R70.1@3.375,-49.594
NetR114_2: R114.2 U22.5 | length 2.2
  Top Layer w0.203: v2(11.707,-51.551) 12,-51.258 U22.5@12,-49.501
NetR115_2: R115.2 U22.18 | length 2.6
  Top Layer w0.203: R115.2@7.957,-44.285 8.359,-44.285 9.675,-45.601 U22.18@10,-45.601
NetR122_2: R122.2 U21.8 | length 1.3
  Top Layer w0.203: U21.8@2.768,-18.681 2.768,-17.651 R122.2@2.934,-17.485
NetR123_1: R123.1 U1.L14 | length 13.9
  INT7 w0.102: v1(38.5,-34.071) 38.5,-34.571 42,-38.071 v1(42,-46.571)
NetR124_1: R124.1 U1.J20 | length 11.6
  INT7 w0.102: v1(43,-46.571) 43,-36.821 43.75,-36.071 v1(44.5,-36.071)
NetR125_1: R125.1 U1.AA30 | length 12.8
  INT3 w0.102: v1(54.5,-24.071) 55,-24.071 55.375,-23.696 55.625,-23.696 55.875,-23.946 56.125,-23.946 56.375,-23.696 56.625,-23.696 56.875,-23.946 57.125,-23.946 57.375,-23.696 57.625,-23.696 59,-25.071 65.5,-25.071 v1(66,-25.571)
NetR126_1: R126.1 U1.V24 | length 18.9
  INT3 w0.102: v1(48.5,-27.071) 48.875,-27.446 53.625,-27.446 53.875,-27.196 54.125,-27.196 54.375,-27.446 54.625,-27.446 54.875,-27.196 55.125,-27.196 55.375,-27.446 55.625,-27.446 55.875,-27.196 56.125,-27.196 56.375,-27.446 56.625,-27.446 56.875,-27.196 57.125,-27.196 57.375,-27.446 58.875,-27.446 59.445,-28.016 65.445,-28.016 v1(66,-28.571)
NetR127_1: R127.1 U1.AG27 | length 12.1
  INT3 w0.102: v1(51.5,-18.071) 51.875,-18.446 58.625,-18.446 59.375,-17.696 62.625,-17.696 v1(63,-18.071)
NetR128_1: R128.1 U1.AD23 | length 17.9
  INT3 w0.102: v1(47.5,-21.071) 49,-21.071 49.375,-21.446 51.625,-21.446 51.875,-21.196 52.125,-21.196 52.375,-21.446 53.625,-21.446 53.875,-21.196 54.125,-21.196 54.375,-21.446 54.625,-21.446 54.875,-21.196 55.125,-21.196 55.375,-21.446 55.625,-21.446 55.875,-21.196 56.125,-21.196 56.375,-21.446 56.625,-21.446 56.875,-21.196 57.125,-21.196 57.375,-21.446 57.625,-21.446 57.875,-21.196 58.125,-21.196 58.375,-21.446 58.625,-21.446 58.875,-21.196 59.25,-21.196 60.875,-19.571 62.5,-19.571 v1(63,-19.071)
NetR129_1: R129.1 U1.L10 | length 46.3
  INT6 w0.102: v1(16.957,-16.571) 16.31,-17.218 15.269,-17.218 14.75,-17.737 14.75,-23.564 16.027,-24.841 16.027,-26.526 16.009,-26.544 16.009,-29.972 15.866,-30.115 15.866,-33.41 15.291,-33.985 15.291,-35.302 16.463,-36.474 29.464,-36.474 30.429,-35.509 31.438,-35.509 31.853,-35.925 31.853,-35.968 32.581,-36.696 35.374,-36.696 35.853,-36.217 35.853,-34.925 34.999,-34.071 v1(34.5,-34.071)
NetR130_1: R130.1 U1.J21 | length 10.7
  INT7 w0.102: v1(45,-46.571) 45,-36.946 45.5,-36.446 v1(45.5,-36.071)
NetR131_1: R131.1 U1.AF19 | length 13.4
  INT7 w0.102: v1(43.5,-19.071) 44.125,-18.446 44.125,-16.946 44.375,-16.696 50.5,-10.571 v1(50.5,-8.571)
NetR133_1: R133.1 U1.K20 | length 12.4
  INT7 w0.102: v1(44,-46.571) 44,-36.821 44.25,-36.571 44.75,-36.571 45,-36.321 45,-35.571 v1(44.5,-35.071)
NetR138_2: R138.2 U19.5 | length 2
  Top Layer w0.381: U19.5@72.581,-36.659 72.974,-36.266 v2(72.974,-35.789)
  Bottom Layer w0.381: R138.2@72.801,-36.659 72.801,-35.962 v2(72.974,-35.789)
NetR501_2: R501.2 U99.D5 U99.D7 | length 6.9
  Top Layer w0.127: R501.2@12.268,0.432 12.827,-0.127 v3(12.903,-0.127)
  INT1 w0.127: v3(9.093,-0.127) 9.652,-0.686 10.719,-0.686 11.278,-0.127 v3(12.903,-0.127)
  Bottom Layer w0.127: v3(9.093,-0.127) U99.D5@9.728,0.508 ; U99.D7@12.268,0.508 v3(12.903,-0.127)
NetR601_2: R601.2 U99.C5 | length 1.7
  Top Layer w0.127: v3(9.093,-1.397) 9.093,-1.219 R601.2@9.55,-0.762
  Bottom Layer w0.127: v3(9.093,-1.397) U99.C5@9.728,-0.762
NetR604_1: R604.1 R605.2 U98.B6 | length 6.2
  Top Layer w0.127: U98.B6@38.1,2.159 38.862,1.397 v3(40.945,1.397) R604.1@41.758,1.397
  Bottom Layer w0.127: R605.2@38.76,1.422 38.786,1.397 v3(40.945,1.397)
NetR606_1: R606.1 R607.2 U98.E6 | length 6.1
  Top Layer w0.127: U98.E6@34.29,2.159 v3(34.29,2.735) ; R606.1@34.671,-0.94 v3(34.671,-0.127)
  INT2 w0.102: v3(34.29,2.735) 34.739,2.286 34.739,-0.059 v3(34.671,-0.127)
  Bottom Layer w0.127: R607.2@33.35,-0.94 33.858,-0.94 v3(34.671,-0.127)
NetR608_1: R608.1 R609.2 U98.H6 | length 4.2
  Top Layer w0.127: R608.1@29.845,-0.94 v3(29.845,-0.127) ; v3(30.48,1.583) U98.H6@30.48,2.159
  INT2 w0.127: v3(29.845,-0.127) 29.845,0.948 v3(30.48,1.583)
  Bottom Layer w0.127: R609.2@29.845,-0.94 v3(29.845,-0.127)
NetR610_1: R610.1 R611.2 U98.L6 | length 4.4
  Top Layer w0.127: R610.1@26.365,-0.864 26.01,-0.508 v3(26.01,-0.076) 26.01,1.499 U98.L6@26.67,2.159
  Bottom Layer w0.127: v3(26.01,-0.076) 26.01,-0.508 R611.2@26.365,-0.864
NetR612_1: R612.1 R613.2 U97.B6 | length 4.9
  Top Layer w0.127: U97.B6@82.423,-16.002 83.109,-16.688 83.109,-17.788 v3(83.82,-18.499)
  Bottom Layer w0.127: R612.1@82.677,-19.228 R613.2@83.82,-19.228 v3(83.82,-18.499)
NetR614_1: R614.1 R615.2 U97.E6 | length 4.2
  Top Layer w0.127: R614.1@78.105,-19.228 v3(78.105,-18.466) 78.105,-16.51 U97.E6@78.613,-16.002
  Bottom Layer w0.127: R615.2@78.105,-19.228 v3(78.105,-18.466)
NetR616_1: R616.1 R617.2 U97.H6 | length 4.5
  Top Layer w0.127: R616.1@74.676,-19.228 v3(74.676,-18.517) ; v3@74.701,-18.491 v3(74.676,-18.517) ; U97.H6@74.803,-16.002 75.387,-16.586 75.387,-17.787 74.676,-18.498 v3(74.676,-18.517)
  Bottom Layer w0.127: R617.2@74.676,-19.228 v3(74.676,-18.517)
NetR618_1: R618.1 R619.2 U97.L6 | length 4.8
  Top Layer w0.127: U97.L6@70.993,-16.002 70.46,-16.535 70.46,-17.856 70.993,-18.39 R618.1@70.993,-19.228 R619.2@72.136,-19.228
NetR633_1: R633.1 R654.2 U96.E6 | length 5
  Top Layer w0.127: v3(57.887,-1.219) R633.1@57.887,-0.635 57.328,-0.076 57.328,1.575 U96.E6@57.912,2.159 v3(57.912,2.735)
  Bottom Layer w0.127: v3(57.887,-1.219) 57.912,-1.194 R654.2@57.912,-0.635
NetR635_1: R635.1 R655.2 U96.H6 | length 5.6
  Top Layer w0.127: v3(54.102,1.583) U96.H6@54.102,2.159 ; v3(54.559,-1.346) R635.1@54.559,-0.635 R635.1@54.737,-0.457
  INT2 w0.127: v3(54.102,1.583) 54.889,0.796 54.889,-0.94 54.559,-1.27 v3(54.559,-1.346)
  Bottom Layer w0.127: v3(54.559,-1.346) R655.2@54.559,-0.635
NetR637_1: R637.1 R656.2 U96.L6 | length 3
  Top Layer w0.127: R637.1@47.955,2.159 v3(48.666,2.159) U96.L6@50.292,2.159
  Bottom Layer w0.127: v3(48.666,2.159) R656.2@49.378,2.159
NetR652_1: R652.1 R653.2 U96.B6 | length 4.8
  Top Layer w0.127: U96.B6@61.722,2.159 62.205,2.159 62.781,1.583 64.305,1.583 v3(64.618,1.27) R652.1@65.329,1.27
  Bottom Layer w0.127: R653.2@63.856,1.219 64.567,1.219 v3(64.618,1.27)
NetR710_1: R710.1 U98.F3 | length 7.5
  Top Layer w0.127: v3(33.02,5.393) U98.F3@33.02,5.969 ; R710.1@33.401,-1.016 R710.1@33.401,-0.94 v3(33.401,-0.203)
  INT2 w0.102: v3(33.02,5.393) 32.537,4.91 32.537,1.473 33.401,0.61 v3(33.401,-0.203)
NetR724_1: R724.1 U97.F3 | length 8.3
  Top Layer w0.127: v3(77.343,-12.768) U97.F3@77.343,-12.192 ; R724.1@79.248,-19.228 v3(79.248,-18.466)
  INT1 w0.127: v3(77.343,-12.768) 77.961,-13.386 78.791,-13.386 79.197,-13.792 79.197,-18.415 v3(79.248,-18.466)
NetR750_1: R750.1 U96.F3 | length 11.6
  Top Layer w0.127: R750.1@47.955,3.429 v3(48.666,3.429) ; v3(56.642,5.393) U96.F3@56.642,5.969
  INT1 w0.102: v3(48.666,3.429) 50.597,3.429 50.927,3.759 50.927,5.588 51.333,5.994 56.007,5.994 56.608,5.393 v3(56.642,5.393)
NetRT5_1: RT5.1 TP3.1 | length 8.1
  INT1 w0.508: v3(84.012,-8.8) 84.455,-8.357 TP3.1@84.455,-2.321
  Bottom Layer w0.508: v3(84.012,-8.8) RT5.1@84.012,-7.344
NetRT5_4: RT5.4 TP4.1 | length 3.2
  Bottom Layer w0.508: TP4.1@81.788,-3.302 83.441,-3.302 84.012,-3.873 RT5.4@84.012,-4.594
NetRT6_1: RT6.1 TP5.1 | length 1.3
  Bottom Layer w0.508: RT6.1@80.518,-7.322 80.55,-7.322 81.229,-8.001 TP5.1@81.534,-8.001
NetRT6_4: RT6.4 TP6.1 | length 4.2
  Bottom Layer w0.508: TP6.1@77.978,-4.318 77.978,-3.77 78.497,-3.251 79.845,-3.251 80.493,-3.899 80.493,-4.547 RT6.4@80.518,-4.572
NetRT7_1: RT7.1 TP7.1 | length 1.5
  Bottom Layer w0.508: RT7.1@76.773,-7.217 77.557,-8.001 TP7.1@77.978,-8.001
NetRT7_4: RT7.4 TP8.1 | length 3.5
  Bottom Layer w0.508: TP8.1@74.193,-3.175 74.245,-3.226 76.162,-3.226 76.773,-3.837 RT7.4@76.773,-4.467
NetRT8_1: RT8.1 TP9.1 | length 1.4
  Bottom Layer w0.508: RT8.1@73.028,-7.321 73.581,-7.874 TP9.1@74.168,-7.874
NetRT8_4: RT8.4 TP10.1 | length 5.5
  Bottom Layer w0.508: TP10.1@70.358,-2.667 70.866,-2.159 72.974,-2.159 73.355,-2.54 73.355,-3.682 73.028,-4.009 RT8.4@73.028,-4.571
NetRT9_1: RT9.1 TP11.1 | length 2.1
  Bottom Layer w0.381: RT9.1@41.845,8.36 41.91,8.425 TP11.1@41.91,10.389
NetRT9_4: RT9.4 TP12.1 | length 4.5
  Bottom Layer w0.508: TP12.1@40.014,9.322 40.522,8.814 40.564,8.814 40.564,6.891 RT9.4@41.845,5.61
NetRT10_1: RT10.1 TP13.1 | length 2
  Bottom Layer w0.381: RT10.1@28.553,11.52 30.263,11.52 TP13.1@30.455,11.328
NetRT10_4: RT10.4 TP14.1 | length 1.9
  Bottom Layer w0.508: TP14.1@23.901,11.495 23.927,11.52 RT10.4@25.803,11.52
NetRT15_1: RT15.1 TP15.1 | length 2.1
  Bottom Layer w0.381: RT15.1@65.34,8.233 65.34,10.222 TP15.1@65.405,10.287
NetRT15_4: RT15.4 TP16.1 | length 5
  Bottom Layer w0.508: TP16.1@63.602,9.804 64.084,9.322 64.084,6.739 RT15.4@65.34,5.483
NetRT16_1: RT16.1 TP17.1 | length 2
  Bottom Layer w0.381: RT16.1@50.651,11.495 52.513,11.495 TP17.1@52.578,11.43
NetRT16_4: RT16.4 TP18.1 | length 2
  Bottom Layer w0.508: TP18.1@45.872,11.481 45.887,11.495 RT16.4@47.901,11.495
NetRT801_1: RT801.1 TP802.1 | length 1.8
  Bottom Layer w0.381: TP802.1@68.936,8.28 68.983,8.328 RT801.1@68.983,10.069
NetRT801_4: RT801.4 TP803.1 | length 1.7
  Bottom Layer w0.381: RT801.4@71.733,10.069 71.733,8.353 TP803.1@71.755,8.331
NetTP703_1: TP703.1 U96.J3 | length 10
  Top Layer w0.102: U96.J3@52.832,5.969 v3(52.832,6.545)
  INT2 w0.102: TP703.1@48.057,0.686 48.895,0.686 50.47,2.261 51.689,2.261 53.289,3.861 53.289,6.088 v3(52.832,6.545)
NetTP705_1: TP705.1 U97.J3 | length 9.4
  Top Layer w0.127: TP705.1@69.596,-5.715 70.409,-6.528 70.409,-11.201 70.841,-11.633 72.974,-11.633 U97.J3@73.533,-12.192
NetTP714_1: TP714.1 U98.J3 | length 6
  Top Layer w0.127: U98.J3@29.21,5.969 v3(29.21,6.545)
  INT1 w0.127: TP714.1@24.359,6.579 24.943,7.163 28.702,7.163 29.21,6.655 v3(29.21,6.545)
PCIE_CLK_N: C227.1 R272.2 R274.1 U1.P5 | length 31.3
  INT7 w0.102: v2(13.25,-41.633) cw(c13.25,-41.26) 12.877,-41.26 12.877,-34.226 cw(c18.907,-34.226) 18.907,-28.196 cw(c18.907,-28.317) 19.028,-28.317 19.028,-28.371 ccw(c19.155,-28.371) 19.155,-28.498 ccw(c19.155,-28.375) 19.278,-28.375 19.278,-28.317 cw(c19.399,-28.317) 19.399,-28.196 cw(c19.399,-28.317) 19.52,-28.317 19.52,-28.371 ccw(c19.647,-28.371) 19.647,-28.498 ccw(c19.647,-28.375) 19.77,-28.375 19.77,-28.317 cw(c19.891,-28.317) 19.891,-28.196 28.3,-28.196 cw(c28.3,-29.769) 29.873,-29.769 29.873,-30.698 cw(c29.5,-30.698) v1(29.5,-31.071)
PCIE_CLK_N1: C225.1 C232.1
PCIE_CLK_N1_1: C232.2 R21.1 U1.E23 | length 46.3
  INT6 w0.102: v2(11.25,-40.719) cw(c11.25,-40.346) 10.877,-40.346 10.877,-39.372 cw(c12.573,-39.372) 12.573,-37.676 13.444,-37.676 cw(c13.444,-40.216) 15.24,-38.42 20.792,-43.973 ccw(c23.174,-41.592) 23.174,-44.959 46.344,-44.959 ccw(c46.344,-44.176) 47.127,-44.176 47.127,-40.444 cw(c47.5,-40.444) v1(47.5,-40.071)
PCIE_CLK_N_C: C230.1 PCIE_CONN.E8 | length 5.6
  Bottom Layer w0.127: PCIE_CONN.E8@-4.632,-29.944 cw(c-4.632,-30.817) -4.014,-30.199 ccw(c-3.582,-29.767) -3.582,-30.378 -0.127,-30.378 ccw(c-0.127,-29.19) C230.1@0.713,-30.03
PCIE_CLK_N_I: C230.2 R275.1 U22.23 | length 27.1
  Top Layer w0.127: v2(7.75,-48.551) cw(c8.123,-48.551) 8.123,-48.178 9.003,-48.178 cw(c9.003,-48.598) U22.23@9.3,-48.301
  INT5 w0.127: v5(1.383,-30.03) ccw(c1.637,-30.03) 1.637,-30.284 3.854,-30.284 cw(c3.854,-35.81) 9.379,-35.81 9.379,-47.426 cw(c8.627,-47.426) 8.627,-48.178 8.123,-48.178 ccw(c8.123,-48.551) v2(7.75,-48.551)
  Bottom Layer w0.127: C230.2@1.233,-30.03 v5(1.383,-30.03)
PCIE_CLK_P: C228.1 R271.2 R273.1 U1.P6 | length 31.3
  INT7 w0.102: v2(12.25,-41.633) ccw(c12.25,-41.26) 12.623,-41.26 12.623,-34.226 cw(c18.907,-34.226) 18.907,-27.942 28.3,-27.942 cw(c28.3,-29.769) 30.127,-29.769 30.127,-30.698 ccw(c30.5,-30.698) v1(30.5,-31.071)
PCIE_CLK_P1: C226.1 C231.1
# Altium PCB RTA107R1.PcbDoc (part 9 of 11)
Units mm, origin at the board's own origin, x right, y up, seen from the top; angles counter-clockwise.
Board outline 96.01 x 65.66 mm, 22 copper layers (Top Layer, GND1, INT1, PWR1-(VCCIO_MRAM), INT2, PWR2-(VCCINT), INT3, PWR3_(12V_MGTAVCC), INT4, GND2-(DGND_SGND), PWR4_(MGTAVTT_VCCBRAM,VCCAUX), PWR5-(VCC_12V), GND3-(DGND_GND), INT5, GND4, INT6, PWR6_(VCCO), INT7, GND5, INT8, GND6, Bottom Layer), stack 2.833 mm thick; 614 components, 659 nets, 4037 pads, 3511 vias.

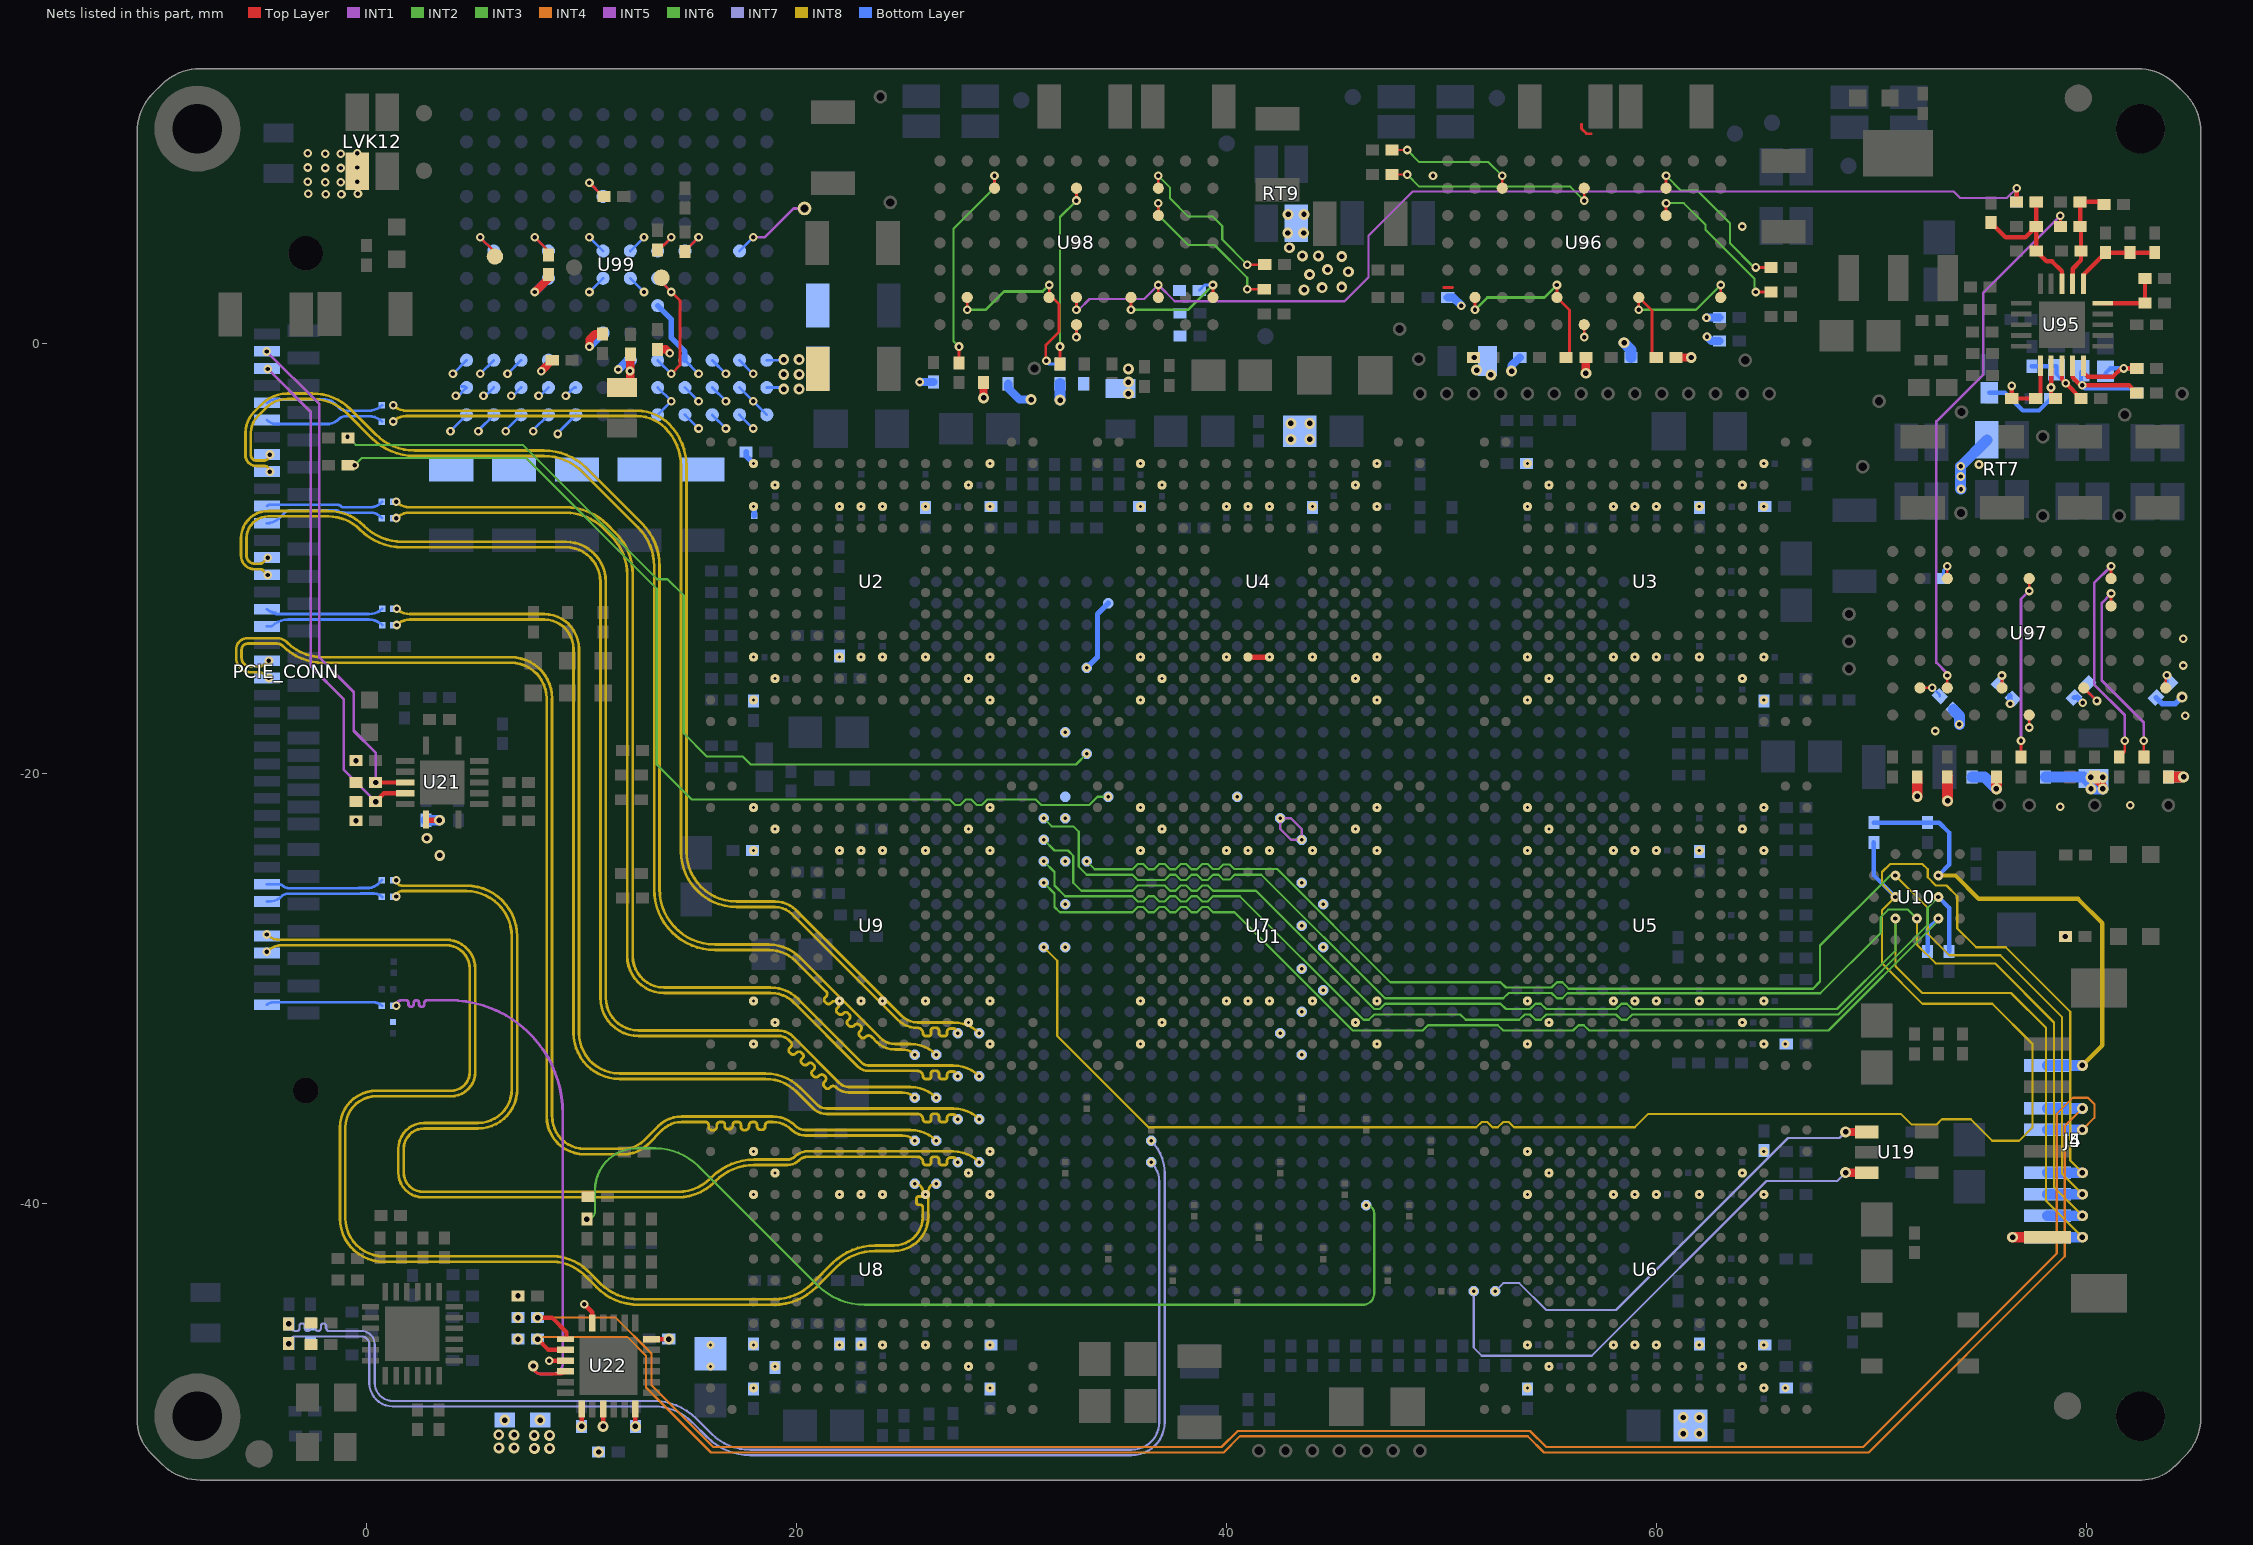
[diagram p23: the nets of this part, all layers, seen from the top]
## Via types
v1: diameter 0.381, hole 0.152, Top Layer to Bottom Layer, tented both sides, 2009 vias
v2: diameter 0.508, hole 0.254, Top Layer to Bottom Layer, tented both sides, 467 vias
v3: diameter 0.406, hole 0.203, Top Layer to Bottom Layer, 458 vias
v4: diameter 0.508, hole 0.254, Top Layer to Bottom Layer, 239 vias
v5: diameter 0.406, hole 0.203, Top Layer to Bottom Layer, tented both sides, 181 vias
v6: diameter 0.381, hole 0.152, Top Layer to GND4, tented both sides, 147 vias
v7: diameter 0.406, hole 0.203, Top Layer to GND4, tented both sides, 10 vias

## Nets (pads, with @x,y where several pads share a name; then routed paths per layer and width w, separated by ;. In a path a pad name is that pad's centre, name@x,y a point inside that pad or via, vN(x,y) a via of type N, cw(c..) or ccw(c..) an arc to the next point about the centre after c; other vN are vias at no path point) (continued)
PCIE_CLK_P1_1: C231.2 R21.2 U1.E22 | length 46.3
  INT6 w0.102: v2(10.25,-40.719) ccw(c10.25,-40.346) 10.623,-40.346 10.623,-39.372 cw(c12.573,-39.372) 12.573,-37.422 13.444,-37.422 cw(c13.444,-40.216) 15.419,-38.24 20.972,-43.793 ccw(c23.174,-41.592) 23.174,-44.705 46.344,-44.705 ccw(c46.344,-44.176) 46.873,-44.176 46.873,-40.444 ccw(c46.5,-40.444) v1(46.5,-40.071)
PCIE_CLK_P_C: C229.1 PCIE_CONN.E7 | length 5.4
  Bottom Layer w0.127: PCIE_CONN.E7@-4.632,-30.744 cw(c-4.364,-31.012) -4.364,-30.632 0.13,-30.632 0.327,-30.632 cw(c0.327,-31.179) C229.1@0.713,-30.792
PCIE_CLK_P_I: C229.2 R276.1 U22.22 | length 27.1
  Top Layer w0.127: v2(7.75,-47.551) ccw(c8.123,-47.551) 8.123,-47.924 9.003,-47.924 ccw(c9.003,-47.504) U22.22@9.3,-47.801
  INT5 w0.127: v5(1.383,-30.792) cw(c1.637,-30.792) 1.637,-30.538 1.823,-30.538 cw(c1.823,-30.659) 1.944,-30.659 1.944,-30.714 ccw(c2.071,-30.714) 2.071,-30.841 ccw(c2.071,-30.717) 2.194,-30.717 2.194,-30.659 cw(c2.315,-30.659) 2.315,-30.538 cw(c2.315,-30.659) 2.436,-30.659 2.436,-30.714 ccw(c2.563,-30.714) 2.563,-30.841 ccw(c2.563,-30.717) 2.686,-30.717 2.686,-30.659 cw(c2.807,-30.659) 2.807,-30.538 3.854,-30.538 cw(c3.854,-35.81) 9.125,-35.81 9.125,-47.426 cw(c8.627,-47.426) 8.627,-47.924 8.123,-47.924 cw(c8.123,-47.551) v2(7.75,-47.551)
  Bottom Layer w0.127: C229.2@1.233,-30.792 v5(1.383,-30.792)
PCIE_CON_ACTIVITY: R140.2 U1.AF9 | length 44.7
  INT2 w0.102: v5(-0.889,-4.319) -0.509,-4.699 7.264,-4.699 13.513,-10.947 13.995,-10.947 14.75,-11.702 14.75,-18.122 15.824,-19.196 17.5,-19.196 17.875,-19.571 33,-19.571 v1(33.5,-19.071)
PCIE_PRSNT1#: U1.AD8
PCIE_PRSNT4#: R240.2 U1.AD10 | length 47.2
  INT2 w0.102: v5(-0.56,-5.646) -0.217,-5.304 7.412,-5.304 13.5,-11.392 13.5,-19.571 15.125,-21.196 27.125,-21.196 27.375,-21.446 27.625,-21.446 27.875,-21.196 28.125,-21.196 28.375,-21.446 28.625,-21.446 28.875,-21.196 31.125,-21.196 31.375,-21.446 33.625,-21.446 34,-21.071 v1(34.5,-21.071)
PCIE_RX0_N: C183.2 U1.G3 | length 50.3
  INT8 w0.127: v5(1.383,-25.712) cw(c1.637,-25.712) 1.637,-25.458 4.638,-25.458 cw(c4.638,-27.57) 6.75,-27.57 6.75,-34.682 cw(c5.186,-34.682) 5.186,-36.246 2.673,-36.246 ccw(c2.673,-37.444) 1.475,-37.444 1.475,-38.557 ccw(c2.618,-38.557) 2.618,-39.7 14.491,-39.7 ccw(c14.491,-37.312) 16.18,-39.001 16.236,-38.944 cw(c18.032,-40.74) 18.032,-38.2 19.578,-38.2 ccw(c19.578,-37.436) 20.119,-37.976 cw(c20.493,-38.351) 20.493,-37.821 25.625,-37.821 cw(c25.625,-38.08) 25.884,-38.08 ccw(c26,-38.08) 25.918,-38.162 ccw(c26.018,-38.062) 26.018,-38.203 26.143,-38.203 ccw(c26.143,-38.096) 26.25,-38.096 26.25,-37.946 cw(c26.375,-37.946) 26.375,-37.821 26.5,-37.821 cw(c26.5,-37.946) 26.625,-37.946 26.625,-38.06 ccw(c26.768,-38.06) 26.768,-38.203 26.893,-38.203 ccw(c26.893,-38.096) 27,-38.096 27,-38.018 cw(c27.167,-38.018) 27.167,-37.85 27.279,-37.85 cw(c27.279,-38.071) v1(27.5,-38.071)
  Bottom Layer w0.127: C183.2@1.233,-25.712 v5(1.383,-25.712)
PCIE_RX0_N_C: C183.1 PCIE_CONN.E13 | length 5.5
  Bottom Layer w0.127: PCIE_CONN.E13@-4.632,-25.944 -4.539,-25.944 ccw(c-4.539,-25.128) -3.962,-25.705 cw(c-3.656,-26.011) -3.656,-25.578 -0.278,-25.578 -0.271,-25.571 0.342,-25.571 cw(c0.342,-26.115) 0.708,-25.712 cw(c0.342,-26.115) C183.1@0.727,-25.73
PCIE_RX0_P: C184.2 U1.G4 | length 50.3
  INT8 w0.127: v5(1.383,-24.95) ccw(c1.637,-24.95) 1.637,-25.204 4.638,-25.204 cw(c4.638,-27.57) 7.004,-27.57 7.004,-34.682 cw(c5.186,-34.682) 5.186,-36.5 2.673,-36.5 ccw(c2.673,-37.444) 1.729,-37.444 1.729,-38.557 ccw(c2.618,-38.557) 2.618,-39.446 14.491,-39.446 ccw(c14.491,-37.312) 16,-38.821 16.057,-38.764 cw(c18.032,-40.74) 18.032,-37.946 19.578,-37.946 ccw(c19.578,-37.436) 19.939,-37.796 cw(c20.493,-38.351) 20.493,-37.567 27.283,-37.567 cw(c27.283,-39.288) v1(28.5,-38.071)
  Bottom Layer w0.127: C184.2@1.233,-24.95 v5(1.383,-24.95)
PCIE_RX0_P_C: C184.1 PCIE_CONN.E14 | length 5.5
  Bottom Layer w0.127: PCIE_CONN.E14@-4.632,-25.144 -4.076,-25.144 cw(c-4.076,-25.412) -3.914,-25.198 ; -3.912,-25.2 ccw(c-3.613,-24.901) -3.613,-25.324 -0.383,-25.324 -0.376,-25.317 0.051,-25.317 ccw(c0.051,-24.62) 0.139,-25.311 ccw(c0.051,-24.62) 0.543,-25.113 C184.1@0.713,-24.943
PCIE_RX1_N: C191.2 U1.J3 | length 47.9
  INT8 w0.127: v5(1.397,-13.081) cw(c2.01,-13.694) 2.01,-12.827 8.258,-12.827 cw(c8.258,-14.194) 9.625,-14.194 9.625,-32.059 ccw(c11.762,-32.059) 11.762,-34.196 18.553,-34.196 cw(c18.553,-36.238) 19.997,-34.794 20.762,-35.559 ccw(c21.404,-34.918) 21.404,-35.825 25.629,-35.825 cw(c25.629,-36.08) 25.884,-36.08 ccw(c26,-36.08) 25.918,-36.162 ccw(c26.018,-36.062) 26.018,-36.203 26.143,-36.203 ccw(c26.143,-36.096) 26.25,-36.096 26.25,-35.946 cw(c26.375,-35.946) 26.375,-35.821 26.5,-35.821 cw(c26.5,-35.946) 26.625,-35.946 26.625,-36.06 ccw(c26.768,-36.06) 26.768,-36.203 26.893,-36.203 ccw(c26.893,-36.096) 27,-36.096 27,-36.018 cw(c27.167,-36.018) 27.167,-35.85 27.279,-35.85 cw(c27.279,-36.071) v1(27.5,-36.071)
  Bottom Layer w0.127: C191.2@1.247,-13.081 v5(1.397,-13.081)
PCIE_RX1_N_C: C191.1 PCIE_CONN.S20 | length 5.5
  Bottom Layer w0.127: PCIE_CONN.S20@-4.632,-13.144 -4.416,-13.144 cw(c-3.651,-13.908) -3.651,-12.827 0.114,-12.827 cw(c0.114,-13.694) C191.1@0.727,-13.081
PCIE_RX1_P: C192.2 U1.J4 | length 47.9
  INT8 w0.127: v5(1.397,-12.319) ccw(c2.01,-11.706) 2.01,-12.573 8.258,-12.573 cw(c8.258,-14.194) 9.879,-14.194 9.879,-32.059 ccw(c11.762,-32.059) 11.762,-33.942 18.553,-33.942 cw(c18.553,-36.238) 20.177,-34.614 20.942,-35.38 ccw(c21.404,-34.918) 21.404,-35.571 27.293,-35.571 cw(c27.293,-37.278) v1(28.5,-36.071)
  Bottom Layer w0.127: C192.2@1.247,-12.319 v5(1.397,-12.319)
PCIE_RX1_P_C: C192.1 PCIE_CONN.S21 | length 5.9
  Bottom Layer w0.127: PCIE_CONN.S21@-4.244,-12.504 cw(c-4.244,-11.955) PCIE_CONN.S21@-4.632,-12.344 ccw(c-4.078,-11.79) -4.078,-12.573 0.114,-12.573 ccw(c0.114,-11.706) C192.1@0.727,-12.319
PCIE_RX2_N: C195.2 U1.L3 | length 49.2
  INT8 w0.127: v5(1.381,-8.106) cw(c1.994,-8.719) 1.994,-7.852 9.235,-7.852 cw(c9.235,-10.392) 11.031,-8.596 11.381,-8.946 cw(c9.585,-10.742) 12.125,-10.742 12.125,-28.484 ccw(c13.837,-28.484) 13.837,-30.196 18.791,-30.196 cw(c18.791,-31.748) 19.888,-30.651 22.87,-33.632 ccw(c23.325,-33.177) 23.325,-33.821 25.625,-33.821 cw(c25.625,-34.08) 25.884,-34.08 ccw(c26,-34.08) 25.918,-34.162 ccw(c26.018,-34.062) 26.018,-34.203 26.143,-34.203 ccw(c26.143,-34.096) 26.25,-34.096 26.25,-33.946 cw(c26.375,-33.946) 26.375,-33.821 26.5,-33.821 cw(c26.5,-33.946) 26.625,-33.946 26.625,-34.06 ccw(c26.768,-34.06) 26.768,-34.203 26.893,-34.203 ccw(c26.893,-34.096) 27,-34.096 27,-34.018 cw(c27.167,-34.018) 27.167,-33.85 27.279,-33.85 cw(c27.279,-34.071) v1(27.5,-34.071)
  Bottom Layer w0.127: C195.2@1.231,-8.106 v5(1.381,-8.106)
PCIE_RX2_N_C: C195.1 PCIE_CONN.S26 | length 5.7
  Bottom Layer w0.127: PCIE_CONN.S26@-4.632,-8.344 ccw(c-4.632,-7.554) -4.074,-8.112 -3.827,-7.865 cw(c-3.526,-8.166) -3.526,-7.741 -1.433,-7.741 cw(c-1.433,-7.936) -1.295,-7.798 -1.294,-7.798 ccw(c-1.171,-7.675) -1.171,-7.849 -1.067,-7.849 ; -1.104,-7.852 0.203,-7.852 cw(c0.203,-8.465) C195.1@0.637,-8.031 ; C195.1@0.637,-8.032 C195.1@0.711,-8.106
PCIE_RX2_P: C196.2 U1.L4 | length 49.2
  INT8 w0.127: v5(1.381,-7.344) ccw(c1.994,-6.731) 1.994,-7.598 9.235,-7.598 cw(c9.235,-10.392) 11.21,-8.416 11.561,-8.767 cw(c9.585,-10.742) 12.379,-10.742 12.379,-28.484 ccw(c13.837,-28.484) 13.837,-29.942 18.791,-29.942 cw(c18.791,-31.748) 20.068,-30.471 23.05,-33.453 ccw(c23.325,-33.177) 23.325,-33.567 27.283,-33.567 cw(c27.283,-35.288) v1(28.5,-34.071)
  Bottom Layer w0.127: C196.2@1.231,-7.344 v5(1.381,-7.344)
PCIE_RX2_P_C: C196.1 PCIE_CONN.S27 | length 5.5
  Bottom Layer w0.127: PCIE_CONN.S27@-4.632,-7.544 cw(c-4.494,-7.681) -4.494,-7.487 -1.373,-7.487 cw(c-1.373,-7.741) -1.194,-7.561 ccw(c-1.104,-7.472) -1.104,-7.598 0.203,-7.598 ccw(c0.203,-6.985) 0.637,-7.418 C196.1@0.711,-7.344
PCIE_RX3_N: C199.2 U1.N3 | length 50.5
  INT8 w0.127: v5(1.233,-3.614) cw(c1.846,-4.228) 1.846,-3.36 12.559,-3.36 cw(c12.559,-5.248) 13.894,-3.913 cw(c12.129,-5.679) 14.625,-5.679 14.625,-23.618 ccw(c17.203,-23.618) 17.203,-26.196 19,-26.196 cw(c19,-27.305) 19.784,-26.521 24.702,-31.439 ccw(c25.625,-30.516) 25.625,-31.821 cw(c25.625,-32.08) 25.884,-32.08 ccw(c26,-32.08) 25.918,-32.162 ccw(c26.018,-32.062) 26.018,-32.203 26.143,-32.203 ccw(c26.143,-32.096) 26.25,-32.096 26.25,-31.946 cw(c26.375,-31.946) 26.375,-31.821 26.5,-31.821 cw(c26.5,-31.946) 26.625,-31.946 26.625,-32.06 ccw(c26.768,-32.06) 26.768,-32.203 26.893,-32.203 ccw(c26.893,-32.096) 27,-32.096 27,-32.018 cw(c27.167,-32.018) 27.167,-31.85 27.279,-31.85 cw(c27.279,-32.071) v1(27.5,-32.071)
PCIE_RX3_N_C: C199.1 PCIE_CONN.E20 | length 5.6
  Bottom Layer w0.127: PCIE_CONN.E20@-4.632,-3.544 ccw(c-4.173,-3.084) -4.173,-3.734 -1.854,-3.734 ccw(c-1.854,-2.937) -1.291,-3.501 cw(c-0.965,-3.826) -0.965,-3.366 0.113,-3.366 cw(c0.113,-4.215) C199.1@0.713,-3.614
PCIE_RX3_P: C200.2 U1.N4 | length 50.5
  INT8 w0.127: v5(1.233,-2.852) ccw(c1.846,-2.239) 1.846,-3.106 12.559,-3.106 cw(c12.559,-5.248) 14.073,-3.734 cw(c12.129,-5.679) 14.879,-5.679 14.879,-23.618 ccw(c17.203,-23.618) 17.203,-25.942 19,-25.942 cw(c19,-27.305) 19.964,-26.341 24.882,-31.259 ccw(c25.625,-30.516) 25.625,-31.567 27.283,-31.567 cw(c27.283,-33.288) v1(28.5,-32.071)
PCIE_RX3_P_C: C200.1 PCIE_CONN.E21 | length 5.6
  Bottom Layer w0.127: PCIE_CONN.E21@-4.632,-2.744 cw(c-4.263,-3.112) -4.263,-2.591 -1.92,-2.591 cw(c-1.92,-3.176) -1.506,-2.762 ; -1.505,-2.763 -1.291,-2.977 ccw(c-0.965,-2.65) -0.965,-3.112 0.087,-3.112 ccw(c0.087,-2.226) C200.1@0.713,-2.852
PCIE_TX0_N_C: PCIE_CONN.E11 U1.F1 | length 59.3
  INT8 w0.127: v5(-4.651,-27.477) ccw(c-4.053,-26.879) -4.053,-27.724 3.697,-27.724 cw(c3.697,-29.083) 5.055,-29.083 5.055,-33.87 cw(c3.926,-33.87) 3.926,-35 0.457,-35 ccw(c0.457,-36.445) -0.988,-36.445 -0.988,-40.676 ccw(c0.782,-40.676) 0.782,-42.446 8.626,-42.446 cw(c8.626,-44.82) 10.305,-43.141 10.865,-43.702 ccw(c12.661,-41.906) 12.661,-44.446 18.948,-44.446 ccw(c18.948,-41.906) 20.744,-43.702 21.682,-42.764 cw(c23.657,-44.74) 23.657,-41.946 24.527,-41.946 ccw(c24.527,-40.6) 25.873,-40.6 25.873,-40.164 ccw(c25.761,-40.164) 25.761,-40.052 25.682,-40.052 cw(c25.682,-39.945) 25.576,-39.945 25.576,-39.792 cw(c25.706,-39.792) 25.706,-39.662 25.787,-39.662 ccw(c25.787,-39.575) 25.873,-39.575 25.873,-39.444 ccw(c25.5,-39.444) v1(25.5,-39.071)
PCIE_TX0_P_C: PCIE_CONN.E10 U1.F2 | length 59.3
  INT8 w0.127: v5(-4.651,-28.277) cw(c-3.931,-28.997) -3.931,-27.978 3.697,-27.978 cw(c3.697,-29.083) 4.801,-29.083 4.801,-33.87 cw(c3.926,-33.87) 3.926,-34.746 0.457,-34.746 ccw(c0.457,-36.445) -1.242,-36.445 -1.242,-40.676 ccw(c0.782,-40.676) 0.782,-42.7 8.626,-42.7 cw(c8.626,-44.82) 10.125,-43.321 10.686,-43.882 ccw(c12.661,-41.906) 12.661,-44.7 18.948,-44.7 ccw(c18.948,-41.906) 20.924,-43.882 21.861,-42.944 cw(c23.657,-44.74) 23.657,-42.2 24.527,-42.2 ccw(c24.527,-40.6) 26.127,-40.6 26.127,-39.444 cw(c26.5,-39.444) v1(26.5,-39.071)
PCIE_TX1_N_C: PCIE_CONN.S18 U1.H1 | length 57.7
  INT8 w0.127: v5@-4.618,-14.816 cw(c-5.105,-14.328) -5.105,-15.018 -5.404,-15.018 cw(c-5.404,-14.605) -5.817,-14.605 -5.817,-14.224 cw(c-5.537,-14.224) -5.537,-13.945 -4.173,-13.945 cw(c-4.173,-14.351) -3.886,-14.064 ccw(c-2.024,-12.201) -2.024,-14.835 6.714,-14.835 cw(c6.714,-16.496) 8.375,-16.496 8.375,-35.941 ccw(c10.134,-35.941) 10.134,-37.7 11.968,-37.7 ccw(c11.968,-36.125) 13.082,-37.239 13.75,-36.571 cw(c14.655,-37.476) 14.655,-36.196 15.749,-36.196 cw(c15.749,-36.359) 15.864,-36.244 cw(c15.749,-36.359) 15.912,-36.359 15.912,-36.435 ccw(c16.054,-36.435) 16.054,-36.578 16.128,-36.578 ccw(c16.128,-36.42) 16.287,-36.42 ; v5@-4.618,-14.816 v5(-4.547,-14.745) ; 16.287,-36.42 16.287,-36.364 cw(c16.455,-36.364) 16.455,-36.196 16.537,-36.196 cw(c16.537,-36.321) 16.662,-36.321 16.662,-36.39 ccw(c16.805,-36.39) 16.805,-36.533 16.863,-36.533 ccw(c16.863,-36.359) 17.037,-36.359 17.037,-36.321 cw(c17.162,-36.321) 17.162,-36.196 17.271,-36.196 cw(c17.271,-36.337) 17.412,-36.337 17.412,-36.435 ccw(c17.554,-36.435) 17.554,-36.578 17.604,-36.578 ccw(c17.604,-36.396) 17.787,-36.396 17.787,-36.368 cw(c17.959,-36.368) 17.959,-36.196 18.018,-36.196 cw(c18.018,-36.339) 18.162,-36.339 18.162,-36.39 ccw(c18.333,-36.39) 18.333,-36.561 18.4,-36.561 ccw(c18.4,-36.425) 18.537,-36.425 18.537,-36.378 cw(c18.719,-36.378) 18.719,-36.196 18.887,-36.196 cw(c18.887,-37.443) 19.769,-36.561 ccw(c20.406,-35.925) 20.406,-36.825 24.805,-36.825 24.906,-36.825 cw(c24.906,-37.665) v1(25.5,-37.071)
PCIE_TX1_P_C: PCIE_CONN.S17 U1.H2 | length 57.7
  INT8 w0.127: v5(-4.547,-15.545) -4.618,-15.474 ccw(c-5.105,-15.962) -5.105,-15.272 -5.404,-15.272 cw(c-5.404,-14.605) -6.071,-14.605 -6.071,-14.224 cw(c-5.537,-14.224) -5.537,-13.691 -4.173,-13.691 cw(c-4.173,-14.351) -3.707,-13.884 ccw(c-2.024,-12.201) -2.024,-14.581 6.714,-14.581 cw(c6.714,-16.496) 8.629,-16.496 8.629,-35.941 ccw(c10.134,-35.941) 10.134,-37.446 11.968,-37.446 ccw(c11.968,-36.125) 12.903,-37.059 13.57,-36.391 cw(c14.655,-37.476) 14.655,-35.942 18.887,-35.942 cw(c18.887,-37.443) 19.949,-36.382 ccw(c20.406,-35.925) 20.406,-36.571 25.293,-36.571 cw(c25.293,-38.278) v1(26.5,-37.071)
PCIE_TX2_N_C: PCIE_CONN.S24 U1.K1 | length 58.4
  INT8 w0.127: v5(-4.6,-9.953) -4.817,-10.17 cw(c-4.953,-10.034) -4.953,-10.226 -5.217,-10.226 cw(c-5.217,-9.855) -5.588,-9.855 -5.588,-9.042 cw(c-4.572,-9.042) -4.572,-8.026 -1.799,-8.026 cw(c-1.799,-10.141) -0.304,-8.646 ccw(c1.672,-6.67) 1.672,-9.464 9.265,-9.464 cw(c9.265,-11.074) 10.875,-11.074 10.875,-30.424 ccw(c12.647,-30.424) 12.647,-32.196 19.163,-32.196 cw(c19.163,-32.883) 19.649,-32.397 19.731,-32.479 cw(c19.616,-32.595) 19.779,-32.595 cw(c19.616,-32.595) 19.731,-32.71 19.677,-32.764 ccw(c19.778,-32.865) 19.677,-32.966 19.729,-33.018 ccw(c19.841,-32.906) 19.953,-33.018 19.993,-32.979 cw(c20.111,-33.097) 20.23,-32.979 20.288,-33.036 cw(c20.2,-33.125) 20.288,-33.213 20.24,-33.262 ccw(c20.341,-33.363) 20.24,-33.464 20.281,-33.505 ccw(c20.404,-33.382) 20.527,-33.505 20.553,-33.478 cw(c20.642,-33.567) 20.73,-33.478 20.808,-33.556 cw(c20.708,-33.655) 20.808,-33.755 20.738,-33.824 ccw(c20.839,-33.925) 20.738,-34.026 20.773,-34.062 ccw(c20.902,-33.933) 21.031,-34.062 21.05,-34.042 cw(c21.172,-34.164) 21.294,-34.042 21.336,-34.084 cw(c21.235,-34.186) 21.336,-34.287 21.3,-34.323 ccw(c21.421,-34.443) 21.3,-34.564 21.348,-34.612 ccw(c21.445,-34.516) 21.541,-34.613 21.574,-34.579 cw(c21.702,-34.708) 21.831,-34.579 ccw(c22.424,-33.986) 22.424,-34.825 24.906,-34.825 cw(c24.906,-35.665) v1(25.5,-35.071)
PCIE_TX2_P_C: PCIE_CONN.S23 U1.K2 | length 58.4
  INT8 w0.127: v5(-4.6,-10.753) -4.817,-10.536 ccw(c-4.953,-10.672) -4.953,-10.48 -5.217,-10.48 cw(c-5.217,-9.855) -5.842,-9.855 -5.842,-9.042 cw(c-4.572,-9.042) -4.572,-7.772 -1.799,-7.772 cw(c-1.799,-10.141) -0.124,-8.466 ccw(c1.672,-6.67) 1.672,-9.21 9.265,-9.21 cw(c9.265,-11.074) 11.129,-11.074 11.129,-30.424 ccw(c12.647,-30.424) 12.647,-31.942 19.163,-31.942 cw(c19.163,-32.883) 19.829,-32.218 22.011,-34.4 ccw(c22.424,-33.986) 22.424,-34.571 25.293,-34.571 cw(c25.293,-36.278) v1(26.5,-35.071)
PCIE_TX3_N_C: PCIE_CONN.E18 U1.M1 | length 57.9
  INT8 w0.127: v5(-4.499,-5.153) cw(c-4.772,-5.153) -4.772,-5.426 -5.132,-5.426 cw(c-5.132,-5.174) -5.385,-5.174 -5.385,-4.15 cw(c-4.257,-4.15) -5.055,-3.353 -4.679,-2.977 cw(c-3.685,-3.972) -3.685,-2.565 -3.092,-2.565 ; -2.896,-2.565 -3.092,-2.565 ; v1(25.5,-33.071) ccw(c24.906,-33.665) 24.906,-32.825 24.579,-32.825 cw(c24.579,-31.61) 23.72,-32.469 23.528,-32.277 23.48,-32.229 ccw(c23.351,-32.358) 23.222,-32.229 23.189,-32.262 cw(c23.093,-32.166) 22.997,-32.262 22.949,-32.214 cw(c23.07,-32.093) 22.949,-31.972 22.984,-31.937 ccw(c22.883,-31.835) 22.984,-31.734 22.942,-31.692 ccw(c22.821,-31.813) 22.699,-31.692 22.679,-31.711 cw(c22.55,-31.583) 22.421,-31.711 22.386,-31.676 cw(c22.487,-31.575) 22.386,-31.474 22.456,-31.404 ccw(c22.357,-31.305) 22.456,-31.206 22.379,-31.128 ccw(c22.29,-31.216) 22.202,-31.128 22.175,-31.155 cw(c22.052,-31.032) 21.929,-31.155 21.888,-31.114 cw(c21.989,-31.013) 21.888,-30.911 21.937,-30.863 ccw(c21.848,-30.775) 21.937,-30.686 21.879,-30.628 ccw(c21.76,-30.747) 21.641,-30.628 21.602,-30.667 cw(c21.49,-30.555) 21.377,-30.667 21.325,-30.615 cw(c21.426,-30.514) 21.325,-30.414 21.38,-30.359 ccw(c21.265,-30.244) 21.427,-30.244 ccw(c21.265,-30.244) 21.38,-30.129 19.976,-28.725 ccw(c18.708,-29.993) 18.708,-28.2 16.202,-28.2 cw(c16.202,-25.373) 13.375,-25.373 13.375,-10.338 ccw(c10.835,-10.338) 12.631,-8.542 10.047,-5.958 ccw(c8.251,-7.754) 8.251,-5.214 2.222,-5.214 cw(c2.222,-2.42) 0.246,-4.396 -0.926,-3.224 ccw(c-2.515,-4.812) -2.515,-2.565 -3.092,-2.565
PCIE_TX3_P_C: PCIE_CONN.E17 U1.M2 | length 57.7
  INT8 w0.127: v5(-4.499,-5.953) ccw(c-4.772,-5.953) -4.772,-5.68 -5.132,-5.68 cw(c-5.132,-5.174) -5.639,-5.174 -5.639,-4.15 cw(c-4.257,-4.15) -5.234,-3.173 -4.859,-2.798 cw(c-3.685,-3.972) -3.685,-2.311 -2.515,-2.311 cw(c-2.515,-4.812) -0.746,-3.044 0.426,-4.216 ccw(c2.222,-2.42) 2.222,-4.96 8.251,-4.96 cw(c8.251,-7.754) 10.227,-5.778 12.811,-8.362 cw(c10.835,-10.338) 13.629,-10.338 13.629,-25.373 ccw(c16.202,-25.373) 16.202,-27.946 18.708,-27.946 cw(c18.708,-29.993) 20.155,-28.546 23.899,-32.289 ccw(c24.579,-31.61) 24.579,-32.571 25.293,-32.571 cw(c25.293,-34.278) v1(26.5,-33.071)
PGOOD1: R603.1 U99.G9 | length 1.8
  Top Layer w0.127: R603.1@14.808,4.293 14.808,4.318 v3(15.443,4.953)
  Bottom Layer w0.127: U99.G9@14.808,4.318 v3(15.443,4.953)
PGOOD1_1: R506.1 U98.C3 | length 7.8
  Top Layer w0.127: U98.C3@36.83,5.969 v3(36.83,6.545) ; v3(40.97,2.54) R506.1@41.758,2.54 R506.1@41.783,2.54
  INT2 w0.102: v3(36.83,6.545) 36.83,5.994 38.227,4.597 39.446,4.597 40.97,3.073 v3(40.97,2.54)
PGOOD1_2: R507.1 U98.C2 | length 7.9
  Top Layer w0.127: U98.C2@36.83,7.239 v3(36.83,7.815) ; v3(40.97,3.683) R507.1@41.783,3.683
  INT2 w0.102: v3(36.83,7.815) 37.381,7.264 37.381,6.765 38.227,5.918 39.37,5.918 39.802,5.486 39.802,4.851 v3(40.97,3.683)
PGOOD1_3: R508.1 U98.F2 | length 8.5
  Top Layer w0.127: R508.1@32.258,-0.94 v3(32.258,-0.127) ; v3(33.02,6.663) U98.F2@33.02,7.239
  INT2 w0.102: v3(32.258,-0.127) 32.258,5.901 v3(33.02,6.663)
PGOOD1_4: R509.1 U98.J2 | length 10.2
  Top Layer w0.127: R509.1@27.559,-0.94 R509.1@27.559,-0.889 v3(27.559,-0.127) ; U98.J2@29.21,7.239 v3(29.21,7.815)
  INT2 w0.102: v3(27.559,-0.127) 27.305,0.127 27.305,5.359 29.21,7.264 v3(29.21,7.815)
PGOOD2: R650.1 U99.G8 | length 1.8
  Top Layer w0.127: R650.1@13.538,4.369 13.589,4.369 v3(14.173,4.953)
  Bottom Layer w0.127: U99.G8@13.538,4.318 v3(14.173,4.953)
PGOOD2_1: R510.1 U97.C3 | length 9.2
  Top Layer w0.127: U97.C3@81.153,-12.192 v3(81.153,-11.616) ; R510.1@82.677,-19.228 v3(82.677,-18.466)
  INT1 w0.127: v3(81.153,-11.616) 80.721,-12.048 80.721,-15.672 82.677,-17.628 v3(82.677,-18.466)
PGOOD2_2: R511.1 U97.C2 | length 10.5
  Top Layer w0.127: U97.C2@81.153,-10.922 v3(81.153,-10.346) ; R511.1@81.534,-19.228 81.788,-18.974 v3(81.788,-18.466)
  INT1 w0.127: v3(81.153,-10.346) 80.366,-11.133 80.366,-15.842 81.788,-17.264 v3(81.788,-18.466)
PGOOD2_3: R512.1 U97.F2 | length 8.5
  Top Layer w0.127: R512.1@76.962,-19.228 v3(76.962,-18.466) ; v3(77.343,-11.498) U97.F2@77.343,-10.922
  INT1 w0.127: v3(76.962,-18.466) 76.962,-11.879 v3(77.343,-11.498)
PGOOD2_4: R513.1 U97.J2 | length 1.2
  Top Layer w0.127: U97.J2@73.533,-10.922 v3(73.533,-10.346)
  Bottom Layer w0.127: R513.1@73.355,-10.922 73.355,-10.524 v3(73.533,-10.346)
PGOOD3_1: R518.2 U96.C3 | length 7.7
  Top Layer w0.127: U96.C3@60.452,5.969 v3(60.452,6.545) ; v3(64.618,2.413) R518.2@65.329,2.413
  INT2 w0.102: v3(60.452,6.545) 61.273,6.545 62.281,5.537 62.281,5.309 64.567,3.023 64.567,2.413 v3(64.618,2.413)
PGOOD3_2: R519.2 U96.C2 | length 7.8
  Top Layer w0.127: U96.C2@60.452,7.239 v3(60.452,7.815) ; v3(64.618,3.556) R519.2@65.329,3.556
  INT2 w0.102: v3(60.452,7.815) 61.13,7.137 61.9,7.137 63.424,5.613 63.424,4.674 64.541,3.556 v3(64.618,3.556)
PGOOD3_3: R520.2 U96.F2 | length 10
  Top Layer w0.102: R520.2@47.701,7.874 v3(48.412,7.874) ; v3(56.642,6.663) U96.F2@56.642,7.239
  INT2 w0.102: v3(48.412,7.874) 48.971,7.315 55.99,7.315 v3(56.642,6.663)
PGOOD3_4: R521.2 U96.J2 | length 6.2
  Top Layer w0.102: R521.2@47.701,9.017 v3(48.412,9.017) ; U96.J2@52.832,7.239 v3(52.832,7.815)
  INT2 w0.102: v3(48.412,9.017) 48.974,8.455 52.192,8.455 v3(52.832,7.815)
PHASMD: R600.1 U99.G4 | length 2
  Top Layer w0.127: v3(7.823,4.953) 8.458,4.318 R600.1@8.458,4.14
  Bottom Layer w0.127: v3(7.823,4.953) U99.G4@8.458,4.318
QSPI_CS: J4.7 R5.1 U1.U7 U10.C2 | length 95.5
  INT8 w0.102: v1(31.5,-28.071) 32.125,-28.696 32.125,-32.196 36.375,-36.446 51.625,-36.446 51.875,-36.196 52.125,-36.196 52.375,-36.446 52.625,-36.446 52.875,-36.196 53.125,-36.196 53.375,-36.446 59,-36.446 59.625,-35.821 71.375,-35.821 71.875,-36.321 73.031,-36.321 73.281,-36.071 74.625,-36.071 75.625,-37.071 76.875,-37.071 77.5,-36.446 77.5,-32.571 75.625,-30.696 72.375,-30.696 70.5,-28.821 70.5,-26.352 v5(71.119,-25.733) 70.5,-25.114 70.5,-24.571 70.875,-24.196 72.375,-24.196 72.625,-24.446 72.625,-24.821 73,-25.196 73.5,-25.196 74,-25.696 74,-27.196 74.875,-28.071 76.25,-28.071 79.25,-31.071 79.25,-37.992 v2(79.821,-38.562)
  Bottom Layer w0.203: R5.1@70.119,-23.19 70.119,-24.733 v5(71.119,-25.733)
  Bottom Layer w0.508: J4.7@78.196,-38.563 v2(79.821,-38.562)
QSPI_FLASH_CLK: J4.8 U1.AA9 U10.B2 | length 65.9
  INT8 w0.102: v5(71.119,-24.733) 72.625,-26.239 72.625,-27.446 73.625,-28.446 76,-28.446 78.875,-31.321 78.875,-38.617 v2(79.821,-39.562)
  INT3 w0.102: v1(33.5,-24.071) 33.875,-24.446 35.625,-24.446 35.875,-24.196 36.125,-24.196 36.375,-24.446 36.625,-24.446 36.875,-24.196 37.125,-24.196 37.375,-24.446 37.625,-24.446 37.875,-24.196 38.125,-24.196 38.375,-24.446 38.625,-24.446 38.875,-24.196 39.125,-24.196 39.364,-24.435 39.637,-24.435 39.854,-24.218 40.146,-24.218 40.363,-24.435 42.364,-24.435 47.625,-29.696 52.75,-29.696 53,-29.946 55.125,-29.946 55.375,-29.696 55.625,-29.696 55.926,-29.997 67.285,-29.997 67.615,-29.667 67.615,-27.991 70.872,-24.733 v5(71.119,-24.733)
  Bottom Layer w0.508: J4.8@78.196,-39.563 v2(79.821,-39.562)
QSPI_FLASH_D2: R6.1 U1.AA7 U10.C4 | length 52.1
  INT3 w0.102: v1(31.5,-24.071) 32,-24.571 32,-25.196 32.5,-25.696 35.625,-25.696 35.875,-25.946 36.125,-25.946 36.375,-25.696 36.625,-25.696 36.875,-25.946 37.125,-25.946 37.375,-25.696 37.625,-25.696 37.875,-25.946 38.125,-25.946 38.375,-25.696 38.625,-25.696 38.875,-25.946 39.125,-25.946 39.375,-25.696 40.625,-25.696 46.375,-31.446 46.625,-31.446 46.875,-31.196 50.875,-31.196 51.125,-31.446 52.25,-31.446 53.625,-31.446 53.875,-31.196 54.125,-31.196 54.375,-31.446 54.625,-31.446 54.875,-31.196 58.125,-31.196 58.375,-31.446 58.625,-31.446 58.875,-31.196 68.456,-31.196 72.625,-27.027 72.625,-26.227 v5(73.119,-25.733)
  Bottom Layer w0.203: v5(73.119,-25.733) 73.619,-26.233 R6.1@73.619,-28.276
QSPI_FLASH_D3: R7.1 U1.Y7 U10.D4 | length 50
  INT3 w0.102: v1(31.5,-25.071) 32,-25.571 32,-26.196 32.25,-26.446 35.625,-26.446 35.875,-26.196 36.125,-26.196 36.375,-26.446 36.625,-26.446 36.875,-26.196 37.125,-26.196 37.375,-26.446 37.625,-26.446 37.875,-26.196 38.125,-26.196 38.375,-26.446 38.625,-26.446 38.875,-26.196 39.125,-26.196 39.375,-26.446 40.375,-26.446 45.875,-31.946 49.125,-31.946 49.375,-31.696 52.625,-31.696 52.875,-31.946 56.125,-31.946 56.375,-31.696 56.625,-31.696 56.875,-31.946 68.008,-31.946 73.119,-26.835 v5(73.119,-26.733)
  Bottom Layer w0.203: R7.1@72.619,-28.276 72.619,-27.233 v5(73.119,-26.733)
QSPI_FLASH_DIN_D1: J4.10 U1.AB7 U10.D2 | length 70
  INT8 w0.102: v5(71.119,-26.733) 71.119,-28.94 72.375,-30.196 76.5,-30.196 78.125,-31.821 78.125,-39.867 v2(79.821,-41.562)
  INT3 w0.102: v1(31.5,-23.071) 32,-23.571 32.625,-23.571 32.875,-23.821 32.875,-25.071 33.25,-25.446 35.625,-25.446 35.875,-25.196 37.125,-25.196 37.375,-25.446 37.625,-25.446 37.875,-25.196 38.125,-25.196 38.375,-25.446 38.625,-25.446 38.875,-25.196 39.125,-25.196 39.375,-25.446 41.375,-25.446 46.875,-30.946 47.125,-30.946 47.375,-30.696 52.75,-30.696 53,-30.946 54.125,-30.946 54.375,-30.696 54.625,-30.696 54.875,-30.946 58.125,-30.946 58.375,-30.696 58.625,-30.696 58.875,-30.946 68.405,-30.946 71.119,-28.232 v5(71.119,-26.733)
  Bottom Layer w0.508: J4.10@78.196,-41.563 v2(79.821,-41.562)
QSPI_FLASH_MOSI_D0: J4.9 U1.AC7 U10.D3 | length 68.6
  INT8 w0.102: v5(72.119,-26.733) 72.119,-27.94 73,-28.821 75.75,-28.821 78.5,-31.571 78.5,-39.242 v2(79.821,-40.562)
  INT3 w0.102: v1(31.5,-22.071) 31.875,-22.446 32.875,-22.446 33.125,-22.696 33.125,-24.321 33.5,-24.696 35.625,-24.696 35.875,-24.946 37.125,-24.946 37.375,-24.696 37.625,-24.696 37.875,-24.946 38.125,-24.946 38.375,-24.696 38.625,-24.696 38.875,-24.946 39.125,-24.946 39.375,-24.696 39.626,-24.696 39.854,-24.924 40.146,-24.924 40.374,-24.696 41.625,-24.696 47.375,-30.446 52.875,-30.446 53.125,-30.196 55.125,-30.196 55.375,-30.446 55.625,-30.446 55.86,-30.211 67.63,-30.211 70.434,-27.407 70.434,-26.67 70.783,-26.321 71.707,-26.321 v5(72.119,-26.733)
  Bottom Layer w0.508: J4.9@78.196,-40.563 v2(79.821,-40.562)
R\E\S\E\T\1\: R530.1 R533.2 U95.15 | length 3.1
  Top Layer w0.203: U95.15@80.767,1.889 82.712,1.889 R530.1@82.728,1.905 R533.2@82.728,3.048
R\E\S\E\T\2\: R529.1 R535.2 R537.2 U95.16 | length 4.2
  Top Layer w0.203: U95.16@79.867,2.789 79.867,3.21 R529.1@80.899,4.242 R535.2@82.042,4.242 R537.2@83.185,4.242
R\E\S\E\T\3\: R528.1 R539.2 R541.2 R743.2 U95.17 | length 5.2
  Top Layer w0.203: U95.17@79.367,2.789 79.367,3.497 79.756,3.886 R528.1@79.756,4.317 79.756,5.415 R539.2@79.71,5.461 79.71,6.599 R541.2@79.705,6.604 80.696,6.604 R743.2@80.823,6.477
R\E\S\E\T\4\: R527.1 R545.2 R547.2 R549.2 U95.18 | length 7.1
  Top Layer w0.203: R549.2@75.565,5.639 76.251,4.953 77.165,4.953 R545.2@77.673,5.461 ; R547.2@77.673,6.604 R545.2@77.673,5.461 ; U95.18@78.867,2.789 78.867,3.378 78.41,3.835 78.156,3.835 R527.1@77.673,4.318 R545.2@77.673,5.461
RSTO#: U1.AD16
  other v1: 40.5,-21.071
SCL_EEPROM: U1.A28 U19.1 | length 21.4
  Top Layer w0.381: v2(68.806,-36.659) U19.1@69.781,-36.659
  INT7 w0.102: v1(52.5,-44.071) 52.875,-43.696 53.625,-43.696 54.875,-44.946 58.125,-44.946 66.125,-36.946 68.519,-36.946 v2(68.806,-36.659)
SCLK: J4.5 R135.2 U22.19 | length 92.1
  Top Layer w0.203: v2(7.957,-45.301) 8.625,-45.301 9.3,-45.976 U22.19@9.3,-46.301
  INT4 w0.102: v2(7.957,-45.301) 11.584,-45.301 13.25,-46.967 13.25,-48.446 16.125,-51.321 39.771,-51.321 40.521,-50.571 54.125,-50.571 54.875,-51.321 69.625,-51.321 78.625,-42.321 78.625,-35.821 79.375,-35.071 80.082,-35.071 80.375,-35.364 80.375,-36.008 v2(79.821,-36.562)
  Bottom Layer w0.508: J4.5@78.196,-36.563 v2(79.821,-36.562)
SDA_EEPROM: U1.A27 U19.3 | length 24.6
  Top Layer w0.381: v2(68.806,-38.559) U19.3@69.781,-38.559
  INT7 w0.102: v1(51.5,-44.071) 51.5,-46.696 51.875,-47.071 57,-47.071 65.125,-38.946 68.419,-38.946 v2(68.806,-38.559)
SDATA: J4.4 R134.2 U22.20 | length 89
  Top Layer w0.203: v2(7.957,-46.301) 8.457,-46.801 U22.20@9.3,-46.801
  INT4 w0.102: v2(7.957,-46.301) 8.062,-46.196 12.125,-46.196 13,-47.071 13,-48.55 16.021,-51.571 39.875,-51.571 40.625,-50.821 54.021,-50.821 54.771,-51.571 69.875,-51.571 79,-42.446 79,-40.446 79,-36.383 v2(79.821,-35.562)
  Bottom Layer w0.508: J4.4@78.196,-35.563 v2(79.821,-35.562)
SENSE1: D14.2 R639.1 R640.1 U95.10 | length 4.6
  Top Layer w0.203: U95.10@79.867,-1.011 79.867,-1.33 80.061,-1.524 81.243,-1.524 81.624,-1.143 v3(81.737,-1.143) R639.1@82.347,-1.143
  Bottom Layer w0.203: D14.2@80.899,-1.36 81.116,-1.143 v3(81.737,-1.143) R640.1@82.347,-1.143
SENSE2: D13.2 R632.1 R638.1 U95.9 | length 7.1
  Top Layer w0.203: U95.9@79.367,-1.011 79.367,-1.562 79.734,-1.929 v3(79.807,-1.929) 81.989,-1.929 R632.1@82.347,-2.286
  Bottom Layer w0.203: D13.2@79.756,-1.323 79.756,-1.878 v3(79.807,-1.929) 79.936,-2.057 82.042,-2.057 82.271,-2.286 R638.1@82.347,-2.286
SENSE3: D12.2 R631.2 R636.1 U95.8 | length 4
  Top Layer w0.203: U95.8@78.867,-1.011 78.867,-1.651 v3(79.043,-1.827) R631.2@79.756,-2.54
  Bottom Layer w0.203: R636.1@77.47,-1.041 78.613,-1.041 D12.2@78.613,-1.195 78.613,-1.397 v3(79.043,-1.827)
SENSE4H: R634.1 R740.2 U95.6 | length 3.3
  Top Layer w0.203: v3(76.53,-1.956) R634.1@76.53,-2.54 R740.2@77.648,-2.54 77.867,-2.321 U95.6@77.867,-1.011
SENSE4L: D11.2 R532.1 R740.1 U95.7 | length 5.6
  Top Layer w0.203: U95.7@78.367,-1.011 78.367,-1.811 78.359,-1.819 v3(78.359,-2.032) 78.359,-2.337 R740.1@78.562,-2.54
  Bottom Layer w0.203: D11.2@75.489,-2.276 76.215,-2.276 77.038,-3.099 77.8,-3.099 78.334,-2.565 R532.1@78.334,-2.54 78.359,-2.515 v3(78.359,-2.032)
SGND_1: C518.1 C520.1 FB4.2 R502.1 R504.2 R605.1 R607.1 R609.1 R611.1 U98.F7 | length 4.2
  Top Layer w0.127: v3(33.02,0.313) U98.F7@33.02,0.889
  Top Layer w0.381: v4(28.702,-2.515) R504.2@28.702,-1.803
  Bottom Layer w0.381: v3(25.73,-1.778) R611.1@26.365,-1.778 ; R609.1@29.845,-1.854 29.845,-2.057 30.378,-2.591 v4(30.912,-2.591)
  Bottom Layer w0.508: v4(32.258,-2.616) C520.1@32.258,-1.854
  other v4: 35.433,-2.321 35.433,-1.778 35.433,-1.168
SGND_2: C528.1 C529.1 C530.1 C531.1 FB5.2 R514.2 R515.1 R516.2 R517.1 R613.1 R615.1 R617.1 R619.1 U97.F7 | length 12.8
  Top Layer w0.127: v3(77.343,-17.848) U97.F7@77.343,-17.272
  Top Layer w0.381: v4(80.772,-20.701) 80.772,-20.574 R515.1@80.391,-20.193 ; R515.1@80.391,-20.193 80.366,-20.168 R515.1@80.391,-20.142 R515.1@80.391,-20.193
  Top Layer w0.508: v4(72.136,-21.057) R619.1@72.136,-20.142 ; R517.1@73.533,-20.117 R517.1@73.533,-20.142 73.547,-20.156 v4(73.547,-21.26) ; v4(75.819,-20.701) R516.2@75.819,-20.142 ; R514.2@83.82,-20.142 v4(84.531,-20.142)
  Bottom Layer w0.254: C530.1@76.441,-16.37 76.441,-16.725 v3(76.454,-16.739) ; C529.1@79.433,-16.452 79.556,-16.452 79.572,-16.436 v3(79.832,-16.696) ; C528.1@83.243,-16.452 83.529,-16.739 84.15,-16.739 v4(84.455,-16.434)
  Bottom Layer w0.508: C531.1@73.812,-17.018 C531.1@73.831,-17.036 74.099,-17.304 74.099,-17.697 v3(74.092,-17.704) ; R617.1@74.676,-20.142 75.26,-20.142 v4(75.819,-20.701) ; R615.1@78.105,-20.142 79.858,-20.142 80.416,-20.701 v4(80.772,-20.701) ; R613.1@83.82,-20.142 v4(84.531,-20.142)
  other v3: 78.791,-21.539 82.042,-21.463 72.974,-18.009 84.607,-17.297 84.506,-14.961 84.506,-13.716
  other v4: 80.218,-20.701 80.213,-20.168 80.767,-20.168
SGND_3: C538.1 C540.1 FB6.2 R522.2 R524.2 R653.1 R654.1 R655.1 R656.1 U96.F7 | length 6.9
  Top Layer w0.127: 50.114,2.616 50.51,2.616 ; 56.515,10.221 56.515,10.008 56.744,9.779 56.975,9.779 ; v3(56.642,0.313) U96.F7@56.642,0.889
  Top Layer w0.381: R524.2@51.486,-0.635 v4(51.537,-0.635) ; v4(56.718,-1.37) C540.1@56.718,-0.659 ; C538.1@60.909,-0.635 v4(61.62,-0.635)
  Bottom Layer w0.381: R656.1@50.292,2.159 50.546,2.159 v3(50.927,1.778) ; v4(53.264,-1.27) 53.264,-1.016 R655.1@53.645,-0.635 ; v3(62.332,1.219) R653.1@62.941,1.219 ; v3(62.357,0.33) 62.56,0.127 R522.2@62.941,0.127
  Bottom Layer w0.508: v4(58.496,0.051) 58.826,-0.279 R654.1@58.826,-0.635
  other v3: 64,5.461 49.606,7.823
  other v4: 52.299,-1.448 51.638,-1.219
SGND_4: C510.1 FB3.2 R500.1 R501.1 R600.2 U99.C7 U99.D6 U99.F4 U99.F6 U99.F7 U99.G6 U99.G7 | length 10.6
  Top Layer w0.381: v3(7.823,2.413) 8.458,3.048 R600.2@8.458,3.226 ; v3(10.363,-0.127) 10.363,0.203 10.617,0.457 R500.1@10.973,0.457 ; FB3.2@11.862,-2.032 11.875,-2.019 11.908,-2.019 12.268,-1.658 R501.1@12.268,-0.483 ; C510.1@13.538,-0.254 13.919,-0.254 v3(14.097,-0.432)
  Bottom Layer w0.127: v3(10.363,2.413) U99.F6@10.998,3.048 ; v3(10.363,4.953) U99.G6@10.998,4.318 ; U99.F7@12.268,3.048 v3(12.903,2.413) ; U99.G7@12.268,4.318 v3(12.903,4.953)
  Bottom Layer w0.381: v3(7.823,2.413) U99.F4@8.458,3.048 ; v3(10.363,-0.127) U99.D6@10.998,0.508 ; v3(11.707,-1.194) 12.139,-0.762 U99.C7@12.268,-0.762
  other v3: 12.25,-1.264
SMClk: PCIE_CONN.E23 R120.1 U21.12 | length 23.7
  Top Layer w0.203: v2(0.419,-21.295) 0.808,-20.906 U21.12@1.793,-20.906
  INT1 w0.127: v5(-4.597,-1.168) -2.6,-3.166 -2.6,-15 -1.069,-16.531 -1.069,-19.807 v2(0.419,-21.295)
SMDat: PCIE_CONN.E24 R121.1 U21.11 | length 23.5
  Top Layer w0.203: v2(0.419,-20.406) U21.11@1.793,-20.406
  INT1 w0.127: v5(-4.648,-0.356) -2.2,-2.804 -2.2,-14.6 -0.6,-16.2 -0.6,-18 0.419,-19.019 v2(0.419,-20.406)
SW1: TP716.1 U99.G2 | length 2.1
  Top Layer w0.127: v3(5.283,4.953) 5.969,4.267 TP716.1@5.969,4.064
  Bottom Layer w0.127: v3(5.283,4.953) U99.G2@5.918,4.318
SW2: TP717.1 U99.G11 | length 3.8
  INT1 w0.127: v3(17.983,4.953) 18.518,4.953 19.865,6.299 TP717.1@20.371,6.299
  Bottom Layer w0.127: U99.G11@17.348,4.318 v3(17.983,4.953)
SYSCLK_300_N: C210.1 R72.2 R74.1 R137.2 U1.G12 | length 58.4
  INT7 w0.102: v2(-3.625,-45.594) ccw(c-3.297,-45.594) -3.297,-45.922 -3.246,-45.922 ccw(c-3.246,-45.801) -3.125,-45.801 -3.125,-45.683 cw(c-3.011,-45.683) -3.011,-45.569 cw(c-3.011,-45.705) -2.875,-45.705 -2.875,-45.801 ccw(c-2.754,-45.801) -2.754,-45.922 ccw(c-2.754,-45.793) -2.625,-45.793 -2.625,-45.683 cw(c-2.511,-45.683) -2.511,-45.569 cw(c-2.511,-45.705) -2.375,-45.705 -2.375,-45.801 ccw(c-2.254,-45.801) -2.254,-45.922 ccw(c-2.254,-45.793) -2.125,-45.793 -2.125,-45.683 cw(c-2.011,-45.683) -2.011,-45.569 cw(c-2.011,-45.705) -1.875,-45.704 -1.875,-45.801 ccw(c-1.754,-45.801) -1.754,-45.922 -0.25,-45.922 cw(c-0.25,-46.551) 0.379,-46.551 0.379,-48.341 ccw(c1.214,-48.341) 1.214,-49.176 13.358,-49.176 cw(c13.358,-51.97) 14.65,-49.493 cw(c13.358,-51.97) 15.334,-49.994 16.042,-50.702 ccw(c17.838,-48.906) 17.838,-51.446 35.587,-51.446 ccw(c35.587,-50.158) 36.875,-50.158 36.875,-38.976 ccw(c35.595,-38.976) v1(36.5,-38.071)
SYSCLK_300_P: C209.1 R71.2 R73.1 R137.1 U1.H12 | length 58.4
  INT7 w0.102: v2(-3.625,-46.508) cw(c-3.293,-46.508) -3.293,-46.176 -0.25,-46.176 cw(c-0.25,-46.551) 0.125,-46.551 0.125,-48.341 ccw(c1.214,-48.341) 1.214,-49.43 13.358,-49.43 cw(c13.358,-51.97) 14.491,-49.697 cw(c13.358,-51.97) 15.154,-50.174 15.862,-50.882 ccw(c17.838,-48.906) 17.838,-51.7 35.587,-51.7 ccw(c35.587,-50.158) 37.129,-50.158 37.129,-38.59 ccw(c34.981,-38.59) v1(36.5,-37.071)
TEMP: RT.1 U99.J6 | length 1.8
  Top Layer w0.127: v3(10.363,7.493) 10.998,6.858 RT.1@11.049,6.858
  Bottom Layer w0.127: v3(10.363,7.493) U99.J6@10.998,6.858
TRACK1_1: C518.2 U98.A6 U98.D6 | length 6.2
  Top Layer w0.127: v3(35.56,1.583) U98.D6@35.56,2.159 ; U98.A6@39.37,2.159 v3(39.37,2.735)
  INT2 w0.127: v3(35.56,1.583) 38.218,1.583 v3(39.37,2.735)
  Bottom Layer w0.127: C518.2@38.735,2.489 38.981,2.735 v3(39.37,2.735)
TRACK1_3: C520.2 U98.G6 U98.K6 | length 9.7
  Top Layer w0.127: v3(27.94,1.583) U98.K6@27.94,2.159 ; v3(31.623,-0.787) 31.598,-0.762 31.598,-0.051 32.207,0.559 32.207,1.854 31.902,2.159 U98.G6@31.75,2.159 v3(31.75,2.735)
  INT2 w0.127: v3(27.94,1.583) 28.793,1.583 29.646,2.436 31.451,2.436 v3(31.75,2.735)
  Bottom Layer w0.127: v3(31.623,-0.787) 31.623,-0.838 31.725,-0.94 C520.2@32.258,-0.94
TRACK2_1: C528.2 U97.A6 | length 1.1
  Top Layer w0.127: U97.A6@83.693,-16.002 83.693,-15.475 v3(83.75,-15.418)
  Bottom Layer w0.127: C528.2@83.75,-15.945 C528.2@83.75,-15.598 ; C528.2@83.75,-15.598 v3(83.75,-15.418)
TRACK2_2: C529.2 U97.D6 | length 1.8
  Top Layer w0.127: U97.D6@79.883,-16.002 v3(80.493,-16.612)
  Bottom Layer w0.127: C529.2@79.94,-15.945 79.94,-16.059 v3(80.493,-16.612)
TRACK2_3: C530.2 U97.G6 | length 1.2
  Top Layer w0.127: U97.G6@76.073,-16.002 v3(76.073,-15.426)
  Bottom Layer w0.127: C530.2@76.073,-16.002 v3(76.073,-15.426)
TRACK2_4: C531.2 U97.K6 | length 1.1
  Top Layer w0.127: U97.K6@72.263,-16.002 72.659,-16.002 v3(72.839,-16.002)
  Bottom Layer w0.127: v3@72.847,-16.002 73.184,-16.339 C531.2@73.184,-16.39
TRACK3_1: C538.2 U96.A6 U96.D6 | length 8.6
  Top Layer w0.127: v3(59.182,1.583) U96.D6@59.182,2.159 59.792,1.549 59.792,-0.432 C538.2@59.995,-0.635 ; U96.A6@62.992,2.159 v3(62.992,2.735)
  INT2 w0.102: v3(59.182,1.583) 61.84,1.583 v3(62.992,2.735)
TRACK3_3: C540.2 U96.G6 U96.K6 | length 8.5
  Top Layer w0.127: v3(51.562,1.583) U96.K6@51.562,2.159 ; v3(55.372,2.735) U96.G6@55.372,2.159 55.956,1.575 55.956,-0.483 C540.2@55.804,-0.635
  INT2 w0.127: v3(51.562,1.583) 52.138,2.159 54.796,2.159 v3(55.372,2.735)
V_OUT: C500.2 C501.2 C502.2 C503.2 C504.2 C505.2 C506.2 C507.2 LVK12.3 R601.1 U99.A1 U99.A2 U99.A3 U99.A4 U99.A5 U99.A8 U99.A9 U99.A10 U99.A11 U99.A12 U99.B1 U99.B2 U99.B3 U99.B4 U99.B5 U99.B8 U99.B9 U99.B10 U99.B11 U99.B12 U99.C1 U99.C2 U99.C3 U99.C4 U99.C9 U99.C10 U99.C11 U99.C12 U99.E8 | length 28.5
  Top Layer w0.381: v3(8.128,-1.27) R601.1@8.636,-0.762
  Bottom Layer w0.127: v3(3.901,-4.064) 3.901,-4.05 U99.A1@4.648,-3.302 ; v3(4.013,-1.397) U99.C1@4.648,-0.762 ; v3@4.191,-2.489 U99.B1@4.648,-2.032 4.623,-2.032 U99.B1@4.648,-2.057 ; U99.B1@4.42,-1.981 U99.B1@4.572,-1.981 ; v3(5.2,-4.064) 5.2,-4.02 U99.A2@5.918,-3.302 ; v3(5.283,-1.397) U99.C2@5.918,-0.762 ; v3(5.436,-2.413) 5.537,-2.413 U99.B2@5.918,-2.032 ; v3(6.477,-4.064) 6.477,-4.013 U99.A3@7.188,-3.302 ; v3(6.553,-1.397) U99.C3@7.188,-0.762 ; v3@6.731,-2.489 U99.B3@7.188,-2.032 ; v3(7.747,-4.064) 7.747,-4.013 U99.A4@8.458,-3.302 ; v3@8.001,-2.489 U99.B4@8.458,-2.032 ; v3(8.128,-1.27) 8.128,-1.092 U99.C4@8.458,-0.762 ; v3(8.89,-4.191) 8.89,-4.14 U99.A5@9.728,-3.302 ; v3@9.271,-2.489 v3@9.309,-2.451 ; v3(9.271,-2.413) 9.652,-2.032 U99.B5@9.728,-2.032 ; U99.A8@13.538,-3.302 v3(14.173,-2.667) U99.B8@13.538,-2.032 ; U99.A9@14.808,-3.302 v3(15.443,-3.937) ; U99.B9@14.808,-2.032 v3(15.443,-2.667) ; U99.C9@14.808,-0.762 v3(15.443,-1.397) ; U99.A10@16.078,-3.302 v3(16.713,-3.937) ; U99.B10@16.078,-2.032 v3(16.713,-2.667) ; U99.C10@16.078,-0.762 v3(16.713,-1.397) ; U99.A11@17.348,-3.302 v3(17.983,-3.937) ; U99.B11@17.348,-2.032 v3(17.983,-2.667) U99.A12@18.618,-3.302 ; U99.C11@17.348,-0.762 v3(17.983,-1.397) ; U99.B12@18.618,-2.032 19.329,-2.032 v4(19.406,-2.108) ; U99.C12@18.618,-0.762 19.38,-0.762 v4(19.406,-0.737)
  Bottom Layer w0.254: U99.E8@13.538,1.778 14.173,1.143 14.173,0.279 14.808,-0.356 U99.C9@14.808,-0.762
  other v3: 4.153,-2.413 6.731,-2.413 8,-2.413 -1.905,6.959 -1.173,6.959 -2.717,6.984 -0.406,6.984 -1.93,7.517 -1.198,7.517 -2.743,7.543 -0.431,7.543 -1.93,8.178 -1.198,8.178 -2.743,8.203 -0.431,8.203 -1.93,8.838 -1.198,8.838 -2.743,8.864 -0.431,8.864
  other v4: 20.117,-2.108 19.406,-1.422 20.117,-1.422 20.117,-0.737
V_OUTS2: TP720.1 U99.C8 U99.F8 | length 6.8
  Top Layer w0.127: TP720.1@13.716,3.073 13.716,2.87 v3(14.173,2.413) 14.58,2.007 14.58,-0.991 v3(14.173,-1.397)
  Bottom Layer w0.127: U99.C8@13.538,-0.762 v3(14.173,-1.397) ; U99.F8@13.538,3.048 v3(14.173,2.413)
VCC: C111.2 C112.2 C139.2 C140.2 C141.2 C145.2 C146.2 C147.2 C151.2 C152.2 C153.2 C157.2 C158.2 C159.2 C163.2 C164.2 C165.2 C169.2 C170.2 C171.2 C175.2 C176.2 C177.2 C213.2 C214.2 C215.2 CS41.2 CS42.2 CS43.2 CS45.2 CS46.2 CS47.2 CS48.2 CS49.2 CS50.2 CS53.2 CS54.2 CS55.2 CS56.2 CS57.2 CS58.2 CS59.2 CS60.2 CS61.2 CS62.2 CS63.2 CS67.2 CS68.2 CS71.2 CS72.2 CS73.2 CS74.2 CS75.2 CS76.2 CS77.2 CS78.2 CS79.2 CS80.2 CS83.2 CS84.2 CS85.2 CS86.2 CS87.2 CS88.2 CS91.2 CS92.2 CS93.2 CS94.2 CS95.2 CS96.2 CS97.2 CS98.2 CS99.2 CS100.2 CS101.2 CS102.2 CS104.2 CS106.2 CS107.2 CS108.2 CS109.2 J5.1 L7.1 R107.2 R114.1 R115.1 R119.2 R120.2 R121.2 R134.1 R135.1 R142.1 RT9.3 U1.AG8 U1.AK9 U1.AN10 U2.C2 U2.C4 U2.C11 U2.C13 U2.D3 U2.D12 U2.F4 U2.F11 U2.H4 U2.H11 U2.J4 U2.J11 U2.K4 U2.K11 U2.N3 U2.N12 U2.P2 U2.P4 U2.P11 U2.P13 U3.C2 U3.C4 U3.C11 U3.C13 U3.D3 U3.D12 U3.F4 U3.F11 U3.H4 U3.H11 U3.J4 U3.J11 U3.K4 U3.K11 U3.N3 U3.N12 U3.P2 U3.P4 U3.P11 U3.P13 U4.C2 U4.C4 U4.C11 U4.C13 U4.D3 U4.D12 U4.F4 U4.F11 U4.H4 U4.H11 U4.J4 U4.J11 U4.K4 U4.K11 U4.N3 U4.N12 U4.P2 U4.P4 U4.P11 U4.P13 U5.C2 U5.C4 U5.C11 U5.C13 U5.D3 U5.D12 U5.F4 U5.F11 U5.H4 U5.H11 U5.J4 U5.J11 U5.K4 U5.K11 U5.N3 U5.N12 U5.P2 U5.P4 U5.P11 U5.P13 U6.C2 U6.C4 U6.C11 U6.C13 U6.D3 U6.D12 U6.F4 U6.F11 U6.H4 U6.H11 U6.J4 U6.J11 U6.K4 U6.K11 U6.N3 U6.N12 U6.P2 U6.P4 U6.P11 U6.P13 U7.C2 U7.C4 U7.C11 U7.C13 U7.D3 U7.D12 U7.F4 U7.F11 U7.H4 U7.H11 U7.J4 U7.J11 U7.K4 U7.K11 U7.N3 U7.N12 U7.P2 U7.P4 U7.P11 U7.P13 U8.C2 U8.C4 U8.C11 U8.C13 U8.D3 U8.D12 U8.F4 U8.F11 U8.H4 U8.H11 U8.J4 U8.J11 U8.K4 U8.K11 U8.N3 U8.N12 U8.P2 U8.P4 U8.P11 U8.P13 U9.C2 U9.C4 U9.C11 U9.C13 U9.D3 U9.D12 U9.F4 U9.F11 U9.H4 U9.H11 U9.J4 U9.J11 U9.K4 U9.K11 U9.N3 U9.N12 U9.P2 U9.P4 U9.P11 U9.P13 U21.14 | length 8.4
  Top Layer w0.254: U21.14@2.768,-22.131 2.793,-22.156 3.379,-22.156 v2(3.386,-22.164) ; U4.J11@41,-14.571 v1(42,-14.571)
  Top Layer w0.508: v2(76.57,-41.563) J5.1@78.196,-41.563
  Bottom Layer w0.254: C177.2@17.653,-5.029 17.653,-5.224 v1(18,-5.571) ; v1(18,-7.571) 18.034,-7.605 CS58.2@18.034,-7.989 ; v1(33.5,-15.071) 34,-14.571 34,-12.571 U1.AN10@34.5,-12.071
  Bottom Layer w0.508: C112.2@2.768,-22.164 v2(3.386,-22.164)
  other v1: 18,-48.571 29,-48.571 54,-48.571 65,-48.571 19,-47.571 28,-47.571 55,-47.571 64,-47.571 18,-46.571 22,-46.571 23,-46.571 24,-46.571 26,-46.571 29,-46.571 54,-46.571 58,-46.571 59,-46.571 60,-46.571 62,-46.571 65,-46.571 54,-39.571 58,-39.571 59,-39.571 60,-39.571 62,-39.571 65,-39.571 55,-38.571 64,-38.571 54,-37.571 65,-37.571 36,-32.571 47,-32.571 54,-32.571 65,-32.571 37,-31.571 46,-31.571 55,-31.571 64,-31.571 36,-30.571 40,-30.571 41,-30.571 42,-30.571 44,-30.571 47,-30.571 54,-30.571 58,-30.571 59,-30.571 60,-30.571 62,-30.571 65,-30.571 18,-23.571 22,-23.571 23,-23.571 24,-23.571 26,-23.571 29,-23.571 36,-23.571 40,-23.571 41,-23.571 42,-23.571 44,-23.571 47,-23.571 54,-23.571 58,-23.571 59,-23.571 60,-23.571 62,-23.571 65,-23.571 19,-22.571 28,-22.571 37,-22.571 46,-22.571 55,-22.571 64,-22.571 18,-21.571 29,-21.571 36,-21.571 47,-21.571 54,-21.571 65,-21.571 32.5,-18.071 18,-16.571 29,-16.571 36,-16.571 47,-16.571 54,-16.571 65,-16.571 19,-15.571 28,-15.571 37,-15.571 46,-15.571 55,-15.571 64,-15.571 18,-14.571 22,-14.571 23,-14.571 24,-14.571 26,-14.571 29,-14.571 36,-14.571 40,-14.571 44,-14.571 47,-14.571 54,-14.571 58,-14.571 59,-14.571 60,-14.571 62,-14.571 65,-14.571 22,-7.571 23,-7.571 24,-7.571 26,-7.571 29,-7.571 36,-7.571 40,-7.571 41,-7.571 42,-7.571 44,-7.571 47,-7.571 54,-7.571 58,-7.571 59,-7.571 60,-7.571 62,-7.571 65,-7.571 19,-6.571 28,-6.571 37,-6.571 46,-6.571 55,-6.571 64,-6.571 29,-5.571 36,-5.571 47,-5.571 54,-5.571 65,-5.571
  other v2: 10.793,-51.551 6.149,-51.359 6.86,-51.362 6.147,-50.749 6.858,-50.753 6.425,-50.067 7.043,-46.301 7.043,-45.301 7.043,-44.285 79.024,-27.571 3.4,-23.8 2.8,-23 -0.495,-22.184 -0.495,-19.39 43,-4.446 43.875,-4.446 43,-3.696 43.875,-3.696
  other v4: 43.612,2.515 44.45,2.616 45.364,2.642 43.866,3.226 45.669,3.353 44.704,3.454 45.364,4.064 43.536,4.089 44.272,4.089 42.926,4.47 42.85,5.156 43.586,5.156 42.871,6.02 43.608,6.02
  other v6: 18,-39.571 22,-39.571 23,-39.571 24,-39.571 26,-39.571 29,-39.571 19,-38.571 28,-38.571 18,-37.571 29,-37.571 18,-32.571 29,-32.571 19,-31.571 28,-31.571 18,-30.571 22,-30.571 23,-30.571 24,-30.571 26,-30.571 29,-30.571
VCC_EN: R547.1 R548.2 U98.C6 U98.F6 | length 50.5
  Top Layer w0.127: v3(33.02,1.583) U98.F6@33.02,2.159 ; U98.C6@36.83,2.159 v3(36.83,2.735)
  Top Layer w0.203: R547.1@76.759,6.604 v3(76.759,7.239)
  INT1 w0.102: v3(33.02,1.583) 33.13,1.583 33.63,2.083 36.178,2.083 v3(36.83,2.735) 36.838,2.735 37.592,1.981 45.491,1.981 46.603,3.093 46.603,5.029 48.661,7.087 73.838,7.087 74.143,6.782 76.302,6.782 v3(76.759,7.239)
  Bottom Layer w0.203: R548.2@76.759,6.604 v3(76.759,7.239)
VCC_F: J4.2 R5.2 R11.1 U10.B4 | length 23.1
  INT8 w0.203: v5(73.119,-24.733) 73.912,-24.733 75,-25.821 79.618,-25.821 80.75,-26.953 80.75,-32.633 v2(79.821,-33.562)
  Bottom Layer w0.203: R5.2@70.119,-22.276 R11.1@72.619,-22.276 73.162,-22.276 73.619,-22.733 73.619,-24.233 v5(73.119,-24.733)
  Bottom Layer w0.508: J4.2@78.196,-33.563 v2(79.821,-33.562)
VCC_FB: C233.1 C234.1 C235.1 L7.2 U22.1 U22.3 U22.6 U22.12 U22.17 U22.21 | length 5.3
  Top Layer w0.203: v5(8.5,-47.301) U22.21@9.3,-47.301 ; v2(10,-50.358) U22.1@10,-49.501 ; v5(10.125,-44.676) 10.5,-45.051 U22.17@10.5,-45.601 ; v2(11,-50.358) U22.3@11,-49.501 ; v2(12.5,-50.358) U22.6@12.5,-49.501 ; U22.12@13.2,-46.301 v2(14.057,-46.301)
  other v2: 7.8,-51.384 8.511,-51.388 7.798,-50.775 8.509,-50.778 8.075,-50.067
VCCAUX: C131.2 C132.2 C133.2 C134.2 RT7.3 U1.AA8 U1.AB19 U1.AC8 U1.AC18 U1.M19 U1.N18 U1.P19 U1.R20 U1.T19 U1.U8 U1.U20 U1.V19 U1.W8 U1.W20 U1.Y19 | length 9.7
  INT1 w0.102: 42.5,-22.57 43.001,-23.071 v1(43.5,-23.071) 43.5,-22.572 42.999,-22.071 v1(42.5,-22.071) 42.5,-22.57
  INT2 w0.102: v1@43.441,-23.012 v1(43.5,-23.071) ; v1(43.5,-23.071) 43.5,-22.57 43.001,-22.071 v1(42.5,-22.071) 42.5,-22.57 43.001,-23.071 v1(43.5,-23.071)
  Bottom Layer w0.254: U1.U8@32.5,-28.093 v1(32.5,-28.071)
  Bottom Layer w0.508: v3(74.168,-6.756) 74.157,-6.745 v3(74.157,-6.169) v3(74.157,-5.695) 75.373,-4.479 RT7.3@75.373,-4.467
  other v1: 66,-48.571 16,-47.571 16,-46.571 43.5,-33.071 66,-32.571 42.5,-32.071 43.5,-31.071 44.5,-30.071 43.5,-29.071 44.5,-28.071 43.5,-27.071 32.5,-26.071 44.5,-26.071 43.5,-25.071 32.5,-24.071 32.5,-22.071
  other v2: 61.25,-50.696 62,-50.696 61.25,-49.946 62,-49.946
  other v3: 75.006,-5.614
VCCAUX_EN: R539.1 R540.2 U97.J6 | length 25.6
  Top Layer w0.127: U97.J6@73.533,-16.002 v3(73.533,-15.426) ; v3(78.791,5.963) 78.796,5.958 R539.1@78.796,5.461
  INT1 w0.127: v3(73.533,-15.426) 73.533,-15.342 73.025,-14.834 73.025,-3.603 75.209,-1.419 75.209,2.381 v3(78.791,5.963)
  Bottom Layer w0.127: v3(78.791,5.963) 78.796,5.958 R540.2@78.796,5.461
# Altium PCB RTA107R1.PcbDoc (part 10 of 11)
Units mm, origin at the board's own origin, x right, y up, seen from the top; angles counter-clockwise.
Board outline 96.01 x 65.66 mm, 22 copper layers (Top Layer, GND1, INT1, PWR1-(VCCIO_MRAM), INT2, PWR2-(VCCINT), INT3, PWR3_(12V_MGTAVCC), INT4, GND2-(DGND_SGND), PWR4_(MGTAVTT_VCCBRAM,VCCAUX), PWR5-(VCC_12V), GND3-(DGND_GND), INT5, GND4, INT6, PWR6_(VCCO), INT7, GND5, INT8, GND6, Bottom Layer), stack 2.833 mm thick; 614 components, 659 nets, 4037 pads, 3511 vias.

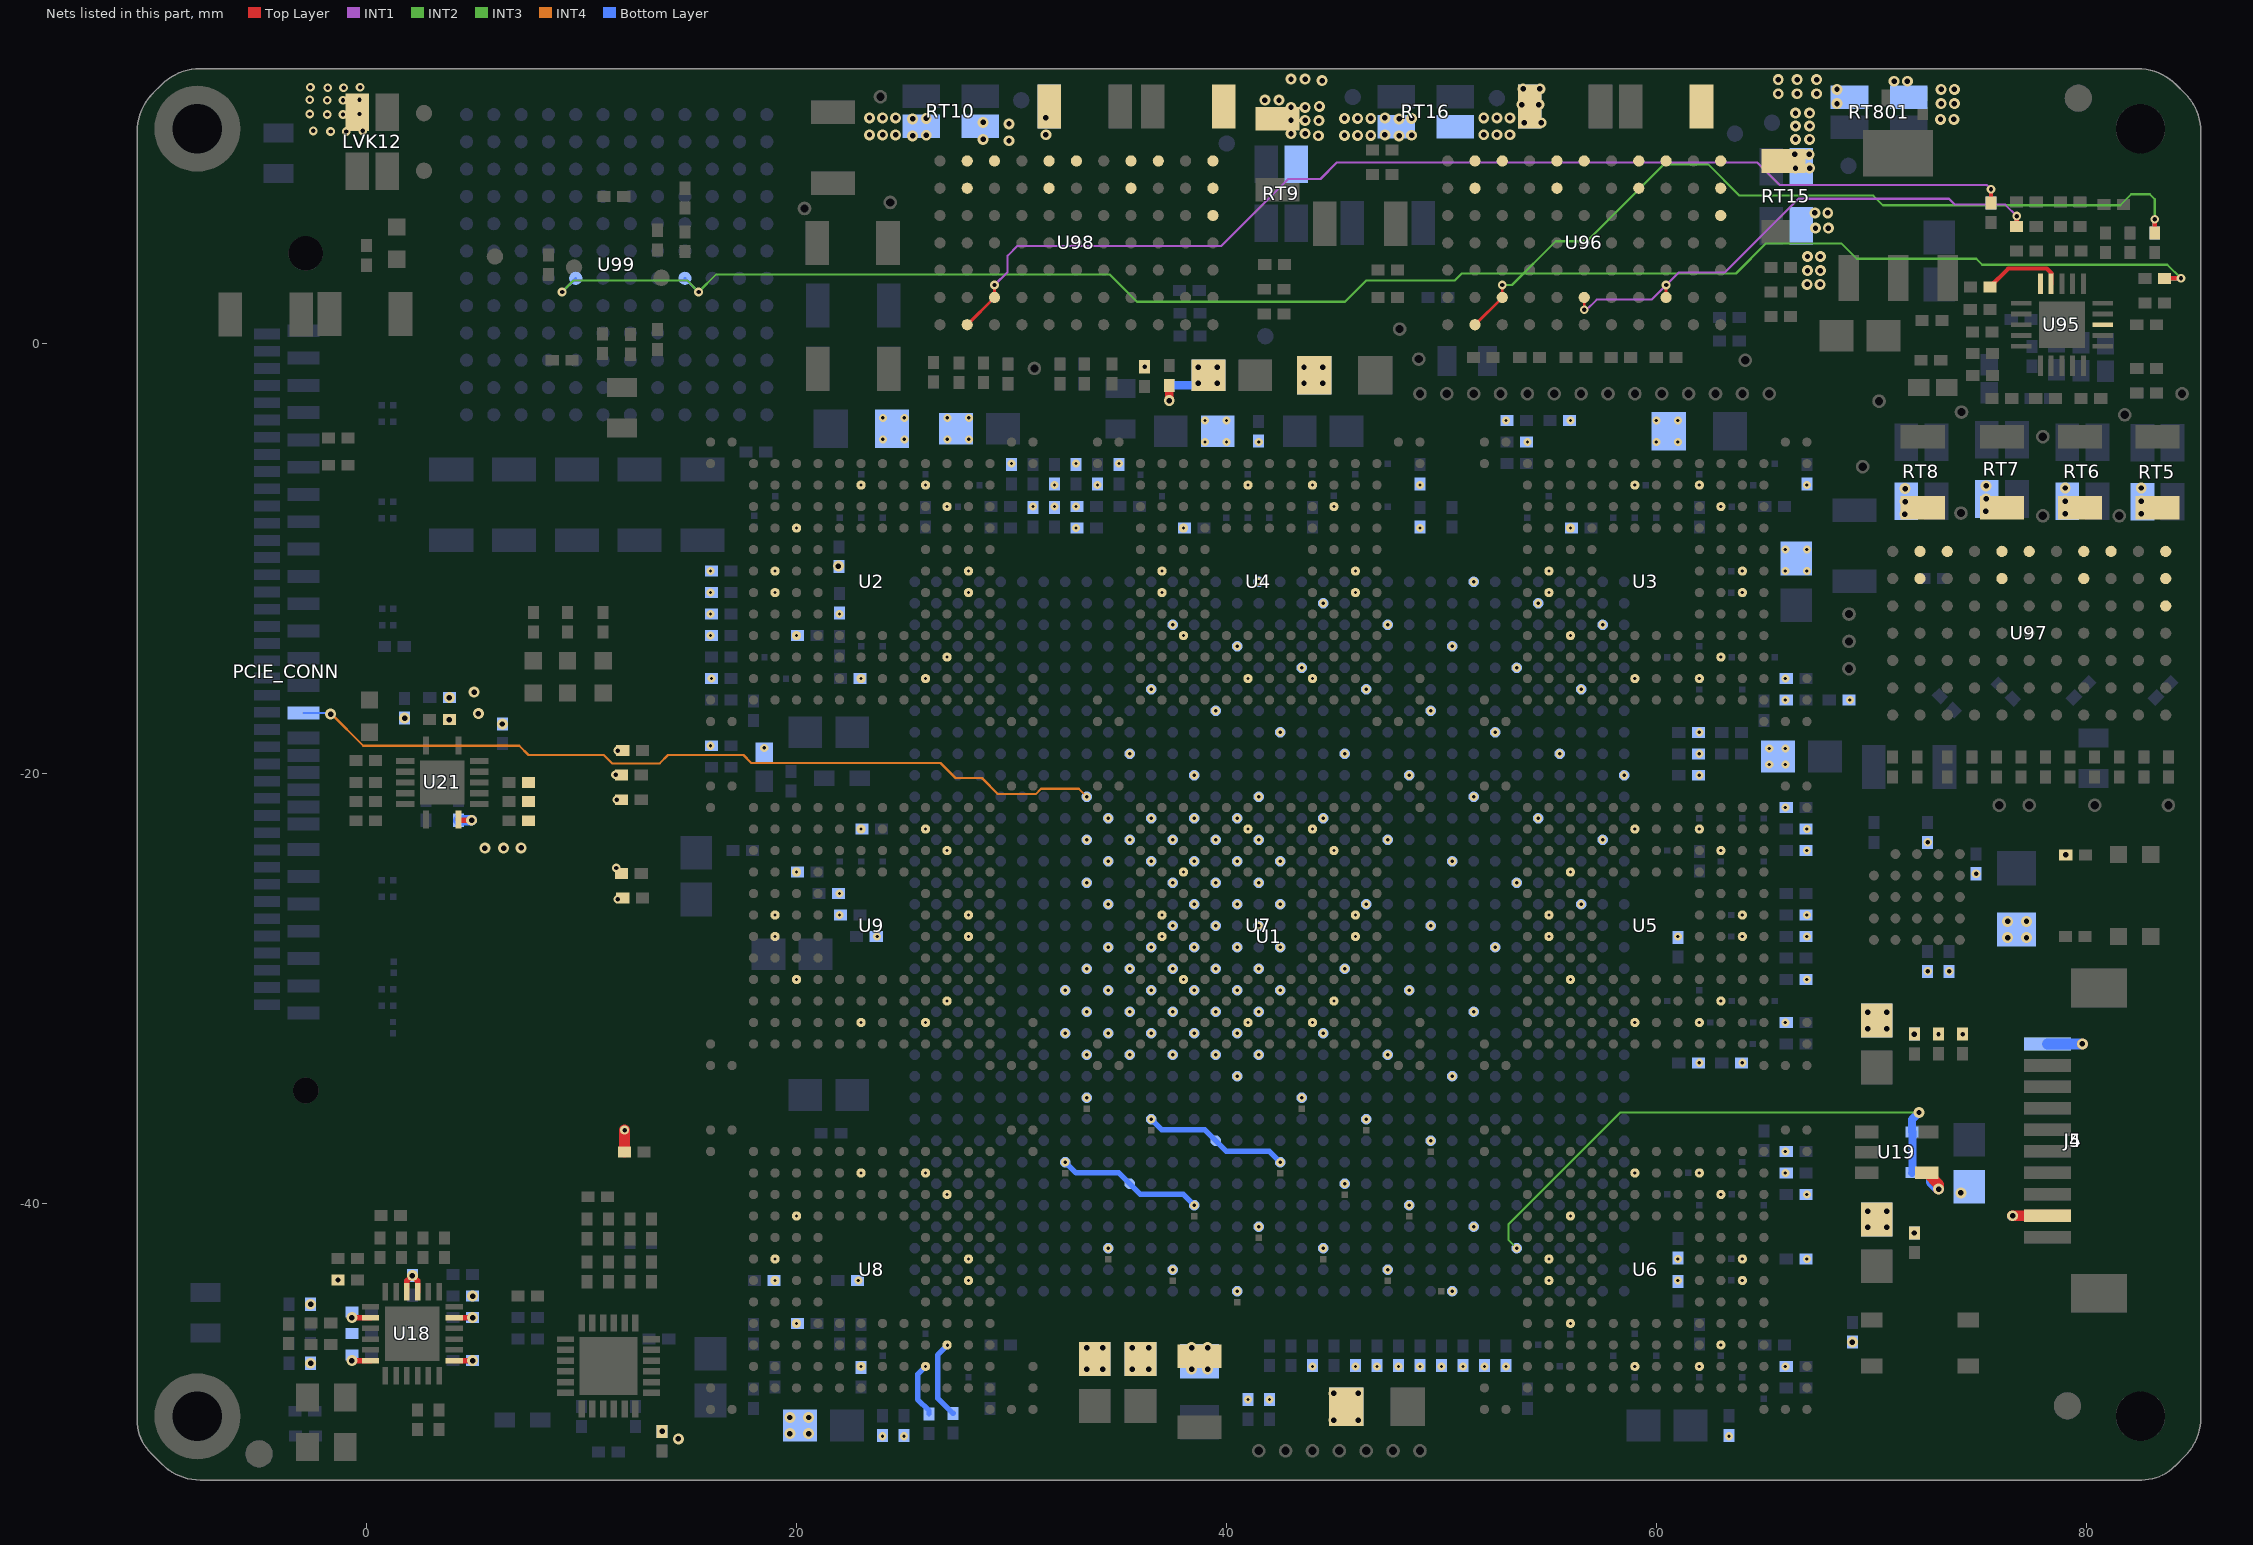
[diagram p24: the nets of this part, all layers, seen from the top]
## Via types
v1: diameter 0.381, hole 0.152, Top Layer to Bottom Layer, tented both sides, 2009 vias
v2: diameter 0.508, hole 0.254, Top Layer to Bottom Layer, tented both sides, 467 vias
v3: diameter 0.406, hole 0.203, Top Layer to Bottom Layer, 458 vias
v4: diameter 0.508, hole 0.254, Top Layer to Bottom Layer, 239 vias
v5: diameter 0.406, hole 0.203, Top Layer to Bottom Layer, tented both sides, 181 vias
v6: diameter 0.381, hole 0.152, Top Layer to GND4, tented both sides, 147 vias
v7: diameter 0.406, hole 0.203, Top Layer to GND4, tented both sides, 10 vias

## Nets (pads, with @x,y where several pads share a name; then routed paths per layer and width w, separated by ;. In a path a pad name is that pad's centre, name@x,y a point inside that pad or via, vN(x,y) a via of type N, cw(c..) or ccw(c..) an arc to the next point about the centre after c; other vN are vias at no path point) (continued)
VCCBRAM: C124.2 C125.2 C126.2 C129.2 C130.2 C237.1 C238.1 RT16.3 RT801.3 U1.AA18 U1.AB17 U1.M17 U1.P17 U1.R18 U1.U18 U1.V17 U1.W18 U1.Y17
  other v1: 41.5,-33.071 41.5,-31.071 42.5,-30.071 42.5,-28.071 41.5,-27.071 42.5,-26.071 41.5,-25.071 42.5,-24.071 41.5,-23.071 32,-6.571 34,-6.571 39,-4.571 40,-4.571 24.016,-4.443 25.016,-4.443 27.016,-4.443 28.016,-4.443 39,-3.571 40,-3.571 24.016,-3.443 25.016,-3.443 27.016,-3.443 28.016,-3.443
  other v2: 43.608,-1.839 44.483,-1.839 43.608,-1.089 44.483,-1.089
  other v4: 48.031,9.677 45.491,9.7 46.101,9.7 46.711,9.7 48.616,9.703 47.371,9.725 73.217,10.439 73.838,10.439 48.031,10.465 45.491,10.487 46.101,10.487 46.711,10.487 48.616,10.49 47.371,10.513 73.242,11.176 73.863,11.176 73.242,11.836 73.863,11.836 71.058,12.217 71.679,12.217
VCCINT: C120.2 C121.2 C122.2 C123.1 C236.1 LVK12.2 RT801.2 U1.AA10 U1.AA12 U1.AA14 U1.AA16 U1.AB11 U1.AB13 U1.AB15 U1.AC10 U1.AC12 U1.AC14 U1.AC16 U1.M9 U1.M11 U1.M13 U1.M15 U1.N8 U1.N10 U1.N12 U1.N14 U1.N16 U1.P9 U1.P11 U1.P13 U1.P15 U1.R8 U1.R10 U1.R12 U1.R14 U1.R16 U1.T9 U1.T11 U1.T13 U1.T15 U1.T17 U1.U10 U1.U14 U1.U16 U1.V13 U1.V15 U1.W10 U1.W14 U1.W16 U1.Y13 U1.Y15
  other v1: 33.5,-33.071 35.5,-33.071 37.5,-33.071 39.5,-33.071 32.5,-32.071 34.5,-32.071 36.5,-32.071 38.5,-32.071 40.5,-32.071 33.5,-31.071 35.5,-31.071 37.5,-31.071 39.5,-31.071 32.5,-30.071 34.5,-30.071 36.5,-30.071 38.5,-30.071 40.5,-30.071 33.5,-29.071 35.5,-29.071 37.5,-29.071 39.5,-29.071 41.5,-29.071 34.5,-28.071 38.5,-28.071 40.5,-28.071 37.5,-27.071 39.5,-27.071 34.5,-26.071 38.5,-26.071 40.5,-26.071 37.5,-25.071 39.5,-25.071 34.5,-24.071 36.5,-24.071 38.5,-24.071 40.5,-24.071 35.5,-23.071 37.5,-23.071 39.5,-23.071 34.5,-22.071 36.5,-22.071 38.5,-22.071 40.5,-22.071 66,-10.571 67,-10.571 66,-9.571 67,-9.571 49,-8.571 60,-4.571 61,-4.571 60,-3.571 61,-3.571
  other v2: 38.375,-47.696 39.125,-47.696 38.375,-46.696 39.125,-46.696
  other v3: -1.676,9.881 -0.944,9.881 -2.489,9.906 -0.178,9.906 -1.829,10.668 -1.097,10.668 -2.642,10.693 -0.33,10.693 -1.829,11.328 -1.097,11.328 -2.642,11.354 -0.33,11.354 -1.803,11.913 -1.071,11.913 -2.616,11.938 -0.305,11.938
  other v4: 68.402,11.176 65.67,11.633 66.548,11.633 67.451,11.633 68.402,11.836 65.67,12.294 66.548,12.294 67.451,12.294
VCCINT_EN: R533.1 R534.2 U99.F5 U99.F9 | length 81.7
  Top Layer w0.203: R533.1@83.642,3.048 v3(84.404,3.048)
  INT3 w0.102: v3(9.093,2.413) 9.627,2.946 14.91,2.946 v3(15.443,2.413) 16.262,3.231 34.569,3.231 ; 34.569,3.226 35.839,1.956 40.894,1.956 ; 40.901,1.963 40.908,1.956 45.517,1.956 46.507,2.946 50.622,2.946 50.952,3.277 63.703,3.277 65.1,4.674 68.605,4.674 69.319,3.96 74.879,3.96 75.156,3.683 83.769,3.683 v3(84.404,3.048)
  Bottom Layer w0.127: v3(9.093,2.413) U99.F5@9.728,3.048 ; U99.F9@14.808,3.048 v3(15.443,2.413)
  Bottom Layer w0.203: R534.2@83.642,3.048 v3(84.404,3.048)
VCCINT_IO_EN: R537.1 R538.2 U96.J6 U96.K7 | length 38.4
  Top Layer w0.127: U96.K7@51.562,0.889 U96.J6@52.832,2.159 v3(52.832,2.735)
  Top Layer w0.203: R537.1@83.185,5.156 v3(83.185,5.791)
  INT2 w0.102: v3(52.832,2.735) 53.281,2.735 55.321,4.775 56.769,4.775 60.35,8.357 62.408,8.357 63.868,6.896 70.091,6.896 70.536,6.452 81.585,6.452 82.093,6.96 82.956,6.96 83.185,6.731 v3(83.185,5.791)
  Bottom Layer w0.203: R538.2@83.185,5.156 v3(83.185,5.791)
VCCIO_MRAM: C142.2 C143.2 C144.2 C148.2 C149.2 C150.2 C154.2 C155.2 C156.2 C160.2 C161.2 C162.2 C166.2 C167.2 C168.2 C172.2 C173.2 C174.2 C178.2 C179.2 C180.2 C216.2 C217.2 C218.2 CS1.2 CS2.2 CS3.2 CS4.2 CS5.2 CS6.2 CS7.2 CS8.2 CS9.2 CS12.2 CS13.2 CS14.2 CS15.2 CS16.2 CS17.2 CS18.2 CS23.2 CS24.2 CS25.2 CS26.2 CS27.2 CS33.2 CS34.2 CS35.2 CS36.2 CS37.2 CS38.2 R75.1 R76.1 R77.1 R78.1 R79.1 R80.1 R81.1 R82.1 R83.1 R84.1 R85.1 R86.1 R87.1 R88.1 R89.1 R90.1 R91.1 R92.1 R93.1 R94.1 R95.1 R96.1 R97.1 R98.1 R144.1 R145.1 R146.1 R147.1 R148.1 R149.1 R150.1 R151.1 R152.1 R153.1 R154.1 R155.1 R156.1 R157.1 R158.1 R159.1 R700.1 R701.1 R702.1 R703.1 R704.1 R705.1 R706.1 R707.1 RT10.3 U2.D7 U2.D8 U2.E4 U2.E11 U2.F3 U2.F12 U2.J3 U2.J12 U2.M5 U2.M10 U2.N7 U2.N8 U3.D7 U3.D8 U3.E4 U3.E11 U3.F3 U3.F12 U3.J3 U3.J12 U3.M5 U3.M10 U3.N7 U3.N8 U4.D7 U4.D8 U4.E4 U4.F3 U4.F12 U4.J3 U4.J12 U4.M5 U4.M10 U4.N7 U4.N8 U5.D7 U5.D8 U5.E4 U5.E11 U5.F3 U5.F12 U5.J3 U5.J12 U5.M5 U5.M10 U5.N7 U5.N8 U6.D7 U6.D8 U6.E4 U6.E11 U6.F3 U6.F12 U6.J3 U6.J12 U6.M5 U6.M10 U6.N7 U6.N8 U7.D7 U7.D8 U7.E4 U7.E11 U7.F3 U7.F12 U7.J3 U7.J12 U7.M5 U7.M10 U7.N7 U7.N8 U8.D7 U8.D8 U8.E4 U8.E11 U8.F3 U8.F12 U8.J3 U8.J12 U8.M5 U8.M10 U8.N7 U8.N8 U9.D7 U9.D8 U9.E4 U9.E11 U9.F3 U9.F12 U9.J3 U9.J12 U9.M5 U9.M10 U9.N7 U9.N8 | length 7.4
  Top Layer w0.381: R702.1@36.195,-1.143 v3(36.195,-1.067)
  Top Layer w0.508: R706.1@11.989,-37.592 11.989,-36.587 v3(12,-36.576)
  Bottom Layer w0.127: v4(21.946,-10.338) R700.1@21.971,-10.363
  Bottom Layer w0.254: v1(26,-47.571) 25.629,-47.942 25.629,-49.098 26.162,-49.632 C172.2@26.162,-49.784 ; v1(27.026,-46.584) 26.568,-47.041 26.568,-49.047 C144.2@27.28,-49.759
  other v1: 24,-50.821 25,-50.821 63.375,-50.821 23,-47.571 46,-47.571 47,-47.571 48,-47.571 49,-47.571 50,-47.571 51,-47.571 52,-47.571 53,-47.571 59,-47.571 62,-47.571 66,-47.571 63,-46.571 20,-45.571 56,-45.571 19,-43.571 22.875,-43.571 28,-43.571 55,-43.571 61,-43.571 64,-43.571 28,-42.571 55,-42.571 61,-42.571 64,-42.571 67,-42.571 56,-40.571 63,-39.571 67,-39.571 59,-38.571 62,-38.571 66,-38.571 66,-37.571 62,-33.446 64,-33.446 41,-31.571 44,-31.571 59,-31.571 62,-31.571 66,-31.571 27,-30.571 45,-30.571 63,-30.571 38,-29.571 56,-29.571 67,-29.571 23.75,-27.571 28,-27.571 37,-27.571 46,-27.571 55,-27.571 61,-27.571 64,-27.571 67,-27.571 28,-26.571 37,-26.571 46,-26.571 55,-26.571 64,-26.571 67,-26.571 22,-25.571 20,-24.571 38,-24.571 56,-24.571 27,-23.571 45,-23.571 63,-23.571 67,-23.571 23,-22.571 26,-22.571 41,-22.571 44,-22.571 59,-22.571 62,-22.571 67,-22.571 62,-20.071 62,-19.071 62,-18.071 66,-16.571 69,-16.571 23,-15.571 26,-15.571 41,-15.571 44,-15.571 59,-15.571 62,-15.571 66,-15.571 27,-14.571 63,-14.571 20,-13.571 38,-13.571 56,-13.571 16,-12.571 22,-12.571 16,-11.571 19,-11.571 28,-11.571 37,-11.571 46,-11.571 55,-11.571 64,-11.571 16,-10.571 19,-10.571 28,-10.571 37,-10.571 46,-10.571 55,-10.571 64,-10.571 20,-8.571 33,-8.571 38,-8.571 56,-8.571 27,-7.571 31,-7.571 32,-7.571 33,-7.571 45,-7.571 63,-7.571 23,-6.571 26,-6.571 41,-6.571 44,-6.571 49,-6.571 59,-6.571 62,-6.571 67,-6.571 30,-5.571 33,-5.571 35,-5.571 41.5,-4.571 54,-4.571 53,-3.571 56,-3.571
  other v4: 25.4,9.677 26.035,9.703 23.393,9.725 24.003,9.725 24.613,9.725 25.4,10.465 26.035,10.49 23.393,10.513 24.003,10.513 24.613,10.513
  other v6: 19,-42.571 20,-40.571 27,-39.571 23,-38.571 26,-38.571 23,-31.571 26,-31.571 20,-29.571 19,-27.571 19,-26.571
  other v7: 11.684,-25.832 11.608,-24.384 11.633,-21.209 11.582,-20.041 11.684,-18.923
VCCIO_MRAM_EN: R549.1 R550.2 U98.J6 U98.K7 | length 53.3
  Top Layer w0.127: U98.K7@27.94,0.889 U98.J6@29.21,2.159 v3(29.21,2.735)
  Top Layer w0.203: R549.1@75.565,6.553 v3(75.565,7.188)
  INT1 w0.102: v3(29.21,2.735) 29.82,3.345 29.82,4.096 30.273,4.549 39.754,4.549 42.875,7.671 44.374,7.671 45.136,8.433 64.694,8.433 65.735,7.391 75.362,7.391 v3(75.565,7.188)
  Bottom Layer w0.203: R550.2@75.565,6.553 v3(75.565,7.188)
VCCO: C91.2 C92.2 C93.2 C94.2 C95.2 C96.2 C97.2 C98.2 C99.2 C100.2 C101.2 C102.2 C103.2 C104.2 C105.2 C106.2 C107.2 C108.2 C109.2 C110.2 C113.2 C114.2 C115.1 C116.2 C117.2 C118.2 C119.1 C203.2 C204.2 C205.2 C206.2 C207.2 C208.2 C321.2 C322.2 C323.2 C324.2 CX1.2 CX2.2 CX3.2 CX4.2 CX6.2 CX7.2 CX8.2 CX9.2 CX10.2 CX12.2 CX13.2 CX14.2 CX15.2 CX16.2 CX17.2 CX18.2 CX19.2 D1.1 J5.2 R1.2 R3.2 R4.2 R6.2 R7.2 R11.2 R22.2 R66.1 R67.1 R71.1 R72.1 R110.2 R116.2 R117.2 R118.2 R122.1 R133.2 R139.2 R141.2 R143.2 R234.2 R235.2 RT15.3 U1.A16 U1.A26 U1.AA26 U1.AB9 U1.AB23 U1.AB33 U1.AC20 U1.AC30 U1.AD17 U1.AD27 U1.AE14 U1.AE24 U1.AE34 U1.AF11 U1.AF21 U1.AF31 U1.AG18 U1.AG28 U1.AH15 U1.AH25 U1.AJ12 U1.AJ22 U1.AJ32 U1.AK19 U1.AK29 U1.AL16 U1.AL26 U1.AM13 U1.AM23 U1.AM33 U1.AN20 U1.AN30 U1.AP17 U1.AP27 U1.B13 U1.B23 U1.C10 U1.C20 U1.D17 U1.D27 U1.E14 U1.E24 U1.F11 U1.F21 U1.G8 U1.G18 U1.H15 U1.H25 U1.J12 U1.J22 U1.K9 U1.K19 U1.L16 U1.L26 U1.M23 U1.N20 U1.P27 U1.R24 U1.T21 U1.U12 U1.U28 U1.V25 U1.W22 U1.W32 U1.Y9 U1.Y29 U18.7 U18.11 U18.15 U18.16 U18.20 U18.24 U19.4 U21.1 | length 26.3
  Top Layer w0.254: v2(-0.682,-47.301) U18.24@0.175,-47.301 ; v2(-0.682,-45.301) U18.20@0.175,-45.301 ; U18.16@1.875,-44.101 1.875,-43.594 v2(2.125,-43.344) 2.375,-43.594 U18.15@2.375,-44.101 ; U18.7@4.075,-47.301 v2(4.932,-47.301) ; U18.11@4.075,-45.301 v2(4.932,-45.301) ; U21.1@4.268,-22.131 4.293,-22.156 4.879,-22.156 v2(4.886,-22.164)
  Top Layer w0.381: v4(37.338,-2.642) C96.2@37.338,-1.93
  Top Layer w0.508: U19.4@72.581,-38.559 73.131,-39.109 v2(73.131,-39.321) ; v2(76.571,-40.563) J5.2@78.196,-40.563
  Bottom Layer w0.254: v1(32.5,-38.071) 33,-38.571 35,-38.571 U1.F11@35.5,-39.071 36,-39.571 38,-39.571 v1(38.5,-40.071) ; v1(36.5,-36.071) 37,-36.571 39,-36.571 U1.H15@39.5,-37.071 40,-37.571 42,-37.571 v1(42.5,-38.071)
  Bottom Layer w0.381: C100.2@37.338,-1.93 38.691,-1.93 C99.2@39.158,-1.464
  Bottom Layer w0.508: C114.2@4.268,-22.164 v2(4.886,-22.164) ; R139.2@72.801,-38.559 72.801,-38.991 v2(73.131,-39.321)
  other v1: 41,-49.114 42,-49.114 44,-47.571 40.5,-44.071 50.5,-44.071 37.5,-43.071 47.5,-43.071 34.5,-42.071 44.5,-42.071 41.5,-41.071 51.5,-41.071 48.5,-40.071 45.5,-39.071 49.5,-37.071 46.5,-36.071 33.5,-35.071 43.5,-35.071 40.5,-34.071 50.5,-34.071 47.5,-33.071 44.5,-32.071 51.5,-31.071 48.5,-30.071 45.5,-29.071 36.5,-28.071 52.5,-28.071 49.5,-27.071 22,-26.571 46.5,-26.071 56.5,-26.071 33.5,-25.071 53.5,-25.071 50.5,-24.071 33.5,-23.071 47.5,-23.071 57.5,-23.071 44.5,-22.071 54.5,-22.071 66,-21.571 41.5,-21.071 51.5,-21.071 38.5,-20.071 48.5,-20.071 58.5,-20.071 65.25,-19.571 66,-19.571 35.5,-19.071 45.5,-19.071 55.5,-19.071 65.25,-18.821 66,-18.821 18.5,-18.796 16,-18.696 42.5,-18.071 52.5,-18.071 39.5,-17.071 49.5,-17.071 36.5,-16.071 46.5,-16.071 56.5,-16.071 16.043,-15.571 43.5,-15.071 53.5,-15.071 40.5,-14.071 50.5,-14.071 16,-13.571 37.5,-13.071 47.5,-13.071 57.5,-13.071 44.5,-12.071 54.5,-12.071 41.5,-11.071 51.5,-11.071
  other v2: 14.5,-50.946 19.691,-50.696 20.566,-50.696 13.75,-50.594 45,-50.071 46.125,-50.071 19.691,-49.946 20.566,-49.946 45,-48.821 46.125,-48.821 33.5,-47.696 34.25,-47.696 35.625,-47.696 36.375,-47.696 -2.609,-47.423 33.5,-46.696 34.25,-46.696 35.625,-46.696 36.375,-46.696 69.123,-46.441 -2.609,-44.679 4.932,-44.301 -1.332,-43.551 72,-41.364 69.842,-41.104 70.717,-41.104 69.842,-40.354 70.717,-40.354 74.168,-39.497 72,-32.114 69.842,-31.854 70.717,-31.854 69.842,-31.104 70.717,-31.104 76.342,-27.621 77.217,-27.621 76.342,-26.871 77.217,-26.871 79.045,-23.774 5.5,-23.46 6.375,-23.46 7.19,-23.446 6.312,-17.685 3.848,-17.485 1.768,-17.414 5.2,-17.2 3.85,-16.456 5,-16.2 38.691,-1.839 39.566,-1.839 38.691,-1.089 39.566,-1.089
  other v4: 67.016,2.769 67.615,2.769 67.031,3.404 67.629,3.404 67.031,4.064 67.629,4.064 67.402,5.385 68,5.385 67.372,6.096 67.97,6.096
  other v5: 73.123,-32.112 74.248,-32.112 72.619,-29.19 73.619,-29.19 74.873,-24.651 72.619,-23.19
VCCO_EN: R545.1 R546.2 U96.C6 U96.F6 | length 24.7
  Top Layer w0.127: v3(56.642,1.583) U96.F6@56.642,2.159 ; U96.C6@60.452,2.159 v3(60.452,2.735)
  Top Layer w0.203: R545.1@76.759,5.461 v3(76.759,5.944)
  INT1 w0.102: v3(56.642,1.583) 56.752,1.583 57.226,2.057 59.774,2.057 v3(60.452,2.735) 61.036,3.319 63.176,3.319 66.609,6.752 73.614,6.752 73.889,6.477 76.225,6.477 v3(76.759,5.944)
  Bottom Layer w0.203: R546.2@76.759,5.461 v3(76.759,5.944)
VDDD: J4.1 | length 1.6
  Bottom Layer w0.508: J4.1@78.196,-32.563 v2(79.821,-32.562)
VOUT1_1: C512.2 C513.2 RT9.2 U98.A1 U98.A2 U98.A3 U98.C1 U98.D1 U98.D2
  other v4: 44.272,9.679 43.002,9.779 43.663,9.779 43.002,10.4 43.663,10.4 44.298,10.389 43.002,10.998 43.663,10.998 44.323,11.049 41.783,11.336 42.443,11.336 44.45,12.243 43.002,12.319 43.663,12.319
VOUT1_2: C514.2 C515.2 RT10.2 U98.F1 U98.G1 U98.G2 U98.J1 U98.K1 U98.K2
  other v4: 29.883,9.449 28.677,9.514 31.598,9.728 29.883,10.236 28.677,10.301 31.598,10.516
VOUT2_1: C522.2 RT5.2 U97.A1 U97.A2 U97.A3
  other v4: 82.55,-7.899 82.558,-7.315 82.558,-6.706
VOUT2_2: C523.2 RT6.2 U97.C1 U97.D1 U97.D2
  other v4: 79.012,-7.899 79.019,-7.315 79.019,-6.706
VOUT2_3: C524.2 RT7.2 U97.F1 U97.G1 U97.G2
  other v4: 75.329,-7.798 75.336,-7.214 75.336,-6.604
VOUT2_4: C525.2 RT8.2 U97.J1 U97.K1 U97.K2 | length 0.1
  Top Layer w0.127: U97.K2@72.263,-10.922 U97.K2@72.263,-10.846
  other v4: 71.561,-7.925 71.569,-7.341 71.569,-6.731
VOUT3_1: C532.2 C533.2 RT15.2 U96.A1 U96.A2 U96.A3 U96.C1 U96.D1 U96.D2
  other v4: 66.472,8.179 67.132,8.179 66.446,8.814 67.107,8.814 66.472,9.514 67.132,9.514 66.472,10.135 67.132,10.135 66.472,10.733 67.132,10.733
VOUT3_2: C534.2 C535.2 RT16.2 U96.F1 U96.G1 U96.G2 U96.J1 U96.K1 U96.K2
  other v4: 51.968,9.728 52.578,9.728 53.188,9.728 53.848,10.287 54.635,10.287 51.968,10.516 52.578,10.516 53.188,10.516 53.746,11.125 54.534,11.125 53.797,11.862 54.585,11.862
VREF: U95.13
W\D\O\: R526.1 U95.19 | length 3.8
  Top Layer w0.203: R526.1@75.52,2.651 76.375,3.505 78.156,3.505 78.367,3.294 U95.19@78.367,2.789
Wake#: PCIE_CONN.P1 U1.AD9 | length 38.6
  INT4 w0.102: v2(-1.676,-17.221) -1.634,-17.221 -0.157,-18.698 7.097,-18.698 7.529,-19.13 11.027,-19.13 11.415,-19.517 13.633,-19.517 14.021,-19.13 17.529,-19.13 17.897,-19.498 26.697,-19.498 27.395,-20.196 28.625,-20.196 29.375,-20.946 31.125,-20.946 31.375,-20.696 33.125,-20.696 v1(33.5,-21.071)
  Bottom Layer w0.102: PCIE_CONN.P1@-2.932,-17.169 -1.729,-17.169 v2(-1.676,-17.221)
WDI: U95.20
WP: R138.1 R139.1 U1.C29 | length 25.5
  INT3 w0.102: v1(53.5,-42.071) 53.125,-41.696 53.125,-40.946 58.312,-35.759 v2(72.217,-35.759)
  Bottom Layer w0.381: R139.1@71.887,-38.559 71.919,-38.526 71.919,-36.659 R138.1@71.887,-36.659 71.887,-36.089 v2(72.217,-35.759)
pads on no net: FUDICIAL1.FUDICIAL FUDICIAL2.FUDICIAL FUDICIAL3.FUDICIAL FUDICIAL4.FUDICIAL FUDICIAL5.FUDICIAL FUDICIAL6.FUDICIAL J4. J5. MTH3.1 MTH4.1 PCIE_CONN. PCIE_CONN.E1 PCIE_CONN.E2 PCIE_CONN.E3 PCIE_CONN.E4 PCIE_CONN.E6 PCIE_CONN.E16 PCIE_CONN.E25 PCIE_CONN.P2 PCIE_CONN.P3 PCIE_CONN.P7 PCIE_CONN.P8 PCIE_CONN.P9 PCIE_CONN.S2 PCIE_CONN.S3 PCIE_CONN.S5 PCIE_CONN.S6 PCIE_CONN.S9 PCIE_CONN.S10 PCIE_CONN.S12 PCIE_CONN.S13 PCIE_CONN.S15 U1.A3 U1.A4 U1.A8 U1.A17 U1.A25 U1.AA3 U1.AA4 U1.AA29 U1.AB1 U1.AB2 U1.AB5 U1.AB6 U1.AB30 U1.AC3 U1.AC4 U1.AC29 U1.AD1 U1.AD2 U1.AD5 U1.AD6 U1.AD13 U1.AD20 U1.AD21 U1.AD24 U1.AE3 U1.AE4 U1.AE8 U1.AE10 U1.AE20 U1.AE21 U1.AE22 U1.AE23 U1.AE25 U1.AE26 U1.AF1 U1.AF2 U1.AF5 U1.AF6 U1.AF8 U1.AF20 U1.AF22 U1.AF23 U1.AF24 U1.AG3 U1.AG4 U1.AG20 U1.AG21 U1.AG22 U1.AG26 U1.AH1 U1.AH2 U1.AH5 U1.AH6 U1.AH8 U1.AH9 U1.AH17 U1.AH18 U1.AH21 U1.AH33 U1.AJ3 U1.AJ4 U1.AJ8 U1.AJ9 U1.AJ10 U1.AJ11 U1.AJ20 U1.AK1 U1.AK2 U1.AK5 U1.AK6 U1.AK8 U1.AK10 U1.AK11 U1.AK22 U1.AK31 U1.AL3 U1.AL4 U1.AL8 U1.AL9 U1.AL10 U1.AL33 U1.AM1 U1.AM2 U1.AM5 U1.AM6 U1.AM9 U1.AM10 U1.AN3 U1.AN4 U1.AN8 U1.AP1 U1.AP2 U1.AP8 U1.AP19 U1.AP20 U1.B1 U1.B2 U1.B5 U1.B6 U1.B25 U1.B31 U1.B32 U1.C3 U1.C4 U1.C32 U1.C33 U1.C34 U1.D1 U1.D2 U1.D5 U1.D6 U1.D26 U1.D31 U1.D32 U1.D33 U1.E3 U1.E4 U1.E11 U1.E26 U1.E27 U1.E31 U1.E33 U1.E34 U1.F5 U1.F6 U1.F25 U1.F27 U1.F30 U1.F31 U1.F32 U1.G16 U1.G19 U1.G25 U1.G26 U1.G27 U1.G29 U1.G30 U1.G32 U1.G33 U1.G34 U1.H5 U1.H6 U1.H23 U1.H24 U1.H26 U1.H27 U1.H29 U1.H31 U1.H32 U1.H33 U1.J19 U1.J23 U1.J24 U1.J25 U1.J26 U1.J29 U1.J30 U1.J31 U1.J33 U1.J34 U1.K5 U1.K6 U1.K21 U1.K23 U1.K25 U1.K26 U1.K27 U1.K29 U1.K31 U1.K32 U1.K33 U1.L20 U1.L22 U1.L23 U1.L24 U1.L25 U1.L27 U1.L29 U1.L30 U1.L32 U1.L33 U1.L34 U1.M20 U1.M22 U1.M24 U1.M25 U1.M26 U1.M27 U1.M29 U1.M31 U1.M32 U1.N22 U1.N23 U1.N24 U1.N26 U1.N27 U1.N29 U1.N30 U1.N31 U1.N33 U1.N34 U1.P1 U1.P2 U1.P20 U1.P21 U1.P23 U1.P24 U1.P25 U1.P26 U1.P29 U1.P31 U1.P32 U1.P33 U1.R3 U1.R4 U1.R21 U1.R22 U1.R23 U1.R25 U1.R26 U1.R27 U1.R29 U1.R30 U1.R32 U1.R33 U1.R34 U1.T1 U1.T2 U1.T5 U1.T6 U1.T24 U1.T25 U1.T27 U1.T31 U1.T32 U1.U3 U1.U4 U1.U26 U1.V1 U1.V2 U1.V5 U1.V6 U1.V12 U1.V22 U1.W3 U1.W4 U1.W11 U1.W25 U1.Y1 U1.Y2 U1.Y5 U1.Y6 U1.Y11 U1.Y12 U1.Y26 U1.Y33 U2. U2.G2 U2.H2 U2.H3 U2.H5 U2.H12 U2.J5 U2.J13 U2.K12 U2.P9 U3. U3.G2 U3.H2 U3.H3 U3.H5 U3.H12 U3.J5 U3.J13 U3.K12 U3.P9 U4. U4.E11 U4.G2 U4.H2 U4.H3 U4.H5 U4.H12 U4.J5 U4.J13 U4.K12 U4.P9 U5. U5.G2 U5.H2 U5.H3 U5.H5 U5.H12 U5.J5 U5.J13 U5.K12 U5.P9 U6. U6.G2 U6.H2 U6.H3 U6.H5 U6.H12 U6.J5 U6.J13 U6.K12 U6.P9 U7. U7.G2 U7.H2 U7.H3 U7.H5 U7.H12 U7.J5 U7.J13 U7.K12 U7.P9 U8. U8.G2 U8.H2 U8.H3 U8.H5 U8.H12 U8.J5 U8.J13 U8.K12 U8.P9 U9. U9.G2 U9.H2 U9.H3 U9.H5 U9.H12 U9.J5 U9.J13 U9.K12 U9.P9 U10.A2 U10.A3 U10.A4 U10.A5 U10.B1 U10.B5 U10.C1 U10.C3 U10.C5 U10.D1 U10.D5 U10.E1 U10.E2 U10.E3 U10.E4 U10.E5 U18. U18.8 U18.9 U18.10 U21. U21.6 U21.9 U22. U22.2 U22.7 U22.8 U22.9 U22.10 U22.11 U96.C7 U97.B7 U97.C7 U97.E7 U97.H7 U97.L7 U98.C7
copper on no net:
  other v4: 49.784,0.432

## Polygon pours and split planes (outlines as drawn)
GND on Bottom Layer "BOTTOM" (solid, remove dead copper, pour order 380): 23 vertices, not listed, extent -10.679,-52.857 85.334,12.8
SGND_2 on Bottom Layer "Bottom Layer-SGND_2" (solid, pour order 327): 24 vertices, not listed, extent 72.39,-21.819 84.988,-15.24
SGND_3 on Bottom Layer "Bottom Layer-SGND_3" (solid, pour order 325): 63.322,-1.651 63.195,-1.778 51.587,-1.778 51.333,-1.524 51.333,-0.279 49.962,1.092 49.962,2.489 50.038,2.565 53.188,2.565 53.391,2.362 63.144,2.362 63.322,2.184
SGND_1 on Bottom Layer "Bottom Layer-SGND_1" (solid, pour order 323): 17 vertices, not listed, extent 25.197,-3.099 38.278,2.819
SGND_4 on Bottom Layer "Bottom Layer-SGND_4" (solid, pour order 321): 10.058,5.207
VCCINT on Bottom Layer "Bottom Layer-VCCINT 3" (solid, pour order 309): 2.885,9.271 3,9.386 3,12.342 2.896,12.446 -2.972,12.446 -2.972,9.296 -2.946,9.271
VCCINT on Bottom Layer "Bottom Layer-VCCINT 4" (solid, pour order 307): 0,11.963
VCCBRAM on Bottom Layer "Bottom Layer-VCCBRAM 1" (solid, pour order 291): 74.157,10.108 74.058,10.009 73.009,10.009 72.873,10.146 72.873,10.744 72.771,10.846 70.891,10.846 70.764,10.973 70.764,12.497 70.866,12.598 74.117,12.598 74.157,12.559
VCCBRAM on Bottom Layer "Bottom Layer-VCCBRAM 2" (solid, pour order 289): 74.041,12.09
VCCINT on Bottom Layer "Bottom Layer-VCCINT" (solid, pour order 287): 65.532,12.598 65.354,12.421 65.354,11.357 65.51,11.201 67.589,11.201 67.92,10.871 69.901,10.871 70.002,10.973 70.002,12.395 69.799,12.598
VCCINT on Bottom Layer "Bottom Layer-VCCINT 1" (solid, pour order 285): 69.875,12.116
VCCINT on Bottom Layer "Bottom Layer-VCCINT 2" (solid, pour order 283): 69.985,12.146
MGTVCCAUX on Bottom Layer "Bottom Layer-MGTVCCAUX" (solid, pour order 279): 83.21,-5.74 83.033,-5.918 82.103,-5.918 81.788,-6.233 81.788,-7.341 81.686,-7.442 81.255,-7.442 81.128,-7.315 81.128,-5.258 81.839,-4.547 81.839,-3.734 81.915,-3.658 83.185,-3.658 83.21,-3.683
MGTAVCC on Bottom Layer "Bottom Layer-MGTAVCC" (solid, pour order 277): 79.705,-3.696 79.705,-5.867 79.604,-5.969 78.638,-5.969 78.348,-6.259 78.348,-7.174 78.232,-7.29 77.521,-7.29 77.419,-7.188 77.419,-5.512 78.461,-4.47 78.461,-3.708 78.555,-3.614 79.637,-3.614 79.654,-3.632
MGTAVTT on Bottom Layer "Bottom Layer-MGTAVTT" (solid, pour order 275): 72.093,-2.769 70.993,-2.769 70.485,-3.277 70.485,-5.639 70.689,-5.843 72.084,-5.843 72.217,-5.71 72.217,-2.892
VCCAUX on Bottom Layer "Bottom Layer-VCCAUX" (solid, pour order 273): 75.921,-3.571 75.893,-3.544 73.977,-3.544 73.807,-3.714 73.807,-5.545 73.807,-7.168 73.903,-7.264 73.912,-7.255 74.375,-7.255 74.625,-7.005 74.625,-6.02 74.752,-5.893 75.737,-5.893 75.946,-5.684 75.946,-3.596
VCCIO_MRAM on Bottom Layer "Bottom Layer-VCCIO_MRAM" (solid, pour order 247): 23.114,9.576 23.114,7.925 23.647,7.391 26.264,7.391 26.746,7.874 26.746,9.5 26.746,10.843 23.266,10.843 23.114,10.69
VCCO on Bottom Layer "VCC_L22_P-001" (solid, pour order 245): 17 vertices, not listed, extent 66.142,0.229 71.119,7.595
VCC on Bottom Layer "VCC_L22_P-001" (solid, pour order 243): 22 vertices, not listed, extent 41.707,1.655 46.304,6.68
VCCBRAM on Bottom Layer "Bottom Layer-VCCBRAM" (solid, pour order 241): 48.844,10.817 45.212,10.817 45.06,10.665 45.06,9.497 45.161,9.395 48.768,9.395 48.844,9.471
VCC on Bottom Layer "Bottom Layer-VCC 1" (solid, pour order 168): 5.818,-51.486 5.996,-51.664 7.113,-51.664 7.24,-51.537 7.24,-49.657 7.154,-49.571 5.878,-49.571 5.818,-49.632
VCC_FB on Bottom Layer "Bottom Layer-VCC_FB" (solid, pour order 166): 7.468,-51.486 7.645,-51.664 8.763,-51.664 8.89,-51.537 8.89,-49.657 8.804,-49.571 7.528,-49.571 7.468,-49.632
V_OUT on Bottom Layer "Bottom Layer-V_OUT" (solid, pour order 158): 48 vertices, not listed, extent -2.997,-7.264 21.59,9.118
12V on Bottom Layer "Bottom Layer-12V 2" (solid, pour order 154): 24 vertices, not listed, extent 5.088,6.452 22.793,12.573
VOUT1_2 on Bottom Layer "Bottom Layer-VOUT1_2" (solid, pour order 148): 30.708,10.769 31.064,11.125 31.064,12.243 31.166,12.344 32.898,12.344 33.071,12.172 33.071,9.284 32.219,8.433 27.838,8.433 27.534,8.738 27.534,10.657 27.645,10.769
VOUT1_1 on Bottom Layer "Bottom Layer-VOUT1_1" (solid, pour order 144): 40.335,12.624 40.081,12.37 40.081,11.481 40.462,11.1 42.393,11.1 42.621,10.871 42.621,7.468 42.697,7.391 44.525,7.391 44.856,7.723 44.856,12.497 44.729,12.624
12V on Bottom Layer "Bottom Layer-12V 3" (solid, pour order 138): 23.635,5.728
12V on Bottom Layer "Bottom Layer-12V 4" (solid, pour order 134): 20 vertices, not listed, extent 23.622,2.591 38.735,6.858
VOUT3_2 on Bottom Layer "Bottom Layer-VOUT3_2" (solid, pour order 130): 17 vertices, not listed, extent 49.708,8.712 55.753,12.192
VOUT3_1 on Bottom Layer "Bottom Layer-VOUT3_1" (solid, pour order 128): 67.564,7.366 67.437,7.239 66.243,7.239 66.142,7.341 66.142,10.922 66.294,11.074 67.437,11.074 67.564,10.947
12V on Bottom Layer "Bottom Layer-12V 5" (solid, pour order 124): 50.114,4.343 50.089,4.318 47.498,4.318 47.295,4.521 47.295,6.756 62.052,6.756 62.408,6.401 62.408,3.048 61.951,2.591 53.873,2.591 53.5,2.964 53.5,4.133 53.289,4.343
12V on Bottom Layer "Bottom Layer-12V 1" (solid, pour order 114): 72.339,-0.119 72.449,-0.229 73.939,-0.229 74.041,-0.127 74.041,3.556 73.99,3.607 72.365,3.607 72.339,3.581
12V on Bottom Layer "Bottom Layer-12V" (solid, pour order 110): 36 vertices, not listed, extent 68.123,-20.853 82.982,-10.363
VOUT2_4 on Bottom Layer "Bottom Layer-VOUT2_4" (solid, pour order 106): 71.018,-6.452 71.018,-8.204 71.069,-8.255 72.187,-8.255 72.217,-8.225 72.217,-6.456 72.187,-6.426 71.044,-6.426
VOUT2_3 on Bottom Layer "Bottom Layer-VOUT2_3" (solid, pour order 104): 74.752,-8.103 74.803,-8.153 75.921,-8.153 75.946,-8.128 75.946,-6.35 75.921,-6.325 74.752,-6.325
VOUT2_2 on Bottom Layer "Bottom Layer-VOUT2_2" (solid, pour order 102): 78.486,-8.184 78.537,-8.235 79.674,-8.235 79.705,-8.204 79.705,-6.451 79.654,-6.4 79.654,-6.401 78.486,-6.401
VOUT2_1 on Bottom Layer "Bottom Layer-VOUT2_1" (solid, pour order 100): 82.017,-8.239 82.042,-8.264 83.15,-8.264 83.193,-8.222 83.193,-6.459 83.134,-6.401 82.017,-6.401
12V on Bottom Layer "GND" (solid, remove dead copper, pour order 86): -5.495,5.461 -4.53,6.426 0.229,6.426 0.229,-1.981 -0.104,-2.286 -3.683,-2.286 -3.785,-2.184 -3.785,0.889 -5.495,2.599
MGTAVTT on Bottom Layer "GND" (solid, remove dead copper, pour order 98): 24.75,-30.321 24.75,-42.446 21.75,-42.446 21.75,-30.321
GND on INT6 "INT6-GND" (solid, remove dead copper, pour order 358): 20 vertices, not listed, extent -10.678,-52.857 85.344,12.803
12V on INT6 "Bottom Layer-12V" (solid, pour order 210): 36 vertices, not listed, extent 68.123,-20.853 82.982,-10.363
12V on INT6 "Bottom Layer-12V 5" (solid, pour order 204): 50.114,4.343 50.089,4.318 47.498,4.318 47.295,4.521 47.295,6.756 62.052,6.756 62.408,6.401 62.408,3.048 61.951,2.591 53.873,2.591 53.5,2.964 53.5,4.133 53.289,4.343
12V on INT6 "Bottom Layer-12V 4" (solid, pour order 200): 21 vertices, not listed, extent 23.622,2.591 38.735,6.858
12V on INT6 "Bottom Layer-12V 2" (solid, pour order 196): 24 vertices, not listed, extent 5.088,6.452 22.793,12.573
V_OUT on INT6 "Bottom Layer-V_OUT" (solid, pour order 190): 42 vertices, not listed, extent -0.051,-6.528 21.589,9.195
12V on INT6 "GND" (solid, remove dead copper, pour order 31): -0.787,7.429 0.699,5.943 0.699,-2.2 -2.984,-2.2 -2.984,0.984 -5.104,3.104 -5.104,7.429
GND on INT8 "INT8" (solid, remove dead copper, pour order 345): 23 vertices, not listed, extent -10.679,-52.857 85.334,12.8
MGTVCCAUX_R on INT8 "INT8-MGTVCCAUX_R" (solid, pour order 182): 30.912,-22.149 31.318,-21.742 31.318,-20.676 31.979,-20.015 32.461,-19.533 32.461,-5.258 31.293,-4.089 28.88,-4.089 25.552,-7.417 22.555,-10.414 22.555,-24.46 23.343,-25.248 30.735,-25.248 30.912,-25.071
VCC on INT8 "INT8-VCC" (solid, pour order 299): 41.986,6.35 42.316,6.68 45.957,6.68 46.152,6.485 46.152,2.972 45.669,2.489 45.669,-2.159 46.787,-3.277 46.787,-4.674 46.228,-5.232 42.291,-5.232 41.986,-4.928
12V on INT8 "Bottom Layer-12V" (solid, pour order 214): 36 vertices, not listed, extent 68.123,-20.853 82.982,-10.363
12V on INT8 "Bottom Layer-12V 5" (solid, pour order 208): 50.114,4.343 50.089,4.318 47.498,4.318 47.295,4.521 47.295,6.756 62.052,6.756 62.408,6.401 62.408,3.048 61.951,2.591 53.873,2.591 53.5,2.964 53.5,4.133 53.289,4.343
12V on INT8 "GND" (solid, remove dead copper, pour order 34): 0.699,7.429 -5.104,7.429 -5.104,3.104 -2.984,0.984 -2.984,-1.6 0.699,-1.6
GND on INT7 "INT7-GND" (solid, remove dead copper, pour order 356): 23 vertices, not listed, extent -10.693,-52.857 85.334,12.803
12V on INT7 "Bottom Layer-12V" (solid, pour order 212): 36 vertices, not listed, extent 68.123,-20.853 82.982,-10.363
12V on INT7 "Bottom Layer-12V 5" (solid, pour order 206): 50.114,4.343 50.089,4.318 47.498,4.318 47.295,4.521 47.295,6.756 62.052,6.756 62.408,6.401 62.408,3.048 61.951,2.591 53.873,2.591 53.5,2.964 53.5,4.133 53.289,4.343
12V on INT7 "Bottom Layer-12V 4" (solid, pour order 202): 21 vertices, not listed, extent 23.622,2.591 38.735,6.858
12V on INT7 "GND" (solid, remove dead copper, pour order 35): 0.699,7.429 -5.104,7.429 -5.104,3.104 -2.984,0.984 -2.984,-2.2 0.699,-2.2
GND on INT2 "INT2-GND" (solid, remove dead copper, pour order 370): 17 vertices, not listed, extent -10.678,-52.857 85.319,12.803
12V on INT2 "GND" (solid, remove dead copper, pour order 37): 0.699,7.429 -5.104,7.429 -5.104,3.104 -2.984,0.984 -2.984,-2.2 0.699,-2.2
GND on INT3 "INT3-GND" (solid, remove dead copper, pour order 368): 17 vertices, not listed, extent -10.678,-52.857 85.319,12.802
12V on INT3 "GND" (solid, remove dead copper, pour order 38): 0.699,7.429 -5.104,7.429 -5.104,3.104 -2.984,0.984 -2.984,-2.2 0.699,-2.2
GND on INT4 "INT4-GND" (solid, remove dead copper, pour order 366): 17 vertices, not listed, extent -10.678,-52.857 85.344,12.802
GND on INT4 "INT4-GND 1" (solid, pour order 364): -11.455,1.118
12V on INT4 "Bottom Layer-12V 4" (solid, pour order 198): 21 vertices, not listed, extent 23.622,2.591 38.735,6.858
12V on INT4 "Bottom Layer-12V 2" (solid, pour order 192): 24 vertices, not listed, extent 5.088,6.452 22.793,12.573
V_OUT on INT4 "Bottom Layer-V_OUT" (solid, pour order 184): 42 vertices, not listed, extent -0.051,-6.553 21.589,9.119
VCC on INT4 "INT4-VCC" (solid, pour order 178): 39.903,6.833 39.903,-2.032 42.723,-4.851 48.158,-4.851 48.565,-4.445 48.565,6.401 48.082,6.883 39.954,6.883
5V on INT4 "INT4-5V" (solid, pour order 176): 69.418,-4.064 70.129,-4.775 84.328,-4.775 85.065,-4.039 85.065,6.071 84.328,6.807 70.18,6.807 69.418,6.045
12V on INT4 "GND" (solid, remove dead copper, pour order 39): 0.699,5.963 0.667,5.963 -0.787,7.429 -5.104,7.429 -5.104,3.104 -2.984,0.984 -2.984,-2.2 0.699,-2.2
GND on INT5 "INT5-GND" (solid, remove dead copper, pour order 362): 20 vertices, not listed, extent -10.693,-52.857 85.344,12.802
GND on INT5 "INT5-GND 1" (solid, pour order 360): -10.693,3.937
MGTAVTT on INT5 "INT5-MGTAVTT" (solid, pour order 180): 73.889,-2.337 73.889,-4.47 73.533,-4.826 69.788,-4.826 66.689,-1.727 34.087,-1.727 32.817,-2.997 32.817,-12.573 32.487,-12.903 28.524,-12.903 28.245,-12.624 28.245,3.581 29.108,4.445 72.288,4.445 73.837,2.896
12V on INT5 "Bottom Layer-12V 2" (solid, pour order 194): 24 vertices, not listed, extent 5.088,6.452 22.793,12.573
V_OUT on INT5 "Bottom Layer-V_OUT" (solid, pour order 188): 41 vertices, not listed, extent -0.229,-6.528 21.589,9.22
12V on INT5 "GND" (solid, remove dead copper, pour order 40): -0.85,7.429 0.699,5.88 0.699,-2.2 -2.984,-2.2 -2.984,0.984 -5.104,3.104 -5.104,7.429
GND on Top Layer "Top Layer-DGND" (solid, remove dead copper, pour order 378): 24 vertices, not listed, extent -10.679,-52.857 85.334,12.8
VCCINT on Top Layer "Top Layer-VCCINT" (solid, pour order 376): 0.127,12.624 0.152,12.598 0.152,9.703 0.076,9.627 -2.869,9.627 -2.946,9.704 -2.946,12.522 -2.845,12.624
V_OUT on Top Layer "Top Layer-V_OUT" (solid, pour order 374): 0.175,9.085 0.175,6.885 0.047,6.756 -2.972,6.756 -3.099,6.883 -3.099,9.017 -2.87,9.246 0.127,9.246 0.178,9.195
SGND_2 on Top Layer "Top Layer-SGND_2" (solid, pour order 335): 85.13,-21.92 69.418,-21.92 69.19,-21.692 69.19,-9.804 69.952,-9.042 84.658,-9.042 85.141,-9.525 85.141,-21.898
SGND_3 on Top Layer "Top Layer-SGND_3" (solid, pour order 333): 17 vertices, not listed, extent 48.336,-3.099 68.174,12.725
SGND_1 on Top Layer "Top Layer-SGND_1" (solid, pour order 331): 49.708,12.573
SGND_1 on Top Layer "Top Layer-SGND_1 1" (solid, remove dead copper, pour order 329): 24.663,12.548 24.663,8.001 22.86,6.198 22.86,-1.803 23.825,-2.769 45.593,-2.769 45.974,-2.388 45.974,2.821 46.533,3.38 46.533,12.37 46.152,12.751 24.714,12.751 24.663,12.7
SGND_4 on Top Layer "Top Layer-SGND_4" (solid, pour order 319): 17.983,-2.515 12.649,-2.515 3.591,-2.515 3.302,-2.225 3.302,-1.753 3.302,12.331 3.518,12.548 18.161,12.548 18.644,12.065 18.644,-1.854
SGND_4 on Top Layer "Top Layer-SGND_4 1" (solid, pour order 317): 18.313,-1.727
GND on Top Layer "Top Layer-DGND" (solid, pour order 216): -10.16,10.084
12V on Top Layer "Top Layer-VIN" (solid, pour order 164): 17 vertices, not listed, extent -5.461,-1.626 0.356,6.477
V_OUT on Top Layer "Top Layer-V_OUT 1" (solid, pour order 160): 21.5,-0.057 21.481,-0.057 19.095,-0.057 18.948,-0.203 18.948,-2.286 19.202,-2.54 21.539,-2.54 21.666,-2.413 21.666,-0.082 21.641,-0.057 21.539,-0.057
12V on Top Layer "Top Layer-12V 1" (solid, pour order 156): 20.041,12.446 19.837,12.243 19.837,10.236 20.015,10.058 22.784,10.058 22.885,10.16 22.885,12.395 22.835,12.446
VOUT1_2 on Top Layer "Top Layer-VOUT1_2" (solid, pour order 146): 22 vertices, not listed, extent 27.203,6.655 33.274,12.548
VOUT1_1 on Top Layer "Top Layer-VOUT1_1" (solid, pour order 142): 28 vertices, not listed, extent 35.204,5.664 44.958,12.573
12V on Top Layer "Top Layer-12V 2" (solid, pour order 140): 24.93,5.893 25.819,6.782 26.772,6.782 27.076,6.477 27.076,3.327 26.772,3.023 23.952,3.023 23.622,3.353 23.622,3.658 23.622,5.74 23.774,5.893
VOUT3_2 on Top Layer "Top Layer-VOUT3_2" (solid, pour order 126): 25 vertices, not listed, extent 51.105,6.883 57.099,12.471
VOUT3_1 on Top Layer "Top Layer-VOUT3_1" (solid, remove dead copper, pour order 120): 30 vertices, not listed, extent 58.801,5.664 67.437,12.37
12V on Top Layer "Top Layer-12V 3" (solid, pour order 118): 47.6,7.036
12V on Top Layer "Top Layer-12V 4" (solid, pour order 116): 50.571,6.782 50.724,6.629 50.724,3.124 50.521,2.921 50.063,2.921 49.022,3.962 47.752,3.962 47.244,4.47 47.244,6.731 47.295,6.782
5V on Top Layer "Top Layer-5V" (solid, pour order 112): 28 vertices, not listed, extent 69.215,-2.311 74.168,9.982
12V on Top Layer "Top Layer-12V" (solid, pour order 108): 74.041,1.956 73.99,1.905 73.99,-0.201 73.886,-0.305 73,-0.305 72.873,-0.178 72.873,4.166 72.949,4.242 74.041,4.242
VOUT2_1 on Top Layer "Top Layer-VOUT2_1" (solid, pour order 96): 82.169,-8.611 83.312,-9.754 83.312,-12.421 83.414,-12.522 84.683,-12.522 84.785,-12.42 84.785,-6.451 84.684,-6.35 82.169,-6.35
VOUT2_2 on Top Layer "Top Layer-VOUT2_2" (solid, pour order 94): 17 vertices, not listed, extent 78.638,-11.278 81.458,-6.375
VOUT2_3 on Top Layer "Top Layer-VOUT2_3" (solid, pour order 92): 74.981,-8.128 75.717,-8.865 75.717,-11.049 75.844,-11.176 76.835,-11.176 76.911,-11.1 76.911,-10.643 77.521,-10.033 77.622,-9.931 77.622,-8.814 77.14,-8.331 77.14,-6.401 77.013,-6.274 74.981,-6.274
VOUT2_3 on Top Layer "Top Layer-VOUT2_3 1" (solid, pour order 90): 74.778,-6.35
VOUT2_4 on Top Layer "Top Layer-VOUT2_4" (solid, pour order 88): 17 vertices, not listed, extent 71.196,-11.328 73.863,-6.35
GND on INT1 "INT1-GND" (solid, remove dead copper, pour order 372): 17 vertices, not listed, extent -10.678,-52.857 85.319,12.803
VCC_FB on INT1 "INT1-VCC_FB" (solid, pour order 170): 6.706,-43.687 6.706,-49.124 7.442,-49.86 7.442,-51.78 7.758,-52.095 14.44,-52.095 15.088,-51.448 15.088,-43.713 14.63,-43.256 14.503,-43.383 6.883,-43.383 6.706,-43.561
SGND_2 on Bottom 3D Body (solid): 10.363,1.143
GND on GND1 (split plane): 95 vertices, not listed, extent -10.17,-52.349 84.825,12.291
VCCIO_MRAM on PWR1-(VCCIO_MRAM) (split plane): 95 vertices, not listed, extent -10.17,-52.349 84.825,12.291
VCCINT on PWR2-(VCCINT) (split plane): 95 vertices, not listed, extent -10.17,-52.349 84.825,12.291
12V on PWR3_(12V_MGTAVCC) (split plane): 61 vertices, not listed, extent -10.17,-5.149 84.825,12.291
MGTAVCC on PWR3_(12V_MGTAVCC) (split plane): 70 vertices, not listed, extent -10.17,-52.349 84.825,3.331
GND on GND2-(DGND_SGND) (split plane): 95 vertices, not listed, extent -10.17,-52.349 84.825,12.291
SGND_4 on GND2-(DGND_SGND) (split plane): 22.618,-4.961 3.316,-4.961 3.316,-0.214 3.316,12.261 3.313,12.29 22.667,12.29
SGND_2 on GND2-(DGND_SGND) (split plane): 33 vertices, not listed, extent 69.192,-22.041 84.825,12.291
SGND_1 on GND2-(DGND_SGND) (split plane): 44.08,-4.961 23.002,-4.961 23.052,12.29 44.08,12.29
SGND_3 on GND2-(DGND_SGND) (split plane): 68.845,-4.961 44.464,-4.961 44.464,12.29 68.845,12.29
MGTAVTT on PWR4_(MGTAVTT_VCCBRAM,VCCAUX) (split plane): 71 vertices, not listed, extent -10.17,-52.349 31.482,12.291
VCCAUX on PWR4_(MGTAVTT_VCCBRAM,VCCAUX) (split plane): 102 vertices, not listed, extent 12.46,-52.348 84.825,12.291
VCCBRAM on PWR4_(MGTAVTT_VCCBRAM,VCCAUX) (split plane): 54 vertices, not listed, extent 21.192,-33.463 74.204,12.29
VCC on PWR5-(VCC_12V) (split plane): 110 vertices, not listed, extent -10.17,-52.349 84.825,12.291
12V on PWR5-(VCC_12V) (split plane): 55 vertices, not listed, extent -4.541,-22.084 84.825,12.291
GND on GND3-(DGND_GND) (split plane): 95 vertices, not listed, extent -10.17,-52.349 84.825,12.291
GND on GND4 (split plane): 95 vertices, not listed, extent -10.17,-52.349 84.825,12.291
VCCO on PWR6_(VCCO) (split plane): 95 vertices, not listed, extent -10.17,-52.349 84.825,12.291
GND on GND5 (split plane): 95 vertices, not listed, extent -10.17,-52.349 84.825,12.291
GND on GND6 (split plane): 95 vertices, not listed, extent -10.17,-52.349 84.825,12.291

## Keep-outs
INT8:
  circle w0.127: c27.5,-11.071 r0.127
  circle w0.127: c28.5,-11.071 r0.127
  circle w0.127: c27.5,-15.071 r0.127
  circle w0.127: c28.5,-15.071 r0.127
  circle w0.127: c28.5,-13.071 r0.127
Keep-Out Layer:
  circle w0.203: c82.897,10.009 r1.15
  lines w0.013: 85.334,7.117 85.334,9.628
  lines w0.203: 74.796,-52.856 ccw(c73.669,-51.866) 75.13,-51.528 cw(c78.297,-50.796) 79.688,-47.859 ccw(c80.33,-46.503) 81.236,-47.699 cw(c82.897,-49.891) 82.897,-47.141 84.697,-47.141 ccw(c84.697,-45.641) 85.334,-46.999 ; 82.159,12.803 74.923,12.803 cw(c73.666,11.984) 75.129,11.65 ccw(c78.297,10.924) 79.683,7.985 cw(c80.322,6.628) 81.231,7.821 ccw(c82.897,10.009) 82.897,7.259 84.697,7.259 cw(c84.697,5.759) 85.334,7.117
  lines w0.508: -7.503,-52.763 cw(c-7.503,-49.588) -10.678,-49.588 ; -7.503,-52.763 82.159,-52.763 ccw(c82.159,-49.588) 85.334,-49.588 85.334,9.721 ccw(c82.159,9.721) 82.159,12.896 -7.503,12.896 ; -7.503,12.896 ccw(c-7.503,9.721) -10.678,9.721 -10.678,-36.646 -10.679,-39.186 ; -10.679,-49.588 -10.679,-39.186 ; -10.679,-49.588 -10.678,-49.588 ; -10.679,-39.186 -10.679,-39.186 ; -10.679,-39.186 -10.679,-39.186

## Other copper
Top Layer:
  rectangle net VCC: -0.8,-22.438 -0.19,-19.136
  rectangle net VCCO: 7.227,-23.585 7.836,-20.152
  rectangle net VCCO: 5.125,-23.96 7.836,-22.71
  region net PCIE_CLK_P: 12.504,-43.024 12.504,-41.328 11.996,-41.328 11.996,-43.024
  region net PCIE_CLK_N: 13.504,-43.024 13.504,-41.328 12.996,-41.328 12.996,-43.024
  region net CLK_125_P: 0.371,-40.297 0.371,-41.899 0.973,-41.899 0.973,-40.297
  region net CLK_125_N: 1.277,-40.297 1.277,-41.899 1.879,-41.899 1.879,-40.297
  rectangle net SYSCLK_300_N: -3.879,-45.899 -2.277,-45.297
  rectangle net SYSCLK_300_P: -3.879,-46.805 -2.277,-46.203
  region net PCIE_CLK_N1_1: 11.504,-41.024 11.504,-39.422 10.902,-39.422 10.902,-41.024
  region net PCIE_CLK_P1_1: 10.598,-41.024 10.598,-39.422 9.996,-39.422 9.996,-41.024
  region net PCIE_CLK_N1: 11.504,-43.024 11.504,-41.328 10.996,-41.328 10.996,-43.024
  region net PCIE_CLK_P1: 10.504,-43.024 10.504,-41.328 9.996,-41.328 9.996,-43.024
  region net VOUT2_1: 82.258,-7.048
  pour cut-out: 79.5,-32.071 76.875,-32.071 76.875,-42.071 79.5,-42.071
  pour cut-out: 11.86,-49.006 11.809,-48.981 11.631,-48.981 11.657,-49.92 11.835,-50.251 12.063,-49.87 12.114,-49.387
  pour cut-out: 11.149,-48.981 11.352,-50.276 10.92,-50.2 11.047,-49.539 11.047,-49.336
  pour cut-out: 2.005,-47.482 2.208,-47.482 2.233,-48.346 2.538,-48.371 2.513,-47.482 2.741,-47.507 2.767,-48.854 2.64,-49.082 1.548,-48.904 1.446,-48.447
  pour cut-out: -3.275,-48.376 -3.275,-51.976 -0.475,-51.976 -0.475,-48.376
  text "LAYER 1: TOP" at -7.62,-54.61 h0.7
INT5:
  pour cut-out: 3.478,-30.769 2.665,-31.074 1.319,-31.099 1.37,-30.845 1.675,-30.769 2.386,-30.743
  pour cut-out: 1.065,-30.032 1.065,-30.794 1.319,-30.616 1.294,-30.21
  pour cut-out: 1.548,-29.778 2.233,-30.108 1.548,-30.21 1.395,-30.032
  pour cut-out: -3.444,-48.194 -0.32,-48.194 -0.32,-52.131 -3.394,-52.131
  text "LAYER 14 : SIG 5" at -7.62,-54.61 h0.7
INT6:
  pour cut-out: 10.46,-39.944 10.038,-40.436 10.144,-41.059 11.202,-41.041 11.554,-40.521 11.043,-39.964
  pour cut-out: 0.712,-40.89 1.58,-40.905 1.407,-40.687 1.034,-40.654
  pour cut-out: 1.774,-39.004 1.929,-40.498 1.435,-39.875 1.5,-39.262
  pour cut-out: 1.48,-38.253 1.765,-38.827 1.536,-38.78 1.431,-38.497
  pour cut-out: 0.816,-39.747 0.426,-40.332 0.668,-40.305 0.917,-40.227
  pour cut-out: 46.336,-42.165 46.346,-44.032 45.69,-44.794 46.462,-44.848 46.794,-44.166 47.18,-42.668 47.243,-42.057
  pour cut-out: 47.588,-41.111 47.629,-44.049 47.153,-43.848 47.323,-41.358
  pour cut-out: 47.727,-40.07 47.705,-40.972 47.368,-40.9 47.351,-40.191
  pour cut-out: 46.673,-39.132 47.575,-39.824 46.848,-40.178 46.296,-39.837 46.193,-39.249
  pour cut-out: 45.489,-41.452 46.408,-42.08 46.898,-41.878 47.032,-40.68 46.786,-40.267 46.417,-40.133 45.892,-40.191
  pour cut-out: 34.389,-11.896 33.631,-12.309 33.649,-11.73 33.797,-11.676
  pour cut-out: 33.721,-10.958 34.174,-11.277 33.645,-11.34
  pour cut-out: 33.245,-11.192 33.214,-12.053 33.492,-11.946 33.528,-11.411
  pour cut-out: -3.419,-48.194 -0.269,-48.194 -0.269,-52.131 -3.444,-52.131
  text "LAYER 16 : INT 6" at -7.62,-54.61 h0.7
INT4:
  pour cut-out: -3.444,-48.219 -0.32,-48.219 -0.32,-52.182 -3.394,-52.182
  text "LAYER 9 : SIG 4" at -7.62,-54.61 h0.7
INT7:
  pour cut-out: -2.625,-46.395 -3.527,-46.79 -3.937,-46.543 -3.964,-45.628 -3.571,-45.24 -2.001,-45.357 -1.813,-45.469 -0.897,-45.227 -0.368,-45.198 0.159,-45.823 -1.424,-46.003 -1.92,-45.92 -2.331,-45.884
  pour cut-out: -1.099,-46.342 -0.826,-47.355 -0.498,-47.095 -0.538,-46.382
  pour cut-out: -0.776,-47.441 -0.938,-48.585 -0.422,-48.517 -0.296,-48.011 -0.44,-47.45
  pour cut-out: 1.521,-49.594 0.305,-49.837 -0.368,-50.362 -0.821,-49.55 -0.476,-49.177 0.269,-49.024 0.883,-49.204
  pour cut-out: 12.452,-40.74 11.996,-41.445 12.164,-41.972 13.234,-41.945 13.517,-41.414 13.041,-40.781
  pour cut-out: 18.423,-28.439 19.075,-28.697 19.181,-28.733 19.706,-28.74 20.527,-28.399 19.284,-28.213
  pour cut-out: 29.678,-30.319 29.298,-30.961 29.41,-31.326 30.469,-31.347 30.726,-30.92 30.291,-30.339
  pour cut-out: 29.355,-33.255 29.677,-33.897 30.269,-33.904 30.742,-33.242 29.946,-33.2
  pour cut-out: 29.538,-32.782 30.446,-32.778 30.271,-33.054 29.616,-33.027
  pour cut-out: 28.928,-42.416 29.17,-41.97 29.282,-42.071 29.282,-42.403
  pour cut-out: 28.838,-42.587 28.84,-43.121 28.887,-43.094 29.076,-42.845
  pour cut-out: 28.914,-43.361 28.928,-44.047 29.255,-43.626 29.17,-43.334
  pour cut-out: 19.062,-45.106 20.027,-45.712 21.243,-44.994 19.336,-44.806
  pour cut-out: 3.333,-42.477 4.253,-43.244 3.149,-43.365 3.064,-43.006
  pour cut-out: 2.607,-41.222 3.636,-41.247 3.853,-41.676 3.425,-42.362 2.808,-42.416 2.411,-41.808
  pour cut-out: -3.419,-48.194 -3.419,-52.131 -0.346,-52.131 -0.346,-48.194
  text "LAYER 18 : SIG 7" at -7.62,-54.61 h0.7
INT8:
  pour cut-out: 25.257,-11.828
  pour cut-out: -4.54,-27.234 -3.997,-27.508 -3.824,-28.178 -4.733,-28.502 -4.942,-28.244 -4.906,-27.485
  pour cut-out: 1.526,-24.669 2.376,-25.08 2.239,-25.612 1.528,-25.95 1.093,-25.704 1.106,-24.925 1.261,-24.755
  pour cut-out: -5.241,-10.094 -4.622,-9.684 -4.33,-9.774 -4.312,-10.799 -4.617,-11.05 -4.844,-10.924 -5.284,-10.646 -5.187,-10.267
  pour cut-out: -5.132,-5.197 -4.581,-4.899 -4.287,-4.978 -4.222,-5.915 -4.632,-6.196 -5.162,-5.857 -5.097,-5.505
  pour cut-out: 2.097,-7.35 1.491,-7.048 1.177,-7.099 1.092,-7.353 1.094,-8.095 1.469,-8.353 2.343,-7.992 2.198,-7.59
  pour cut-out: -5.169,-14.817 -4.732,-14.539 -4.308,-14.588 -4.272,-15.447 -4.647,-15.793 -5.234,-15.454 -5.203,-15.104
  pour cut-out: 2.091,-12.367 1.535,-12.085 1.14,-12.147 1.095,-12.313 1.088,-13.116 1.4,-13.348 1.452,-13.368 2.313,-13.004 2.199,-12.634
  pour cut-out: 2.071,-2.767 1.534,-2.492 1.113,-2.602 1.088,-3.555 1.427,-3.768 2.237,-3.368
  pour cut-out: 20.971,-29.974 20.316,-30.676 20.729,-30.777 21.074,-30.528 21.158,-30.145
  pour cut-out: 24.5,-32.356 24.805,-32.213 24.832,-32.051 24.531,-31.499 25.186,-31.607 25.514,-32.172 24.644,-32.67
  pour cut-out: 28.331,-32.32 27.535,-32.307 26.963,-32.421 26.725,-32.942 27.1,-33.354 26.783,-33.485 26.427,-33.193 26.395,-32.76 26.494,-32.459 26.568,-32.28 26.732,-32.181 27.452,-32.06 27.932,-32.042 28.055,-32.047
  pour cut-out: 28.281,-34.348 27.526,-34.342 26.792,-34.456 26.938,-34.128 27.225,-34.029 27.589,-34.003 27.93,-34.023 28.102,-34.05
  pour cut-out: 27.012,-34.411 27.205,-35.394 26.568,-35.376 26.523,-34.555 26.631,-34.317
  pour cut-out: 21.117,-32.006 20.381,-32.688 21.036,-32.931 21.44,-32.563 21.503,-32.311
  pour cut-out: 18.559,-32.419 18.802,-32.791 18.811,-33.088 18.753,-33.343 18.233,-33.765 18.201,-33.85 19.008,-33.779 19.246,-33.541 19.255,-32.953 19.099,-32.634 19.049,-32.415 19.04,-32.343
  pour cut-out: 21.009,-35.77 20.529,-36.47 21.207,-36.51 21.436,-36.363
  pour cut-out: 19.843,-36.829 19.865,-37.56 20.359,-37.538 20.377,-37.094 20.143,-36.748
  pour cut-out: 27.003,-36.47 27.165,-37.56 26.128,-37.179 26.384,-36.556 26.613,-36.336 26.676,-36.309 26.774,-36.309
  pour cut-out: 25.271,-38.036 25.918,-38.426 26.866,-38.446 27.571,-38.341 28.511,-38.3 28.022,-37.874 27.672,-37.753 26.568,-37.677 26.012,-37.776
  pour cut-out: 25.63,-40.703 25.397,-40.014 25.321,-39.745 25.236,-39.018 25.505,-38.794 26.573,-38.79 26.752,-39.112 26.303,-40.041 25.918,-39.956
  pour cut-out: -3.444,-48.219 -3.444,-52.207 -0.269,-52.207 -0.269,-48.219
  text "LAYER 20 : SIG 8" at -7.62,-54.61 h0.7
INT1:
  pour cut-out: -3.419,-48.194 -3.419,-52.156 -0.295,-52.156 -0.295,-48.219 -0.269,-48.219
  text "LAYER 3 : SIG 1" at -7.62,-54.61 h0.7
INT2:
  pour cut-out: -3.444,-48.245 -0.269,-48.245 -0.269,-52.156 -3.47,-52.156
  text "LAYER 5 : SIG 2" at -7.62,-54.61 h0.7
INT3:
  pour cut-out: -3.47,-48.169 -0.32,-48.169 -0.32,-52.156 -3.394,-52.156
  text "LAYER 7 : SIG 3" at -7.62,-54.61 h0.7
Bottom Layer:
  region net GND: 1.989,-31.918 0.465,-31.918 0.465,-32.443 1.989,-32.443
  rectangle net PCIE_CLK_P_I: 1.083,-31.698 1.377,-30.642
  rectangle net GND: 0.127,-28.904 2.261,-28.379
  rectangle net PCIE_CLK_N_I: 1.083,-30.18 1.377,-29.124
  region net GND: -8.77,-43.166 -8.77,-44.576 -6.23,-44.576 -6.23,-43.166
  rectangle net MGTAVTT: 11.996,-43.051 14.5,-42.375
  rectangle net VCCO: -0.987,-47.301 -0.377,-44.793
  rectangle net SYSCLK_300_P: -3.863,-46.813 -2.355,-46.203
  rectangle net SYSCLK_300_N: -3.863,-45.899 -2.355,-45.289
  pour cut-out: 79.5,-32.071 76.875,-32.071 76.875,-42.071 79.5,-42.071
  text "LAYER 22 : BOTTOM" at -7.62,-54.61 h0.7
GND1 (plane layer: these items are gaps in the copper):
  text "LAYER 2 : GND PLANE 1" at -7.62,-54.61 h0.7
PWR6_(VCCO) (plane layer: these items are gaps in the copper):
  text "LAYER 17 : PWR PLANE 6" at -7.62,-54.61 h0.7
GND3-(DGND_GND) (plane layer: these items are gaps in the copper):
  text "LAYER 13 : GND PLANE 3" at -7.62,-54.61 h0.7
PWR5-(VCC_12V) (plane layer: these items are gaps in the copper):
  rectangle: -3.475,-52.176 -0.275,-48.176
  lines w0.381: -4.733,12.591 -4.733,11.319 -4.733,-2.321 -4.733,-2.438 40.015,-2.438 40.132,-2.321 40.183,-2.321 40.183,6.604 46.634,6.604 46.634,-2.321 75.25,-2.321 75.25,-22.276 85.446,-22.276
  text "LAYER 12 : PWR PLANE 5" at -7.62,-54.61 h0.7
PWR3_(12V_MGTAVCC) (plane layer: these items are gaps in the copper):
  rectangle: -3.475,-52.176 -0.275,-48.176
  lines w0.381: -10.678,-5.341 18.225,-5.341 27.09,3.524 39.047,3.524 39.829,2.742 44.892,-2.321 72.957,-2.321 85.287,-2.321
  text "LAYER 8 : PWR PLANE 3" at -7.62,-54.61 h0.7
PWR1-(VCCIO_MRAM) (plane layer: these items are gaps in the copper):
  rectangle: -3.475,-52.176 -0.275,-48.176
  text "LAYER 4 : PWR PLANE 1" at -7.62,-54.61 h0.7
PWR4_(MGTAVTT_VCCBRAM,VCCAUX) (plane layer: these items are gaps in the copper):
  rectangle: -3.475,-52.176 -0.275,-48.176
  lines w0.381: 12.268,-52.629 12.268,-45.06 31.674,-45.06 31.674,-9.245 30,-7.571 21,-7.571 21,12.896 ; 31.623,-21.514 40.005,-21.514 40.005,-33.655 42.088,-33.655 42.088,-32.918 42.088,-31.071 43.129,-31.071 43.129,-21.488 71.196,-21.488 71.196,9.347 ; 71.145,9.347 74.397,9.347 74.397,12.497
  text "LAYER 11 : PWR PLANE 4" at -7.62,-54.61 h0.7
GND4 (plane layer: these items are gaps in the copper):
  text "LAYER 15 : GND PLANE 4" at -7.62,-54.61 h0.7
GND2-(DGND_SGND) (plane layer: these items are gaps in the copper):
  lines w0.381: 3.124,12.261 3.124,-0.214 3.124,-5.153 69,-5.153 69,-22.234 85.356,-22.234 ; 22.809,-5.156 22.86,12.471 ; 44.272,-5.156 44.272,12.548 ; 69.037,-5.232 69.037,12.548
  text "LAYER 10 : GND PLANE 2" at -7.62,-54.61 h0.7
PWR2-(VCCINT) (plane layer: these items are gaps in the copper):
  text "LAYER 6 : PWR PLANE 2" at -7.62,-54.61 h0.7
GND5 (plane layer: these items are gaps in the copper):
  text "LAYER 19 : GND PLANE 5" at -7.62,-54.61 h0.7
GND6 (plane layer: these items are gaps in the copper):
  text "LAYER 21 : GND PLANE 7" at -7.62,-54.61 h0.7

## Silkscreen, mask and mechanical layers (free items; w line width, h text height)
Top Overlay:
  drawing of 174 lines, arcs and shapes, not listed
  text "Mounting hole drill size 2.3mm" at 27.28,19.025 h1.78
  text "D" at 75.173,8.001 h0.7
  text "A" at 66.294,-2.54 h0.7
  text "E" at 26.416,-3.226 h0.51 r90
  text "C" at 69.977,-4.521 h0.7
  text "A" at -3.658,-6.096 h0.7
  text "D" at -1.016,-8.23 h0.7
  text "B" at 68.478,-11.455 h0.7
  text "C" at 5.613,-28.296 h0.7
  text "B" at -4.267,-29.845 h0.7
  text "TDI" at 75.794,-32.918 h0.7
  text "TDO" at 75.26,-33.96 h0.7
  text "TCK" at 75.184,-34.925 h0.7
  text "TMS" at 75.057,-35.966 h0.7
  text "DGND" at 74.32,-36.906 h0.7
  text "SDA" at 75.108,-37.897 h0.7
  text "SCL" at 75.133,-38.913 h0.7
  text "DGND" at 74.371,-39.954 h0.7
  text "VCCAUX" at 72.923,-40.919 h0.7
  text "E" at -10.236,-41.402 h0.7
  text "VCC" at 74.879,-41.935 h0.7
  text "TOP SILKSCREEN" at -7.823,-54.585 h0.7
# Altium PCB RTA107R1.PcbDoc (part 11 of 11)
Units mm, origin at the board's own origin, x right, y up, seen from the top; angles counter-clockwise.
Board outline 96.01 x 65.66 mm, 22 copper layers (Top Layer, GND1, INT1, PWR1-(VCCIO_MRAM), INT2, PWR2-(VCCINT), INT3, PWR3_(12V_MGTAVCC), INT4, GND2-(DGND_SGND), PWR4_(MGTAVTT_VCCBRAM,VCCAUX), PWR5-(VCC_12V), GND3-(DGND_GND), INT5, GND4, INT6, PWR6_(VCCO), INT7, GND5, INT8, GND6, Bottom Layer), stack 2.833 mm thick; 614 components, 659 nets, 4037 pads, 3511 vias.

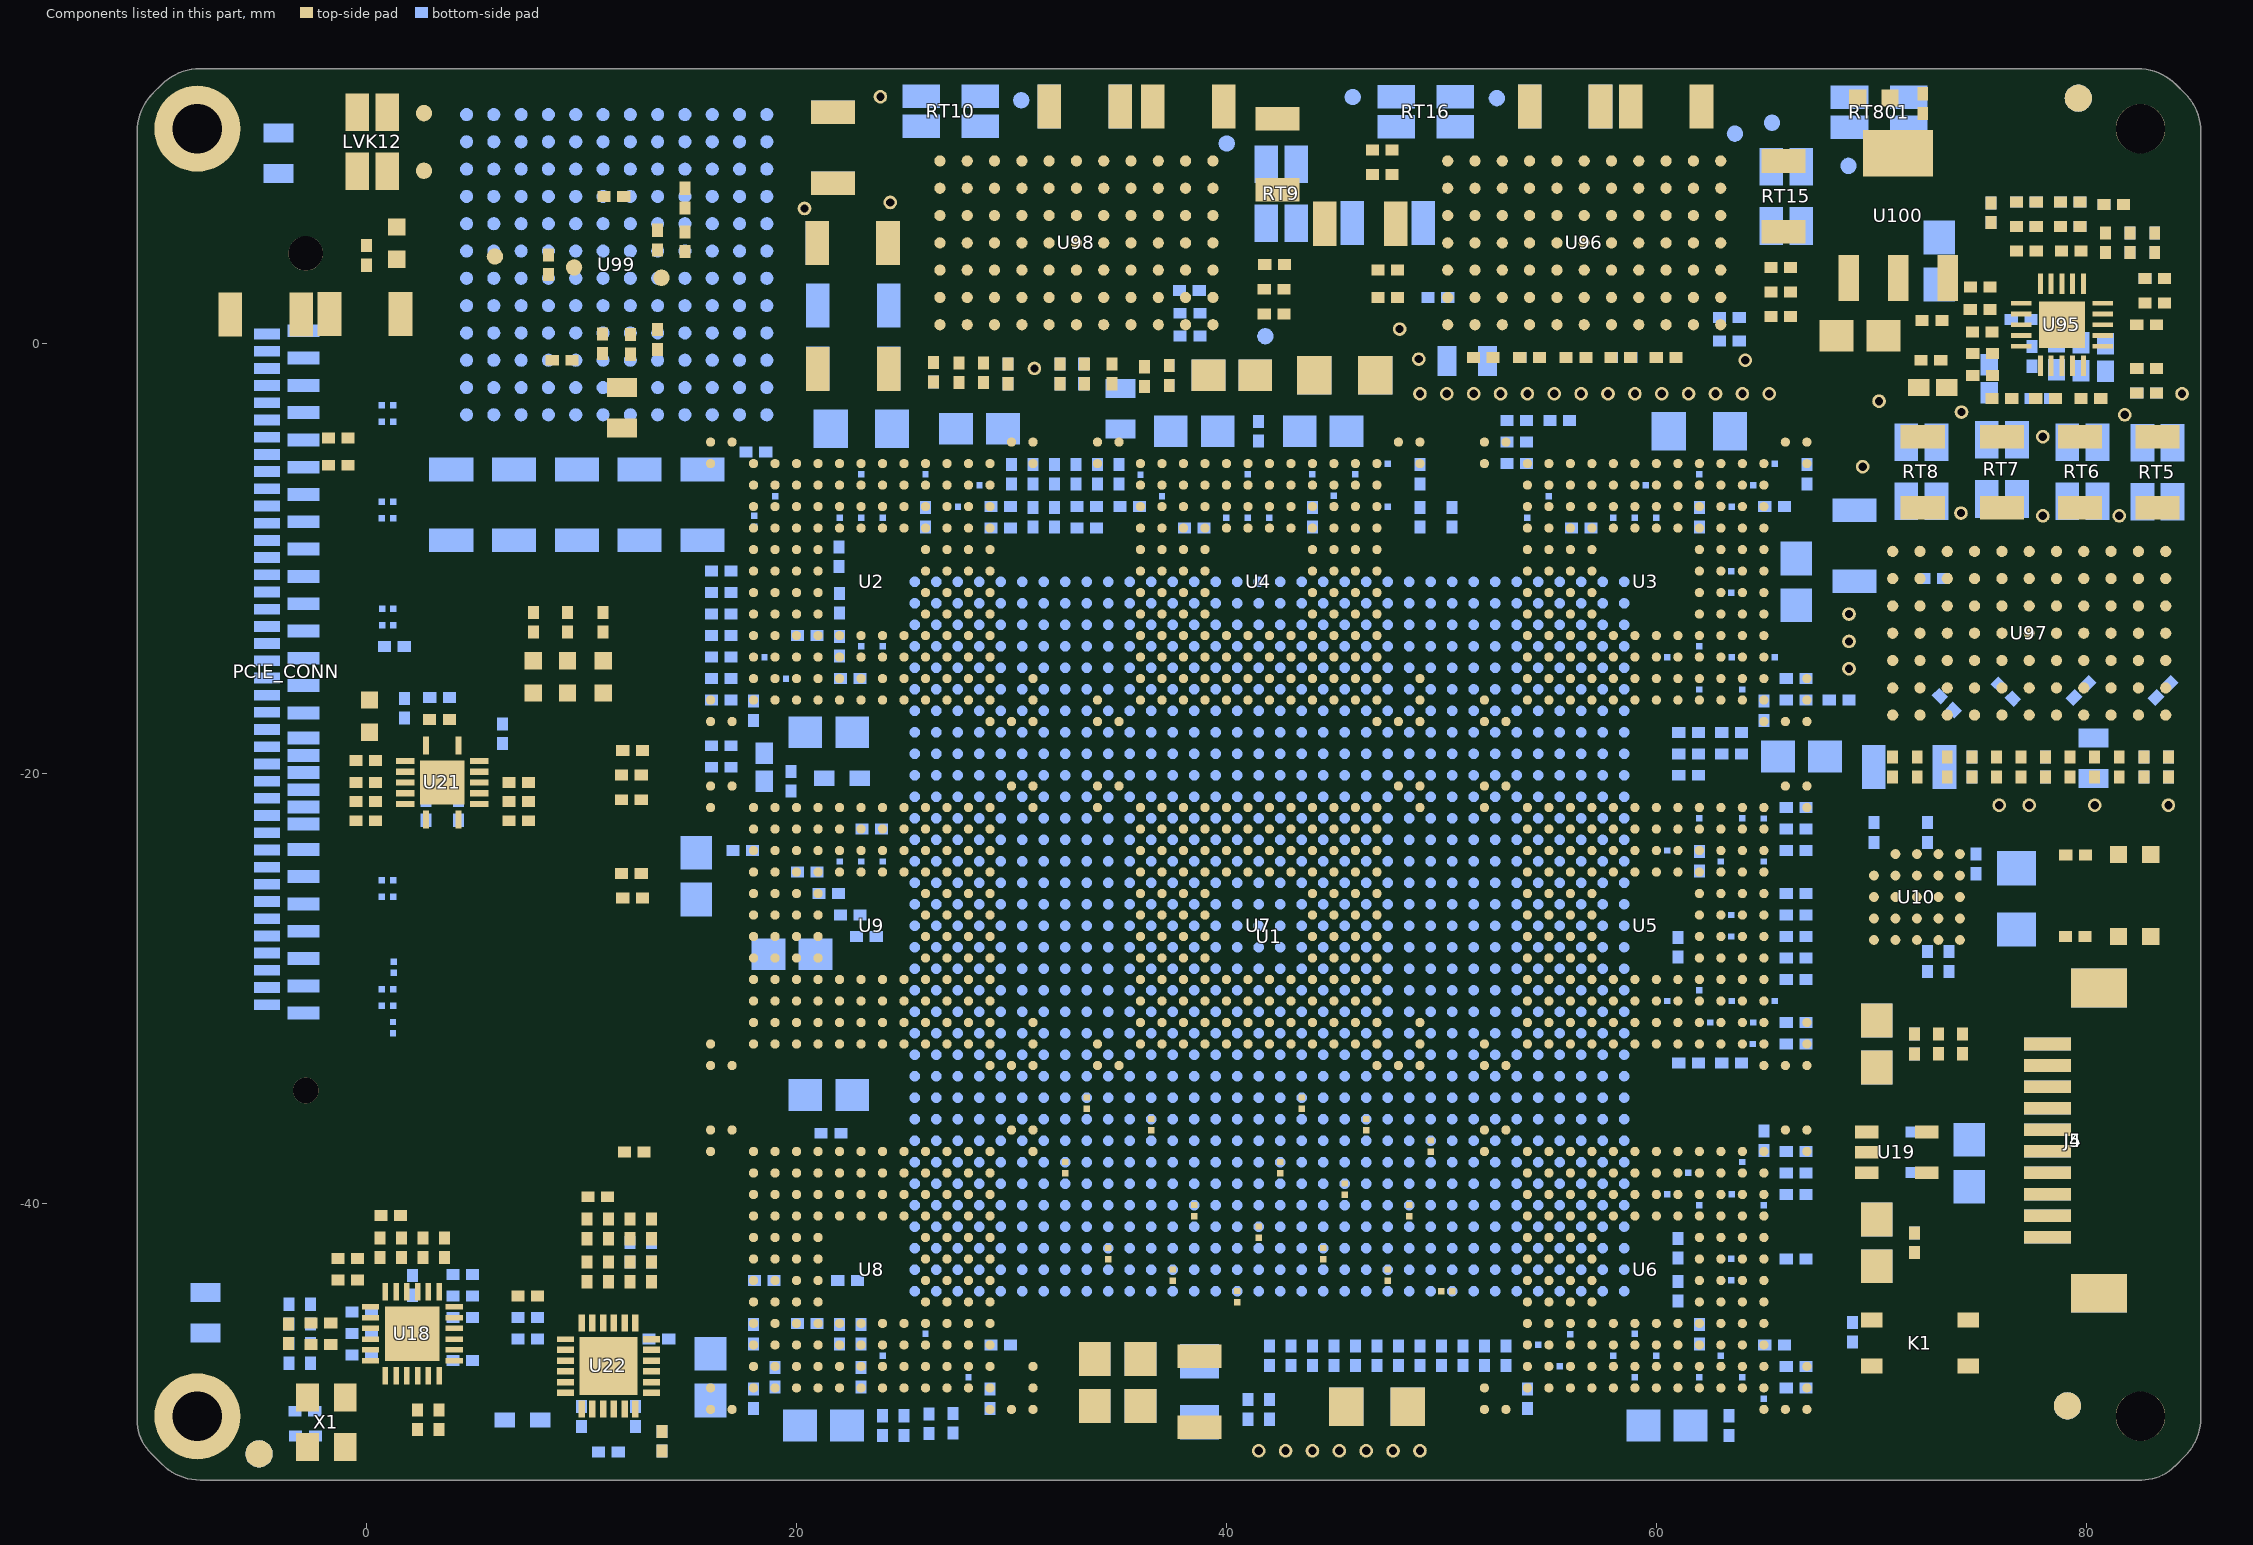
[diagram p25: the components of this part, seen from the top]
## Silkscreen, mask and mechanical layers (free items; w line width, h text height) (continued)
Bottom Overlay:
  drawing of 2060 lines, arcs and shapes, not listed
  text "H" at 35.077,2.235 h0.56
  text "H" at 34.862,-9.042 h0.56
  text "F" at 20.599,-12.7 h0.56
  text "F" at 8.407,-13.564 h0.56
  text "U . 2" at 11.024,-27.559 h1.02 r270
  text "VDD" at 76.807,-32.827 h0.56
  text "VCC_F" at 76.797,-33.825 h0.56
  text "DGND" at 76.811,-35.077 h0.56
  text "G" at 8.382,-40.894 h0.56
  text "SDATA" at 77.851,-43.942 h0.56
  text "SCLK" at 77.851,-44.958 h0.56
  text "CE_PMIC" at 77.902,-45.974 h0.56
  text "QSPI_CS" at 77.978,-47.117 h0.56
  text "QSPI_FLASH_CLK" at 77.978,-48.133 h0.56
  text "G" at 52.68,-49.047 h0.56
  text "QSPI_FLASH_MOSI_D0" at 77.978,-49.276 h0.56
  text "QSPI_FLASH_DIN_D1" at 77.876,-50.508 h0.56
  text "BOT SILKSCREEN" at -7.569,-54.585 h0.56
Top Paste:
  text "TOP PASTE" at -7.772,-54.635 h0.7
Bottom Paste:
  text "BOTTOM PASTE" at -7.67,-54.619 h0.7
Top Solder:
  text "TOP SOLDERMASK" at -7.772,-54.61 h0.7
Bottom Solder:
  text "BOTTOM SOLDERMASK" at -7.671,-54.635 h0.7
Mechanical 1:
  lines w0.254: 30.53,-29.138 48.03,-29.138 ; 48.03,-46.638 48.03,-29.138 ; 48.03,-11.638 48.03,-29.138 ; 65.53,-29.138 48.03,-29.138
  lines w1.2: -10.678,-49.588 ccw(c-7.502,-49.588) -10.67,-49.803 -10.668,-49.958 -10.65,-50.258 ccw(c-8.175,-49.958) -9.938,-51.721 -9.551,-52.107 ccw(c-7.755,-50.311) -7.755,-52.851 82.474,-52.851 ccw(c82.474,-50.445) 84.176,-52.146 84.588,-51.734 ccw(c82.792,-49.938) 85.331,-49.938 85.331,-49.72 ccw(c82.193,-49.589) 85.334,-49.588 85.334,9.69 85.334,9.977 ccw(c83.091,9.977) 84.677,11.563 84.183,12.058 ccw(c82.387,10.262) 82.387,12.802 -7.755,12.802 ccw(c-7.755,10.262) -9.551,12.058 -9.934,11.675 ccw(c-8.138,9.879) -10.678,9.879 -10.678,6.304 -6.054,6.304 cw(c-6.054,5.829) -5.579,5.829 -5.579,2.944 ccw(c-5.204,2.944) -5.204,2.569 cw(c-5.204,2.194) -4.829,2.194 -4.829,-32.536 cw(c-5.204,-32.536) -5.204,-32.911 ccw(c-5.204,-33.286) -5.579,-33.286 -5.579,-36.146 cw(c-6.079,-36.146) -6.079,-36.646 -10.679,-36.646 -10.679,-39.186 -10.679,-49.588 ; -10.679,-49.588 -10.678,-49.588
DXF_07OCT2024:
  drawing of 12251 lines, arcs and shapes, not listed
Mechanical 8:
  drawing of 4038 lines, arcs and shapes, not listed
  text "ZERO HEIGHT COMPONENT" at 362.832,98.873 h0.7
  text "2.30" at 269.762,93.289 h0.7 r43.37
  text "2.26" at 193.226,13.022 h0.7
  text "65.66" at 110.514,-10.587 h0.7 r90
  text "MAXIMUM HEIGHT COMPONENT" at 101.054,-11.693 h0.7
  text "3 MM" at 101.054,-15.693 h0.7
  text "PSAS4M2130181TR" at 49.597,-19.274 h0.7
  text "MAXIMUM HEIGHT COMPONENT" at 327.096,-19.409 h0.7
  text "5 MM" at 327.096,-23.409 h0.7
  text "ZERO HEIGHT COMPONENT" at 98.865,-70.537 h0.7 r180
  text "96.01" at 46.646,-73.77 h0.7 r180
BRD OUTLINE:
  lines w0.127: -10.679,-39.186 -10.679,-39.186 ; -7.503,-52.857 82.26,-52.857 ccw(c82.26,-49.782) 85.335,-49.782 ; -7.503,-52.857 cw(c-7.503,-49.681) -10.679,-49.681 -10.678,-49.681 -10.678,9.628 cw(c-7.503,9.628) -7.503,12.803 ; -7.503,12.8 82.159,12.8 ; 82.159,12.803 cw(c82.159,9.628) 85.334,9.628 ; 85.334,-49.782 85.334,9.627 ; -10.679,-39.186 -10.679,-39.186
Drill Drawing:
  circle w0.254: c-2.27,138.07 r0.847
  lines w0.254: -3.117,114.363 -1.423,114.363 -1.423,116.057 -3.117,116.057 -3.117,114.363 ; -3.117,119.867 -1.423,119.867 -2.27,118.173 -3.117,119.867 ; -3.117,122.407 -2.693,122.407 -2.27,121.983 -1.847,122.407 -1.423,122.407 -1.847,122.83 -1.423,123.253 -1.847,123.253 -2.27,123.677 -2.693,123.253 -3.117,123.253 -2.693,122.83 -3.117,122.407 ; -3.117,126.217 -2.693,126.217 -2.693,125.793 -1.847,125.793 -1.847,126.217 -1.423,126.217 -1.423,127.063 -1.847,127.063 -1.847,127.487 -2.693,127.487 -2.693,127.063 -3.117,127.063 -3.117,126.217 ; -3.117,129.603 -3.117,130.027 -2.693,130.45 -3.117,130.873 -3.117,131.297 -2.693,131.297 -2.27,130.873 -1.847,131.297 -1.423,131.297 -1.423,130.873 -1.847,130.45 -1.423,130.027 -1.423,129.603 -1.847,129.603 -2.27,130.027 -2.693,129.603 -3.117,129.603 ; -3.117,133.413 -2.27,133.837 -1.423,133.413 -1.847,134.26 -1.423,135.107 -2.27,134.683 -3.117,135.107 -2.693,134.26 -3.117,133.413 ; -2.778,114.702 -1.762,114.702 -1.762,115.718 -2.778,115.718 -2.778,114.702 ; -1.847,88.963 -0.153,88.963 -0.153,90.657 -1.847,90.657 -1.847,88.963 ; -1.847,93.197 -1.423,93.197 -1,92.773 -0.577,93.197 -0.153,93.197 -0.577,93.62 -0.153,94.043 -0.577,94.043 -1,94.467 -1.423,94.043 -1.847,94.043 -1.423,93.62 -1.847,93.197 ; -1.508,89.302 -0.492,89.302 -0.492,90.318 -1.508,90.318 -1.508,89.302
  lines w0.381: -4.635,113.221 139.75,113.221 ; -4.635,139.89 139.75,139.89 ; -3.365,87.82 129.847,87.82 ; -3.365,95.441 129.847,95.441 ; 9.357,109.41 9.357,143.7 ; 10.627,84.01 10.627,99.251 ; 25.609,84.01 25.609,99.251 ; 26.116,109.41 26.116,143.7 ; 52.017,84.01 52.017,99.251 ; 54.048,109.41 54.048,143.7 ; 64.866,84.01 64.866,99.251 ; 66.897,109.41 66.897,143.7 ; 83.505,84.01 83.505,99.251 ; 85.536,109.41 85.536,143.7 ; 113.722,84.01 113.722,99.251 ; 123.624,109.41 123.624,143.7 ; -4.635,109.41 139.75,109.41 139.75,143.7 -4.635,143.7 -4.635,109.41 ; -3.365,84.01 129.847,84.01 129.847,99.251 -3.365,99.251 -3.365,84.01
  text "Symbol" at -2.349,141.033 h1.83
  text "Count" at 10.5,141.033 h1.83
  text "Hole Size" at 27.259,141.033 h1.83
  text "Plated" at 55.191,141.033 h1.83
  text "Hole Type" at 68.04,141.033 h1.83
  text "Drill Layer Pair" at 86.679,141.033 h1.83
  text "Via/Pad" at 124.767,141.033 h1.83
  text "1" at 10.5,137.223 h1.52
  text "47.24mil (1.200mm)" at 27.259,137.223 h1.52
  text "NPTH" at 55.191,137.223 h1.52
  text "Round" at 68.04,137.223 h1.52
  text "Top Layer - Bottom Layer" at 86.679,137.223 h1.52
  text "Pad" at 124.767,137.223 h1.52
  text "1" at 10.5,133.413 h1.52
  text "62.99mil (1.600mm)" at 27.259,133.413 h1.52
  text "NPTH" at 55.191,133.413 h1.52
  text "Round" at 68.04,133.413 h1.52
  text "Top Layer - Bottom Layer" at 86.679,133.413 h1.52
  text "Pad" at 124.767,133.413 h1.52
  text "4" at 10.5,129.603 h1.52
  text "90.55mil (2.300mm)" at 27.259,129.603 h1.52
  text "NPTH" at 55.191,129.603 h1.52
  text "Round" at 68.04,129.603 h1.52
  text "Top Layer - Bottom Layer" at 86.679,129.603 h1.52
  text "Pad" at 124.767,129.603 h1.52
  text "44" at 10.5,125.793 h1.52
  text "15.00mil (0.381mm)" at 27.259,125.793 h1.52
  text "PTH" at 55.191,125.793 h1.52
  text "Round" at 68.04,125.793 h1.52
  text "Top Layer - Bottom Layer" at 86.679,125.793 h1.52
  text "Pad" at 124.767,125.793 h1.52
  text "639" at 10.5,121.983 h1.52
  text "8.00mil (0.203mm)" at 27.259,121.983 h1.52
  text "PTH" at 55.191,121.983 h1.52
  text "Round" at 68.04,121.983 h1.52
  text "Top Layer - Bottom Layer" at 86.679,121.983 h1.52
  text "Via" at 124.767,121.983 h1.52
  text "706" at 10.5,118.173 h1.52
  text "10.00mil (0.254mm)" at 27.259,118.173 h1.52
  text "PTH" at 55.191,118.173 h1.52
  text "Round" at 68.04,118.173 h1.52
  text "Top Layer - Bottom Layer" at 86.679,118.173 h1.52
  text "Via" at 124.767,118.173 h1.52
  text "2009" at 10.5,114.363 h1.52
  text "6.00mil (0.152mm)" at 27.259,114.363 h1.52
  text "PTH" at 55.191,114.363 h1.52
  text "Round" at 68.04,114.363 h1.52
  text "Top Layer - Bottom Layer" at 86.679,114.363 h1.52
  text "Via" at 124.767,114.363 h1.52
  text "3404 Total" at 10.5,110.553 h1.52
  text "Symbol" at -1.079,96.584 h1.83
  text "Count" at 11.77,96.584 h1.83
  text "Hole Size" at 26.752,96.584 h1.83
  text "Plated" at 53.16,96.584 h1.83
  text "Hole Type" at 66.009,96.584 h1.83
  text "Drill Layer Pair" at 84.648,96.584 h1.83
  text "Via/Pad" at 114.865,96.584 h1.83
  text "10" at 11.77,92.773 h1.52
  text "8.00mil (0.203mm)" at 26.752,92.773 h1.52
  text "PTH" at 53.16,92.773 h1.52
  text "Round" at 66.009,92.773 h1.52
  text "Top Layer - GND4" at 84.648,92.773 h1.52
  text "Via" at 114.865,92.773 h1.52
  text "147" at 11.77,88.963 h1.52
  text "6.00mil (0.152mm)" at 26.752,88.963 h1.52
  text "PTH" at 53.16,88.963 h1.52
  text "Round" at 66.009,88.963 h1.52
  text "Top Layer - GND4" at 84.648,88.963 h1.52
  text "Via" at 114.865,88.963 h1.52
  text "157 Total" at 11.77,85.153 h1.52
  text "FINISH : ENIG" at -2.591,68.859 h1.78
  text "MASK : GREEN" at -2.756,63.906 h1.78
  text "STACKUP AND MATERIAL : REFER THE ATTACHMENT(PDF)" at -3.188,58.572 h1.78
  text "VIA ON PAD TO BE CAPPED" at -3.061,52.857 h1.78
Mechanical 29:
  lines w0.127: 12.7,-40.262 12.707,-40.262 ; 25.959,-0.076 25.578,-0.076 ; 43.434,2.896 44.272,2.896 44.272,4.064 43.434,4.064 ; 64.668,4.293 65.684,4.293 ; 66.015,-1.93 66.98,-1.93 66.98,-3.073 ; 69.291,-20.269 69.291,-21.361 68.25,-21.361 68.25,-20.218 ; 69.571,-15.545 69.571,-18.364 84.303,-18.364 84.455,-18.364 84.455,-20.803 84.226,-20.803 ; 69.596,-12.09 69.596,-11.811 68.25,-11.811 68.25,-20.218 ; 71.718,-0.889 71.628,-0.889 71.247,-0.889 71.247,-3.369 71.037,-3.369 70.618,-3.369 70.409,-3.369 70.409,-8.763 85.065,-8.763 85.065,2.718 85.065,3.327 84.455,3.327 ; 71.755,1.549 71.755,3.302 73.939,3.302 ; 71.755,2.007 71.755,1.981 72.923,1.981 72.923,2.184 72.923,2.718 72.923,3.302 76.149,3.302 82.271,3.302 ; 75.667,-20.777 75.006,-20.777 73.99,-20.777 70.307,-20.777 70.307,-20.218 68.25,-20.218 ; 77.927,-20.828 79.858,-20.828 ; 80.95,-20.853 83.388,-20.853 ; 81.915,3.505 81.128,3.505 80.239,3.505 74.879,3.505 74.879,7.341 83.845,7.341 ; 83.795,8.484 74.676,8.484 74.676,11.303 83.845,11.303 83.845,7.341 ; 83.845,3.835 83.845,7.341 ; 25.578,-0.076 40.894,-0.076 40.894,4.318 43.434,4.318 43.434,-0.076 42.672,-0.076 42.672,-2.769 25.578,-2.769 25.578,-0.076 ; 66.98,-3.073 48.235,-3.073 48.235,0.025 65.989,0.025 65.989,-3.073 66.98,-3.073 ; -1.676,-34.569 6.68,-34.569 6.68,-32.563 1.905,-32.563 1.905,-30.277 -1.676,-30.277 -1.676,-34.569
  lines w0.14: -9.093,-8.585 -8.103,-8.585 -8.103,-9.881 ; -1.676,-34.569 -1.676,-35.839 -0.686,-35.839 -0.686,-34.569 ; -0.203,-3.124 -1.168,-3.124 -1.168,-1.651 -0.152,-1.651 ; 7.188,-25.883 8.153,-25.883 8.153,-24.765 7.188,-24.765 ; 44.602,-51.867 44.602,-52.4 48.362,-52.4 48.362,-51.841 ; 44.602,-51.079 44.602,-50.8 ; 44.78,-47.777 47.777,-47.777 47.777,-44.679 44.755,-44.679 44.755,-47.777 44.196,-47.777 44.196,-50.8 48.311,-50.8 48.311,-51.054 ; -0.152,-1.651 8.966,-1.651 8.966,-8.89 -0.152,-8.89 -0.152,-1.651 ; 7.188,-24.765 7.188,-29.439 -1.575,-29.439 -1.575,-26.975 5.004,-26.975 5.004,-24.765 7.188,-24.765 ; -10.185,-13.767 -10.185,-8.382 -9.119,-8.382 -9.119,-9.906 1.651,-9.906 1.651,-13.767 -10.185,-13.767
  text "B" at 43.637,3.15 h0.69
  text "D" at 72.06,2.286 h0.7
  text "D" at -0.838,-2.794 h0.7
  text "C" at 66.218,-2.845 h0.7
  text "C" at -8.839,-9.601 h0.64
  text "A" at 68.529,-21.133 h0.7
  text "B" at 7.468,-25.629 h0.64
  text "A" at -1.422,-35.56 h0.7
Mechanical 30:
  lines w0.14: 21.463,-23.216 21.463,-23.317 21.361,-23.216 21.463,-23.114 21.463,-23.241 21.666,-23.241 ; 28.473,-7.036 28.423,-7.036 28.423,-9.296 36.576,-9.296 36.601,-9.271 36.601,-7.645 ; 29.058,-6.934 29.261,-6.934 29.261,-5.156 29.388,-5.156 ; 30.988,-4.953 35.535,-4.953 35.585,-4.953 35.585,-5.08 ; 35.001,3.175 34.925,3.175 34.925,4.267 35.941,4.267 ; 35.484,-9.271 35.484,-8.179 36.601,-8.179 ; 35.662,-6.579 35.662,-6.909 36.525,-6.909 36.525,-7.036 ; 28.88,3.175 28.88,6.883 35.941,6.883 35.941,3.175 28.88,3.175
  text "E" at 35.255,3.404 h0.64
  text "E" at 35.916,-9.042 h0.64

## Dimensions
82.522,10.009 to 85.334,9.628 on Top Overlay
82.522,10.009 to 82.159,12.8 on Top Overlay
82.522,-49.891 to 82.26,-52.857 on Top Overlay
82.522,-49.891 to 85.335,-49.782 on Top Overlay
-7.878,10.009 to -7.503,12.803 on Top Overlay
-7.878,10.009 to -7.878,-49.891 on Top Overlay
-7.878,-49.891 to -10.678,-49.681 on Top Overlay
-7.878,-49.891 to -14.249,-52.857 on Top Overlay
-10.678,9.628 to 85.334,9.627 on Top Overlay
82.522,10.009 to -7.878,10.009 on Top Overlay
82.522,10.009 to 82.522,-49.891 on Top Overlay
-7.503,12.8 to -7.503,-52.857 on Top Overlay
